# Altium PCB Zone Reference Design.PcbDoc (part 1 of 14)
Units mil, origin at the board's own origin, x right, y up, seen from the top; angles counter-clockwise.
Board outline 8858.11 x 7047.08 mil, 16 copper layers (Top Layer, GND_1, SIG_1, GND_2, PWR/SIG_1, GND_3, PWR_1, PWR_2, GND_4, PWR/SIG_2, GND_5, SIG_2, GND_6, SIG_3, GND_7, Bottom Layer), stack 80.368 mil thick; 1131 components, 808 nets, 3825 pads, 3523 vias.
Unrouted connection lines stored in the file: 563.

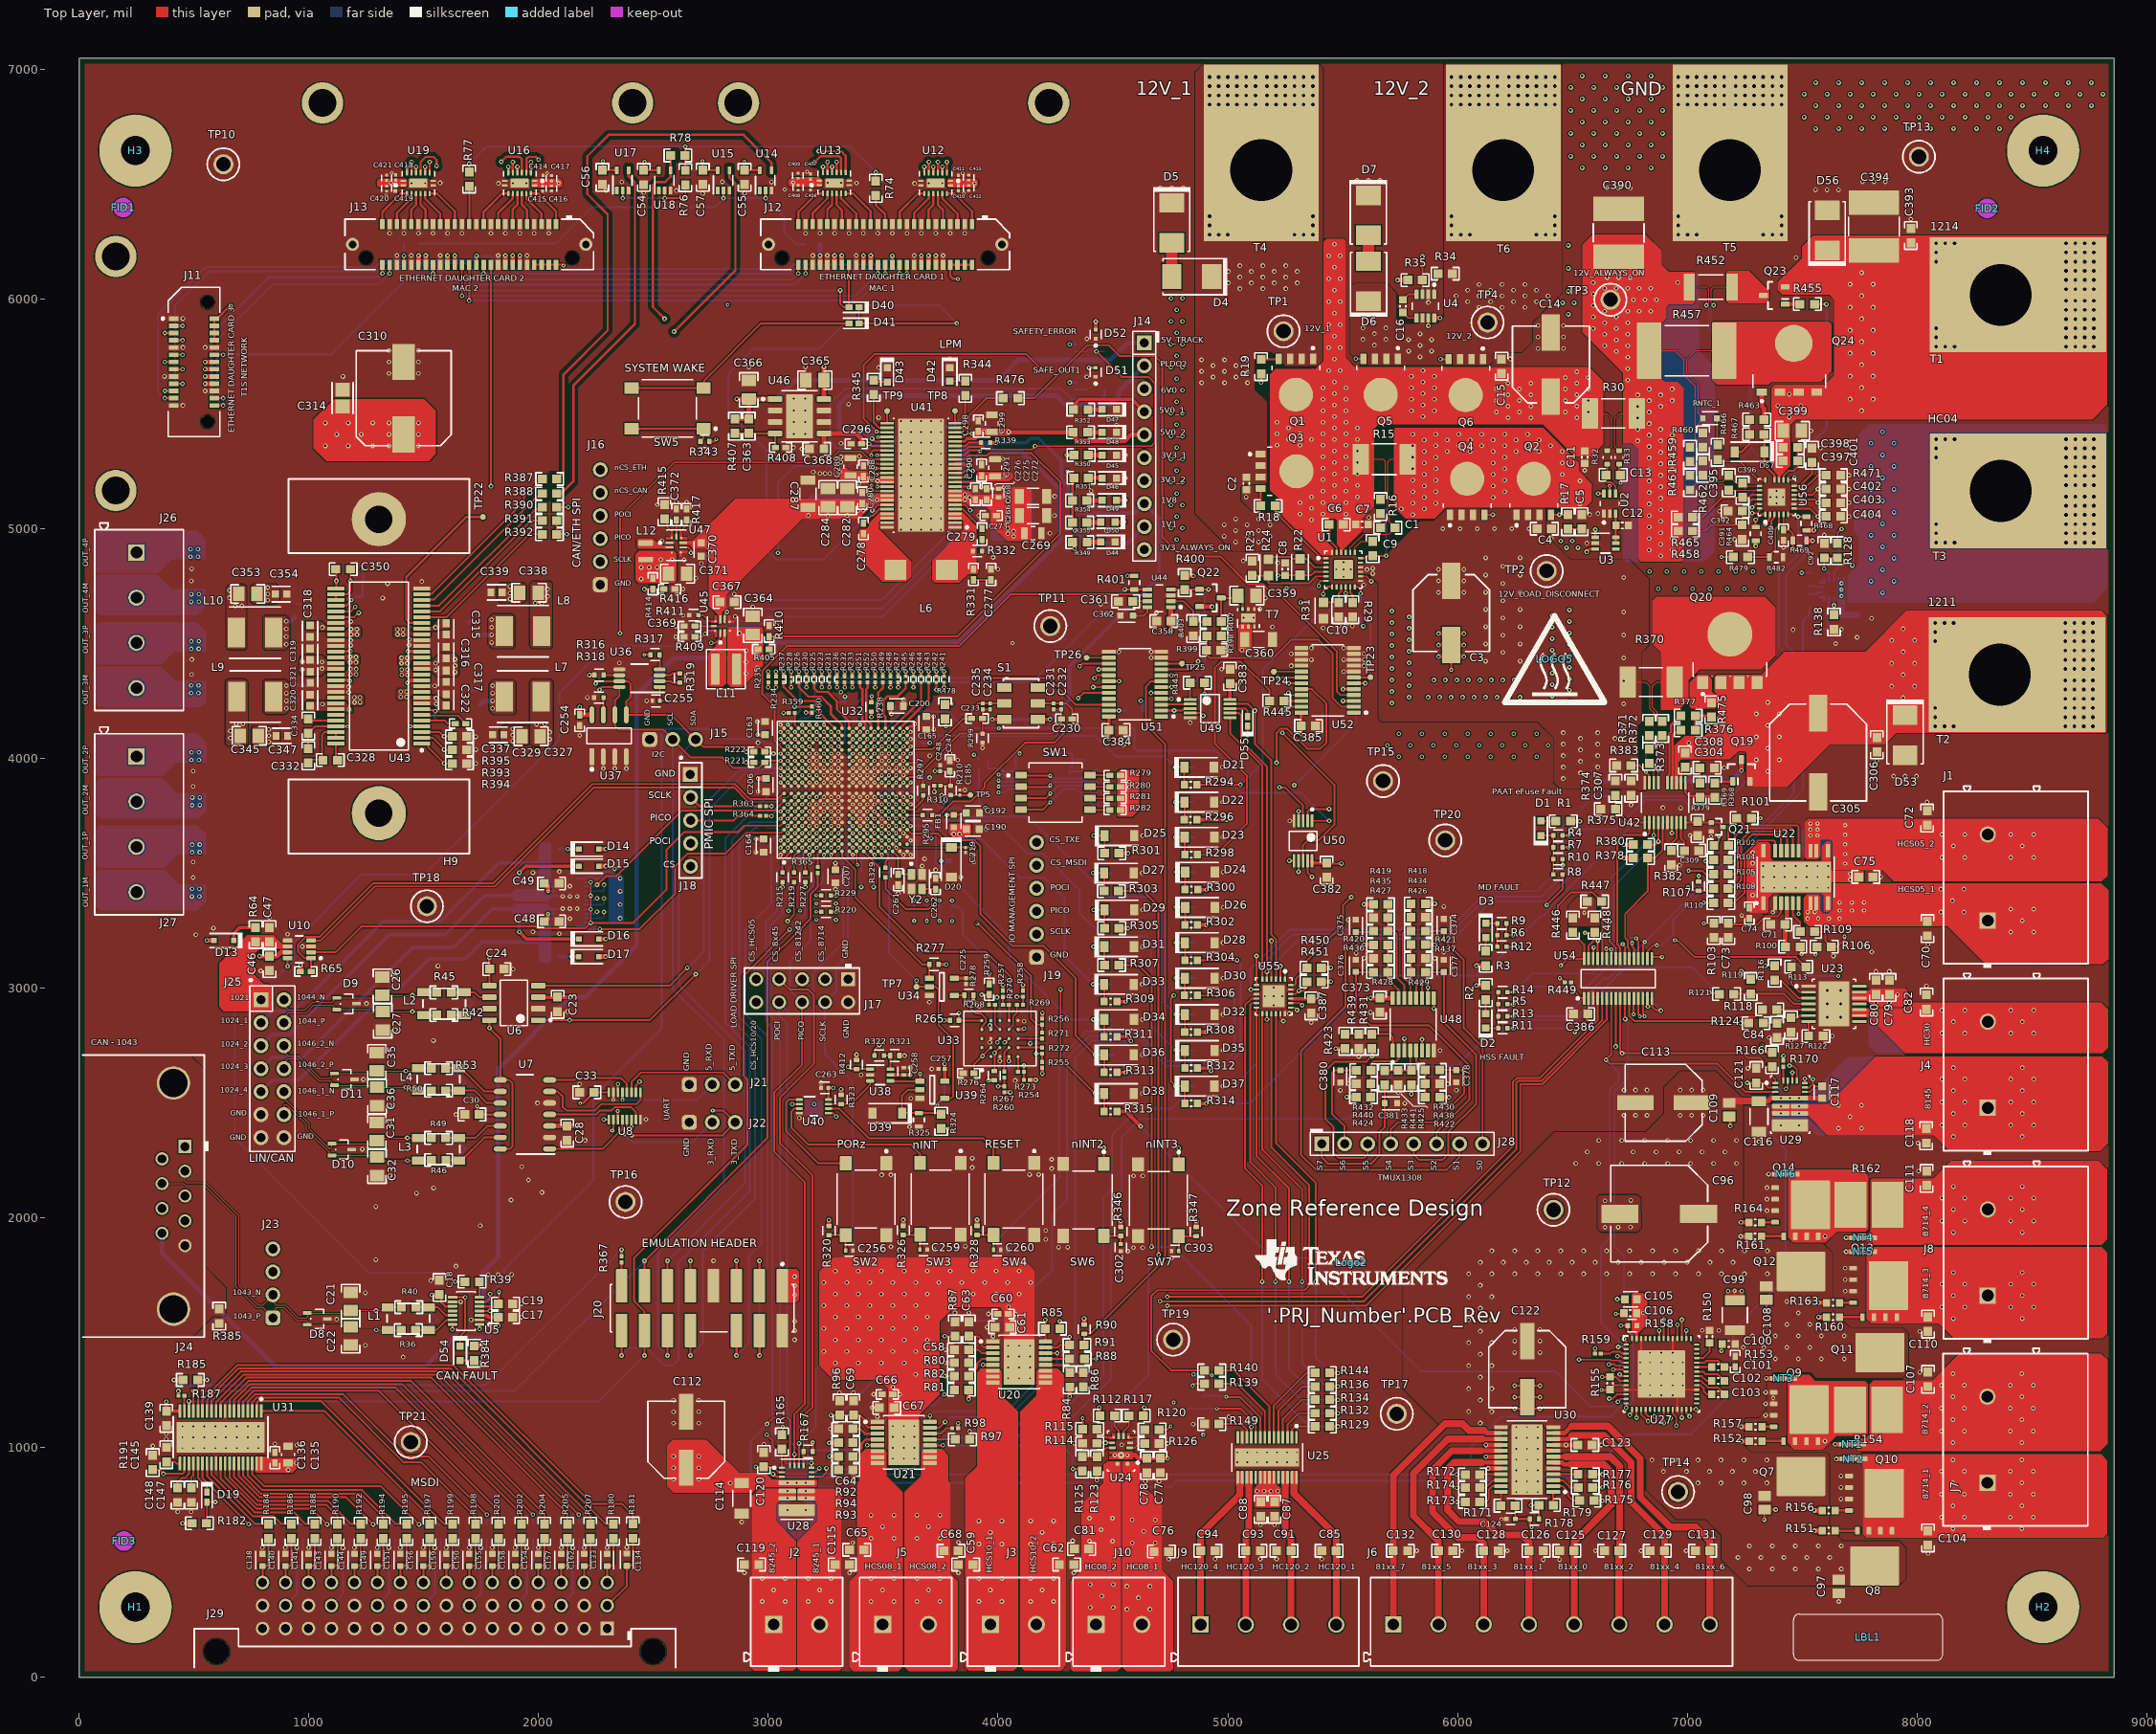
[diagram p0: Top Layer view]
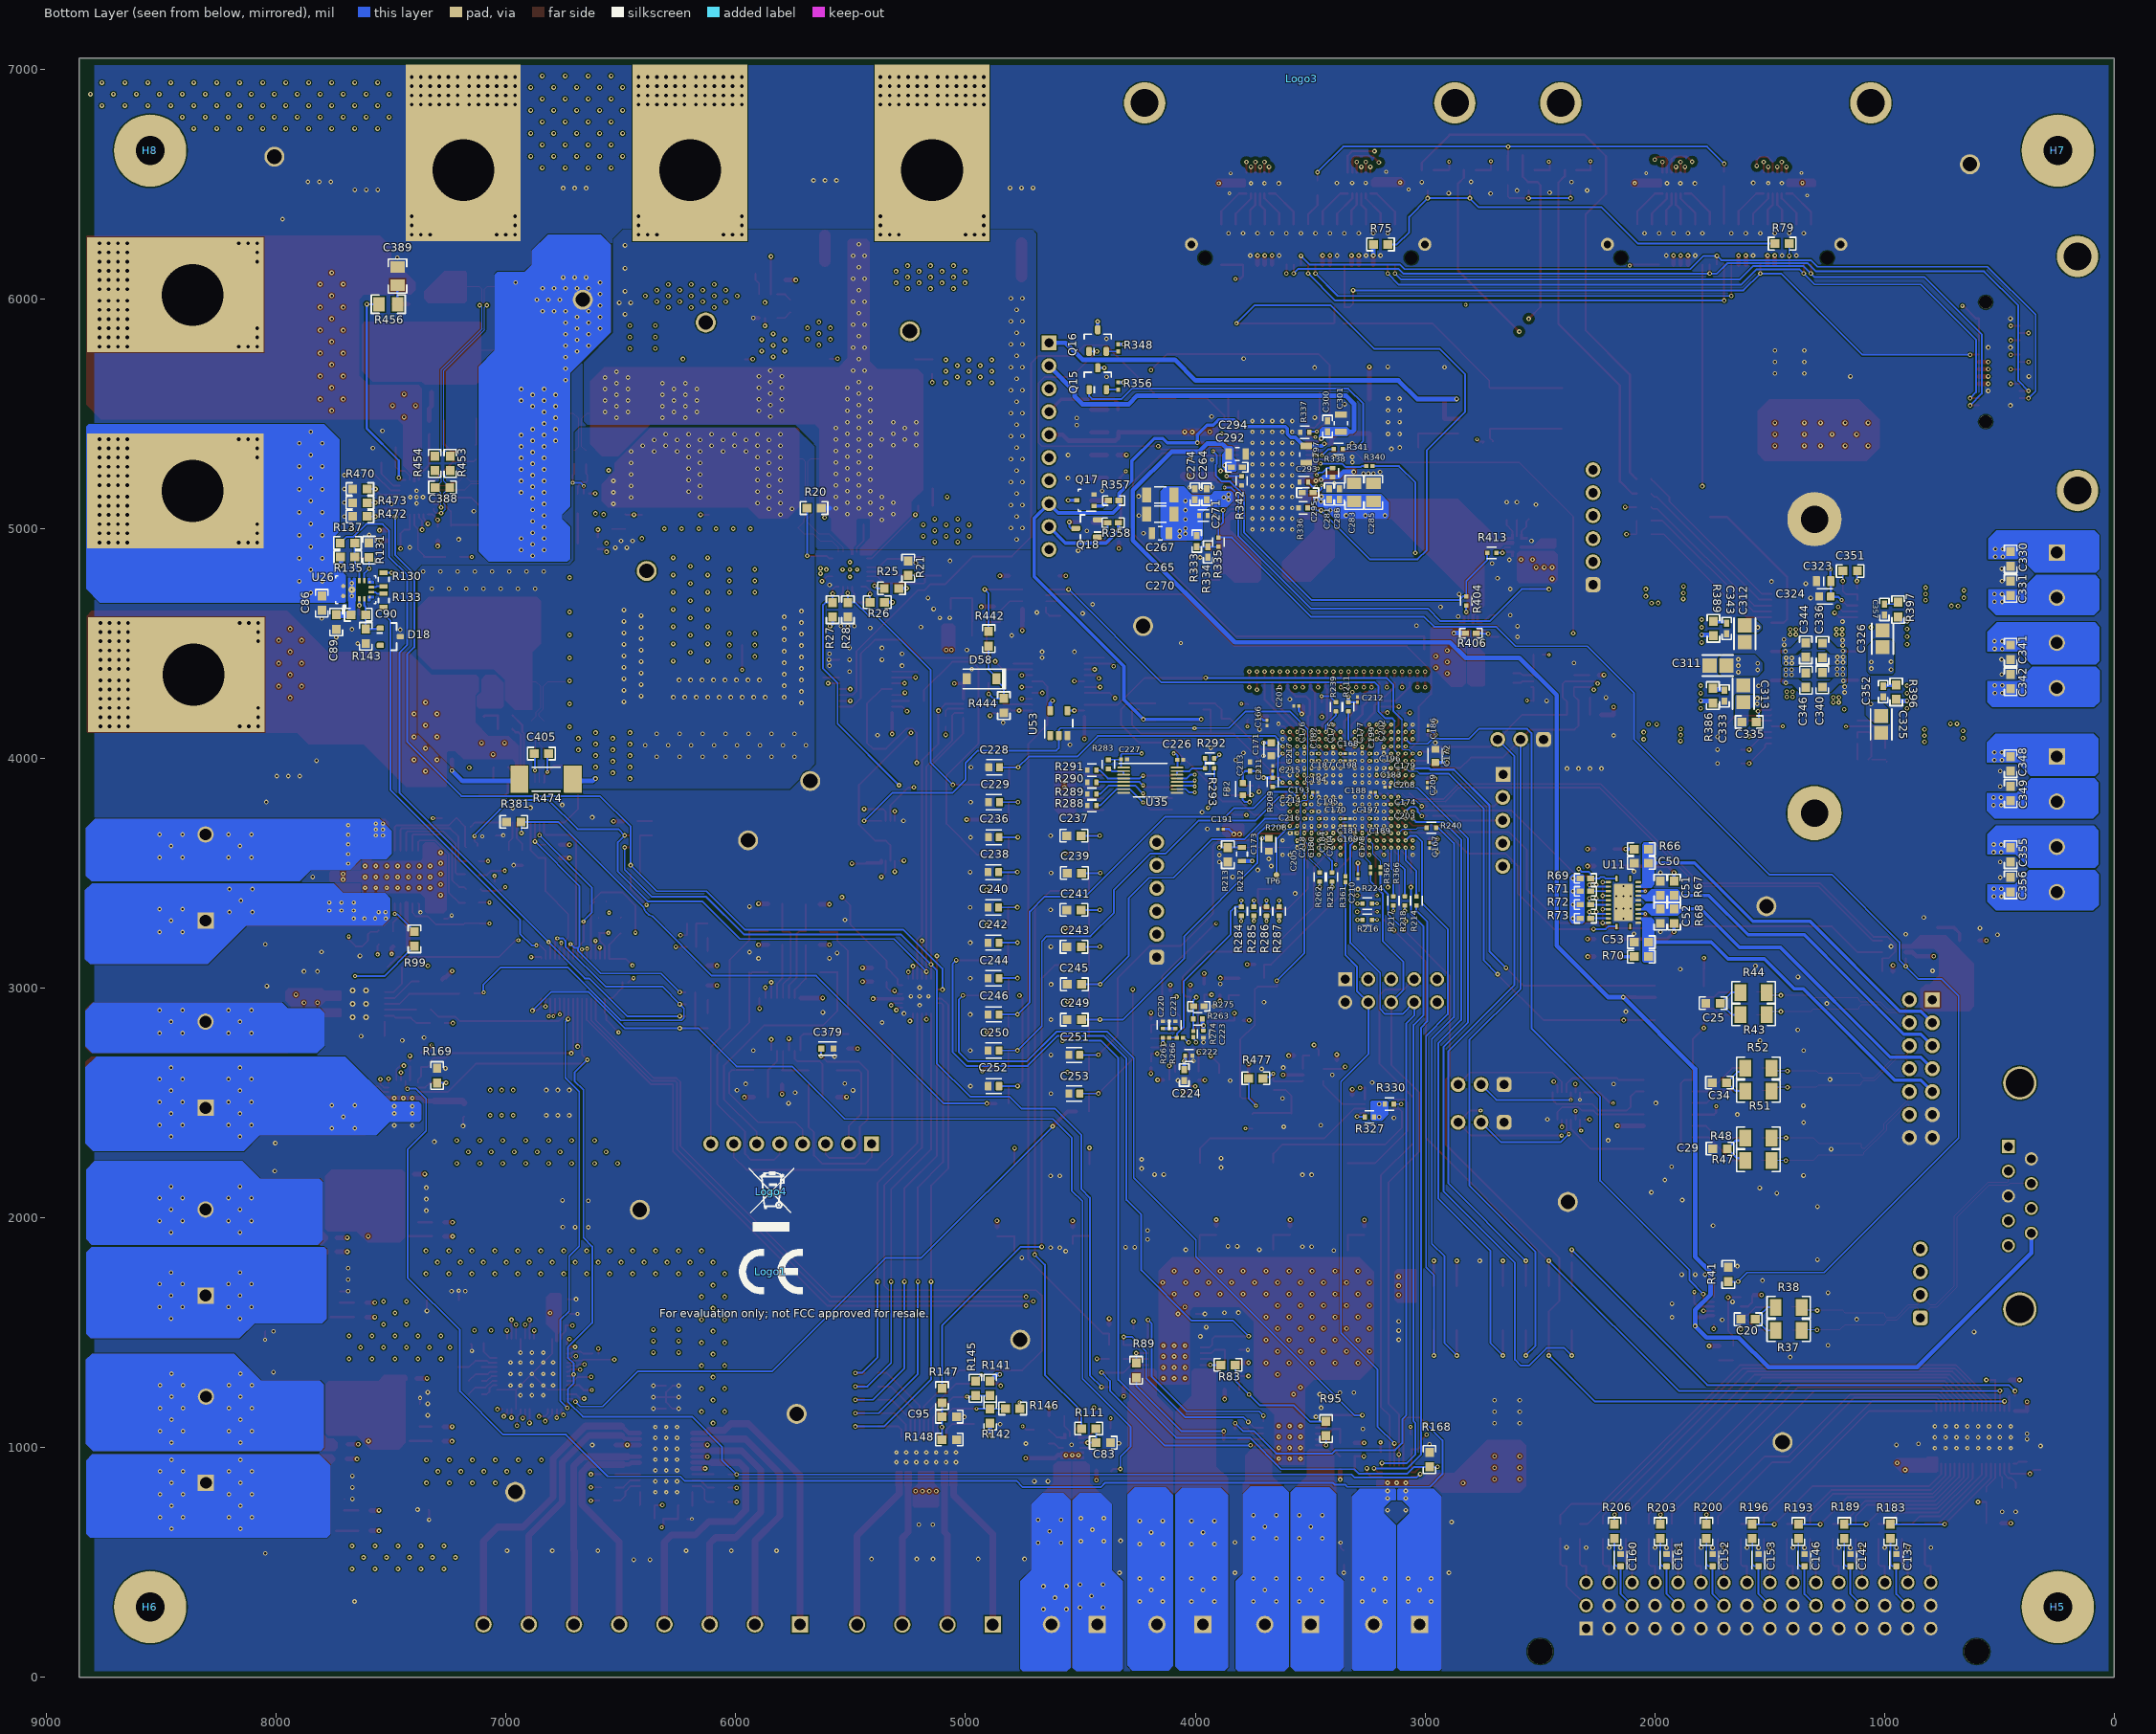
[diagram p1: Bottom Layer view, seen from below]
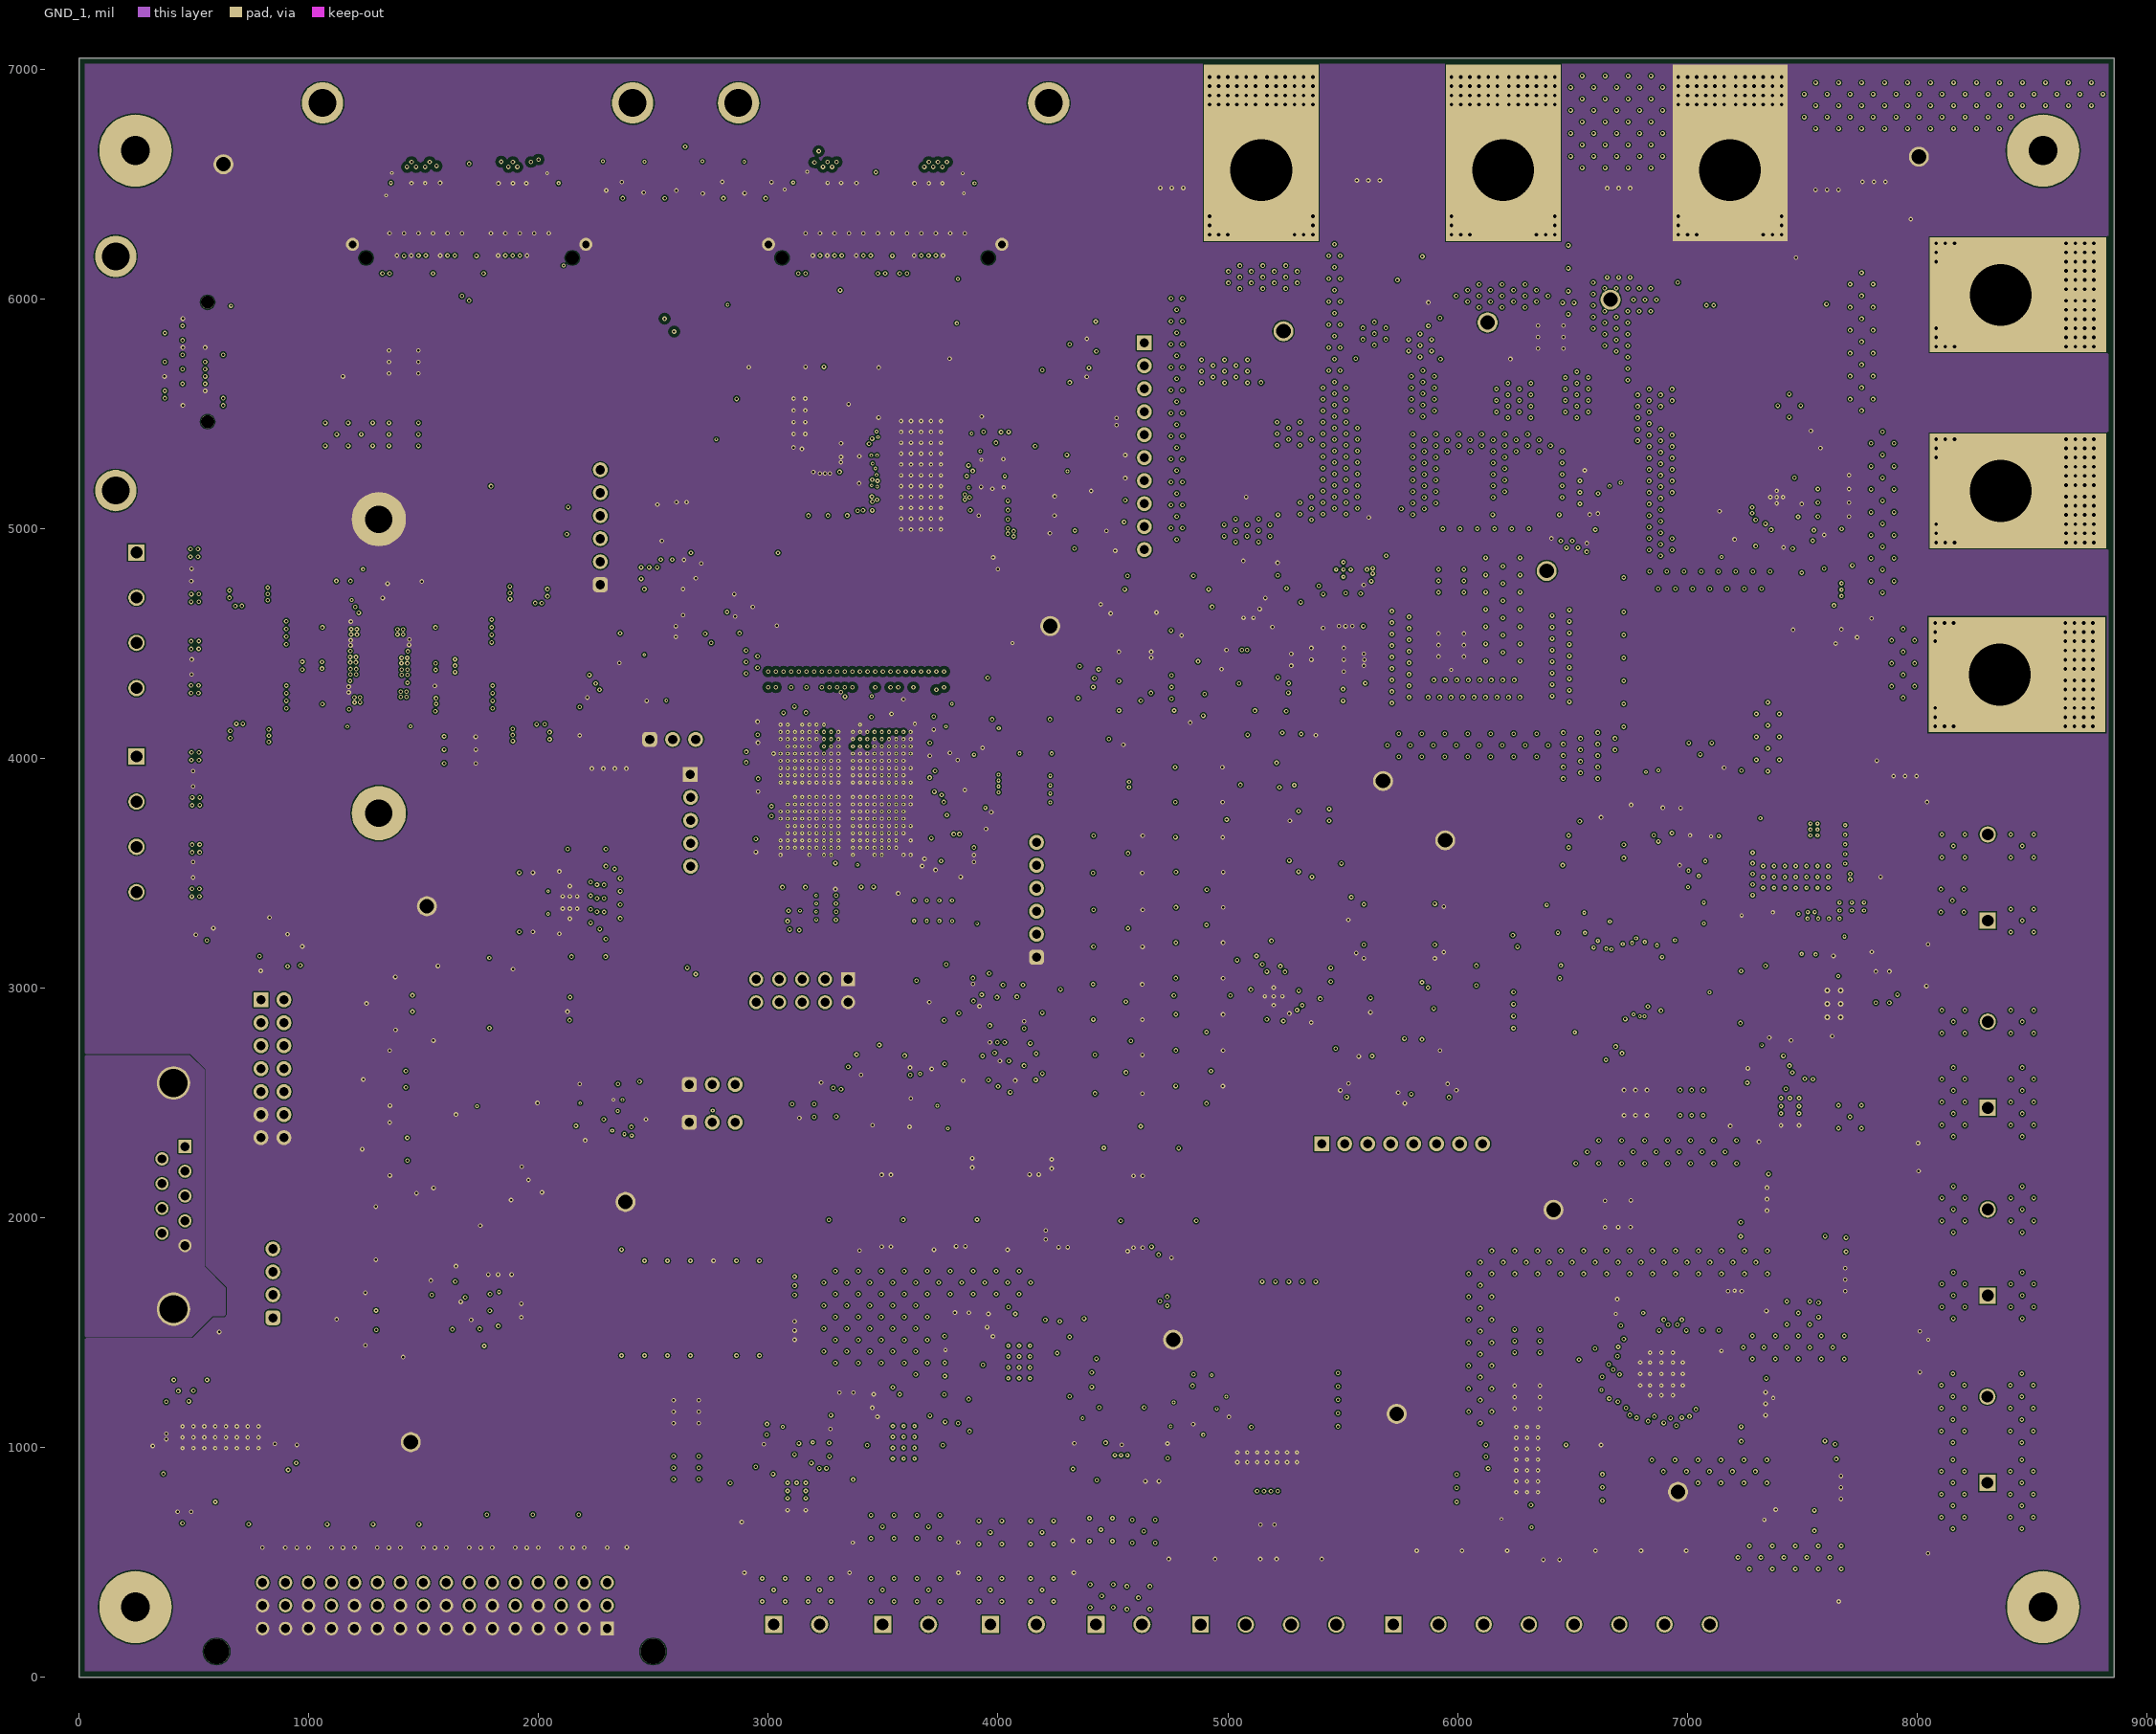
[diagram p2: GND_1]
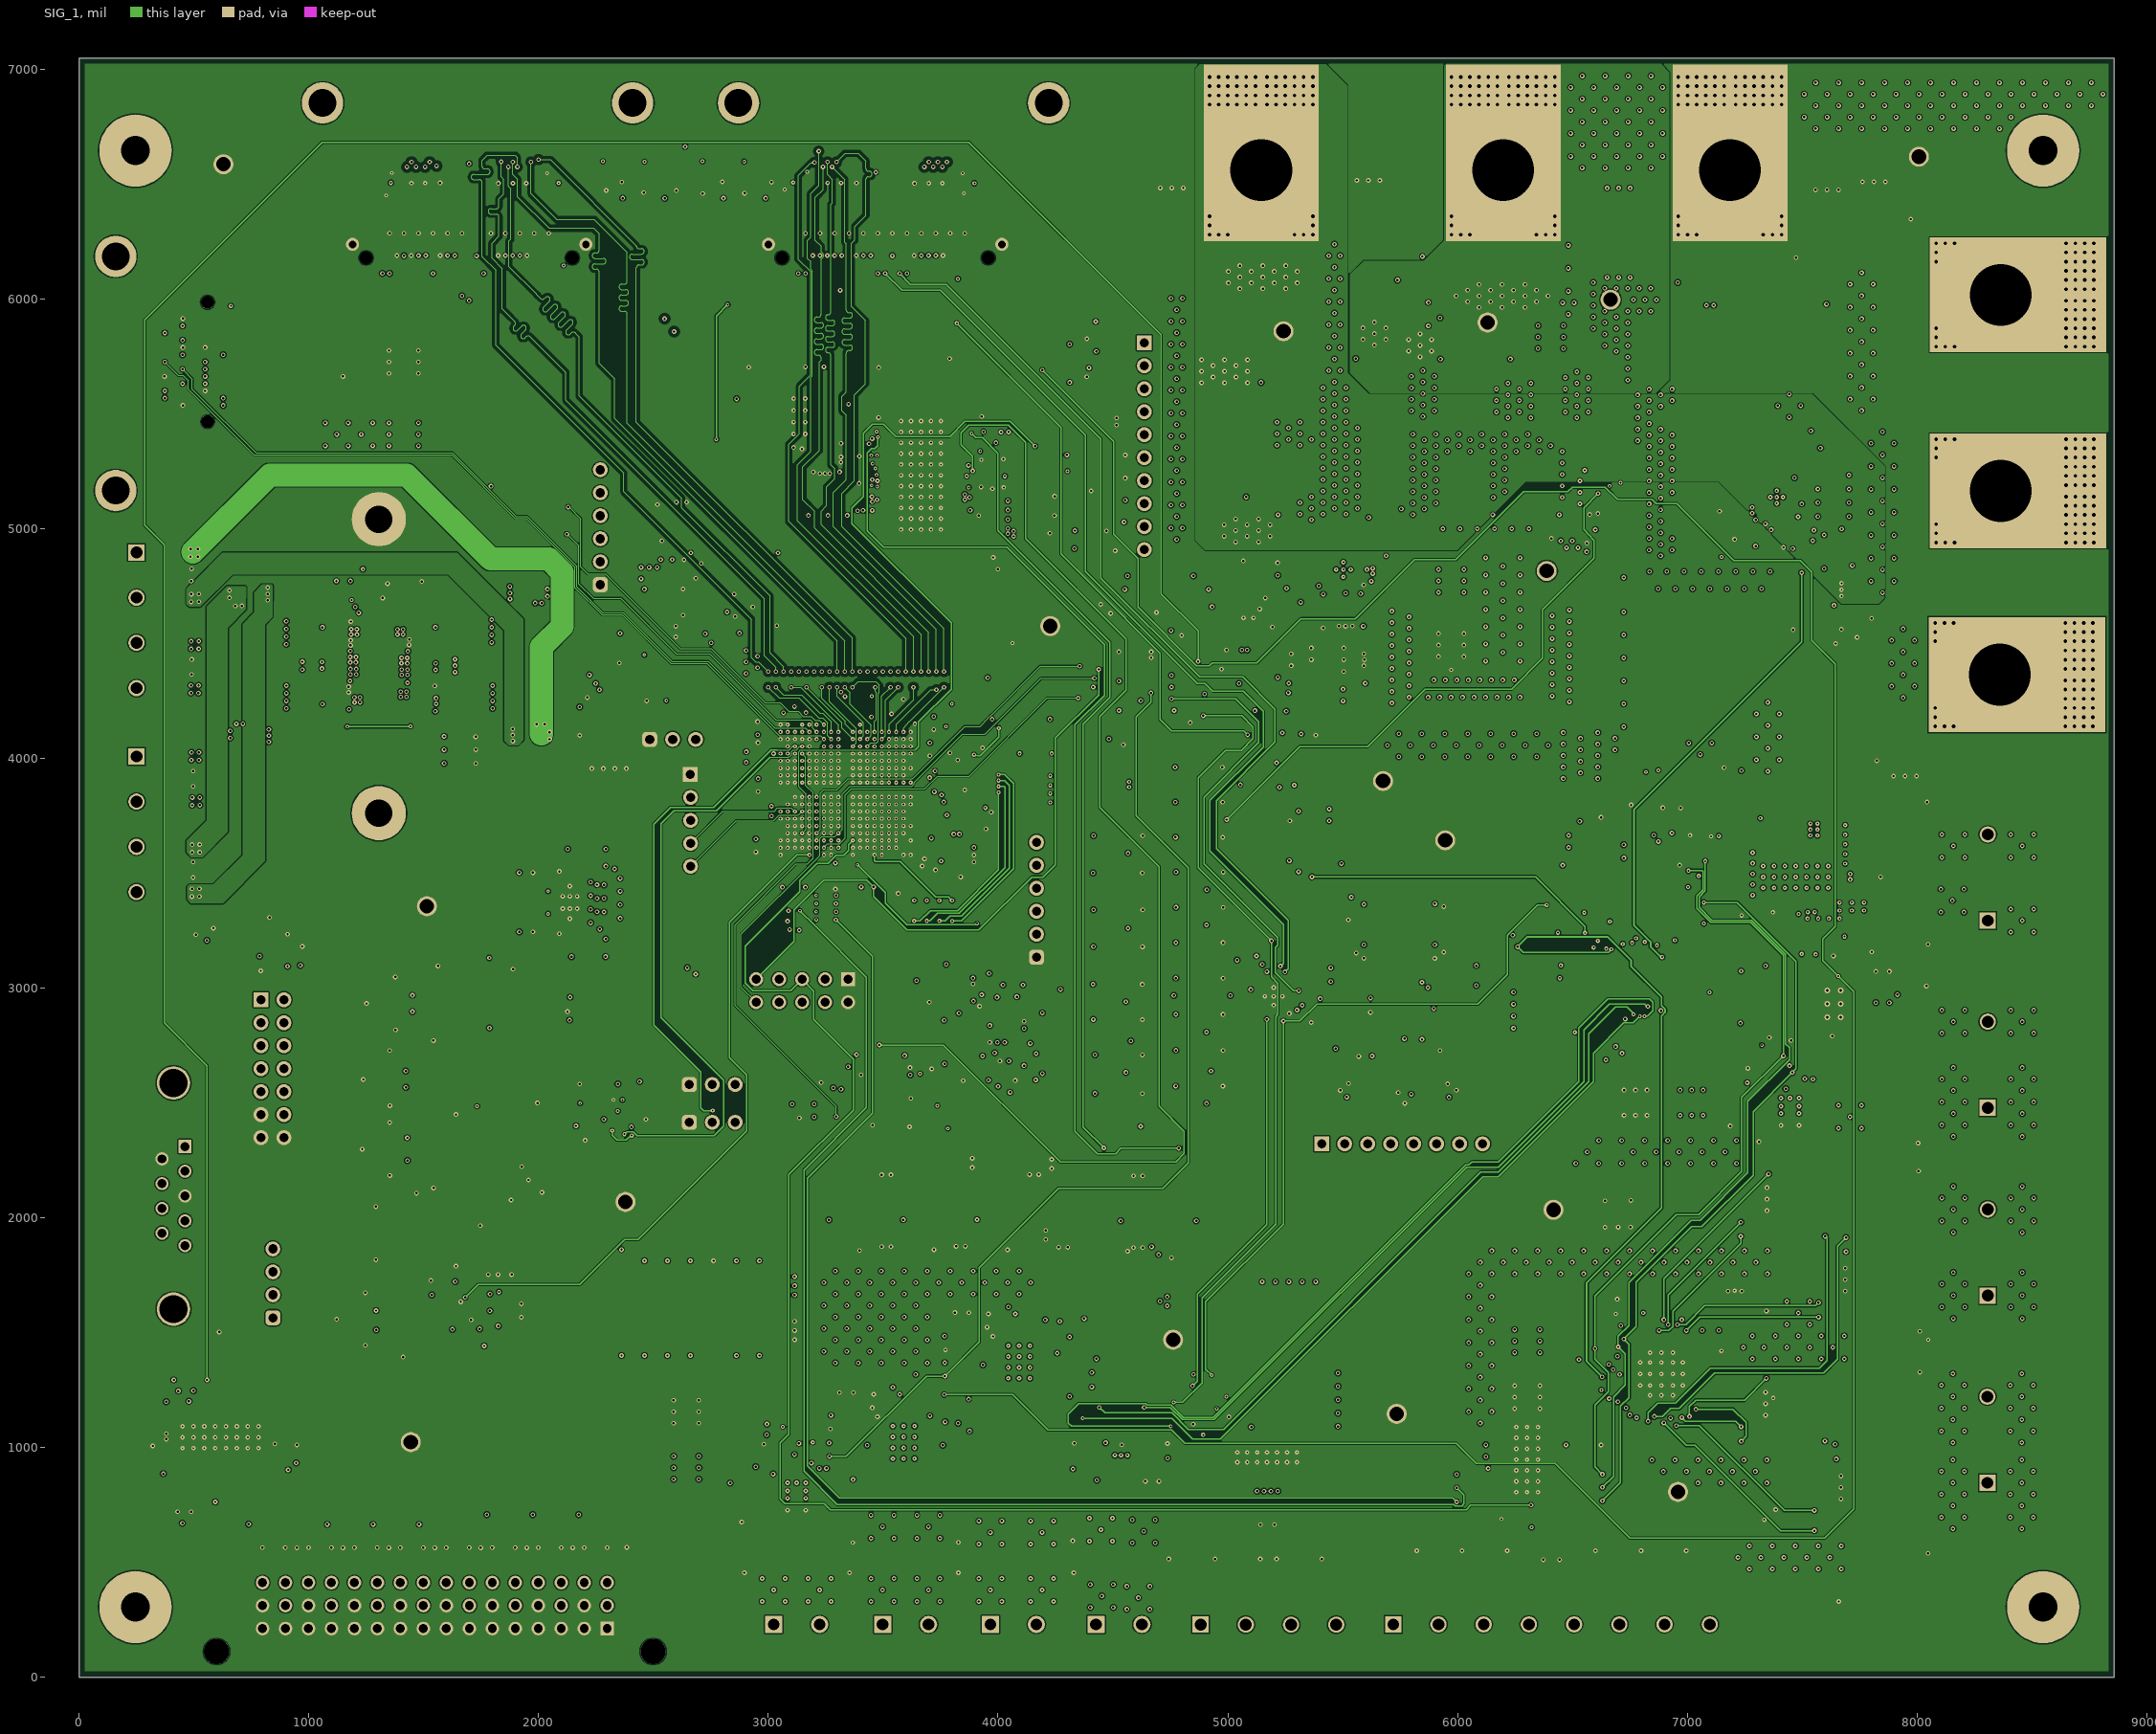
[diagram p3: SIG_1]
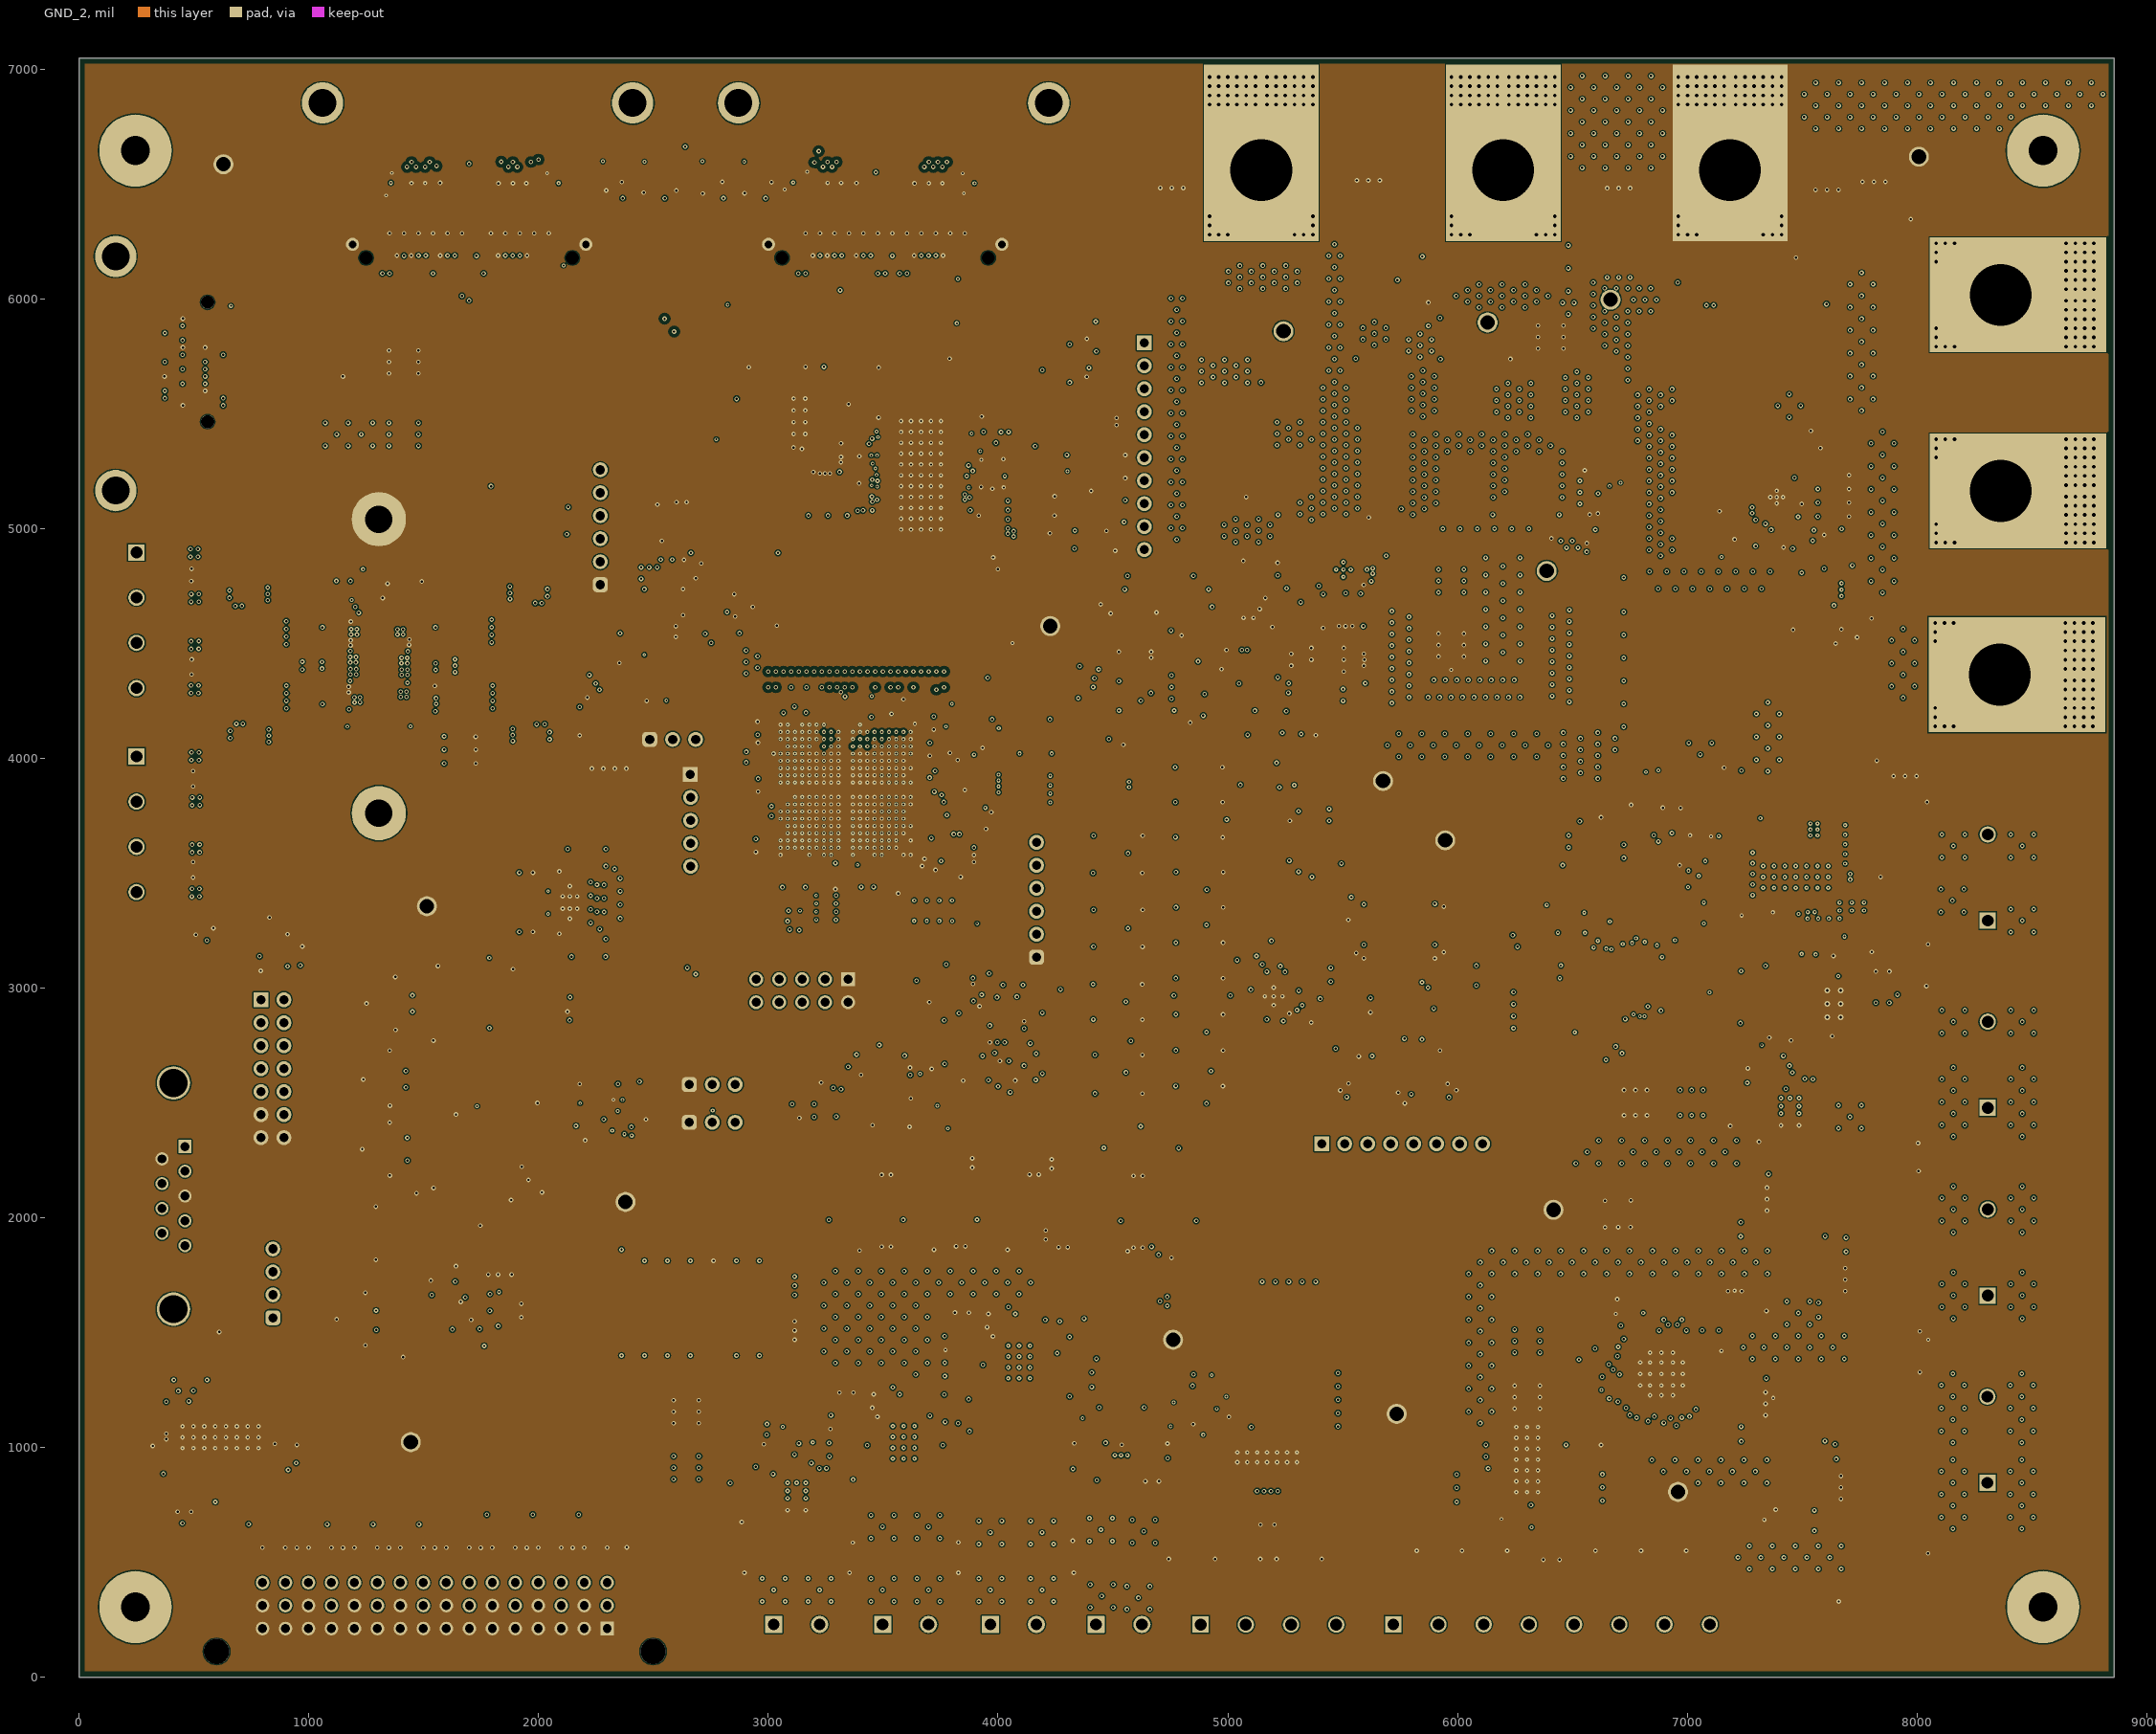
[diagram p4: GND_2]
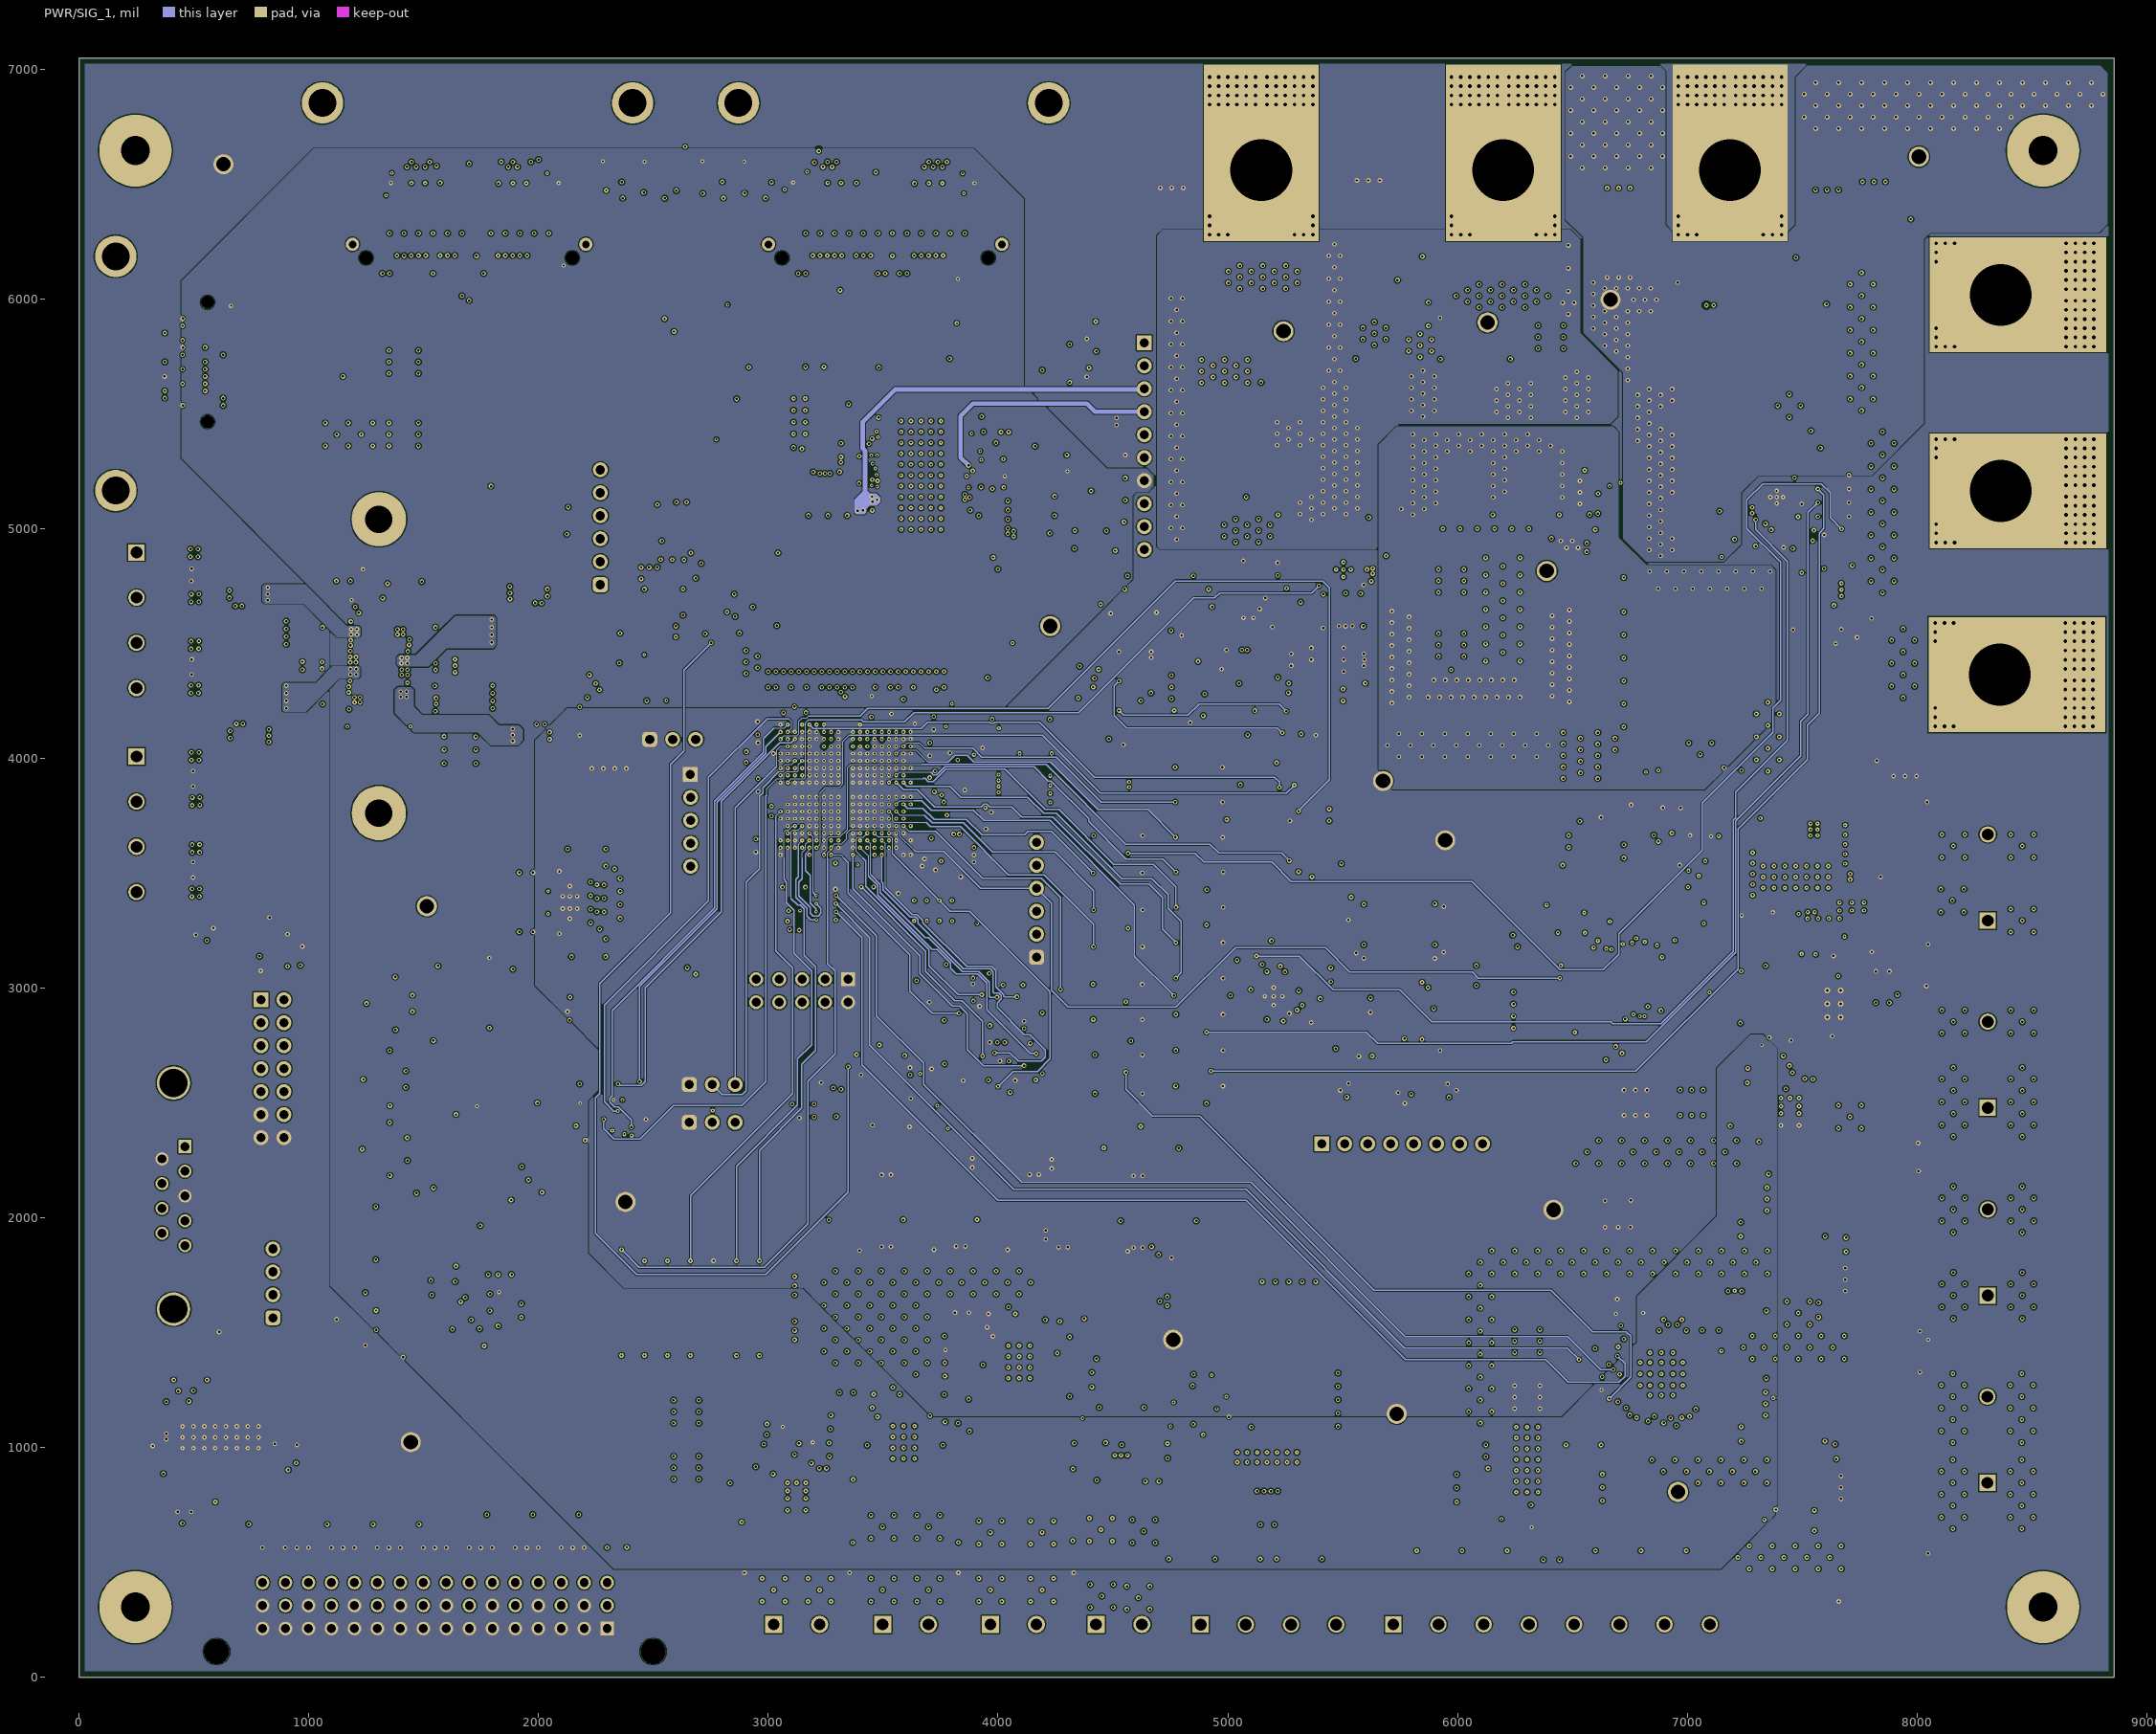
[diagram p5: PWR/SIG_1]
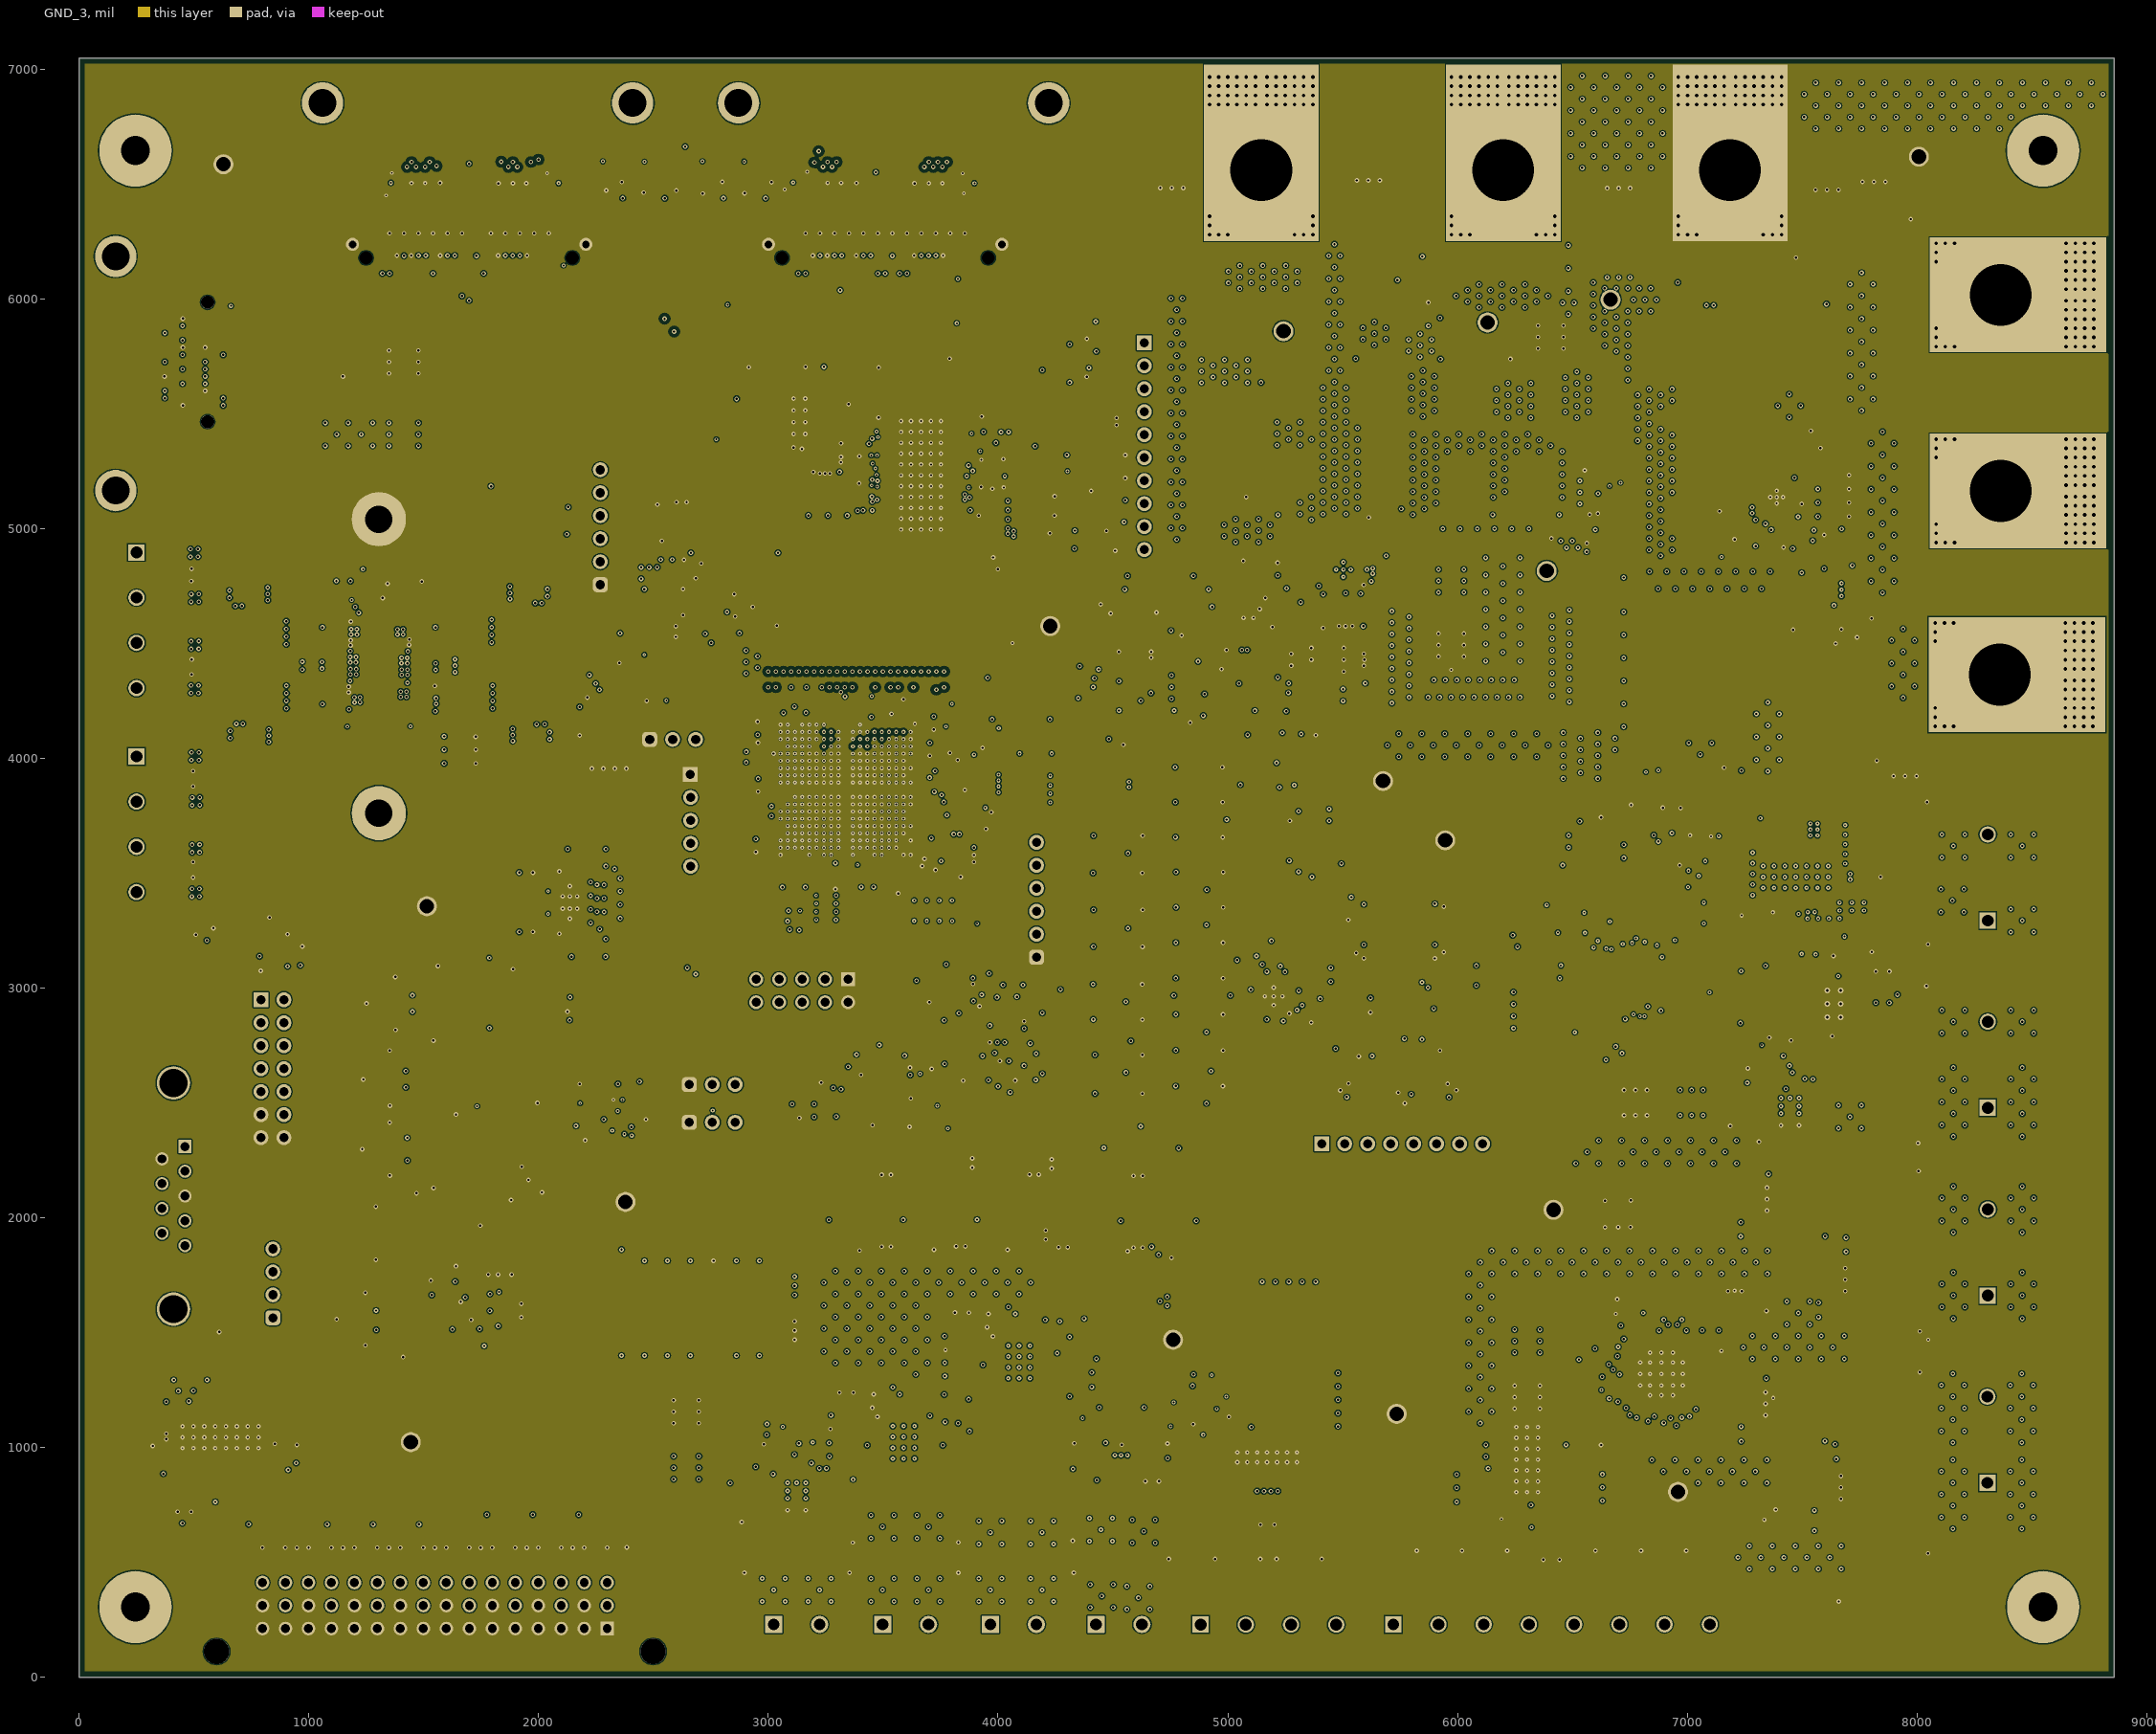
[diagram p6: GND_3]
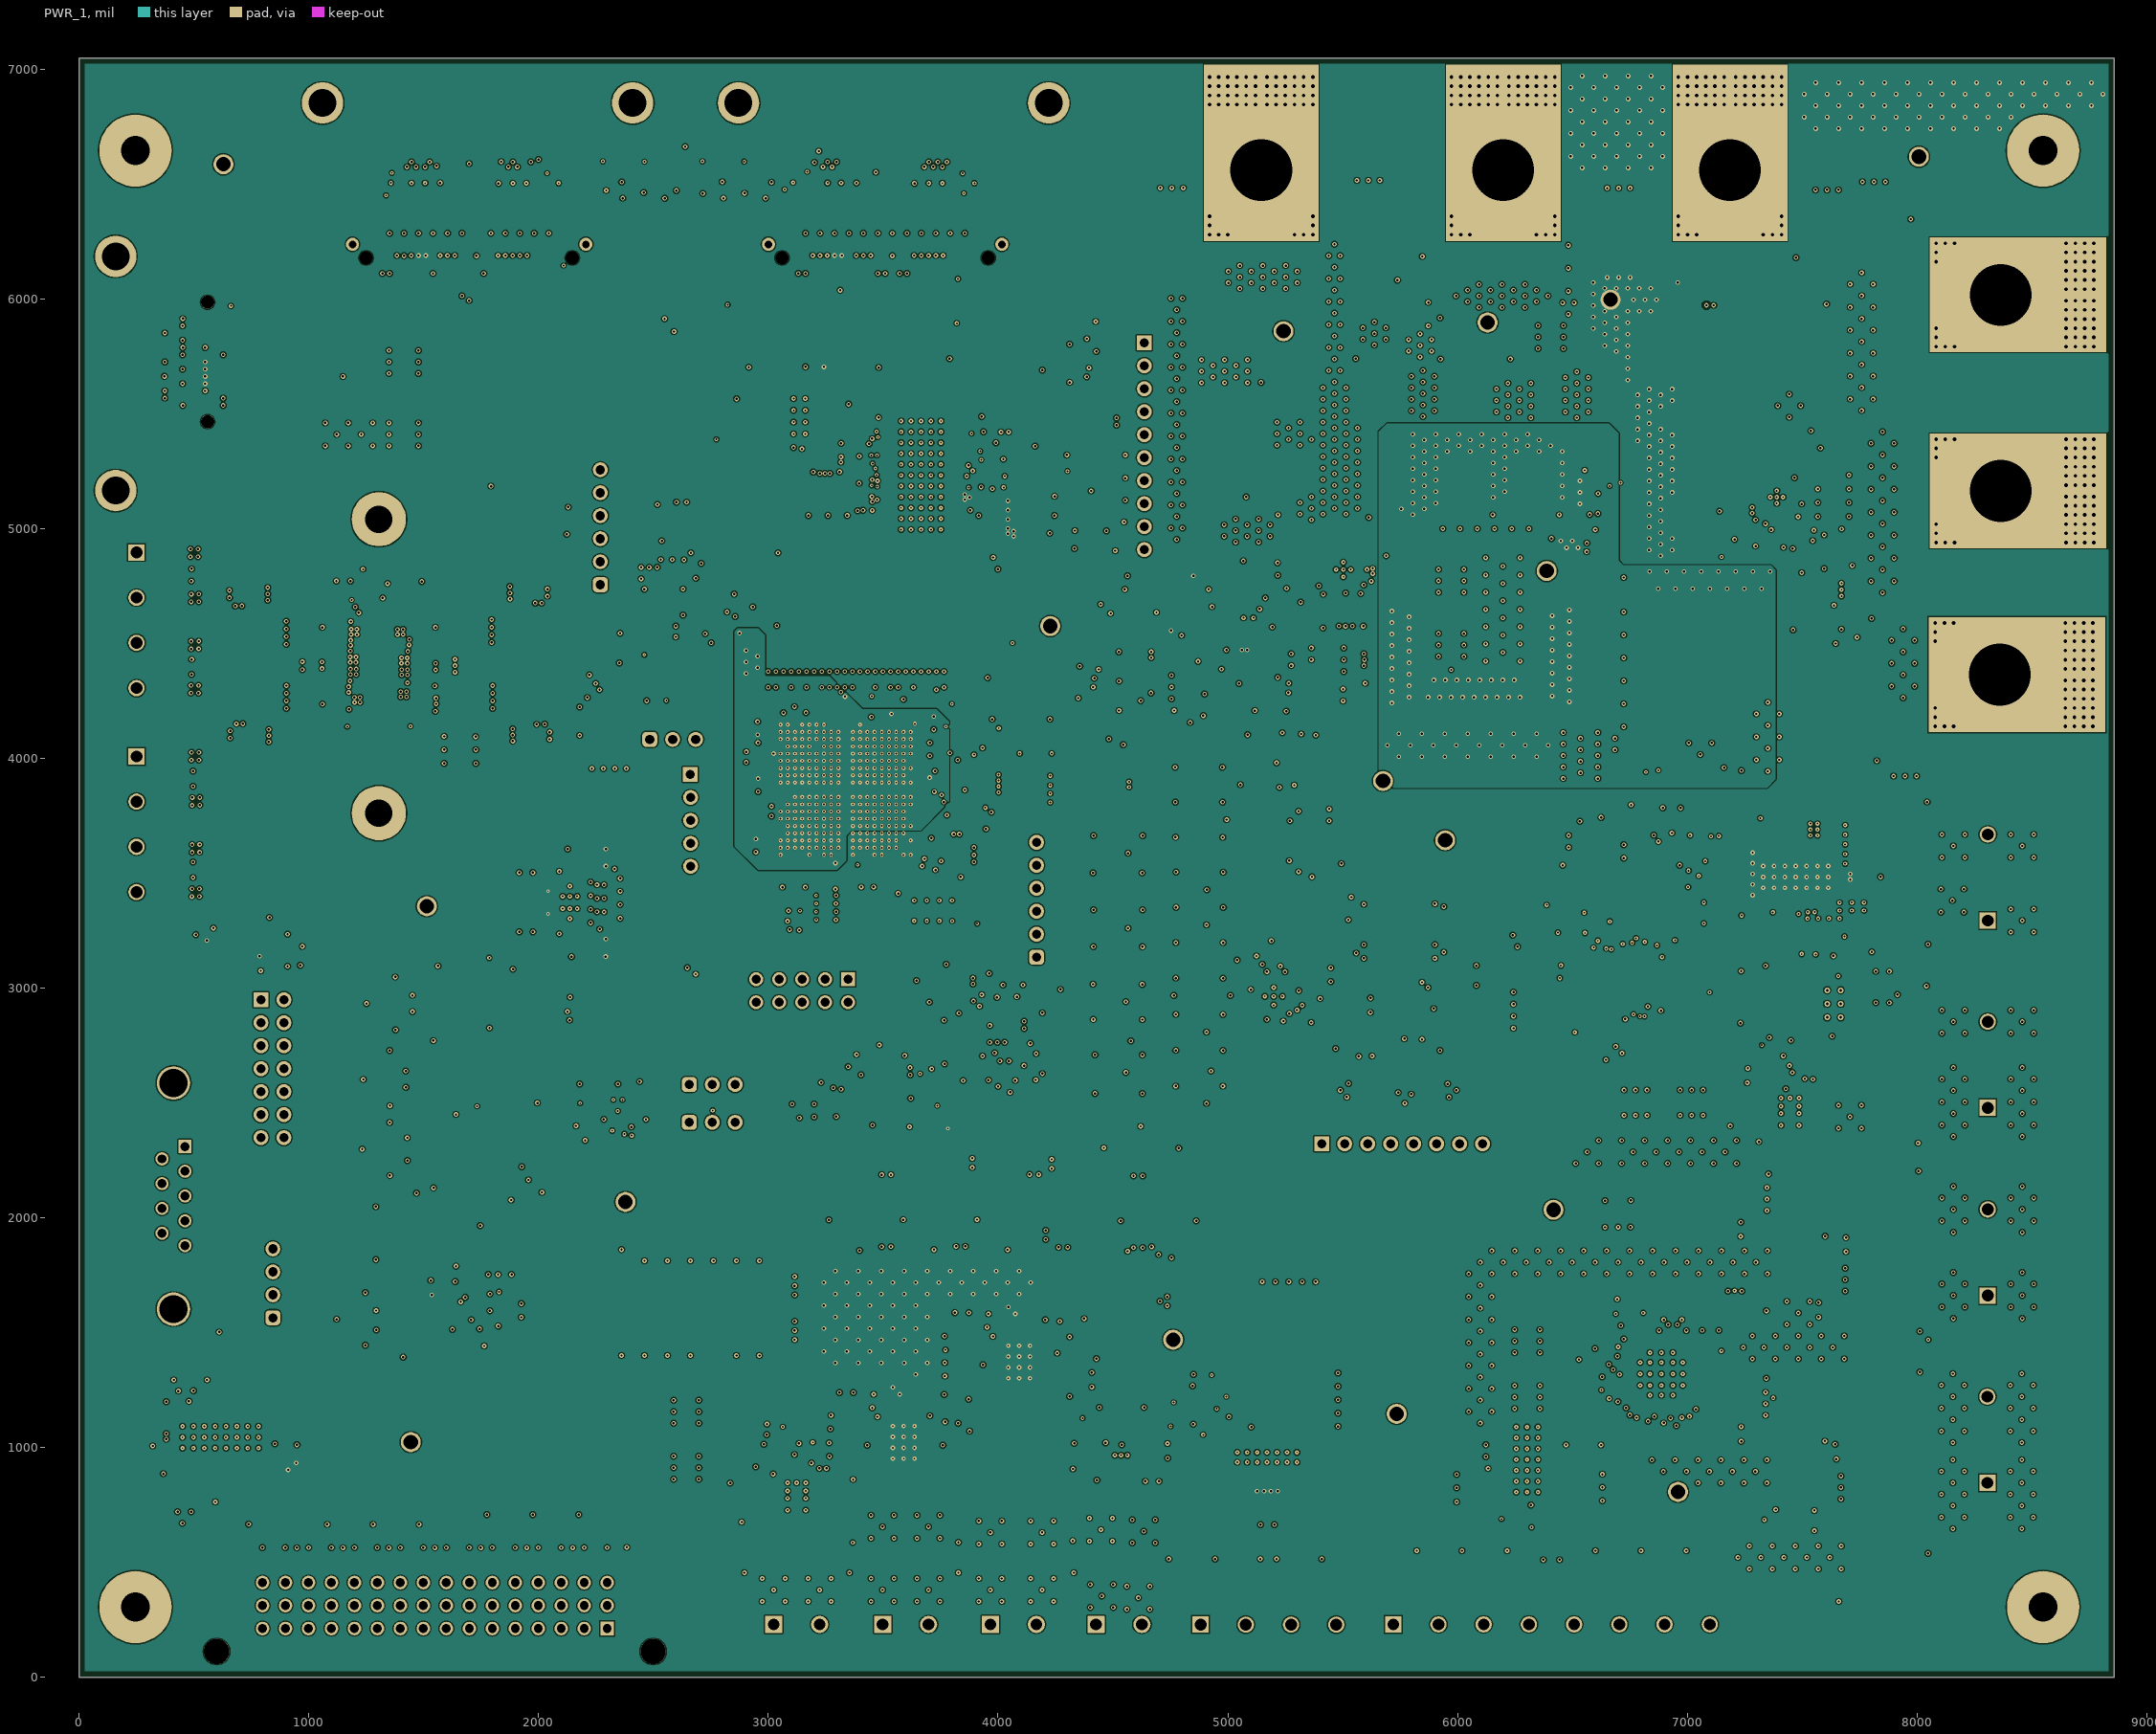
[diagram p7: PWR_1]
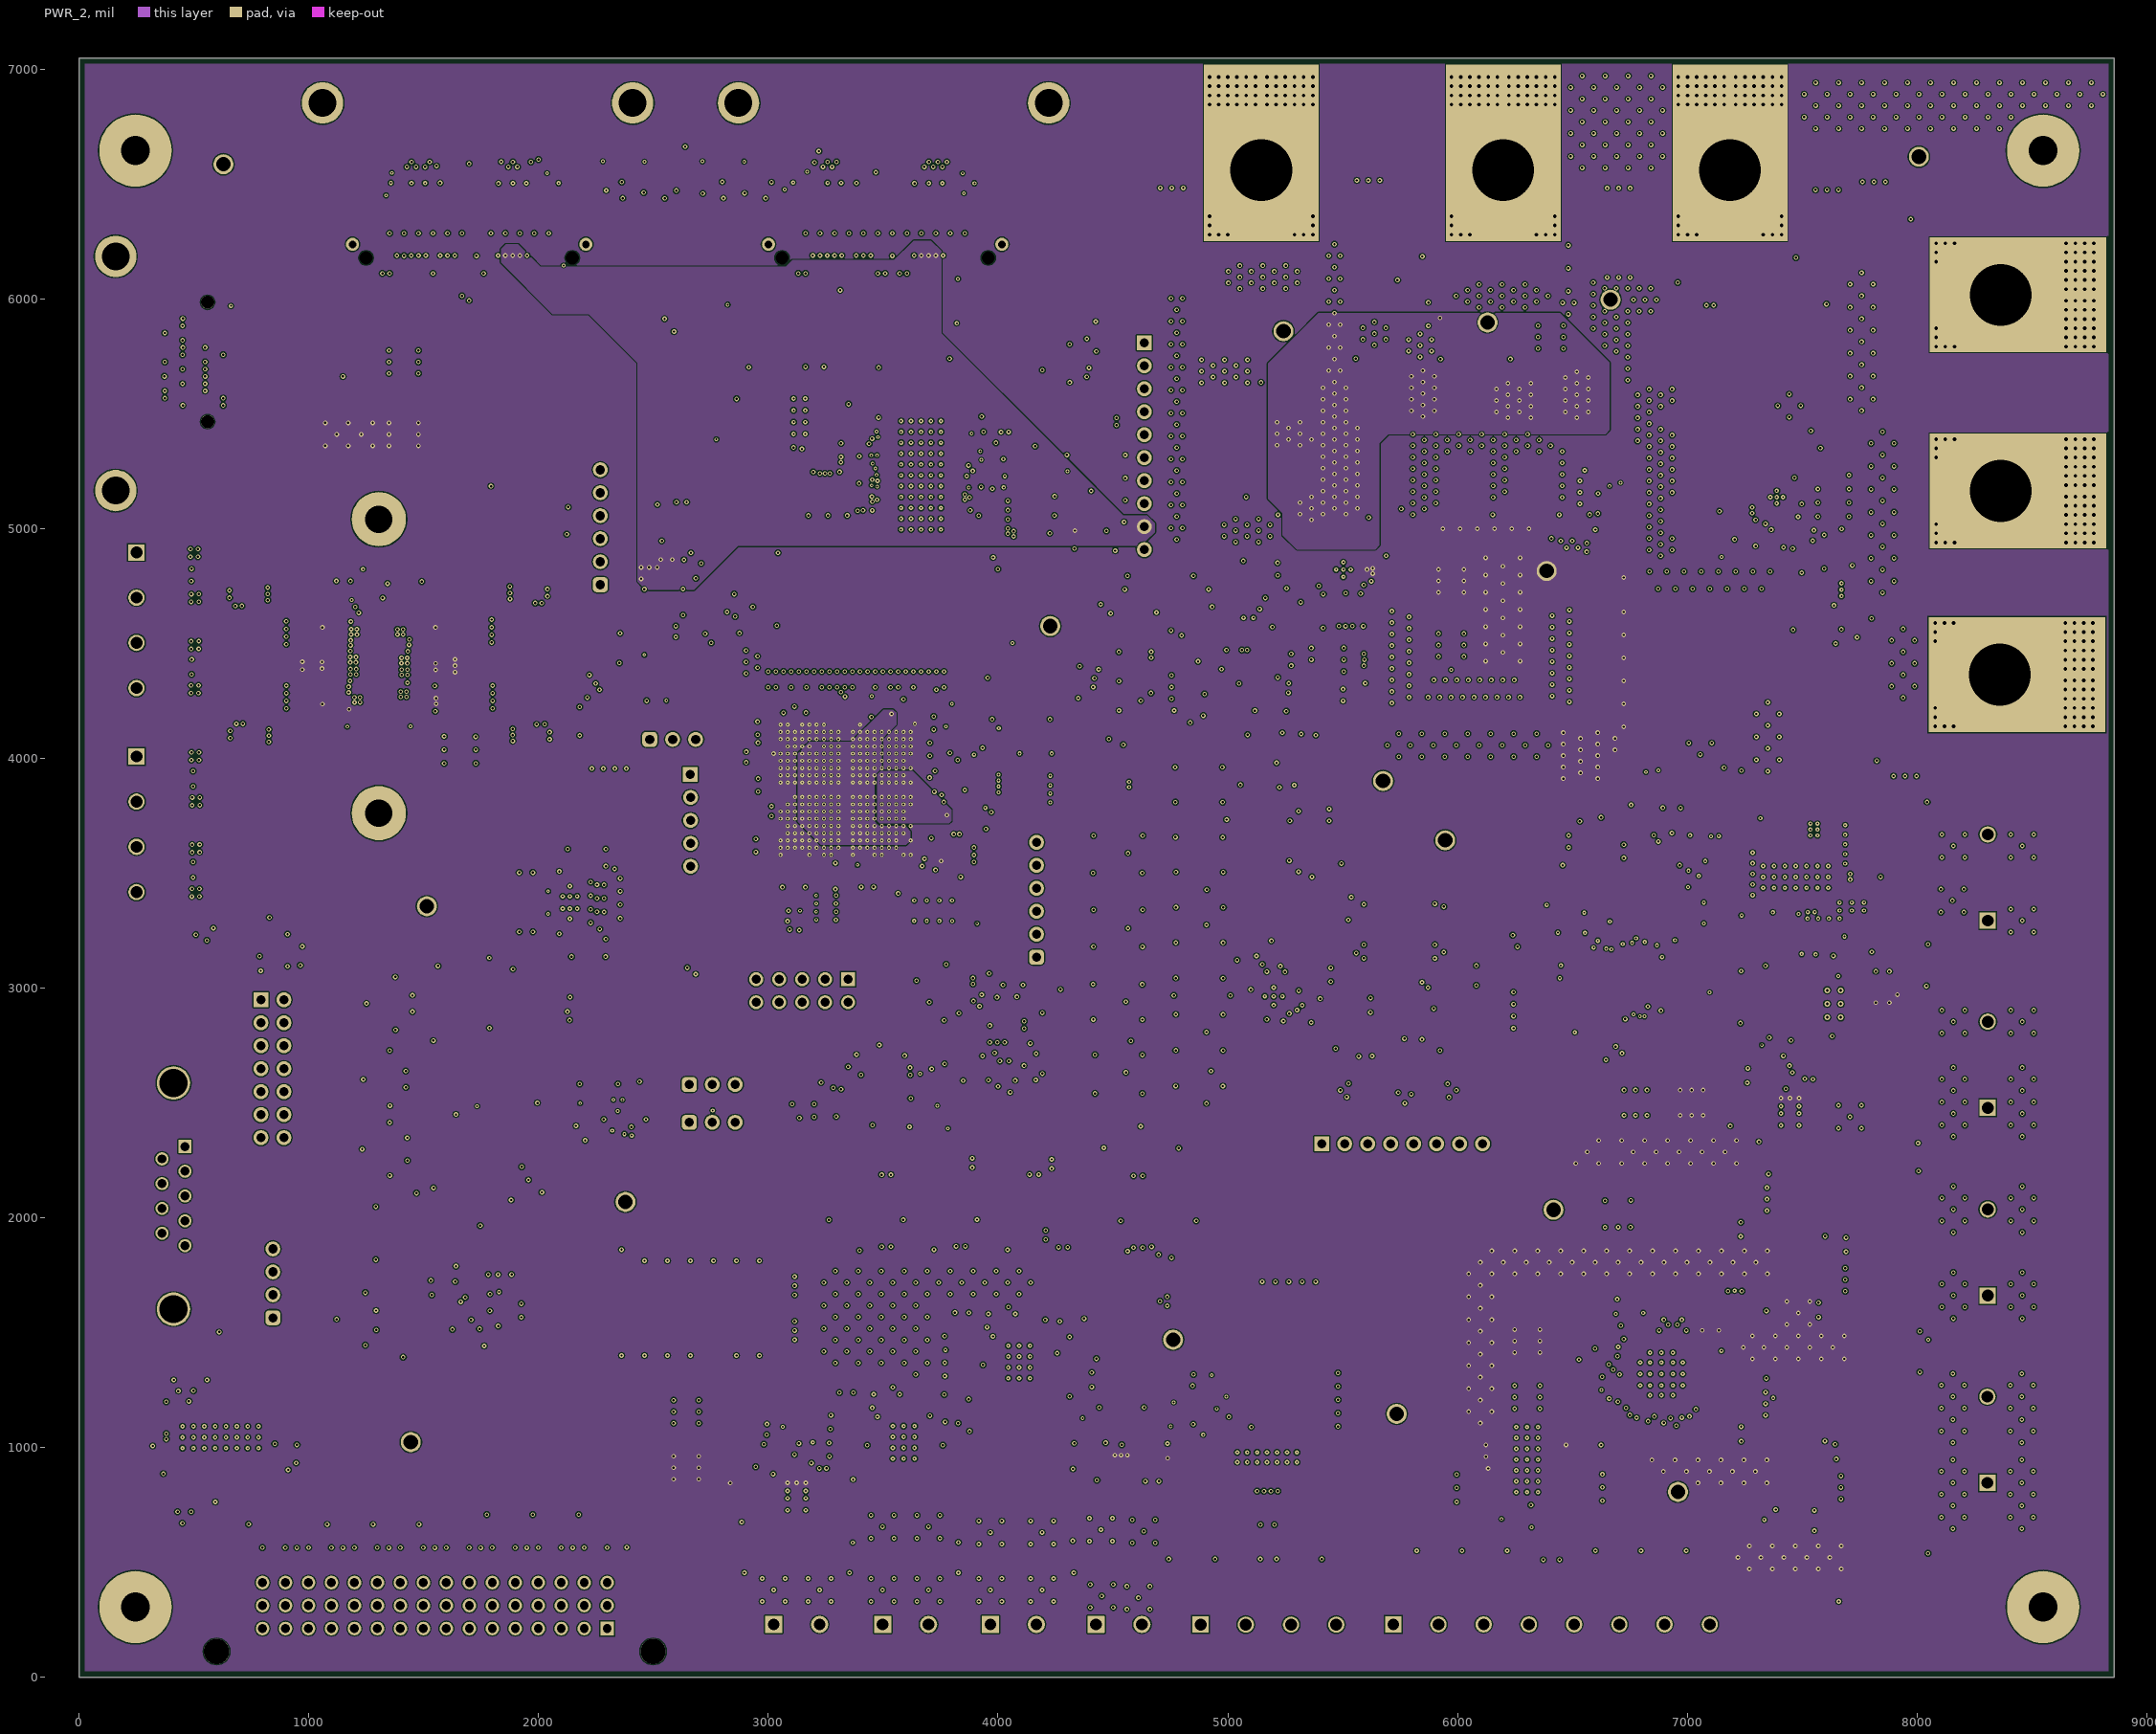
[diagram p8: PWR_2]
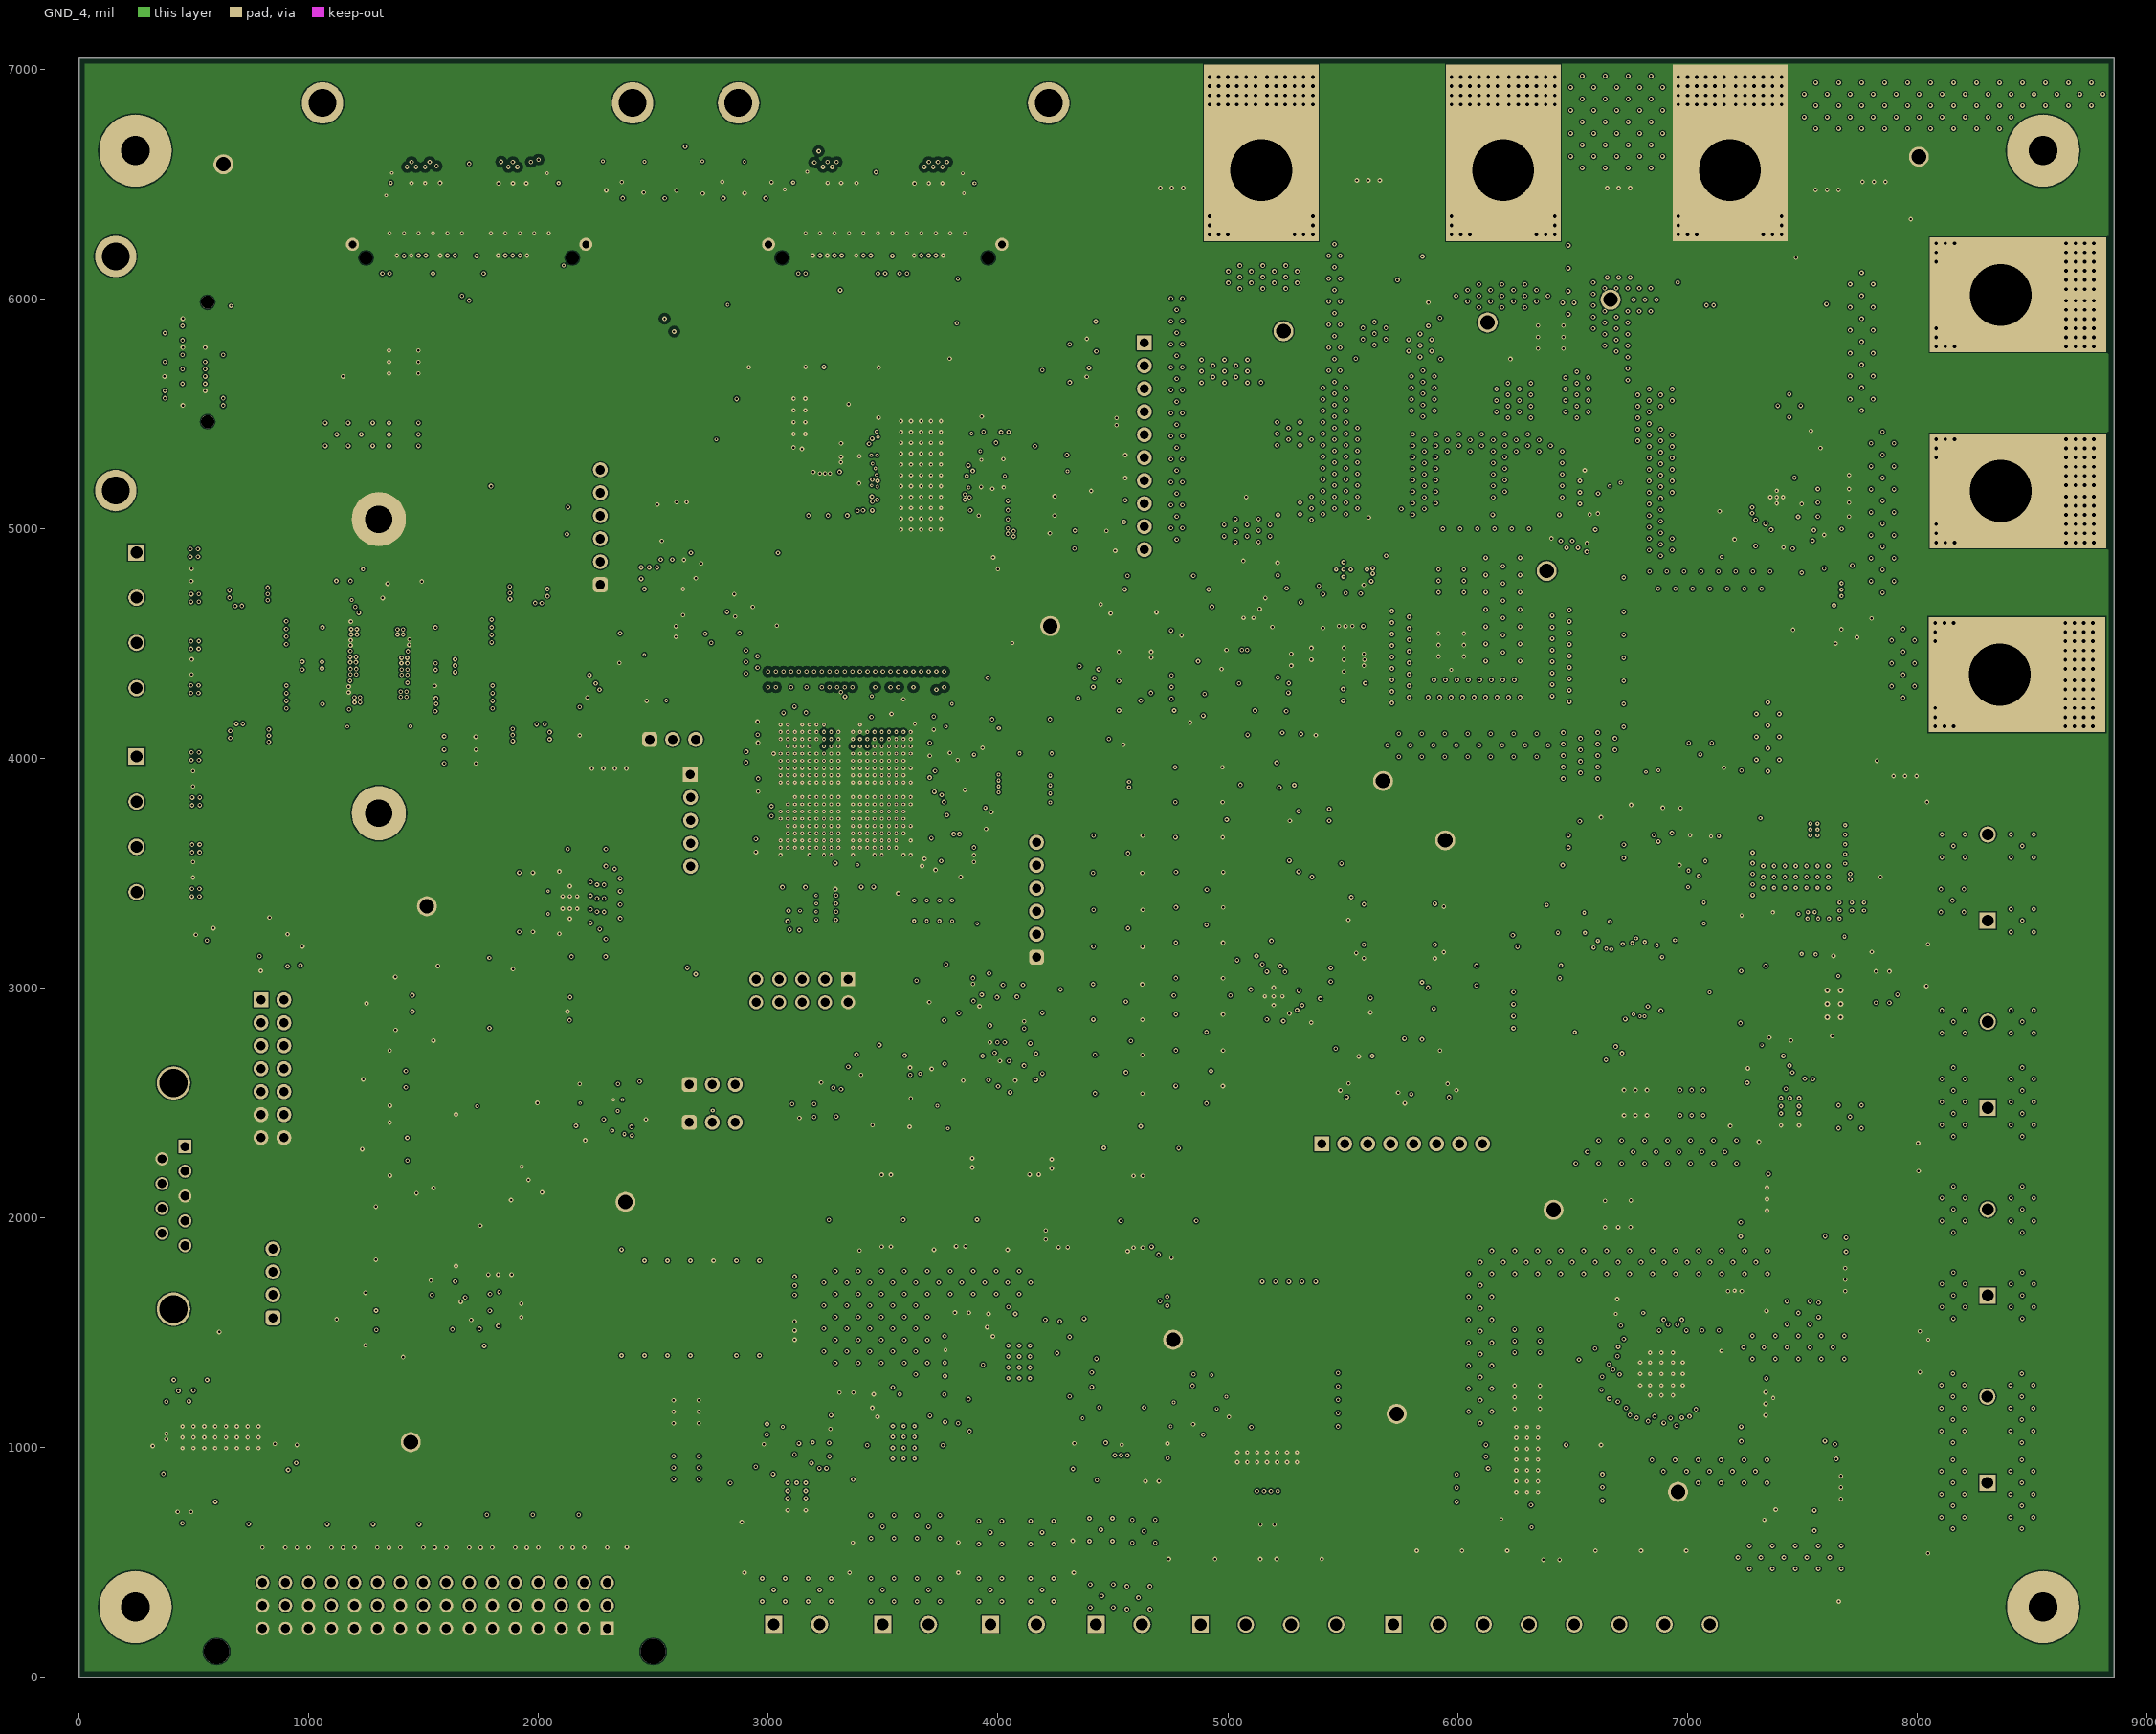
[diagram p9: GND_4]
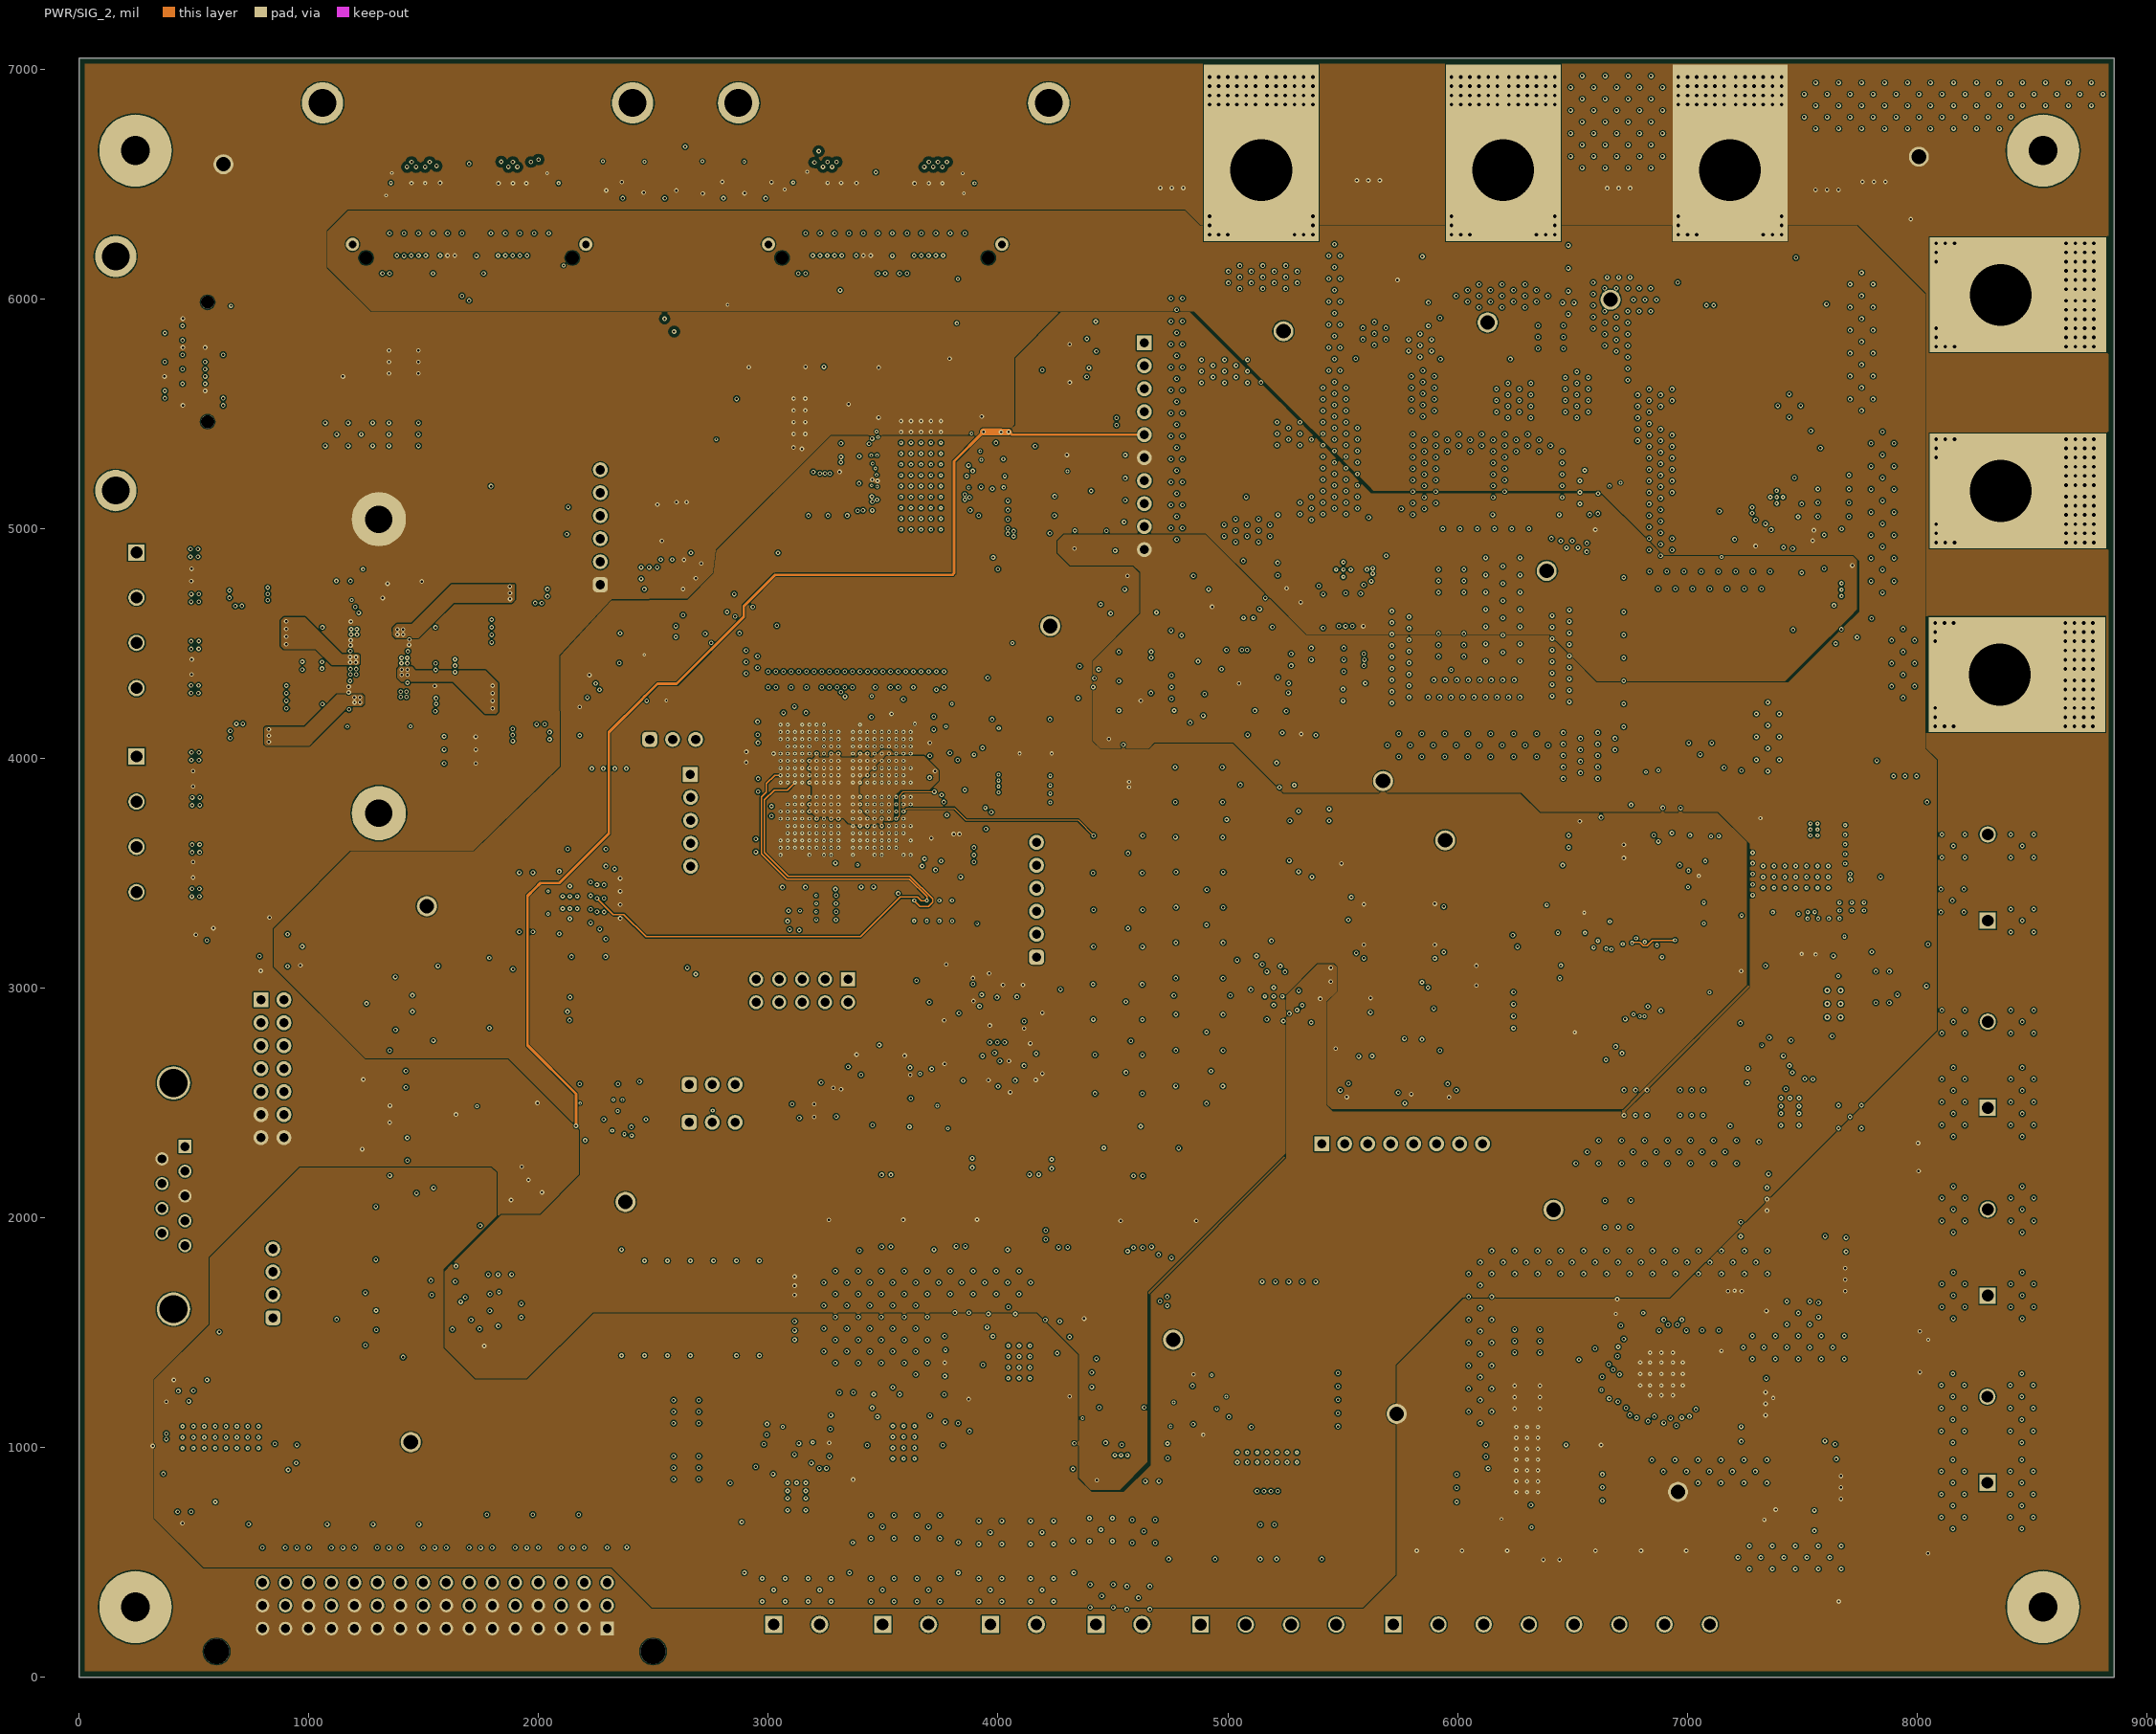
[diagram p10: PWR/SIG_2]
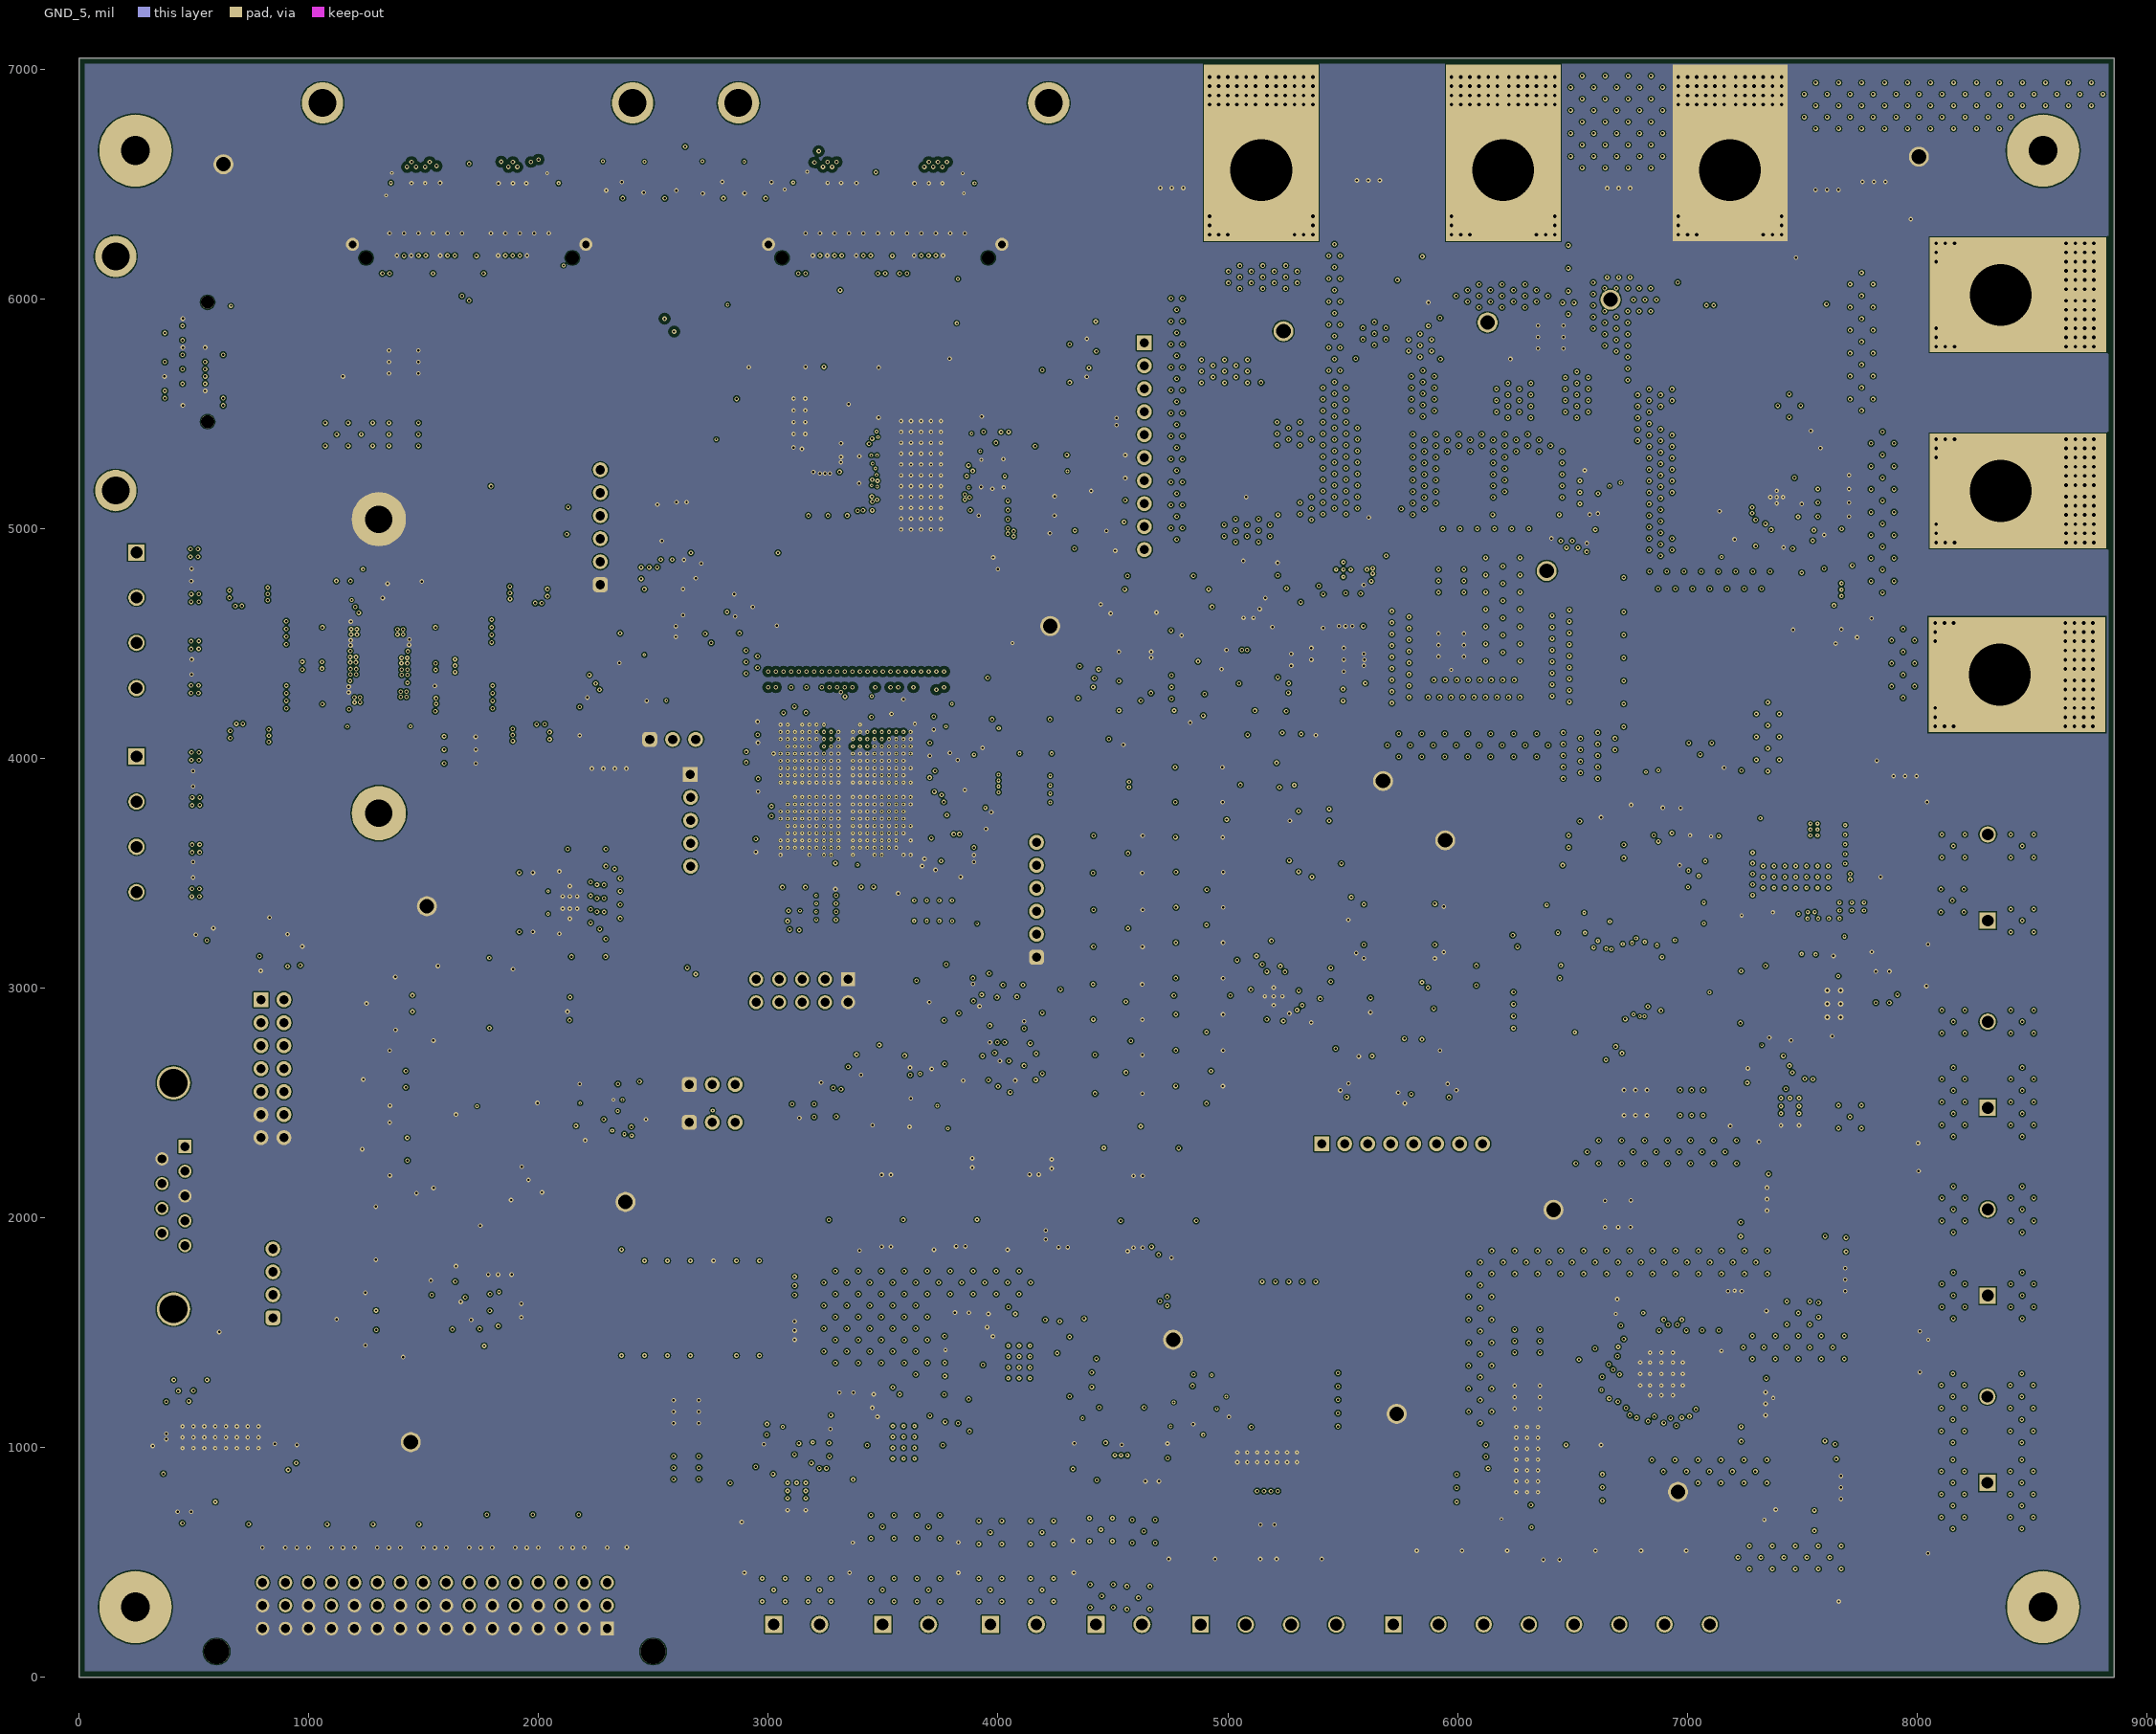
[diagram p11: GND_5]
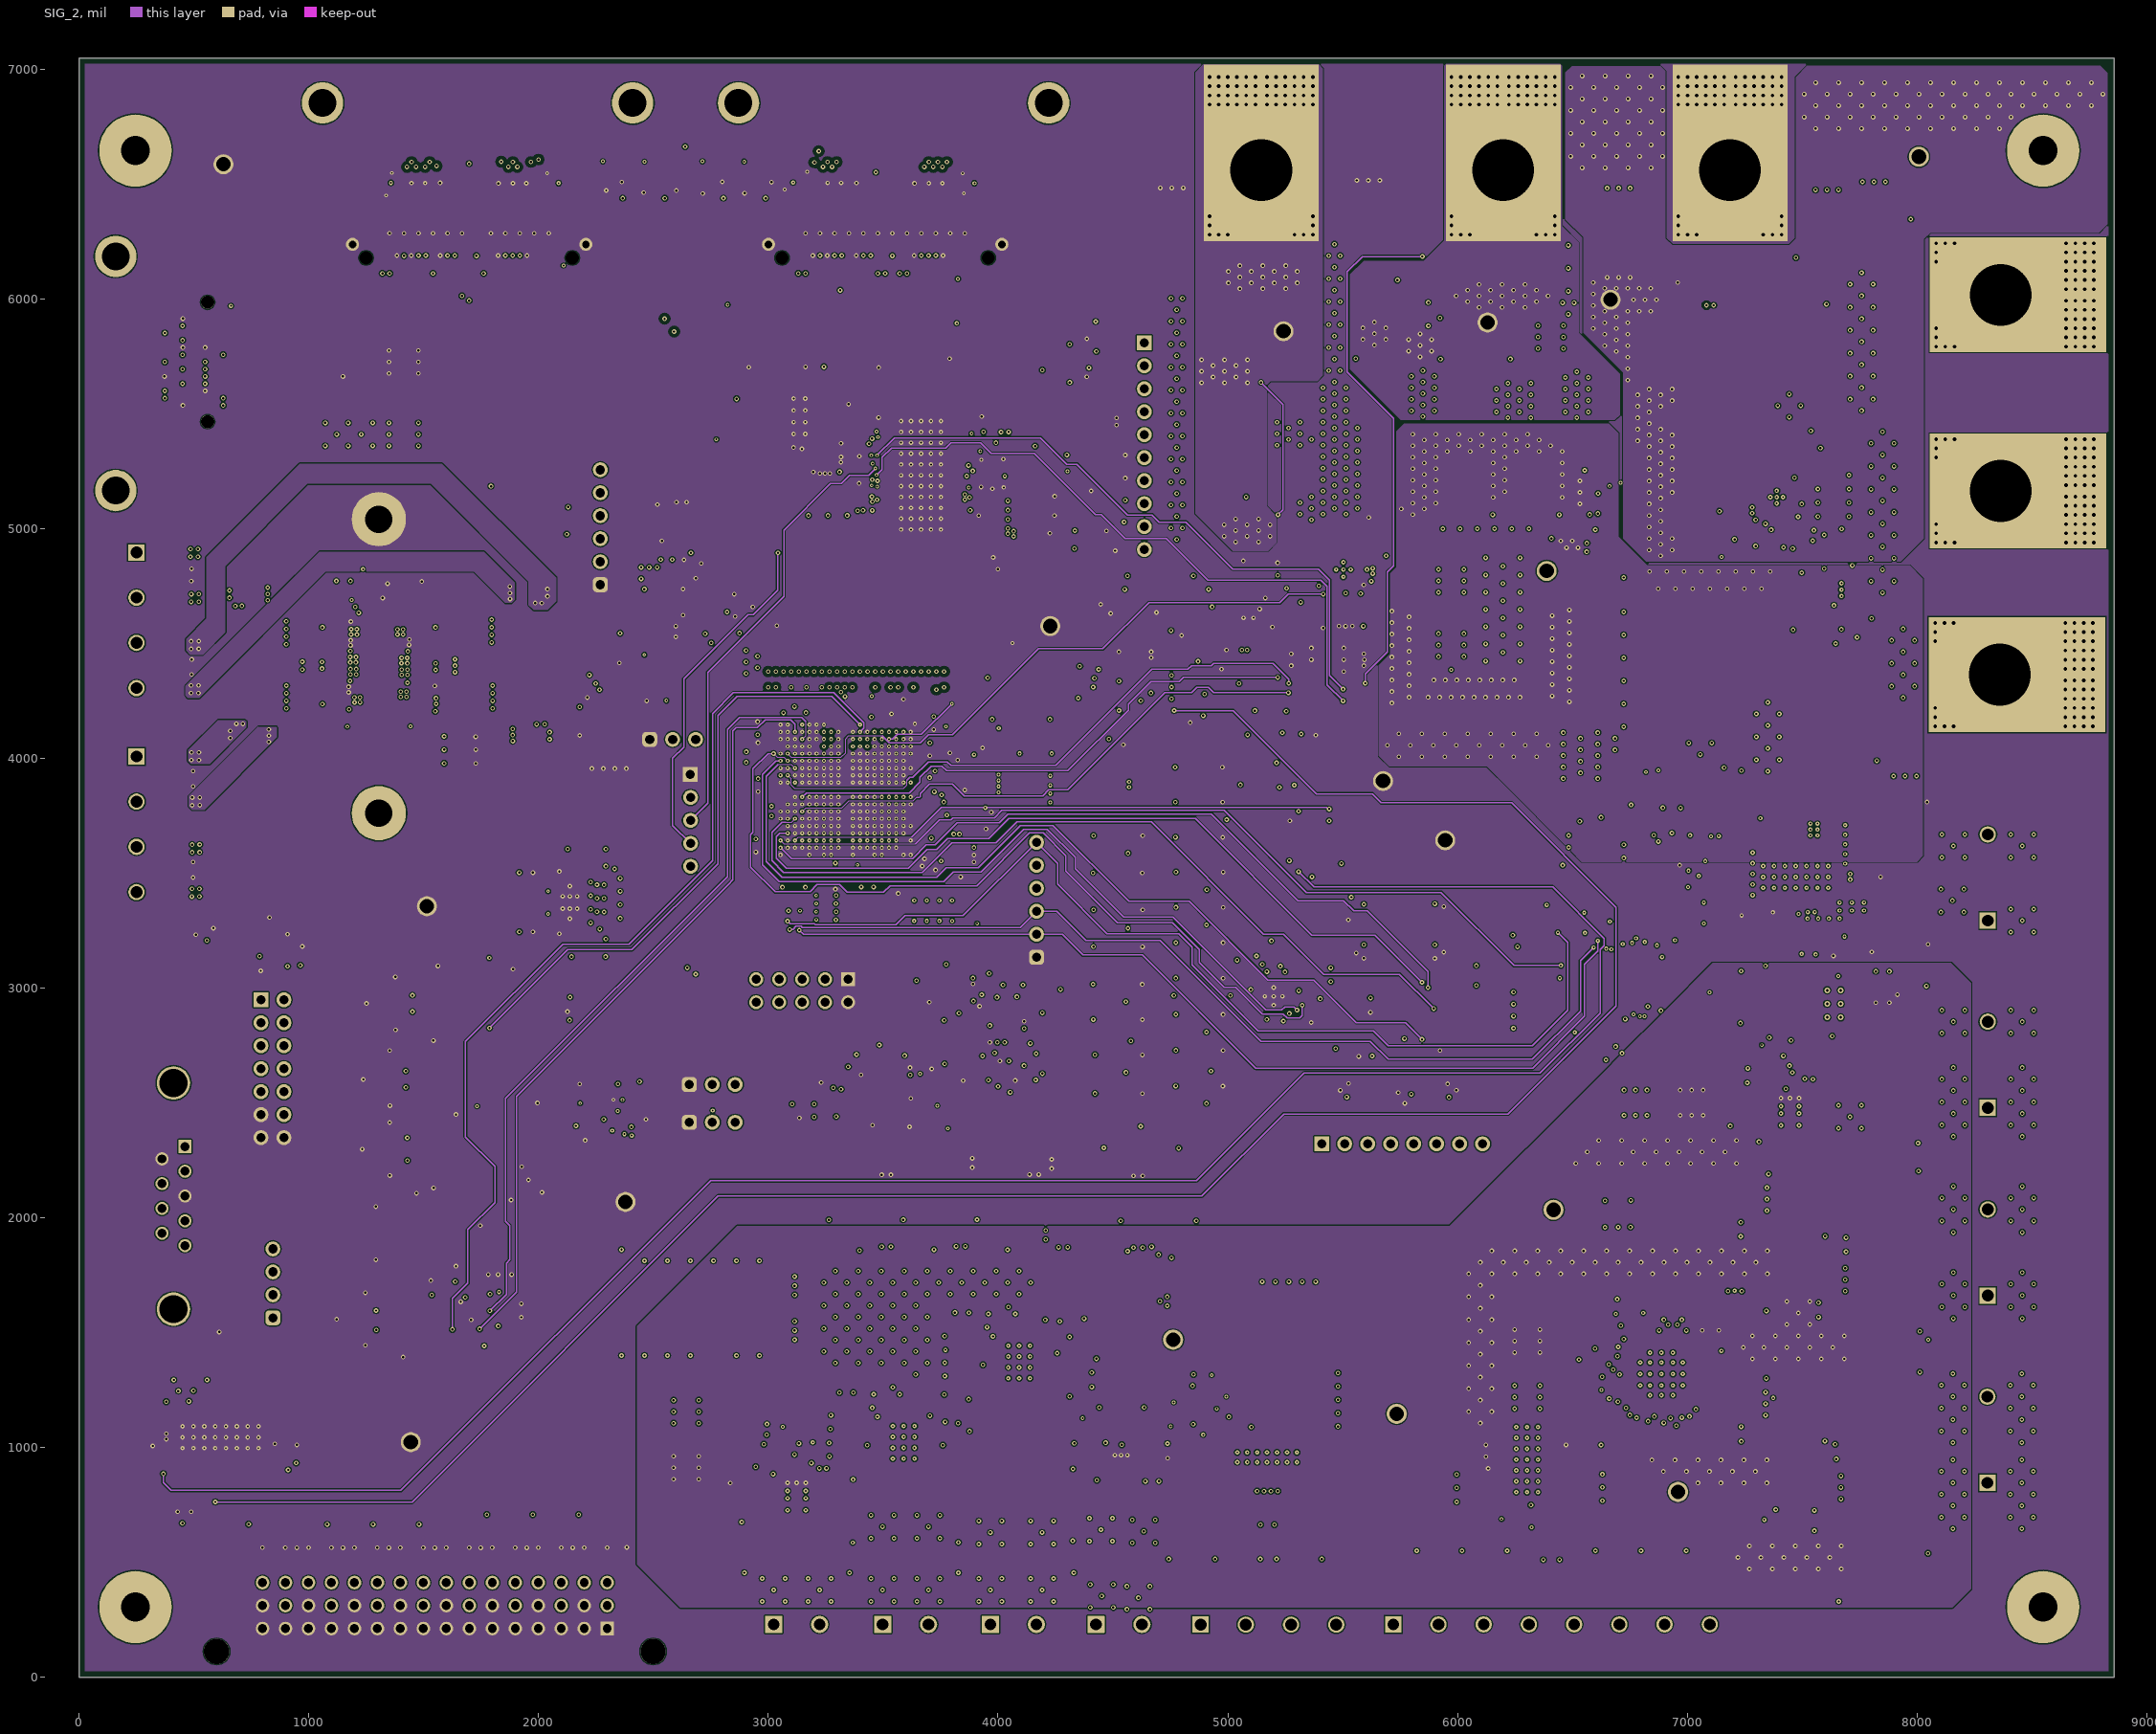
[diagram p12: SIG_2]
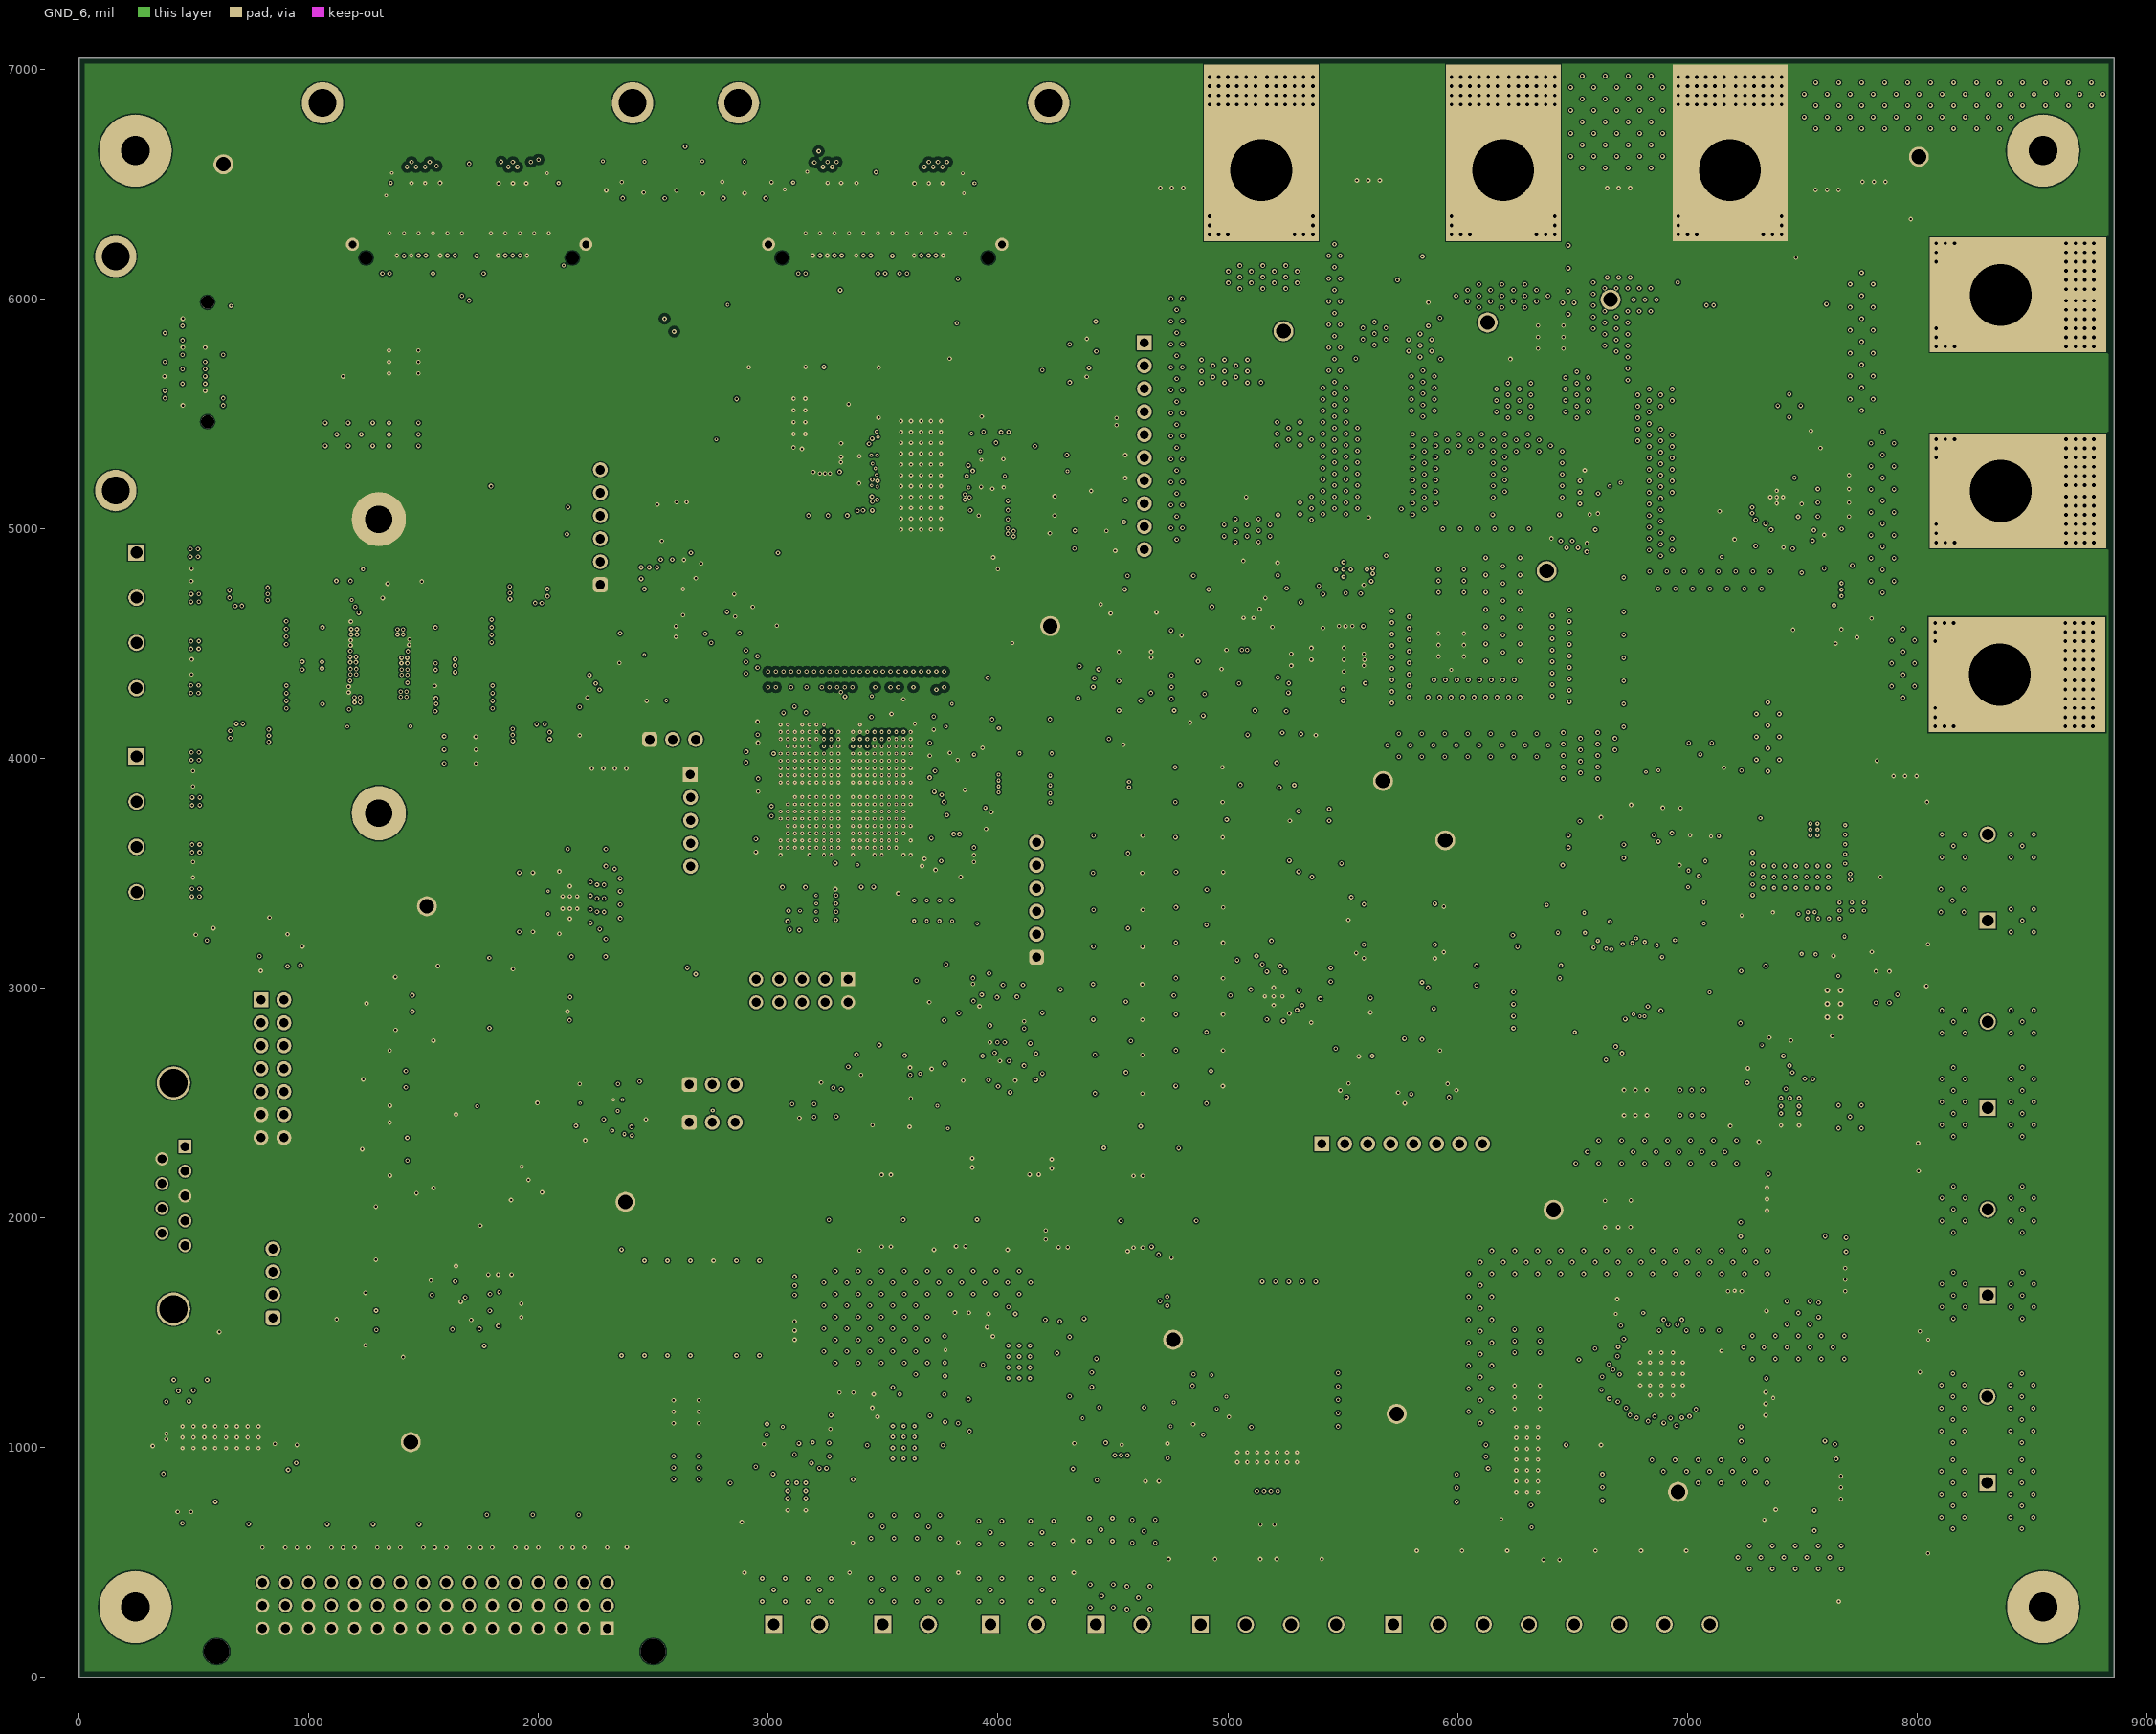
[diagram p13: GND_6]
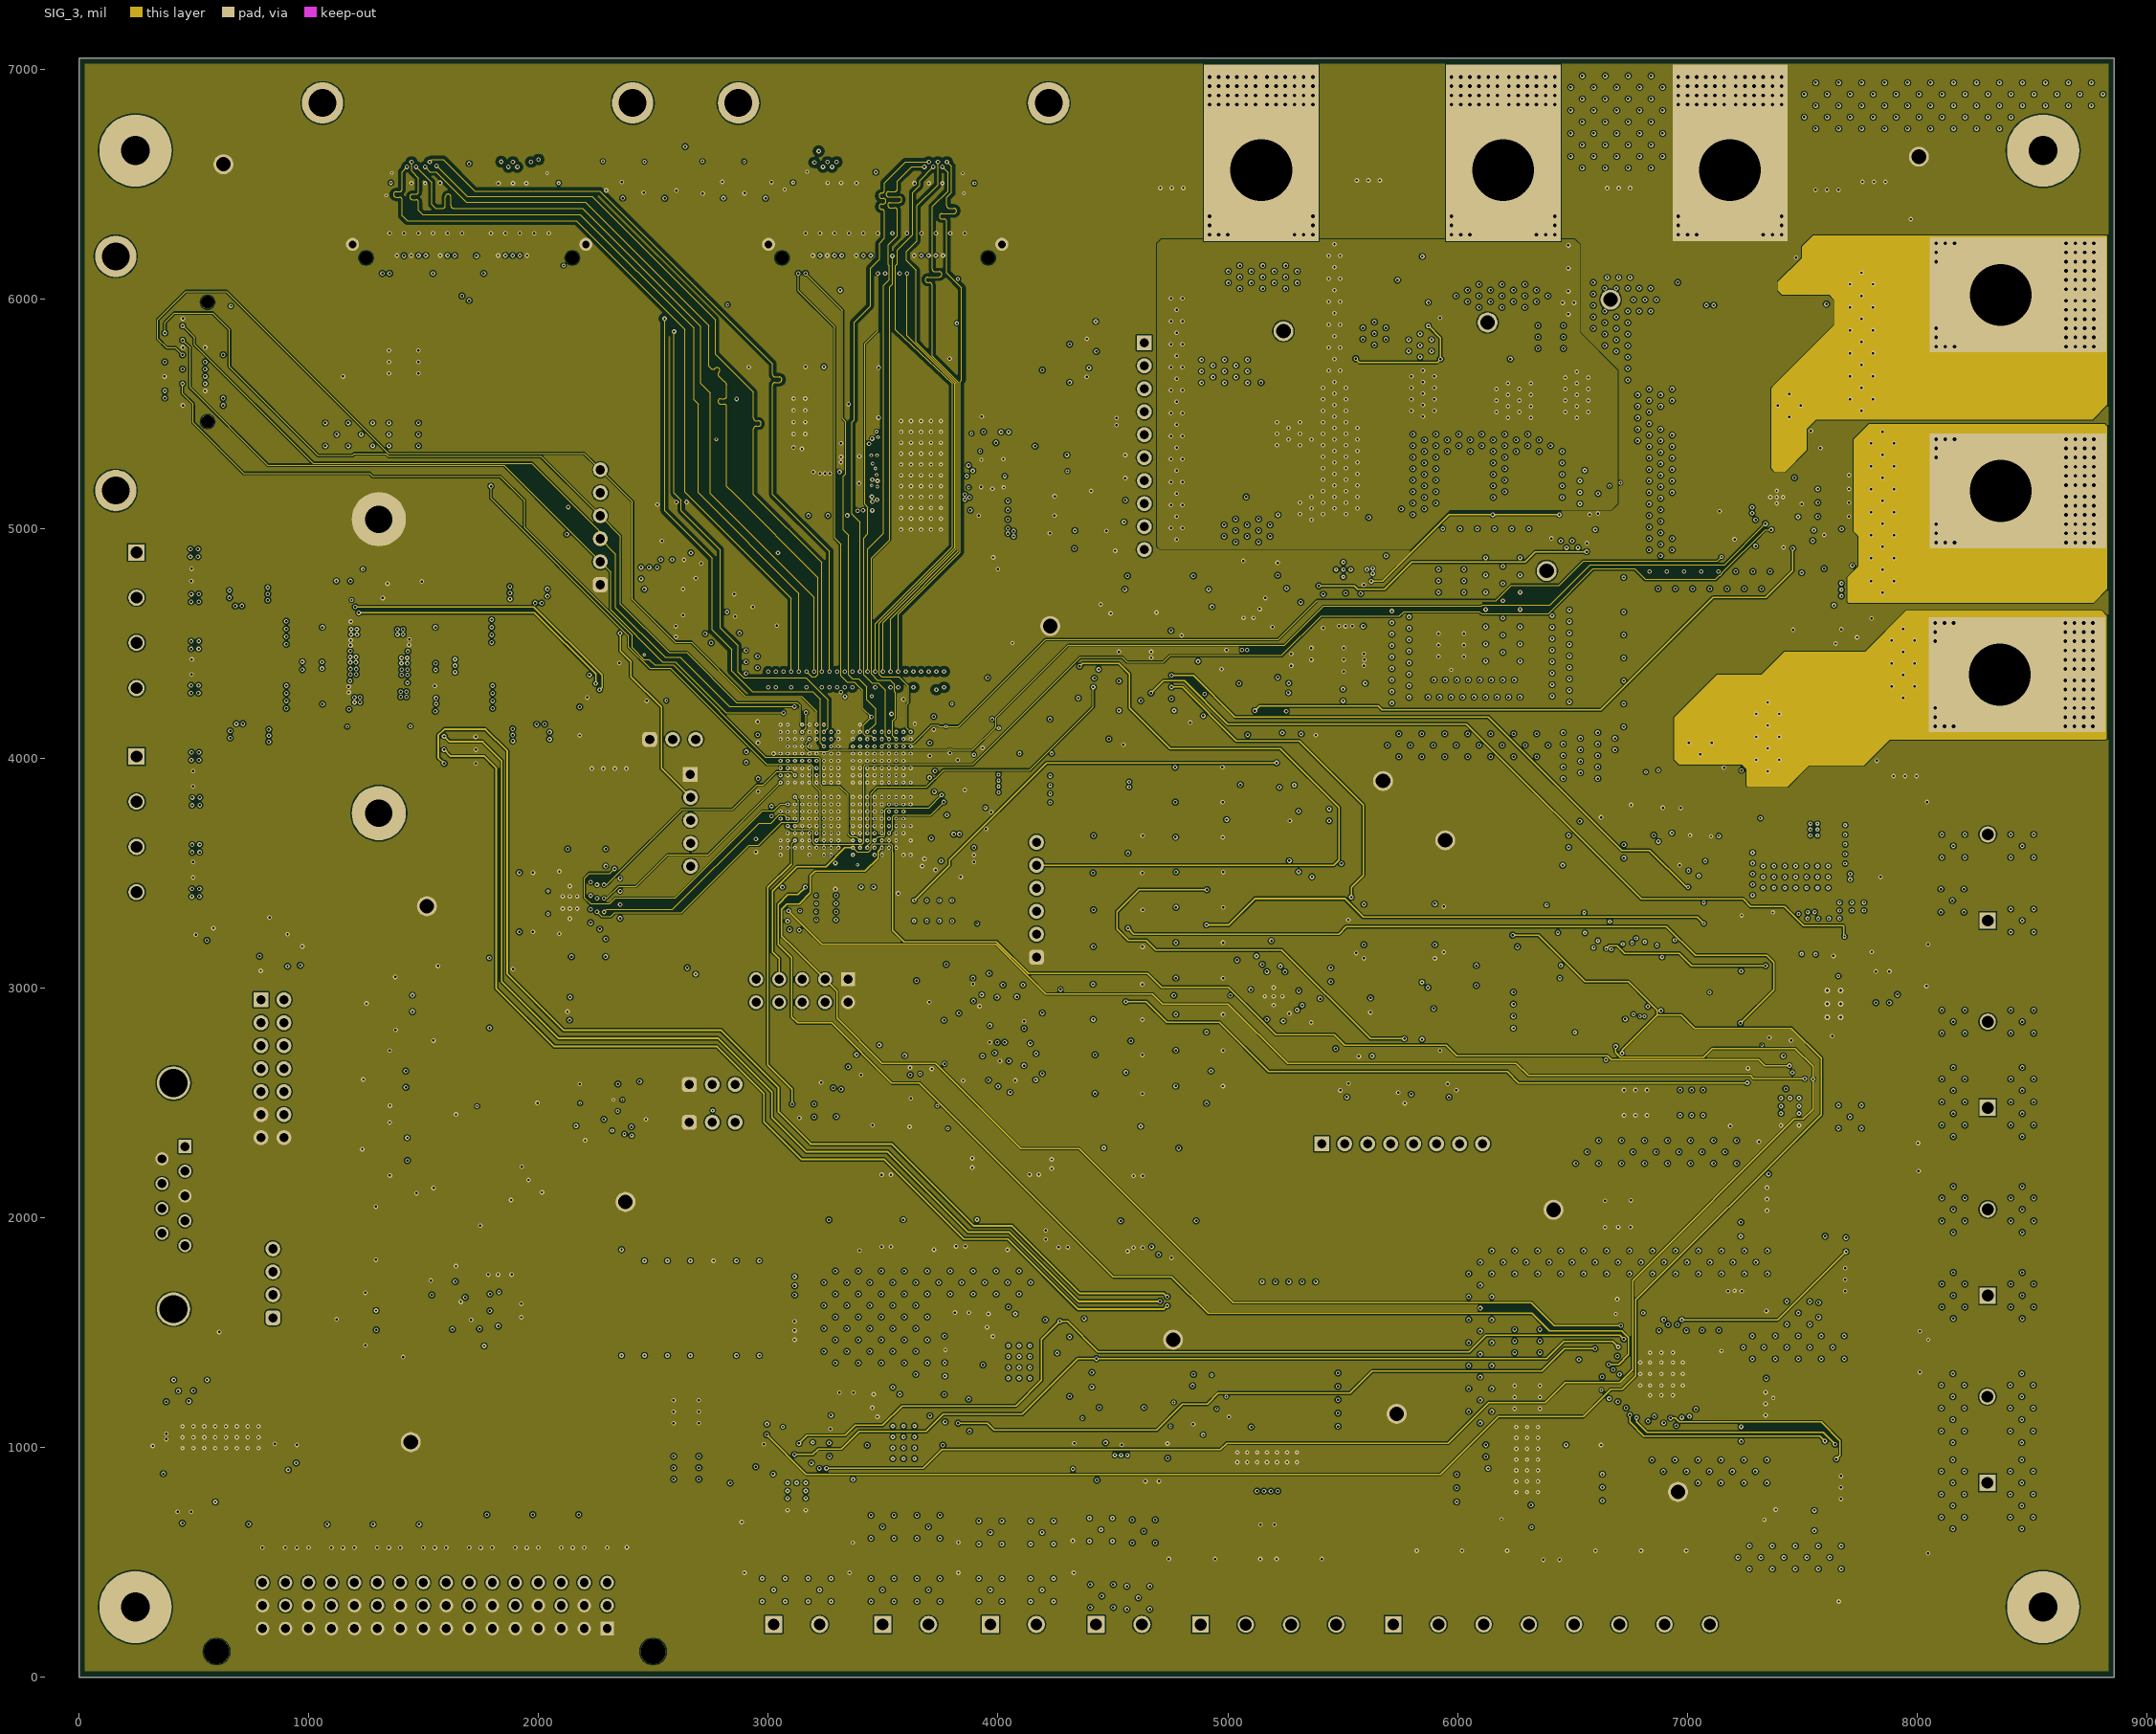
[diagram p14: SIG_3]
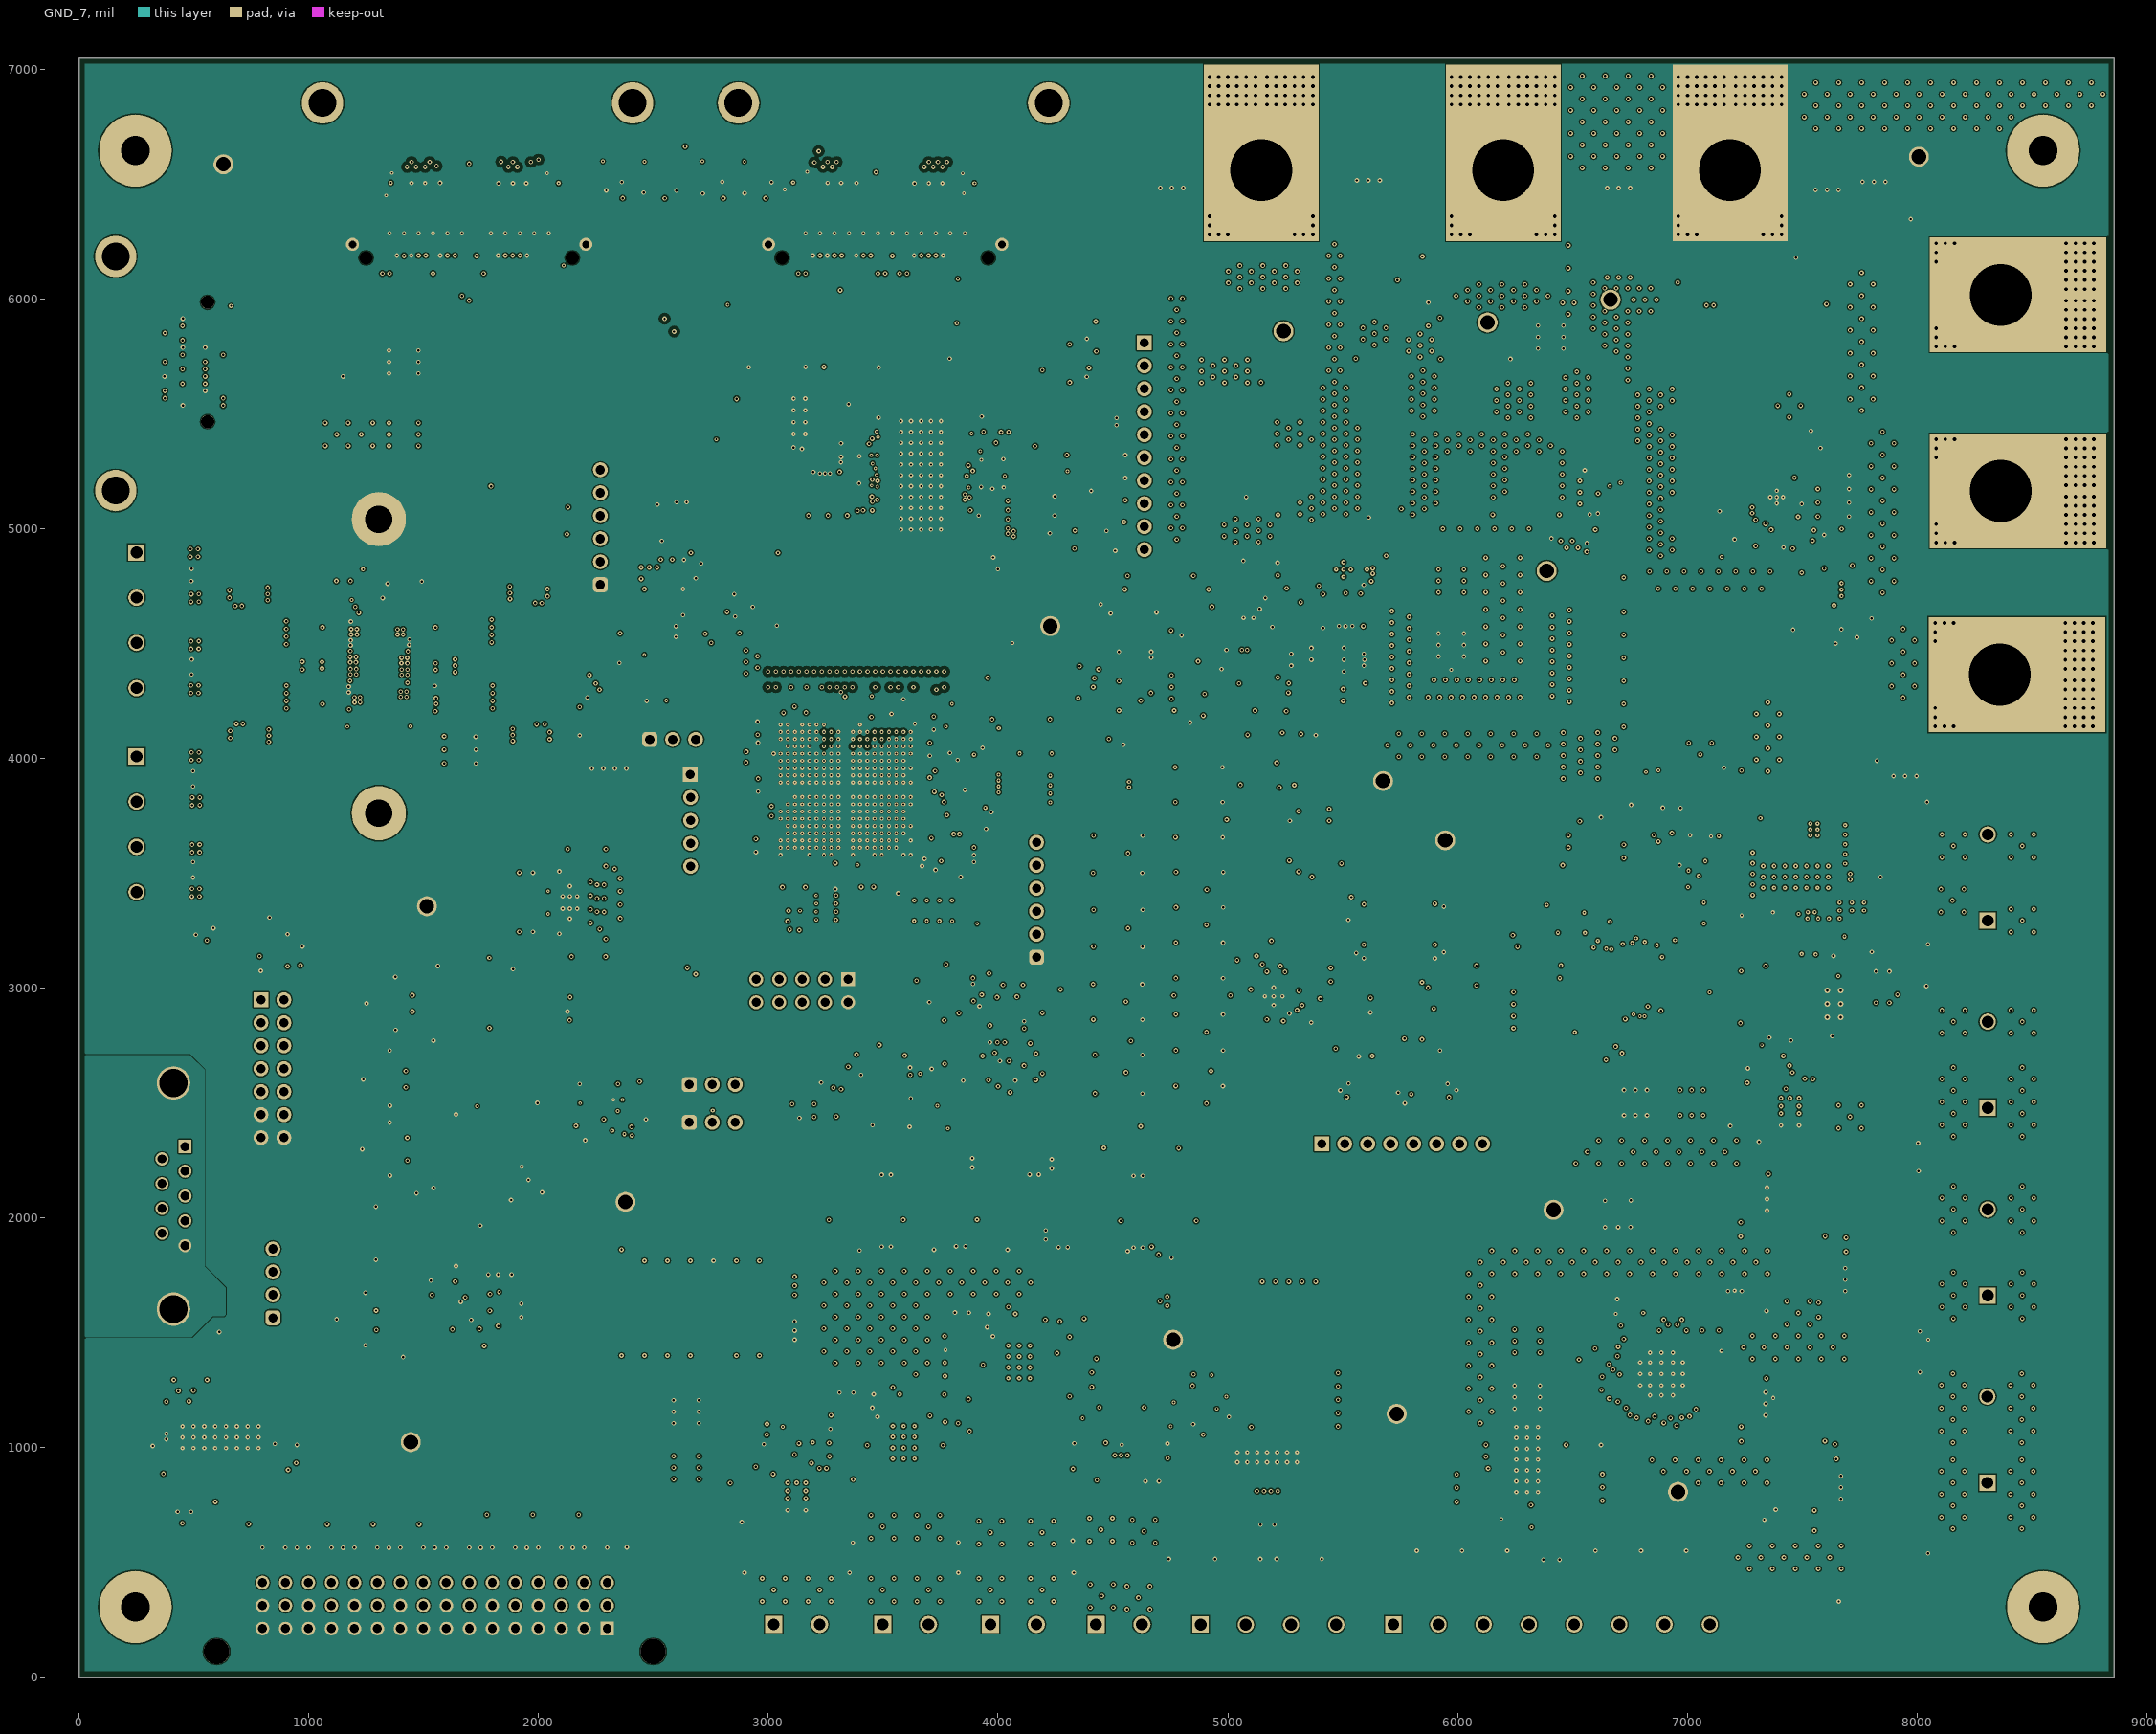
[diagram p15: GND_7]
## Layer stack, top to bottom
Top Solder: solder mask 0.4, Solder Resist, Dk 3.5
Top Layer: signal copper 0.7
Dielectric 11: prepreg 5.9, PP-006, Dk 4.1
GND_1: signal copper 0.7
Dielectric 9: core 3.9, Core-009, Dk 4.5
SIG_1: signal copper 0.7
Dielectric 7: prepreg 5, PP-006, Dk 4.1
GND_2: signal copper 0.7
Dielectric 5: core 3.9, Core-009, Dk 4.5
PWR/SIG_1: signal copper 1.378
Dielectric 3: prepreg 4, PP-006, Dk 4.1
GND_3: signal copper 0.7
Dielectric 1: core 3.9, Core-009, Dk 4.5
PWR_1: signal copper 1.378
Dielectric1: prepreg 4, PP-006, Dk 4.1
PWR_2: signal copper 1.378
Dielectric 2: core 3.9, Core-009, Dk 4.5
GND_4: signal copper 0.7
Dielectric 4: prepreg 4, PP-006, Dk 4.1
PWR/SIG_2: signal copper 1.378
Dielectric 6: core 3.9, Core-009, Dk 4.5
GND_5: signal copper 0.7
Dielectric 14: prepreg 4, PP-006, Dk 4.1
SIG_2: signal copper 1.378
Dielectric 13: core 3.9, Core-009, Dk 4.5
GND_6: signal copper 1.378
Dielectric 8: prepreg 5, PP-006, Dk 4.1
SIG_3: signal copper 0.7
Dielectric 10: core 3.9, Core-009, Dk 4.5
GND_7: signal copper 0.7
Dielectric 12: prepreg 5.9, PP-006, Dk 4.1
Bottom Layer: signal copper 0.7
Bottom Solder: solder mask 0.4, Solder Resist, Dk 3.5

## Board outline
0,0 0,7047.08 8858.11,7047.08 8858.11,0 5850,0

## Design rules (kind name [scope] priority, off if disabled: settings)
AcuteAngle [All] p1: minimum=4.50000000000000E+0001 checktracksonly=FALSE
AssemblyTestPointUsage [All] p1: valid=2
BoardOutlineClearance BoardOutlineClearance_MountingHoles [OnCopper and InComponentClass('Mounting Holes')] p1: gap=39.37 ignorepadtopadclearanceinfootprint=FALSE
BoardOutlineClearance BoardOutlineClearance_Poly [OnCopper and IsPoly] p2: gap=25 ignorepadtopadclearanceinfootprint=FALSE
BoardOutlineClearance [OnCopper and Not InComponentClass('Logo') and not InComponentClass('FiducialMark') and not InRegion(1000,500,4000,800) and not InPoly] p3: gap=25 ignorepadtopadclearanceinfootprint=FALSE
Clearance "RGMII Polygon Clearance" [InNetClass('50ohm') vs InNet('GND')] p1: gap=15 ignorepadtopadclearanceinfootprint=TRUE except(5: Arc-SMDPad Arc-Via Arc-Hole Track-SMDPad Track-Via Track-Hole SMDPad-SMDPad SMDPad-Via SMDPad-Hole THPad-Via THPad-Hole Via-Via Via-Hole Fill-Hole Poly-Hole Region-Hole Text-Hole)
Clearance Clearance_Keepouts [((IsTrack Or IsArc) And Not InPoly) And IsFree and IsKeepOut vs ((IsTrack Or IsArc) And Not InPoly) And IsFree and IsKeepOut] p2: gap=0 ignorepadtopadclearanceinfootprint=FALSE
Clearance Clearance_BGA_Inner [WithinRoom('BGA') vs OnMid] p3: gap=8 ignorepadtopadclearanceinfootprint=TRUE except(2: Text-Text; 4: Arc-Arc Arc-Track Arc-Via Track-Track Track-Via SMDPad-Via THPad-Via Via-Via Via-Fill Via-Poly Via-Region; 5: Arc-SMDPad Track-SMDPad; 10: Fill-Fill Fill-Poly Fill-Region Poly-Poly Poly-Region Region-Region)
Clearance Clearance_BGA_Outer [WithinRoom('BGA') vs OnOutside] p4: gap=8 ignorepadtopadclearanceinfootprint=TRUE except(2: Text-Text; 4: Arc-Via Track-Via Via-Fill Via-Poly Via-Region; 5: Arc-SMDPad Track-SMDPad SMDPad-Via; 6: Arc-Arc Arc-Track Track-Track Via-Via; 10: Fill-Fill Fill-Poly Fill-Region Poly-Poly Poly-Region Region-Region)
Clearance Clearance_Poly [InPolygon] p5: gap=5 ignorepadtopadclearanceinfootprint=TRUE
Clearance Clearance_FiducialMark [IsKeepOut and InComponentClass('FiducialMark') vs IsPad and InComponentClass('FiducialMark')] p6: gap=0 ignorepadtopadclearanceinfootprint=FALSE
Clearance [All] p7: gap=3.94 ignorepadtopadclearanceinfootprint=TRUE
ComponentClearance ComponentClearance_Heatsink [InComponent('U43') vs InComponent('H13')] p1: gap=0 collisioncheckmode=3 verticalgap=0 showdistances=FALSE
ComponentClearance ComponentClearance_MountingHoles_FiducialMarks [InComponentClass('Mounting Holes') vs InComponentClass('FiducialMark')] p2: gap=50 collisioncheckmode=3 verticalgap=10 showdistances=FALSE
ComponentClearance ComponentClearance_Shunt [InComponentClass('Header') vs InComponentClass('Shunt')] p3: gap=0 collisioncheckmode=3 verticalgap=0 showdistances=FALSE
ComponentClearance ComponentClearance_Logo [InComponentClass('Logo')] p4: gap=30 collisioncheckmode=3 verticalgap=10 showdistances=FALSE
ComponentClearance ComponentClearance_ScrewToNut [(HasFootprint('NY PMS 440 0025 PH')) vs (HasFootprint('Keystone_1902C'))] p5: gap=5 collisioncheckmode=3 verticalgap=10 showdistances=FALSE
ComponentClearance ComponentClearance_MountingHoles [InComponentClass('Mounting Holes')] p6: gap=100 collisioncheckmode=3 verticalgap=100000 showdistances=FALSE
ComponentClearance ComponentClearance_SmallPassives [HasFootprint('0201*') or HasFootprint('0402*') or HasFootprint('0508') or HasFootprint('0603*') or HasFootprint('0612') or HasFootprint('0805*') or HasFootprint('0815*') or HasFootprint('0830*') or HasFootprint('1206*') or HasFootprint('1210*') or HasFootprint('1808*') or HasFootprint('1812*') or HasFootprint('1825*') or HasFootprint('2010*') or HasFootprint('2220*') or HasFootprint('2225*') or HasFootprint('2512*') or HasFootprint('2728*') or HasFootprint('3518*') vs HasFootprint('0201*') or HasFootprint('0402*') or HasFootprint('0508') or HasFootprint('0603*') or HasFootprint('0612') or HasFootprint('0805*') or HasFootprint('0815*') or HasFootprint('0830*') or HasFootprint('1206*') or HasFootprint('1210*') or HasFootprint('1808*') or HasFootprint('1812*') or HasFootprint('1825*') or HasFootprint('2010*') or HasFootprint('2220*') or HasFootprint('2225*') or HasFootprint('2512*') or HasFootprint('2728*') or HasFootprint('3518*')] p7: gap=14.96 collisioncheckmode=3 verticalgap=10 showdistances=FALSE
ComponentClearance ComponentClearance_THtoSMT [IsThruComponent vs IsSMTComponent] p8: gap=30 collisioncheckmode=3 verticalgap=30 showdistances=FALSE
ComponentClearance ComponentClearance_THtoTH [IsThruComponent vs IsThruComponent] p9: gap=20 collisioncheckmode=3 verticalgap=30 showdistances=FALSE
ComponentClearance [All] p10: gap=20 collisioncheckmode=3 verticalgap=10 showdistances=FALSE
DiffPairsRouting [InDifferentialPairClass('All Differential Pairs')] p1: maxlimit=10 minlimit=7.8 mostfreqgap=10 toplayer_maxgap=7.8 toplayer_prefgap=7.8 toplayer_minwidth=4 toplayer_maxwidth=4 toplayer_prefwidth=4 bottomlayer_maxgap=7.8 bottomlayer_prefgap=7.8 bottomlayer_minwidth=4 bottomlayer_maxwidth=4 bottomlayer_prefwidth=4 impedanceprofiledriven=TRUE impedanceprofileid={B26EC2ED-3F71-405D-8DA8-618565256D38} impedanceprofilevalue=120.000000 maxuncoupledlength=1000
FabricationTestPointUsage TestPointUsage [All] p1: valid=2 allowmultiple=FALSE
FabricationTestpoint Testpoint [All] p1: side=3 testpointundercomponent=TRUE minsize=40 maxsize=100 preferedsize=60 minholesize=0 maxholesize=40 preferedholesize=32 testpointgrid=1 allowsidetop=TRUE allowsidebottom=TRUE usegrid=TRUE gridtolerance=0.01
FanoutControl Fanout_LCC [IsLCC] p1: bgadir=Out bgaviamode=Centered fanoutstyle=Auto fanoutdirection=Alternating viagrid=1 // Fanout_LCC (Default Rule)
FanoutControl Fanout_BGA [IsBGA] p2: bgadir=Out bgaviamode=Centered fanoutstyle=Auto fanoutdirection=Alternating viagrid=1 // Fanout_BGA (Default Rule)
FanoutControl Fanout_Default [All] p4: bgadir=Out bgaviamode=Centered fanoutstyle=Auto fanoutdirection=Alternating viagrid=1 // Fanout_Default (Default Rule)
FanoutControl Fanout_Small [(CompPinCount < 5)] p5: bgadir=Out bgaviamode=Centered fanoutstyle=Auto fanoutdirection=OutThenIn viagrid=1 // Fanout_Small (Default Rule)
Height Height_Heatsink [InComponent('H13')] p1: minheight=0 maxheight=2000 prefheight=500
Height [All] p2: minheight=0 maxheight=1000 prefheight=500
HoleSize [All] p1: absolutevalues=TRUE maxlimit=271 minlimit=7.87 maxpercent=80.000 minpercent=20.000
MinimumAnnularRing MinimumAnnularRing_ThermalPadVias [IsVia and InAnyComponent] p1: minimumring=5.91
MinimumAnnularRing [All] p2: minimumring=4
MinimumSolderMaskSliver MinimumSolderMaskSliver_Logo [InComponentClass('Logo') vs InComponentClass('Logo')] p1: minsoldermaskwidth=0.7
MinimumSolderMaskSliver [All] p2: minsoldermaskwidth=1.5
PlaneConnect [All] p1: planeconnectstyle=Relief reliefexpansion=10 reliefentries=4 reliefconductorwidth=10 reliefairgap=10
PolygonConnect [All] p1: connectstyle=Direct reliefconductorwidth=10 reliefentries=4 polygonreliefangle="90 Angle" airgapwidth=10
RoutingVias ThermalPadVias [IsVia and InAnyComponent] p1: holewidth=7.87 width=19.68 viastyle="Through Hole" minholewidth=7.87 minwidth=19.68 maxholewidth=16 maxwidth=32
RoutingVias [All] p2: holewidth=16 width=20 viastyle="Through Hole" minholewidth=7.87 minwidth=16 maxholewidth=40 maxwidth=65
SilkToBoardRegionClearance [Not ((IsComment or IsDesignator) And (Hide <> 'False')) and not InRegion(1000,500,4000,800)] p1:
SilkToSilkClearance SilkToSilkClearance_Pb-FreeLogo [(HasFootprint('Pb-Free_Overlay_Medium') OR HasFootprint('Pb-Free_Overlay_Small')) vs (HasFootprint('Pb-Free_Overlay_Medium') OR HasFootprint('Pb-Free_Overlay_Small'))] p1: silktosilkclearance=0
SilkToSilkClearance [All] p2: silktosilkclearance=3.94
SilkToSolderMaskClearance SilkToSolderMaskClearance_Footprints [HasFootprint('SOD-123') or HasFootprint('SMB') or HasFootprint('SOD-323') or HasFootprint('SOT-23')] p1: minsilkscreentomaskgap=3.5 clearancetoexposedcopper=TRUE
SilkToSolderMaskClearance SilkToComponentPadClearance [(IsPad or IsFill or IsRegion) and InAnycomponent] p2: minsilkscreentomaskgap=5 clearancetoexposedcopper=TRUE
SilkToSolderMaskClearance "Silk to Solder Mask Opening" [All] p3: minsilkscreentomaskgap=3.94 clearancetoexposedcopper=FALSE
SolderMaskExpansion [All] p1: expansion=1.97 istentingtop=FALSE
SupplyNets "Schematic Supply Nets_19" [InNet('TPS1HC04_IC_GND')] p1: voltage=0.000
SupplyNets "Schematic Supply Nets_18" [InNet('VS')] p2: voltage=0.000
SupplyNets "Schematic Supply Nets_17" [InNet('6V0_BB')] p3: voltage=0.000
SupplyNets "Schematic Supply Nets_16" [InNet('12V_VBATT_1')] p4: voltage=0.000
SupplyNets "Schematic Supply Nets_15" [InNet('12V_ALWAYS_ON')] p5: voltage=0.000
SupplyNets "Schematic Supply Nets_14" [InNet('1V2')] p6: voltage=0.000
SupplyNets "Schematic Supply Nets_13" [InNet('1V8')] p7: voltage=0.000
SupplyNets "Schematic Supply Nets_12" [InNet('5V0_1')] p8: voltage=0.000
SupplyNets "Schematic Supply Nets_11" [InNet('3V3_1')] p9: voltage=0.000
SupplyNets "Schematic Supply Nets_9" [InNet('SHIELD_GND')] p10: voltage=0.000
SupplyNets "Schematic Supply Nets_8" [InNet('VDDS18_LDO')] p11: voltage=0.000
SupplyNets "Schematic Supply Nets_7" [InNet('5V0_2')] p12: voltage=0.000
SupplyNets "Schematic Supply Nets_6" [InNet('5V_TRACK')] p13: voltage=0.000
SupplyNets "Schematic Supply Nets_5" [InNet('3V3_2')] p14: voltage=0.000
SupplyNets "Schematic Supply Nets_4" [InNet('1V1')] p15: voltage=0.000
SupplyNets "Schematic Supply Nets_3" [InNet('3V3_ALWAYS_ON')] p16: voltage=0.000
SupplyNets "Schematic Supply Nets_2" [InNet('GND')] p17: voltage=0.000
SupplyNets "Schematic Supply Nets_1" [InNet('12V_VBATT_2')] p18: voltage=0.000
SupplyNets "Schematic Supply Nets" [InNet('VDDA18_LDO')] p19: voltage=0.000
UnRoutedNet [All] p1: checkbadconnections=TRUE
Width Width_50Ohm [InNetClass('50ohm')] p1: maxlimit=10 minlimit=3.6 preferedwidth=10 toplayer_minwidth=9.9 toplayer_maxwidth=9.9 toplayer_prefwidth=9.9 midlayer2_maxwidth=3.6 midlayer2_prefwidth=3.6 midlayer11_maxwidth=3.6 midlayer11_prefwidth=3.6 bottomlayer_minwidth=9.9 bottomlayer_maxwidth=9.9 bottomlayer_prefwidth=9.9 impedanceprofiledriven=TRUE impedanceprofileid={22B06C10-33A0-4624-B183-3587ED3DEAF1} impedanceprofilevalue=50.000000 minimp=50.000000 maximp=50.000000 favimp=50.000000
Width [All] p2: maxlimit=100 minlimit=4 preferedwidth=6 toplayer_minwidth=5 toplayer_prefwidth=8 bottomlayer_minwidth=5 bottomlayer_prefwidth=8 minimp=50.000000 maximp=50.000000 favimp=50.000000 checkconnectedcopper=TRUE
13 further rules are at their usual default settings.

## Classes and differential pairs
net class 50ohm: ClassD_AMP_FSYNC ClassD_AMP_SCLk CRS_DV/RX_CTRL_ETH1 CRS_DV/RX_CTRL_ETH2 I2S_FSYNC_ETH_MCU I2S_SCLK_ETH_MCU NetR231_2 NetR232_2 NetR233_2 NetR234_2 NetR235_2 NetR236_2 NetR237_2 NetR241_1 NetR242_1 NetR243_1 NetR244_1 NetR245_1 NetR246_1 NetR247_1 NetR248_1 NetR249_1 NetR250_1 NetR251_1 NetR252_1 PR0_PRU0_GPIO0 PR0_PRU0_GPIO1 PR0_PRU0_GPIO2 PR0_PRU0_GPIO3 PR0_PRU0_GPIO6 PR0_PRU0_GPIO11 PR0_PRU0_GPIO12 PR0_PRU0_GPIO13 PR0_PRU0_GPIO14 PR0_PRU0_GPIO15 PR0_PRU0_GPIO16 RGMII1_RD0 RGMII1_RD1 RGMII1_RD2 RGMII1_RD3 RGMII1_RXC RGMII1_TD0 RGMII1_TD1 RGMII1_TD2 RGMII1_TD3 RGMII1_TX_CTL RGMII1_TXC
component class "Mounting Holes": H1 H2 H3 H4
component class Logo: Logo2
component class Label: LBL1
component class HeatSink: H9
component class Hardware: !PCB1 FID1 FID2 FID3 H1 H2 H3 H4 H5 H6 H7 H8 LBL1 Logo1 Logo2 Logo3 Logo4 LOGO5 ZZ1 ZZ2 ZZ3 ZZ4
component class FiducialMark: FID1 FID2 FID3
component class AssemblyNote: ZZ1 ZZ2 ZZ3 ZZ4
component class "Zone Reference Design Top Sheet": D40 R478
component class "TLIN1021A and TLIN1024A": C46 C47 C48 C49 C50 C51 C52 C53 D13 D14 D15 D16 D17 R64 R65 R66 R67 R68 R69 R70 R71 R72 R73 U10 U11
component class "Temp Sensor/EEPROM": C254 C255 R316 R317 R318 R319 U36 U37
component class TCAN1046AV: C28 C29 C30 C31 C32 C33 C34 C35 C36 D10 D11 L3 L4 R46 R47 R48 R49 R50 R51 R52 R53 U7 U8
component class "TCAN1043A and TCAN1044V": C17 C18 C19 C20 C21 C22 C23 C24 C25 C26 C27 D8 D9 L1 L2 R36 R37 R38 R39 R40 R41 R42 R43 R44 R45 U5 U6
component class "Standard HSS": C76 C77 C78 C79 C80 C81 C82 C83 C84 C85 C86 C87 C88 C89 C90 C91 C92 C93 C94 C95 D18 R111 R112 R113 R114 R115 R116 R117 R118 R119 R120 R121 R122 R123 R124 R125 R126 R127 R128 R129 R130 R131 R132 R133 R134 R135 R136 R137 R138 R139 R140 R141 R142 R143 R144 R145 R146 R147 R148 R149 U23 U24 U25 U26
component class "Standard HSSC": C304 C305 C306 C307 C308 C309 C405 D53 Q19 Q20 Q21 R368 R369 R370 R371 R372 R373 R374 R375 R376 R377 R378 R379 R380 R381 R382 R383 R474 R475 U42
component class "Smart Fuse HSS": C58 C59 C60 C61 C62 C63 C64 C65 C66 C67 C68 C69 C70 C71 C72 C73 C74 C75 R80 R81 R82 R83 R84 R85 R86 R87 R88 R89 R90 R91 R92 R93 R94 R95 R96 R97 R98 R99 R100 R101 R102 R103 R104 R105 R106 R107 R108 R109 R110 U20 U21 U22
component class "Smart Fuse HSSC": C388 C389 C390 C391 C392 C393 C394 C395 C396 C397 C398 C399 C400 C401 C402 C403 C404 D56 D57 Q23 Q24 R452 R453 R454 R455 R456 R457 R458 R459 R460 R461 R462 R463 R464 R465 R466 R467 R468 R469 R470 R471 R472 R473 R479 R482 RNTC_1 U56
component class POWER: C302 C303 D41 D42 D43 D44 D45 D46 D47 D48 D49 D50 D51 D52 Q15 Q16 Q17 Q18 R343 R344 R345 R346 R347 R348 R349 R350 R351 R352 R353 R354 R355 R356 R357 R358 SW5 SW6 SW7 TP10 TP11 TP12 TP13 TP14 TP15 TP16 TP17 TP18 TP19 TP20 TP21
component class "Power ORing": C1 C2 C3 C4 C5 C6 C7 C8 C9 C10 C11 C12 C13 C14 C15 C16 D4 D5 D6 D7 Q1 Q2 Q3 Q4 Q5 Q6 R15 R16 R17 R18 R19 R20 R21 R22 R23 R24 R25 R26 R27 R28 R29 R30 R31 R32 R33 R34 R35 T4 T5 T6 TP1 TP2 TP3 TP4 U1 U2 U3 U4
component class PMIC: C264 C265 C266 C267 C268 C269 C270 C271 C272 C273 C274 C275 C276 C277 C278 C279 C280 C281 C282 C283 C284 C285 C286 C287 C288 C289 C290 C291 C292 C293 C294 C295 C296 C297 C298 C299 C300 C301 J14 L6 R331 R332 R333 R334 R335 R336 R337 R338 R339 R340 R341 R342 R476 TP8 TP9 U41
component class "MUXes and TPLD": C373 C374 C375 C376 C377 C378 C379 C380 C381 C382 C383 C384 C385 D55 D58 R418 R419 R420 R421 R422 R423 R424 R425 R426 R427 R428 R429 R430 R431 R432 R433 R434 R435 R436 R437 R438 R439 R440 R441 R442 R443 R444 R445 TP23 TP24 TP25 TP26 U48 U49 U50 U51 U52 U53
component class MSDI: C133 C134 C135 C136 C137 C138 C139 C140 C141 C142 C143 C144 C145 C146 C147 C148 C149 C150 C151 C152 C153 C154 C155 C156 C157 C158 C159 C160 C161 C162 D19 R180 R181 R182 R183 R184 R185 R186 R187 R188 R189 R190 R191 R192 R193 R194 R195 R196 R197 R198 R199 R200 R201 R202 R203 R204 R205 R206 R207 U31
component class MCU: J15 J16 J17 J18 J19 J20 J21 J22 R359 R360 R361 R362 R363 R364 R365 R366 R367
component class "LOAD DRIVERS": D1 D2 D3 J1 J2 J3 J4 J5 J6 J7 J8 J9 J10 R1 R2 R3 R4 R5 R6 R7 R8 R9 R10 R11 R12 R13 R14 T1 T2 T3
component class "IO Mgmt": J28 J29
component class "IO Expanders": C386 C387 R446 R447 R448 R449 R450 R451 U54 U55
component class Header: J14 J15 J16 J17 J18 J19 J21 J22 J23 J25 J28 J29
component class "Half Bridge Gate Driver": C96 C97 C98 C99 C100 C101 C102 C103 C104 C105 C106 C107 C108 C109 C110 C111 NT1 NT2 NT3 NT4 NT5 NT6 Q7 Q8 Q9 Q10 Q11 Q12 Q13 Q14 R150 R151 R152 R153 R154 R155 R156 R157 R158 R159 R160 R161 R162 R163 R164 U27
component class "H-Bridge, Half Bridge, HS/LS": C112 C113 C114 C115 C116 C117 C118 C119 C120 C121 C122 C123 C124 C125 C126 C127 C128 C129 C130 C131 C132 R165 R166 R167 R168 R169 R170 R171 R172 R173 R174 R175 R176 R177 R178 R179 U28 U29 U30
component class "Extra Power": C358 C359 C360 C361 C362 C363 C364 C365 C366 C367 C368 C369 C370 C371 C372 L11 L12 Q22 R398 R399 R400 R401 R402 R403 R404 R405 R406 R407 R408 R409 R410 R411 R412 R413 R414 R415 R416 R417 T7 U44 U45 U46 U47
component class ETHERNET: C54 C55 C56 C57 C406 C407 C408 C409 C410 C411 C412 C413 C414 C415 C416 C417 C418 C419 C420 C421 J11 J12 J13 R74 R75 R76 R77 R78 R79 U12 U13 U14 U15 U16 U17 U18 U19
component class CAN/LIN: D54 J23 J24 J25 R384 R385
component class AUDIO: C310 C311 C312 C313 C314 C315 C316 C317 C318 C319 C320 C321 C322 C323 C324 C325 C326 C327 C328 C329 C330 C331 C332 C333 C334 C335 C336 C337 C338 C339 C340 C341 C342 C343 C344 C345 C346 C347 C348 C349 C350 C351 C352 C353 C354 C355 C356 C357 H9 J26 J27 L7 L8 L9 L10 R386 R387 R388 R389 R390 R391 R392 R393 R394 R395 R396 R397 TP22 U43
component class "RESET CIRCUIT": C256 C257 C258 C259 C260 C261 C262 C263 D39 R320 R321 R322 R323 R324 R325 R326 R327 R328 R329 R330 R477 SW2 SW3 SW4 TP7 U38 U39 U40 Y2
component class "AM263Px Power Caps": C163 C164 C165 C166 C167 C168 C169 C170 C171 C172 C173 C174 C175 C176 C177 C178 C179 C180 C181 C182 C183 C184 C185 C186 C187 C188 C189 C190 C191 C192 C193 C194 C195 C196 C197 C198 C199 C200 C201 C202 C203 C204 C205 C206 C207 C208 C209 C210 C211 C212 C213 C214 C215 C216 C217 C218 C219 D20 FB1 FB2 R208 R209 R210 R211 R212 R213 TP5
component class "OSPI Bootmode": C220 C221 C222 C223 C224 C225 C226 C227 R253 R254 R255 R256 R257 R258 R259 R260 R261 R262 R263 R264 R265 R266 R267 R268 R269 R270 R271 R272 R273 R274 R275 R276 R277 R278 R279 R280 R281 R282 R283 R284 R285 R286 R287 R288 R289 R290 R291 R292 R293 SW1 U33 U34 U35
component class "AM263Px IO": R214 R215 R216 R217 R218 R219 R220 R221 R222 R223 R224 R225 R226 R227 R228 R229 R230 R231 R232 R233 R234 R235 R236 R237 R238 R239 R240 R241 R242 R243 R244 R245 R246 R247 R248 R249 R250 R251 R252
component class ADC: C228 C229 C230 C231 C232 C233 C234 C235 C236 C237 C238 C239 C240 C241 C242 C243 C244 C245 C246 C247 C248 C249 C250 C251 C252 C253 D21 D22 D23 D24 D25 D26 D27 D28 D29 D30 D31 D32 D33 D34 D35 D36 D37 D38 R294 R295 R296 R297 R298 R299 R300 R301 R302 R303 R304 R305 R306 R307 R308 R309 R310 R311 R312 R313 R314 R315 S1 TP6 U32
differential pair CAN_1044: +CAN_1044_P -CAN_1044_N
differential pair CAN_1043: +CAN_1043_P -CAN_1043_N
differential pair CAN2_1046: +CAN2_1046_P -CAN2_1046_N
differential pair CAN1_1046: +CAN1_1046_P -CAN1_1046_N

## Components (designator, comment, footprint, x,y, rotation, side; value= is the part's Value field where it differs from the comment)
C1 "C0603C103J5RACTU" 0603 5696.37,5002.89 r180 top value=0.01uF
C2 "06035C104K4Z4A" 0603L 5079.98,5195.4 r270 top value=0.1uF
C3 "EEEFP1H101AP" Panasonic_SMT_800x1020 5972.29,4631.88 r270 top value=100uF
C4 "GRM188R61H225KE11D" 0603 6377.53,4998.39 r0 top value=2.2uF
C5 "C0603C103J5RACTU" 0603 6539.98,5029.02 r270 top value=0.01uF
C6 "GCM188R71H224KA64D" 0603 5472.13,5016.57 r0 top value=0.22uF
C7 "06035C104K4Z4A" 0603L 5584,5016.55 r0 top value=0.1uF
C8 "06035C104K4Z4A" 0603L 5249.21,4822.6 r270 top value=0.1uF
C9 "C0603C332K5RACTU" 0603 5630.4,4911.97 r90 top value=3300pF
C10 "06035C104KAZ2A" 0603 5483.73,4645.84 r270 top value=0.1uF
C11 "06035C104K4Z4A" 0603L 6553.43,5309.76 r270 top value=0.1uF
C12 "06035C104K4Z4A" 0603L 6716.6,5012.59 r0 top value=0.1uF
C13 "C0603C103J5RACTU" 0603 6677.52,5232.76 r180 top value=0.01uF
C14 "EEEFP1H101AP" Panasonic_SMT_800x1020 6406.23,5713.03 r90 top value=100uF
C15 "GRM188R61H225KE11D" 0603 6191.78,5705.87 r90 top value=2.2uF
C16 "06035C104K4Z4A" 0603L 5762.23,5967.51 r90 top value=0.1uF
C17 "06035C104KAZ2A" 0603 1855.72,1566.07 r0 top value=0.1uF
C18 "06035C104KAZ2A" 0603 1568.33,1695.79 r90 top value=0.1uF
C19 "06035C104KAZ2A" 0603 1855.72,1625.04 r0 top value=0.1uF
C20 "C0603C472K5RACTU" 0603 1593.31,1557.66 r180 bottom value=4700pF
C21 "08051A200JAT2A" 0805_HV 1181.71,1635.51 r90 top value=20pF
C22 "08051A200JAT2A" 0805_HV 1181.71,1484.62 r270 top value=20pF
C23 "06035C104KAZ2A" 0603 2082.53,2928.2 r270 top value=0.1uF
C24 "06035C104KAZ2A" 0603 1818.07,3081.46 r0 top value=0.1uF
C25 "C0603C472K5RACTU" 0603 1746.24,2933.33 r180 bottom value=4700pF
C26 "08051A200JAT2A" 0805_HV 1319.93,3007.47 r90 top value=20pF
C27 "08051A200JAT2A" 0805_HV 1321.11,2856.57 r270 top value=20pF
C28 "06035C104KAZ2A" 0603 2124.44,2367.69 r270 top value=0.1uF
C29 "C0603C472K5RACTU" 0603 1715.47,2300 r180 bottom value=4700pF
C30 "06035C104KAZ2A" 0603 1709.51,2448.99 r180 top value=0.1uF
C31 "08051A200JAT2A" 0805_HV 1295.8,2374.05 r90 top value=20pF
C32 "08051A200JAT2A" 0805_HV 1296.38,2223.16 r270 top value=20pF
C33 "06035C104KAZ2A" 0603 2210.12,2544.98 r180 top value=0.1uF
C34 "C0603C472K5RACTU" 0603 1718,2587.67 r180 bottom value=4700pF
C35 "08051A200JAT2A" 0805_HV 1295.51,2678.01 r90 top value=20pF
C36 "08051A200JAT2A" 0805_HV 1296.69,2527.11 r270 top value=20pF
C46 "06035C104KAZ2A" 0603 828.37,3105.75 r270 top value=0.1uF
C47 "CL10B221JB8NNNC" 0603 828.44,3231.77 r90 top value=220pF
C48 "06035C104KAZ2A" 0603 2056.74,3289.19 r0 top value=0.1uF
C49 "06035C104KAZ2A" 0603 2056.74,3454.42 r0 top value=0.1uF
C50 "CL10B221JB8NNNC" 0603 2058.52,3543.49 r0 bottom value=220pF
C51 "CL10B221JB8NNNC" 0603 1975.13,3433.63 r90 bottom value=220pF
C52 "CL10B221JB8NNNC" 0603 1975.19,3311.73 r270 bottom value=220pF
C53 "CL10B221JB8NNNC" 0603 2058.52,3198.99 r0 bottom value=220pF
C54 "HMK107B7104KAHT" 0603 2457.29,6527.57 r270 top value=0.1uF
C55 "HMK107B7104KAHT" 0603 2896.66,6527.78 r270 top value=0.1uF
C56 "HMK107B7104KAHT" 0603 2277.6,6527.77 r270 top value=0.1uF
C57 "HMK107B7104KAHT" 0603 2714.63,6527.92 r270 top value=0.1uF
C58 "C1608X7R1H474K080AC" 0603 3840.27,1425.27 r180 top value=0.47uF
C59 "CGA3E2X7R2A223K080AA" 0603 3858.48,489.93 r180 top value=0.022uF
C60 "GCM155R71H104KE02D" 0402 4021.5,1580.76 r180 top value=0.1uF
C61 "C0603X102K5RACTU" 0603 4018.8,1522.81 r180 top value=1000pF
C62 "CGA3E2X7R2A223K080AA" 0603 4298.1,490 r0 top value=0.022uF
C63 "GCM188R72A472KA37D" 0603 3873.05,1515.01 r90 top value=4700pF
C64 "C1608X7R1H474K080AC" 0603 3337.33,1080.12 r180 top value=0.47uF
C65 "CGA3E2X7R2A223K080AA" 0603 3384.48,554.25 r180 top value=0.022uF
C66 "GCM155R71H104KE02D" 0402 3518.27,1230.81 r180 top value=0.1uF
C67 "C0603X102K5RACTU" 0603 3514.81,1172.01 r180 top value=1000pF
C68 "CGA3E2X7R2A223K080AA" 0603 3795.49,550 r0 top value=0.022uF
C69 "GCM188R72A472KA37D" 0603 3370.11,1171.07 r90 top value=4700pF
C70 "CGA3E2X7R2A223K080AA" 0603 8045.45,3257.72 r270 top value=0.022uF
C71 "C1608X7R1H474K080AC" 0603 7393.86,3275.44 r180 top value=0.47uF
C72 "CGA3E2X7R2A223K080AA" 0603 8043.97,3739.22 r90 top value=0.022uF
C73 "C0603C102K5RACTU" 0603 7178.8,3249.94 r270 top value=1000pF
C74 "GCM155R71H104KE02D" 0402 7270.03,3325.44 r270 top value=0.1uF
C75 "C0603X102K5RACTU" 0603 7776.5,3482.81 r0 top value=1000pF
C76 "CGA3E2X7R2A223K080AA" 0603 4710.51,546.63 r0 top value=0.022uF
C77 "GCJ188R71H224KA01D" 0603 4707.04,920.8 r270 top value=0.22uF
C78 "06035C104KAZ2A" 0603 4647.54,920.74 r270 top value=0.1uF
C79 "GCJ188R71H224KA01D" 0603 7879.73,3001.94 r90 top value=0.22uF
C80 "06035C104KAZ2A" 0603 7820.98,3001.94 r90 top value=0.1uF
C81 "CGA3E2X7R2A223K080AA" 0603 4363.22,557.32 r180 top value=0.022uF
C82 "CGA3E2X7R2A223K080AA" 0603 8041.07,2938.41 r90 top value=0.022uF
C83 "06035C104KAZ2A" 0603 4400.19,1020.06 r180 bottom value=0.1uF
C84 "06035C104KAZ2A" 0603 7390.54,2815.03 r270 top value=0.1uF
C85 "CGA3E2X7R2A223K080AA" 0603 5440.53,550 r180 top value=0.022uF
C86 "CGA3E2X7R2A223K080AA" 0603 7801.71,4674.21 r270 bottom value=0.022uF
C87 "GCJ188R71H224KA01D" 0603 5202.92,731.04 r270 top value=0.22uF
C88 "06035C104KAZ2A" 0603 5142.64,731.04 r270 top value=0.1uF
C89 "GCJ188R71H224KA01D" 0603 7739,4592.38 r270 bottom value=0.22uF
C90 "06035C104KAZ2A" 0603 7642.73,4623.97 r180 bottom value=0.1uF
C91 "CGA3E2X7R2A223K080AA" 0603 5243.68,550 r180 top value=0.022uF
C92 "06035C104KAZ2A" 0603 7595.95,4902.94 r90 top value=0.1uF
C93 "CGA3E2X7R2A223K080AA" 0603 5109.82,550 r0 top value=0.022uF
C94 "CGA3E2X7R2A223K080AA" 0603 4912.97,550 r0 top value=0.022uF
C95 "06035C104KAZ2A" 0603 5070.51,1133.5 r180 bottom value=0.1uF
C96 "EEE-FT1H331AP" SM_RADIAL_G 6877.69,2016.79 r180 top value=330uF
C97 "885012207103" 0805L 7659.14,393.93 r270 top value=1uF
C98 "885012207103" 0805L 7337.05,758.54 r270 top value=1uF
C99 "CGA6P3X7S1H106K250AB" 1210_280 7207.07,1575.2 r90 top value=10uF
C100 "885012206095" 0603L 7180.19,1450.39 r180 top value=0.1uF
C101 "885012206052" 0603L 7134.06,1349.08 r180 top value=1uF
C102 "885012206095" 0603L 7134.06,1289.48 r180 top value=0.1uF
C103 "885012206095" 0603L 7134.06,1231.8 r180 top value=0.1uF
C104 "06035C104KAZ2A" 0603 8047.57,605.52 r270 top value=0.1uF
C105 "C0603X105J9RACAUTO" FP-C0603X105J9RACAUTO_0603-MFG 6754.01,1644.96 r0 top value=1µF
C106 "C0603C104K9RAC7867" 0603L 6751.79,1583.96 r0 top value=0.1uF
C107 "06035C104KAZ2A" 0603 8047.57,1295.78 r90 top value=0.1uF
C108 "885012207103" 0805L 7344.22,1671.87 r270 top value=1uF
C109 "885012207103" 0805L 7182.1,2469.72 r270 top value=1uF
C110 "06035C104KAZ2A" 0603 8047.57,1536.66 r270 top value=0.1uF
C111 "06035C104KAZ2A" 0603 8041.68,2170.75 r90 top value=0.1uF
C112 "EEE-2AA100UP" SM_RADIAL_E 2642.7,1033.22 r90 top value=10uF
C113 "EEE-2AA100UP" SM_RADIAL_E 6896.75,2500.29 r180 top value=10uF
C114 "C3216X7R2A104K160AA" 1206_180 2883.95,777.91 r270 top value=0.1uF
C115 "885012206095" 0603 3321.77,490 r180 top value=0.1uF
C116 "C3216X7R2A104K160AA" 1206_180 7311.72,2440.2 r270 top value=0.1uF
C117 "C0603X105J9RACAUTO" FP-C0603X105J9RACAUTO_0603-MFG 7586.55,2545.6 r270 top value=1µF
C118 "885012206095" 0603 8039.68,2355.93 r90 top value=0.1uF
C119 "885012206095" 0603 2927.26,490 r0 top value=0.1uF
C120 "885012206095" 0603 2980.43,946.7 r270 top value=0.1uF
C121 "885012206095" 0603 7300.01,2618.15 r270 top value=0.1uF
C122 "EEE-2AA100UP" SM_RADIAL_E 6303.27,1340.31 r270 top value=10uF
C123 "CGA3E3X7S2A683K080AB" 0603 6554.15,1010.02 r0 top value=0.068uF
C124 "885012205018" FP-885012205018_0402-MFG 6231.48,688.11 r180 top value=100nF
C125 "CGA3E2X7R2A103K080AA" 0603 6475.81,550 r180 top value=0.01uF
C126 "CGA3E2X7R2A103K080AA" 0603 6341.95,550 r0 top value=0.01uF
C127 "CGA3E2X7R2A103K080AA" 0603 6670.74,550 r180 top value=0.01uF
C128 "CGA3E2X7R2A103K080AA" 0603 6145.1,550 r0 top value=0.01uF
C129 "CGA3E2X7R2A103K080AA" 0603 6869.51,550 r180 top value=0.01uF
C130 "CGA3E2X7R2A103K080AA" 0603 5948.18,550 r0 top value=0.01uF
C131 "CGA3E2X7R2A103K080AA" 0603 7066.36,550 r180 top value=0.01uF
C132 "CGA3E2X7R2A103K080AA" 0603 5751.4,550 r0 top value=0.01uF
C133 "GCE188R71H103KA01D" FP-GCE188R71H103KA01D_0603-MFG 2298.37,510.03 r270 top value=10nF
C134 "GCE188R71H103KA01D" FP-GCE188R71H103KA01D_0603-MFG 2383.97,511.01 r270 top value=10nF
C135 "CGA4J1X7R1H475K125AC" FP-CGA4J1X7R1H475K125AC_0805-MFG 909.86,968.25 r270 top value=4.7µF
C136 "GCM155R71H104KE02D" 0402 851.82,955.15 r90 top value=0.1uF
C137 "GCE188R71H103KA01D" FP-GCE188R71H103KA01D_0603-MFG 948.11,509.04 r270 bottom value=10nF
C138 "GCE188R71H103KA01D" FP-GCE188R71H103KA01D_0603-MFG 797.93,510.03 r270 top value=10nF
C139 "GCM188R71E104KA57D" 0603 379.38,1126.41 r90 top value=0.1uF
C140 "GCE188R71H103KA01D" FP-GCE188R71H103KA01D_0603-MFG 897.43,510.03 r270 top value=10nF
C141 "GCE188R71H103KA01D" FP-GCE188R71H103KA01D_0603-MFG 998.8,510.03 r270 top value=10nF
C142 "GCE188R71H103KA01D" FP-GCE188R71H103KA01D_0603-MFG 1148.46,509.04 r270 bottom value=10nF
C143 "GCE188R71H103KA01D" FP-GCE188R71H103KA01D_0603-MFG 1098.36,510.03 r270 top value=10nF
C144 "GCE188R71H103KA01D" FP-GCE188R71H103KA01D_0603-MFG 1198.56,510.03 r270 top value=10nF
C145 "885012206020" 0603 379.37,968.26 r270 top value=0.1uF
C146 "GCE188R71H103KA01D" FP-GCE188R71H103KA01D_0603-MFG 1348.21,509.04 r270 bottom value=10nF
C147 "885012206020" 0603 487.64,791.76 r90 top value=0.1uF
C148 "LMK107B7105KA-T" 0603 428.59,791.76 r90 top value=1uF
C149 "GCE188R71H103KA01D" FP-GCE188R71H103KA01D_0603-MFG 1298,510.03 r270 top value=10nF
C150 "GCE188R71H103KA01D" FP-GCE188R71H103KA01D_0603-MFG 1698.37,510.03 r270 top value=10nF
C151 "GCE188R71H103KA01D" FP-GCE188R71H103KA01D_0603-MFG 1398.42,510.03 r270 top value=10nF
C152 "GCE188R71H103KA01D" FP-GCE188R71H103KA01D_0603-MFG 1748.37,509.04 r270 bottom value=10nF
C153 "GCE188R71H103KA01D" FP-GCE188R71H103KA01D_0603-MFG 1548.37,509.04 r270 bottom value=10nF
C154 "GCE188R71H103KA01D" FP-GCE188R71H103KA01D_0603-MFG 1998.37,510.03 r270 top value=10nF
C155 "GCE188R71H103KA01D" FP-GCE188R71H103KA01D_0603-MFG 1798.37,510.03 r270 top value=10nF
C156 "GCE188R71H103KA01D" FP-GCE188R71H103KA01D_0603-MFG 1498.37,510.03 r270 top value=10nF
C157 "GCE188R71H103KA01D" FP-GCE188R71H103KA01D_0603-MFG 2098.37,510.03 r270 top value=10nF
C158 "GCE188R71H103KA01D" FP-GCE188R71H103KA01D_0603-MFG 1898.37,510.03 r270 top value=10nF
C159 "GCE188R71H103KA01D" FP-GCE188R71H103KA01D_0603-MFG 1598.37,510.03 r270 top value=10nF
C160 "GCE188R71H103KA01D" FP-GCE188R71H103KA01D_0603-MFG 2148.37,509.04 r270 bottom value=10nF
C161 "GCE188R71H103KA01D" FP-GCE188R71H103KA01D_0603-MFG 1948.37,509.04 r270 bottom value=10nF
C162 "GCE188R71H103KA01D" FP-GCE188R71H103KA01D_0603-MFG 2198.37,510.03 r270 top value=10nF
C163 "CL10A335KP8NNNC" FP-CL10A335KP8NNNC_0603-MFG 2986.4,4130.47 r90 top value=3.3µF
C164 "CL10A335KP8NNNC" FP-CL10A335KP8NNNC_0603-MFG 2978.92,3619.51 r270 top value=3.3µF
C165 "CL10A335KP8NNNC" FP-CL10A335KP8NNNC_0603-MFG 3686.72,4152.68 r270 top value=3.3µF
C166 "GRM033Z71C104KE14D" 0201L 3686.72,4152.68 r270 bottom value=0.1uF
C167 "GRM033Z71C104KE14D" 0201L 2978.92,3619.51 r270 bottom value=0.1uF
C168 "GRM033Z71C104KE14D" 0201L 3336.25,4019.74 r180 bottom value=0.1uF
C169 "GRM033Z71C104KE14D" 0201L 3336.5,3704.81 r180 bottom value=0.1uF
C170 "GRM033Z71C104KE14D" 0201L 3446.25,3736.18 r180 bottom value=0.1uF
C171 "CL10A335KP8NNNC" FP-CL10A335KP8NNNC_0603-MFG 3669.37,4038.54 r270 bottom value=3.3µF
C172 "CL10A335KP8NNNC" FP-CL10A335KP8NNNC_0603-MFG 2955.01,4009.63 r90 bottom value=3.3µF
C173 "CL10A335KP8NNNC" FP-CL10A335KP8NNNC_0603-MFG 3679.66,3623.16 r270 bottom value=3.3µF
C174 "GRM033Z71C104KE14D" 0201L 3163.33,3799.17 r0 bottom value=0.1uF
C175 "GRM033Z71C104KE14D" 0201L 3399.28,4035.11 r270 bottom value=0.1uF
C176 "GRM033Z71C104KE14D" 0201L 3525.26,4035.11 r270 bottom value=0.1uF
C177 "GRM033Z71C104KE14D" 0201L 3273.29,4035.11 r270 bottom value=0.1uF
C178 "GRM033Z71C104KE14D" 0201L 3273.29,3689.21 r90 bottom value=0.1uF
C179 "GRM033Z71C104KE14D" 0201L 3163.33,3956.65 r0 bottom value=0.1uF
C180 "GRM033Z71C104KE14D" 0201L 3493.77,3689.21 r90 bottom value=0.1uF
C181 "GRM033Z71C104KE14D" 0201L 3336.5,3736.18 r180 bottom value=0.1uF
C182 "GRM033Z71C104KE14D" 0201L 3478.29,4019.64 r0 bottom value=0.1uF
C183 "GRM033Z71C104KE14D" 0201L 3210.3,3941.18 r90 bottom value=0.1uF
C184 "GRM033Z71C104KE14D" 0201L 3446.25,3704.68 r180 bottom value=0.1uF
C185 "GRM033Z71C104KE14D" 0201L 3833.38,3850.38 r90 top value=0.1uF
C186 "GRM033Z71C104KE14D" 0201L 2986.4,4130.47 r90 bottom value=0.1uF
C187 "GRM033Z71C104KE14D" 0201L 3478.29,3988.14 r0 bottom value=0.1uF
C188 "GRM033Z71C104KE14D" 0201L 3226.33,3850.66 r0 bottom value=0.1uF
C189 "GRM033Z71C104KE14D" 0201L 3225.77,3704.68 r180 bottom value=0.1uF
C190 "CL10A335KP8NNNC" FP-CL10A335KP8NNNC_0603-MFG 3889.77,3691.35 r0 top value=3.3µF
C191 "GRM033Z71C104KE14D" 0201L 3889.77,3691.35 r0 bottom value=0.1uF
C192 "CL10A335KP8NNNC" FP-CL10A335KP8NNNC_0603-MFG 3889.9,3760.48 r0 top value=3.3µF
C193 "GRM033Z71C104KE14D" 0201L 3477.74,3850.66 r180 bottom value=0.1uF
C194 "GRM033Z71C104KE14D" 0201L 3477.74,3925.15 r180 bottom value=0.1uF
C195 "GRM033Z71C104KE14D" 0201L 3477.74,3767.67 r180 bottom value=0.1uF
C196 "GRM033Z71C104KE14D" 0201L 3225.77,3988.14 r180 bottom value=0.1uF
C197 "GRM033Z71C104KE14D" 0201L 3225.77,3736.18 r180 bottom value=0.1uF
C198 "GRM033Z71C104KE14D" 0201L 3336.25,3988.24 r180 bottom value=0.1uF
C199 "GRM033Z71C104KE14D" 0201L 3225.77,4019.64 r180 bottom value=0.1uF
C200 "CL10A335KP8NNNC" FP-CL10A335KP8NNNC_0603-MFG 3559.76,4226.86 r0 top value=3.3µF
C201 "GRM033Z71C104KE14D" 0201L 3559.76,4226.86 r0 bottom value=0.1uF
C202 "GRM033Z71C104KE14D" 0201L 3178.81,4035.11 r270 bottom value=0.1uF
C203 "GRM033Z71C104KE14D" 0201L 3163.33,3736.18 r0 bottom value=0.1uF
C204 "GRM033Z71C104KE14D" 0201L 3399.28,3689.21 r90 bottom value=0.1uF
C205 "GRM033Z71C104KE14D" 0201L 3556.76,3625.66 r270 bottom value=0.1uF
C206 "CL10A335KP8NNNC" FP-CL10A335KP8NNNC_0603-MFG 2989.02,3882.49 r270 top value=3.3µF
C207 "CL10A335KP8NNNC" FP-CL10A335KP8NNNC_0603-MFG 3291.76,3485.31 r270 top value=3.3µF
C208 "GRM033Z71C104KE14D" 0201L 3163.33,3873.66 r0 bottom value=0.1uF
C209 "GRM033Z71C104KE14D" 0201L 2989.02,3882.49 r270 bottom value=0.1uF
C210 "GRM033Z71C104KE14D" 0201L 3291.76,3485.31 r270 bottom value=0.1uF
C211 "GRM033Z71C104KE14D" 0201L 3663.08,3954.99 r90 bottom value=0.1uF
C212 "GRM033Z71C104KE14D" 0201L 3293.76,4254.78 r90 bottom value=0.1uF
C213 "GRM155R61A475MEAAD" 0402L 3761.22,3963.66 r90 bottom value=4.7uF
C214 "GRM033Z71C104KE14D" 0201L 3509.24,3799.17 r180 bottom value=0.1uF
C215 "GRM033Z71C104KE14D" 0201L 3525.26,3941.18 r90 bottom value=0.1uF
C216 "GRM033Z71C104KE14D" 0201L 3509.24,3736.18 r180 bottom value=0.1uF
C217 "GRM033Z71C104KE14D" 0201L 3540.74,3988.14 r180 bottom value=0.1uF
C218 "GRM033Z71C104KE14D" 0201L 3525.26,3689.21 r90 bottom value=0.1uF
C219 "GRM033Z71C104KE14D" 0201L 3858.02,3600.03 r270 top value=0.1uF
C220 "GRM155R71H104KE14D" FP-GRM155R71H104KE14D_0402-MFG 4140.29,2838.62 r90 bottom value=100nF
C221 "GRM155R71H104KE14D" FP-GRM155R71H104KE14D_0402-MFG 4086.79,2838.62 r90 bottom value=100nF
C222 "GRM155R71H104KE14D" FP-GRM155R71H104KE14D_0402-MFG 4027.78,2704.96 r180 bottom value=100nF
C223 "GRM155R71H104KE14D" FP-GRM155R71H104KE14D_0402-MFG 3964.63,2798.52 r270 bottom value=100nF
C224 "GRM155R61A475MEAAD" 0402 4047.89,2620.42 r90 bottom value=4.7uF
C225 "GRM033Z71C104KE14D" 0201 3860.21,3029.54 r270 top value=0.1uF
C226 "GRM033Z71C104KE14D" 0201 4064.77,3992.04 r180 bottom value=0.1uF
C227 "GRM033Z71C104KE14D" 0201 4309.84,3994.61 r180 bottom value=0.1uF
C228 "C0603C104J5RAC7867" FP-C0603C104J5RAC7867_0603-MFG 4875.02,3960.06 r0 bottom value=100nF
C229 "C0603C104J5RAC7867" FP-C0603C104J5RAC7867_0603-MFG 4875.88,3808.23 r0 bottom value=100nF
C230 "GRM155R61A475MEAAD" 0402 4299.22,4170.98 r0 top value=4.7uF
C231 "GRM033Z71C104KE14D" 0201 4240.94,4225.41 r90 top value=0.1uF
C232 "GRM033Z71C104KE14D" 0201 4275.6,4225.41 r90 top value=0.1uF
C233 "GRM155R61A475MEAAD" 0402 3908.79,4172.12 r180 top value=4.7uF
C234 "GRM033Z71C104KE14D" 0201 3965.6,4225.09 r90 top value=0.1uF
C235 "GRM033Z71C104KE14D" 0201 3932.51,4225.09 r90 top value=0.1uF
C236 "C0603C104J5RAC7867" FP-C0603C104J5RAC7867_0603-MFG 4876.72,3655.28 r0 bottom value=100nF
C237 "GCM188R71E104KA57D" 0603 4528.09,3662.27 r0 bottom value=0.1uF
C238 "C0603C104J5RAC7867" FP-C0603C104J5RAC7867_0603-MFG 4878.93,3503.48 r0 bottom value=100nF
C239 "GCM188R71E104KA57D" 0603 4525.9,3499.75 r0 bottom value=0.1uF
C240 "C0603C104J5RAC7867" FP-C0603C104J5RAC7867_0603-MFG 4878.91,3350.13 r0 bottom value=100nF
C241 "GCM188R71E104KA57D" 0603 4527.91,3339.3 r0 bottom value=0.1uF
C242 "C0603C104J5RAC7867" FP-C0603C104J5RAC7867_0603-MFG 4878.08,3196.62 r0 bottom value=100nF
C243 "GCM188R71E104KA57D" 0603 4527.15,3178.83 r0 bottom value=0.1uF
C244 "C0603C104J5RAC7867" FP-C0603C104J5RAC7867_0603-MFG 4877.87,3042.02 r0 bottom value=100nF
C245 "C0603C103J5RACTU" 0603 4526.09,3015.3 r180 bottom value=0.01uF
C246 "C0603C104J5RAC7867" FP-C0603C104J5RAC7867_0603-MFG 4877.75,2884.01 r0 bottom value=100nF
C247 "GRM155R61A475MEAAD" 0402 3789.9,3966.9 r270 top value=4.7uF
C248 "GRM033Z71C104KE14D" 0201 3748.32,3956.38 r270 top value=0.1uF
C249 "C0603C103J5RACTU" 0603 4526.75,2861.77 r180 bottom value=0.01uF
C250 "C0603C104J5RAC7867" FP-C0603C104J5RAC7867_0603-MFG 4877.75,2727.51 r0 bottom value=100nF
C251 "C0603C104J5RAC7867" FP-C0603C104J5RAC7867_0603-MFG 4526.5,2708.04 r0 bottom value=100nF
C252 "C0603C104J5RAC7867" FP-C0603C104J5RAC7867_0603-MFG 4877.42,2572.2 r0 bottom value=100nF
C253 "C0603C104J5RAC7867" FP-C0603C104J5RAC7867_0603-MFG 4526.5,2539.91 r0 bottom value=100nF
C254 "GRM155R71E104KE14D" 0402 2179,4164.73 r270 top value=0.1uF
C255 "GRM155R71H104KE14D" FP-GRM155R71H104KE14D_0402-MFG 2511.39,4249.28 r180 top value=100nF
C256 "GRM155R71H104KE14D" FP-GRM155R71H104KE14D_0402-MFG 3352.03,1856.84 r0 top value=100nF
C257 "GRM033Z71C104KE14D" 0201 3754.17,2647.36 r180 top value=0.1uF
C258 "GRM155R71H104KE14D" FP-GRM155R71H104KE14D_0402-MFG 3589.76,2637.06 r90 top value=100nF
C259 "GRM155R71H104KE14D" FP-GRM155R71H104KE14D_0402-MFG 3675.63,1860.42 r0 top value=100nF
C260 "GRM155R71H104KE14D" FP-GRM155R71H104KE14D_0402-MFG 3996.01,1860.02 r0 top value=100nF
C261 "CGA2B2C0G1H120J050BA" 0402 3565.03,3470.55 r270 top value=12pF
C262 "CGA2B2C0G1H120J050BA" 0402 3727.56,3453.7 r270 top value=12pF
C263 "GRM155R71H104KE14D" FP-GRM155R71H104KE14D_0402-MFG 3245.48,2564.82 r180 top value=100nF
C264 "GRM155R71E104KE14D" 0402 3950.25,5148.57 r90 bottom value=0.1uF
C265 "GMC31X5R476M25NT" FP-GMC31X5R476M25NT_1206-MFG 4151.89,5062.02 r180 bottom value=47µF
C266 "GMC31X5R476M25NT" FP-GMC31X5R476M25NT_1206-MFG 4151.98,5055.89 r180 top value=47µF
C267 "GMC31X5R476M25NT" FP-GMC31X5R476M25NT_1206-MFG 4151.89,5145.98 r180 bottom value=47µF
C268 "GMC31X5R476M25NT" FP-GMC31X5R476M25NT_1206-MFG 4151.98,5139.75 r180 top value=47µF
C269 "GRM21BR61H106KE43L" FP-GRM21BR61H106KE43L_0805-MFG 4151.89,4979.14 r180 top value=10µF
C270 "GRM21BR61H106KE43L" FP-GRM21BR61H106KE43L_0805-MFG 4151.89,4979.14 r180 bottom value=10µF
C271 "GRM155R61E225KE11D" "FP-GRM155R61E225KE11D_0402 (1005 metric)-MFG" 3964.41,5055.75 r180 bottom value=2.2µF
C272 "GRM155R61E225KE11D" "FP-GRM155R61E225KE11D_0402 (1005 metric)-MFG" 4001.89,5153.89 r90 top value=2.2µF
C273 "GRM1555C1H102JA01D" 0402 3969.33,5055.75 r0 top value=1000pF
C274 "GRM1555C1H102JA01D" 0402 4001.89,5148.97 r270 bottom value=1000pF
C275 "GRM155R71E104KE14D" 0402 3950.25,5148.57 r90 top value=0.1uF
C276 "GRM155R71E104KE14D" 0402 3901.26,5148.8 r90 top value=0.1uF
C277 "GCM155R71E103KA37D" 0402 3969.04,4799.27 r90 top value=0.01uF
C278 "GRM155R71E104KE14D" 0402 3413.69,4999.62 r90 top value=0.1uF
C279 "GRM155R71E104KE14D" 0402 3930.44,4975.27 r90 top value=0.1uF
C280 "GRM1555C1H102JA01D" 0402 3408.75,5131.53 r90 top value=1000pF
C281 "GRM155R71E104KE14D" 0402 3417.15,5149.09 r90 bottom value=0.1uF
C282 "GRM21BR61E226ME44L" 0805_HV 3343.42,5134.26 r270 top value=22uF
C283 "GRM21BR61E226ME44L" 0805_HV 3308.31,5156.79 r270 bottom value=22uF
C284 "GRM21BR61E226ME44L" 0805_HV 3259.39,5134.26 r270 top value=22uF
C285 "GRM21BR61E226ME44L" 0805_HV 3224.28,5156.79 r270 bottom value=22uF
C286 "GRM155R71E104KE14D" 0402 3371.98,5149.09 r90 bottom value=0.1uF
C287 "GMC31X5R476M25NT" FP-GMC31X5R476M25NT_1206-MFG 3172.9,5150.51 r270 top value=47µF
C288 "GRM155R71E104KE14D" 0402 3414.38,5249.23 r90 top value=0.1uF
C289 "GRM21BR61H106KE43L" FP-GRM21BR61H106KE43L_0805-MFG 3357.12,5267.97 r90 top value=10µF
C290 "GRM155R71E104KE14D" 0402 3928.43,5252.98 r90 top value=0.1uF
C291 "GRM21BR61H106KE43L" FP-GRM21BR61H106KE43L_0805-MFG 3987.02,5263.89 r90 top value=10µF
C292 "GRM155R71E104KE14D" 0402 3819.01,5266.32 r180 bottom value=0.1uF
C293 "GRM155R61E225KE11D" "FP-GRM155R61E225KE11D_0402 (1005 metric)-MFG" 3526.91,5201.84 r0 bottom value=2.2µF
C294 "GRM21BR61H106KE43L" FP-GRM21BR61H106KE43L_0805-MFG 3817.06,5323.19 r180 bottom value=10µF
C295 "GRM155R61A475MEAAD" 0402 3510.42,5155.32 r180 bottom value=4.7uF
C296 "GRM155R71E104KE14D" 0402 3382.49,5368.3 r180 top value=0.1uF
C297 "GRM21BR61H106KE43L" FP-GRM21BR61H106KE43L_0805-MFG 3516.97,5321.63 r270 bottom value=10µF
C298 "GRM155R71E104KE14D" 0402 3913.99,5445.13 r90 top value=0.1uF
C299 "GRM21BR61H106KE43L" FP-GRM21BR61H106KE43L_0805-MFG 3973.12,5456.91 r90 top value=10µF
C300 "GRM155R71E104KE14D" 0402 3424.02,5444.37 r90 bottom value=0.1uF
C301 "GRM21BR61H106KE43L" FP-GRM21BR61H106KE43L_0805-MFG 3365.6,5458.1 r90 bottom value=10µF
C302 "GRM155R71H104KE14D" FP-GRM155R71H104KE14D_0402-MFG 4534.33,1869.55 r270 top value=100nF
C303 "GRM155R71H104KE14D" FP-GRM155R71H104KE14D_0402-MFG 4770.91,1854.75 r180 top value=100nF
C304 "GRM188R71E823KA01D" 0603 7086.31,3957.92 r180 top value=0.082uF
C305 "EEVFK1H221P" SM_RADIAL_G 7569.62,4024.24 r270 top value=220uF
C306 "CGA3E2X7R1H104K080AA" 0603 7825.29,4058.43 r270 top value=0.1uF
C307 "C0603C223K5RACTU" 0603 6755.38,3869.51 r90 top value=0.022uF
C308 "06035C104KAZ2A" 0603 6989.92,3991.61 r270 top value=0.1uF
C309 "06035C104KAZ2A" 0603 7019.14,3597.83 r0 top value=0.1uF
C310 "UCL1V391MNL1GS" SM_RADIAL_10BMM 1412.8,5566.72 r90 top value=390uF
C311 "GCJ21BR71H105MA01L" FP-GCJ21B-0_3-IPC_A 1725.01,4402.9 r0 bottom
C312 "GCJ21BR71H105MA01L" FP-GCJ21B-0_3-IPC_A 1607.72,4541.43 r270 bottom
C313 "GCJ21BR71H105MA01L" FP-GCJ21B-0_3-IPC_A 1614.27,4279.91 r90 bottom
C314 "GCJ21BR71H105MA01L" FP-GCJ21B-0_3-IPC_A 1146.64,5567.72 r90 top
C315 "GCJ188R71H104KA12D" FP-GCJ188-0_2-IPC_C 1597.68,4562.41 r90 top
C316 "GCJ188R71H104KA12D" FP-GCJ188-0_2-IPC_C 1597.68,4459.44 r270 top
C317 "GCJ188R71H104KA12D" FP-GCJ188-0_2-IPC_C 1597.68,4356.46 r90 top
C318 "GCJ188R71H104KA12D" FP-GCJ188-0_2-IPC_C 1004.9,4552.71 r90 top
C319 "GCJ188R71H104KA12D" FP-GCJ188-0_2-IPC_C 1005.16,4452.37 r270 top
C320 "GCJ188R71H104KA12D" FP-GCJ188-0_2-IPC_C 1005.46,4251.77 r270 top
C321 "GCJ188R71H104KA12D" FP-GCJ188-0_2-IPC_C 1005.72,4351.68 r90 top
C322 "GCJ188R71H104KA12D" FP-GCJ188-0_2-IPC_C 1597.68,4253.48 r270 top
C323 "CL10B105KB9VPJC" FP-CL10B105KB9VPJC_0603-MFG 1264.58,4769.71 r0 bottom value=1µF
C324 "C0603X104K5RACAUTO" FP-C0603X104K5RACAUTO_0603-MFG 1258.91,4703.31 r0 bottom value=100nF
C325 "GCJ21BR71H105MA01L" FP-GCJ21B-0_3-IPC_A 1014.03,4146.47 r270 bottom
C326 "GCJ21BR71H105MA01L" FP-GCJ21B-0_3-IPC_A 1008.52,4519.81 r90 bottom
C327 "GCM21BR71H105KA03K" 0805_HV 1967.39,4094.94 r180 top value=1uF
C328 "GCM188R71C105KA64J" 0603 1092.79,3991.34 r0 top value=1uF
C329 "GCM188R71H154KA64D" FP-GCM188-0_1-IPC_C 1824.57,4101.69 r180 top
C330 "GRM1885C1H103JA01D" 0603 450.68,4867.27 r270 bottom value=0.01uF
C331 "GRM1885C1H103JA01D" 0603 450.62,4738.77 r90 bottom value=0.01uF
C332 "GCM188R71C105KA64J" 0603 997.33,4010.19 r270 top value=1uF
C333 "GRM155R71H331KA01D" 0402 1696.53,4271.2 r90 bottom value=330pF
C334 "GRM188R71A225KE15J" 0603 997.39,4140.05 r90 top value=2.2uF
C335 "GRM188R71C334KA01D" 0603 1588.86,4157.07 r0 bottom value=0.33uF
C336 "GCM188R71C105KA64D" 0603 1269.44,4469.32 r90 bottom value=1uF
C337 "GCM155R71C104KA55D" 0402 1660.11,4150.37 r180 top value=0.1uF
C338 "GCM21BR71H105KA03K" 0805_HV 1958.32,4719.85 r180 top value=1uF
C339 "GCM188R71H154KA64D" FP-GCM188-0_1-IPC_C 1816.57,4721.45 r180 top
C340 "GCM188R71C105KA64D" 0603 1270.25,4340.58 r270 bottom value=1uF
C341 "GRM1885C1H103JA01D" 0603 450.68,4461.02 r270 bottom value=0.01uF
C342 "GRM1885C1H103JA01D" 0603 450.62,4332.85 r90 bottom value=0.01uF
C343 "GRM155R71H331KA01D" 0402 1686.53,4564.14 r90 bottom value=330pF
C344 "GCM188R71C105KA64D" 0603 1342.31,4470.94 r90 bottom value=1uF
C345 "GCM21BR71H105KA03K" 0805_HV 741.2,4096.87 r0 top value=1uF
C346 "GCM188R71C105KA64D" 0603 1341.71,4339.54 r270 bottom value=1uF
C347 "GCM188R71H154KA64D" FP-GCM188-0_1-IPC_C 882.37,4096.58 r0 top
C348 "GRM1885C1H103JA01D" 0603 450.68,3975.23 r270 bottom value=0.01uF
C349 "GRM1885C1H103JA01D" 0603 450.62,3845.76 r90 bottom value=0.01uF
C350 "GCM188R71C105KA64J" 0603 1148.87,4822.59 r0 top value=1uF
C351 "GCM188R71C105KA64J" 0603 1149.13,4814.51 r0 bottom value=1uF
C352 "GRM155R71H331KA01D" 0402 1005.35,4289.82 r90 bottom value=330pF
C353 "GCM21BR71H105KA03K" 0805_HV 734.27,4714.95 r0 top value=1uF
C354 "GCM188R71H154KA64D" FP-GCM188-0_1-IPC_C 879.13,4714.1 r0 top
C355 "GRM1885C1H103JA01D" 0603 450.68,3579.59 r270 bottom value=0.01uF
C356 "GRM1885C1H103JA01D" 0603 450.62,3448.93 r90 bottom value=0.01uF
C357 "GRM155R71H331KA01D" 0402 1000.51,4647.02 r90 bottom value=330pF
C358 "06035C104KAZ2A" 0603 4721.04,4596.41 r180 top value=0.1uF
C359 "CL21B106KOQNNNG" 0805_HV 5083.31,4707.02 r0 top value=10uF
C360 "GMC31X7R106K50NT" FP-GMC31X7R106K50NT_1206-MFG 5133.8,4516.25 r180 top value=10µF
C361 "06035C104KAZ2A" 0603 4555.24,4682.35 r180 top value=0.1uF
C362 "CGA3E2X7R1H333K080AA" FP-CGA3E2X7R1H333K080AA_0603-MFG 4559.63,4619.82 r0 top value=33nF
C363 "C0603C102J5RACAUTO" 0603 2914.81,5444.9 r270 top value=1000pF
C364 "GRM21BR61E226ME44L" 0805_HV 2932.07,4578.21 r90 top value=22uF
C365 "GCJ21BR71H105MA01L" 0805_HV 3201.95,5645.35 r180 top value=1uF
C366 "CGA4J3X7R1H225K125AE" 0805_HV 2914.81,5603.4 r90 top value=2.2uF
C367 "GRM188R61C106MAALD" 0603 2819.6,4679.27 r0 top value=10uF
C368 "06035C104KAZ2A" 0603 3210.33,5346.01 r180 top value=0.1uF
C369 "GRM155R71H682KA88D" 0402 2657.09,4574.25 r180 top value=6800pF
C370 "885012106031" FP-885012106031_0603-MFG 2707.57,4907.63 r270 top value=10µF
C371 "GRM21BR61E226ME44L" 0805_HV 2604.33,4802.79 r0 top value=22uF
C372 "GRM155R71H682KA88D" 0402 2599.87,5060.52 r90 top value=6800pF
C373 "C0603C475K8PACTU" 0603 5661.81,2924.65 r90 top value=4.7uF
C374 "GCE188R71H103KA01D" FP-GCE188R71H103KA01D_0603-MFG 5940.38,3273.68 r270 top value=10nF
C375 "GCE188R71H103KA01D" FP-GCE188R71H103KA01D_0603-MFG 5557.43,3270.1 r270 top value=10nF
C376 "GCE188R71H103KA01D" FP-GCE188R71H103KA01D_0603-MFG 5557.43,3095.94 r270 top value=10nF
C377 "GCE188R71H103KA01D" FP-GCE188R71H103KA01D_0603-MFG 5940.38,3095.28 r270 top value=10nF
C378 "GCE188R71H103KA01D" FP-GCE188R71H103KA01D_0603-MFG 5994.89,2615.27 r90 top value=10nF
C379 "GCE188R71H103KA01D" FP-GCE188R71H103KA01D_0603-MFG 5601.02,2735.89 r0 bottom value=10nF
C380 "GCE188R71H103KA01D" FP-GCE188R71H103KA01D_0603-MFG 5489.71,2614.68 r90 top value=10nF
C381 "GCE188R71H103KA01D" FP-GCE188R71H103KA01D_0603-MFG 5709.8,2497.76 r180 top value=10nF
C382 "GCM188R71C104KA37J" 0603 5430.09,3512.09 r270 top value=0.1uF
C383 "GCM188R71C104KA37J" 0603 5009.3,4356.08 r90 top value=0.1uF
C384 "GCM188R71C104KA37J" 0603 4513.42,4122.09 r0 top value=0.1uF
C385 "GCM188R71C104KA37J" 0603 5351.26,4140.61 r0 top value=0.1uF
C386 "GCM188R71C104KA37J" 0603 6535.54,2885.73 r180 top value=0.1uF
C387 "GCM188R71C104KA37J" 0603 5363.12,2921.54 r270 top value=0.1uF
C388 "C0603X102K5RACTU" 0603 7276.34,5178.61 r180 bottom value=1000pF
C389 "CGA4J2X7R2A104K125AA" 0805_HV 7472.6,6098.46 r90 bottom value=0.1uF
C390 "KCM55WR72A156MH01K" KCM55W 6701.35,6286.7 r90 top value=15uF
C391 "HMK107B7104KAHT" 0603 7239.26,4983.67 r270 top value=0.1uF
C392 "CGA3E2X7R2A103K080AA" 0603 7208.3,5074.75 r180 top value=0.01uF
C393 "HMK107B7104KAHT" 0603 7973.11,6274.52 r90 top value=0.1uF
C394 "KCM55WR72A156MH01K" KCM55W 7812.39,6314.29 r90 top value=15uF
C395 "C0603X102K5RACTU" 0603 7180.6,5198.55 r270 top value=1000pF
C396 "C0603X102K5RACTU" 0603 7240.43,5165.6 r270 top value=1000pF
C397 "CGA3E3X7R1E474K080AB" 0603 7448.92,5293.38 r0 top value=0.47uF
C398 "CGA3E3X7R1E474K080AB" 0603 7448.92,5352.17 r0 top value=0.47uF
C399 "CGA4J2X7R2A104K125AA" 0805_HV 7456.73,5424.87 r0 top value=0.1uF
C400 "GRM155R71H331KA01D" 0402 7418.7,4970.86 r270 top value=330pF
C401 "CGA3E3X7R1E474K080AB" 0603 7543.13,5318.16 r90 top value=0.47uF
C402 "C0603C331K5RACTU" 0603 7636.11,5171.25 r0 top value=330pF
C403 "C0603C331K5RACTU" 0603 7636.11,5111.95 r0 top value=330pF
C404 "CGA3E3X7R1E474K080AB" 0603 7636.11,5051.74 r0 top value=0.47uF
C405 "06035C104KAZ2A" 0603 6846.24,4019.76 r0 bottom value=0.1uF
C406 "0201BB104KW160" 0201_033L 3184.12,6483.94 r270 top value=0.1uF
C407 "0201BB104KW160" 0201_033L 3184.12,6531.55 r90 top value=0.1uF
C408 "GRM033R61C105ME15D" FP-GRM033R61C105ME15D_0201-MFG 3129.34,6483.22 r90 top value=1µF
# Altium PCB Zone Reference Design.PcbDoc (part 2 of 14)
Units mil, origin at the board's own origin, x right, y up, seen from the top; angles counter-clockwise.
Board outline 8858.11 x 7047.08 mil, 16 copper layers (Top Layer, GND_1, SIG_1, GND_2, PWR/SIG_1, GND_3, PWR_1, PWR_2, GND_4, PWR/SIG_2, GND_5, SIG_2, GND_6, SIG_3, GND_7, Bottom Layer), stack 80.368 mil thick; 1131 components, 808 nets, 3825 pads, 3523 vias.
Unrouted connection lines stored in the file: 563.

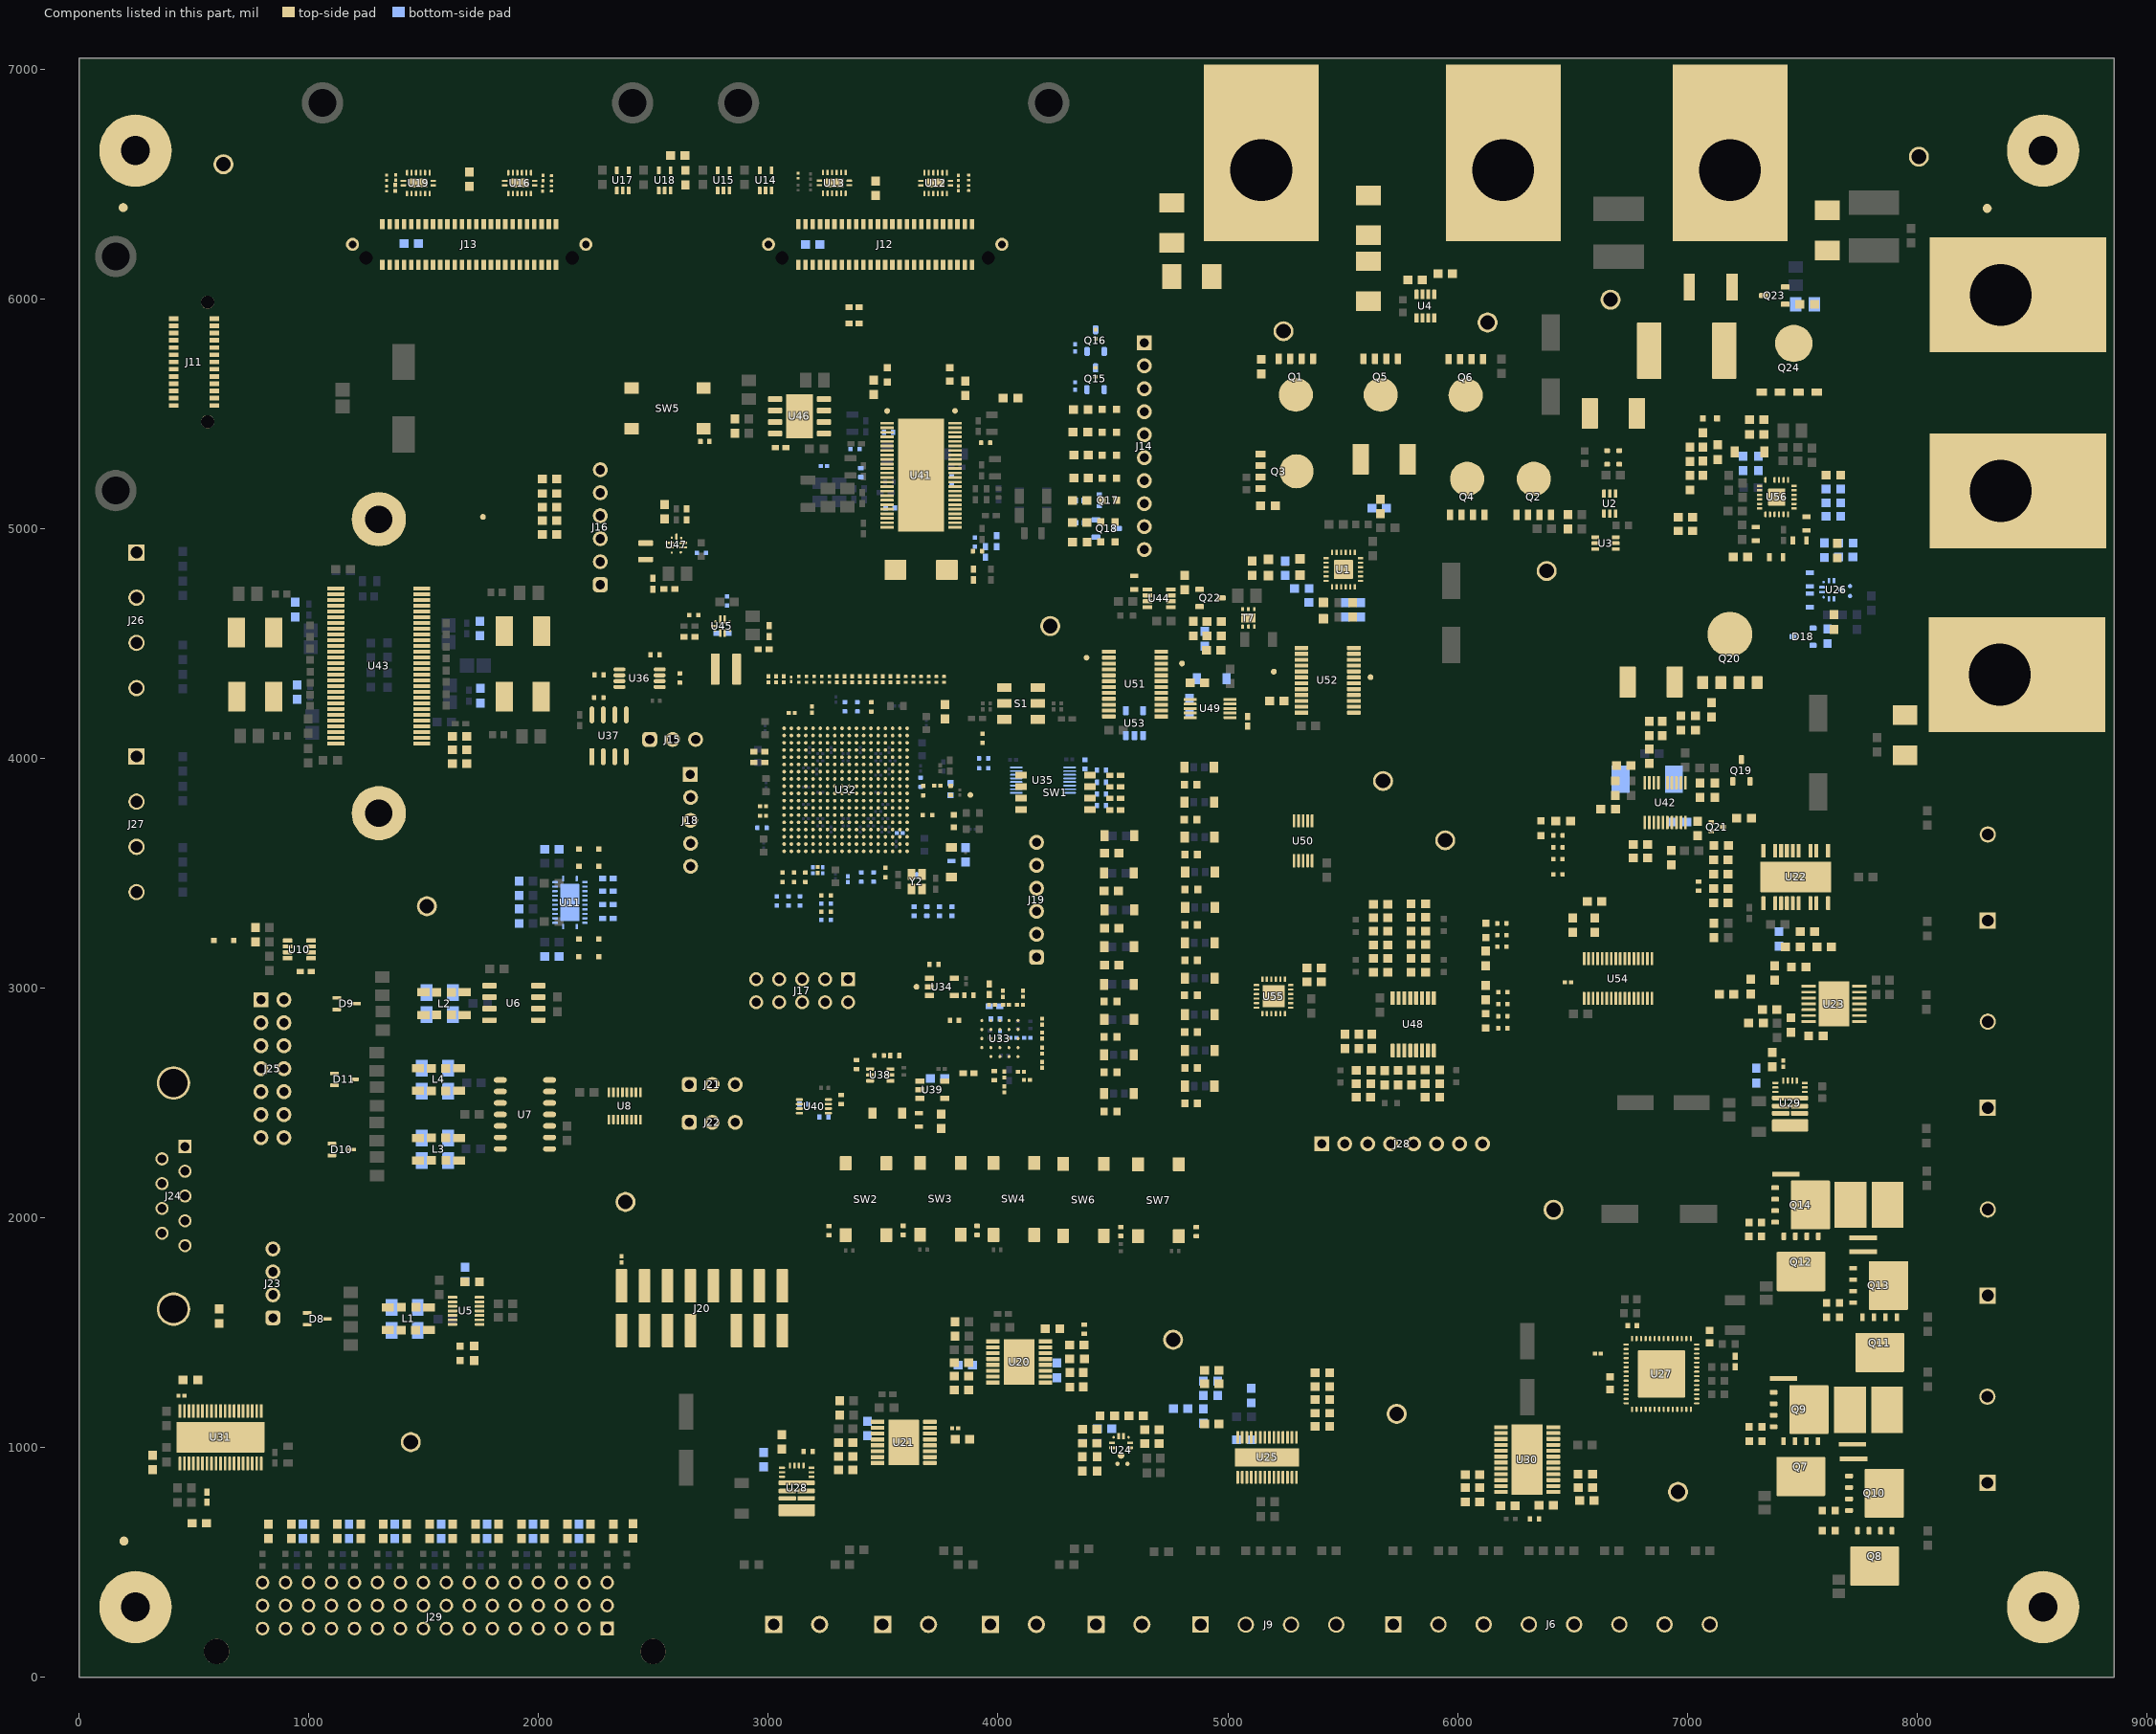
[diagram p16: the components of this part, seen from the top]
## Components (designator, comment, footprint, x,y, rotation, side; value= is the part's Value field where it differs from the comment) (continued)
C409 "GRM033R61C105ME15D" FP-GRM033R61C105ME15D_0201-MFG 3129.18,6535.52 r270 top value=1µF
C410 "0201BB104KW160" 0201_033L 3827.94,6480.54 r270 top value=0.1uF
C411 "0201BB104KW160" 0201_033L 3827.73,6525.83 r90 top value=0.1uF
C412 "GRM033R61C105ME15D" FP-GRM033R61C105ME15D_0201-MFG 3872.3,6481.49 r90 top value=1µF
C413 "GRM033R61C105ME15D" FP-GRM033R61C105ME15D_0201-MFG 3872.01,6526.78 r270 top value=1µF
C414 "0201BB104KW160" 0201_033L 2018.47,6524.91 r90 top value=0.1uF
C415 "0201BB104KW160" 0201_033L 2017.28,6478.63 r270 top value=0.1uF
C416 "GRM033R61C105ME15D" FP-GRM033R61C105ME15D_0201-MFG 2056.28,6479.58 r90 top value=1µF
C417 "GRM033R61C105ME15D" FP-GRM033R61C105ME15D_0201-MFG 2056.28,6523.95 r270 top value=1µF
C418 "0201BB104KW160" 0201_033L 1377.71,6527.09 r90 top value=0.1uF
C419 "0201BB104KW160" 0201_033 1376.53,6482 r270 top value=0.1uF
C420 "GRM033R61C105ME15D" FP-GRM033R61C105ME15D_0201-MFG 1338.1,6479.02 r90 top value=1µF
C421 "GRM033R61C105ME15D" FP-GRM033R61C105ME15D_0201-MFG 1338.1,6526.14 r270 top value=1µF
D1 "150060SS75000" WL-SMCW_RED 6363,3694.81 r90 top value="Super Red"
D2 "150060SS75000" WL-SMCW_RED 6122.29,2856.4 r90 top value="Super Red"
D3 "150060SS75000" WL-SMCW_RED 6122.86,3249.49 r270 top value="Super Red"
D4 "SMBJ33A-13-F" SMB 4843.13,6095.71 r180 top value=33V
D5 "SMBJ16A-13-F" SMB 4756.12,6329.84 r270 top value=16V
D6 "SMBJ33A-13-F" SMB 5612.33,6075.75 r90 top value=33V
D7 "SMBJ16A-13-F" SMB 5611.72,6362.8 r270 top value=16V
D8 "ESD2CAN24DCK" DCK0003A-MFG 1035.93,1559.24 r0 top
D9 "ESD2CAN24DCK" DCK0003A-MFG 1164.44,2931.09 r0 top
D10 "ESD2CAN24DCK" DCK0003A-MFG 1143.85,2296.23 r0 top
D11 "ESD2CAN24DCK" DCK0003A-MFG 1154.94,2601.68 r0 top
D13 "1N4148WS-7-F" SOD-323 629.83,3206.05 r180 top value=75V
D14 "1N4148WS-7-F" SOD-323 2219.13,3603.86 r0 top value=75V
D15 "1N4148WS-7-F" SOD-323 2219.13,3529.82 r0 top value=75V
D16 "1N4148WS-7-F" SOD-323 2219.17,3213.03 r0 top value=75V
D17 "1N4148WS-7-F" SOD-323 2218.39,3136.1 r0 top value=75V
D18 "BAS21-7-F" SOT-23L 7504.02,4528.47 r180 bottom value=200V
D19 "BAS 52-02V H6327" SOD-523 556.32,783.81 r270 top value=45V
D20 "MMSZ5226B-7-F" SOD-123 3796.11,3547.05 r270 top value=3.3V
D21 "MMSZ5226B-7-F" SOD-123 4875.02,3960.06 r0 top value=3.3V
D22 "MMSZ5226B-7-F" SOD-123 4875.88,3808.23 r0 top value=3.3V
D23 "MMSZ5226B-7-F" SOD-123 4876.72,3655.28 r0 top value=3.3V
D24 "MMSZ5226B-7-F" SOD-123 4878.93,3503.48 r0 top value=3.3V
D25 "MMSZ5226B-7-F" SOD-123 4528.09,3662.27 r0 top value=3.3V
D26 "MMSZ5226B-7-F" SOD-123 4878.91,3350.13 r0 top value=3.3V
D27 "MMSZ5226B-7-F" SOD-123 4525.9,3499.75 r0 top value=3.3V
D28 "MMSZ5226B-7-F" SOD-123 4878.08,3196.62 r0 top value=3.3V
D29 "MMSZ5226B-7-F" SOD-123 4527.91,3339.3 r0 top value=3.3V
D30 "MMSZ5226B-7-F" SOD-123 4877.87,3042.02 r0 top value=3.3V
D31 "MMSZ5226B-7-F" SOD-123 4527.15,3178.83 r0 top value=3.3V
D32 "MMSZ5226B-7-F" SOD-123 4877.75,2884.01 r0 top value=3.3V
D33 "MMSZ5226B-7-F" SOD-123 4526.09,3015.3 r0 top value=3.3V
D34 "MMSZ5226B-7-F" SOD-123 4526.75,2861.77 r0 top value=3.3V
D35 "MMSZ5226B-7-F" SOD-123 4877.75,2727.51 r0 top value=3.3V
D36 "MMSZ5226B-7-F" SOD-123 4526.5,2708.04 r0 top value=3.3V
D37 "MMSZ5226B-7-F" SOD-123 4877.21,2572.2 r0 top value=3.3V
D38 "MMSZ5226B-7-F" SOD-123 4526.5,2539.91 r0 top value=3.3V
D39 "MMSZ5226B-7-F" SOD-123 3517.56,2454.14 r180 top value=3.3V
D40 "NSR0520V2T1G" SOD-523 3373.69,5962.5 r180 top value=20V
D41 "NSR0520V2T1G" SOD-523 3373.69,5892.14 r180 top value=20V
D42 "LTST-C193TBKT-5A" LTST-C193_Blue 3789.6,5670.52 r90 top value=Blue
D43 "150060YS75000" WL-SMCW_YELLOW 3517.33,5668.55 r270 top value=Yellow
D44 "150060VS75000" WL-SMCW_GREEN 4478.5,4941.07 r180 top value=Green
D45 "150060VS75000" WL-SMCW_GREEN 4484.01,5319.09 r180 top value=Green
D46 "150060VS75000" WL-SMCW_GREEN 4484.01,5219.09 r180 top value=Green
D47 "150060VS75000" WL-SMCW_GREEN 4484.01,5517.31 r180 top value=Green
D48 "150060VS75000" WL-SMCW_GREEN 4484.01,5418.51 r180 top value=Green
D49 "150060VS75000" WL-SMCW_GREEN 4484.01,5122.39 r180 top value=Green
D50 "150060VS75000" WL-SMCW_GREEN 4478.5,5027.6 r180 top value=Green
D51 "150040RS73220" FP-150040RS73220_0402-MFG 4424.45,5679.24 r90 top
D52 "150040RS73220" FP-150040RS73220_0402-MFG 4424.71,5844.97 r90 top
D53 "SS2H10-E3/5BT" SMB 7947.76,4099.7 r270 top value=100V
D54 "150060SS75000" WL-SMCW_RED 1657.87,1409.57 r270 top value="Super Red"
D55 "NSR0520V2T1G" SOD-523 5085.98,4160.31 r90 top value=20V
D56 "SS2H10-E3/5BT" SMB 7608.54,6296.94 r90 top value=100V
D57 "1N4148W-TP" SOD-123 7270.48,5333 r180 top value=100V
D58 "MMSZ5226B-7-F" SOD-123 4930.14,4345.04 r0 bottom value=3.3V
FB1 "BLM18EG121SN1D" FP-BLM18EG121SN1D_0603-MFG 3806.77,3725.87 r90 top
FB2 "BLM18EG121SN1D" FP-BLM18EG121SN1D_0603-MFG 3793.06,3864.84 r270 bottom
FID1 "Fiducial" Fiducial10-20 191.69,6396.42 r0 top
FID2 "Fiducial" Fiducial10-20 8305.46,6392.92 r0 top
FID3 "Fiducial" Fiducial10-20 195.19,592.08 r0 top
H1 "NY PMS 440 0025 PH" "NY PMS 440 0025 PH" 245.19,304.99 r0 top
H2 "NY PMS 440 0025 PH" "NY PMS 440 0025 PH" 8549,304.99 r0 top
H3 "NY PMS 440 0025 PH" "NY PMS 440 0025 PH" 245.19,6644.75 r0 top
H4 "NY PMS 440 0025 PH" "NY PMS 440 0025 PH" 8549,6644.75 r0 top
H5 "1902C" Keystone_1902C 245.19,304.99 r180 bottom
H6 "1902C" Keystone_1902C 8549,304.99 r180 bottom
H7 "1902C" Keystone_1902C 245.19,6644.75 r180 bottom
H8 "1902C" Keystone_1902C 8549,6644.75 r180 bottom
H9 "HeatSink_2" HEATSINK-DKQ56_20MMX41_4X32_77MM 1304.45,4400.07 r180 top locked
J1 "1902547" Phoenix_1902547 8430.02,3480.32 r90 top
J2 "1715721" PhoenixContact_1715721 3123.25,229.26 r0 top
J3 "1715721" PhoenixContact_1715721 4066.47,229.26 r0 top
J4 "1902547" Phoenix_1902547 8430.02,2665.43 r90 top
J5 "1715721" PhoenixContact_1715721 3597.31,229.26 r0 top
J6 "1715080" Phoenix_1715080 6408.88,229.26 r0 top
J7 "1902547" Phoenix_1902547 8428.29,1033.15 r90 top
J8 "1902547" Phoenix_1902547 8430.02,1848.04 r90 top
J9 "1715048" Phoenix_1715048 5176.75,240.18 r0 top
J10 "1715721" PhoenixContact_1715721 4525.99,229.26 r0 top
J11 "ERF8-013-05.0-L-DV-TR" FP-ERF8-013-05.0-L-DV-TR_CONN_RCPT26-MFG 500,5724.28 r90 top
J12 "ERF8-025-05.0-L-DV-L-TR" Samtec_ERF8-025-05_0-x-DV-L 3508.44,6236.38 r270 top
J13 "ERF8-025-05.0-L-DV-L-TR" Samtec_ERF8-025-05_0-x-DV-L 1697.78,6236.38 r270 top
J14 "TSW-110-07-G-S" TSW-110-07-G-S 4636.77,5357.69 r270 top
J15 "TSW-103-07-G-S" TSW-103-07-G-S 2583.63,4081.72 r0 top
J16 "TSW-106-07-G-S" TSW-106-07-G-S 2268.87,5004.88 r90 top
J17 "TSW-105-07-F-D" Samtec_TSW-105-07-x-D 3146.96,2987.36 r270 top
J18 "TSW-105-07-G-S" TSW-105-07-X-S 2661.16,3728.88 r270 top
J19 "TSW-106-07-G-S" TSW-106-07-G-S 4167.42,3383.4 r90 top
J20 "TSM-108-01-L-DV-008-P-TR" FP-TSM-108-01-L-DV-008-P-TR_HDR15-MFG 2711.03,1605.81 r180 top
J21 "TSW-103-07-G-S" TSW-103-07-G-S 2755.83,2579.3 r0 top
J22 "TSW-103-07-G-S" TSW-103-07-G-S 2755.83,2414.69 r0 top
J23 "TSW-104-07-G-S" TSW-104-07-G-S 843.13,1713.96 r90 top
J24 "09 65 162 6810" "Harting_09 65 162 6810" 0.14,2093.89 r270 top
J25 "TSW-107-07-G-D" TSW-107-07-X-D 841.28,2648.11 r270 top
J26 "1715048" Phoenix_1715048 261.45,4600.04 r270 top
J27 "1715048" Phoenix_1715048 261.45,3712.24 r270 top
J28 "TSW-108-07-G-S" TSW-108-07-G-S 5758.74,2320.81 r0 top
J29 "5650478-5" TE_5650478-5 1548.37,2.26 r180 top
L1 "ACT45B-101-2P-TL003" ACT45B 1433.52,1560.29 r180 top value=100uH
L2 "ACT45B-101-2P-TL003" ACT45B 1588.69,2931.35 r180 top value=100uH
L3 "ACT45B-101-2P-TL003" ACT45B 1564.75,2297.94 r180 top value=100uH
L4 "ACT45B-101-2P-TL003" ACT45B 1564.27,2601.89 r180 top value=100uH
L6 "CLF7045NIT-2R2N-D" CLF7045NI-D 3664.85,4819.5 r180 top value=2.2uH
L7 "VCMT053T-3R3MN5" VCMT053T 1930.66,4267.41 r0 top value=3.3uH
L8 "VCMT053T-3R3MN5" VCMT053T 1931.47,4552.26 r0 top value=3.3uH
L9 "VCMT053T-3R3MN5" VCMT053T 766.51,4268.13 r180 top value=3.3uH
L10 "VCMT053T-3R3MN5" VCMT053T 765.59,4546.03 r180 top value=3.3uH
L11 "XGL4030-102MEC" FP-XGL4030-102MEC_SMD_IND_4MM0_4MM0-MFG 2815.34,4387.34 r0 top value=1uH
L12 "TFM201610ALMA1R0MTAA" TFM201610ALMA 2465.9,4900.31 r270 top value=1uH
LBL1 "THT-14-423-10" Label_650x200 7786.62,173.62 r0 top
Logo1 "CE Mark" CE_Mark_5mm 5847.55,1765.22 r180 bottom
Logo2 "Texas Instruments" TI_Stacked_Overlay_Small 5538,1805.76 r0 top
Logo3 "FCC disclaimer" FCC_disclaimer 3537.4,6956.99 r180 bottom
Logo4 "WEEE logo" WEEE_Minimum 5846.44,2112.64 r180 bottom
LOGO5 "CAUTION HOT SURFACE" IEC_HotSurface_Medium 6422.63,4430.68 r0 top
NT1 "Net-Tie" Net-Tie_20milWide_60milLong 7718.37,1013.61 r180 top net-tie
NT2 "Net-Tie" Net-Tie_20milWide_60milLong 7723.83,949.23 r0 top net-tie
NT3 "Net-Tie" Net-Tie_20milWide_60milLong 7418.94,1300.21 r0 top net-tie
NT4 "Net-Tie" Net-Tie_20milWide_60milLong 7765.93,1912.57 r180 top net-tie
NT5 "Net-Tie" Net-Tie_20milWide_60milLong 7765.93,1851.79 r0 top net-tie
NT6 "Net-Tie" Net-Tie_20milWide_60milLong 7428.79,2189.46 r0 top net-tie
Q1 "BUK7J1R4-40HX" FP-BUK7J1R4-40HX_LFPAK56E-MFG 5296.03,5615.06 r180 top
Q2 "BUK7J1R4-40HX" FP-BUK7J1R4-40HX_LFPAK56E-MFG 6331.79,5182.72 r0 top
Q3 "BUK7J1R4-40HX" FP-BUK7J1R4-40HX_LFPAK56E-MFG 5265.84,5248.42 r270 top
Q4 "BUK7J1R4-40HX" FP-BUK7J1R4-40HX_LFPAK56E-MFG 6041.58,5182.72 r0 top
Q5 "BUK7J1R4-40HX" FP-BUK7J1R4-40HX_LFPAK56E-MFG 5665.57,5615.06 r180 top
Q6 "BUK7J1R4-40HX" FP-BUK7J1R4-40HX_LFPAK56E-MFG 6035.1,5613.11 r180 top
Q7 "CSD18512Q5B" DNK0008A 7493.89,916.11 r270 top value=40V
Q8 "CSD18512Q5B" DNK0008A 7815.59,525.99 r270 top value=40V
Q9 "CSD18512Q5B" DNK0008A 7486.68,1164.68 r0 top value=40V
Q10 "CSD18512Q5B" DNK0008A 7815.11,800.11 r0 top value=40V
Q11 "CSD18512Q5B" DNK0008A 7837.5,1455.62 r270 top value=40V
Q12 "CSD18512Q5B" DNK0008A 7495.26,1807.7 r270 top value=40V
Q13 "CSD18512Q5B" DNK0008A 7833.35,1704.54 r0 top value=40V
Q14 "CSD18512Q5B" DNK0008A 7493.08,2055.12 r0 top value=40V
Q15 "IRLML6401TRPBF" SOT-23 4424.44,5651.29 r90 bottom value=-12V
Q16 "IRLML6401TRPBF" SOT-23 4424.71,5817.41 r90 bottom value=-12V
Q17 "BSS123W-7-F" SOT-323 4478.11,5122.39 r0 bottom value=100V
Q18 "FDV303N" SOT-23 4472.88,4999.91 r0 bottom value=25V
Q19 "DMN6075S-7" SOT-23 7235.56,3946.09 r90 top value=60V
Q20 "BUK7S0R5-40HJ" FP-BUK7S0R5-40HJ_SOT1235-MFG 7185.6,4479.19 r0 top
Q21 "MMBT3904TT1G" SOT-416 7129.46,3700.35 r0 top value="40 V"
Q22 "ZVN4106FTA" SOT-23 4924.09,4697.12 r0 top value=60V
Q23 "DMN6075S-7" SOT-23 7378.8,6013.4 r180 top value=60V
Q24 "SQJQ410EL-T1_GE3" "FP-SQJQ410EL-T1_GE3_PowerPAK 8x8L-MFG" 7443.67,5736.04 r0 top
R1 "RC0603FR-07205RL" 0603 6459.78,3725.38 r0 top value=205
R2 "RC0603FR-07205RL" 0603 6122.67,2979.14 r90 top value=205
R3 "RC0603FR-07205RL" 0603 6122.39,3128.26 r270 top value=205
R4 "ERJ-2GE0R00X" FP-ERJ-2GE0R00X_0402-MFG 6437.23,3663.38 r0 top value=0
R5 "ERJ-2GE0R00X" FP-ERJ-2GE0R00X_0402-MFG 6196.89,2928.84 r0 top value=0
R6 "ERJ-2GE0R00X" FP-ERJ-2GE0R00X_0402-MFG 6192.52,3229.39 r0 top value=0
R7 "ERJ-2GE0R00X" FP-ERJ-2GE0R00X_0402-MFG 6437.23,3611.35 r0 top value=0
R8 "ERJ-2GE0R00X" FP-ERJ-2GE0R00X_0402-MFG 6437.23,3494.26 r0 top value=0
R9 "ERJ-2GE0R00X" FP-ERJ-2GE0R00X_0402-MFG 6192.52,3280.74 r0 top value=0
R10 "ERJ-2GE0R00X" FP-ERJ-2GE0R00X_0402-MFG 6437.23,3560.18 r0 top value=0
R11 "ERJ-2GE0R00X" FP-ERJ-2GE0R00X_0402-MFG 6196.89,2824.41 r0 top value=0
R12 "ERJ-2GE0R00X" FP-ERJ-2GE0R00X_0402-MFG 6192.52,3178.83 r0 top value=0
R13 "ERJ-2GE0R00X" FP-ERJ-2GE0R00X_0402-MFG 6196.89,2876.62 r0 top value=0
R14 "ERJ-2GE0R00X" FP-ERJ-2GE0R00X_0402-MFG 6196.89,2981.05 r0 top value=0
R15 "PU2512FKGP60U3L" "FP-PU2512FKGP60U3L_2512 (6432 Metric)-MFG" 5680.07,5300.9 r0 top
R16 "CRCW060350R0FKEA" 0603 5665,5095.11 r90 top value=50
R17 "ERJ-3GEY0R00V" 0603 6480.43,5029.02 r270 top value=0
R18 "ERJ-3GEY0R00V" 0603 5174.75,5097.68 r180 top value=0
R19 "ERJ-3GEY0R00V" 0603 5144.87,5704.36 r90 top value=0
R20 "CRCW060350R0FKEA" 0603 5659.23,5088.43 r180 bottom value=50
R21 "RT0603BRD0720K8L" 0603 5249.21,4826.54 r270 bottom value=20.8k
R22 "ERJ-PB3B1003V" FP-ERJ-PB3B1003V_0603-IPC_A 5314.53,4831.49 r270 top value=100k
R23 "RT0603BRD071K62L" 0603 5106.46,4827.01 r270 top value=1.62k
R24 "ERJ-PB3B1003V" FP-ERJ-PB3B1003V_0603-IPC_A 5176.42,4829.56 r270 top value=100k
R25 "ERJ-3EKF1002V" 0603 5322.24,4738.84 r180 bottom value=10.0k
R26 "ERJ-3EKF1002V" 0603 5384.06,4678.34 r180 bottom value=10.0k
R27 "ERJ-3EKF1002V" 0603 5578.33,4645.84 r270 bottom value=10.0k
R28 "RC0603FR-0730KL" 0603 5512.3,4645.79 r270 bottom value=30.0k
R29 "RC0603FR-0736K5L" 0603 5542.62,4645.85 r90 top value=36.5k
R30 "CSS2H-2512R-L500F" FP-CSS2H-2512R-L500F_2512-MFG 6677.67,5500.4 r0 top value=500µ
R31 "ERJ-PB3B1003V" FP-ERJ-PB3B1003V_0603-IPC_A 5415.72,4641.81 r270 top value=100k
R32 "SG73S1JTTD101J" FP-SG73S1JTTD101J_0603-MFG 6651.01,5308.87 r90 top value=100
R33 "SG73S1JTTD101J" FP-SG73S1JTTD101J_0603-MFG 6703.51,5308.87 r90 top value=100
R34 "ERJ-3GEY0R00V" 0603 5946.25,6108.58 r0 top value=0
R35 "ERJ-3EKF1002V" 0603 5814.86,6080.93 r180 top value=10.0k
R36 "RC0603JR-070RL" 0603 1433.09,1510 r180 top value=0
R37 "CRCW120660R0KNEAIF" 1206 1416.87,1509.09 r180 bottom value=60
R38 "CRCW120660R0KNEAIF" 1206 1416.87,1609.88 r0 bottom value=60
R39 "CRCW060333R0JNEA" 0603 1710.89,1721.13 r0 top value=33
R40 "RC0603JR-070RL" 0603 1434.4,1610 r180 top value=0
R41 "RG1608P-104-B-T5" 0603 1679.4,1752.62 r270 bottom value=100k
R42 "RC0603JR-070RL" 0603 1588.2,2882 r180 top value=0
R43 "CRCW120660R0KNEAIF" 1206 1569.8,2882.81 r180 bottom value=60
R44 "CRCW120660R0KNEAIF" 1206 1569.8,2980.01 r0 bottom value=60
R45 "RC0603JR-070RL" 0603 1588.2,2980 r180 top value=0
R46 "RC0603JR-070RL" 0603 1565.18,2250 r180 top value=0
R47 "CRCW120660R0KNEAIF" 1206 1549.03,2247.97 r180 bottom value=60
R48 "CRCW120660R0KNEAIF" 1206 1549.03,2347.15 r0 bottom value=60
R49 "RC0603JR-070RL" 0603 1564.76,2347 r180 top value=0
R50 "RC0603JR-070RL" 0603 1564.76,2552 r180 top value=0
R51 "CRCW120660R0KNEAIF" 1206 1549.03,2550.73 r180 bottom value=60
R52 "CRCW120660R0KNEAIF" 1206 1549.03,2650.7 r0 bottom value=60
R53 "RC0603JR-070RL" 0603 1564.76,2650 r180 top value=0
R64 "RT0603BRD071KL" 0603 767.96,3231.77 r90 top value=1.00k
R65 "AC0402FR-0710KL" 0402 986.51,3071.43 r180 top value=10.0k
R66 "RT0603BRD071KL" 0603 2058.52,3603.86 r0 bottom value=1.00k
R67 "RT0603BRD071KL" 0603 1915.7,3433.63 r90 bottom value=1.00k
R68 "RT0603BRD071KL" 0603 1915.77,3311.73 r270 bottom value=1.00k
R69 "AC0402FR-0710KL" 0402 2301.46,3476.37 r0 bottom value=10.0k
R70 "RT0603BRD071KL" 0603 2058.52,3136.1 r0 bottom value=1.00k
R71 "AC0402FR-0710KL" 0402 2301.46,3420.28 r0 bottom value=10.0k
R72 "AC0402FR-0710KL" 0402 2301.46,3362.26 r0 bottom value=10.0k
R73 "AC0402FR-0710KL" 0402 2301.46,3302.64 r0 bottom value=10.0k
R74 "RC0603JR-070RL" 0603 3467.84,6480.46 r270 top value=0
R75 "RC0603JR-070RL" 0603 3193.57,6236.15 r180 bottom value=0
R76 "RC0603JR-070RL" 0603 2638.95,6526.98 r270 top value=0
R77 "RC0603JR-070RL" 0603 1697.78,6520.4 r270 top value=0
R78 "RC0603JR-070RL" 0603 2606.33,6623.43 r180 top value=0
R79 "RC0603JR-070RL" 0603 1445.3,6239.52 r0 bottom value=0
R80 "CRCW060310R0FKEAHP" 0603 3840.27,1368.24 r0 top value=10.0
R81 "RMCF0603FT10K0" 0603 3840.27,1250.54 r0 top value=10.0k
R82 "RMCF0603FT10K0" 0603 3840.27,1309.91 r180 top value=10.0k
R83 "RMCF0603FT10K0" 0603 3857.3,1358.76 r180 bottom value=10.0k
R84 "RMCF0603FT10K0" 0603 4311.77,1293.72 r270 top value=10.0k
R85 "CRCW0603100RJNEA" 0603 4237.16,1516.22 r180 top value=100
R86 "RMCF0603FT10K0" 0603 4370.02,1293.89 r90 top value=10.0k
R87 "CRCW0603698RFKEA" 0603 3812.12,1515.09 r270 top value=698
R88 "CRCW0603100RJNEA" 0603 4343.79,1385.6 r180 top value=100
R89 "RC0603FR-0722RL" 0603 4257.05,1335.15 r90 bottom value=22.0
R90 "RC0402JR-0710KL" FP-RC0402JR-0710KL_0402-MFG 4374.68,1514.4 r270 top value=10k
R91 "CRCW0603100RJNEA" 0603 4343.27,1445.53 r180 top value=100
R92 "CRCW060310R0FKEAHP" 0603 3337.33,1019.87 r0 top value=10.0
R93 "RMCF0603FT10K0" 0603 3337.33,900.91 r0 top value=10.0k
R94 "RMCF0603FT10K0" 0603 3337.33,960.82 r180 top value=10.0k
R95 "RMCF0603FT10K0" 0603 3430.5,1081.43 r90 bottom value=10.0k
R96 "CRCW0603698RFKEA" 0603 3309.7,1171.07 r270 top value=698
R97 "CRCW0603100RJNEA" 0603 3844.8,1034.34 r180 top value=100
R98 "RC0201FR-0722RL" 0201 3812.81,1082.54 r180 top value=22.0
R99 "RMCF0603FT10K0" 0603 7398.54,3213.39 r270 bottom value=10.0k
R100 "CRCW060310R0FKEAHP" 0603 7459.29,3179.16 r180 top value=10.0
R101 "RMCF0603FT10K0" 0603 7247.09,3738.94 r0 top value=10.0k
R102 "RMCF0603FT10K0" 0603 7147.27,3619.62 r180 top value=10.0k
R103 "CRCW0603698RFKEA" 0603 7115.24,3249.94 r90 top value=698
R104 "CRCW0603100RJNEA" 0603 7146.55,3557.01 r0 top value=100
R105 "RC0603FR-0722RL" 0603 7146.55,3494.47 r0 top value=22.0
R106 "RMCF0603FT10K0" 0603 7596.01,3179.16 r180 top value=10.0k
R107 "RC0402JR-0710KL" FP-RC0402JR-0710KL_0402-MFG 7049.09,3442.41 r270 top value=10k
R108 "CRCW0603100RJNEA" 0603 7146.55,3431.93 r0 top value=100
R109 "RMCF0603FT10K0" 0603 7523.31,3243.94 r0 top value=10.0k
R110 "CRCW0603100RJNEA" 0603 7146.55,3369.39 r0 top value=100
R111 "RMCF0603FT10K0" 0603 4463.6,1081.58 r180 bottom value=10.0k
R112 "CRCW06034K99FKEA" 0603 4475.06,1137.95 r0 top value=4.99k
R113 "CRCW06034K99FKEA" 0603 7484.6,3091.4 r180 top value=4.99k
R114 "ESR03EZPJ102" 0603 4398.98,1017.49 r0 top value=1.0k
R115 "CRCW06034K99FKEA" 0603 4398.98,1079.83 r0 top value=4.99k
R116 "CRCW06034K99FKEA" 0603 7380.12,3065 r270 top value=4.99k
R117 "CRCW06034K99FKEA" 0603 4601.01,1138.01 r180 top value=4.99k
R118 "CRCW06034K99FKEA" 0603 7359.02,2906.28 r0 top value=4.99k
R119 "RMCF0603FT10K0" 0603 7276.21,3005.5 r90 top value=10.0k
R120 "CRCW06034K99FKEA" 0603 4669.93,1077.64 r180 top value=4.99k
R121 "CRCW06034K99FKEA" 0603 7171.15,2972.72 r0 top value=4.99k
R122 "CRCW060320K5FKEA" 0603 7559.56,2789.99 r180 top value=20.5k
R123 "RMCF0603FT10K0" 0603 4430.5,927.39 r270 top value=10.0k
R124 "RMCF0603FT10K0" 0603 7299.04,2846.53 r180 top value=10.0k
R125 "CRCW06034K99FKEA" 0603 4366.13,927.39 r270 top value=4.99k
R126 "CRCW060366K5FKEA" 0603 4669.93,1016.44 r180 top value=66.5k
R127 "ESR03EZPJ102" 0603 7451.54,2838.46 r90 top value=1.0k
R128 "RMCF0603FT10K0" 0603 7653.99,4902.94 r270 top value=10.0k
R129 "CRCW06034K99FKEA" 0603 5411.88,1091.07 r180 top value=4.99k
R130 "TNPW060310K0BEEA" TNPW0603 7532.63,4777.56 r270 bottom value=10.0k
R131 "ESR03EZPJ102" 0603 7595.95,4905.04 r270 bottom value=1.0k
R132 "CRCW06034K99FKEA" 0603 5411.88,1148.67 r180 top value=4.99k
R133 "TNPW060310K0BEEA" TNPW0603 7532.3,4686.29 r90 bottom value=10.0k
R134 "CRCW06034K99FKEA" 0603 5411.88,1207.1 r180 top value=4.99k
R135 "RMCF0603FT10K0" 0603 7688.88,4874.74 r0 bottom value=10.0k
R136 "CRCW06034K99FKEA" 0603 5411.88,1265.01 r180 top value=4.99k
R137 "CRCW06034K99FKEA" 0603 7690.25,4936.52 r0 bottom value=4.99k
R138 "CRCW060316K9FKEA" 0603 7638.61,4592.38 r270 top value=16.9k
R139 "CRCW06034K99FKEA" 0603 4929.94,1277.18 r0 top value=4.99k
R140 "CRCW06034K99FKEA" 0603 4929.94,1335.18 r0 top value=4.99k
R141 "RMCF0603FT10K0" 0603 4892.67,1256.77 r90 bottom value=10.0k
R142 "RMCF0603FT10K0" 0603 4892.73,1136.05 r270 bottom value=10.0k
R143 "ESR03EZPJ102" 0603 7610.39,4530.09 r90 bottom value=1.0k
R144 "CRCW06034K99FKEA" 0603 5411.88,1323.89 r180 top value=4.99k
R145 "CRCW06034K99FKEA" 0603 4956.81,1256.77 r270 bottom value=4.99k
R146 "CRCW06034K99FKEA" 0603 4794.62,1168.84 r0 bottom value=4.99k
R147 "RMCF0603FT10K0" 0603 5102.01,1224.99 r90 bottom value=10.0k
R148 "ESR03EZPJ102" 0603 5070.51,1033.79 r0 bottom value=1.0k
R149 "CRCW060323K2FKEA" 0603 4929.94,1101.22 r0 top value=23.2k
R150 "Resistor" 0603L 7097.12,1481.67 r270 top value=0
R151 "Resistor" 0603L 7615.8,637.01 r180 top value=0
R152 "Resistor" 0603L 7297.48,1026.32 r0 top value=0
R153 "CRCW04020000Z0ED" 0402 7208.08,1373.81 r270 top value=0
R154 "WSHM28187L000FEA" WSHM2818 7789.01,1162.86 r0 top value=0.007
R155 "ERA-3ARW103V" 0603L 6663.53,1279.23 r90 top value=10.0k
R156 "Resistor" 0603L 7615.8,725.11 r180 top value=0
R157 "Resistor" 0603L 7297,1089.57 r0 top value=0
R158 "RC0402JR-0710KL" FP-RC0402JR-0710KL_0402-MFG 6760.51,1530.08 r180 top value=10k
R159 "RC0201FR-0722RL" 0201 6610.85,1408.08 r0 top value=22.0
R160 "Resistor" 0603L 7634.21,1566.64 r0 top value=0
R161 "Resistor" 0603L 7295.21,1918.09 r0 top value=0
R162 "WSHM28187L000FEA" WSHM2818 7791.21,2055.16 r0 top value=0.007
R163 "Resistor" 0603L 7634.21,1629.54 r0 top value=0
R164 "Resistor" 0603L 7295.7,1979.32 r0 top value=0
R165 "RC0603JR-0710KL" 0603 3059.14,1023.49 r90 top value=10k
R166 "RC0603JR-0710KL" 0603 7369.31,2687.15 r90 top value=10k
R167 "RC0402JR-0710KL" FP-RC0402JR-0710KL_0402-MFG 3173.14,982.48 r180 top value=10k
R168 "CRCW06031K00FKEA" 0603 2980.43,946.7 r270 bottom value=1.00k
R169 "CRCW06031K00FKEA" 0603 7300.01,2618.15 r270 bottom value=1.00k
R170 "RC0201FR-0722RL" 0201 7417.99,2669.94 r270 top value=22.0
R171 "CRCW0603110RJNEA" 0603 6219.61,746.22 r180 top value=110
R172 "CRCW06034K70JNEA" 0603 6064.46,881.97 r0 top value=4.7k
R173 "CRCW06034K70JNEA" 0603 6064.46,762.53 r0 top value=4.7k
R174 "CRCW06034K70JNEA" 0603 6064.46,824.01 r0 top value=4.7k
R175 "CRCW0603510RJNEA" 0603 6562.23,767.75 r180 top value=510
R176 "CRCW0603510RJNEA" 0603 6556.04,825.33 r180 top value=510
R177 "CRCW0603510RJNEA" 0603 6555.66,882.89 r180 top value=510
R178 "RC0402JR-0710KL" FP-RC0402JR-0710KL_0402-MFG 6334.49,688.28 r0 top value=10k
R179 "CRCW0603510RJNEA" 0603 6385.93,748.54 r0 top value=510
R180 "MCT06030C2200FP500" 0603 2324.79,634.64 r90 top value=220
R181 "MCT06030C2200FP500" 0603 2410.39,635.63 r90 top value=220
R182 "ERJ-3EKF1002V" 0603 523.37,669.68 r0 top value=10.0k
R183 "MCT06030C2200FP500" 0603 974.53,633.66 r90 bottom value=220
R184 "MCT06030C2200FP500" 0603 824.34,634.64 r90 top value=220
R185 "ERJ-3EKF1002V" 0603 484.3,1293.28 r0 top value=10.0k
R186 "MCT06030C2200FP500" 0603 923.84,634.64 r90 top value=220
R187 "RC0201FR-0722RL" 0201 445.12,1223.81 r180 top value=22.0
R188 "MCT06030C2200FP500" 0603 1025.21,634.64 r90 top value=220
R189 "MCT06030C2200FP500" 0603 1174.8,633.66 r90 bottom value=220
R190 "MCT06030C2200FP500" 0603 1124.77,634.64 r90 top value=220
R191 "RT0603BRD071KL" 0603 320.32,933.49 r90 top value=1.00k
R192 "MCT06030C2200FP500" 0603 1224.97,634.64 r90 top value=220
R193 "MCT06030C2200FP500" 0603 1374.62,633.66 r90 bottom value=220
R194 "MCT06030C2200FP500" 0603 1324.41,634.64 r90 top value=220
R195 "MCT06030C2200FP500" 0603 1424.83,634.64 r90 top value=220
R196 "MCT06030C2200FP500" 0603 1574.79,633.66 r90 bottom value=220
R197 "MCT06030C2200FP500" 0603 1524.79,634.64 r90 top value=220
R198 "MCT06030C2200FP500" 0603 1724.79,634.64 r90 top value=220
R199 "MCT06030C2200FP500" 0603 1624.79,634.64 r90 top value=220
R200 "MCT06030C2200FP500" 0603 1774.79,633.66 r90 bottom value=220
R201 "MCT06030C2200FP500" 0603 1824.79,634.64 r90 top value=220
R202 "MCT06030C2200FP500" 0603 1924.79,634.64 r90 top value=220
R203 "MCT06030C2200FP500" 0603 1974.72,633.66 r90 bottom value=220
R204 "MCT06030C2200FP500" 0603 2024.79,634.64 r90 top value=220
R205 "MCT06030C2200FP500" 0603 2124.79,634.64 r90 top value=220
R206 "MCT06030C2200FP500" 0603 2174.79,633.66 r90 bottom value=220
R207 "MCT06030C2200FP500" 0603 2224.79,634.64 r90 top value=220
R208 "ERJ-1GN0R00C" 0201 3572.25,3673.18 r0 bottom value=0
R209 "ERJ-2GE0R00X" FP-ERJ-2GE0R00X_0402-MFG 3662.86,3895.12 r270 bottom value=0
R210 "ERJ-2GE0R00X" FP-ERJ-2GE0R00X_0402-MFG 3793.53,3859.41 r90 top value=0
R211 "ERJ-2GE0R00X" FP-ERJ-2GE0R00X_0402-MFG 3333.41,4223.77 r270 bottom value=0
R212 "TNPW060310K0BEEA" TNPW0603 3796.11,3581.99 r270 bottom value=10.0k
R213 "ERJ-3GEYJ122V" 0603 3858.02,3579.55 r90 bottom value=1.2k
R214 "ERJ-2GE0R00X" FP-ERJ-2GE0R00X_0402-MFG 3037.27,3378.55 r90 bottom value=0
R215 "ERJ-2GE0R00X" FP-ERJ-2GE0R00X_0402-MFG 3061.31,3481.2 r90 top value=0
R216 "ERJ-2GE0R00X" FP-ERJ-2GE0R00X_0402-MFG 3251.24,3296.13 r180 bottom value=0
R217 "ERJ-2GE0R00X" FP-ERJ-2GE0R00X_0402-MFG 3137.71,3378.55 r90 bottom value=0
R218 "ERJ-2GE0R00X" FP-ERJ-2GE0R00X_0402-MFG 3087.67,3378.55 r90 bottom value=0
R219 "ERJ-2GE0R00X" FP-ERJ-2GE0R00X_0402-MFG 3111.6,3481.2 r90 top value=0
R220 "ERJ-2GE0R00X" FP-ERJ-2GE0R00X_0402-MFG 3251.25,3331.46 r180 top value=0
R221 "CRCW04024K70JNED" 0402 2961.31,3981.77 r180 top value=4.7k
R222 "CRCW04024K70JNED" 0402 2961.31,4027.75 r180 top value=4.7k
R223 "RMCF0201ZT0R00" FP-RMCF0201ZT0R00_0201-MFG 3232.43,4342.72 r270 top value=0
R224 "ERJ-2GE0R00X" FP-ERJ-2GE0R00X_0402-MFG 3251.24,3366.78 r180 bottom value=0
R225 "RMCF0201ZT0R00" FP-RMCF0201ZT0R00_0201-MFG 3199.18,4342.72 r270 top value=0
R226 "RMCF0201ZT0R00" FP-RMCF0201ZT0R00_0201-MFG 3132.67,4342.72 r270 top value=0
R227 "ERJ-2GE0R00X" FP-ERJ-2GE0R00X_0402-MFG 3161.13,3481.2 r90 top value=0
R228 "RMCF0201ZT0R00" FP-RMCF0201ZT0R00_0201-IPC_C 3099.42,4342.72 r270 top value=0
R229 "ERJ-2GE0R00X" FP-ERJ-2GE0R00X_0402-MFG 3251.25,3402.11 r180 top value=0
R230 "RMCF0201ZT0R00" FP-RMCF0201ZT0R00_0201-MFG 3165.93,4342.72 r270 top value=0
R231 "RMCF0201ZT0R00" FP-RMCF0201ZT0R00_0201-MFG 3265.69,4342.72 r270 top value=0
R232 "RC0201FR-0722RL" 0201 3332.19,4342.72 r270 top value=22.0
R233 "RC0201FR-0722RL" 0201 3365.45,4342.72 r270 top value=22.0
R234 "RC0201FR-0722RL" 0201 3032.91,4342.72 r270 top value=22.0
R235 "RC0201FR-0722RL" 0201 2999.66,4342.72 r270 top value=22.0
R236 "RC0201FR-0722RL" 0201 3298.94,4342.72 r270 top value=22.0
R237 "RC0201FR-0722RL" 0201 3066.17,4342.72 r270 top value=22.0
R238 "ERJ-2GEJ152X" FP-ERJ-2GEJ152X_0402-MFG 3448.47,4223.05 r90 top value=1.5k
R239 "ERJ-2GEJ152X" FP-ERJ-2GEJ152X_0402-MFG 3387.29,4223.19 r90 bottom value=1.5k
R240 "ERJ-2GE0R00X" FP-ERJ-2GE0R00X_0402-MFG 2972.51,3696.72 r0 bottom value=0
R241 "RMCF0201ZT0R00" FP-RMCF0201ZT0R00_0201-MFG 3764.48,4342.72 r90 top value=0
R242 "RMCF0201ZT0R00" FP-RMCF0201ZT0R00_0201-MFG 3731.23,4342.72 r90 top value=0
R243 "RMCF0201ZT0R00" FP-RMCF0201ZT0R00_0201-MFG 3697.98,4342.72 r90 top value=0
R244 "RMCF0201ZT0R00" FP-RMCF0201ZT0R00_0201-MFG 3664.72,4342.72 r90 top value=0
R245 "RMCF0201ZT0R00" FP-RMCF0201ZT0R00_0201-MFG 3598.22,4342.72 r90 top value=0
R246 "RMCF0201ZT0R00" FP-RMCF0201ZT0R00_0201-MFG 3631.47,4342.72 r90 top value=0
R247 "RC0201FR-0722RL" 0201 3564.96,4342.72 r90 top value=22.0
R248 "RC0201FR-0722RL" 0201 3531.71,4342.72 r90 top value=22.0
R249 "RC0201FR-0722RL" 0201 3498.46,4342.72 r90 top value=22.0
R250 "RC0201FR-0722RL" 0201 3465.2,4342.72 r90 top value=22.0
R251 "RC0201FR-0722RL" 0201 3398.7,4342.72 r90 top value=22.0
R252 "RC0201FR-0722RL" 0201 3431.95,4342.72 r90 top value=22.0
R253 "ERJ-2GE0R00X" FP-ERJ-2GE0R00X_0402-MFG 3404.51,3482.18 r90 bottom value=0
R254 "RC0201FR-0749K9L" 0201 4125.78,2599.2 r0 top value=49.9k
R255 "RC0201FR-0749K9L" 0201 4192.38,2664.97 r270 top value=49.9k
R256 "RC0201FR-0749K9L" 0201 4192.38,2852.9 r90 top value=49.9k
R257 "RC0201FR-0749K9L" 0201 4021.42,2974.33 r90 top value=49.9k
R258 "RC0201FR-0749K9L" 0201 4108.13,2974.37 r90 top value=49.9k
R259 "CRCW04024K70JNED" 0402 3960.94,2993.81 r90 top value=4.7k
R260 "RC0201FR-0749K9L" 0201 4027.24,2558.38 r270 top value=49.9k
R261 "RC0201FR-0749K9L" 0201 4127.11,2783.51 r0 bottom value=49.9k
R262 "ERJ-2GE0R00X" FP-ERJ-2GE0R00X_0402-MFG 3458.29,3482.18 r90 bottom value=0
R263 "RC0402JR-0710KL" FP-RC0402JR-0710KL_0402-MFG 3988.61,2864.49 r180 bottom value=10k
R264 "RC0402JR-0710KL" FP-RC0402JR-0710KL_0402-MFG 3983.21,2617.7 r90 top value=10k
R265 "RC0402JR-0710KL" FP-RC0402JR-0710KL_0402-MFG 3809.86,2858.54 r180 top value=10k
R266 "RC0201FR-0722RL" 0201 4066.75,2783.48 r0 bottom value=22.0
R267 "RC0201FR-0722RL" 0201 4027.58,2622.93 r270 top value=22.0
R268 "RC0201FR-0722RL" 0201 3973.51,2925.84 r180 top value=22.0
R269 "RC0201FR-0722RL" 0201 4095.41,2925.84 r0 top value=22.0
R270 "RC0201FR-0722RL" 0201 4034.23,2925.84 r180 top value=22.0
R271 "RC0201FR-0722RL" 0201 4192.38,2792.6 r90 top value=22.0
R272 "RC0201FR-0722RL" 0201 4192.38,2726.91 r270 top value=22.0
R273 "RC0201FR-0722RL" 0201 4099.78,2634.13 r0 top value=22.0
R274 "RC0201FR-0722RL" 0201 4007.81,2798.76 r90 bottom value=22.0
R275 "ERJ-2RKF1001X" 0402 3984.28,2919.82 r0 bottom value=1.00k
R276 "CRCW0402100KJNED" 0402 3871.73,2628.34 r0 top value=100k
R277 "RC0402JR-0710KL" FP-RC0402JR-0710KL_0402-MFG 3720.51,3101.86 r0 top value=10k
R278 "RC0402JR-0710KL" FP-RC0402JR-0710KL_0402-MFG 3873.21,2967.89 r0 top value=10k
R279 "ERJ-2RKF1001X" 0402 4509.51,3925.11 r0 top value=1.00k
R280 "ERJ-2RKF1001X" 0402 4509.51,3874.87 r0 top value=1.00k
R281 "ERJ-2RKF1001X" 0402 4509.51,3825.08 r0 top value=1.00k
R282 "ERJ-2RKF1001X" 0402 4509.51,3774.25 r0 top value=1.00k
R283 "RC0402JR-0710KL" FP-RC0402JR-0710KL_0402-MFG 4377.77,3972.87 r90 bottom value=10k
R284 "RC0402JR-0710KL" FP-RC0402JR-0710KL_0402-MFG 3799.6,3333.36 r270 bottom value=10k
R285 "RC0402JR-0710KL" FP-RC0402JR-0710KL_0402-MFG 3745.02,3333.36 r270 bottom value=10k
R286 "RC0402JR-0710KL" FP-RC0402JR-0710KL_0402-MFG 3689.55,3333.36 r270 bottom value=10k
R287 "RC0402JR-0710KL" FP-RC0402JR-0710KL_0402-MFG 3634.42,3333.36 r270 bottom value=10k
R288 "RC0402JR-0710KL" FP-RC0402JR-0710KL_0402-MFG 4450,3793.83 r180 bottom value=10k
R289 "RC0402JR-0710KL" FP-RC0402JR-0710KL_0402-MFG 4450,3844.14 r180 bottom value=10k
R290 "RC0402JR-0710KL" FP-RC0402JR-0710KL_0402-MFG 4450,3894.44 r180 bottom value=10k
R291 "RC0402JR-0710KL" FP-RC0402JR-0710KL_0402-MFG 4450,3947.38 r180 bottom value=10k
R292 "ERJ-2GE0R00X" FP-ERJ-2GE0R00X_0402-MFG 3936.95,3999.17 r0 bottom value=0
R293 "ERJ-2GE0R00X" FP-ERJ-2GE0R00X_0402-MFG 3936.95,3955.93 r0 bottom value=0
R294 "Resistor" 0603L 4838.38,3884.05 r180 top value=0
R295 "ERJ-2GE0R00X" FP-ERJ-2GE0R00X_0402-MFG 3692.77,3752.25 r0 top value=0
R296 "Resistor" 0603L 4837.81,3732.23 r180 top value=0
R297 "ERJ-2GE0R00X" FP-ERJ-2GE0R00X_0402-MFG 3673.58,3858.43 r90 top value=0
R298 "Resistor" 0603L 4840.39,3579.27 r180 top value=0
R299 "ERJ-2GE0R00X" FP-ERJ-2GE0R00X_0402-MFG 3932.41,4086.48 r90 top value=0
R300 "Resistor" 0603L 4841.76,3427.48 r180 top value=0
R301 "CRCW06034K99FKEA" 0603 4494.86,3586.21 r180 top value=4.99k
R302 "Resistor" 0603L 4840.54,3274.13 r180 top value=0
R303 "CRCW06034K99FKEA" 0603 4493.02,3421.36 r180 top value=4.99k
R304 "Resistor" 0603L 4840.15,3120.62 r180 top value=0
R305 "CRCW06034K99FKEA" 0603 4494.5,3259.76 r180 top value=4.99k
R306 "Resistor" 0603L 4839.21,2967.15 r180 top value=0
R307 "CRCW06034K99FKEA" 0603 4494.33,3098.97 r180 top value=4.99k
R308 "Resistor" 0603L 4839.86,2807.55 r180 top value=0
R309 "Resistor" 0603L 4489.11,2939.88 r180 top value=0
R310 "ERJ-1GN0R00C" 0201 3735.48,3879.71 r180 top value=0
R311 "Resistor" 0603L 4489.19,2787.35 r180 top value=0
R312 "Resistor" 0603L 4840.6,2650.95 r180 top value=0
R313 "Resistor" 0603L 4489.54,2632.12 r180 top value=0
R314 "Resistor" 0603L 4840.11,2496.98 r180 top value=0
R315 "Resistor" 0603L 4489.59,2461.83 r180 top value=0
R316 "RC0402JR-0710KL" FP-RC0402JR-0710KL_0402-MFG 2263.33,4361.72 r0 top value=10k
R317 "RC0402JR-0710KL" FP-RC0402JR-0710KL_0402-MFG 2507.05,4450.44 r0 top value=10k
R318 "ERJ-2GE0R00X" FP-ERJ-2GE0R00X_0402-MFG 2261.71,4263.73 r180 top value=0
R319 "ERJ-2GE0R00X" FP-ERJ-2GE0R00X_0402-MFG 2614.93,4348.72 r90 top value=0
R320 "RC0402JR-0710KL" FP-RC0402JR-0710KL_0402-MFG 3263.73,1943.51 r270 top value=10k
R321 "RC0402JR-0710KL" FP-RC0402JR-0710KL_0402-MFG 3550.58,2705.19 r180 top value=10k
R322 "ERJ-2GE0R00X" FP-ERJ-2GE0R00X_0402-MFG 3482.54,2705.37 r0 top value=0
R323 "RC0402JR-0710KL" FP-RC0402JR-0710KL_0402-MFG 3316.66,2513.85 r270 top value=10k
R324 "CRCW060326K7FKEA" 0603 3752.04,2419.06 r90 top value=26.7k
R325 "TNPW060310K0BEEA" TNPW0603 3655.25,2425.36 r90 top value=10.0k
R326 "RC0402JR-0710KL" FP-RC0402JR-0710KL_0402-MFG 3587.16,1944.55 r270 top value=10k
R327 "RC0402JR-0710KL" FP-RC0402JR-0710KL_0402-MFG 3241.63,2438.12 r0 bottom value=10k
R328 "RC0402JR-0710KL" FP-RC0402JR-0710KL_0402-MFG 3908.43,1944.14 r270 top value=10k
R329 "ERJ-2GE0R00X" FP-ERJ-2GE0R00X_0402-MFG 3509.74,3501.82 r90 top value=0
R330 "RC0402JR-0710KL" FP-RC0402JR-0710KL_0402-MFG 3155.02,2494.15 r180 bottom value=10k
R331 "ERJ-2GEJ102X" 0402 3893.1,4799.35 r270 top value=1.0k
R332 "ERJ-2GE0R00X" FP-ERJ-2GE0R00X_0402-MFG 3910.24,4901.1 r0 top value=0
R333 "AC0402FR-0710KL" 0402 3993.63,4944.64 r90 bottom value=10.0k
R334 "CRCW04023K90JNED" 0402 3944.45,4897.34 r90 bottom value=3.9k
R335 "ERJ-2GE0R00X" FP-ERJ-2GE0R00X_0402-MFG 3898.93,4940.12 r270 bottom value=0
R336 "RC0402JR-0710KL" FP-RC0402JR-0710KL_0402-MFG 3530.44,5088.86 r0 bottom value=10k
R337 "RC0402JR-0710KL" FP-RC0402JR-0710KL_0402-MFG 3522.75,5418.09 r0 bottom value=10k
R338 "RC0402JR-0710KL" FP-RC0402JR-0710KL_0402-MFG 3402.57,5242.81 r90 bottom value=10k
R339 "ERJ-2GE0R00X" FP-ERJ-2GE0R00X_0402-MFG 3945.79,5373.01 r180 top value=0
R340 "RC0201FR-0722RL" 0201 3241.75,5271.31 r0 bottom value=22.0
R341 "ERJ-2GE0R00X" FP-ERJ-2GE0R00X_0402-MFG 3377.03,5345.11 r180 bottom value=0
R342 "ERJ-2GE0R00X" FP-ERJ-2GE0R00X_0402-MFG 3798.28,5206.7 r270 bottom value=0
R343 "RC0402JR-0710KL" FP-RC0402JR-0710KL_0402-MFG 2723.91,5378.2 r180 top value=10k
R344 "RT0603BRD074K7L" 0603 3857.31,5609.5 r270 top value=4.70k
R345 "RT0603BRD074K7L" 0603 3458.36,5613.79 r270 top value=4.70k
R346 "RC0402JR-0710KL" FP-RC0402JR-0710KL_0402-MFG 4533.71,1939.57 r270 top value=10k
R347 "RC0402JR-0710KL" FP-RC0402JR-0710KL_0402-MFG 4862.6,1938.79 r270 top value=10k
R348 "ERJ-2GEJ221X" RESC1005X40X25LL05T05 4335.44,5785.84 r90 bottom
R349 "RT0603BRD07470RL" 0603 4355.81,4939.93 r0 top value=470
R350 "RT0603BRD07470RL" 0603 4361.32,5319.52 r180 top value=470
R351 "RT0603BRD07470RL" 0603 4361.32,5219.99 r0 top value=470
R352 "RT0603BRD07470RL" 0603 4360.13,5517.31 r180 top value=470
R353 "RT0603BRD07470RL" 0603 4358.3,5418.51 r180 top value=470
R354 "RT0603BRD07470RL" 0603 4354.98,5121.35 r0 top value=470
R355 "RT0603BRD07470RL" 0603 4355.32,5025.58 r0 top value=470
R356 "ERJ-2GEJ221X" RESC1005X40X25LL05T05 4335.81,5619.66 r90 bottom
R357 "ERJ-2RKF1001X" 0402 4354.98,5121.35 r0 bottom value=1.00k
R358 "ERJ-2RKF1001X" 0402 4357.6,5024.82 r0 bottom value=1.00k
R359 "RC0201FR-0722RL" 0201 3101.79,4197.27 r0 top value=22.0
R360 "RC0201FR-0722RL" 0201 3189.23,4211.16 r270 top value=22.0
R361 "RC0201FR-0722RL" 0201 3346.21,3472.92 r90 bottom value=22.0
R362 "RC0201FR-0722RL" 0201 3236.74,3511.77 r90 bottom value=22.0
R363 "RC0201FR-0722RL" 0201 2977.2,3790.57 r0 top value=22.0
R364 "RC0201FR-0722RL" 0201 2977.15,3748.25 r0 top value=22.0
R365 "RC0201FR-0722RL" 0201 3214.82,3513.32 r90 top value=22.0
R366 "RC0201FR-0722RL" 0201 3193.88,3511.77 r90 bottom value=22.0
R367 "RC0201FR-0722RL" 0201 2361.03,1818.33 r270 top value=22.0
R368 "RT0603DRE072R21L" 0603 7120.48,3860.58 r90 top value=2.21
R369 "RC0603FR-07300RL" 0603 7054.74,3859.98 r90 top value=300
R370 "WSLF25121L000FEB" FP-WSLF25121L000FEB_2512-MFG 6842.72,4331.17 r0 top
R371 "CRCW06030000Z0EA" 0603 6833.77,4129.13 r90 top value=0
R372 "CRCW06030000Z0EA" 0603 6890.9,4129.13 r90 top value=0
R373 "CRCW060350R0FKEA" 0603 6833.7,4007.83 r270 top value=50
R374 "ERJ-3EKF2002V" 0603 6686.95,3869.51 r90 top value=20.0k
R375 "ERJ-3EKF1002V" 0603 6655.46,3777.95 r180 top value=10.0k
R376 "TNPW060310R0BEEA" 0603 7003.45,4121.25 r180 top value=10.0
R377 "CRCW06030000Z0EA" 0603 7003.43,4185.12 r180 top value=0
R378 "ERJ-3EKF1002V" 0603 6796.11,3565.06 r0 top value=10.0k
R379 "CRCW06030000Z0EA" 0603 7044.24,3693.57 r90 top value=0
R380 "ERJ-3EKF1002V" 0603 6796.11,3623.08 r0 top value=10.0k
R381 "RC0603FR-076K65L" 0603 6966.09,3722.46 r180 bottom value=6.65k
R382 "RC0603FR-0723K7L" 0603 6929.38,3566.3 r90 top value=23.7k
R383 "RC0603FR-071K33L" 0603 6723.25,3967.93 r0 top value=1.33k
R384 "RC0603FR-07205RL" 0603 1719.89,1409.73 r90 top value=205
R385 "MCT06030C1004FP500" 0603 609.75,1570.78 r90 top value=1.00Meg
R386 "CRCW06033R30JNEA" 0603 1746.9,4271.82 r270 bottom value=3.3
R387 "RC0603JR-070RL" 0603 2047.75,5215.06 r180 top value=0
R388 "RC0603JR-070RL" 0603 2047.2,5151.61 r180 top value=0
R389 "CRCW06033R30JNEA" 0603 1744.48,4564.65 r270 bottom value=3.3
R390 "RC0603JR-070RL" 0603 2047.2,5092.57 r180 top value=0
R391 "RC0603JR-070RL" 0603 2047.2,5033.53 r180 top value=0
R392 "RC0603JR-070RL" 0603 2047.2,4974.49 r180 top value=0
R393 "CRCW0603100KJNEAC" 0603 1655.36,4036.69 r0 top value=100k
R394 "CRCW0603100KJNEAC" 0603 1655.36,3976.84 r0 top value=100k
R395 "CRCW0603100KJNEAC" 0603 1655.36,4094.51 r0 top value=100k
R396 "CRCW06033R30JNEA" 0603 948.98,4287.89 r270 bottom value=3.3
R397 "CRCW06033R30JNEA" 0603 940.47,4646.59 r270 bottom value=3.3
R398 "RT0603BRD07499KL" 0603 4940.04,4532.73 r0 top value=499k
R399 "RT0603BRD07200KL" 0603 4937.9,4470.18 r180 top value=200k
R400 "RT0603BRD07180KL" 0603 4812.51,4763.77 r90 top value=180k
R401 "TNPW060310K0BEEA" TNPW0603 4593.28,4764.03 r90 top value=10.0k
R402 "CRCW0603715KFKEA" 0603 4940.07,4594.06 r0 top value=715k
R403 "CRCW0603200KFKEA" 0603 4848.94,4563.55 r90 top value=200k
R404 "ERJ-2GE0R00X" FP-ERJ-2GE0R00X_0402-MFG 2820.21,4684.55 r270 bottom value=0
R405 "AC0402FR-0710KL" 0402 2979.89,4473.77 r180 top value=10.0k
R406 "CRCW0402100KJNED" 0402 2799.99,4543.74 r0 bottom value=100k
R407 "CRCW060317K8FKEA" 0603 2854.41,5444.9 r90 top value=17.8k
R408 "AC0402FR-0710KL" 0402 3053.29,5351.99 r180 top value=10.0k
R409 "CRCW0402100KJNED" 0402 2657.09,4527.97 r0 top value=100k
R410 "AC0402FR-0710KL" 0402 3003.51,4553.18 r270 top value=10.0k
R411 "ERJ-2GE0R00X" FP-ERJ-2GE0R00X_0402-MFG 2675.12,4622.54 r0 top value=0
R412 "RC0402JR-0710KL" FP-RC0402JR-0710KL_0402-MFG 3383.86,2666.19 r90 top value=10k
R413 "ERJ-2GE0R00X" FP-ERJ-2GE0R00X_0402-MFG 2708.99,4893.66 r180 bottom value=0
R414 "AC0402FR-0710KL" 0402 2496.77,4759.21 r90 top value=10.0k
R415 "RG1608P-113-B-T5" 0603 2547.72,5072.5 r90 top value=11.0k
R416 "AC0402FR-0710KL" 0402 2569.79,4736.05 r180 top value=10.0k
R417 "CRCW040226K1FKED" 0402 2644.08,5060.52 r90 top value=26.1k
R418 "CRCW06030000Z0EA" 0603 5828.89,3366.01 r0 top value=0
R419 "CRCW06030000Z0EA" 0603 5664.68,3363.61 r180 top value=0
R420 "CRCW06030000Z0EA" 0603 5664.68,3187.59 r180 top value=0
R421 "CRCW06030000Z0EA" 0603 5828.89,3187.99 r0 top value=0
R422 "CRCW06030000Z0EA" 0603 5890.8,2523.95 r0 top value=0
R423 "CRCW06030000Z0EA" 0603 5510.54,2767.39 r270 top value=0
R424 "CRCW06030000Z0EA" 0603 5590.48,2524.6 r180 top value=0
R425 "CRCW06030000Z0EA" 0603 5798.67,2609.66 r270 top value=0
R426 "CRCW06030000Z0EA" 0603 5828.89,3247.11 r180 top value=0
R427 "CRCW06030000Z0EA" 0603 5664.68,3246.2 r0 top value=0
R428 "CRCW06030000Z0EA" 0603 5664.68,3068.62 r0 top value=0
R429 "CRCW06030000Z0EA" 0603 5828.89,3068.7 r180 top value=0
R430 "CRCW06030000Z0EA" 0603 5890.89,2642.54 r180 top value=0
R431 "CRCW06030000Z0EA" 0603 5627.59,2767.39 r90 top value=0
R432 "CRCW06030000Z0EA" 0603 5591.2,2641.26 r0 top value=0
R433 "CRCW06030000Z0EA" 0603 5683.23,2609.25 r90 top value=0
R434 "CRCW06030000Z0EA" 0603 5828.89,3307.26 r180 top value=0
R435 "CRCW06030000Z0EA" 0603 5664.68,3304.92 r0 top value=0
R436 "CRCW06030000Z0EA" 0603 5664.68,3128.57 r0 top value=0
R437 "CRCW06030000Z0EA" 0603 5828.89,3128.13 r180 top value=0
R438 "CRCW06030000Z0EA" 0603 5890.76,2582.31 r180 top value=0
R439 "CRCW06030000Z0EA" 0603 5570.05,2767.39 r90 top value=0
R440 "CRCW06030000Z0EA" 0603 5591.04,2583.4 r0 top value=0
R441 "CRCW06030000Z0EA" 0603 5741.46,2609.52 r90 top value=0
R442 "CRCW0603270KJNEA" 0603 4898.9,4519.66 r90 bottom value=270k
R443 "CRCW06030000Z0EA" 0603 4867.4,4327.95 r180 top value=0
R444 "CRCW0603110KFKEA" 0603 4833.01,4228.27 r90 bottom value=110k
R445 "CRCW06030000Z0EA" 0603 5212.86,4249.48 r0 top value=0
R446 "ERJ-3EKF1002V" 0603 6501.84,3273.31 r270 top value=10.0k
R447 "ERJ-3EKF1002V" 0603 6596.42,3375.79 r0 top value=10.0k
R448 "ERJ-3EKF1002V" 0603 6596.23,3273.31 r270 top value=10.0k
R449 "RC0201FR-0722RL" 0201 6480.38,3024.76 r0 top value=22.0
R450 "ERJ-3EKF1002V" 0603 5375.58,3087.06 r180 top value=10.0k
R451 "ERJ-3EKF1002V" 0603 5375.58,3027.05 r180 top value=10.0k
R452 "VMP-1R00-1.0-U" FP-VMP-1R00-1.0-U_2010-MFG 7101.79,6050.45 r0 top value=3
R453 "CRCW06030000Z0EA" 0603 7242.96,5282.8 r90 bottom value=0
R454 "CRCW06030000Z0EA" 0603 7310.09,5282.8 r90 bottom value=0
R455 "CRCW06030000Z0EA" 0603 7521.94,5975.89 r180 top value=0
R456 "RC0805FR-0710RL" 0805_HV 7512.6,5975.41 r0 bottom value=10.0
R457 "WSL3921L5000FEA" FP-WSL3921L5000FEA_3921-MFG 6997.67,5773.48 r0 top value=500µ
R458 "ERJ-3EKF1000V" 0603 6991.52,4989.19 r180 top value=100
R459 "CRCW06030000Z0EA" 0603 7011.89,5322.35 r90 top value=0
R460 "CRCW06030000Z0EA" 0603 7068.34,5385.12 r90 top value=0
R461 "RC0603FR-07124RL" 0603 7011.89,5198.65 r90 top value=124
R462 "CRCW06030000Z0EA" 0603 7068.34,5261.45 r90 top value=0
R463 "RC0603FR-072R21L" 0603 7302.34,5473.73 r0 top value=2.21
R464 "TNPW060310K0BEEA" TNPW0603 7297.3,4976.37 r270 top value=10.0k
R465 "RC0603FR-07820RL" 0603 6991.52,5047.62 r180 top value=820
R466 "RC0603FR-071KL" 0603 7131.83,5331.65 r90 top value=1.00k
R467 "CRCW06030000Z0EA" 0603 7301.85,5409.57 r0 top value=0
R468 "TNPW060310K0BEEA" TNPW0603 7518.16,5021.25 r270 top value=10.0k
R469 "TNPW060310K0BEEA" TNPW0603 7488.66,4946.6 r0 top value=10.0k
R470 "ERJ-3EKF1002V" 0603 7636.11,5171.25 r0 bottom value=10.0k
R471 "RC0603FR-074K7L" 0603 7636.11,5231.66 r180 top value=4.70k
R472 "CRCW0603100KFKEA" 0603 7636.11,5051.74 r180 bottom value=100k
R473 "RT0603BRD0724K6L" 0603 7636.11,5111.95 r180 bottom value=24.6k
R474 "3502220RFT" FP-3502220RFT_2010-MFG 6825.62,3908.49 r0 bottom
R475 "RT0603DRE072R21L" 0603 7104.65,4210.04 r90 top value=2.21
R476 "CRCW06030000Z0EA" 0603 4054.03,5566.72 r0 top value=0
R477 "CRCW06030000Z0EA" 0603 3736.13,2606.32 r180 bottom value=0
R478 "RC0603JR-070RL" 0603 3768.76,4201.68 r90 top value=0
R479 "RC0603JR-070RL" 0603 7231.32,4875.04 r0 top value=0
R482 "TNPW060310K0BEEA" TNPW0603 7387.18,4875.04 r180 top value=10.0k
RNTC_1 "NCU18WB473J6SRB" FP-NCU18WB473J6SRB_0603-MFG 7098.85,5479.19 r180 top value=47kΩ
S1 "CAS-D20TA" SW_CAS-D20TA 4100.27,4238.28 r0 top
SW1 "416131160804" FP-416131160804_SMT_SW-MFG 4249.35,3850.48 r270 top
SW2 "430182050816" FP-430182050816_SMT_SW_6MM2_6MM2-MFG 3424.75,2080.15 r270 top
SW3 "430182050816" FP-430182050816_SMT_SW_6MM2_6MM2-MFG 3748.77,2081.43 r270 top
SW4 "430182050816" FP-430182050816_SMT_SW_6MM2_6MM2-MFG 4068.61,2080.99 r270 top
SW5 "430182050816" FP-430182050816_SMT_SW_6MM2_6MM2-MFG 2561.2,5522.33 r180 top
SW6 "430182050816" FP-430182050816_SMT_SW_6MM2_6MM2-MFG 4371.74,2077.06 r270 top
SW7 "430182050816" FP-430182050816_SMT_SW_6MM2_6MM2-MFG 4698.05,2075.47 r270 top
T1 "CXS70-14-C" Panduit_CXS70-14-C 8364.25,6016.12 r180 top
T2 "CXS70-14-C" Panduit_CXS70-14-C 8360.21,4363.44 r180 top
T3 "CXS70-14-C" Panduit_CXS70-14-C 8364.25,5163.52 r180 top
T4 "CXS70-14-C" Panduit_CXS70-14-C 5144.95,6559.7 r270 top
T5 "CXS70-14-C" Panduit_CXS70-14-C 7185.58,6559.7 r270 top
T6 "CXS70-14-C" Panduit_CXS70-14-C 6198.51,6559.7 r270 top
T7 "TPS7B8133QDRVRQ1" DRV0006A 5089.81,4610.64 r90 top
TP1 "5010" Keystone5010 5242.27,5858.2 r0 top
TP2 "5010" Keystone5010 6388,4814.57 r0 top
TP3 "5010" Keystone5010 6665.66,5995.4 r0 top
TP4 "5010" Keystone5010 6130.36,5896.25 r0 top
TP5 "TESTPOINT" TP_25MIL-SMT 3879.32,3839.72 r90 top
TP6 "TESTPOINT" TP_25MIL-SMT 3646.41,3491.81 r90 bottom
TP7 "TESTPOINT" TP_25MIL-SMT 3644.68,3004.52 r90 top
TP8 "TESTPOINT" TP_25MIL-SMT 3812.36,5511.67 r270 top
TP9 "TESTPOINT" TP_25MIL-SMT 3517.1,5511.17 r270 top
TP10 "5011" Keystone5011 627.86,6584.9 r0 top
TP11 "5011" Keystone5011 4227.19,4574.96 r0 top
TP12 "5011" Keystone5011 6417.54,2034.06 r0 top
TP13 "5011" Keystone5011 8007.95,6617.81 r0 top
TP14 "5011" Keystone5011 6959.68,805.77 r0 top
TP15 "5011" Keystone5011 5675.8,3900.34 r0 top
TP16 "5011" Keystone5011 2378.28,2068.18 r0 top
TP17 "5011" Keystone5011 5735.25,1145.92 r0 top
TP18 "5011" Keystone5011 1513.81,3355.18 r90 top
TP19 "5011" Keystone5011 4761.84,1468.73 r90 top
TP20 "5011" Keystone5011 5946.15,3642.14 r90 top
TP21 "5011" Keystone5011 1443.74,1022.8 r90 top
TP22 "TESTPOINT" TP_25MIL-SMT 1757.78,5050.06 r180 top
TP23 "TESTPOINT" TP_25MIL-SMT 5621.07,4352.15 r0 top
TP24 "TESTPOINT" TP_25MIL-SMT 5200.23,4376.44 r0 top
TP25 "TESTPOINT" TP_25MIL-SMT 4800.56,4411.86 r180 top
TP26 "TESTPOINT" TP_25MIL-SMT 4384.94,4437.25 r0 top
U1 "LM74900QRGERQ1" RGE0024T-MFG 5503.11,4820.88 r0 top
U2 "INA186A3QDCKRQ1" DCK0006A-MFG 6662.54,5108.04 r90 top
U3 "TPS22919DCKT" DCK0006A_N 6644.04,4935.73 r0 top
U4 "LM74703QDDFRQ1" DDF0008A-MFG 5859.86,5967.23 r270 top
U5 "TCAN1043ADYYRQ1" DYY0014A-MFG 1683.99,1593.99 r180 top
U6 "TCAN1044VDRQ1" D0008A-MFG 1892.31,2934.25 r180 top
U7 "TCAN1046VDRQ1" D0014A_N 1940.53,2448.99 r180 top
U8 "SN3257QDYYRQ1" DYY0016A 2374.51,2486.2 r90 top
U10 "TLIN1021ADDF" DDF0008A-MFG 958.56,3167.55 r180 top
U11 "TLIN1024RGYRQ1" RGY0024C 2136.34,3371.56 r180 bottom
U12 "TXV0106BQBR" BQB0016A-MFG 3728.04,6502.68 r270 top
U13 "TXV0106BQBR" BQB0016A-MFG 3287.31,6503.64 r90 top
U14 "SN74LVC1G17QDCKRQ1" DCK0005A_N 2988.06,6514.96 r90 top
U15 "SN74LVC1G17QDCKRQ1" DCK0005A_N 2804.76,6515.01 r90 top
U16 "TXV0106BQBR" BQB0016A-MFG 1917.38,6502.68 r270 top
U17 "SN74LVC1G17QDCKRQ1" DCK0005A_N 2366.11,6515.01 r90 top
U18 "SN74LVC1G17QDCKRQ1" DCK0005A_N 2548.86,6514.76 r90 top
U19 "TXV0106BQBR" BQB0016A-MFG 1476.33,6502.84 r90 top
U20 "TPS2HCS10-Q1" PWP0016P-MFG 4091.67,1371.55 r0 top
U21 "TPS2HCS10-Q1" PWP0016P-MFG 3589.02,1021.54 r0 top
U22 "TPS2HCS05A" PWC0018A-MFG 7472.01,3482.69 r90 top
U23 "TPS1HC30BQPWPRQ1" PWP0014C-MFG 7638.36,2930.38 r0 top
U24 "TPS2HC08-Q1" VAH0011C-MFG 4535.32,983.41 r180 top
U25 "TPS4HC120-Q1" DGQ0028A-MFG 5170.91,956.42 r270 top
U26 "TPS1HC04PQVAHRQ1" VAH0011B-MFG 7653.42,4733.2 r90 bottom
U27 "DRV8714SQRVJRQ1" RVJ0056A 6887.44,1319.5 r0 top
U28 "DRV8245SQRXZRQ1" RXZ0016A-MFG 3123.43,817.89 r0 top
U29 "DRV8145SQRXZRQ1" RXZ0016A-MFG 7447.29,2492.92 r0 top
U30 "DRV81602QPWPRQ1" PWP0024T-MFG 6302.57,946.72 r180 top
U31 "TIC12400QDCPRQ1" DCP0038A-MFG 615.6,1043.93 r270 top
U32 "AM263PxC" ZCZ0324A-MFG 3336.29,3862.16 r90 top
U33 "IS25LX256-LHLE" FP-IS25LX256-LHLE_TFBGA24-IPC_C 4008,2779.44 r90 top
U34 "SN74LVC1G08DBVR" DBV0005A_N 3754.74,3004.66 r0 top
U35 "SN74AVC4T245DGVR" DGV0016A_N 4195.41,3904.08 r180 bottom
U36 "TMP411AQDGKRQ1" DGK0008A_N 2439.28,4347.81 r180 top
U37 "CAT24M01WI-GT3" FP-CAT24M01WI-GT3_SOIC8-IPC_C 2306.64,4097.23 r90 top
U38 "SN74LVC1G11DCKR" DCK0006A_N 3487.24,2621 r0 top
U39 "SN74LVC1G08DBVR" DBV0005A_N 3713.07,2556.37 r0 top
U40 "SN74LVC3G17DCUR" DCU0008A_N 3198.32,2484.31 r0 top
U41 "TPS6538600QDCARQ1" DCA0048J-MFG 3664.61,5231.08 r180 top
U42 "PTPS48111-Q1" 0-MFG 6903.5,3806.34 r90 top
U43 "TAS6754QDKQRQ1" DKQ0056D-MFG 1304.45,4401.1 r180 top
U44 "TPS3762-Q1" DDF0008A-MFG 4701.3,4695.67 r180 top
U45 "TPS62903QRYTQ1" RYT0009A-MFG 2800.49,4574.25 r90 top
U46 "TPS7B4256QDDARQ1" DDA0008A-MFG 3135.51,5488.01 r0 top
U47 "TPS62902QRYTRQ1" RYT0009A-MFG 2599.81,4927 r0 top
U48 "TMUX1308AQPWRQ1" PW0016A-MFG 5806.94,2841.47 r90 top
U49 "PTPLD1201DGSRQ1" DGS0010A-MFG 4922.82,4215.9 r0 top
U50 "PTPLD1201DGSRQ1" DGS0010A-MFG 5327.55,3640.12 r270 top
U51 "CCBTLV3861IPWRQ1" PW0024A-MFG 4596.32,4322.09 r180 top
U52 "CCBTLV3861IPWRQ1" PW0024A-MFG 5434.21,4338.62 r180 top
U53 "SN74AHCT1G14DBVT" DBV0005A_N 4593.79,4152.68 r90 bottom
U54 "TXE8124DGSR" DGS0032A-MFG 6698.38,3040.44 r90 top
U55 "TCAL9539RTW" RTW0024B-MFG 5199.43,2963.12 r270 top
U56 "TPS12140-Q1" RGE0023A-MFG 7389.35,5136.07 r90 top
Y2 "ABM10W-25.0000MHZ-8-K1Z-T3" FP-ABM10W-25.0000MHZ-8-K1Z-T3_SMT4_2MM5_2MM0-MFG 3645.74,3462.41 r270 top
ZZ1 "This Assembly Note is for PCB labels only" AssemblyNoteLabel -2.45,7848.43 r0 top
ZZ2 "These assemblies are ESD sensitive, ESD precautions shall be observed." AssemblyNote -0.79,7743.55 r0 top
ZZ3 "These assemblies must be clean and free from flux and all contaminants. Use of no clean flux is not acceptable." AssemblyNote -0.79,7645.8 r0 top
ZZ4 "These assemblies must comply with workmanship standards IPC-A-610 Class 2, unless otherwise specified." AssemblyNote -0.79,7548.06 r0 top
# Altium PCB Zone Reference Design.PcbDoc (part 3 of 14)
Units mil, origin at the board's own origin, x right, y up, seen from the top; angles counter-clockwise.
Board outline 8858.11 x 7047.08 mil, 16 copper layers (Top Layer, GND_1, SIG_1, GND_2, PWR/SIG_1, GND_3, PWR_1, PWR_2, GND_4, PWR/SIG_2, GND_5, SIG_2, GND_6, SIG_3, GND_7, Bottom Layer), stack 80.368 mil thick; 1131 components, 808 nets, 3825 pads, 3523 vias.
Unrouted connection lines stored in the file: 563.

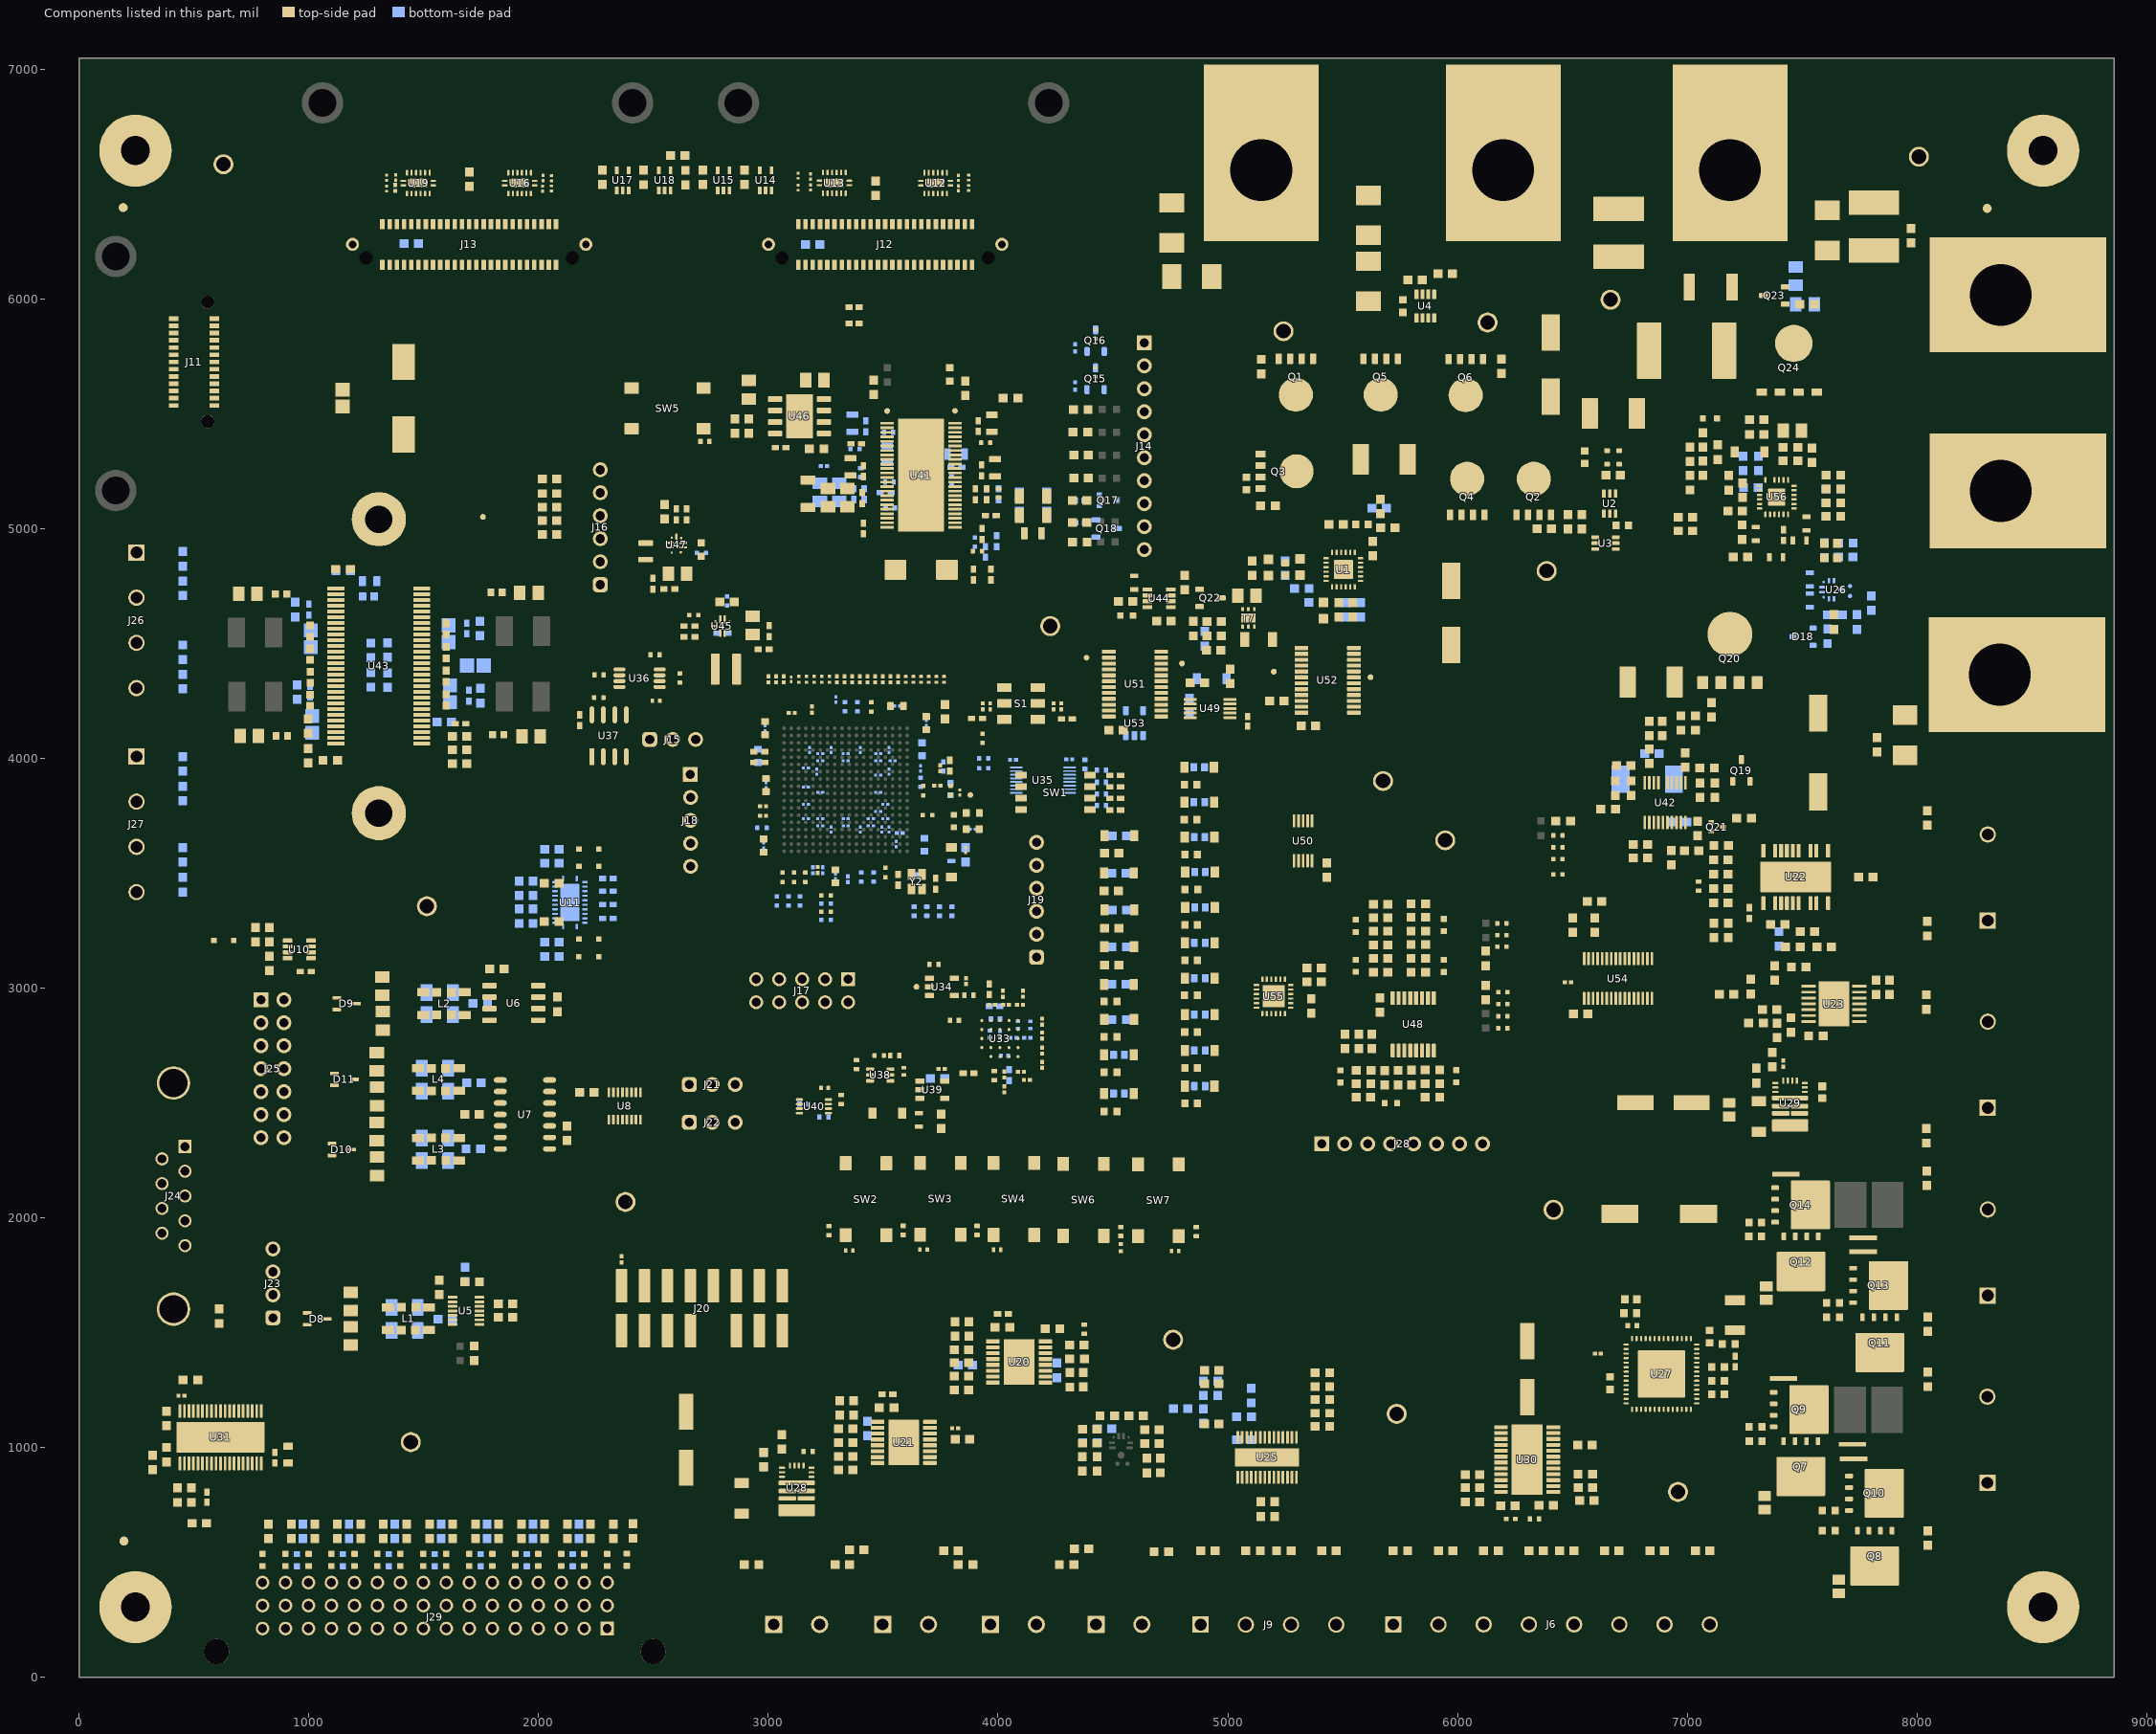
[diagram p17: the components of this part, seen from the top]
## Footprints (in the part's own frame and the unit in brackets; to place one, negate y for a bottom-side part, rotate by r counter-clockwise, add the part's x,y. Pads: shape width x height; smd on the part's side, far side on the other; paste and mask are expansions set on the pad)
0-MFG [mm]
  rrect33% 1.45x0.3 smd paste+0 mask+0: 1(-2.2,2.25) 2(-2.2,1.75) 3(-2.2,1.25) 4(-2.2,0.75) 5(-2.2,0.25) 6(-2.2,-0.25) 7(-2.2,-0.75) 8(-2.2,-1.25) 9(-2.2,-1.75) 10(-2.2,-2.25) 11(2.2,-2.25) 12(2.2,-1.75) 13(2.2,-1.25) 14(2.2,-0.75) 15(2.2,-0.25) 17(2.2,0.75) 18(2.2,1.25) 19(2.2,1.75) 20(2.2,2.25)
  silkscreen extent -3.6,-2.6 1.1,2.6, body extent -3.03,-2.85 3.03,2.85, height 0.25
0201 [mm] "Data from Kemet datasheet CC101_COM dated 7/28/11"
  rect 0.46x0.42 smd mask+0.048: 1(-0.33,0) 2(0.33,0)
  body extent -0.31,-0.16 0.31,0.16, height 0.26
0201_033 [mm] "SMD, 2-Leads, Height 0.33mm"
  rect 0.46x0.42 smd mask+0.048: 1(-0.33,0) 2(0.33,0)
  body extent -0.31,-0.16 0.31,0.16, height 0.33
0201_033L [mm] "0201"
  rect 0.36x0.32 smd mask+0.048: 1(-0.28,0) 2(0.28,0)
  body extent -0.31,-0.16 0.31,0.16, height 0.33
0201L [mm] "Data from Kemet datasheet CC101_COM dated 7/28/11"
  rect 0.36x0.32 smd mask+0.048: 1(-0.28,0) 2(0.28,0)
  body extent -0.31,-0.16 0.31,0.16, height 0.26
0402 [mm] "0402 from SM-752 data"
  rect 0.8x0.6 smd: 1(-0.6,0) 2(0.6,0)
  silkscreen extent -1.22,-0.52 1.22,0.52, body extent -0.55,-0.3 0.55,0.3, height 0.6
0402L [mm] "0402 from SM-752 data"
  rect 0.6x0.5 smd: 1(-0.5,0) 2(0.5,0)
  body extent -0.55,-0.3 0.55,0.3, height 0.6
0603 [mm] "0603 from SM-752 data"
  rect 1x0.95 smd: 1(-0.8,0) 2(0.8,0)
  silkscreen extent -1.52,-0.69 1.52,0.69, body extent -0.87,-0.47 0.87,0.47, height 1
0603L [mm] "0603 from SM-752 data"
  rect 0.8x0.85 smd: 1(-0.7,0) 2(0.7,0)
  silkscreen extent -0.07,-0.33 0.07,0.33, body extent -0.87,-0.47 0.87,0.47, height 1
0805_HV [mil] "0805 with 30mil clearance between pads"
  rect 50x63 smd: 1(-40,0) 2(40,0)
  silkscreen extent -74,-40 74,40, body extent -43,-29 43,29, height 57
0805L [mm] "0805 from SM-752 data"
  rect 1.1x1.4 smd: 1(-0.75,0) 2(0.75,0)
  body extent -1.1,-0.72 1.1,0.72, height 1.45
1206 [mm] "1206 from SM-752 data"
  rect 1.3x1.85 smd: 1(-1.45,0) 2(1.45,0)
  silkscreen extent -2.4,-1.21 2.4,1.21, body extent -1.7,-0.9 1.7,0.9, height 1.35
1206_180 [mm] "1206_180"
  rect 1.1x1.6 smd: 1(-1.7,0) 2(1.7,0)
  silkscreen extent -0.9,-1 0.9,1, body extent -1.75,-0.95 1.75,0.95, height 1.8
1210_280 [mm] "SMD, 2-Leads, Body 3.6x2.8mm, Height 2.8mm"
  rect 1.1x2.2 smd: 1(-1.65,0) 2(1.65,0)
  silkscreen extent -0.84,-1.4 0.84,1.4, body extent -1.8,-1.4 1.8,1.4, height 2.8
ACT45B [mm] "SMD, 4-Leads, Body 4.7 x 3.7 mm"
  rect 1.35x0.9 smd: 1(-2.275,1.25) 2(-2.275,-1.25) 3(2.275,-1.25) 4(2.275,1.25)
  silkscreen extent -2.35,-1.7 2.35,2, body extent -2.35,-1.7 2.35,1.7, height 3
AssemblyNote [mil] "Assembly Note"
AssemblyNoteLabel [mil] "Assembly Note for PCB Labels"
BQB0016A-MFG [mm]
  rrect42% 0.24x0.6 smd paste+0 mask+0: 1(-0.25,1.65) 8(-0.25,-1.65) 9(0.25,-1.65) 16(0.25,1.65)
  rrect42% 0.6x0.24 smd paste+0 mask+0: 2(-1.15,1.25) 3(-1.15,0.75) 4(-1.15,0.25) 5(-1.15,-0.25) 6(-1.15,-0.75) 7(-1.15,-1.25) 10(1.15,-1.25) 11(1.15,-0.75) 12(1.15,-0.25) 13(1.15,0.25) 14(1.15,0.75) 15(1.15,1.25)
  rrect10% 1x2 smd paste-1000 mask+0: 17(0,0)
  silkscreen extent -1.3,-1.8 1.3,2.63, body extent -1.55,-2.05 1.55,2.05, height 0.25
CE_Mark_5mm [mil] "Minimum text height for CE Mark"
  silkscreen extent -138,-98 138,98
CLF7045NI-D [mm] "Inductor"
  rrect5% 2.4x2.2 smd: 1(-2.85,0) 2(2.85,0)
  body extent -3.8,-3.6 3.8,3.6, height 4.81
D0008A-MFG [mm]
  rrect17% 1.55x0.6 smd paste+0 mask+0: 1(-2.7,1.905) 2(-2.7,0.635) 3(-2.7,-0.635) 4(-2.7,-1.905) 5(2.7,-1.905) 6(2.7,-0.635) 7(2.7,0.635) 8(2.7,1.905)
  silkscreen extent -4.18,-2.5 1.5,2.5, body extent -3.57,-2.75 3.57,2.75, height 0.25
D0014A_N [mm] "SOIC, 14-Leads, Body 8.7x3.9mm, Pitch 1.27mm, IPC Medium Density"
  oval 1.45x0.6 smd: 1(-2.725,3.81) 2(-2.725,2.54) 3(-2.725,1.27) 4(-2.725,0) 5(-2.725,-1.27) 6(-2.725,-2.54) 7(-2.725,-3.81) 8(2.725,-3.81) 9(2.725,-2.54) 10(2.725,-1.27) 11(2.725,0) 12(2.725,1.27) 13(2.725,2.54) 14(2.725,3.81)
  silkscreen extent -3.3,-4.4 0.9,4.4, body extent -3.02,-4.32 3.02,4.32, height 1.6
DBV0005A_N [mm] "SOT23, 5-Leads, Body 2.9x1.6mm, Pitch 0.95mm, Lead Span 2.8mm, IPC Medium Density"
  rrect17% 1x0.6 smd: 1(-1.375,0.95) 2(-1.375,0) 3(-1.375,-0.95) 4(1.375,-0.95) 5(1.375,0.95)
  silkscreen extent -0.25,-1.55 0.25,1.55, body extent -1.42,-1.46 1.42,1.46, height 1.09
DCA0048J-MFG [mm]
  rrect33% 1.5x0.3 smd paste+0 mask+0: 1(-3.75,5.75) 2(-3.75,5.25) 3(-3.75,4.75) 4(-3.75,4.25) 5(-3.75,3.75) 6(-3.75,3.25) 7(-3.75,2.75) 8(-3.75,2.25) 9(-3.75,1.75) 10(-3.75,1.25) 11(-3.75,0.75) 12(-3.75,0.25) 13(-3.75,-0.25) 14(-3.75,-0.75) 15(-3.75,-1.25) 16(-3.75,-1.75) 17(-3.75,-2.25) 18(-3.75,-2.75) 19(-3.75,-3.25) 20(-3.75,-3.75) 21(-3.75,-4.25) 22(-3.75,-4.75) 23(-3.75,-5.25) 24(-3.75,-5.75) 25(3.75,-5.75) 26(3.75,-5.25) 27(3.75,-4.75) 28(3.75,-4.25) 29(3.75,-3.75) 30(3.75,-3.25) 31(3.75,-2.75) 32(3.75,-2.25) 33(3.75,-1.75) 34(3.75,-1.25) 35(3.75,-0.75) 36(3.75,-0.25) 37(3.75,0.25) 38(3.75,0.75) 39(3.75,1.25) 40(3.75,1.75) 41(3.75,2.25) 42(3.75,2.75) 43(3.75,3.25) 44(3.75,3.75) 45(3.75,4.25) 46(3.75,4.75) 47(3.75,5.25) 48(3.75,5.75)
  rrect2% 5.1x12.5 smd paste-1000 mask-1000: 49(0,0)
  silkscreen extent -5.2,-6.3 3.1,6.3, body extent -4.6,-6.55 4.6,6.55, height 0.25
DCK0003A-MFG [mm]
  rrect25% 0.95x0.4 smd paste+0 mask+0: 1(-1.1,0.65) 2(-1.1,-0.65) 3(1.1,0)
  silkscreen extent -0.7,-1.07 0.7,1.07, body extent -1.67,-1.17 1.68,1.17, height 0.25
DCK0005A_N [mm] "SOT353, 5-Leads, Body 2x1.3mm, Pitch 0.65mm, Lead Span 2.1mm, IPC Medium Density"
  rrect25% 0.85x0.4 smd: 1(-1.125,0.65) 2(-1.125,0) 3(-1.125,-0.65) 4(1.125,-0.65) 5(1.125,0.65)
  silkscreen extent -1.48,-1.02 0.55,1.1, body extent -1.14,-1 1.14,1, height 0.95
DCK0006A-MFG [mm]
  rrect25% 0.9x0.4 smd paste-1000 mask+0: 1(-1.1,0.65) 2(-1.1,0) 3(-1.1,-0.65) 4(1.1,-0.65) 5(1.1,0) 6(1.1,0.65)
  silkscreen extent -2.22,-1.07 0.27,1.07, body extent -1.65,-1.33 1.65,1.33, height 0.25
DCK0006A_N [mm] "SOT23, 6-Leads, Body 2x1.3mm, Pitch 0.65mm, Lead Span 2.1mm, IPC Medium Density"
  rrect25% 0.85x0.4 smd: 1(-1.125,0.65) 2(-1.125,0) 3(-1.125,-0.65) 4(1.125,-0.65) 5(1.125,0) 6(1.125,0.65)
  silkscreen extent -1.5,-1.09 0.51,1.09, body extent -1.14,-1 1.14,1, height 0.95
DCP0038A-MFG [mm]
  rrect33% 1.5x0.3 smd paste+0 mask+0: 1(-2.9,4.5) 2(-2.9,4) 3(-2.9,3.5) 4(-2.9,3) 5(-2.9,2.5) 6(-2.9,2) 7(-2.9,1.5) 8(-2.9,1) 9(-2.9,0.5) 10(-2.9,0) 11(-2.9,-0.5) 12(-2.9,-1) 13(-2.9,-1.5) 14(-2.9,-2) 15(-2.9,-2.5) 16(-2.9,-3) 17(-2.9,-3.5) 18(-2.9,-4) 19(-2.9,-4.5) 20(2.9,-4.5) 21(2.9,-4) 22(2.9,-3.5) 23(2.9,-3) 24(2.9,-2.5) 25(2.9,-2) 26(2.9,-1.5) 27(2.9,-1) 28(2.9,-0.5) 29(2.9,0) 30(2.9,0.5) 31(2.9,1) 32(2.9,1.5) 33(2.9,2) 34(2.9,2.5) 35(2.9,3) 36(2.9,3.5) 37(2.9,4) 38(2.9,4.5)
  rrect3% 3.4x9.7 smd paste-1000 mask-1000: 39(0,0)
  silkscreen extent -4.35,-5.23 2.25,5.22, body extent -3.75,-5.15 3.75,5.15, height 0.25
DCU0008A_N [mm] "TSSOP, 8-Leads, Body 2x2.3mm, Pitch 0.5mm, IPC Medium Density"
  oval 0.8x0.3 smd: 1(-1.6,0.75) 2(-1.6,0.25) 3(-1.6,-0.25) 4(-1.6,-0.75) 5(1.6,-0.75) 6(1.6,-0.25) 7(1.6,0.25) 8(1.6,0.75)
  silkscreen extent -1.05,-1.05 0.38,1.05, body extent -1.56,-1 1.56,1, height 0.9
DDA0008A-MFG [mm]
  rrect17% 1.55x0.6 smd paste+0 mask+0: 1(-2.7,1.905) 2(-2.7,0.635) 3(-2.7,-0.635) 4(-2.7,-1.905) 5(2.7,-1.905) 6(2.7,-0.635) 7(2.7,0.635) 8(2.7,1.905)
  rrect3% 2.95x4.9 smd paste-1000 mask-1000: 9(0,0)
  silkscreen extent -4.15,-2.83 2,2.83, body extent -3.57,-2.75 3.57,2.75, height 0.25
DDF0008A-MFG [mm]
  rrect22% 1.05x0.45 smd paste+0 mask+0: 1(-1.3,0.975) 2(-1.3,0.325) 3(-1.3,-0.325) 4(-1.3,-0.975) 5(1.3,-0.975) 6(1.3,-0.325) 7(1.3,0.325) 8(1.3,0.975)
  silkscreen extent -2.5,-1.47 0.4,1.48, body extent -1.92,-1.72 1.93,1.73, height 0.25
DGK0008A_N [mm] "TSOP, 8-Leads, Body 3x3mm, Pitch 0.65mm, IPC Medium Density"
  oval 1.35x0.45 smd: 1(-2.225,0.975) 2(-2.225,0.325) 3(-2.225,-0.325) 4(-2.225,-0.975) 5(2.225,-0.975) 6(2.225,-0.325) 7(2.225,0.325) 8(2.225,0.975)
  silkscreen extent -2.75,-1.55 0.95,1.55, body extent -2.45,-1.5 2.45,1.5, height 0.96
DGQ0028A-MFG [mm]
  rrect33% 1.4x0.3 smd paste+0 mask+0: 1(-2.2,3.25) 2(-2.2,2.75) 3(-2.2,2.25) 4(-2.2,1.75) 5(-2.2,1.25) 6(-2.2,0.75) 7(-2.2,0.25) 8(-2.2,-0.25) 9(-2.2,-0.75) 10(-2.2,-1.25) 11(-2.2,-1.75) 12(-2.2,-2.25) 13(-2.2,-2.75) 14(-2.2,-3.25) 15(2.2,-3.25) 16(2.2,-2.75) 17(2.2,-2.25) 18(2.2,-1.75) 19(2.2,-1.25) 20(2.2,-0.75) 21(2.2,-0.25) 22(2.2,0.25) 23(2.2,0.75) 24(2.2,1.25) 25(2.2,1.75) 26(2.2,2.25) 27(2.2,2.75) 28(2.2,3.25)
  rrect5% 2x7.1 smd paste-1000 mask-1000: 29(0,0)
  silkscreen extent -3.57,-3.92 1.55,3.92, body extent -3,-3.85 3,3.85, height 0.25
DGS0010A-MFG [mm] "Recommended Land Pattern"
  rrect33% 1.45x0.3 smd paste+0 mask+0: 1(-2.2,1) 2(-2.2,0.5) 3(-2.2,0) 4(-2.2,-0.5) 5(-2.2,-1) 6(2.2,-1) 7(2.2,-0.5) 8(2.2,0) 9(2.2,0.5) 10(2.2,1)
  silkscreen extent -3.6,-1.55 1.05,1.55, body extent -3.03,-1.8 3.03,1.8, height 0.25
DGS0032A-MFG [mm]
  rrect33% 1.45x0.3 smd paste+0 mask+0: 1(-2.2,3.75) 2(-2.2,3.25) 3(-2.2,2.75) 4(-2.2,2.25) 5(-2.2,1.75) 6(-2.2,1.25) 7(-2.2,0.75) 8(-2.2,0.25) 9(-2.2,-0.25) 10(-2.2,-0.75) 11(-2.2,-1.25) 12(-2.2,-1.75) 13(-2.2,-2.25) 14(-2.2,-2.75) 15(-2.2,-3.25) 16(-2.2,-3.75) 17(2.2,-3.75) 18(2.2,-3.25) 19(2.2,-2.75) 20(2.2,-2.25) 21(2.2,-1.75) 22(2.2,-1.25) 23(2.2,-0.75) 24(2.2,-0.25) 25(2.2,0.25) 26(2.2,0.75) 27(2.2,1.25) 28(2.2,1.75) 29(2.2,2.25) 30(2.2,2.75) 31(2.2,3.25) 32(2.2,3.75)
  silkscreen extent -2.32,-4.1 1,4.57, body extent -3.03,-4.35 3.03,4.35, height 0.25
DGV0016A_N [mm] "TSSOP, 16-Leads, Body 3.6x4.4mm, Pitch 0.4mm, IPC Medium Density"
  oval 1.4x0.2 smd: 1(-2.95,1.4) 2(-2.95,1) 3(-2.95,0.6) 4(-2.95,0.2) 5(-2.95,-0.2) 6(-2.95,-0.6) 7(-2.95,-1) 8(-2.95,-1.4) 9(2.95,-1.4) 10(2.95,-1) 11(2.95,-0.6) 12(2.95,-0.2) 13(2.95,0.2) 14(2.95,0.6) 15(2.95,1) 16(2.95,1.4)
  silkscreen extent -3.45,-1.85 1.85,1.85, body extent -3.21,-1.8 3.21,1.8, height 1.2
DKQ0056D-MFG [mm]
  rrect25% 1.9x0.4 smd paste+0 mask+0: 1(-4.75,8.572) 2(-4.75,7.937) 3(-4.75,7.303) 4(-4.75,6.667) 5(-4.75,6.032) 6(-4.75,5.397) 7(-4.75,4.762) 8(-4.75,4.127) 9(-4.75,3.492) 10(-4.75,2.857) 11(-4.75,2.222) 12(-4.75,1.587) 13(-4.75,0.952) 14(-4.75,0.317) 15(-4.75,-0.318) 16(-4.75,-0.953) 17(-4.75,-1.588) 18(-4.75,-2.223) 19(-4.75,-2.858) 20(-4.75,-3.493) 21(-4.75,-4.128) 22(-4.75,-4.763) 23(-4.75,-5.398) 24(-4.75,-6.033) 25(-4.75,-6.668) 26(-4.75,-7.302) 27(-4.75,-7.938) 28(-4.75,-8.572) 29(4.75,-8.572) 30(4.75,-7.938) 31(4.75,-7.303) 32(4.75,-6.668) 33(4.75,-6.033) 34(4.75,-5.398) 35(4.75,-4.762) 36(4.75,-4.127) 37(4.75,-3.493) 38(4.75,-2.858) 39(4.75,-2.222) 40(4.75,-1.588) 41(4.75,-0.953) 42(4.75,-0.318) 43(4.75,0.317) 44(4.75,0.952) 45(4.75,1.587) 46(4.75,2.222) 47(4.75,2.857) 48(4.75,3.493) 49(4.75,4.128) 50(4.75,4.762) 51(4.75,5.397) 52(4.75,6.033) 53(4.75,6.667) 54(4.75,7.302) 55(4.75,7.937) 56(4.75,8.572)
  silkscreen extent -4.87,-9.27 3.25,9.45, body extent -5.8,-9.52 5.8,9.52, height 0.25
DNK0008A [mm] "SON, 8-Leads, Body 5x6mm"
  rrect39% 0.86x0.51 smd paste-0.05 mask-0.05: 1(-2.82,1.905) 2(-2.82,0.635) 3(-2.82,-0.635) 4(-2.82,-1.905) 5(2.82,-1.905) 6(2.82,-0.635) 7(2.82,0.635) 8(2.82,1.905)
  rrect40% 0.25x0.555 on Top Paste: 9(-0.83,2.372) 9(-0.83,-2.373)
  rrect40% 0.25x0.555 on Top Solder: 9(-0.83,2.372) 9(-0.83,-2.373)
  rrect11% 0.95x1.13 on Top Paste: 9(-0.535,0) 9(-0.535,-1.33) 9(-0.535,1.33) 9(0.615,1.33) 9(0.615,0) 9(0.615,-1.33) 9(1.765,1.33) 9(1.765,-1.33) 9(1.765,0)
  rrect3% 3.58x4 on Top Solder: 9(0.75,0)
  rrect5% 4.34x5.4 smd paste-3 mask-3: 9(1.08,0)
  body extent -3.05,-2.55 3.05,2.55, height 1.06
DRV0006A [mm] "SON, 6-Leads, Body 2x2mm, Pitch 0.65mm, Thermal Pad 1.6x1mm, TI Recommended"
  rrect33% 0.45x0.3 smd: 1(-0.975,0.65) 2(-0.975,0) 3(-0.975,-0.65) 4(0.975,-0.65) 5(0.975,0) 6(0.975,0.65)
  rrect14% 1x0.7 on Top Paste: 7(0,0.45) 7(0,-0.45)
  rrect10% 1x1.6 smd paste-0.5: 7(0,0)
  silkscreen extent -1.05,-1.2 1.05,1.2, body extent -1.05,-1.05 1.05,1.05, height 0.81
DYY0014A-MFG [mm]
  rrect33% 1.05x0.3 smd paste+0 mask+0: 1(-1.5,1.5) 2(-1.5,1) 3(-1.5,0.5) 4(-1.5,0) 5(-1.5,-0.5) 6(-1.5,-1) 7(-1.5,-1.5) 8(1.5,-1.5) 9(1.5,-1) 10(1.5,-0.5) 11(1.5,0) 12(1.5,0.5) 13(1.5,1) 14(1.5,1.5)
  silkscreen extent -2.73,-2.15 1.05,2.15, body extent -2.13,-2.4 2.12,2.4, height 0.25
DYY0016A [mm] "SOP, 16-Leads, Body 2x4.2mm, Pitch 0.5mm"
  rrect33% 1.05x0.3 smd: 1(-1.5,1.75) 2(-1.5,1.25) 3(-1.5,0.75) 4(-1.5,0.25) 5(-1.5,-0.25) 6(-1.5,-0.75) 7(-1.5,-1.25) 8(-1.5,-1.75) 9(1.5,-1.75) 10(1.5,-1.25) 11(1.5,-0.75) 12(1.5,-0.25) 13(1.5,0.25) 14(1.5,0.75) 15(1.5,1.25) 16(1.5,1.75)
  body extent -1.63,-2.1 1.63,2.1, height 1.02
FCC_disclaimer [mil]
Fiducial10-20 [mm]
  round 1 smd mask+0.5: 1(0,0)
  Top Layer keep-out circle w1.178: c0,0 r0.5
FP-150040RS73220_0402-MFG [mm]
  rrect25% 0.4x0.46 smd paste+0 mask+0: 1(-0.5,0) 2(0.5,0)
  silkscreen extent -1.37,-0.6 0.5,0.61, body extent -0.8,-0.4 0.8,0.4, height 0.25
FP-3502220RFT_2010-MFG [mm]
  rrect5% 2x3 smd paste+0 mask+0: 1(-2.95,0) 2(2.95,0)
  silkscreen extent -1.58,-1.33 1.58,1.33, body extent -2.5,-1.25 2.5,1.25, height 1.2
FP-416131160804_SMT_SW-MFG [mm]
  rrect13% 0.76x1.27 smd paste+0 mask+0: 1(-1.905,-3.81) 2(-0.635,-3.81) 3(0.635,-3.81) 4(1.905,-3.81) 5(1.905,3.81) 6(0.635,3.81) 7(-0.635,3.81) 8(-1.905,3.81)
  silkscreen extent -3.27,-5.33 3.27,2.93, body extent -3.37,-4.54 3.37,4.54, height 0.25
FP-430182050816_SMT_SW_6MM2_6MM2-MFG [mm]
  rrect8% 1.55x1.3 smd paste+0 mask+0: 1(-3.975,2.25) 2(-3.975,-2.25) 3(3.975,2.25) 4(3.975,-2.25)
  silkscreen extent -5.42,-3.2 3.2,3.2, body extent -4.85,-3.3 4.85,3.3, height 0.25
FP-885012106031_0603-MFG [mm]
  rrect13% 0.8x0.8 smd paste+0 mask+0: 1(-0.75,0) 2(0.75,0)
  silkscreen extent -0.9,-0.77 0.9,0.78, body extent -1.25,-0.6 1.25,0.6, height 0.25
FP-885012205018_0402-MFG [mm]
  rrect20% 0.5x0.5 smd paste+0 mask+0: 1(-0.5,0) 2(0.5,0)
  silkscreen extent -0.5,-0.63 0.5,0.63, body extent -0.85,-0.38 0.85,0.38, height 0.25
FP-ABM10W-25.0000MHZ-8-K1Z-T3_SMT4_2MM5_2MM0-MFG [mm]
  rrect12% 1.2x0.85 smd paste+0 mask+0: 1(-0.813,-0.6) 2(0.812,-0.6) 3(0.812,0.6) 4(-0.813,0.6)
  silkscreen extent -2.1,-1.42 1.3,1.43, body extent -1.51,-1.15 1.51,1.15, height 0.25
FP-BLM18EG121SN1D_0603-MFG [mm]
  rrect15% 0.65x0.7 smd paste+0 mask+0: 1(-0.675,0) 2(0.675,0)
  silkscreen extent -0.87,-0.8 0.88,0.8, body extent -1.1,-0.58 1.1,0.58, height 0.25
FP-BUK7J1R4-40HX_LFPAK56E-MFG [mm]
  rrect14% 0.7x1.15 smd paste-1000 mask+0: 1(-1.905,-3.137) 2(-0.635,-3.137) 3(0.635,-3.137) 4(1.905,-3.137)
  round 3.78 smd paste-1000 mask+0: 5(0,0.845)
  Top Layer region: -2.35,3.087 2.35,3.087 2.35,1.588 2.1,1.588 2.1,-1.512 -2.1,-1.512 -2.1,1.587 -2.35,1.587
  silkscreen extent -2.65,-4.42 2.65,-1.89, body extent -2.9,-3.81 2.9,3.19, height 0.25
FP-BUK7S0R5-40HJ_SOT1235-MFG [mm]
  rrect8% 1.2x1.4 smd paste-1000 mask-1000: 1(-3,-3.825) 2(-1,-3.825) 3(1,-3.825) 4(3,-3.825)
  round 4.95 smd paste-1000 mask-1000: 5(0,1.525)
  Top Layer region: -3.4,-1.225 3.4,-1.225 3.4,2.515 4.3,2.515 4.3,4.275 -4.3,4.275 -4.3,2.515 -3.4,2.515 -3.4,-1.225
  silkscreen extent -4.05,-5.2 4.05,-1.6, body extent -4.6,-4.83 4.6,4.57, height 0.25
FP-C0603C104J5RAC7867_0603-MFG [mm]
  rrect13% 0.75x0.9 smd paste+0 mask+0: 1(-0.6,0) 2(0.6,0)
  silkscreen extent -0.87,-0.83 0.88,0.82, body extent -0.8,-0.4 0.8,0.4, height 0.95
FP-C0603X104K5RACAUTO_0603-MFG [mm]
  rrect12% 0.85x0.9 smd paste+0 mask+0: 1(-0.65,0) 2(0.65,0)
  silkscreen extent -0.88,-0.83 0.88,0.83, body extent -0.8,-0.4 0.8,0.4, height 0.95
FP-C0603X105J9RACAUTO_0603-MFG [mm]
  rrect12% 0.85x0.9 smd paste+0 mask+0: 1(-0.65,0) 2(0.65,0)
  silkscreen extent -0.81,-0.85 0.81,0.85, body extent -1.2,-0.6 1.2,0.6, height 0.25
FP-CAT24M01WI-GT3_SOIC8-IPC_C [mil]
  rrect18% 73.78x21.39 smd paste+0 mask+0: 1(-91.18,75)
  rrect100% 73.78x21.39 smd paste+0 mask+0: 2(-91.18,25) 3(-91.18,-25) 4(-91.18,-75) 5(91.18,-75) 6(91.18,-25) 7(91.18,25) 8(91.18,75)
  silkscreen extent -153,-96 35,96, body extent -132,-100 132,100, height 10
FP-CGA3E2X7R1H333K080AA_0603-MFG [mm]
  rrect14% 0.7x0.7 smd paste+0 mask+0: 1(-0.7,0) 2(0.7,0)
  silkscreen extent -0.95,-0.73 0.95,0.73, body extent -1.15,-0.65 1.15,0.65, height 0.25
FP-CGA4J1X7R1H475K125AC_0805-MFG [mm]
  rrect13% 0.8x1.05 smd paste+0 mask+0: 1(-0.925,0) 2(0.925,0)
  silkscreen extent -0.15,-0.73 0.15,0.73, body extent -1.43,-0.82 1.42,0.82, height 0.25
FP-CL10A335KP8NNNC_0603-MFG [mm]
  rrect13% 0.76x0.85 smd paste+0 mask+0: 1(-0.72,0) 2(0.72,0)
  silkscreen extent -0.85,-0.8 0.85,0.8, body extent -1.2,-0.55 1.2,0.55, height 0.25
FP-CL10B105KB9VPJC_0603-MFG [mm]
  rrect12% 0.82x1.1 smd paste+0 mask+0: 1(-0.79,0) 2(0.79,0)
  silkscreen extent 0,-0.5 0,0.5, body extent -0.8,-0.4 0.8,0.4, height 1
FP-CSS2H-2512R-L500F_2512-MFG [mm]
  rrect6% 1.8x3.4 smd paste+0 mask+0: 1(-2.6,0) 2(2.6,0)
  silkscreen extent -1.33,-1.63 1.33,1.63, body extent -3.6,-1.8 3.6,1.8, height 0.25
FP-ERF8-013-05.0-L-DV-TR_CONN_RCPT26-MFG [mm]
  rrect20% 0.5x1.1 smd paste+0 mask+0: 1(4.8,2.25) 2(4.8,-2.25) 3(4,2.25) 4(4,-2.25) 5(3.2,2.25) 6(3.2,-2.25) 7(2.4,2.25) 8(2.4,-2.25) 9(1.6,2.25) 10(1.6,-2.25) 11(0.8,2.25) 12(0.8,-2.25) 13(0,2.25) 14(0,-2.25) 15(-0.8,2.25) 16(-0.8,-2.25) 17(-1.6,2.25) 18(-1.6,-2.25) 19(-2.4,2.25) 20(-2.4,-2.25) 21(-3.2,2.25) 22(-3.2,-2.25) 23(-4,2.25) 24(-4,-2.25) 25(-4.8,2.25) 26(-4.8,-2.25)
  round 1.45 hole 1.45 unplated paste-2539.97 mask+0: ""(-6.6,-1.5) ""(6.6,-1.5)
  silkscreen extent -8.26,-2.87 8.26,3.57, body extent -8.36,-2.97 8.36,2.97, height 0.25
FP-ERJ-2GE0R00X_0402-MFG [mm]
  rrect21% 0.475x0.5 smd paste+0 mask+0: 1(-0.512,0) 2(0.513,0)
  silkscreen extent -0.52,-0.63 0.53,0.63, body extent -0.85,-0.38 0.85,0.38, height 0.25
FP-ERJ-2GEJ152X_0402-MFG [mm]
  rrect21% 0.475x0.5 smd paste+0 mask+0: 1(-0.513,0) 2(0.512,0)
  silkscreen extent -0.53,-0.63 0.52,0.63, body extent -0.85,-0.38 0.85,0.38, height 0.25
FP-ERJ-PB3B1003V_0603-IPC_A [mil]
  rrect9% 41.62x41.82 smd paste+0 mask+0: 1(-35.45,0) 2(35.45,0)
  silkscreen extent -56,-37 56,37, body extent -76,-41 76,41, height 10
FP-GCE188R71H103KA01D_0603-MFG [mm] "0603 from SM-752 data"
  rrect15% 0.65x0.7 smd paste+0 mask+0: 1(-0.675,0) 2(0.675,0)
  silkscreen extent -1,-0.72 1,0.72, body extent -1.1,-0.55 1.1,0.55, height 0.25
FP-GCJ21B-0_3-IPC_A [mil]
  rect 61.16x61.27 smd paste+0 mask+0: 1(-36.43,0) 2(36.43,0)
  silkscreen extent -67,-46 67,46, body extent -39,-25 39,25, height 57
FP-GCJ188-0_2-IPC_C [mil]
  rect 33.67x31.97 smd paste+0 mask+0: 1(-24.63,0) 2(24.63,0)
  silkscreen extent -41,-33 41,33, body extent -45,-22 45,22, height 10
FP-GCM188-0_1-IPC_C [mil]
  rect 29.87x31.97 smd paste+0 mask+0: 1(-24.67,0) 2(24.67,0)
  silkscreen extent -40,-33 40,33, body extent -31,-16 31,16, height 35
FP-GMC31X5R476M25NT_1206-MFG [mil] "Recommended Land Pattern"
  rrect10% 40x65 smd paste+0 mask+0: 1(-60,0) 2(60,0)
  silkscreen extent -25,-35 25,35, body extent -63,-31 63,31, height 71
FP-GMC31X7R106K50NT_1206-MFG [mil]
  rrect10% 40x65 smd paste+0 mask+0: 1(-60,0) 2(60,0)
  silkscreen extent -25,-35 25,35, body extent -84,-39 84,39, height 10
FP-GRM21BR61H106KE43L_0805-MFG [mm]
  rrect14% 0.7x1.3 smd paste+0 mask+0: 1(-0.95,0) 2(0.95,0)
  silkscreen extent -0.23,-0.72 0.23,0.73, body extent -1.4,-0.82 1.4,0.82, height 0.25
FP-GRM033R61C105ME15D_0201-MFG [mm]
  rrect33% 0.3x0.35 smd paste+0 mask+0: 1(-0.282,0) 2(0.282,0)
  silkscreen extent -0.35,-0.58 0.35,0.58, body extent -0.53,-0.3 0.53,0.3, height 0.25
"FP-GRM155R61E225KE11D_0402 (1005 metric)-MFG" [mm]
  rrect22% 0.45x0.6 smd paste+0 mask+0: 1(-0.475,0) 2(0.475,0)
  silkscreen extent -0.6,-0.64 0.6,0.65, body extent -0.5,-0.25 0.5,0.25, height 0.7
FP-GRM155R71H104KE14D_0402-MFG [mm]
  rrect25% 0.4x0.5 smd paste+0 mask+0: 1(-0.4,0) 2(0.4,0)
  silkscreen extent -0.5,-0.65 0.5,0.65, body extent -0.5,-0.25 0.5,0.25, height 0.55
FP-IS25LX256-LHLE_TFBGA24-IPC_C [mm]
  round 0.34 smd paste+0 mask+0: A2(-1,2) A3(0,2) A4(1,2) A5(2,2) B1(-2,1) B2(-1,1) B3(0,1) B4(1,1) B5(2,1) C1(-2,0) C2(-1,0) C3(0,0) C4(1,0) C5(2,0) D1(-2,-1) D2(-1,-1) D3(0,-1) D4(1,-1) D5(2,-1) E1(-2,-2) E2(-1,-2) E3(0,-2) E4(1,-2) E5(2,-2)
  silkscreen extent -3.62,-4 3,4, body extent -3.1,-4.1 3.1,4.1, height 0.25
FP-NCU18WB473J6SRB_0603-MFG [mm]
  rrect15% 0.65x0.7 smd paste+0 mask+0: 1(-0.775,0) 2(0.775,0)
  silkscreen extent -0.87,-0.72 0.87,0.72, body extent -1.2,-0.58 1.2,0.58, height 0.25
"FP-PU2512FKGP60U3L_2512 (6432 Metric)-MFG" [mm]
  rrect6% 1.8x3.4 smd paste+0 mask+0: 1(-2.6,0) 2(2.6,0)
  silkscreen extent -1.33,-1.72 1.33,1.72, body extent -3.6,-1.82 3.6,1.82, height 0.25
FP-RC0402JR-0710KL_0402-MFG [mm]
  rrect20% 0.5x0.6 smd paste+0 mask+0: 1(-0.5,0) 2(0.5,0)
  silkscreen extent -0.5,-0.67 0.5,0.67, body extent -0.85,-0.4 0.85,0.4, height 0.25
FP-RMCF0201ZT0R00_0201-IPC_C [mil]
  rrect38% 13.94x10.34 smd paste+0 mask+0: 1(-10.01,0) 2(10.01,0)
  silkscreen extent -17,-22 17,22, body extent -21,-10 21,10, height 10
FP-RMCF0201ZT0R00_0201-MFG [mm]
  rrect29% 0.35x0.4 smd paste+0 mask+0: 1(-0.325,0) 2(0.325,0)
  silkscreen extent -0.32,-0.58 0.32,0.58, body extent -0.6,-0.3 0.6,0.3, height 0.25
FP-SG73S1JTTD101J_0603-MFG [mm]
  rrect20% 0.5x0.6 smd paste+0 mask+0: 1(-0.75,0) 2(0.75,0)
  silkscreen extent -0.13,-0.45 0.13,0.45, body extent -1.1,-0.55 1.1,0.55, height 0.25
"FP-SQJQ410EL-T1_GE3_PowerPAK 8x8L-MFG" [mm]
  rrect12% 1.15x0.82 smd paste+0 mask+0: 1(-3.045,-3.64) 2(-1.015,-3.64) 3(1.015,-3.64) 4(3.045,-3.64)
  round 4.13 smd paste+0 mask+0: 5(0.506,1.755)
  Top Layer region: -4,4.05 4,4.05 4,3.55 3.45,3.55 3.45,-0.44 4.125,-0.44 4.125,-1.29 3.055,-1.29 3.055,-0.54 -3.055,-0.54 -3.055,-1.29 -4.125,-1.29 -4.125,-0.44 -3.45,-0.44 -3.45,3.55 -4,3.55 -4,4.05
  silkscreen extent -4,-4.75 4,-1.67, body extent -4.23,-4.15 4.23,4.15, height 0.25
FP-TSM-108-01-L-DV-008-P-TR_HDR15-MFG [mm]
  rrect8% 1.27x3.68 smd paste+0 mask+0: 1(-8.89,-2.475) 2(-8.89,2.475) 3(-6.35,-2.475) 4(-6.35,2.475) 5(-3.81,-2.475) 6(-3.81,2.475) 7(-1.27,-2.475) 9(1.27,-2.475) 10(1.27,2.475) 11(3.81,-2.475) 12(3.81,2.475) 13(6.35,-2.475) 14(6.35,2.475) 15(8.89,-2.475) 16(8.89,2.475)
  silkscreen extent -10.16,-5 10.16,2.61, body extent -10.26,-4.42 10.26,4.42, height 0.25
FP-VMP-1R00-1.0-U_2010-MFG [mm]
  rrect8% 1.25x3 smd paste+0 mask+0: 1(-2.375,0) 2(2.375,0)
  silkscreen extent -1.38,-1.37 1.37,1.37, body extent -3.1,-1.6 3.1,1.6, height 0.25
FP-WSL3921L5000FEA_3921-MFG [mm]
  rrect4% 2.7x6.2 smd paste+0 mask+0: 1(-4.15,0) 2(4.15,0)
  silkscreen extent -2.42,-2.79 2.42,2.79, body extent -5.6,-3.2 5.6,3.2, height 0.25
FP-WSLF25121L000FEB_2512-MFG [mm]
  rrect6% 1.8x3.4 smd paste+0 mask+0: 1(-2.6,0) 2(2.6,0)
  silkscreen extent -1.33,-1.61 1.33,1.61, body extent -3.6,-1.8 3.6,1.8, height 0.25
FP-XGL4030-102MEC_SMD_IND_4MM0_4MM0-MFG [mm]
  rrect10% 0.98x3.4 smd paste+0 mask+0: 1(-1.185,0) 2(1.185,0)
  silkscreen extent -2.15,-2.15 2.15,2.15, body extent -2.25,-2.25 2.25,2.25, height 0.25
"Harting_09 65 162 6810" [mm] "Harting"
  rrect7% 1.45x1.45 hole 1 paste-2539.97: 1(-5.48,11.7)
  round 1.45 hole 1 paste-2539.97: 2(-2.74,11.7) 3(0,11.7) 4(2.74,11.7) 5(5.48,11.7) 6(-4.11,9.16) 7(-1.37,9.16) 8(1.37,9.16) 9(4.11,9.16)
  round 3.7 hole 3.1 paste-2539.97: 10(-12.5,10.43) 11(12.5,10.43)
  silkscreen extent -15.6,0.38 15.6,14.3, body extent -15.6,-7.27 15.6,13.73, height 13.61
HEATSINK-DKQ56_20MMX41_4X32_77MM [mm] "Heat Sink for DKQ Packages, 41.4x20 mm"
  round 6 hole 3: 2(0,-16.25) C(0,16.25)
  silkscreen extent -10,-20.7 10,20.7, body extent -10,-20.7 10,20.7, height 32.77
IEC_HotSurface_Medium [mil]
  silkscreen extent -217,-188 217,188
KCM55W [mm] "MuRata"
  rect 2.7x5.6 smd: 1(-2.65,0) 2(2.65,0)
  silkscreen extent -1.05,-2.8 1,2.8, body extent -3.25,-2.75 3.25,2.75, height 6.7
Keystone5010 [mil] "Keystone Multipurpose loops"
  round 87 hole 63: 1(0,0)
  silkscreen extent -70,-70 70,70, body extent -63,-63 63,62, height 319
Keystone5011 [mil] "Keystone Multipurpose loops"
  round 87 hole 63: 1(0,0)
  silkscreen extent -70,-70 70,70, body extent -63,-63 63,62, height 319
Keystone_1902C [mil] "Hex Standoff, 4-40 threaded, nylon"
  round 1 on Mech4: 0(0,0)
  body extent -145,-126 146,126, height 501
Label_650x200 [mil] "Thermal Transfer Label"
  round 1 on Mech13: 0(0,0)
  silkscreen extent -325,-100 325,100, body extent -325,-100 325,100, height 1
LTST-C193_Blue [mm] "SMD, 2-Leads, Body1.6x0.8mm"
  rect 0.8x0.8 smd: 1(-0.75,0) 2(0.75,0)
  silkscreen extent -1.2,-0.9 1.85,0.9, body extent -0.85,-0.45 0.85,0.45, height 0.45
Net-Tie_20milWide_60milLong [mil] "20mil net tie, no solder mask opening, no solder paste"
  rect 60x20 smd paste-10 mask-10: 1(-30,0) 2(30,0)
"NY PMS 440 0025 PH" [mm] "4-40 nylon screw and mounting hole"
  round 8 hole 3.2: 1(0,0)
  body extent -3.3,-3.3 3.3,3.3, height 2.69
Panasonic_SMT_800x1020 [mm] "SMD, 2-Leads, Dia 8mm"
  rect 4x2 smd: 1(-3.55,0) 2(3.55,0)
  silkscreen extent -4.25,-4.25 4.25,4.25, body extent -4.25,-4.25 4.25,4.25, height 10.51
Panduit_CXS70-14-C [mil] "Panduit"
  rect 770x500 hole 270 copper offset -74.8,0 paste-99999: 1(0,0)
  body extent -960,-250 310,250, height 684
Phoenix_1715048 [mm] "Terminal Block, 5mm, 4x1, TH"
  rect 1.8x1.8 hole 1.3: 1(-7.5,-0.3)
  round 1.8 hole 1.3: 2(-2.5,-0.3) 3(2.5,-0.3) 4(7.5,-0.3)
  silkscreen extent -10.74,-4.9 10,4.9, body extent -10.74,-4.9 10,4.9, height 14.3
Phoenix_1715080 [mm] "Terminal Block, 5mm, 8 Pos, TH"
  rect 1.8x1.8 hole 1.3: 1(-17.5,0)
  round 1.8 hole 1.3: 2(-12.5,0) 3(-7.5,0) 4(-2.5,0) 5(2.5,0) 6(7.5,0) 7(12.5,0) 8(17.5,0)
  silkscreen extent -20.74,-4.6 20,5.2, body extent -20.74,-4.6 20,5.2, height 13.8
Phoenix_1902547 [mm] "TH, 2-Leads, Body 19.04x16mm, Pitch 9.52mm"
  rect 1.8x1.8 hole 1.3: 1(-4.76,3.1)
  round 1.8 hole 1.3: 2(4.76,3.1)
  silkscreen extent -10,-8 10.09,8, body extent -9.52,-8 10.09,8, height 22
PhoenixContact_1715721 [mm] "Phoenix Contact 1715721 used on LM3445 design from Longmont"
  rrect5% 1.905x1.905 hole 1.3: 1(-2.54,0)
  round 1.9 hole 1.3: 2(2.54,0)
  silkscreen extent -5.82,-5.25 5.08,5.2, body extent -5.82,-4.6 5.08,5.2, height 14.2
PW0016A-MFG [mm]
  rrect22% 1.5x0.45 smd paste+0 mask+0: 1(-2.9,2.275) 2(-2.9,1.625) 3(-2.9,0.975) 4(-2.9,0.325) 5(-2.9,-0.325) 6(-2.9,-0.975) 7(-2.9,-1.625) 8(-2.9,-2.275) 9(2.9,-2.275) 10(2.9,-1.625) 11(2.9,-0.975) 12(2.9,-0.325) 13(2.9,0.325) 14(2.9,0.975) 15(2.9,1.625) 16(2.9,2.275)
  silkscreen extent -4.32,-2.55 1.78,2.55, body extent -3.75,-2.8 3.75,2.8, height 0.25
PW0024A-MFG [mm]
  rrect22% 1.5x0.45 smd paste+0 mask+0: 1(-2.9,3.575) 2(-2.9,2.925) 3(-2.9,2.275) 4(-2.9,1.625) 5(-2.9,0.975) 6(-2.9,0.325) 7(-2.9,-0.325) 8(-2.9,-0.975) 9(-2.9,-1.625) 10(-2.9,-2.275) 11(-2.9,-2.925) 12(-2.9,-3.575) 13(2.9,-3.575) 14(2.9,-2.925) 15(2.9,-2.275) 16(2.9,-1.625) 17(2.9,-0.975) 18(2.9,-0.325) 19(2.9,0.325) 20(2.9,0.975) 21(2.9,1.625) 22(2.9,2.275) 23(2.9,2.925) 24(2.9,3.575)
  silkscreen extent -4.38,-3.95 1.78,3.95, body extent -3.75,-4.2 3.75,4.2, height 0.25
PWC0018A-MFG [mm] "Recommended Land Pattern"
  rrect22% 1.5x0.45 smd paste+0 mask+0: 1(-2.9,3.575) 2(-2.9,2.275) 3(-2.9,1.625) 4(-2.9,0.975) 5(-2.9,0.325) 6(-2.9,-0.325) 7(-2.9,-1.625) 8(-2.9,-2.275) 9(-2.9,-3.575) 10(2.9,-3.575) 11(2.9,-2.275) 12(2.9,-1.625) 13(2.9,-0.325) 14(2.9,0.325) 15(2.9,0.975) 16(2.9,1.625) 17(2.9,2.275) 18(2.9,3.575)
  rrect3% 3.4x7.8 smd paste-1000 mask-1000: 19(0,0)
  silkscreen extent -3.02,-4.28 2.25,4.47, body extent -3.75,-4.2 3.75,4.2, height 0.25
PWP0014C-MFG [mm]
  rrect33% 1.6x0.3 smd paste-1000 mask+0: 1(-2.8,1.95) 2(-2.8,1.3) 3(-2.8,0.65) 4(-2.8,0) 5(-2.8,-0.65) 6(-2.8,-1.3) 7(-2.8,-1.95) 8(2.8,-1.95) 9(2.8,-1.3) 10(2.8,-0.65) 11(2.8,0) 12(2.8,0.65) 13(2.8,1.3) 14(2.8,1.95)
  rrect3% 3.4x5 smd paste-1000 mask-1000: 15(0,0)
  silkscreen extent -4.27,-2.7 2.4,2.7, body extent -3.7,-2.8 3.7,2.8, height 0.25
PWP0016P-MFG [mm]
  rrect22% 1.5x0.45 smd paste+0 mask+0: 1(-2.9,2.275) 2(-2.9,1.625) 3(-2.9,0.975) 4(-2.9,0.325) 5(-2.9,-0.325) 6(-2.9,-0.975) 7(-2.9,-1.625) 8(-2.9,-2.275) 9(2.9,-2.275) 10(2.9,-1.625) 11(2.9,-0.975) 12(2.9,-0.325) 13(2.9,0.325) 14(2.9,0.975) 15(2.9,1.625) 16(2.9,2.275)
  rrect3% 3.4x5 smd paste-1000 mask-1000: 17(0,0)
  silkscreen extent -4.35,-2.95 2.25,2.95, body extent -3.75,-2.8 3.75,2.8, height 0.25
PWP0024T-MFG [mm]
  rrect22% 1.5x0.45 smd paste+0 mask+0: 1(-2.9,3.575) 2(-2.9,2.925) 3(-2.9,2.275) 4(-2.9,1.625) 5(-2.9,0.975) 6(-2.9,0.325) 7(-2.9,-0.325) 8(-2.9,-0.975) 9(-2.9,-1.625) 10(-2.9,-2.275) 11(-2.9,-2.925) 12(-2.9,-3.575) 13(2.9,-3.575) 14(2.9,-2.925) 15(2.9,-2.275) 16(2.9,-1.625) 17(2.9,-0.975) 18(2.9,-0.325) 19(2.9,0.325) 20(2.9,0.975) 21(2.9,1.625) 22(2.9,2.275) 23(2.9,2.925) 24(2.9,3.575)
  rrect3% 3.4x7.8 smd paste-1000 mask-1000: 25(0,0)
  silkscreen extent -4.33,-4.28 2.22,4.28, body extent -3.75,-4.2 3.75,4.2, height 0.25
RESC1005X40X25LL05T05 [mm] "Chip Resistor, 2-Leads, Body 1.05x0.55mm, IPC High Density"
  rect 0.45x0.45 smd: 1(-0.4,0) 2(0.4,0)
  body extent -0.53,-0.28 0.53,0.28, height 0.4
RGE0023A-MFG [mm]
  rrect40% 0.6x0.25 smd paste+0 mask+0: 1(-1.9,1.25) 2(-1.9,0.75) 3(-1.9,0.25) 4(-1.9,-0.25) 5(-1.9,-0.75) 6(-1.9,-1.25) 13(1.9,-1.25) 14(1.9,-0.75) 15(1.9,-0.25) 16(1.9,0.25) 18(1.9,1.25)
  rrect40% 0.25x0.6 smd paste+0 mask+0: 7(-1.25,-1.9) 8(-0.75,-1.9) 9(-0.25,-1.9) 10(0.25,-1.9) 11(0.75,-1.9) 12(1.25,-1.9) 19(1.25,1.9) 20(0.75,1.9) 21(0.25,1.9) 22(-0.25,1.9) 23(-0.75,1.9) 24(-1.25,1.9)
  rrect5% 1.9x1.9 smd paste-1000 mask+0: 25(0,0)
  silkscreen extent -2.87,-2.05 2.05,2.05, body extent -2.3,-2.3 2.3,2.3, height 0.25
RGE0024T-MFG [mm]
  rrect40% 0.6x0.25 smd paste+0 mask+0: 1(-1.9,1.25) 2(-1.9,0.75) 3(-1.9,0.25) 4(-1.9,-0.25) 5(-1.9,-0.75) 6(-1.9,-1.25) 13(1.9,-1.25) 14(1.9,-0.75) 15(1.9,-0.25) 16(1.9,0.25) 17(1.9,0.75) 18(1.9,1.25)
  rrect40% 0.25x0.6 smd paste+0 mask+0: 7(-1.25,-1.9) 8(-0.75,-1.9) 9(-0.25,-1.9) 10(0.25,-1.9) 11(0.75,-1.9) 12(1.25,-1.9) 19(1.25,1.9) 20(0.75,1.9) 21(0.25,1.9) 22(-0.25,1.9) 23(-0.75,1.9) 24(-1.25,1.9)
  rrect5% 2.1x2.1 smd paste-1000 mask+0: 25(0,0)
  silkscreen extent -2.9,-2.05 2.05,2.05, body extent -2.3,-2.3 2.3,2.3, height 0.25
RGY0024C [mm] "VQFN-24"
  rrect42% 0.24x0.6 smd: 1(-0.75,2.65) 12(-0.75,-2.65) 13(0.75,-2.65) 24(0.75,2.65)
  rrect42% 0.6x0.24 smd: 2(-1.65,2.25) 3(-1.65,1.75) 4(-1.65,1.25) 5(-1.65,0.75) 6(-1.65,0.25) 7(-1.65,-0.25) 8(-1.65,-0.75) 9(-1.65,-1.25) 10(-1.65,-1.75) 11(-1.65,-2.25) 14(1.65,-2.25) 15(1.65,-1.75) 16(1.65,-1.25) 17(1.65,-0.75) 18(1.65,-0.25) 19(1.65,0.25) 20(1.65,0.75) 21(1.65,1.25) 22(1.65,1.75) 23(1.65,2.25)
  rrect5% 2.1x4.1 smd paste-1.2: 25(0,0)
  body extent -1.75,-2.75 1.75,2.75, height 1
RTW0024B-MFG [mm]
  rrect42% 0.6x0.24 smd paste+0 mask+0: 1(-1.9,1.25) 2(-1.9,0.75) 3(-1.9,0.25) 4(-1.9,-0.25) 5(-1.9,-0.75) 6(-1.9,-1.25) 13(1.9,-1.25) 14(1.9,-0.75) 15(1.9,-0.25) 16(1.9,0.25) 17(1.9,0.75) 18(1.9,1.25)
  rrect42% 0.24x0.6 smd paste+0 mask+0: 7(-1.25,-1.9) 8(-0.75,-1.9) 9(-0.25,-1.9) 10(0.25,-1.9) 11(0.75,-1.9) 12(1.25,-1.9) 19(1.25,1.9) 20(0.75,1.9) 21(0.25,1.9) 22(-0.25,1.9) 23(-0.75,1.9) 24(-1.25,1.9)
  rrect4% 2.45x2.45 smd paste-1000 mask+0: 25(0,0)
  silkscreen extent -2.9,-2.05 2.05,2.05, body extent -2,-2 2,2, height 0.8
RVJ0056A [mm] "QFN, 56-Leads, Body 8.00x8.00mm, Pitch 0.50mm, Thermal Pad 5.20x5.20mm"
  rrect100% 0.6x0.24 smd: 1(-3.9,3.25) 2(-3.9,2.75) 3(-3.9,2.25) 4(-3.9,1.75) 5(-3.9,1.25) 6(-3.9,0.75) 7(-3.9,0.25) 8(-3.9,-0.25) 9(-3.9,-0.75) 10(-3.9,-1.25) 11(-3.9,-1.75) 12(-3.9,-2.25) 13(-3.9,-2.75) 14(-3.9,-3.25) 29(3.9,-3.25) 30(3.9,-2.75) 31(3.9,-2.25) 32(3.9,-1.75) 33(3.9,-1.25) 34(3.9,-0.75) 35(3.9,-0.25) 36(3.9,0.25) 37(3.9,0.75) 38(3.9,1.25) 39(3.9,1.75) 40(3.9,2.25) 41(3.9,2.75) 42(3.9,3.25)
  rrect100% 0.24x0.6 smd: 15(-3.25,-3.9) 16(-2.75,-3.9) 17(-2.25,-3.9) 18(-1.75,-3.9) 19(-1.25,-3.9) 20(-0.75,-3.9) 21(-0.25,-3.9) 22(0.25,-3.9) 23(0.75,-3.9) 24(1.25,-3.9) 25(1.75,-3.9) 26(2.25,-3.9) 27(2.75,-3.9) 28(3.25,-3.9) 43(3.25,3.9) 44(2.75,3.9) 45(2.25,3.9) 46(1.75,3.9) 47(1.25,3.9) 48(0.75,3.9) 49(0.25,3.9) 50(-0.25,3.9) 51(-0.75,3.9) 52(-1.25,3.9) 53(-1.75,3.9) 54(-2.25,3.9) 55(-2.75,3.9) 56(-3.25,3.9)
  rrect2% 5.2x5.2 smd paste-5: 57(0,0)
  silkscreen extent -4.23,-4.23 4.22,4.23, body extent -4.08,-4.07 4.07,4.08, height 1.02
RXZ0016A-MFG [mm]
  rrect40% 0.65x0.25 smd paste+0 mask+0: 1(-1.625,2.375) 2(-1.625,1.875) 3(-1.625,1.375) 10(1.625,1.375) 11(1.625,1.875) 12(1.625,2.375)
  rrect40% 4x0.5 smd paste-1000 mask-1000: 4(0,0.7)
  rrect40% 1.925x0.5 smd paste-1000 mask-1000: 5(-1.038,-0.2) 6(-1.038,-1) 8(1.038,-1) 9(1.038,-0.2)
  rrect15% 4x1.35 smd paste-1000 mask-1000: 7(0,-2.325)
  rrect40% 0.25x0.65 smd paste+0 mask+0: 13(0.75,2.625) 14(0.25,2.625) 15(-0.25,2.625) 16(-0.75,2.625)
  silkscreen extent -2.62,-3.32 1.8,3.33, body extent -2.1,-3.1 2.1,3.05, height 0.25
RYT0009A-MFG [mm]
  rrect40% 0.875x0.25 smd paste+0 mask+0: 1(-0.763,0.25) 2(-0.763,-0.25) 5(0.763,-0.25) 6(0.763,0.25)
  round 0.255 smd paste+0 mask+0: 3(-0.509,-0.828)
  round 0.278 smd paste+0 mask+0: 4(0.488,-0.787)
  round 0.26 smd paste+0 mask+0: 7(0.537,0.787)
  rrect40% 0.25x0.65 smd paste+0 mask+0: 8(0,0.95)
  round 0.242 smd paste+0 mask+0: 9(-0.509,0.828)
  Top Layer region: -1.2,0.825 -1.193,0.85 -1.175,0.868 -1.15,0.875 -1.15,0.875 -0.675,0.875 -0.656,0.879 -0.64,0.89 -0.629,0.906 -0.625,0.925 -0.625,0.925 -0.625,1.225 -0.618,1.25 -0.6,1.268 -0.575,1.275 -0.575,1.275 -0.425,1.275 -0.406,1.271 -0.39,1.26 -0.379,1.244 -0.375,1.225 -0.375,1.225 -0.375,0.675 -0.379,0.656 -0.39,0.64 -0.406,0.629 -0.425,0.625 -0.425,0.625 -1.15,0.625 -1.169,0.629 -1.185,0.64 -1.196,0.656 -1.2,0.675 -1.2,0.675
  Top Layer region: 1.2,0.825 1.193,0.85 1.175,0.868 1.15,0.875 1.15,0.875 0.675,0.875 0.656,0.879 0.64,0.89 0.629,0.906 0.625,0.925 0.625,0.925 0.625,1.225 0.618,1.25 0.6,1.268 0.575,1.275 0.575,1.275 0.425,1.275 0.406,1.271 0.39,1.26 0.379,1.244 0.375,1.225 0.375,1.225 0.375,0.675 0.379,0.656 0.39,0.64 0.406,0.629 0.425,0.625 0.425,0.625 1.15,0.625 1.169,0.629 1.185,0.64 1.196,0.656 1.2,0.675 1.2,0.675
  Top Layer region: -1.2,-0.825 -1.193,-0.85 -1.175,-0.868 -1.15,-0.875 -1.15,-0.875 -0.675,-0.875 -0.656,-0.879 -0.64,-0.89 -0.629,-0.906 -0.625,-0.925 -0.625,-0.925 -0.625,-1.225 -0.618,-1.25 -0.6,-1.268 -0.575,-1.275 -0.575,-1.275 -0.425,-1.275 -0.406,-1.271 -0.39,-1.26 -0.379,-1.244 -0.375,-1.225 -0.375,-1.225 -0.375,-0.912 -0.368,-0.887 -0.35,-0.868 -0.35,-0.868 -0.337,-0.857 -0.328,-0.842 -0.325,-0.825 -0.325,-0.825 -0.325,-0.675 -0.329,-0.656 -0.34,-0.64 -0.356,-0.629 -0.375,-0.625 -0.375,-0.625 -1.15,-0.625 -1.169,-0.629 -1.185,-0.64 -1.196,-0.656 -1.2,-0.675 -1.2,-0.675
  Top Layer region: 1.2,-0.825 1.193,-0.85 1.175,-0.868 1.15,-0.875 1.15,-0.875 0.675,-0.875 0.656,-0.879 0.64,-0.89 0.629,-0.906 0.625,-0.925 0.625,-0.925 0.625,-1.225 0.618,-1.25 0.6,-1.268 0.575,-1.275 0.575,-1.275 0.425,-1.275 0.406,-1.271 0.39,-1.26 0.379,-1.244 0.375,-1.225 0.375,-1.225 0.375,-0.912 0.372,-0.894 0.363,-0.879 0.35,-0.868 0.35,-0.868 0.337,-0.857 0.328,-0.842 0.325,-0.825 0.325,-0.825 0.325,-0.675 0.329,-0.656 0.34,-0.64 0.356,-0.629 0.375,-0.625 0.375,-0.625 1.15,-0.625 1.169,-0.629 1.185,-0.64 1.196,-0.656 1.2,-0.675 1.2,-0.675
  silkscreen extent -1.92,-1.68 1.05,1.68, body extent -1.3,-1.38 1.3,1.38, height 0.25
Samtec_ERF8-025-05_0-x-DV-L [mm] "Receptacle, 0.8mm, 25x2, SMT"
  rect 1.1x0.5 smd: 1(-2.25,9.6) 2(2.25,9.6) 3(-2.25,8.8) 4(2.25,8.8) 5(-2.25,8) 6(2.25,8) 7(-2.25,7.2) 8(2.25,7.2) 9(-2.25,6.4) 10(2.25,6.4) 11(-2.25,5.6) 12(2.25,5.6) 13(-2.25,4.8) 14(2.25,4.8) 15(-2.25,4) 16(2.25,4) 17(-2.25,3.2) 18(2.25,3.2) 19(-2.25,2.4) 20(2.25,2.4) 21(-2.25,1.6) 22(2.25,1.6) 23(-2.25,0.8) 24(2.25,0.8) 25(-2.25,0) 26(2.25,0) 27(-2.25,-0.8) 28(2.25,-0.8) 29(-2.25,-1.6) 30(2.25,-1.6) 31(-2.25,-2.4) 32(2.25,-2.4) 33(-2.25,-3.2) 34(2.25,-3.2) 35(-2.25,-4) 36(2.25,-4) 37(-2.25,-4.8) 38(2.25,-4.8) 39(-2.25,-5.6) 40(2.25,-5.6) 41(-2.25,-6.4) 42(2.25,-6.4) 43(-2.25,-7.2) 44(2.25,-7.2) 45(-2.25,-8) 46(2.25,-8) 47(-2.25,-8.8) 48(2.25,-8.8) 49(-2.25,-9.6) 50(2.25,-9.6)
  round 1.45 hole 0.83: MH1(0,12.9) MH2(0,-12.9)
  round 1 hole 1.45 unplated: MH3(1.5,11.4) MH4(1.5,-11.4)
  silkscreen extent -3.2,-13.75 2.8,13.75, body extent -2.8,-13.75 2.8,13.75, height 5.34
Samtec_TSW-105-07-x-D [mm] "Header, 2.54mm, 5x2, TH"
  rect 1.55x1.55 hole 1.02: 1(-1.27,5.08)
  round 1.55 hole 1.02: 2(1.27,5.08) 3(-1.27,2.54) 4(1.27,2.54) 5(-1.27,0) 6(1.27,0) 7(-1.27,-2.54) 8(1.27,-2.54) 9(-1.27,-5.08) 10(1.27,-5.08)
  silkscreen extent -3,-6.35 2.54,6.35, body extent -2.54,-6.35 2.54,6.35, height 8.39
SM_RADIAL_10BMM [mm] "Nichicon 10x10"
  rect 4x2.5 smd: 1(-4,0) 2(4,0)
  silkscreen extent -5.25,-5.25 5.25,5.25, body extent -5.25,-5.25 5.25,5.25, height 10.5
SM_RADIAL_E [mm] "8 x 6.2mm:  Panasonic E"
  rect 4x1.6 smd: 1(-3.1,0) 2(3.1,0)
  silkscreen extent -4.25,-4.25 4.25,4.25, body extent -4.25,-4.25 4.25,4.25, height 6.5
SM_RADIAL_G [mm] "10 x 10.2mm:  Panasonic G"
  rect 4.1x2 smd: 1(-4.35,0) 2(4.35,0)
  silkscreen extent -5.35,-5.35 5.35,5.35, body extent -5.25,-5.25 5.25,5.25, height 10.5
SMB [mil] "Molded Diode, 2-Leads, Body 5.4x3.6mm, IPC Medium Density, based on OnSemi component dimensions"
  rect 85x107.99 smd: 1(-87.01,0) 2(87.01,0)
  silkscreen extent -155,-82 125,82, body extent -106,-71 106,71, height 91
SOD-123 [mm] "On Semi recommended land pattern"
  rect 0.915x1.22 smd: 1(-1.637,0) 2(1.637,0)
  silkscreen extent -2.74,-1.17 2.03,1.17, body extent -1.93,-0.9 1.93,0.9, height 1.35
SOD-323 [mm] "NXP recommended land pattern"
  rect 0.6x0.6 smd paste-0.05: 1(-1.1,0) 2(1.1,0)
  silkscreen extent -2.06,-0.86 1.53,0.86, body extent -1.3,-0.67 1.3,0.68, height 1.1
SOD-523 [mm] "NXP Semiconductor recommended land pattern, nominal STEP model"
  rect 0.8x0.6 smd paste-0.05: 1(-0.55,0) 2(0.55,0)
  silkscreen extent -1.65,-0.66 1.2,0.66, body extent -0.8,-0.4 0.8,0.4, height 0.72
SOT-23 [mm] "SOT23, 3-Leads, Body 2.9x1.3mm, Pitch 0.95mm, Lead Span 2.5mm, IPC Medium Density"
  rrect50% 1x0.6 smd: 1(-1.2,0.95) 2(-1.2,-0.95) 3(1.2,0)
  silkscreen extent -1.62,-1.5 0.7,1.5, body extent -1.16,-1.45 1.21,1.45, height 1
SOT-23L [mm] "SOT23, 3-Leads, Body 2.9x1.3mm, Pitch 0.95mm, Lead Span 2.5mm, IPC High Density"
  rrect50% 0.8x0.6 smd: 1(-1.1,0.95) 2(-1.1,-0.95) 3(1.1,0)
  silkscreen extent -1.5,-1.5 0.7,1.5, body extent -1.16,-1.45 1.21,1.45, height 1
SOT-323 [mm] "Diodes Inc recommended land pattern.  2016-02-24"
  rrect21% 0.6x0.47 smd: 1(-0.95,0.65) 2(-0.95,-0.65) 3(0.95,0)
  silkscreen extent -1.14,-1.22 0.78,1.22, body extent -1.13,-1.13 1.12,1.12, height 1.13
SOT-416 [mm] "NXP recommended footprint."
  rect 0.6x0.5 smd: 1(-0.65,0.5) 2(-0.65,-0.5) 3(0.65,0)
  silkscreen extent -0.13,-0.9 0.5,0.9, body extent -0.8,-0.9 0.8,0.9, height 0.82
SW_CAS-D20TA [mm] "SMD, 6-Leads, Body 5.4x3.9mm, Pitch 1.75mm"
  rect 1.6x1 smd: 1(-1.85,1.75) 2(-1.85,0) 3(-1.85,-1.75) 4(1.85,1.75) 5(1.85,0) 6(1.85,-1.75)
  silkscreen extent -1.95,-2.7 1.95,2.9, body extent -2.1,-2.7 2.1,2.7, height 2.5
TE_5650478-5 [mm] "Header, 2.54mml, 16x3, TH"
  rect 1.5x1.5 hole 0.99: A1(-19.05,-5.31)
  round 1.5 hole 0.99: A2(-16.51,-5.31) A3(-13.97,-5.31) A4(-11.43,-5.31) A5(-8.89,-5.31) A6(-6.35,-5.31) A7(-3.81,-5.31) A8(-1.27,-5.31) A9(1.27,-5.31) A10(3.81,-5.31) A11(6.35,-5.31) A12(8.89,-5.31) A13(11.43,-5.31) A14(13.97,-5.31) A15(16.51,-5.31) A16(19.05,-5.31) B1(-19.05,-7.85) B2(-16.51,-7.85) B3(-13.97,-7.85) B4(-11.43,-7.85) B5(-8.89,-7.85) B6(-6.35,-7.85) B7(-3.81,-7.85) B8(-1.27,-7.85) B9(1.27,-7.85) B10(3.81,-7.85) B11(6.35,-7.85) B12(8.89,-7.85) B13(11.43,-7.85) B14(13.97,-7.85) B15(16.51,-7.85) B16(19.05,-7.85) C1(-19.05,-10.39) C2(-16.51,-10.39) C3(-13.97,-10.39) C4(-11.43,-10.39) C5(-8.89,-10.39) C6(-6.35,-10.39) C7(-3.81,-10.39) C8(-1.27,-10.39) C9(1.27,-10.39) C10(3.81,-10.39) C11(6.35,-10.39) C12(8.89,-10.39) C13(11.43,-10.39) C14(13.97,-10.39) C15(16.51,-10.39) C16(19.05,-10.39)
  round 2.79 hole 2.79 unplated mask+0: MH1(-24.13,-2.77) MH2(24.13,-2.77)
  silkscreen extent -26.61,-5.31 26.61,-1, body extent -26.61,-10.68 26.6,7.34, height 9.46
TFM201610ALMA [mm] "TDK"
  rrect17% 0.6x1.6 smd: 1(-0.9,0) 2(0.9,0)
  body extent -1.1,-0.9 1.1,0.9, height 1
TI_Stacked_Overlay_Small [mil]
  silkscreen extent -418,-98 418,98
TNPW0603 [mm] "Vishay"
  rect 0.5x0.9 smd: 1(-0.75,0) 2(0.75,0)
  silkscreen extent -0.2,-0.6 0.2,0.6, body extent -0.85,-0.47 0.85,0.47, height 0.55
TP_25MIL-SMT [mil]
  round 25 smd mask-2.5: 1(0,0)
TSW-103-07-G-S [mm] "Samtec 100mil, 1x3, 230 mil above insulator"
  rrect50% 1.65x1.65 hole 1.016: 1(-2.54,0)
  round 1.65 hole 1.016: 2(0,0) 3(2.54,0)
  body extent -3.81,-1.27 3.81,1.27, height 8.38
TSW-104-07-G-S [mm] "Samtec 100mil, 1x4, 230 mil above insulator"
  rrect50% 1.65x1.65 hole 1.016: 1(-3.81,0)
  round 1.65 hole 1.016: 2(-1.27,0) 3(1.27,0) 4(3.81,0)
  body extent -5.08,-1.27 5.08,1.27, height 8.38
TSW-105-07-X-S [mm] "Samtec 100mil, 1x5, 230 mil above insulator"
  rrect6% 1.65x1.65 hole 1.016: 1(-5.08,-0.025)
  round 1.65 hole 1.016: 2(-2.54,0) 3(0,0) 4(2.54,0) 5(5.08,0)
  silkscreen extent -7.05,-1.25 6.37,1.25, body extent -6.35,-1.27 6.35,1.27, height 8.38
TSW-106-07-G-S [mm] "Samtec 100mil, 1x6, 230 mil above insulator"
  rrect50% 1.65x1.65 hole 1.016: 1(-6.35,0)
  round 1.65 hole 1.016: 2(-3.81,0) 3(-1.27,0) 4(1.27,0) 5(3.81,0) 6(6.35,0)
  body extent -7.62,-1.27 7.62,1.27, height 8.38
TSW-107-07-X-D [mm] "Samtec 100mil, 2x7, 230 mil above insulator"
  rrect6% 1.65x1.65 hole 1.016: 1(-7.62,-1.27)
  round 1.65 hole 1.016: 2(-7.62,1.27) 3(-5.08,-1.27) 4(-5.08,1.27) 5(-2.54,-1.27) 6(-2.54,1.27) 7(0,-1.27) 8(0,1.27) 9(2.54,-1.27) 10(2.54,1.27) 11(5.08,-1.27) 12(5.08,1.27) 13(7.62,-1.27) 14(7.62,1.27)
  silkscreen extent -9.91,-2.52 9.14,2.5, body extent -8.89,-2.54 8.89,2.54, height 8.38
TSW-108-07-G-S [mm] "Samtec 100mil, 1x8, 230 mil above insulator"
  rrect6% 1.65x1.65 hole 1.016: 1(-8.89,0)
  round 1.65 hole 1.016: 2(-6.35,0) 3(-3.81,0) 4(-1.27,0) 5(1.27,0) 6(3.81,0) 7(6.35,0) 8(8.89,0)
  silkscreen extent -10.16,-1.27 10.16,1.65, body extent -10.16,-1.27 10.16,1.27, height 8.38
TSW-110-07-G-S [mm] "Samtec 100mil, 1x10, 230 mil above insulator"
  rrect6% 1.65x1.65 hole 1.016: 1(-11.43,0)
  round 1.65 hole 1.016: 2(-8.89,0) 3(-6.35,0) 4(-3.81,0) 5(-1.27,0) 6(1.27,0) 7(3.81,0) 8(6.35,0) 9(8.89,0) 10(11.43,0)
  silkscreen extent -12.7,-1.27 12.7,1.65, body extent -12.7,-1.27 12.7,1.27, height 8.38
VAH0011B-MFG [mm] "Recommended Land Pattern"
  round 0.469 smd paste+0 mask+0: 1(-0.698,1.397)
  round 0.765 smd paste-1000 mask+0: 2(0,0.449)
  rrect33% 0.6x0.3 smd paste+0 mask+0: 3(-1,-0.376) 4(-1,-0.926) 9(1,-0.926) 10(1,-0.376)
  round 0.281 smd paste+0 mask+0: 5(-0.831,-1.532) 8(0.831,-1.532)
  rrect33% 0.3x0.6 smd paste+0 mask+0: 6(-0.275,-1.701) 7(0.275,-1.701)
  round 0.47 smd paste+0 mask+0: 11(0.398,1.397)
  Top Layer region: -1.25,1.124 -1.269,1.128 -1.285,1.139 -1.296,1.155 -1.3,1.174 -1.3,1.174 -1.3,1.374 -1.293,1.399 -1.275,1.417 -1.25,1.424 -1.25,1.424 -1.025,1.424 -1.006,1.428 -0.99,1.439 -0.979,1.455 -0.975,1.474 -0.975,1.474 -0.975,1.949 -0.968,1.974 -0.95,1.992 -0.925,1.999 -0.925,1.999 -0.725,1.999 -0.706,1.995 -0.69,1.984 -0.679,1.968 -0.675,1.949 -0.675,1.949 -0.675,1.699 -0.671,1.68 -0.66,1.664 -0.644,1.653 -0.625,1.649 -0.625,1.649 -0.475,1.649 -0.456,1.653 -0.44,1.664 -0.429,1.68 -0.425,1.699 -0.425,1.699 -0.425,1.949 -0.418,1.974 -0.4,1.992 -0.375,1.999 -0.375,1.999 -0.175,1.999 -0.156,1.995 -0.14,1.984 -0.129,1.968 -0.125,1.949 -0.125,1.949 -0.125,1.174 -0.129,1.155 -0.14,1.139 -0.156,1.128 -0.175,1.124 -0.175,1.124
  Top Layer region: 1.25,1.124 1.269,1.128 1.285,1.139 1.296,1.155 1.3,1.174 1.3,1.174 1.3,1.374 1.296,1.393 1.285,1.409 1.269,1.42 1.25,1.424 1.25,1.424 1.025,1.424 1.006,1.428 0.99,1.439 0.979,1.455 0.975,1.474 0.975,1.474 0.975,1.949 0.971,1.968 0.96,1.984 0.944,1.995 0.925,1.999 0.925,1.999 0.725,1.999 0.706,1.995 0.69,1.984 0.679,1.968 0.675,1.949 0.675,1.949 0.675,1.699 0.671,1.68 0.66,1.664 0.644,1.653 0.625,1.649 0.625,1.649 0.475,1.649 0.456,1.653 0.44,1.664 0.429,1.68 0.425,1.699 0.425,1.699 0.425,1.949 0.421,1.968 0.41,1.984 0.394,1.995 0.375,1.999 0.375,1.999 0.175,1.999 0.156,1.995 0.14,1.984 0.129,1.968 0.125,1.949 0.125,1.949 0.125,1.174 0.129,1.155 0.14,1.139 0.156,1.128 0.175,1.124 0.175,1.124
  Top Layer region: -1.3,0.824 -1.293,0.849 -1.275,0.867 -1.25,0.874 -1.25,0.874 1.25,0.874 1.275,0.867 1.293,0.849 1.3,0.824 1.3,0.824 1.3,0.624 1.296,0.605 1.285,0.589 1.269,0.578 1.25,0.574 1.25,0.574 1,0.574 0.975,0.567 0.957,0.549 0.95,0.524 0.95,0.524 0.95,0.374 0.954,0.355 0.965,0.339 0.981,0.328 1,0.324 1,0.324 1.25,0.324 1.275,0.317 1.293,0.299 1.3,0.274 1.3,0.274 1.3,0.074 1.296,0.055 1.285,0.039 1.269,0.028 1.25,0.024 1.25,0.024 -1.25,0.024 -1.269,0.028 -1.285,0.039 -1.296,0.055 -1.3,0.074 -1.3,0.074 -1.3,0.274 -1.293,0.299 -1.275,0.317 -1.25,0.324 -1.25,0.324 -1,0.324 -0.981,0.328 -0.965,0.339 -0.954,0.355 -0.95,0.374 -0.95,0.374 -0.95,0.524 -0.957,0.549 -0.975,0.567 -1,0.574 -1,0.574 -1.25,0.574 -1.269,0.578 -1.285,0.589 -1.296,0.605 -1.3,0.624 -1.3,0.624
  Top Layer region: -0.675,-1.951 -0.682,-1.976 -0.7,-1.994 -0.725,-2.001 -0.725,-2.001 -0.925,-2.001 -0.95,-1.994 -0.968,-1.976 -0.975,-1.951 -0.975,-1.951 -0.975,-1.676 -0.979,-1.657 -0.99,-1.641 -1.006,-1.63 -1.025,-1.626 -1.025,-1.626 -1.25,-1.626 -1.275,-1.619 -1.293,-1.601 -1.3,-1.576 -1.3,-1.576 -1.3,-1.376 -1.296,-1.357 -1.285,-1.341 -1.269,-1.33 -1.25,-1.326 -1.25,-1.326 -0.725,-1.326 -0.706,-1.33 -0.69,-1.341 -0.679,-1.357 -0.675,-1.376 -0.675,-1.376
  Top Layer region: 0.675,-1.951 0.679,-1.97 0.69,-1.986 0.706,-1.997 0.725,-2.001 0.725,-2.001 0.925,-2.001 0.944,-1.997 0.96,-1.986 0.971,-1.97 0.975,-1.951 0.975,-1.951 0.975,-1.676 0.982,-1.651 1,-1.633 1.025,-1.626 1.025,-1.626 1.25,-1.626 1.275,-1.619 1.293,-1.601 1.3,-1.576 1.3,-1.576 1.3,-1.376 1.293,-1.351 1.275,-1.333 1.25,-1.326 1.25,-1.326 0.725,-1.326 0.706,-1.33 0.69,-1.341 0.679,-1.357 0.675,-1.376 0.675,-1.376
  silkscreen extent -1.97,-2.22 1.53,2.22, body extent -1.1,-1.8 1.1,1.8, height 1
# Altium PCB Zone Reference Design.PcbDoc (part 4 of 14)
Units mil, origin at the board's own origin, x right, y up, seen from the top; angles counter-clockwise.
Board outline 8858.11 x 7047.08 mil, 16 copper layers (Top Layer, GND_1, SIG_1, GND_2, PWR/SIG_1, GND_3, PWR_1, PWR_2, GND_4, PWR/SIG_2, GND_5, SIG_2, GND_6, SIG_3, GND_7, Bottom Layer), stack 80.368 mil thick; 1131 components, 808 nets, 3825 pads, 3523 vias.
Unrouted connection lines stored in the file: 563.

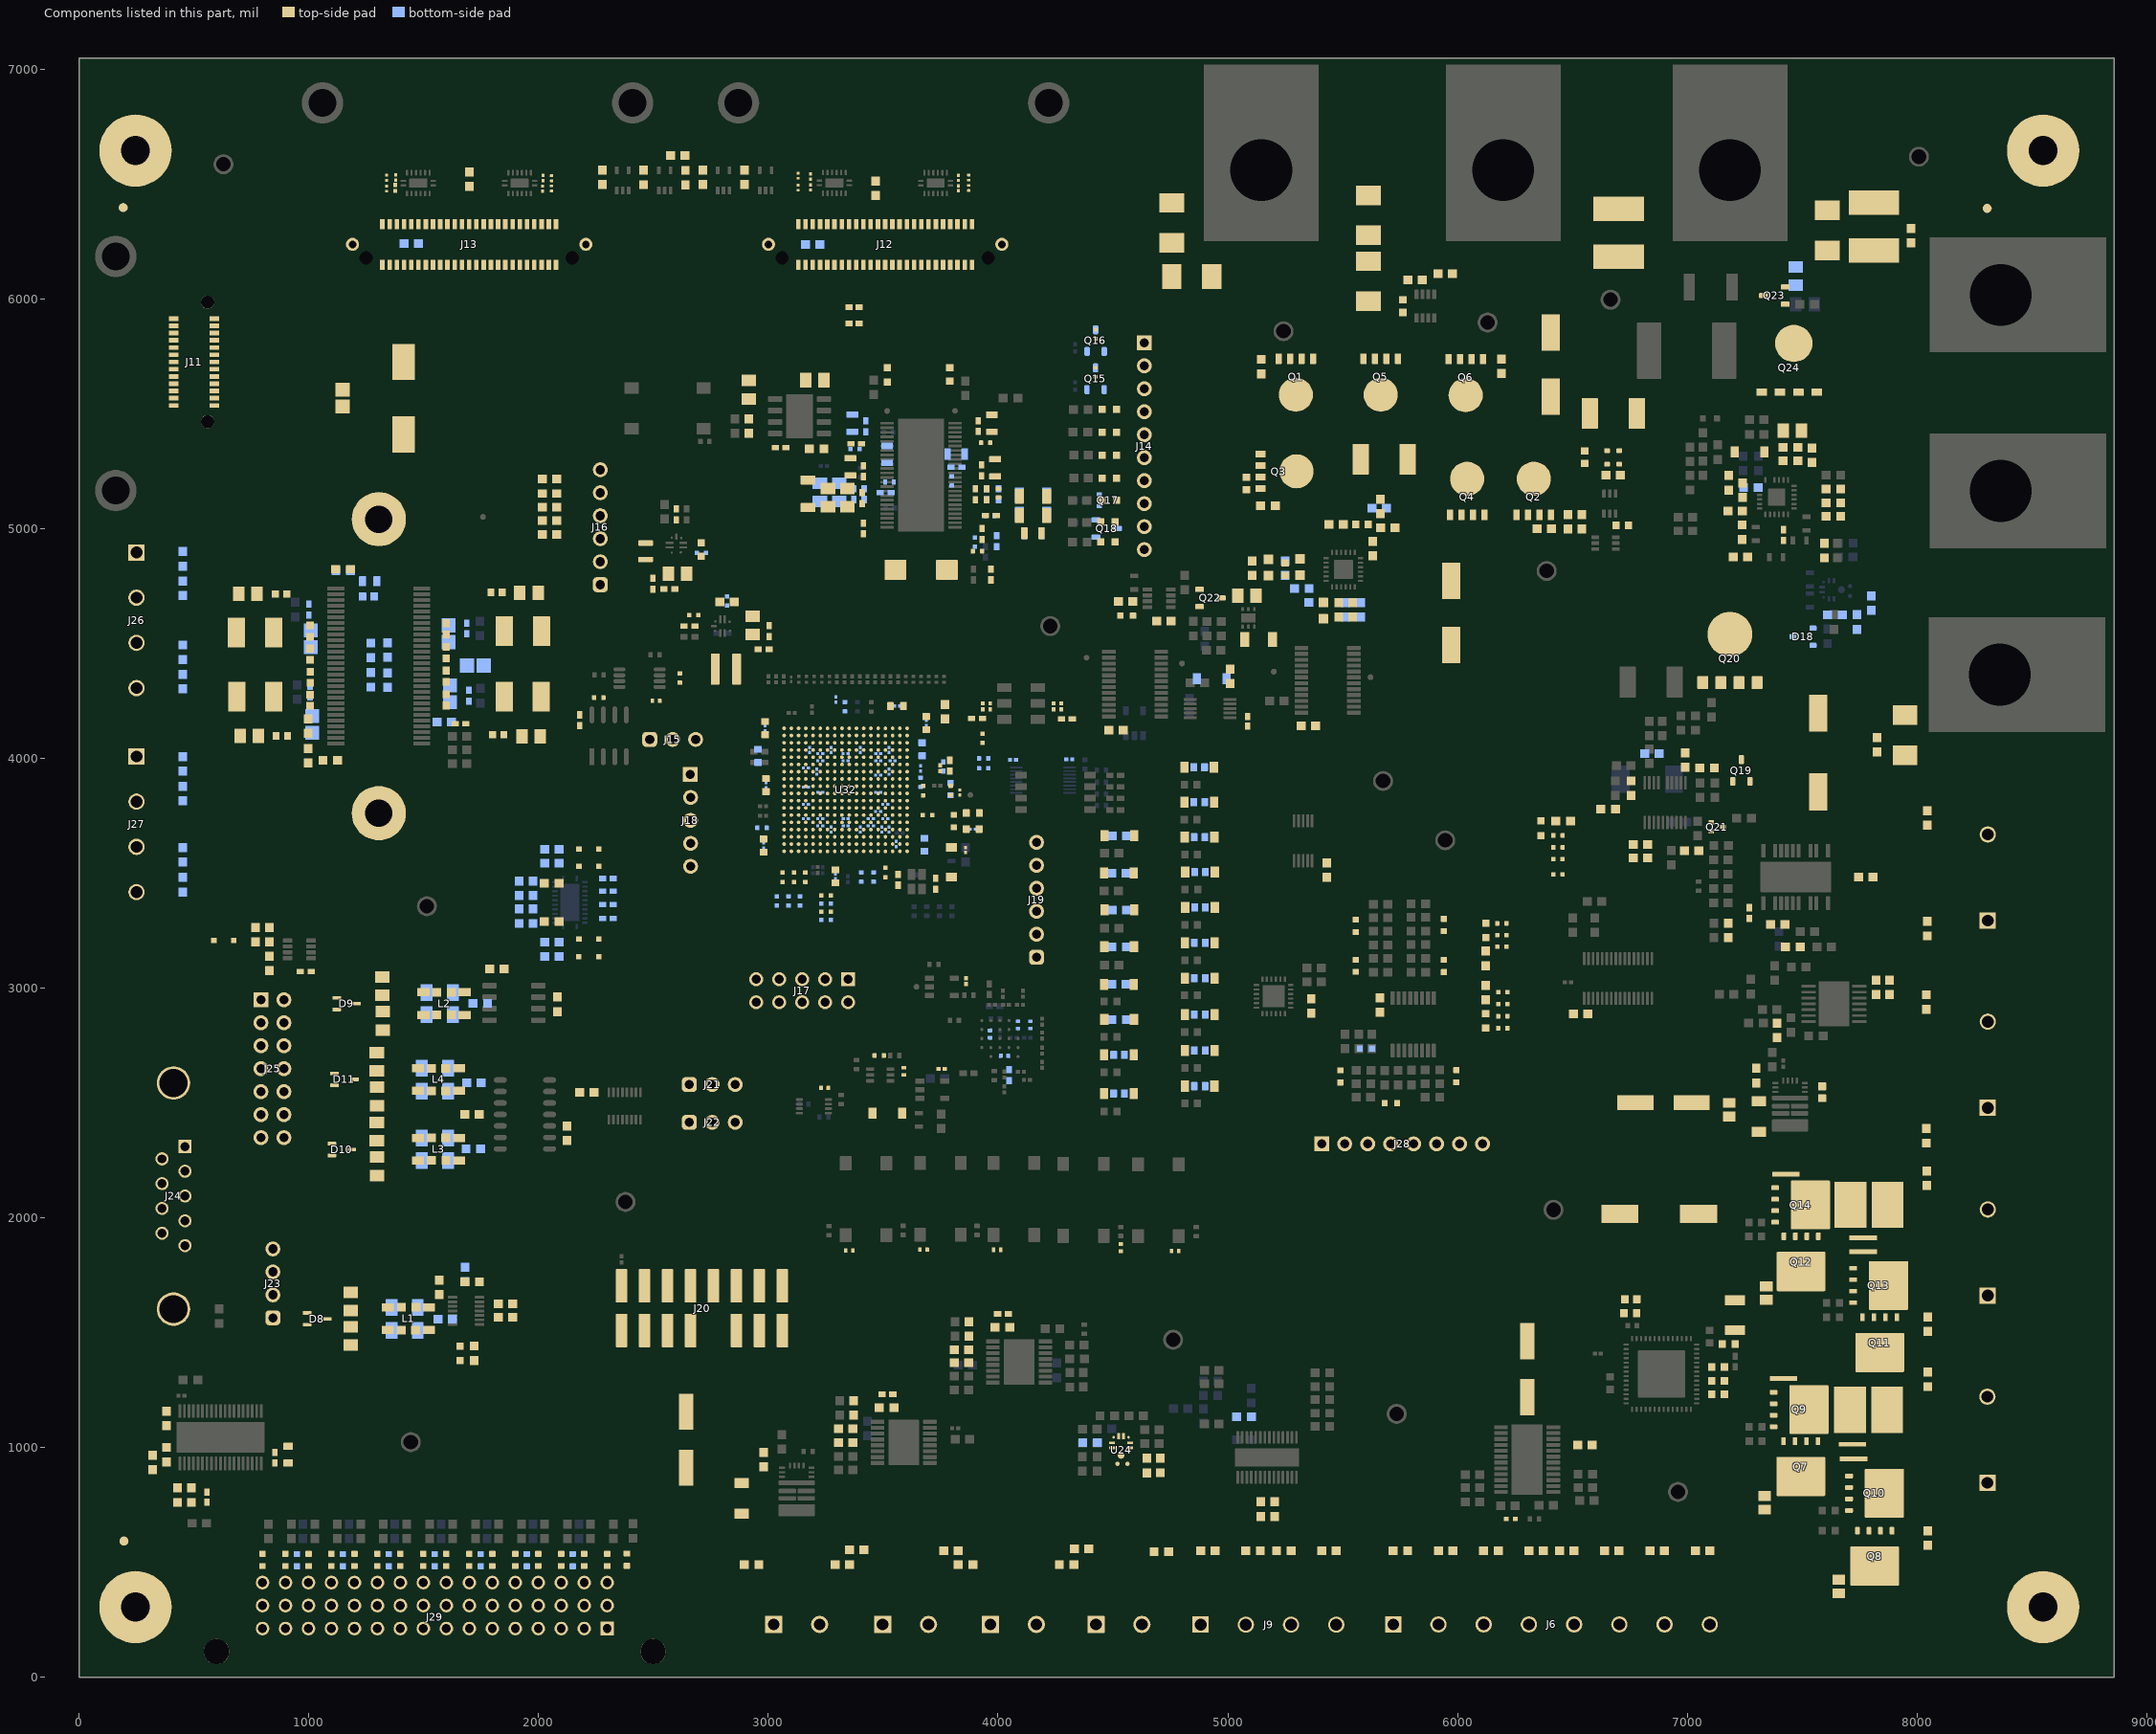
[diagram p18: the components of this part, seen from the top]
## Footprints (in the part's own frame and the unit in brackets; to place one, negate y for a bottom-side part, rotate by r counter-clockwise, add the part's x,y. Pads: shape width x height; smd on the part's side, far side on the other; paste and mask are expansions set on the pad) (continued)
VAH0011C-MFG [mm]
  round 0.469 smd paste+0 mask+0: 1(-0.698,1.397)
  round 0.765 smd paste-1000 mask+0: 2(0,0.449)
  rrect33% 0.7x0.3 smd paste+0 mask+0: 3(-0.95,-0.376) 10(0.95,-0.376)
  rrect33% 0.6x0.3 smd paste+0 mask+0: 4(-1,-0.926) 9(1,-0.926)
  round 0.281 smd paste+0 mask+0: 5(-0.831,-1.532) 8(0.831,-1.532)
  rrect33% 0.3x0.7 smd paste+0 mask+0: 6(-0.275,-1.651) 7(0.275,-1.651)
  round 0.47 smd paste+0 mask+0: 11(0.398,1.397)
  Top Layer region: 0.675,-1.951 0.679,-1.97 0.69,-1.986 0.706,-1.997 0.725,-2.001 0.725,-2.001 0.925,-2.001 0.944,-1.997 0.96,-1.986 0.971,-1.97 0.975,-1.951 0.975,-1.951 0.975,-1.676 0.982,-1.651 1,-1.633 1.025,-1.626 1.025,-1.626 1.25,-1.626 1.275,-1.619 1.293,-1.601 1.3,-1.576 1.3,-1.576 1.3,-1.376 1.293,-1.351 1.275,-1.333 1.25,-1.326 1.25,-1.326 0.725,-1.326 0.706,-1.33 0.69,-1.341 0.679,-1.357 0.675,-1.376 0.675,-1.376
  Top Layer region: -0.675,-1.951 -0.682,-1.976 -0.7,-1.994 -0.725,-2.001 -0.725,-2.001 -0.925,-2.001 -0.95,-1.994 -0.968,-1.976 -0.975,-1.951 -0.975,-1.951 -0.975,-1.676 -0.979,-1.657 -0.99,-1.641 -1.006,-1.63 -1.025,-1.626 -1.025,-1.626 -1.25,-1.626 -1.275,-1.619 -1.293,-1.601 -1.3,-1.576 -1.3,-1.576 -1.3,-1.376 -1.296,-1.357 -1.285,-1.341 -1.269,-1.33 -1.25,-1.326 -1.25,-1.326 -0.725,-1.326 -0.706,-1.33 -0.69,-1.341 -0.679,-1.357 -0.675,-1.376 -0.675,-1.376
  Top Layer region: -1.3,0.824 -1.293,0.849 -1.275,0.867 -1.25,0.874 -1.25,0.874 1.25,0.874 1.275,0.867 1.293,0.849 1.3,0.824 1.3,0.824 1.3,0.624 1.296,0.605 1.285,0.589 1.269,0.578 1.25,0.574 1.25,0.574 1,0.574 0.975,0.567 0.957,0.549 0.95,0.524 0.95,0.524 0.95,0.374 0.954,0.355 0.965,0.339 0.981,0.328 1,0.324 1,0.324 1.25,0.324 1.275,0.317 1.293,0.299 1.3,0.274 1.3,0.274 1.3,0.074 1.296,0.055 1.285,0.039 1.269,0.028 1.25,0.024 1.25,0.024 -1.25,0.024 -1.269,0.028 -1.285,0.039 -1.296,0.055 -1.3,0.074 -1.3,0.074 -1.3,0.274 -1.293,0.299 -1.275,0.317 -1.25,0.324 -1.25,0.324 -1,0.324 -0.981,0.328 -0.965,0.339 -0.954,0.355 -0.95,0.374 -0.95,0.374 -0.95,0.524 -0.957,0.549 -0.975,0.567 -1,0.574 -1,0.574 -1.25,0.574 -1.269,0.578 -1.285,0.589 -1.296,0.605 -1.3,0.624 -1.3,0.624
  Top Layer region: 1.25,1.124 1.269,1.128 1.285,1.139 1.296,1.155 1.3,1.174 1.3,1.174 1.3,1.374 1.296,1.393 1.285,1.409 1.269,1.42 1.25,1.424 1.25,1.424 1.025,1.424 1.006,1.428 0.99,1.439 0.979,1.455 0.975,1.474 0.975,1.474 0.975,1.949 0.971,1.968 0.96,1.984 0.944,1.995 0.925,1.999 0.925,1.999 0.725,1.999 0.706,1.995 0.69,1.984 0.679,1.968 0.675,1.949 0.675,1.949 0.675,1.699 0.671,1.68 0.66,1.664 0.644,1.653 0.625,1.649 0.625,1.649 0.475,1.649 0.456,1.653 0.44,1.664 0.429,1.68 0.425,1.699 0.425,1.699 0.425,1.949 0.421,1.968 0.41,1.984 0.394,1.995 0.375,1.999 0.375,1.999 0.175,1.999 0.156,1.995 0.14,1.984 0.129,1.968 0.125,1.949 0.125,1.949 0.125,1.174 0.129,1.155 0.14,1.139 0.156,1.128 0.175,1.124 0.175,1.124
  Top Layer region: -1.25,1.124 -1.269,1.128 -1.285,1.139 -1.296,1.155 -1.3,1.174 -1.3,1.174 -1.3,1.374 -1.293,1.399 -1.275,1.417 -1.25,1.424 -1.25,1.424 -1.025,1.424 -1.006,1.428 -0.99,1.439 -0.979,1.455 -0.975,1.474 -0.975,1.474 -0.975,1.949 -0.968,1.974 -0.95,1.992 -0.925,1.999 -0.925,1.999 -0.725,1.999 -0.706,1.995 -0.69,1.984 -0.679,1.968 -0.675,1.949 -0.675,1.949 -0.675,1.699 -0.671,1.68 -0.66,1.664 -0.644,1.653 -0.625,1.649 -0.625,1.649 -0.475,1.649 -0.456,1.653 -0.44,1.664 -0.429,1.68 -0.425,1.699 -0.425,1.699 -0.425,1.949 -0.418,1.974 -0.4,1.992 -0.375,1.999 -0.375,1.999 -0.175,1.999 -0.156,1.995 -0.14,1.984 -0.129,1.968 -0.125,1.949 -0.125,1.949 -0.125,1.174 -0.129,1.155 -0.14,1.139 -0.156,1.128 -0.175,1.124 -0.175,1.124
  silkscreen extent -1.97,-2.22 1.53,2.22, body extent -1.4,-2.1 1.4,2.1, height 0.25
VCMT053T [mm] "CYNTEC"
  rrect5% 1.9x3.3 smd: 1(-2.05,0) 2(2.05,0)
  silkscreen extent -2.8,-2.85 2.8,2.85, body extent -2.9,-2.72 2.9,2.72, height 3.02
WEEE_Minimum [mil] "WEEElie bin"
  silkscreen extent -95,-172 99,104
WL-SMCW_GREEN [mm] "WURTH"
  rect 0.8x0.8 smd: 1(-0.8,0) 2(0.8,0)
  silkscreen extent -1.9,-0.8 1.2,0.8, body extent -0.85,-0.45 0.85,0.45, height 0.8
WL-SMCW_RED [mm] "WURTH"
  rect 0.8x0.8 smd: 1(-0.8,0) 2(0.8,0)
  silkscreen extent -1.9,-0.8 1.2,0.8, body extent -0.85,-0.45 0.85,0.45, height 0.8
WL-SMCW_YELLOW [mm] "WURTH"
  rect 0.8x0.8 smd: 1(-0.8,0) 2(0.8,0)
  silkscreen extent -1.9,-0.8 1.2,0.8, body extent -0.85,-0.45 0.85,0.45, height 0.8
WSHM2818 [mm] "SMD, 2-Leads, Body 7.1x4.6mm"
  rect 3.5x5.1 smd: 1(-2.055,0) 2(2.055,0)
  body extent -3.55,-2.3 3.55,2.3, height 1.5
ZCZ0324A-MFG [mm]
  round 0.4 smd paste+0 mask+0.05: A1(-6.8,6.8) A2(-6,6.8) A3(-5.2,6.8) A4(-4.4,6.8) A5(-3.6,6.8) A6(-2.8,6.8) A7(-2,6.8) A8(-1.2,6.8) A9(-0.4,6.8) A10(0.4,6.8) A11(1.2,6.8) A12(2,6.8) A13(2.8,6.8) A14(3.6,6.8) A15(4.4,6.8) A16(5.2,6.8) A17(6,6.8) A18(6.8,6.8) B1(-6.8,6) B2(-6,6) B3(-5.2,6) B4(-4.4,6) B5(-3.6,6) B6(-2.8,6) B7(-2,6) B8(-1.2,6) B9(-0.4,6) B10(0.4,6) B11(1.2,6) B12(2,6) B13(2.8,6) B14(3.6,6) B15(4.4,6) B16(5.2,6) B17(6,6) B18(6.8,6) C1(-6.8,5.2) C2(-6,5.2) C3(-5.2,5.2) C4(-4.4,5.2) C5(-3.6,5.2) C6(-2.8,5.2) C7(-2,5.2) C8(-1.2,5.2) C9(-0.4,5.2) C10(0.4,5.2) C11(1.2,5.2) C12(2,5.2) C13(2.8,5.2) C14(3.6,5.2) C15(4.4,5.2) C16(5.2,5.2) C17(6,5.2) C18(6.8,5.2) D1(-6.8,4.4) D2(-6,4.4) D3(-5.2,4.4) D4(-4.4,4.4) D5(-3.6,4.4) D6(-2.8,4.4) D7(-2,4.4) D8(-1.2,4.4) D9(-0.4,4.4) D10(0.4,4.4) D11(1.2,4.4) D12(2,4.4) D13(2.8,4.4) D14(3.6,4.4) D15(4.4,4.4) D16(5.2,4.4) D17(6,4.4) D18(6.8,4.4) E1(-6.8,3.6) E2(-6,3.6) E3(-5.2,3.6) E4(-4.4,3.6) E5(-3.6,3.6) E6(-2.8,3.6) E7(-2,3.6) E8(-1.2,3.6) E9(-0.4,3.6) E10(0.4,3.6) E11(1.2,3.6) E12(2,3.6) E13(2.8,3.6) E14(3.6,3.6) E15(4.4,3.6) E16(5.2,3.6) E17(6,3.6) E18(6.8,3.6) F1(-6.8,2.8) F2(-6,2.8) F3(-5.2,2.8) F4(-4.4,2.8) F5(-3.6,2.8) F6(-2.8,2.8) F7(-2,2.8) F8(-1.2,2.8) F9(-0.4,2.8) F10(0.4,2.8) F11(1.2,2.8) F12(2,2.8) F13(2.8,2.8) F14(3.6,2.8) F15(4.4,2.8) F16(5.2,2.8) F17(6,2.8) F18(6.8,2.8) G1(-6.8,2) G2(-6,2) G3(-5.2,2) G4(-4.4,2) G5(-3.6,2) G6(-2.8,2) G7(-2,2) G8(-1.2,2) G9(-0.4,2) G10(0.4,2) G11(1.2,2) G12(2,2) G13(2.8,2) G14(3.6,2) G15(4.4,2) G16(5.2,2) G17(6,2) G18(6.8,2) H1(-6.8,1.2) H2(-6,1.2) H3(-5.2,1.2) H4(-4.4,1.2) H5(-3.6,1.2) H6(-2.8,1.2) H7(-2,1.2) H8(-1.2,1.2) H9(-0.4,1.2) H10(0.4,1.2) H11(1.2,1.2) H12(2,1.2) H13(2.8,1.2) H14(3.6,1.2) H15(4.4,1.2) H16(5.2,1.2) H17(6,1.2) H18(6.8,1.2) J1(-6.8,0.4) J2(-6,0.4) J3(-5.2,0.4) J4(-4.4,0.4) J5(-3.6,0.4) J6(-2.8,0.4) J7(-2,0.4) J8(-1.2,0.4) J9(-0.4,0.4) J10(0.4,0.4) J11(1.2,0.4) J12(2,0.4) J13(2.8,0.4) J14(3.6,0.4) J15(4.4,0.4) J16(5.2,0.4) J17(6,0.4) J18(6.8,0.4) K1(-6.8,-0.4) K2(-6,-0.4) K3(-5.2,-0.4) K4(-4.4,-0.4) K5(-3.6,-0.4) K6(-2.8,-0.4) K7(-2,-0.4) K8(-1.2,-0.4) K9(-0.4,-0.4) K10(0.4,-0.4) K11(1.2,-0.4) K12(2,-0.4) K13(2.8,-0.4) K14(3.6,-0.4) K15(4.4,-0.4) K16(5.2,-0.4) K17(6,-0.4) K18(6.8,-0.4) L1(-6.8,-1.2) L2(-6,-1.2) L3(-5.2,-1.2) L4(-4.4,-1.2) L5(-3.6,-1.2) L6(-2.8,-1.2) L7(-2,-1.2) L8(-1.2,-1.2) L9(-0.4,-1.2) L10(0.4,-1.2) L11(1.2,-1.2) L12(2,-1.2) L13(2.8,-1.2) L14(3.6,-1.2) L15(4.4,-1.2) L16(5.2,-1.2) L17(6,-1.2) L18(6.8,-1.2) M1(-6.8,-2) M2(-6,-2) M3(-5.2,-2) M4(-4.4,-2) M5(-3.6,-2) M6(-2.8,-2) M7(-2,-2) M8(-1.2,-2) M9(-0.4,-2) M10(0.4,-2) M11(1.2,-2) M12(2,-2) M13(2.8,-2) M14(3.6,-2) M15(4.4,-2) M16(5.2,-2) M17(6,-2) M18(6.8,-2) N1(-6.8,-2.8) N2(-6,-2.8) N3(-5.2,-2.8) N4(-4.4,-2.8) N5(-3.6,-2.8) N6(-2.8,-2.8) N7(-2,-2.8) N8(-1.2,-2.8) N9(-0.4,-2.8) N10(0.4,-2.8) N11(1.2,-2.8) N12(2,-2.8) N13(2.8,-2.8) N14(3.6,-2.8) N15(4.4,-2.8) N16(5.2,-2.8) N17(6,-2.8) N18(6.8,-2.8) P1(-6.8,-3.6) P2(-6,-3.6) P3(-5.2,-3.6) P4(-4.4,-3.6) P5(-3.6,-3.6) P6(-2.8,-3.6) P7(-2,-3.6) P8(-1.2,-3.6) P9(-0.4,-3.6) P10(0.4,-3.6) P11(1.2,-3.6) P12(2,-3.6) P13(2.8,-3.6) P14(3.6,-3.6) P15(4.4,-3.6) P16(5.2,-3.6) P17(6,-3.6) P18(6.8,-3.6) R1(-6.8,-4.4) R2(-6,-4.4) R3(-5.2,-4.4) R4(-4.4,-4.4) R5(-3.6,-4.4) R6(-2.8,-4.4) R7(-2,-4.4) R8(-1.2,-4.4) R9(-0.4,-4.4) R10(0.4,-4.4) R11(1.2,-4.4) R12(2,-4.4) R13(2.8,-4.4) R14(3.6,-4.4) R15(4.4,-4.4) R16(5.2,-4.4) R17(6,-4.4) R18(6.8,-4.4) T1(-6.8,-5.2) T2(-6,-5.2) T3(-5.2,-5.2) T4(-4.4,-5.2) T5(-3.6,-5.2) T6(-2.8,-5.2) T7(-2,-5.2) T8(-1.2,-5.2) T9(-0.4,-5.2) T10(0.4,-5.2) T11(1.2,-5.2) T12(2,-5.2) T13(2.8,-5.2) T14(3.6,-5.2) T15(4.4,-5.2) T16(5.2,-5.2) T17(6,-5.2) T18(6.8,-5.2) U1(-6.8,-6) U2(-6,-6) U3(-5.2,-6) U4(-4.4,-6) U5(-3.6,-6) U6(-2.8,-6) U7(-2,-6) U8(-1.2,-6) U9(-0.4,-6) U10(0.4,-6) U11(1.2,-6) U12(2,-6) U13(2.8,-6) U14(3.6,-6) U15(4.4,-6) U16(5.2,-6) U17(6,-6) U18(6.8,-6) V1(-6.8,-6.8) V2(-6,-6.8) V3(-5.2,-6.8) V4(-4.4,-6.8) V5(-3.6,-6.8) V6(-2.8,-6.8) V7(-2,-6.8) V8(-1.2,-6.8) V9(-0.4,-6.8) V10(0.4,-6.8) V11(1.2,-6.8) V12(2,-6.8) V13(2.8,-6.8) V14(3.6,-6.8) V15(4.4,-6.8) V16(5.2,-6.8) V17(6,-6.8) V18(6.8,-6.8)
  silkscreen extent -8.15,-7.55 7.55,7.55, body extent -8.05,-8.05 8.05,8.05, height 0.25

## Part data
C1 C5 C13: library part CMP-0006850-4, "CAP, CERM, 0.01 uF, 50 V, +/- 5%, X7R, 0603", Cap_Case=0603, Manufacturer=Kemet, Supplier Part Number 1=399-1092-1-ND, TempCo=X7R, Tolerance_%=5%, Value1=Unknown, Value2=50V, ValueDisplayed=0.01uF
C2 C7 C8 C11 C12 C16: library part CMP-0084736-1, "CAP, CERM, 0.1 µF, 50 V,+/- 10%, X7R, AEC-Q200 Grade 0, 0603", Cap_Case=0603, Manufacturer=AVX, TempCo=X7R, Tolerance_%=10%, Value2=50V, ValueDisplayed=0.1µF
C3 C14: library part CMP-0077295-1, "CAP, AL, 100 µF, 50 V, +/- 20%, 0.18 ohm, AEC-Q200 Grade 2, SMD", Cap_Case=8x10.2mm, Manufacturer=Panasonic, Supplier Part Number 1=P19726CT-ND, Tolerance_%=20%, Value1="0.18 ohm", Value2=50V, ValueDisplayed=100µF
C4 C15: library part CMP-0007353-5, "CAP, CERM, 2.2 uF, 50 V, +/- 10%, X5R, 0603", Cap_Case=0603, Manufacturer=MuRata, Supplier Part Number 1=490-10733-1-ND, TempCo=X5R, Tolerance_%=10%, Value1=Unknown, Value2=50V, ValueDisplayed=2.2uF
C6: library part CMP-0007145-4, "CAP, CERM, 0.22 uF, 50 V, +/- 10%, X7R, AEC-Q200 Grade 1, 0603", Cap_Case=0603, Manufacturer=MuRata, Supplier Part Number 1=490-5402-1-ND, TempCo=X7R, Tolerance_%=10%, Value1=Unknown, Value2=50V, ValueDisplayed=0.22uF
C9: library part CMP-0006922-4, "CAP, CERM, 3300 pF, 50 V, +/- 10%, X7R, 0603", Cap_Case=0603, Manufacturer=Kemet, Supplier Part Number 1=399-1086-1-ND, TempCo=X7R, Tolerance_%=10%, Value1=Unknown, Value2=50V, ValueDisplayed=3300pF
C10 C17 C18 C19 C23 C24 C28 C30 C33 C46 C48 C49 C78 C80 C83 C84 C88 C90 C92 C95 C104 C107 C110 C111 C308 C309 C358 C361 C368 C405: library part CMP-0079095-1, "CAP, CERM, 0.1 µF, 50 V,+/- 10%, X7R, AEC-Q200 Grade 1, 0603", Cap_Case=0603, Manufacturer=AVX, Supplier Part Number 1=478-3540-1-ND, TempCo=X7R, Tolerance_%=10%, Value2=50V, ValueDisplayed=0.1µF
C20 C25 C29 C34: library part CMP-0006943-2, "CAP, CERM, 4700 pF, 50 V, +/- 10%, X7R, 0603", Cap_Case=0603, Manufacturer=Kemet, Supplier Part Number 1=399-1087-1-ND, TempCo=X7R, Tolerance_%=10%, Value1=Unknown, Value2=50V, ValueDisplayed=4700pF
C21 C22 C26 C27 C31 C32 C35 C36: library part CMP-0007523-1, "CAP, CERM, 20 pF, 100 V, +/- 5%, C0G/NP0, 0805", Cap_Case=0805, Manufacturer=AVX, Supplier Part Number 1=478-3735-1-ND, TempCo=C0G/NP0, Tolerance_%=5%, Value1="0.92 ohm", Value2=100V, ValueDisplayed=20pF
C47 C50 C51 C52 C53: library part CMP-0860329-1, "CAP, CERM, 220 pF, 50 V,+/- 5%, X7R, 0603", Cap_Case=0603, Manufacturer="Samsung Electro-Mechanics", TempCo=X7R, Tolerance_%=5%, Value2=50V, ValueDisplayed=220pF
C54 C55 C56 C57 C391 C393: library part CMP-0081011-1, "CAP, CERM, 0.1 µF, 100 V,+/- 10%, X7R, AEC-Q200 Grade 1, 0603", Cap_Case=0603, Manufacturer="Taiyo Yuden", Supplier Part Number 1=587-6009-1-ND, TempCo=X7R, Tolerance_%=10%, Value2=100V, ValueDisplayed=0.1µF
C58 C64 C71: library part CMP-0007050-1, "CAP, CERM, 0.47 uF, 50 V, +/- 10%, X7R, 0603", Cap_Case=0603, Manufacturer=TDK, Supplier Part Number 1=445-5952-1-ND, TempCo=X7R, Tolerance_%=10%, Value1="0.010974 ohm", Value2=50V, ValueDisplayed=0.47uF
C59 C62 C65 C68 C70 C72 C76 C81 C82 C85 C86 C91 C93 C94: library part CMP-0007086-4, "CAP, CERM, 0.022 uF, 100 V, +/- 10%, X7R, AEC-Q200 Grade 1, 0603", Cap_Case=0603, Manufacturer=TDK, Supplier Part Number 1=445-5814-1-ND, TempCo=X7R, Tolerance_%=10%, Value1="0.083542 ohm", Value2=100V, ValueDisplayed=0.022uF
C60 C66 C74 C136: library part CMP-0006356-2, "CAP, CERM, 0.1 uF, 50 V, +/- 10%, X7R, AEC-Q200 Grade 1, 0402", Cap_Case=0402, Manufacturer=MuRata, Supplier Part Number 1=490-10672-1-ND, TempCo=X7R, Tolerance_%=10%, Value1=Unknown, Value2=50V, ValueDisplayed=0.1uF
C61 C67 C75 C388 C395 C396: library part CMP-0006976-5, "CAP, CERM, 1000 pF, 50 V, +/- 10%, X7R, 0603", Cap_Case=0603, Manufacturer=Kemet, Supplier Part Number 1=399-5348-1-ND, TempCo=X7R, Tolerance_%=10%, Value1=Unknown, Value2=50V, ValueDisplayed=1000pF
C63 C69: library part CMP-0079247-1, "CAP, CERM, 4700 pF, 100 V,+/- 10%, X7R, AEC-Q200 Grade 1, 0603", Cap_Case=0603, Manufacturer=MuRata, Supplier Part Number 1=490-4930-1-ND, TempCo=X7R, Tolerance_%=10%, Value2=100V, ValueDisplayed=4700pF
C73: library part CMP-0006847-3, "CAP, CERM, 1000 pF, 50 V, +/- 10%, X7R, 0603", Cap_Case=0603, Manufacturer=Kemet, Supplier Part Number 1=399-1082-1-ND, TempCo=X7R, Tolerance_%=10%, Value1=Unknown, Value2=50V, ValueDisplayed=1000pF
C77 C79 C87 C89: library part CMP-0079579-1, "CAP, CERM, 0.22 µF, 50 V,+/- 10%, X7R, AEC-Q200 Grade 1, 0603", Cap_Case=0603, Manufacturer=MuRata, Supplier Part Number 1=490-14410-1-ND, TempCo=X7R, Tolerance_%=10%, Value2=50V, ValueDisplayed=0.22µF
C96: library part CMP-0860442-1, "CAP, AL, 330 µF, 50 V, +/- 20%, 0.12 ohm, AEC-Q200 Grade 2, SMD", Cap_Case=10x10.2mm, Manufacturer=Panasonic, Tolerance_%=20%, Value1="0.12 ohm", Value2=50V, ValueDisplayed=330µF
C97 C98 C108 C109: library part CMP-0007696-2, "CAP, CERM, 1 uF, 50 V, +/- 10%, X7R, 0805", Cap_Case=0805, Manufacturer="Wurth Elektronik", Supplier Part Number 1=710-885012207103, TempCo=X7R, Tolerance_%=10%, Value1=Unknown, Value2=50V, ValueDisplayed=1uF
C99: library part CMP-0009164-2, "CAP, CERM, 10 uF, 50 V, +/- 10%, X7S, AEC-Q200 Grade 1, 1210", Cap_Case=1210_280, Manufacturer=TDK, Supplier Part Number 1=445-7004-1-ND, TempCo=X7S, Tolerance_%=10%, Value1="0.002827 ohm", Value2=50V, ValueDisplayed=10uF
C100 C102 C103: library part CMP-0006837-4, "CAP, CERM, 0.1 uF, 50 V, +/- 10%, X7R, 0603", Cap_Case=0603, Manufacturer="Wurth Elektronik", TempCo=X7R, Tolerance_%=10%, Value1=Unknown, Value2=50V, ValueDisplayed=0.1uF
C101: library part CMP-0006831-4, "CAP, CERM, 1 uF, 16 V, +/- 10%, X7R, 0603", Cap_Case=0603, Manufacturer="Wurth Elektronik", Supplier Part Number 1=710-885012206052, TempCo=X7R, Tolerance_%=10%, Value1=Unknown, Value2=16V, ValueDisplayed=1uF
C105 C117: library part CMP-0095056-1, "Cap Ceramic 1uF 6.3V X7R 5% Pad SMD 0603 Flexible Termination 125°C Automotive T/R", Digikey Part Number=399-17703-1-ND, Manufacturer=KEMET, Mouser Part Number=80-C0603X105J9RAUTO, Operating Temperature Range="-55°C to +125°C", TempCo=15%, Temperature Characteristic=X7R, Tolerance_%=5%, ValueDisplayed=1uF
C106: library part CMP-0086271-1, "CAP, CERM, 0.1 µF, 6.3 V,+/- 10%, X7R, 0603", Cap_Case=0603, Manufacturer=Kemet, TempCo=X7R, Tolerance_%=10%, Value2=6.3V, ValueDisplayed=0.1µF
C112 C113 C122: library part CMP-0011164-2, "CAP, AL, 10 uF, 100 V, +/- 20%, AEC-Q200 Grade 3, SMD", Cap_Case=8.0x6.0mm, Manufacturer=Panasonic, Supplier Part Number 1=PCE3966CT-ND, Tolerance_%=20%, Value1=Unknown, Value2=100V, ValueDisplayed=10uF
C114 C116: library part CMP-0008709-1, "CAP, CERM, 0.1 uF, 100 V, +/- 10%, X7R, 1206", Cap_Case=1206_180, Manufacturer=TDK, Supplier Part Number 1=445-1377-1-ND, TempCo=X7R, Tolerance_%=10%, Value1="0.030343 ohm", Value2=100V, ValueDisplayed=0.1uF
C115 C118 C119 C120 C121: library part CMP-0006837-2, "CAP, CERM, 0.1 uF, 50 V, +/- 10%, X7R, 0603", Cap_Case=0603, Manufacturer="Wurth Elektronik", TempCo=X7R, Tolerance_%=10%, Value1=Unknown, Value2=50V, ValueDisplayed=0.1uF
C123: library part CMP-0007102-3, "CAP, CERM, 0.068 uF, 100 V, +/- 10%, X7S, AEC-Q200 Grade 1, 0603", Cap_Case=0603, Manufacturer=TDK, Supplier Part Number 1=445-6937-1-ND, TempCo=X7S, Tolerance_%=10%, Value1="0.074084 ohm", Value2=100V, ValueDisplayed=0.068uF
C124: library part CMP-0090362-1, "0.1µF ±10% 10V Ceramic Capacitor X7R 0402 (1005 Metric)", Digikey Part Number=732-7513-1-ND, Manufacturer="Wurth Electronics", Mouser Part Number=710-885012205018, Operating Temperature Range="-55°C to +125°C", TempCo=15%, Temperature Characteristic=X7R, Tolerance_%=10%, ValueDisplayed=100000pF
C125 C126 C127 C128 C129 C130 C131 C132: library part CMP-0007082-1, "CAP, CERM, 0.01 uF, 100 V, +/- 10%, X7R, AEC-Q200 Grade 1, 0603", Cap_Case=0603, Manufacturer=TDK, Supplier Part Number 1=445-5812-1-ND, TempCo=X7R, Tolerance_%=10%, Value1="0.235428 ohm", Value2=100V, ValueDisplayed=0.01uF
C133 C134 C137 C138 C140 C141 C142 C143 C144 C146 C149 C150 C151 C152 C153 C154 C155 C156 C157 C158 C159 C160 C161 C162 C374 C375 C376 C377 C378 C379 C380 C381: library part CMP-0095668-2, "Ceramic Capacitor 10nF ±10% 50V X7R 0603", Manufacturer=Murata, Operating Temperature Range="-55°C to +125°C", TempCo=15%, Temperature Characteristic=X7R, Tolerance_%=10%, ValueDisplayed=10nF
C135: library part CMP-0090082-1, "Cap Ceramic 4.7uF 50V X7R 10% Pad SMD 0805 +125°C Automotive T/R", Manufacturer="TDK Corporation", Operating Temperature Range="-55°C to +125°C", TempCo=15%, Temperature Characteristic=X7R, Tolerance_%=0.1%, ValueDisplayed=4.7uF
C139 C237 C239 C241 C243: library part CMP-0084679-1, "CAP, CERM, 0.1 µF, 25 V,+/- 10%, X7R, AEC-Q200 Grade 1, 0603", Cap_Case=0603, Manufacturer=MuRata, TempCo=X7R, Tolerance_%=10%, Value2=25V, ValueDisplayed=0.1µF
C145 C147: library part CMP-0064931-4, "CAP, CERM, 0.1 uF, 10 V,+/- 10%, X7R, 0603", Cap_Case=0603, Manufacturer="Wurth Elektronik", Supplier Part Number 1=732-7939-1-ND, TempCo=X7R, Tolerance_%=10%, Value1=Unknown, Value2=10V, ValueDisplayed=0.1uF
C148: library part CMP-0080632-1, "CAP, CERM, 1 µF, 10 V,+/- 10%, X7R, 0603", Cap_Case=0603, Manufacturer="Taiyo Yuden", Supplier Part Number 1=587-1242-1-ND, TempCo=X7R, Tolerance_%=10%, Value2=10V, ValueDisplayed=1µF
C163 C164 C165 C171 C172 C173 C190 C192 C200 C206 C207: library part CMP-0042976-1, "Cap Ceramic 3.3uF 10V X5R ±10% Pad SMD 0603 +85°C T/R", Digikey Part Number=1276-1892-1-ND, Manufacturer=Samsung, Mouser Part Number=187-CL10A335KP8NNNC, Operating Temperature Range="-55°C to +85°C", TempCo=15%, Temperature Characteristic=X5R, Tolerance_%=10%, ValueDisplayed=3.3uF
C166 C167 C168 C169 C170 C174 C175 C176 C177 C178 C179 C180 C181 C182 C183 C184 C185 C186 C187 C188 C189 C191 C193 C194 C195 C196 C197 C198 C199 C201 C202 C203 C204 C205 C208 C209 C210 C211 C212 C214 C215 C216 C217 C218 C219 C225 C226 C227 C231 C232 C234 C235 C248 C257: library part CMP-0064970-1, "CAP, CERM, 0.1 uF, 16 V,+/- 10%, X7R, 0201", Cap_Case=0201, Manufacturer=MuRata, Supplier Part Number 1=81-GRM033Z71C104KE4D, TempCo=X7R, Tolerance_%=10%, Value1=Unknown, Value2=16V, ValueDisplayed=0.1uF
C213 C224 C230 C233 C247 C295: library part CMP-0006582-2, "CAP, CERM, 4.7 uF, 10 V, +/- 20%, X5R, 0402", Cap_Case=0402, Manufacturer=MuRata, TempCo=X5R, Tolerance_%=20%, Value1=Unknown, Value2=10V, ValueDisplayed=4.7uF
C220 C221 C222 C223 C255 C256 C258 C259 C260 C263 C302 C303: library part CMP-0096855-1, "Chip Multilayer Ceramic Capacitors for General Purpose, 0402, 0.10uF, X7R, 15%, 10%, 50V", Manufacturer=Murata, Operating Temperature Range="-55°C to +125°C", TempCo=15%, Temperature Characteristic=X7R, Tolerance_%=10%, ValueDisplayed=0.10uF
C228 C229 C236 C238 C240 C242 C244 C246 C250 C251 C252 C253: library part CMP-0122528-1, "Cap Ceramic 0.1uF 50V X7R 5% SMD 1.6 x 0.8 mm 125 C Paper T/R", Digikey Part Number=399-C0603C104J5RAC7867CT-ND, Manufacturer=KEMET, Mouser Part Number=80-C0603C104J5R, Operating Temperature Range="-55°C to +125°C", TempCo=15%, Temperature Characteristic=X7R, Tolerance_%=5%, ValueDisplayed=0.1uF
C245 C249: library part CMP-0006850-2, "CAP, CERM, 0.01 uF, 50 V, +/- 5%, X7R, 0603", Cap_Case=0603, Manufacturer=Kemet, Supplier Part Number 1=399-1092-1-ND, TempCo=X7R, Tolerance_%=5%, Value1=Unknown, Value2=50V, ValueDisplayed=0.01uF
C254 C264 C275 C276 C278 C279 C281 C286 C288 C290 C292 C296 C298 C300: library part CMP-0006659-2, "CAP, CERM, 0.1 uF, 25 V, +/- 10%, X7R, 0402", Cap_Case=0402, Manufacturer=MuRata, Supplier Part Number 1=490-10698-1-ND, TempCo=X7R, Tolerance_%=10%, Value1=Unknown, Value2=25V, ValueDisplayed=0.1uF
C261 C262: library part CMP-0860828-1, "CAP, CERM, 12 pF, 50 V,+/- 5%, C0G/NP0, AEC-Q200 Grade 1, 0402", Cap_Case=0402, Manufacturer=TDK, TempCo=C0G/NP0, Tolerance_%=5%, Value2=50V, ValueDisplayed=12pF
C265 C266 C267 C268 C287: library part CMP-0124829-1, "47 µF ±20% 25V Ceramic Capacitor X5R 1206 (3216 Metric)", Digikey Part Number=4713-GMC31X5R476M25NTCT-ND, Manufacturer="Cal-Chip Electronics", Operating Temperature Range="-55°C to +85°C", TempCo=15%, Temperature Characteristic=X5R, Tolerance_%=20%, ValueDisplayed=47uF
C269 C270 C289 C291 C294 C297 C299 C301: library part CMP-0122097-1, "Chip Multilayer Ceramic Capacitors for General Purpose, 0805, 10uF, X5R, 15%, 10%, 50V", Manufacturer=Murata, Operating Temperature Range="-55°C to +85°C", TempCo=15%, Temperature Characteristic=X5R, Tolerance_%=10%, ValueDisplayed=10uF
C271 C272 C293: library part CMP-0089929-1, "2.2µF ±10% 25V Ceramic Capacitor X5R 0402 (1005 Metric)", Digikey Part Number=490-12703-1-ND, Manufacturer=Murata, Mouser Part Number=81-GRM155R61E225KE1D, Operating Temperature Range="-55°C to +85°C", TempCo=15%, Temperature Characteristic=X5R, Tolerance_%=10%, ValueDisplayed=2.2uF, Voltage=25V
C273 C274 C280: library part CMP-0006412-2, "CAP, CERM, 1000 pF, 50 V, +/- 5%, C0G/NP0, 0402", Cap_Case=0402, Manufacturer=MuRata, Supplier Part Number 1=490-3244-1-ND, TempCo=C0G/NP0, Tolerance_%=5%, Value1=Unknown, Value2=50V, ValueDisplayed=1000pF
C277: library part CMP-0006352-2, "CAP, CERM, 0.01 uF, 25 V, +/- 10%, X7R, 0402", Cap_Case=0402, Manufacturer=MuRata, Supplier Part Number 1=490-6043-2-ND, TempCo=X7R, Tolerance_%=10%, Value1=Unknown, Value2=25V, ValueDisplayed=0.01uF
C282 C283 C284 C285 C364 C371: library part CMP-0008305-2, "CAP, CERM, 22 uF, 25 V, +/- 20%, X5R, 0805", Cap_Case=0805, Manufacturer=MuRata, Supplier Part Number 1=490-10749-1-ND, TempCo=X5R, Tolerance_%=20%, Value1=Unknown, Value2=25V, ValueDisplayed=22uF
C304: library part CMP-0007430-2, "CAP, CERM, 0.082 uF, 25 V, +/- 10%, X7R, 0603", Cap_Case=0603, Manufacturer=MuRata, Supplier Part Number 1=GRM188R71E823KA01D-ND, TempCo=X7R, Tolerance_%=10%, Value1=Unknown, Value2=25V, ValueDisplayed=0.082uF
C305: library part CMP-0011210-2, "CAP, AL, 220 uF, 50 V, +/- 20%, 0.1 ohm, AEC-Q200 Grade 2, SMD", Cap_Case=G, Manufacturer=Panasonic, Supplier Part Number 1=PCE3474CT-ND, Tolerance_%=20%, Value1="0.1 ohm", Value2=50V, ValueDisplayed=220uF
C306: library part CMP-0007078-1, "CAP, CERM, 0.1 uF, 50 V, +/- 10%, X7R, AEC-Q200 Grade 1, 0603", Cap_Case=0603, Manufacturer=TDK, Supplier Part Number 1=445-5666-1-ND, TempCo=X7R, Tolerance_%=10%, Value1="0.0296 ohm", Value2=50V, ValueDisplayed=0.1uF
C307: library part CMP-0006901-3, "CAP, CERM, 0.022 uF, 50 V, +/- 10%, X7R, 0603", Cap_Case=0603, Manufacturer=Kemet, Supplier Part Number 1=399-1280-1-ND, TempCo=X7R, Tolerance_%=10%, Value1=Unknown, Value2=50V, ValueDisplayed=0.022uF
C310: library part CMP-0011092-1, "CAP, AL, 390 uF, 35 V, +/- 20%, 0.08 ohm, SMD", Cap_Case=10x10, Manufacturer=Nichicon, Supplier Part Number 1=493-3960-1-ND, Tolerance_%=20%, Value1="0.08 ohm", Value2=35V, ValueDisplayed=390uF
C311 C312 C313 C314 C325 C326: library part CMP-06035-059042-1, "Multilayer Ceramic Capacitors MLCC - SMD/SMT 0805 1uF 20%, 50VDC,  X7R 15%", Capacitance=1uF, Case Code (Imperial)=0805, Case Code (Metric)=2012, Max Operating Temperature=125°C, Min Operating Temperature=-55°C, Ratings=AEC-Q200, Tolerance=20%, Voltage Rating=50V
C315 C316 C317 C318 C319 C320 C321 C322: library part CMP-2006-02223-2, "Cap Ceramic 0.1uF 50V X7R 10% Pad SMD 0603 Soft Termination +125°C Automotive T/R", Capacitance=100nF, Case Code (Imperial)=0603, Case Code (Metric)=1608, Dielectric=X7R, Max Operating Temperature=125°C, Min Operating Temperature=-55°C, Package Quantity=1, Ratings=AEC-Q200, Tolerance=10%, Voltage Rating=50V
C323: library part CMP-0122257-1, "1 µF ±10% 50V Ceramic Capacitor X7R 0603 (1608 Metric)", Digikey Part Number=1276-CL10B105KB9VPJCCT-ND, Manufacturer=Samsung, Mouser Part Number=187-CL10B105KB9VPJC, Operating Temperature Range="-55°C to +125°C", TempCo=15%, Temperature Characteristic=X7R, Tolerance_%=10%, ValueDisplayed=1uF
C324: library part CMP-0122397-1, "Cap Ceramic 0.1uF 50V X7R 10% Pad SMD 0603 Flexible Termination 125C Automotive T/R", Digikey Part Number=399-6912-1-ND, Manufacturer=Kemet, Mouser Part Number=80-C0603X104K5RAUTO, Operating Temperature Range="-55°C to +125°C", TempCo=15%, Temperature Characteristic=X7R, Tolerance_%=10%, ValueDisplayed=0.1uF
C327 C338 C345 C353: library part CMP-0086249-1, "CAP, CERM, 1 µF, 50 V,+/- 10%, X7R, AEC-Q200 Grade 1, 0805", Cap_Case=0805, Manufacturer=MuRata, TempCo=X7R, Tolerance_%=10%, Value2=50V, ValueDisplayed=1µF
C328 C332 C350 C351: library part CMP-0079154-1, "CAP, CERM, 1 µF, 16 V,+/- 10%, X7R, AEC-Q200 Grade 1, 0603", Cap_Case=0603, Manufacturer=MuRata, Supplier Part Number 1=490-12657-1-ND, TempCo=X7R, Tolerance_%=10%, Value2=16V, ValueDisplayed=1µF
C329 C339 C347 C354: library part CMP-2006-02379-2, "Ceramic Capacitor for Automotive 150nF  ±10% 50VDC X7R 0603 Paper T/R", Capacitance=150nF, Case Code (Imperial)=0603, Case Code (Metric)=1608, Dielectric=X7R, Max Operating Temperature=125°C, Min Operating Temperature=-55°C, Package Quantity=4000, Ratings=AEC-Q200, Tolerance=10%, Voltage Rating=50V
C330 C331 C341 C342 C348 C349 C355 C356: library part CMP-0007174-3, "CAP, CERM, 0.01 uF, 50 V, +/- 5%, C0G/NP0, 0603", Cap_Case=0603, Manufacturer=MuRata, Supplier Part Number 1=490-9666-1-ND, TempCo=C0G/NP0, Tolerance_%=5%, Value1=Unknown, Value2=50V, ValueDisplayed=0.01uF
C333 C343 C352 C357: library part CMP-0006687-1, "CAP, CERM, 330 pF, 50 V, +/- 10%, X7R, 0402", Cap_Case=0402, Manufacturer=MuRata, Supplier Part Number 1=490-3247-1-ND, TempCo=X7R, Tolerance_%=10%, Value1=Unknown, Value2=50V, ValueDisplayed=330pF
C334: library part CMP-0084284-1, "CAP, CERM, 2.2 µF, 10 V,+/- 10%, X7R, AEC-Q200 Grade 1, 0603", Cap_Case=0603, Manufacturer=MuRata, TempCo=X7R, Tolerance_%=10%, Value2=10V, ValueDisplayed=2.2µF
C335: library part CMP-0007393-2, "CAP, CERM, 0.33 uF, 16 V, +/- 10%, X7R, 0603", Cap_Case=0603, Manufacturer=MuRata, Supplier Part Number 1=490-3294-1-ND, TempCo=X7R, Tolerance_%=10%, Value1=Unknown, Value2=16V, ValueDisplayed=0.33uF
C336 C340 C344 C346: library part CMP-0007136-1, "CAP, CERM, 1 uF, 16 V, +/- 10%, X7R, AEC-Q200 Grade 1, 0603", Cap_Case=0603, Manufacturer=MuRata, Supplier Part Number 1=490-5241-6-ND, TempCo=X7R, Tolerance_%=10%, Value1=Unknown, Value2=16V, ValueDisplayed=1uF
C337: library part CMP-0006351-1, "CAP, CERM, 0.1 uF, 16 V, +/- 10%, X7R, 0402", Cap_Case=0402, Manufacturer=MuRata, Supplier Part Number 1=490-4759-2-ND, TempCo=X7R, Tolerance_%=10%, Value1=Unknown, Value2=16V, ValueDisplayed=0.1uF
C359: library part CMP-0860967-1, "CAP, CERM, 10 µF, 16 V,+/- 10%, X7R, 0805", Cap_Case=0805, Manufacturer=Samsung, TempCo=X7R, Tolerance_%=10%, Value2=16V, ValueDisplayed=10µF
C360: library part CMP-0093201-1, "10 µF ±10% 50V Ceramic Capacitor X7R 1206 (3216 Metric)", Manufacturer="Cal-Chip Electronics", Operating Temperature Range="-55°C to +125°C", TempCo=15%, Temperature Characteristic=X7R, Tolerance_%=10%, ValueDisplayed=10uF
C362: library part CMP-0090210-1, "Cap Ceramic 33nF 50V X7R 10% Pad SMD 0603 +125°C Automotive T/R", Manufacturer=TDK, Operating Temperature Range="-55°C to +125°C", TempCo=0.15, Temperature Characteristic=X7R, Tolerance_%=0.1%, ValueDisplayed=33nF
C363: library part CMP-0006844-3, "CAP, CERM, 1000 pF, 50 V, +/- 5%, X7R, AEC-Q200 Grade 1, 0603", Cap_Case=0603, Manufacturer=Kemet, Supplier Part Number 1=399-12989-1-ND, TempCo=X7R, Tolerance_%=5%, Value1=Unknown, Value2=50V, ValueDisplayed=1000pF
C365: library part CMP-0080480-1, "CAP, CERM, 1 µF, 50 V,+/- 20%, X7R, AEC-Q200 Grade 1, 0805", Cap_Case=0805, Manufacturer=MuRata, Supplier Part Number 1=490-16470-1-ND, TempCo=X7R, Tolerance_%=20%, Value2=50V, ValueDisplayed=1µF
C366: library part CMP-0860897-1, "CAP, CERM, 2.2 µF, 50 V,+/- 10%, X7R, AEC-Q200 Grade 1, 0805", Cap_Case=0805, Manufacturer=TDK, TempCo=X7R, Tolerance_%=10%, Value2=50V, ValueDisplayed=2.2µF
C367: library part CMP-0007336-5, "CAP, CERM, 10 uF, 16 V, +/- 20%, X5R, 0603", Cap_Case=0603, Manufacturer=MuRata, Supplier Part Number 1=GRM188R61C106MAALD-ND, TempCo=X5R, Tolerance_%=20%, Value1=Unknown, Value2=16V, ValueDisplayed=10uF
C369 C372: library part CMP-0006696-2, "CAP, CERM, 6800 pF, 50 V, +/- 10%, X7R, 0402", Cap_Case=0402, Manufacturer=MuRata, Supplier Part Number 1=490-4515-1-ND, TempCo=X7R, Tolerance_%=10%, Value1=Unknown, Value2=50V, ValueDisplayed=6800pF
C370: library part CMP-0096736-1, "10 µF ±20% 25V Ceramic Capacitor X5R 0603 (1608 Metric)", Manufacturer=Wurth, Operating Temperature Range="-55°C to +85°C", TempCo=15%, Temperature Characteristic=X5R, Tolerance_%=20%, ValueDisplayed=10uF
C373: library part CMP-0006949-5, "CAP, CERM, 4.7 uF, 10 V, +/- 10%, X5R, 0603", Cap_Case=0603, Manufacturer=Kemet, Supplier Part Number 1=399-5503-1-ND, TempCo=X5R, Tolerance_%=10%, Value1="0.006 ohm", Value2=10V, ValueDisplayed=4.7uF
C382 C383 C384 C385 C386 C387: library part CMP-0007135-2, "CAP, CERM, 0.1 uF, 16 V, +/- 10%, X7R, AEC-Q200 Grade 1, 0603", Cap_Case=0603, Manufacturer=MuRata, Supplier Part Number 1=490-8015-1-ND, TempCo=X7R, Tolerance_%=10%, Value1=Unknown, Value2=16V, ValueDisplayed=0.1uF
C389 C399: library part CMP-0007969-2, "CAP, CERM, 0.1 uF, 100 V, +/- 10%, X7R, AEC-Q200 Grade 1, 0805", Cap_Case=0805, Manufacturer=TDK, Supplier Part Number 1=445-5827-1-ND, TempCo=X7R, Tolerance_%=10%, Value1="0.020726 ohm", Value2=100V, ValueDisplayed=0.1uF
C390 C394: library part CMP-0009477-2, "CAP, CERM, 15 uF, 100 V, +/- 20%, X7R, Stacked 2220", Cap_Case=2220, Manufacturer=MuRata, Supplier Part Number 1=490-5838-1-ND, TempCo=X7R, Tolerance_%=20%, Value1=Unknown, Value2=100V, ValueDisplayed=15uF
C392: library part CMP-0007082-4, "CAP, CERM, 0.01 uF, 100 V, +/- 10%, X7R, AEC-Q200 Grade 1, 0603", Cap_Case=0603, Manufacturer=TDK, Supplier Part Number 1=445-5812-1-ND, TempCo=X7R, Tolerance_%=10%, Value1="0.235428 ohm", Value2=100V, ValueDisplayed=0.01uF
C397 C398 C401 C404: library part CMP-0007092-5, "CAP, CERM, 0.47 uF, 25 V, +/- 10%, X7R, AEC-Q200 Grade 1, 0603", Cap_Case=0603, Manufacturer=TDK, Supplier Part Number 1=445-6929-1-ND, TempCo=X7R, Tolerance_%=10%, Value1=Unknown, Value2=25V, ValueDisplayed=0.47uF
C400: library part CMP-0006687-2, "CAP, CERM, 330 pF, 50 V, +/- 10%, X7R, 0402", Cap_Case=0402, Manufacturer=MuRata, Supplier Part Number 1=490-3247-1-ND, TempCo=X7R, Tolerance_%=10%, Value1=Unknown, Value2=50V, ValueDisplayed=330pF
C402 C403: library part CMP-0006921-4, "CAP, CERM, 330 pF, 50 V, +/- 10%, X7R, 0603", Cap_Case=0603, Manufacturer=Kemet, Supplier Part Number 1=399-1073-1-ND, TempCo=X7R, Tolerance_%=10%, Value1=Unknown, Value2=50V, ValueDisplayed=330pF
C406 C407 C410 C411 C414 C415 C418 C419: library part CMP-0860981-1, "CAP, CERM, 0.1 µF, 16 V,+/- 10%, X7R, 0201", Cap_Case=0201, Manufacturer="Passive Plus", TempCo=X7R, Tolerance_%=10%, Value2=16V, ValueDisplayed=0.1µF
C408 C409 C412 C413 C416 C417 C420 C421: library part CMP-0097126-1, "Chip Multilayer Ceramic Capacitors for General Purpose, 0201, 1.0uF, X5R, 15%, 20%, 16V", Manufacturer=Murata, Operating Temperature Range="-55°C to +85°C", TempCo=15%, Temperature Characteristic=X5R, Tolerance_%=20%, ValueDisplayed=1.0uF
D1 D2 D3 D54: library part CMP-0002893-1, "LED, Super Red, SMD", Color="super red", Manufacturer="Wurth Elektronik", Supplier Part Number 1=732-4979-1-ND, Value1=W, Value2=1.9V
D4 D6: library part CMP-0005563-4, "Diode, TVS, Uni, 33 V, 53.3 Vc, SMB", Manufacturer="Diodes Inc.", Value1=600W
D5 D7: library part CMP-0005547-4, "Diode, TVS, Uni, 16 V, 26 Vc, SMB", Manufacturer="Diodes Inc.", Value1=600W
D8 D9 D10 D11: library part CMP-0093308-1, "24-V, 2-Channel ESD Protection Diode for In-Vehicle Networks, SC70-3", Breakdown Voltage=25.5V, Clamping Voltage=32V, Manufacturer="Texas Instruments", Operating Temperature Range="-55°C to +150°C", ValueDisplayed=3pF
D13 D14 D15 D16 D17: library part CMP-0079597-2, "Diode, Switching, 75 V, 0.15 A, AEC-Q101, SOD-323", Manufacturer="Diodes Inc.", Value1=0.15A, Value2=1.25V
D18: library part CMP-0076901-2, "Diode, Switching, 200 V, 0.2 A, SOT-23", Manufacturer="Diodes Inc.", Value1=0.2A, Value2=1.25V
D19: library part CMP-0028606-3, "Diode, Schottky, 45 V, 0.75 A, SOD-523", Manufacturer="Infineon Technologies", Value1=0.75A, Value2=0.6V
D20 D21 D22 D23 D24 D25 D26 D27 D28 D29 D30 D31 D32 D33 D34 D35 D36 D37 D38 D39 D58: library part CMP-0005797-3, "Diode, Zener, 3.3 V, 500 mW, SOD-123", Manufacturer="Diodes Inc.", Power_W=500mW, Value1=0.5W
D40 D41 D55: library part CMP-0028880-3, "Diode, Schottky, 20 V, 0.5 A, AEC-Q101, SOD-523", Manufacturer="ON Semiconductor", Value1=0.5A, Value2=0.48V
D42: library part CMP-0002938-2, "LED, Blue, SMD", Color=Blue, Manufacturer=Lite-On, Power_TotalModule=76mW, Supplier Part Number 1=160-1827-1-ND, Value1=0.076W, Value2=2.8V
D43: library part CMP-0002892-2, "LED, Yellow, SMD", Color=yellow, Manufacturer="Wurth Elektronik", Supplier Part Number 1=732-4981-1-ND, Value1=W, Value2=2V
D44 D45 D46 D47 D48 D49 D50: library part CMP-0002894-2, "LED, Green, SMD", Color=green, Manufacturer="Wurth Elektronik", Value1=W, Value2=2V
D51 D52: library part CMP-0122246-1, "Red 624nm LED Indication - Discrete 2V 0402 (1005 Metric)", Color=Red, Digikey Part Number=732-13422-1-ND, Forward Current=20mA, Manufacturer=Wurth, Mouser Part Number=710-150040RS73220, Operating Temperature Range="-40°C to +85°C", Power_TotalModule=48mW
D53 D56: library part CMP-0028987-2, "Diode, Schottky, 100 V, 2 A, SMB", Manufacturer=Vishay-Semiconductor, Value1=2A, Value2=0.79V
D57: library part CMP-0076974-1, "Diode, Switching, 100 V, 0.15 A, SOD-123", Manufacturer="Micro Commercial Components", Supplier Part Number 1=1N4148WTPMSCT-ND, Value1=0.15A, Value2=1.25V
FB1 FB2: library part CMP-0089199-1, "120 Ohms @ 100MHz 1  Ferrite Bead 0603 (1608 Metric) 2A 40mOhm", Digikey Part Number=490-3991-1-ND, Impedance At Frequency="120Ω @ 100MHz", Manufacturer=Murata, Mouser Part Number=81-BLM18EG121SN1D, Operating Temperature Range="-55°C to +125°C", Tolerance_%=25%
FID1 FID2 FID3: library part CMP-0077181-1, "Fiducial mark.  There is nothing to buy or mount.", Manufacturer=N/A
H1 H2 H3 H4: library part CMP-0003617-1, "Machine Screw, Round, #4-40 x 1/4, Nylon, Philips panhead", Manufacturer="B&F Fastener Supply", Supplier Part Number 1=H542-ND
H5 H6 H7 H8: library part CMP-0003610-1, "Standoff, Hex, 0.5\"L #4-40 Nylon", Manufacturer=Keystone, Supplier Part Number 1=36-1902C-ND
H9: library part CMP-0004050-1, "Heat Sink for DKQ Packages, 41.4x20 mm", Manufacturer="Advanced Thermal Solutions", PartNumber=ATS-TI1OP-1099-C1-R1
J1 J4 J7 J8: library part CMP-0055527-1, "Terminal Block, 9.52mm, 2x1, R/A, TH", Color=Green, Current_A=32A, Manufacturer="Phoenix Contact", Supplier Part Number 1=277-5951-ND, Voltage_V=1kV
J2 J3 J5 J10: library part CMP-0055471-1, "Terminal Block, 5.08 mm, 2x1, TH", Color=Green, Current_A=17.5A, Manufacturer="Phoenix Contact", Supplier Part Number 1=277-1263-ND, Voltage_V=400V
J6: library part CMP-0055522-1, "Terminal Block, 5mm, 8 Pos, TH", Color=Green, Current_A=17.5A, Manufacturer="Phoenix Contact", Supplier Part Number 1=277-1261-ND
J9 J26 J27: library part CMP-0055526-1, "Terminal Block, 5mm, 4x1, R/A,TH", Color=Green, Current_A=17.5A, Manufacturer="Phoenix Contact", Supplier Part Number 1=277-1260-ND, Voltage_V=400V
J11: library part CMP-0096961-1, "26 Position Connector Socket, Outer Shroud Contacts Surface Mount Gold", Current_A=1.4A, Digikey Part Number=SAM13540CT-ND, Manufacturer=Samtec, Mouser Part Number=200-ERF801305.0LDVTR, Operating Temperature Range="-55°C to +125°C", Voltage_V=225V
J12 J13: library part CMP-0055635-1, "Receptacle, 0.8mm, 25x2, Gold, SMT", Color=Black, Current_A=2.2A, Manufacturer=Samtec, Voltage_V=200V
J14: library part CMP-0075422-1, "Header, 100mil, 10x1, Gold, TH", Color=Black, Current_A=6.3A, Manufacturer=Samtec, Supplier Part Number 1=SAM1029-10-ND, Voltage_V=550V
J15 J21 J22: library part CMP-0075407-2, "Header, 100mil, 3x1, Gold, TH", Color=Black, Current_A=6.3A, Manufacturer=Samtec, Supplier Part Number 1=SAM1029-03-ND, Voltage_V=550V
J16 J19: library part CMP-0075413-2, "Header, 100mil, 6x1, Gold, TH", Color=Black, Current_A=6.3A, Manufacturer=Samtec, Supplier Part Number 1=SAM1029-06-ND, Voltage_V=550V
J17: library part CMP-0075665-2, "Header, 2.54mm, 5x2, Gold, Black, TH", Color=Black, Manufacturer=Samtec, Supplier Part Number 1=SAM8999-ND
J18: library part CMP-0075411-1, "Header, 100mil, 5x1, Gold, TH", Color=Black, Current_A=6.3A, Manufacturer=Samtec, Supplier Part Number 1=SAM1029-05-ND, Voltage_V=550V
J20: library part CMP-0121706-1, "Conn Unshrouded HDR 16 POS 2.54mm Solder ST SMT", Manufacturer=Samtec, Operating Temperature Range="-55°C to +125°C"
J23: library part CMP-0075409-2, "Header, 100mil, 4x1, Gold, TH", Color=Black, Current_A=6.3A, Manufacturer=Samtec, Supplier Part Number 1=SAM1029-04-ND, Voltage_V=550V
J24: library part CMP-0055372-1, "D-Sub-9, 11Pos, Male, TH", Manufacturer=Harting, Supplier Part Number 1=09651626810-ND
J25: library part CMP-0075415-1, "Header, 100mil, 7x2, Gold, TH", Color=Black, Current_A=6.3A, Manufacturer=Samtec, Supplier Part Number 1=SAM1028-07-ND, Voltage_V=550V
J28: library part CMP-0075419-1, "Header, 100mil, 8x1, Gold, TH", Color=Black, Current_A=6.3A, Manufacturer=Samtec, Supplier Part Number 1=SAM1029-08-ND, Voltage_V=550V
J29: library part CMP-0054957-1, "Header, 2.54mml, 16x3, Gold, TH", Manufacturer="TE Connectivity", Supplier Part Number 1=A32298-ND
L1 L2 L3 L4: library part CMP-0062430-2, "Inductor, Ferrite, 100 uH, 0.15 A, 2 ohm, SMD", Manufacturer=TDK, Supplier Part Number 1=445-3959-1-ND, Value1="2 ohm", Value2=0.15A, ValueDisplayed=100uH
L6: library part CMP-0080400-2, "Inductor, Shielded, Ferrite, 2.2 µH, 5.1 A, 0.017 ohm, AEC-Q200 Grade 0, SMD", Manufacturer=TDK, Supplier Part Number 1=445-174169-1-ND, Value1="0.017 ohm", Value2=5.1A, ValueDisplayed=2.2µH
L7 L8 L9 L10: library part CMP-0059924-1, "Inductor, 3.3 uH, 4.5 A, 0.038 ohm, AEC-Q200 Grade 0, SMD", Manufacturer=Cyntec, Value1="0.038 ohm", Value2=4.5A, ValueDisplayed=3.3uH
L11: library part CMP-0090842-1, "Power Inductor, shielded, composite, 1uH 20% tol, DCR 7.2mOhms, SRF 65MHz, Isat 4.8A, Irms 13A, AEC-Q200", Manufacturer=Coilcraft, Operating Temperature Range="to +165°C", Self Resonant Frequency=65MHz, Test Frequency=1MHz, Tolerance_%=20%
L12: library part CMP-0081092-1, "Inductor, Shielded, Metal Composite, 1 µH, 3.1 A, 0.06 ohm, AEC-Q200 Grade 0, SMD", Manufacturer=TDK, Supplier Part Number 1=445-174574-1-ND, Value1="0.06 ohm", Value2=3.1A, ValueDisplayed=1µH
LBL1: library part CMP-0003625-1, "Thermal Transfer Printable Labels, 0.650\" W x 0.200\" H - 10,000 per roll", Manufacturer=Brady, Supplier Part Number 1=97C5133
Logo1: library part CMP-0074844-1
Logo2: library part CMP-0074838-1, "Texas Instrument Corporate Signature"
Logo3: library part CMP-0074847-1, "FCC_disclaimer"
Logo4: library part CMP-0074769-1
LOGO5: library part CMP-0074837-1, "IEC 61010-1 Hot Surface Warning"
NT1 NT2 NT3 NT4 NT5 NT6: library part CMP-0078142-3, "Single point connection between nets.", Manufacturer=N/A
Q1 Q2 Q3 Q4 Q5 Q6: library part CMP-0098150-1, "Trans MOSFET N-CH 40V 190A Automotive 5-Pin(4+Tab) LFPAK T/R", Digikey Part Number=1727-7419-1-ND, Drain To Source Breakdown Voltage=42V, Input Capacitace At Vds="5436pF @ 25V", Manufacturer=Nexperia, Mouser Part Number=771-BUK7J1R4-40HX, Operating Temperature Range="-55°C to +175°C", Power_W=395W, Pulse Drain Current=600A, Typ Forward Diode Voltage=0.8V
Q7 Q8 Q9 Q10 Q11 Q12 Q13 Q14: library part CMP-0000713-2, "MOSFET, N-CH, 40 V, 100 A, DNK0008A (VSON-CLIP-8)", Alternate Manufacturer=None, Manufacturer="Texas Instruments", Supplier Part Number 1=CSD18512Q5B-ND, Value1=0.002, Value2="37 nC"
Q15 Q16: library part CMP-0078819-2, "MOSFET, P-CH, -12 V, -4.3 A, SOT-23", Alternate Manufacturer=None, Manufacturer="Infineon Technologies", Value1="0.05 ohm", Value2="10 nC"
Q17: library part CMP-0000948-2, "MOSFET, N-CH, 100 V, 0.17 A, SOT-323", Alternate Manufacturer=None, Manufacturer="Diodes Inc.", Supplier Part Number 1=BSS123W-FDICT-ND, Value1=1
Q18: library part CMP-0000282-1, "MOSFET, N-CH, 25 V, 0.68 A, SOT-23", Alternate Manufacturer=None, Manufacturer="Fairchild Semiconductor", Supplier Part Number 1=FDV303NCT-ND, Value1=0.4, Value2="1.64 nC"
Q19 Q23: library part CMP-0078323-1, "MOSFET, N-CH, 60 V, 2 A, AEC-Q101, SOT-23", Alternate Manufacturer=None, Manufacturer="Diodes Inc.", Supplier Part Number 1=DMN6075S-7DICT-ND, Value1="0.12 ohm", Value2="5.6 nC"
Q20: library part CMP-0095948-1, "N-Channel 40 V 500A (Ta) 375W (Ta) Surface Mount LFPAK88 (SOT1235)", Digikey Part Number=1727-BUK7S0R5-40HJCT-ND, Drain To Source Breakdown Voltage=43V, Input Capacitace At Vds="15116pF @ 25V", Manufacturer=Nexperia, Mouser Part Number=771-BUK7S0R5-40HJ, Operating Temperature Range="-55°C to +175°C", Power_W=375W, Pulse Drain Current=2237A, Typ Forward Diode Voltage=0.79V
Q21: library part CMP-0000428-2, "Transistor, NPN, 40 V, 0.2 A, SOT-416", Manufacturer="ON Semiconductor", Supplier Part Number 1=MMBT3904TT1GOSCT-ND, Value1="0.2 A", Value2=300
Q22: library part CMP-0000887-1, "MOSFET, N-CH, 60 V, 0.2 A, AEC-Q101, SOT-23", Alternate Manufacturer=None, Manufacturer="Diodes Inc.", Supplier Part Number 1=ZVN4106FCT-ND
Q24: library part CMP-0091832-1, "N-Channel 100V 135A (Tc) 136W (Tc) Surface Mount PowerPAK® 8 x 8", Digikey Part Number=SQJQ410EL-T1_GE3CT-ND, Drain To Source Breakdown Voltage=100V, Input Capacitace At Vds="5620pF @ 25V", Manufacturer=Vishay, Mouser Part Number=78-SQJQ410EL-T1_GE3, Operating Temperature Range="-55°C to +175°C", Power_W=136W, Pulse Drain Current=210A, Typ Forward Diode Voltage=0.83V
R1 R2 R3 R384: library part CMP-0022904-5, "RES, 205, 1%, 0.1 W, 0603", Manufacturer=Yageo, Power_W=100mW, Supplier Part Number 1=311-205HRCT-ND, TempCo="100 ppm/C", Tolerance_%=1%, Value2=0.1W, Value_Code=205R, ValueDisplayed=205
R4 R5 R6 R7 R8 R9 R10 R11 R12 R13 R14 R209 R210 R211 R214 R215 R216 R217 R218 R219 R220 R224 R227 R229 R240 R253 R262 R292 R293 R295 R297 R299 R318 R319 R322 R329 R332 R335 R339 R341 R342 R404 R411 R413: library part CMP-0002710-1, "0 Ohms Jumper Chip Resistor 0402 (1005 Metric) Automotive AEC-Q200 Thick Film", Digikey Part Number=P0.0JCT-ND, Manufacturer=Panasonic, Mouser Part Number=667-ERJ-2GE0R00X, Operating Temperature Range="-55°C to +155°C", Power=100mW
R15: library part CMP-0086899-1, "300 µOhms ±1% 6W Chip Resistor 2512 (6432 Metric) Automotive AEC-Q200, Current Sense, Moisture Resistant Metal Element", Manufacturer=Yageo, Power_W=6W, TempCo=200ppm/°C, Tolerance_%=1%
R16: library part CMP-0022479-4, "RES, 50, 1%, 0.1 W, AEC-Q200 Grade 0, 0603", Manufacturer=Vishay-Dale, Power_W=100mW, Supplier Part Number 1=89M6778, TempCo="100 ppm/C", Tolerance_%=1%, Value2=0.1W, Value_Code=50R0, ValueDisplayed=50
R17: library part CMP-0025874-4, "RES, 0, 5%, 0.1 W, AEC-Q200 Grade 0, 0603", Manufacturer=Panasonic, Power_W=100mW, Supplier Part Number 1=P0.0GCT-ND, TempCo="600 ppm/C", Tolerance_%=5%, Value2=0.1W, Value_Code=0000, ValueDisplayed=100
R18 R19 R34: library part CMP-0025874-4, "RES, 0, 5%, 0.1 W, AEC-Q200 Grade 0, 0603", Manufacturer=Panasonic, Power_W=100mW, Supplier Part Number 1=P0.0GCT-ND, TempCo="600 ppm/C", Tolerance_%=5%, Value2=0.1W, Value_Code=0000, ValueDisplayed=0
R20: library part CMP-0022479-4, "RES, 50, 1%, 0.1 W, AEC-Q200 Grade 0, 0603", Manufacturer=Vishay-Dale, Power_W=100mW, Supplier Part Number 1=89M6778, TempCo="100 ppm/C", Tolerance_%=1%, Value2=0.1W, Value_Code=50R0, ValueDisplayed=0
R21: library part CMP-0023930-3, "RES, 20.8 k, 0.1%, 0.1 W, 0603", Manufacturer="Yageo America", Power_W=100mW, TempCo="25 ppm/C", Tolerance_%=0.1%, Value2=0.1W, Value_Code=20k8, ValueDisplayed=10k
R22 R24 R31: library part CMP-0092407-1, "Res Thick Film 0603 100K Ohm 0.1% 0.2W(1/5W) ±50ppm/°C Pad SMD Automotive T/R", Digikey Part Number=P20200CT-ND, Manufacturer=Panasonic, Mouser Part Number=667-ERJ-PB3B1003V, Operating Temperature Range="-55°C to +155°C", Power_W=200mW, TempCo=50ppm/°C, Tolerance_%=0.1%
R23: library part CMP-0023900-3, "RES, 1.62 k, 0.1%, 0.1 W, 0603", Manufacturer="Yageo America", Power_W=100mW, TempCo="25 ppm/C", Tolerance_%=0.1%, Value2=0.1W, Value_Code=1k62, ValueDisplayed=1.65k
R25 R26 R27 R35 R375 R378 R380: library part CMP-0022684-3, "RES, 10.0 k, 1%, 0.1 W, 0603", Manufacturer=Panasonic, Power_W=100mW, Supplier Part Number 1=P10.0KHCT-ND, TempCo="100 ppm/C", Tolerance_%=1%, Value2=0.1W, Value_Code=10k0, ValueDisplayed=10.0k
R28: library part CMP-0023020-5, "RES, 30.0 k, 1%, 0.1 W, 0603", Manufacturer=Yageo, Power_W=100mW, Supplier Part Number 1=311-30.0KHRCT-ND, TempCo="100 ppm/C", Tolerance_%=1%, Value2=0.1W, Value_Code=30k0, ValueDisplayed=5k
R29: library part CMP-0023056-5, "RES, 36.5 k, 1%, 0.1 W, 0603", Manufacturer=Yageo, Power_W=100mW, Supplier Part Number 1=311-36.5KHRCT-ND, TempCo="100 ppm/C", Tolerance_%=1%, Value2=0.1W, Value_Code=36k5, ValueDisplayed=36.5k
R30: library part CMP-0095938-1, "500 µOhms ±1% 6W Chip Resistor 2512 (6432 Metric) Automotive AEC-Q200, Current Sense Metal Element", Digikey Part Number=CSS2H-2512R-L500FCT-ND, Manufacturer=Bourns, Mouser Part Number=652-CSS2H2512RL500F, Operating Temperature Range="-55°C to +170°C", Power_W=6W, TempCo=100ppm/°C, Tolerance_%=1%
R32 R33: library part CMP-0095262-1, "100 Ohms ±5% 0.2W, 1/5W Chip Resistor 0603 (1608 Metric) Automotive AEC-Q200, Moisture Resistant, Pulse Withstanding Thick Film", Digikey Part Number=2019-SG73S1JTTD101JCT-ND, Manufacturer="KOA Speer", Mouser Part Number=660-SG73S1JTTD101J, Operating Temperature Range="-55°C to +155°C", Power_W=200mW, TempCo=100ppm/°C, Tolerance_%=5%
R36 R40 R42 R45 R46 R49 R50 R53 R74 R75 R76 R77 R78 R79 R387 R388 R390 R391 R392 R478 R479: library part CMP-0025885-5, "RES, 0, 5%, 0.1 W, 0603", Manufacturer=Yageo, Power_W=100mW, Supplier Part Number 1=311-0.0GRCT-ND, TempCo="200 ppm/C", Tolerance_%=5%, Value2=0.1W, Value_Code=0000, ValueDisplayed=0
R37 R38 R43 R44 R47 R48 R51 R52: library part CMP-0018709-3, "RES, 60, 10%, 0.25 W, AEC-Q200 Grade 0, 1206", Manufacturer=Vishay-Dale, Power_W=250mW, Supplier Part Number 1=CRCW120660R0KNEAIF-ND, TempCo="200 ppm/C", Tolerance_%=10%, Value2=0.25W, Value_Code=60R0, ValueDisplayed=60
R39: library part CMP-0025787-4, "RES, 33, 5%, 0.1 W, AEC-Q200 Grade 0, 0603", Manufacturer=Vishay-Dale, Power_W=100mW, Supplier Part Number 1=541-33GCT-ND, TempCo="200 ppm/C", Tolerance_%=5%, Value2=0.1W, Value_Code=33R0, ValueDisplayed=33
R41: library part CMP-0023405-3, "RES, 100 k, 0.1%, 0.1 W, 0603", Manufacturer="Susumu Co Ltd", Power_W=100mW, Supplier Part Number 1=RG16P100KBCT-ND, TempCo="25 ppm/C", Tolerance_%=0.1%, Value2=0.1W, Value_Code=100k
R64 R66 R67 R68 R70 R191: library part CMP-0023919-1, "RES, 1.00 k, 0.1%, 0.1 W, 0603", Manufacturer="Yageo America", Power_W=100mW, Supplier Part Number 1=603-RT0603BRD071KL, TempCo="25 ppm/C", Tolerance_%=0.1%, Value2=0.1W, Value_Code=1k00, ValueDisplayed=1.00k
R65 R69 R71 R72 R73 R333 R405 R408 R410 R414 R416: library part CMP-0077731-1, "RES, 10.0 k, 1%, 0.063 W, AEC-Q200 Grade 0, 0402", Manufacturer="Yageo America", Power_W=63mW, Supplier Part Number 1=YAG3436CT-ND, TempCo="100 ppm/C", Tolerance_%=1%, Value2=0.063W, Value_Code=10k0, ValueDisplayed=10.0k
R80 R92 R100: library part CMP-0022004-4, "RES, 10.0, 1%, 0.25 W, AEC-Q200 Grade 0, 0603", Manufacturer=Vishay-Dale, Power_W=250mW, Supplier Part Number 1=541-10.0SCT-ND, TempCo="100 ppm/C", Tolerance_%=1%, Value2=0.25W, Value_Code=10R0, ValueDisplayed=10.0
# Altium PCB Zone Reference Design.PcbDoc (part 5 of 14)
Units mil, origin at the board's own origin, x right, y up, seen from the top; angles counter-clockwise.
Board outline 8858.11 x 7047.08 mil, 16 copper layers (Top Layer, GND_1, SIG_1, GND_2, PWR/SIG_1, GND_3, PWR_1, PWR_2, GND_4, PWR/SIG_2, GND_5, SIG_2, GND_6, SIG_3, GND_7, Bottom Layer), stack 80.368 mil thick; 1131 components, 808 nets, 3825 pads, 3523 vias.
Unrouted connection lines stored in the file: 563.

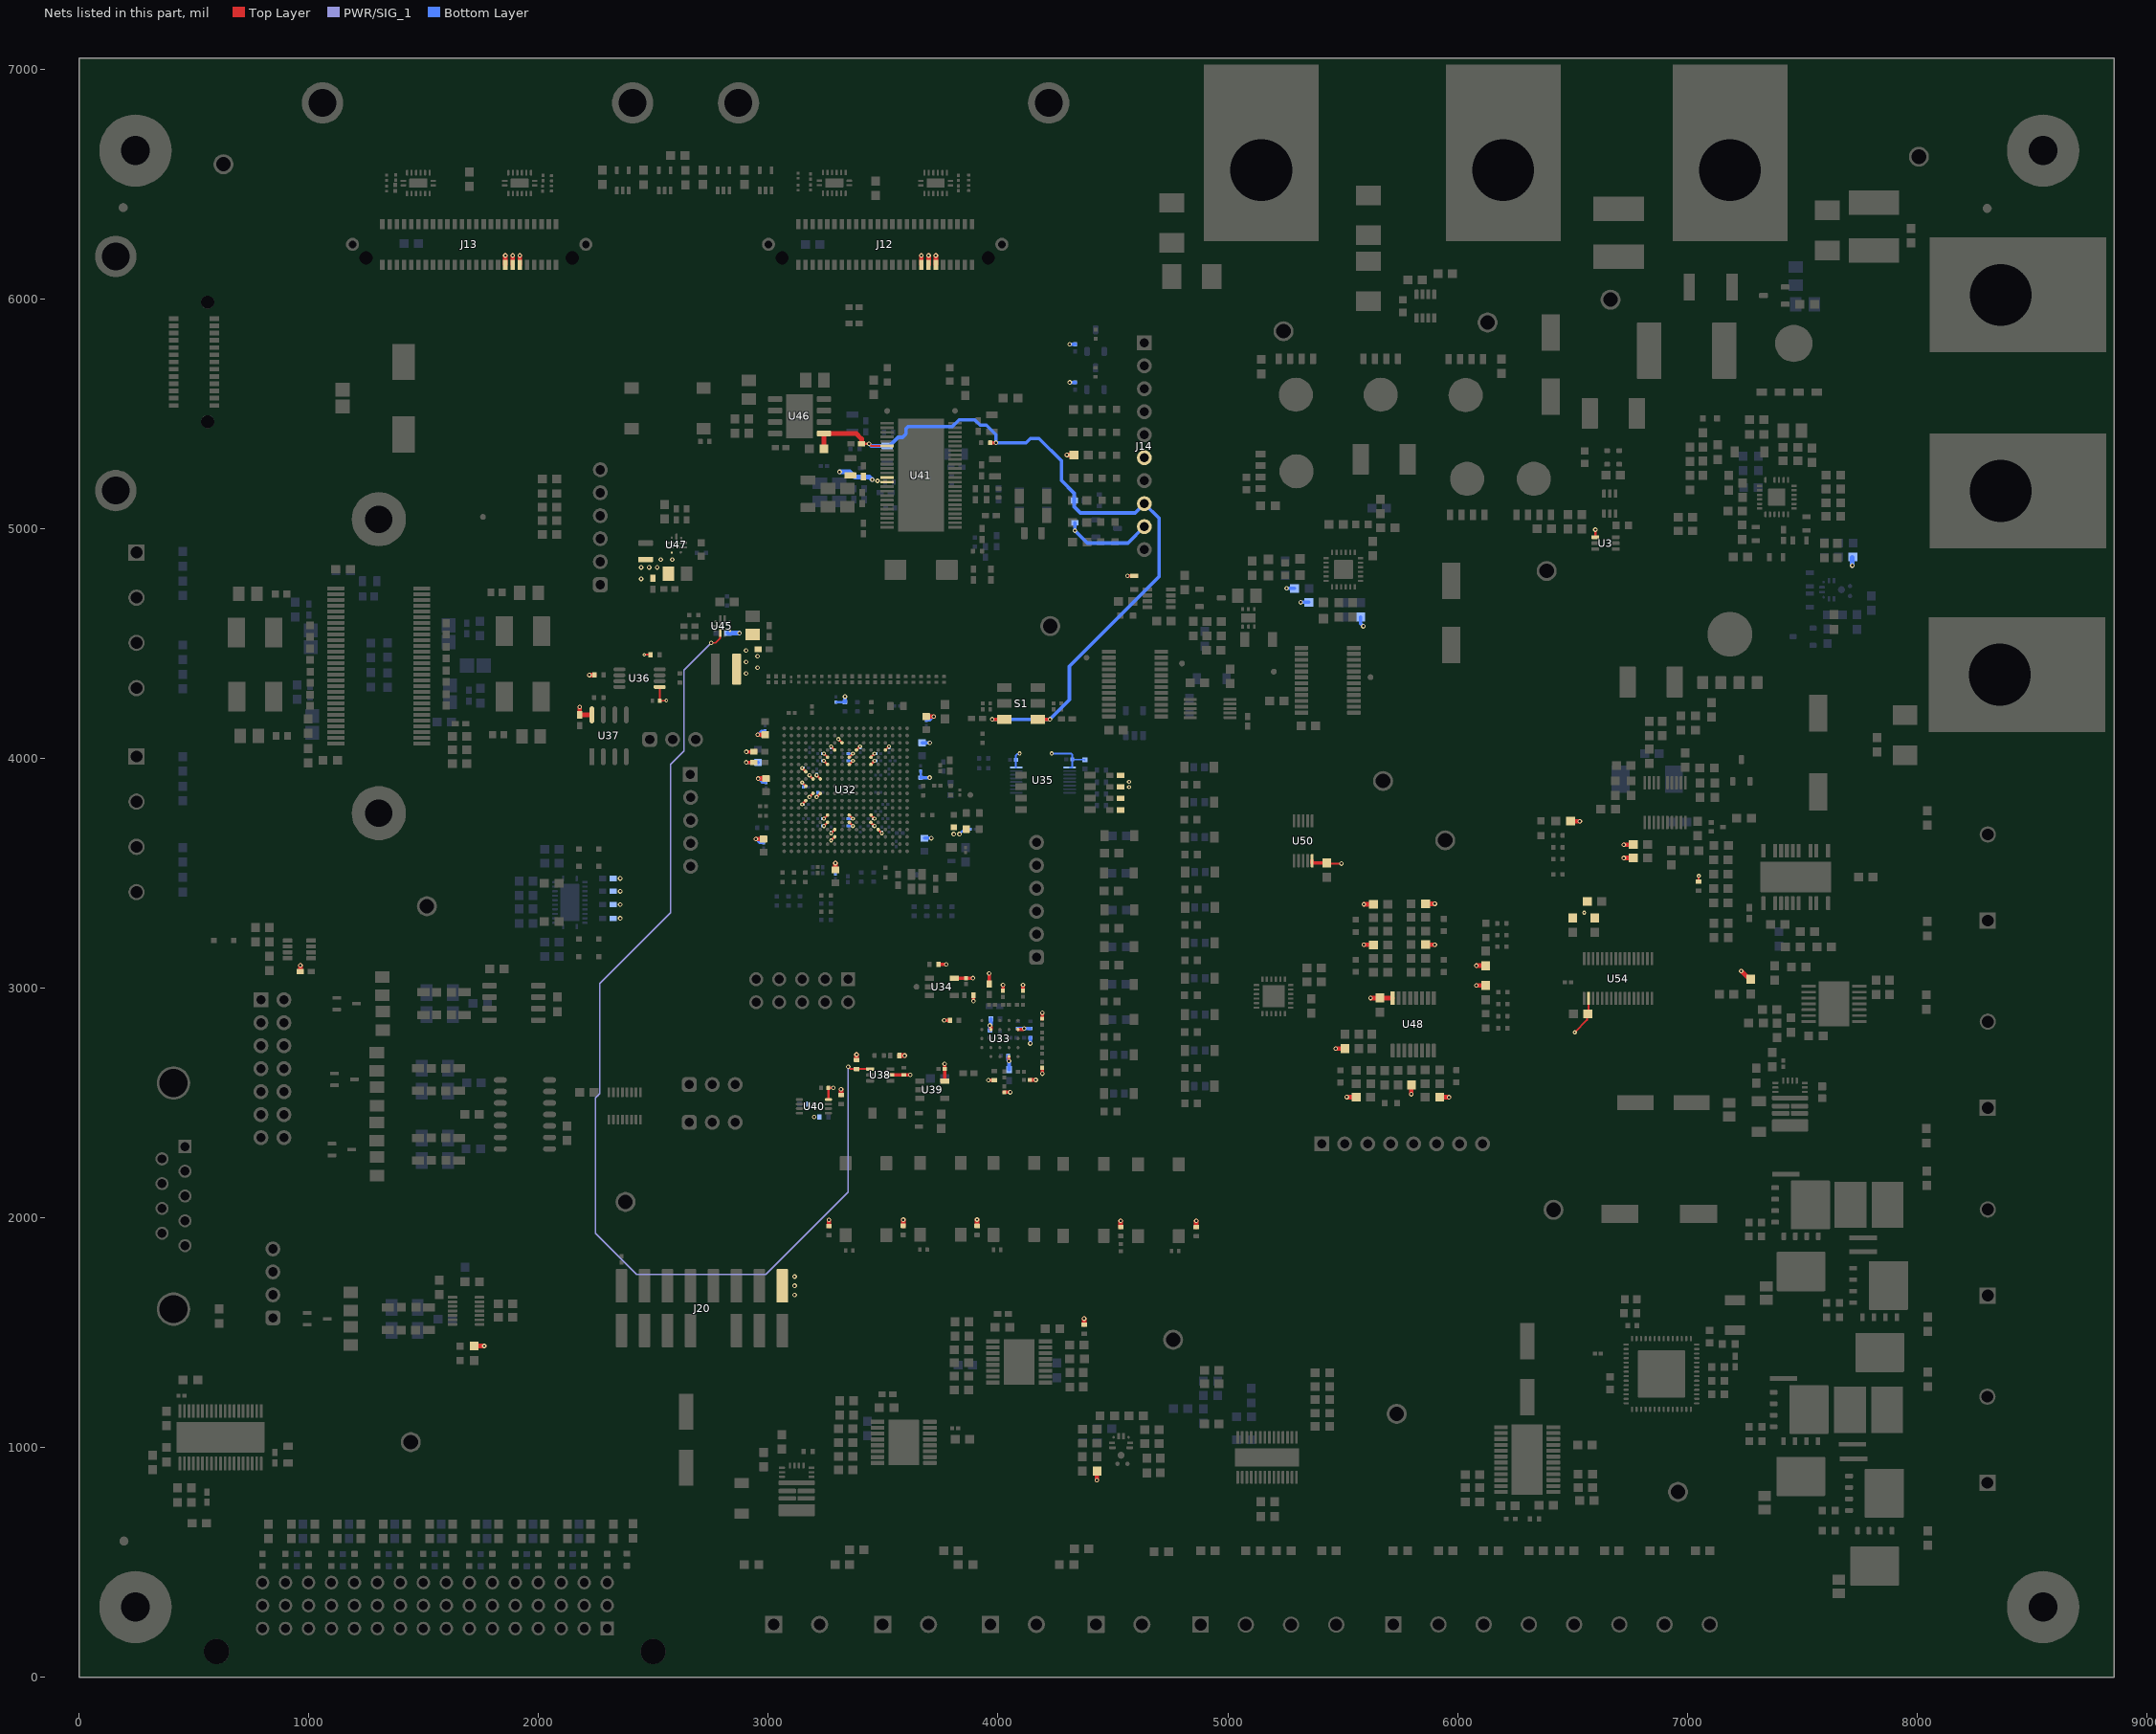
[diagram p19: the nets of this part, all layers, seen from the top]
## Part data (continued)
R81 R82 R83 R84 R86 R93 R94 R95 R99 R101 R102 R106 R109 R111 R119 R123 R124 R128 R135 R141 R142 R147: library part CMP-0023341-2, "RES, 10.0 k, 1%, 0.1 W, AEC-Q200 Grade 0, 0603", Manufacturer="Stackpole Electronics Inc", Power_W=100mW, Supplier Part Number 1=RMCF0603FT10K0CT-ND, TempCo="100 ppm/C", Tolerance_%=1%, Value2=0.1W, Value_Code=10k0, ValueDisplayed=10.0k
R85 R88 R91 R97 R104 R108 R110: library part CMP-0025700-3, "RES, 100, 5%, 0.1 W, 0603", Manufacturer=Vishay-Dale, Power_W=100mW, Supplier Part Number 1=541-100GCT-ND, TempCo="200 ppm/C", Tolerance_%=5%, Value2=0.1W, Value_Code=100R, ValueDisplayed=100
R87 R96 R103: library part CMP-0022555-5, "RES, 698, 1%, 0.1 W, AEC-Q200 Grade 0, 0603", Manufacturer=Vishay-Dale, Power_W=100mW, Supplier Part Number 1=541-698HCT-ND, TempCo="100 ppm/C", Tolerance_%=1%, Value2=0.1W, Value_Code=698R, ValueDisplayed=698
R89 R105: library part CMP-0022928-4, "RES, 22.0, 1%, 0.1 W, 0603", Manufacturer=Yageo, Power_W=100mW, Supplier Part Number 1=311-22.0HRCT-ND, TempCo="100 ppm/C", Tolerance_%=1%, Value2=0.1W, Value_Code=22R0, ValueDisplayed=22.0
R90 R107 R158 R167 R178 R263 R264 R265 R277 R278 R283 R284 R285 R286 R287 R288 R289 R290 R291 R316 R317 R320 R321 R323 R326 R327 R328 R330 R336 R337 R338 R343 R346 R347 R412: library part CMP-0094798-1, "Res Thick Film 0402 10K Ohm 5% 0.063W(1/16W) ±100ppm/C Pad SMD T/R", Digikey Part Number=311-10KJRCT-ND, Manufacturer=YAGEO, Mouser Part Number=603-RC0402JR-0710KL, Operating Temperature Range="-55°C to +155°C", Power_W=63mW, TempCo=100ppm/°C, Tolerance_%=5%
R98 R159 R170 R187 R232 R233 R234 R235 R236 R237 R247 R248 R249 R250 R251 R252 R266 R267 R268 R269 R270 R271 R272 R273 R274 R340 R359 R360 R361 R362 R363 R364 R365 R366 R367 R449: library part CMP-0027500-1, "RES, 22.0, 1%, 0.05 W, 0201", Manufacturer="Yageo America", Power_W=50mW, Supplier Part Number 1=YAG2518CT-ND, TempCo="200 ppm/C", Tolerance_%=1%, Value2=0.05W, Value_Code=22R0, ValueDisplayed=22.0
R112 R113 R115 R116 R117 R118 R120 R121 R125 R129 R132 R134 R136 R137 R139 R140 R144 R145 R146 R301 R303 R305 R307: library part CMP-0022458-4, "RES, 4.99 k, 1%, 0.1 W, AEC-Q200 Grade 0, 0603", Manufacturer=Vishay-Dale, Power_W=100mW, Supplier Part Number 1=541-4.99KHCT-ND, TempCo="100 ppm/C", Tolerance_%=1%, Value2=0.1W, Value_Code=4k99, ValueDisplayed=4.99k
R114 R127 R131 R143 R148: library part CMP-0084244-1, "RES, 1.0 k, 5%, 0.25 W, AEC-Q200 Grade 0, 0603", Manufacturer=Rohm, Power_W=250mW, TempCo="200 ppm/C", Tolerance_%=5%, Value2=0.25W, Value_Code=1k00, ValueDisplayed=1.0k
R122: library part CMP-0022205-4, "RES, 20.5 k, 1%, 0.1 W, AEC-Q200 Grade 0, 0603", Manufacturer=Vishay-Dale, Power_W=100mW, Supplier Part Number 1=541-20.5KHCT-ND, TempCo="100 ppm/C", Tolerance_%=1%, Value2=0.1W, Value_Code=20k5, ValueDisplayed=20.5k
R126: library part CMP-0022548-4, "RES, 66.5 k, 1%, 0.1 W, AEC-Q200 Grade 0, 0603", Manufacturer=Vishay-Dale, Power_W=100mW, Supplier Part Number 1=541-66.5KHCT-ND, TempCo="100 ppm/C", Tolerance_%=1%, Value2=0.1W, Value_Code=66k5, ValueDisplayed=66.5k
R130 R133 R212 R325 R401 R464 R468 R469 R482: library part CMP-0025686-1, "RES, 10.0 k, 0.1%, 0.1 W, AEC-Q200 Grade 1, 0603", Manufacturer=Vishay-Dale, Power_W=100mW, Supplier Part Number 1=TNP10.0KAACT-ND, TempCo="25 ppm/C", Tolerance_%=0.1%, Value2=0.1W, Value_Code=10k0, ValueDisplayed=10.0k
R138: library part CMP-0022081-1, "RES, 16.9 k, 1%, 0.1 W, 0603", Manufacturer=Vishay-Dale, Power_W=100mW, Supplier Part Number 1=541-16.9KHCT-ND, TempCo="100 ppm/C", Tolerance_%=1%, Value2=0.1W, Value_Code=16k9, ValueDisplayed=16.9k
R149: library part CMP-0022228-4, "RES, 23.2 k, 1%, 0.1 W, AEC-Q200 Grade 0, 0603", Manufacturer=Vishay-Dale, Power_W=100mW, Supplier Part Number 1=541-23.2KHCT-ND, TempCo="100 ppm/C", Tolerance_%=1%, Value2=0.1W, Value_Code=23k2, ValueDisplayed=23.2k
R150 R151 R152 R156 R157 R160 R161 R163 R164 R294 R296 R298 R300 R302 R304 R306 R308 R309 R311 R312 R313 R314 R315: library part CMP-0025697-4, "RES, 0, 5%, 0.1 W, AEC-Q200 Grade 0, 0603", Manufacturer=Vishay-Dale, PartNumber=CRCW06030000Z0EA, Power_W=100mW, Supplier Part Number 1=541-0.0GCT-ND, TempCo="200 ppm/C", Tolerance_%=5%, Value2=0.1W, Value_Code=0000, ValueDisplayed=0
R153: library part CMP-0026822-1, "RES, 0, 5%, 0.063 W, 0402", Manufacturer=Vishay-Dale, Power_W=63mW, Supplier Part Number 1=541-0.0JCT-ND, TempCo="200 ppm/C", Tolerance_%=5%, Value2=0.063W, Value_Code=0000, ValueDisplayed=0
R154 R162: library part CMP-0086254-1, "RES, 0.007, 1%, 7 W, AEC-Q200 Grade 0, 7.1x4.6mm", Manufacturer=Vishay-Dale, Power_W=7W, TempCo="75 ppm/C", Tolerance_%=1%, Value_Code=7L000, ValueDisplayed=0.007
R155: library part CMP-0086251-1, "RES, 10.0 k, 0.05%, 0.1 W, AEC-Q200 Grade 0, 0603", Manufacturer=Panasonic, Power_W=100mW, TempCo="10 ppm/C", Tolerance_%=0.05%, Value2=0.1W, Value_Code=10k0, ValueDisplayed=10.0k
R165 R166: library part CMP-0025886-3, "RES, 10 k, 5%, 0.1 W, 0603", Manufacturer="Yageo America", Power_W=100mW, Supplier Part Number 1=311-10KGRCT-ND, TempCo="100 ppm/C", Tolerance_%=5%, Value2=0.1W, Value_Code=10k0, ValueDisplayed=10k
R168 R169: library part CMP-0022109-5, "RES, 1.00 k, 1%, 0.1 W, AEC-Q200 Grade 0, 0603", Manufacturer=Vishay-Dale, Power_W=100mW, Supplier Part Number 1=541-1.00KHCT-ND, TempCo="100 ppm/C", Tolerance_%=1%, Value2=0.1W, Value_Code=1k00, ValueDisplayed=1.00k
R171: library part CMP-0025706-4, "RES, 110, 5%, 0.1 W, AEC-Q200 Grade 0, 0603", Manufacturer=Vishay-Dale, Power_W=100mW, Supplier Part Number 1=541-110GCT-ND, TempCo="200 ppm/C", Tolerance_%=5%, Value2=0.1W, Value_Code=110R, ValueDisplayed=110
R172 R173 R174: library part CMP-0025817-4, "RES, 4.7 k, 5%, 0.1 W, AEC-Q200 Grade 0, 0603", Manufacturer=Vishay-Dale, Power_W=100mW, Supplier Part Number 1=541-4.7KGCT-ND, TempCo="200 ppm/C", Tolerance_%=5%, Value2=0.1W, Value_Code=4k70, ValueDisplayed=4.7k
R175 R176 R177 R179: library part CMP-0025823-4, "RES, 510, 5%, 0.1 W, AEC-Q200 Grade 0, 0603", Manufacturer=Vishay-Dale, Power_W=100mW, Supplier Part Number 1=541-510GCT-ND, TempCo="200 ppm/C", Tolerance_%=5%, Value2=0.1W, Value_Code=510R, ValueDisplayed=510
R180 R181 R183 R184 R186 R188 R189 R190 R192 R193 R194 R195 R196 R197 R198 R199 R200 R201 R202 R203 R204 R205 R206 R207: library part CMP-0022733-1, "RES, 220, 1%, 0.125 W, 0603", Manufacturer=Vishay/Beyschlag, Power_W=125mW, Supplier Part Number 1=MCT0603-220-CFCT-ND, TempCo="50 ppm/C", Tolerance_%=1%, Value2=0.125W, Value_Code=220R, ValueDisplayed=220
R182 R185 R446 R447 R448 R450 R451 R470: library part CMP-0022684-2, "RES, 10.0 k, 1%, 0.1 W, 0603", Manufacturer=Panasonic, Power_W=100mW, Supplier Part Number 1=P10.0KHCT-ND, TempCo="100 ppm/C", Tolerance_%=1%, Value2=0.1W, Value_Code=10k0, ValueDisplayed=10.0k
R208 R310: library part CMP-0065361-1, "RES, 0, 5%, .05 W, AEC-Q200 Grade 0, 0201", Manufacturer=Panasonic, Power_W=50mW, Supplier Part Number 1=P15979CT-ND, TempCo=ppm/C, Tolerance_%=5%, Value2=.05W, Value_Code=0000, ValueDisplayed=0
R213: library part CMP-0025876-1, "RES, 1.2 k, 5%, 0.1 W, AEC-Q200 Grade 0, 0603", Manufacturer=Panasonic, Power_W=100mW, Supplier Part Number 1=P1.2KGCT-ND, TempCo="200 ppm/C", Tolerance_%=5%, Value2=0.1W, Value_Code=1k20, ValueDisplayed=1.2k
R221 R222 R259: library part CMP-0026938-5, "RES, 4.7 k, 5%, 0.063 W, AEC-Q200 Grade 0, 0402", Manufacturer=Vishay-Dale, Power_W=63mW, Supplier Part Number 1=541-4.7KJCT-ND, TempCo="200 ppm/C", Tolerance_%=5%, Value2=0.063W, Value_Code=4k70, ValueDisplayed=4.7k
R223 R225 R226 R228 R230 R231 R241 R242 R243 R244 R245 R246: library part CMP-0033520-1, "0Ω ±0 0.05W 0201 Thick Film Chip Resistor AEC-Q200 compliant", Manufacturer="Stackpole Electronics", Operating Temperature Range="-55°C to +155°C", Power_W=50mW
R238 R239: library part CMP-0042990-1, "Res Thick Film 0402 1.5K Ohm 5% 1/10W ±200ppm/°C Molded SMD Punched Carrier T/R", Digikey Part Number=P1.5KJCT-ND, Manufacturer=Panasonic, Mouser Part Number=667-ERJ-2GEJ152X, Octopart Part Number=cecc048b4d5c110b, Operating Temperature Range="-55°C to +155°C", Power_W=100mW, TempCo=200ppm/°C, Tolerance_%=5%, Voltage=50V
R254 R255 R256 R257 R258 R260 R261: library part CMP-0027732-1, "RES, 49.9 k, 1%, 0.05 W, 0201", Manufacturer="Yageo America", Power_W=50mW, Supplier Part Number 1=YAG2701CT-ND, TempCo="200 ppm/C", Tolerance_%=1%, Value2=0.05W, Value_Code=49k9, ValueDisplayed=49.9k
R275 R279 R280 R281 R282 R357 R358: library part CMP-0026657-1, "RES, 1.00 k, 1%, 0.1 W, 0402", Manufacturer=Panasonic, Power_W=100mW, Supplier Part Number 1=P1.00KLCT-ND, TempCo="100 ppm/C", Tolerance_%=1%, Value2=0.1W, Value_Code=1k00, ValueDisplayed=1.00k
R276 R406 R409: library part CMP-0026823-3, "RES, 100 k, 5%, 0.063 W, AEC-Q200 Grade 0, 0402", Manufacturer=Vishay-Dale, Power_W=63mW, Supplier Part Number 1=541-100KJCT-ND, TempCo="200 ppm/C", Tolerance_%=5%, Value2=0.063W, Value_Code=100k
R324: library part CMP-0022249-4, "RES, 26.7 k, 1%, 0.1 W, AEC-Q200 Grade 0, 0603", Manufacturer=Vishay-Dale, Power_W=100mW, Supplier Part Number 1=541-26.7KHCT-ND, TempCo="100 ppm/C", Tolerance_%=1%, Value2=0.1W, Value_Code=26k7, ValueDisplayed=26.7k
R331: library part CMP-0078193-1, "RES, 1.0 k, 5%, 0.1 W, AEC-Q200 Grade 0, 0402", Manufacturer=Panasonic, Power_W=100mW, Supplier Part Number 1=P1.0KJCT-ND, TempCo="200 ppm/C", Tolerance_%=5%, Value2=0.1W, Value_Code=1k00, ValueDisplayed=1.0k
R334: library part CMP-0026920-5, "RES, 3.9 k, 5%, 0.063 W, AEC-Q200 Grade 0, 0402", Manufacturer=Vishay-Dale, Power_W=63mW, Supplier Part Number 1=541-3.9KJCT-ND, TempCo="200 ppm/C", Tolerance_%=5%, Value2=0.063W, Value_Code=3k90, ValueDisplayed=3.9k
R344 R345: library part CMP-0024300-2, "RES, 4.70 k, 0.1%, 0.1 W, 0603", Manufacturer="Yageo America", Power_W=100mW, TempCo="25 ppm/C", Tolerance_%=0.1%, Value2=0.1W, Value_Code=4k70, ValueDisplayed=4.70k
R348 R356: library part CMP-2002-00487-3, "Chip Resistor, 220 Ohm, +/- 5%, 100 mW, -55 to 155 degC, 0402 (1005 Metric), RoHS, Tape and Reel", Case Code (Imperial)=0402, Case Code (Metric)=1005, Manufacturer="Basic Passives", Max Operating Temperature="155 degC", Min Operating Temperature="-55 degC", Package Quantity=10000, Power Rating="100 mW", Resistance="220 Ohm", Tolerance=5%, Voltage Rating="50 V"
R349 R350 R351 R352 R353 R354 R355: library part CMP-0024263-2, "RES, 470, 0.1%, 0.1 W, 0603", Manufacturer="Yageo America", Power_W=100mW, TempCo="25 ppm/C", Tolerance_%=0.1%, Value2=0.1W, Value_Code=470R, ValueDisplayed=470
R368 R475: library part CMP-0025088-1, "RES, 2.21, 0.5%, 0.1 W, 0603", Manufacturer="Yageo America", Power_W=100mW, TempCo="50 ppm/C", Tolerance_%=0.5%, Value2=0.1W, Value_Code=2R21, ValueDisplayed=2.21
R369: library part CMP-0023013-5, "RES, 300, 1%, 0.1 W, 0603", Manufacturer=Yageo, Power_W=100mW, Supplier Part Number 1=311-300HRCT-ND, TempCo="100 ppm/C", Tolerance_%=1%, Value2=0.1W, Value_Code=300R, ValueDisplayed=300
R370: library part CMP-0089827-1, "1 mOhms ±1% 5W Chip Resistor 2512 (6432 Metric) Automotive AEC-Q200, Current Sense, Moisture Resistant, Pulse Withstanding Metal Element", Digikey Part Number=541-3130-1-ND, Manufacturer=Vishay, Mouser Part Number=71-WSLF25121L000FEB, Operating Temperature Range="-65°C to +170°C", Power_W=5W, TempCo=170ppm/°C, Tolerance_%=1%
R371 R372 R377 R379 R418 R419 R420 R421 R422 R423 R424 R425 R426 R427 R428 R429 R430 R431 R432 R433 R434 R435 R436 R437 R438 R439 R440 R441 R443 R445 R453 R454 R455 R459 R460 R462 R467 R476 R477: library part CMP-0025697-4, "RES, 0, 5%, 0.1 W, AEC-Q200 Grade 0, 0603", Manufacturer=Vishay-Dale, Power_W=100mW, Supplier Part Number 1=541-0.0GCT-ND, TempCo="200 ppm/C", Tolerance_%=5%, Value2=0.1W, Value_Code=0000, ValueDisplayed=0
R373: library part CMP-0022479-2, "RES, 50, 1%, 0.1 W, 0603", Manufacturer=Vishay-Dale, Power_W=100mW, Supplier Part Number 1=89M6778, TempCo="100 ppm/C", Tolerance_%=1%, Value2=0.1W, Value_Code=50R0, ValueDisplayed=50
R374: library part CMP-0022691-1, "RES, 20.0 k, 1%, 0.1 W, AEC-Q200 Grade 0, 0603", Manufacturer=Panasonic, Power_W=100mW, Supplier Part Number 1=P20.0KHCT-ND, TempCo="100 ppm/C", Tolerance_%=1%, Value2=0.1W, Value_Code=20k0, ValueDisplayed=20.0k
R376: library part CMP-0025687-2, "RES, 10.0, 0.1%, 0.1 W, 0603", Manufacturer=Vishay-Dale, Power_W=100mW, Supplier Part Number 1=TNP10.0AACT-ND, TempCo="25 ppm/C", Tolerance_%=0.1%, Value2=0.1W, Value_Code=10R0, ValueDisplayed=10.0
R381: library part CMP-0023251-5, "RES, 6.65 k, 1%, 0.1 W, 0603", Manufacturer=Yageo, Power_W=100mW, Supplier Part Number 1=311-6.65KHRCT-ND, TempCo="100 ppm/C", Tolerance_%=1%, Value2=0.1W, Value_Code=6k65, ValueDisplayed=6.65k
R382: library part CMP-0022934-5, "RES, 23.7 k, 1%, 0.1 W, 0603", Manufacturer=Yageo, Power_W=100mW, Supplier Part Number 1=311-23.7KHRCT-ND, TempCo="100 ppm/C", Tolerance_%=1%, Value2=0.1W, Value_Code=23k7, ValueDisplayed=23.7k
R383: library part CMP-0022875-5, "RES, 1.33 k, 1%, 0.1 W, 0603", Manufacturer=Yageo, Power_W=100mW, Supplier Part Number 1=311-1.33KHRCT-ND, TempCo="100 ppm/C", Tolerance_%=1%, Value2=0.1W, Value_Code=1k33, ValueDisplayed=1.33k
R385: library part CMP-0022731-2, "RES, 1.00 M, 1%, 0.125 W, 0603", Manufacturer=Vishay/Beyschlag, Power_W=125mW, Supplier Part Number 1=MCT0603-1.00M-CFCT-ND, TempCo="50 ppm/C", Tolerance_%=1%, Value2=0.125W, Value_Code=1M00, ValueDisplayed=1.00M
R386 R389 R396 R397: library part CMP-0025805-4, "RES, 3.3, 5%, 0.1 W, AEC-Q200 Grade 0, 0603", Manufacturer=Vishay-Dale, Power_W=100mW, Supplier Part Number 1=541-3.3GCT-ND, TempCo="200 ppm/C", Tolerance_%=5%, Value2=0.1W, Value_Code=3R30, ValueDisplayed=3.3
R393 R394 R395: library part CMP-0082530-1, "RES, 100 k, 5%, 0.1 W, 0603", Manufacturer=Vishay-Dale, Power_W=100mW, Supplier Part Number 1=541-3992-1-ND, TempCo="200 ppm/C", Tolerance_%=5%, Value2=0.1W, Value_Code=100k
R398: library part CMP-0024280-3, "RES, 499 k, 0.1%, 0.1 W, 0603", Manufacturer="Yageo America", Power_W=100mW, TempCo="25 ppm/C", Tolerance_%=0.1%, Value2=0.1W, Value_Code=499k
R399: library part CMP-0023920-1, "RES, 200 k, 0.1%, 0.1 W, 0603", Manufacturer="Yageo America", Power_W=100mW, TempCo="25 ppm/C", Tolerance_%=0.1%, Value2=0.1W, Value_Code=200k
R400: library part CMP-0023826-3, "RES, 180 k, 0.1%, 0.1 W, 0603", Manufacturer="Yageo America", Power_W=100mW, TempCo="25 ppm/C", Tolerance_%=0.1%, Value2=0.1W, Value_Code=180k
R402: library part CMP-0022579-4, "RES, 715 k, 1%, 0.1 W, AEC-Q200 Grade 0, 0603", Manufacturer=Vishay-Dale, Power_W=100mW, Supplier Part Number 1=541-715KHCT-ND, TempCo="100 ppm/C", Tolerance_%=1%, Value2=0.1W, Value_Code=715k
R403: library part CMP-0022200-4, "RES, 200 k, 1%, 0.1 W, AEC-Q200 Grade 0, 0603", Manufacturer=Vishay-Dale, Power_W=100mW, Supplier Part Number 1=541-200KHCT-ND, TempCo="100 ppm/C", Tolerance_%=1%, Value2=0.1W, Value_Code=200k
R407: library part CMP-0022090-4, "RES, 17.8 k, 1%, 0.1 W, AEC-Q200 Grade 0, 0603", Manufacturer=Vishay-Dale, Power_W=100mW, Supplier Part Number 1=541-17.8KHCT-ND, TempCo="100 ppm/C", Tolerance_%=1%, Value2=0.1W, Value_Code=17k8, ValueDisplayed=17.8k
R415: library part CMP-0023415-3, "RES, 11.0 k, 0.1%, 0.1 W, 0603", Manufacturer="Susumu Co Ltd", Power_W=100mW, Supplier Part Number 1=RG16P11.0KBCT-ND, TempCo="25 ppm/C", Tolerance_%=0.1%, Value2=0.1W, Value_Code=11k0, ValueDisplayed=11.0k
R417: library part CMP-0026207-1, "RES, 26.1 k, 1%, 0.063 W, 0402", Manufacturer=Vishay-Dale, Power_W=63mW, Supplier Part Number 1=541-26.1KLCT-ND, TempCo="100 ppm/C", Tolerance_%=1%, Value2=0.063W, Value_Code=26k1, ValueDisplayed=26.1k
R442: library part CMP-0025764-4, "RES, 270 k, 5%, 0.1 W, AEC-Q200 Grade 0, 0603", Manufacturer=Vishay-Dale, Power_W=100mW, Supplier Part Number 1=541-270KGCT-ND, TempCo="200 ppm/C", Tolerance_%=5%, Value2=0.1W, Value_Code=270k
R444: library part CMP-0022008-4, "RES, 110 k, 1%, 0.1 W, AEC-Q200 Grade 0, 0603", Manufacturer=Vishay-Dale, Power_W=100mW, Supplier Part Number 1=541-110KHCT-ND, TempCo="100 ppm/C", Tolerance_%=1%, Value2=0.1W, Value_Code=110k
R452: library part CMP-0098465-1, "1 Ohms ±1% 3W Chip Resistor 2010 (5025 Metric) Automotive AEC-Q200, Current Sense, Moisture Resistant, Pulse Withstanding", Digikey Part Number=4423-VMP-1R00-1.0-UCT-ND, Manufacturer=Isabellenhuette, Operating Temperature Range="-65°C to +170°C", Power_W=3W, TempCo=20ppm/°C, Tolerance_%=1%
R456: library part CMP-0021863-2, "RES, 10.0, 1%, 0.125 W, 0805", Manufacturer="Yageo America", Power_W=125mW, Supplier Part Number 1=311-10.0CRCT-ND, TempCo="200 ppm/C", Tolerance_%=1%, Value2=0.125W, Value_Code=10R0, ValueDisplayed=10.0
R457: library part CMP-0092921-1, "Res Metal Strip 3921 0.0005 Ohm 1% 3W ±175ppm/°C Molded SMD SMD Embossed Plastic T/R", Digikey Part Number=WSLM-.0005CT-ND, Manufacturer="Vishay Dale", Mouser Part Number=71-WSL3921L5000FEA, Operating Temperature Range="-65°C to +170°C", Power_W=3W, TempCo=150ppm/°C, Tolerance_%=1%
R458: library part CMP-0022679-3, "RES, 100, 1%, 0.1 W, AEC-Q200 Grade 0, 0603", Manufacturer=Panasonic, Power_W=100mW, Supplier Part Number 1=P100HCT-ND, TempCo="100 ppm/C", Tolerance_%=1%, Value2=0.1W, Value_Code=100R, ValueDisplayed=100
R461: library part CMP-0022773-5, "RES, 124, 1%, 0.1 W, 0603", Manufacturer=Yageo, Power_W=100mW, Supplier Part Number 1=311-124HRCT-ND, TempCo="100 ppm/C", Tolerance_%=1%, Value2=0.1W, Value_Code=124R, ValueDisplayed=124
R463: library part CMP-0023007-4, "RES, 2.21, 1%, 0.1 W, 0603", Manufacturer=Yageo, Power_W=100mW, Supplier Part Number 1=311-2.21HRCT-ND, TempCo="200 ppm/C", Tolerance_%=1%, Value2=0.1W, Value_Code=2R21, ValueDisplayed=2.21
R465: library part CMP-0023288-5, "RES, 820, 1%, 0.1 W, 0603", Manufacturer=Yageo, Power_W=100mW, Supplier Part Number 1=311-820HRCT-ND, TempCo="100 ppm/C", Tolerance_%=1%, Value2=0.1W, Value_Code=820R, ValueDisplayed=820
R466: library part CMP-0022895-5, "RES, 1.00 k, 1%, 0.1 W, 0603", Manufacturer=Yageo, Power_W=100mW, Supplier Part Number 1=311-1.00KHRCT-ND, TempCo="100 ppm/C", Tolerance_%=1%, Value2=0.1W, Value_Code=1k00, ValueDisplayed=1.00k
R471: library part CMP-0023153-5, "RES, 4.70 k, 1%, 0.1 W, 0603", Manufacturer=Yageo, Power_W=100mW, Supplier Part Number 1=311-4.70KHRCT-ND, TempCo="100 ppm/C", Tolerance_%=1%, Value2=0.1W, Value_Code=4k70, ValueDisplayed=4.70k
R472: library part CMP-0021990-4, "RES, 100 k, 1%, 0.1 W, AEC-Q200 Grade 0, 0603", Manufacturer=Vishay-Dale, Power_W=100mW, Supplier Part Number 1=541-100KHCT-ND, TempCo="100 ppm/C", Tolerance_%=1%, Value2=0.1W, Value_Code=100k
R473: library part CMP-0023989-3, "RES, 24.6 k, 0.1%, 0.1 W, 0603", Manufacturer="Yageo America", Power_W=100mW, TempCo="25 ppm/C", Tolerance_%=0.1%, Value2=0.1W, Value_Code=24k6, ValueDisplayed=24.6k
R474: library part CMP-0088875-1, "220 Ohms ±1% 2W Chip Resistor 2010 (5025 Metric)  Thick Film", Digikey Part Number=A143179CT-ND, Manufacturer=TE, Mouser Part Number=279-3502220RFT, Operating Temperature Range="-55°C to +155°C", Power_W=2W, TempCo=100ppm/°C, Tolerance_%=1%
RNTC_1: library part CMP-0095715-1, "NTC Thermistor for Temperature Sensor, Automotive, 0603, 47kΩ, 5%, 0.046mA, 5V", B Tolerance=1%, Digikey Part Number=490-NCU18WB473D60RBTR-ND, Manufacturer=Murata, Max Current=0.046mA, Mouser Part Number=81-NCU18WB473D60RB, Operating Temperature Range="-40°C to +150℃", Tolerance_%=5%
S1: library part CMP-0002233-1, "Switch, Dual SPDT,  2 Pos, 0.1A, 6VDC, SMD", CurrentRating_mA=100A, Manufacturer="Copal Electronics", Supplier Part Number 1=CASD20JCT-ND
SW1: library part CMP-0093176-1, "Dip Switch SPST 4 Position Surface Mount Slide (Standard) Actuator 25mA 24VDC", Coil Resistance_ohm=100mΩ, Contact Current Rating=25mA, Digikey Part Number=732-3854-1-ND, Manufacturer=Wurth, Mouser Part Number=710-416131160804, Operating Temperature Range="-40°C to +85°C"
SW2 SW3 SW4 SW5 SW6 SW7: library part CMP-0097324-1, "Switch Tactile N.O. SPST Round Button Gull Wing 0.05A 12VDC 1000000Cycles 1.57N SMD Reel", Coil Resistance_ohm=100mΩ, Contact Current Rating=50mA, Digikey Part Number=732-7005-1-ND, Manufacturer="Wurth Electronics", Mouser Part Number=710-430182050816, Operating Force=160gf, Operating Temperature Range="-40°C to +85°C"
T1 T2 T3 T4 T5 T6: library part CMP-0075010-2, "Terminal 70A Lug", Manufacturer=Panduit, Supplier Part Number 1=CXS70-14-C-ND
T7: library part CMP-0860463-2, "Automotive 150-mA high-voltage ultra-low-IQ low-dropout (LDO) linear regulator, DRV0006A (WSON-6)", Alternate Manufacturer="Texas Instruments", Operating Temperature Range="-40 to 150 C", Rating=Automotive
TP1 TP2 TP3 TP4: library part CMP-0055147-2, "Test Point, Multipurpose, Red, TH", Color=Red, Manufacturer="Keystone Electronics", Supplier Part Number 1=36-5010-ND
TP5 TP6 TP7 TP8 TP9 TP22 TP23 TP24 TP25 TP26: library part CMP-0078143-3, "TEST POINT.  No entry in BOM.", Manufacturer=N/A
TP10 TP11 TP12 TP13 TP14 TP15 TP16 TP17 TP18 TP19 TP20 TP21: library part CMP-0055148-2, "Test Point, Multipurpose, Black, TH", Color=Black, Manufacturer="Keystone Electronics", Supplier Part Number 1=36-5011-ND
U1: library part CMP-0122616-1, "Automotive ideal diode with circuit breaker, under- and overvoltage protection with fault output 24-VQFN -40 to 125", Digikey Part Number=296-LM74900QRGERQ1CT-ND, Manufacturer="Texas Instruments", Max Supply Voltage=65V, Min Supply Voltage=3V, Mouser Part Number=595-LM74900QRGERQ1, Nominal Supply Current=630-635uA, Operating Temperature Range="-40°C to +125°C"
U2: library part CMP-0121214-1, "SP Amp Current Sense Amp Single R-R O/P 5.5V Automotive AEC-Q100 6-Pin SC-70 T/R", Digikey Part Number=296-INA186A3QDCKRQ1CT-ND, Input Bias Current=0.0005uA, Input Offset Voltage=-0.003mV, Manufacturer="Texas Instruments", Max Supply Voltage=5.5V, Min Supply Voltage=1.7V, Mouser Part Number=595-INA186A3QDCKRQ1, Nominal Supply Current=48uA, Operating Temperature Range="-40°C to +125°C", Voltage Gain=0.1V/mV
U3: library part CMP-0081107-1, "5.5-V, 1.5-A, 100-mohm Load Switch with Output Discharge, DCK0006A (SOT-SC70-6)", Alternate Manufacturer="Texas Instruments", Alternate PartNumber=TPS22919DCKR
U4: library part CMP-0122213-1, "Automotive Ideal Diode Controller With External FET Health Indication", Digikey Part Number=296-LM74703QDDFRQ1CT-ND, Manufacturer="Texas Instruments", Max Supply Voltage=65V, Min Supply Voltage=3.2V, Mouser Part Number=595-LM74703QDDFRQ1, Nominal Supply Current=80uA, Operating Temperature Range="-40°C to +125°C"
U5: library part CMP-0089855-1, "Low-Power Fault Protected CAN FD Transceiver with INH and WAKE", Manufacturer="Texas Instruments", Max Supply Voltage=28V, Min Supply Voltage=1.7V, Operating Temperature Range="-40°C to +125°C"
U6: library part CMP-0032674-1, "CAN Interface IC Automotive high speed CAN transceiver 8-SOIC -40 to 125", Digikey Part Number=296-TCAN1044VDRQ1CT-ND, Manufacturer="Texas Instruments", Max Supply Voltage=5.5V, Min Supply Voltage=4.5V, Mouser Part Number=595-TCAN1044VDRQ1, Nominal Supply Current=4.5-49mA, Operating Temperature Range="-40°C to +125°C"
U7: library part CMP-0013023-1, "Automotive High Speed Dual CAN Transceiver, D0014A (SOIC-14)", Alternate Manufacturer="Texas Instruments"
U8: library part CMP-0860151-2, "SN3257QDYYRQ1, DYY0016A (SOT-23-THIN-16)", Alternate Manufacturer="Texas Instruments"
U10: library part CMP-0088554-1, "Local Interconnect Network (LIN) Transceiver with Local Wake and Inhibit", Manufacturer="Texas Instruments", Max Supply Voltage=36V, Min Supply Voltage=5.5V, Nominal Supply Current=300-1200uA, Operating Temperature Range="-40°C to +125°C"
U11: library part CMP-0081959-1, "Quad Local Interconnect Network (LIN) Transceiver with Dominant State Timeout, RGY0024C (VQFN-24)", Alternate Manufacturer="Texas Instruments", Alternate PartNumber=TLIN1024RGYTQ1, Operating Temperature Range="-40 to 125 C", Rating=Automotive
U12 U13 U16 U19: library part CMP-0050159-1, "Dual-Supply Hex-Buffer with Configurable Voltage Translation and Tri-State Outputs", Manufacturer="Texas Instruments", Operating Temperature Range=to, Quiescent Current=40uA
U14 U15 U17 U18: library part CMP-0051710-3, "Automotive Catalog Single Schmitt-Trigger Buffer, DCK0005A, LARGE T&R", F @ Nom Voltage(Max)(Mhz)=150, Generic Part Number=SN74LVC1G17-Q1, ICC @ Nom Voltage(Max)(mA)=0.02, Manufacturer="Texas Instruments", Operating Temperature Range(C)="-40 to 125", Rating=Automotive, tpd @ Nom Voltage(Max)(ns)=14,9,8,7, Voltage(Nom)(V)=1.8,2.5,3.3,5
U20 U21: library part CMP-0098417-1, Manufacturer="Texas Instruments", Operating Temperature Range=to
U22: library part CMP-0124507-1, "5mΩ, Automotive Dual-Channel, SPI Controlled High-Side Switch with Integrated I2 t Wire Protection and low power mode", Manufacturer="Texas Instruments", Max Supply Voltage=18V, Min Supply Voltage=6V, Nominal Supply Current=2-4.9mA, Operating Temperature Range="-40°C to +125°C"
U23: library part CMP-0094747-1, "30-mΩ, 5-A Single-Channel Smart High-Side Switch, HTSSOP14", Manufacturer="Texas Instruments", Max Supply Voltage=28V, Min Supply Voltage=2.6V, Nominal Supply Current=1.6mA, Operating Temperature Range="-40°C to +150°C"
U24: library part CMP-0123761-1, Manufacturer="Texas Instruments", Operating Temperature Range=to
U25: library part CMP-0038451-2, "1A, 120-mΩ Quad-Channel Smart High-Side Switch", Manufacturer="Texas Instruments", Max Supply Voltage=18V, Min Supply Voltage=6V, Nominal Supply Current=1.3-4.9mA, Operating Temperature Range="-40°C to +125°C"
U26: library part CMP-0127210-1, Manufacturer="Texas Instruments", Operating Temperature Range=to
U27: library part CMP-0860746-6, "Automotive Multi-Channel Smart Half-Bridge Gate Drivers With Wide Common Mode Current Sense Amplifiers, RVJ0056A (VQFN-56)", Alternate Manufacturer="Texas Instruments"
U28: library part CMP-0095863-1, "Automotive H-Bridge Driver with Integrated Current Sense and Diagnostics", Manufacturer="Texas Instruments", Max Supply Voltage=35V, Min Supply Voltage=4.5V, Nominal Supply Current=10mA, Operating Temperature Range="-40°C to +150°C", Switching Frequency=25kHz
U29: library part CMP-0096004-1, "Automotive Half Bridge Driver with Integrated Current Sense and Diagnostics", Manufacturer="Texas Instruments", Max Supply Voltage=35V, Min Supply Voltage=4.5V, Nominal Supply Current=10mA, Operating Temperature Range="-40°C to +150°C"
U30: library part CMP-0122276-1, "8-channel Configurable Low-side and High-side Driver for Automotive Relay, Lighting and Motor Control", Manufacturer="Texas Instruments", Max Supply Voltage=40V, Min Supply Voltage=3V, Nominal Supply Current=2.6-4.5mA, Operating Temperature Range="-40°C to +150°C"
U31: library part CMP-0088400-1, "Automotive, Switch Monitoring Interface 38-HTSSOP", Digikey Part Number=296-47394-1-ND, Manufacturer="Texas Instruments", Max Supply Voltage=35V, Min Supply Voltage=4.5V, Mouser Part Number=595-TIC12400QDCPRQ1, Operating Temperature Range="-40°C to +150°C"
U32: library part CMP-0001698-2, "Sitara™ Microcontroller", Frequency_Fixed=200MHz, Manufacturer="Texas Instruments", Max Supply Voltage=3.465V, Min Supply Voltage=1.14V, Operating Temperature Range=to
U33: library part CMP-0120691-1, "FLASH Memory IC 256Mbit SPI - Octal I/O 133 MHz 6 ns 24-TFBGA (6x8)", Digikey Part Number=706-IS25LX256-LHLE-ND, Frequency_Fixed=133MHz, Manufacturer=ISSI, Max Supply Voltage=3.6V, Min Supply Voltage=2.7V, Mouser Part Number=870-IS25LX256-LHLE, Nominal Supply Current=0.13-48mA, Operating Temperature Range="-40°C to +105°C"
U34 U39: library part CMP-0051588-2, "Single 2-Input Positive-AND Gate, DBV0005A, LARGE T&R", Alternate Manufacturer="Texas Instruments", F @ Nom Voltage(Max)(Mhz)=150, Generic Part Number=SN74LVC1G08, ICC @ Nom Voltage(Max)(mA)=0.01, Operating Temperature Range(C)="-40 to 125,-40 to 85", Rating=Catalog, tpd @ Nom Voltage(Max)(ns)=4.5,6,4,5, Voltage(Nom)(V)=1.8,2.5,3.3,5
U35: library part CMP-0066446-2, "4-Bit Dual-Supply Bus Transceiver with Configurable Voltage-Level Shifting and 3-State Outputs, DGV0016A (TVSOP-16)", Alternate Manufacturer="Texas Instruments"
U36: library part CMP-0860146-1, "Automotive Grade, Remote and Local Temperature Sensor with N-Factor and Series-R Correction, DGK0008A (VSSOP-8)", Alternate Manufacturer="Texas Instruments", Operating Temperature Range="-40 to 125 C", Rating=Automotive
U37: library part CMP-0122130-1, "EEPROM Serial-I2C 1M-bit 128K x 8 2.5V/3.3V/5V 8-Pin SOIC N T/R", Digikey Part Number=CAT24M01WI-GT3OSCT-ND, Frequency_Fixed=1MHz, Manufacturer="ON Semi", Max Supply Voltage=5.5V, Min Supply Voltage=1.8V, Mouser Part Number=863-CAT24M01WI-GT3, Nominal Supply Current=1-5mA, Operating Temperature Range="-40°C to +85°C"
U38: library part CMP-0051216-3, "Single 3-Input Positive-AND Gate, DCK0006A (SOT-SC70-6)", F @ Nom Voltage(Max)(Mhz)=150, Generic Part Number=SN74LVC1G11, ICC @ Nom Voltage(Max)(mA)=0.01, Manufacturer="Texas Instruments", Operating Temperature Range="-40 to 125,-40 to 85 C", Rating=Catalog, tpd @ Nom Voltage(Max)(ns)=20,7.8,6.2,4.6, Voltage(Nom)(V)=1.8,2.5,3.3,5
U40: library part CMP-0051981-2, "TRIPLE SCHMITT-TRIGGER BUFFER, DCU0008A (VSSOP-8)", F @ Nom Voltage(Max)(Mhz)=150, Generic Part Number=SN74LVC3G17, ICC @ Nom Voltage(Max)(mA)=0.01, Manufacturer="Texas Instruments", Operating Temperature Range="-40 to 125 C", Rating=Catalog, tpd @ Nom Voltage(Max)(ns)=9.2,6.2,5.4,4.1, Voltage(Nom)(V)=1.8,2.5,3.3,5
U41: library part CMP-0095884-1, "Power Management IC For Safety-Relevant Applications HTSSOP48 5 Outputs 4 LDO and 1 Synchronous Buck-Boost Regulator", Manufacturer="Texas Instruments", Max Supply Voltage=28V, Min Supply Voltage=2.3V, Operating Temperature Range="-40°C to +150°C"
U42: library part CMP-0092088-1, "100V Smart High Side controller with Protection and Diagnostics", Manufacturer="Texas Instruments", Max Supply Voltage=80V, Min Supply Voltage=3.5V, Nominal Supply Current=1uA, Operating Temperature Range=to
U43: library part CMP-0123170-1, "1L Modulation, 2-MHz Digital Input 4-Channel Automotive Class-D Audio Amplifier with Current Sense and Real-time Load Diagnostics", Manufacturer="Texas Instruments", Max Supply Voltage=26.4V, Min Supply Voltage=4.5V, Nominal Supply Current=40-81mA, Operating Temperature Range="-40°C to +125°C", Part Number=TAS6764QDKQRQ1, Power At Speaker R="75W @ 4Ω"
U44: library part CMP-0098319-1, "Wide VIN 65 V Dual Channel Overvoltage & Undervoltage (OV & UV) Detector with Built-in Self-test for Automotive", Manufacturer="Texas Instruments", Max Supply Voltage=65V, Min Supply Voltage=2.7V, Nominal Supply Current=8.1-31.1uA, Operating Temperature Range="-40°C to +125°C"
U45: library part CMP-0093448-1, "3-V to 18-V, High Efficiency and Low IQ Buck Converter in QFN HR  Package with 165C Junction temperature", Manufacturer="Texas Instruments", Max Supply Voltage=18V, Min Supply Voltage=3V, Nominal Supply Current=8mA, Operating Temperature Range="-55°C to +165°C", Output Voltage=0.4-5.5V, Switching Frequency=1/2.5MHz
U46: library part CMP-0037155-1, "70-mA, 40-V, Voltage-Tracking LDO With 3-mV Tracking Tolerance", Dropout Voltage=300mV, Manufacturer="Texas Instruments", Max Supply Voltage=40V, Min Supply Voltage=3V, Nominal Supply Current=34-45uA, Operating Temperature Range="-40°C to +150°C", Output Voltage=2-40V
U47: library part CMP-0121948-1, "3-V to 18-V, 2-A, Automotive Low IQ Buck Converter with +165°C TJ", Digikey Part Number=296-TPS62902QRYTRQ1CT-ND, Manufacturer="Texas Instruments", Max Supply Voltage=18V, Min Supply Voltage=3V, Mouser Part Number=595-TPS62902QRYTRQ1, Nominal Supply Current=8mA, Operating Temperature Range="-40°C to +165°C", Output Voltage=0.4-5.5V, Switching Frequency=1/2.5MHz
U48: library part CMP-0123545-1, "Automotive 5V, bidirectional 8: 1, 1-channel multiplexer with injection current control & 1.8V logic 16-TSSOP -40 to...", Digikey Part Number=296-TMUX1308AQPWRQ1CT-ND, Manufacturer="Texas Instruments", Max Supply Voltage=5.5V, Min Supply Voltage=1.62V, Mouser Part Number=595-TMUX1308AQPWRQ1, Nominal Supply Current=1uA, On State Resistance=75Ω, Operating Temperature Range="-40°C to +125°C"
U49 U50: library part CMP-0123925-1, "Automotive Programmable logic device with eight general purpose inputs or outputs 10-VSSOP -40 to 125", Manufacturer="Texas Instruments", Operating Temperature Range=to
U51 U52: library part CMP-0123129-1, "Automotive 3.3-V, 1:1 (SPST), 10-channel general-purpose FET bus switch", Digikey Part Number=296-28890-1-ND, Manufacturer="Texas Instruments", Max Supply Voltage=3.6V, Min Supply Voltage=2.3V, Mouser Part Number=595-CCBTLV3861IPWRQ1, Nominal Supply Current=10uA, On State Resistance=5Ω, Operating Temperature Range="-40°C to +85°C"
U53: library part CMP-0051630-2, "Single Schmitt-Trigger Inverter Gate, DBV0005A (SOT-23-5)", F @ Nom Voltage(Max)(Mhz)=75, Generic Part Number=SN74AHCT1G14, ICC @ Nom Voltage(Max)(mA)=0.01, Manufacturer="Texas Instruments", Operating Temperature Range="-40 to 125 C", Rating=Catalog, tpd @ Nom Voltage(Max)(ns)=8, Voltage(Nom)(V)=5
U54: library part CMP-0122824-1, Manufacturer="Texas Instruments", Operating Temperature Range=to
U55: library part CMP-0094311-1, "Low-Voltage Translating, 16-Bit I2C-Bus, SMBus I/O Expander with Interrupt Output, Reset, and Agile I/O Configuration Registers", Frequency_Fixed=1MHz, Manufacturer="Texas Instruments", Max Supply Voltage=3.6V, Min Supply Voltage=1.08V, Nominal Supply Current=2-11uA, Operating Temperature Range="to +125°C"
U56: library part CMP-0121394-1, "Low IQ Smart High Side gate driver with I2t, Low Power Mode and Diagnostics", Manufacturer="Texas Instruments", Operating Temperature Range=to
Y2: library part CMP-0120101-2, "Crystal 25MHz ±10ppm 8pF SMD-4 2.5mm x 2mm", Frequency Stability=50ppm, Frequency Tolerance=10ppm, Frequency_Fixed=25MHz, Load Capacitance=8pF, Manufacturer=Abracon, Operating Temperature Range="-40°C to +125°C"
ZZ1: library part CMP-0003616-3
ZZ2: library part CMP-0077236-1
ZZ3: library part CMP-0077237-1
ZZ4: library part CMP-0077238-1

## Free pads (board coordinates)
  round 180 hole 121: 2(159.05,5164.44) 2(159.05,6184.13) 2(1059.36,6851.73) 2(2409.41,6851.73) 2(2870.02,6851.73) 2(4220.07,6851.73)

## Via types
v1: diameter 20, hole 10, Top Layer to Bottom Layer, tented both sides, 2450 vias
v2: diameter 18, hole 8, Top Layer to Bottom Layer, tented both sides, 400 vias
v3: diameter 32, hole 16, Top Layer to Bottom Layer, tented both sides, 348 vias
v4: diameter 19.68, hole 7.87, Top Layer to Bottom Layer, tented both sides, 245 vias
v5: diameter 16, hole 8, Top Layer to Bottom Layer, tented both sides, 60 vias
v6: diameter 16, hole 8, Top Layer to Bottom Layer, 14 vias
v7: diameter 24.8, hole 12.99, Top Layer to Bottom Layer, tented both sides, 6 vias

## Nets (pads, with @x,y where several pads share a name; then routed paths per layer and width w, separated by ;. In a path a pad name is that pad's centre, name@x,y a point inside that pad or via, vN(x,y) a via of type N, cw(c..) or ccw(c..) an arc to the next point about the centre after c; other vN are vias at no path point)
1V1: C371.1 J12.12 J12.14 J12.16 J13.12 J13.14 J13.16 J14.9 L12.2 R358.1 R414.2 U47.3 | length 629.5
  Top Layer w20: J13.16@1855.26,6147.8 v1(1855.26,6187.8) ; J13.14@1886.76,6147.8 v1(1886.76,6187.8) ; J13.12@1918.25,6147.8 v1(1918.25,6187.8) ; J12.16@3665.92,6147.8 v1(3665.92,6187.8) ; J12.14@3697.41,6147.8 v1(3697.41,6187.8) ; J12.12@3728.91,6147.8 v1(3728.91,6187.8)
  Bottom Layer w15: R358.1@4333.98,5024.82 v1(4333.98,4990.23) 4388.21,4936 4565.08,4936 J14.9@4636.77,5007.69
  other v1: 2446.36,4780.44 2446.36,4830.44 2481.36,4830.44 2516.36,4830.44 2531.72,4863.79 2581.72,4863.79
1V2: C163.1 C164.1 C165.1 C166.1 C167.1 C168.1 C169.1 C170.1 C181.1 C182.1 C183.1 C184.1 C186.1 C187.1 C188.1 C189.1 C196.1 C197.1 C198.1 C199.1 C206.1 C207.1 C208.1 C209.1 C210.1 C211.1 C212.1 C364.1 L11.2 R209.1 R211.1 R405.2 R406.2 U32.D10 U32.E9 U32.E11 U32.F9 U32.F11 U32.G5 U32.G6 U32.G13 U32.G14 U32.H3 U32.J16 U32.K5 U32.K6 U32.K13 U32.K14 U32.N5 U32.N6 U32.N13 U32.N14 U45.3 | length 1099.5
  Top Layer w9.9: v2(3147.31,3893.66) U32.D10@3163.06,3877.91 ; v2(3178.81,3830.66) U32.E9@3194.55,3846.41 ; v2(3178.81,3925.15) U32.E11@3194.55,3909.4 ; v2(3210.3,3830.66) U32.F9@3226.05,3846.41 ; v2(3210.3,3925.15) U32.F11@3226.05,3909.4 ; v2(3241.8,3704.68) U32.G5@3257.55,3720.43 ; v2(3241.8,3736.18) U32.G6@3257.55,3751.92 ; v2(3241.8,3988.14) U32.G13@3257.55,3972.4 ; v2(3241.8,4019.64) U32.G14@3257.55,4003.89 ; v2(3273.29,3641.69) U32.H3@3289.04,3657.44 ; v2(3304.79,4082.63) U32.J16@3320.54,4066.88 ; U32.K5@3352.03,3720.43 v2(3367.78,3704.68) ; U32.K6@3352.03,3751.92 v2(3367.78,3736.18) ; U32.K13@3352.03,3972.4 v2(3367.78,3988.14) ; U32.K14@3352.03,4003.89 v2(3367.78,4019.64) ; U32.N5@3446.52,3720.43 v2(3462.27,3704.68) ; U32.N6@3446.52,3751.92 v2(3462.27,3736.18) ; U32.N13@3446.52,3972.4 v2(3462.27,3988.14) ; U32.N14@3446.52,4003.89 v2(3462.27,4019.64)
  Top Layer w20: v1(2945.57,3647.85) C164.1@2978.92,3647.85 ; v1(2953.16,4102.12) C163.1@2986.4,4102.12 ; v1(2955.67,3910.84) C206.1@2989.02,3910.84 ; C207.1@3291.76,3513.66 v1(3291.76,3543.01) ; C165.1@3686.72,4181.02 v1(3719.96,4181.02)
  Bottom Layer w10: v1(2945.57,3647.85) 2962.89,3630.53 C167.1@2978.92,3630.53 ; v1(2953.16,4102.12) 2970.48,4119.44 C186.1@2986.4,4119.44 ; v1(2955.67,3910.84) 2972.99,3893.51 C209.1@2989.02,3893.51 ; v2(3147.31,3893.66) 3152.31,3888.66 C208.1@3152.31,3873.66 ; v2(3210.3,3830.66) 3215.3,3835.66 C188.1@3215.3,3850.66 ; C210.1@3291.76,3496.34 v1(3291.76,3543.01) ; C212.1@3295.95,4243.94 R211.1@3333.41,4243.94 ; C198.1@3347.27,3988.24 3367.68,3988.24 v2(3367.78,3988.14) ; C168.1@3347.27,4019.74 3367.68,4019.74 v2(3367.78,4019.64) ; C169.1@3347.52,3704.81 3367.66,3704.81 v2(3367.78,3704.68) ; C181.1@3347.52,3736.18 v2(3367.78,3736.18) ; R209.1@3662.86,3915.3 3663.08,3915.51 C211.1@3663.08,3943.97 ; C166.1@3686.72,4163.7 3702.63,4163.7 v1(3719.96,4181.02)
  Bottom Layer w15: R211.1@3333.41,4243.94 v1(3333.41,4268.11) ; R209.1@3662.86,3915.3 v1(3702.14,3915.3)
  Bottom Layer w20: R406.2@2824.1,4544.22 v1(2873.92,4544.22)
  other v1: 2902.66,4368.68 2952.66,4393.68 2902.66,4418.68 2952.66,4443.68 2902.66,4468.68
1V2_PG: R412.1 U38.1 U45.1 | length 4815.5
  Top Layer w8: v1(2751.48,4501.8) 2769.98,4501.8 2790.65,4522.46 U45.1@2790.65,4544.23 ; v1(3347.59,2656.94) 3358.02,2646.51 R412.1@3383.86,2646.51 3383.94,2646.59 U38.1@3442.95,2646.59
  PWR/SIG_1 w6: v1(2751.48,4501.8) 2632.69,4383.01 2632.69,4030.71 2574.37,3972.39 2574.37,3326.35 2266.7,3018.68 2266.7,2540.81 2247.97,2522.08 2247.97,1931.5 2426.54,1752.92 2988.73,1752.92 3347.59,2111.78 v1(3347.59,2656.94)
1V8: C296.1 C297.1 C368.1 J14.8 R339.1 R357.1 S1.3 S1.6 U41.30 U46.5 | length 3489.4
  Top Layer w10: C296.1@3406.11,5368.3 v1(3438.26,5368.3) 3447.53,5359.03 U41.30@3516.97,5359.03
  Top Layer w15: R339.1@3965.97,5373.01 3966.06,5372.91 3990.14,5372.91 v1(3990.24,5372.82) ; v1(3974.33,4169.38) S1.3@4027.44,4169.38 ; S1.6@4173.11,4169.38 v1(4226.22,4169.38)
  Top Layer w20: C368.1@3241.83,5346.01 U46.5@3241.81,5413.01 3383.05,5413.01 3406.11,5389.95 C296.1@3406.11,5368.3
  Bottom Layer w15: v1(3438.26,5368.3) 3447.53,5359.03 C297.1@3516.97,5359.03 3527.17,5359.03 3564.42,5396.28 3583.36,5396.28 3585.86,5398.78 3586.81,5398.78 3599.27,5411.24 3599.27,5412.19 3599.39,5412.31 3599.39,5433.73 3608.41,5442.75 3800.35,5442.75 3829.95,5472.34 3898.22,5472.34 3921.28,5449.28 3948.96,5449.28 3990.24,5408 v1(3990.24,5372.82) 4121.45,5372.82 4140.33,5391.7 4178.1,5391.7 4276.65,5293.15 4276.65,5207.23 4331.35,5152.53 R357.1@4331.35,5121.35 4331.35,5094.27 4358.37,5067.25 4596.33,5067.25 J14.8@4636.77,5107.69 4701.66,5042.8 4701.66,4791.66 4310.2,4400.2 4310.2,4253.36 v1(4226.22,4169.38) v1(3974.33,4169.38)
3V3_1: C171.1 C172.1 C173.1 C174.1 C175.1 C176.1 C177.1 C178.1 C179.1 C180.1 C190.1 C191.1 C220.1 C221.1 C222.1 C223.1 C224.2 C225.1 C226.1 C227.1 C254.1 C255.1 C257.1 C258.1 C263.1 C288.1 C289.1 C373.2 C382.1 C386.1 FB1.1 J14.6 J20.1 R1.2 R2.2 R3.2 R25.2 R26.2 R27.2 R65.2 R69.2 R71.2 R72.2 R73.2 R90.1 R107.1 R119.2 R123.2 R135.2 R221.2 R222.2 R254.2 R255.2 R256.2 R257.2 R258.2 R259.2 R260.2 R261.2 R263.2 R264.1 R265.2 R277.2 R278.2 R279.2 R280.2 R281.2 R282.2 R283.2 R316.1 R317.1 R320.1 R321.1 R323.1 R326.1 R327.1 R328.1 R330.1 R338.1 R346.1 R347.1 R348.2 R350.2 R356.2 R378.1 R380.1 R384.2 R401.2 R412.2 R418.2 R419.2 R420.2 R421.2 R422.2 R423.2 R424.2 R425.2 R446.1 R447.1 R448.1 U3.1 U32.D8 U32.D12 U32.H4 U32.H15 U32.L15 U32.P4 U32.R15 U33.B4 U33.D1 U33.E4 U34.5 U35.1 U35.16 U36.1 U37.8 U38.5 U39.5 U40.8 U41.37 U41.38 U48.16 U50.10 U54.2 | length 3621.5
  Top Layer w8: v6(2460,4449.64) 2460.4,4450.04 2486.96,4450.04 R317.1@2487.36,4450.44 ; U36.1@2526.88,4309.43 U36.1@2527.14,4309.18 ; U36.1@2538.16,4308.72 2527.6,4308.72 U36.1@2527.14,4309.18 ; v6(2555.89,4250.55) 2555.25,4249.92 2527.77,4249.92 C255.1@2527.14,4249.28 U36.1@2527.14,4309.18 ; R280.2@4533.13,3874.88 R280.2@4533.62,3874.39 ; v2@4569.77,3874.39 v2(4570.26,3873.9) ; C382.1@5430.09,3543.59 5432.73,3540.95 v1(5494.01,3540.95) ; R446.1@6499.76,3306.89 R446.1@6501.84,3304.81 ; v2(6510.38,2806.4) 6563.69,2859.72 6563.69,2882.38 C386.1@6567.04,2885.73 ; R447.1@6563.7,3377.01 R447.1@6564.92,3375.79 ; C386.1@6570.43,2891.55 U54.2@6570.43,2953.82 ; R107.1@7049.09,3462.09 7049.61,3462.61 7049.61,3486.85 v2(7050.12,3487.36)
  Top Layer w9.9: v2(3147.31,3799.17) U32.D8@3163.06,3814.92 ; v2(3147.31,3956.65) U32.D12@3163.06,3940.9 ; v2(3273.29,3673.18) U32.H4@3289.04,3688.93 ; v2(3273.29,4051.14) U32.H15@3289.04,4035.39 ; U32.L15@3383.53,4035.39 v2(3399.28,4051.14) ; U32.P4@3478.02,3688.93 v2(3493.77,3673.18) ; U32.R15@3509.51,4035.39 v2(3525.26,4051.14)
  Top Layer w10: U40.8@3261.32,2513.84 3261.32,2564.74 C263.1@3261.23,2564.82 v1(3282.5,2564.82) ; U3.1@6599.75,4961.32 v1(6599.75,4994.48)
  Top Layer w15: v1(2903.52,3981.77) R221.2@2937.69,3981.77 ; v1(2904.02,4027.75) R222.2@2937.69,4027.75 ; U38.5@3531.53,2621 3589.45,2621 C258.1@3589.76,2621.31 v1(3618.09,2621.31) ; R277.2@3740.2,3101.86 v1(3773.83,3101.86) ; v1(3764.98,2858.54) R265.2@3790.17,2858.54 ; v1(3767.16,2669.15) C257.1@3767.16,2647.36 U39.5@3767.21,2593.77 U39.5@3767.21,2593.77 ; U34.5@3808.87,3042.06 3859.73,3042.06 C225.1@3860.21,3042.54 v1(3890.73,3042.54) ; v1(3892.89,2942.7) R278.2@3892.89,2967.89 ; v1@3960.02,2598.02 R264.1@3983.21,2598.02 R264.1@3985.21,2598.02 ; R259.2@3960.94,3017.43 v1(3960.94,3062.47) ; v1(3964.25,2836.08) 3968.63,2831.69 U33.B4@3968.63,2818.81 ; R257.2@4021.42,2987.32 v1(4021.42,3012.51) ; R260.2@4027.24,2545.39 v1(4052.43,2545.39) ; v1@4047.37,2683.14 U33.D1@4047.37,2700.69 ; U33.E4@4086.74,2818.81 4109.74,2818.81 v1(4113.77,2822.83) ; R258.2@4108.13,2987.37 v1(4108.13,3012.55) ; R254.2@4138.77,2599.2 v1(4163.96,2599.2) ; v1(4192.38,2626.79) R255.2@4192.38,2651.98 ; R256.2@4192.38,2865.89 v1(4192.38,2891.08) ; v1(4563.55,4793.56) R401.2@4593.28,4793.56
  Top Layer w16: U50.10@5366.92,3553.51 5366.92,3545.49 5368.83,3543.59 C382.1@5430.09,3543.59
  Top Layer w20: R65.2@962.88,3071.43 v1(962.88,3098.16) ; R384.2@1719.89,1441.23 v1(1763.37,1441.23) ; v1(2179,4222.77) C254.1@2179,4188.36 2179.05,4188.41 U37.8@2231.64,4188.41 ; v1(2221.17,4361.72) R316.1@2243.65,4361.72 ; R320.1@3263.73,1963.19 v1(3263.73,1989.68) ; R323.1@3316.66,2533.53 v1(3316.66,2558.45) ; R412.2@3383.86,2685.88 v1(3383.86,2709.84) ; R321.1@3570.26,2705.19 v1(3593.49,2705.19) ; R326.1@3587.16,1964.24 v1(3587.16,1990.73) ; R328.1@3908.43,1964.81 v1(3908.43,1991.3) ; v1(4299.37,5319.52) R350.2@4337.7,5319.52 ; R90.1@4374.68,1534.09 v1(4374.68,1560.25) ; v1(4430.48,857.12) R123.2@4430.48,898.04 ; R346.1@4533.71,1959.25 v1(4533.71,1985.74) ; R347.1@4862.6,1959.46 v1(4862.6,1985.95) ; v1(5469.62,2735.89) R423.2@5510.54,2735.89 ; v1(5518.06,2524.6) R424.2@5558.99,2524.6 ; v1(5592.26,3187.59) R420.2@5633.19,3187.59 ; v1(5592.26,3363.61) R419.2@5633.19,3363.61 ; v1(5621.01,2956.02) C373.2@5661.94,2956.02 ; C373.2@5662.06,2955.9 C373.2@5661.94,2956.02 ; U48.16@5717.37,2955.64 5662.32,2955.64 C373.2@5661.94,2956.02 ; v1(5798.67,2537.24) R425.2@5798.67,2578.17 ; R421.2@5860.38,3187.99 v1(5901.31,3187.99) ; R418.2@5860.38,3366.01 v1(5901.31,3366.01) ; R422.2@5922.3,2523.95 v1(5963.22,2523.95) ; v1(6081.46,3096.77) R3.2@6122.39,3096.77 ; v1(6081.74,3010.64) R2.2@6122.67,3010.64 ; R1.2@6491.28,3725.38 v1(6532.2,3725.38) ; v1(6723.69,3565.06) R378.1@6764.61,3565.06 ; v1(6723.69,3623.08) R380.1@6764.61,3623.08 ; v1(7234.64,3073.37) 7262.07,3045.93 7268.78,3045.93 7277.48,3037.23 R119.2@7277.48,3036.25 ; C373.2@5661.94,2956.02 C373.2@5661.81,2956.15 C373.2@5661.94,2956.02
  Bottom Layer w8: U35.16@4079.27,3959.2 4077.82,3959.2 4077.76,3959.26 C226.1@4077.76,3992.04 4077.76,4012.31 4083.89,4018.44 4092.15,4018.44 v2(4094.07,4020.36) ; v2(4233.15,4020.36) 4318.14,4020.36 4322.82,4015.67 4322.82,3959.26 4322.76,3959.2 U35.1@4311.55,3959.2 ; C227.1@4322.83,3994.61 4323.86,3993.58 4376.75,3993.58 R283.2@4377.77,3992.56
  Bottom Layer w10: v1(3831.77,3669.29) 3853.82,3691.35 C191.1@3878.74,3691.35
  Bottom Layer w15: v1(2903.52,3981.77) 2904.01,3981.29 C172.1@2955.01,3981.29 ; C171.1@3669.37,4066.88 v1(3702.78,4066.88) ; C173.1@3679.66,3651.51 v1(3709.16,3651.51) ; C223.1@3964.63,2814.27 3964.63,2835.69 3968.93,2839.99 R263.2@3968.93,2864.49 ; C222.1@4043.53,2704.96 4043.53,2684.98 v1(4047.37,2681.14) 4047.89,2680.62 C224.2@4047.89,2644.04 ; C221.1@4086.79,2822.87 C220.1@4140.29,2822.87 ; v1(4140.1,2758.01) R261.2@4140.1,2783.51 ; v1(4311.5,5801.58) R348.2@4335.44,5801.58 ; v1(4311.87,5635.41) R356.2@4335.81,5635.41 ; v1(5255.75,4738.84) R25.2@5290.75,4738.84 ; v1(5317.57,4678.34) R26.2@5352.57,4678.34 ; R27.2@5578.33,4614.35 5578.33,4585.46 v1(5589.62,4574.17)
  Bottom Layer w20: v1(3310.16,5245.89) 3354.57,5245.89 3377.33,5223.12 R338.1@3402.57,5223.12 3440.88,5223.12 v1(3452.35,5211.65) ; v1(7718.06,4838.39) R135.2@7718.06,4873.39
  other v1: 3114.58,1663.25 3114.58,1703.25 3114.58,1743.25 3198.95,2438.12 3198.95,2494.15 3958.02,2598.02 2355.08,3302.64 2355.08,3362.26 2355.08,3420.28 2355.08,3476.37 3806.77,3669.29 3475.13,5206.75
  other v2: 6551.09,3327.32 4570.26,3897.04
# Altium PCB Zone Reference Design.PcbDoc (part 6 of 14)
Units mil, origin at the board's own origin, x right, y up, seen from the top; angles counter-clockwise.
Board outline 8858.11 x 7047.08 mil, 16 copper layers (Top Layer, GND_1, SIG_1, GND_2, PWR/SIG_1, GND_3, PWR_1, PWR_2, GND_4, PWR/SIG_2, GND_5, SIG_2, GND_6, SIG_3, GND_7, Bottom Layer), stack 80.368 mil thick; 1131 components, 808 nets, 3825 pads, 3523 vias.
Unrouted connection lines stored in the file: 563.

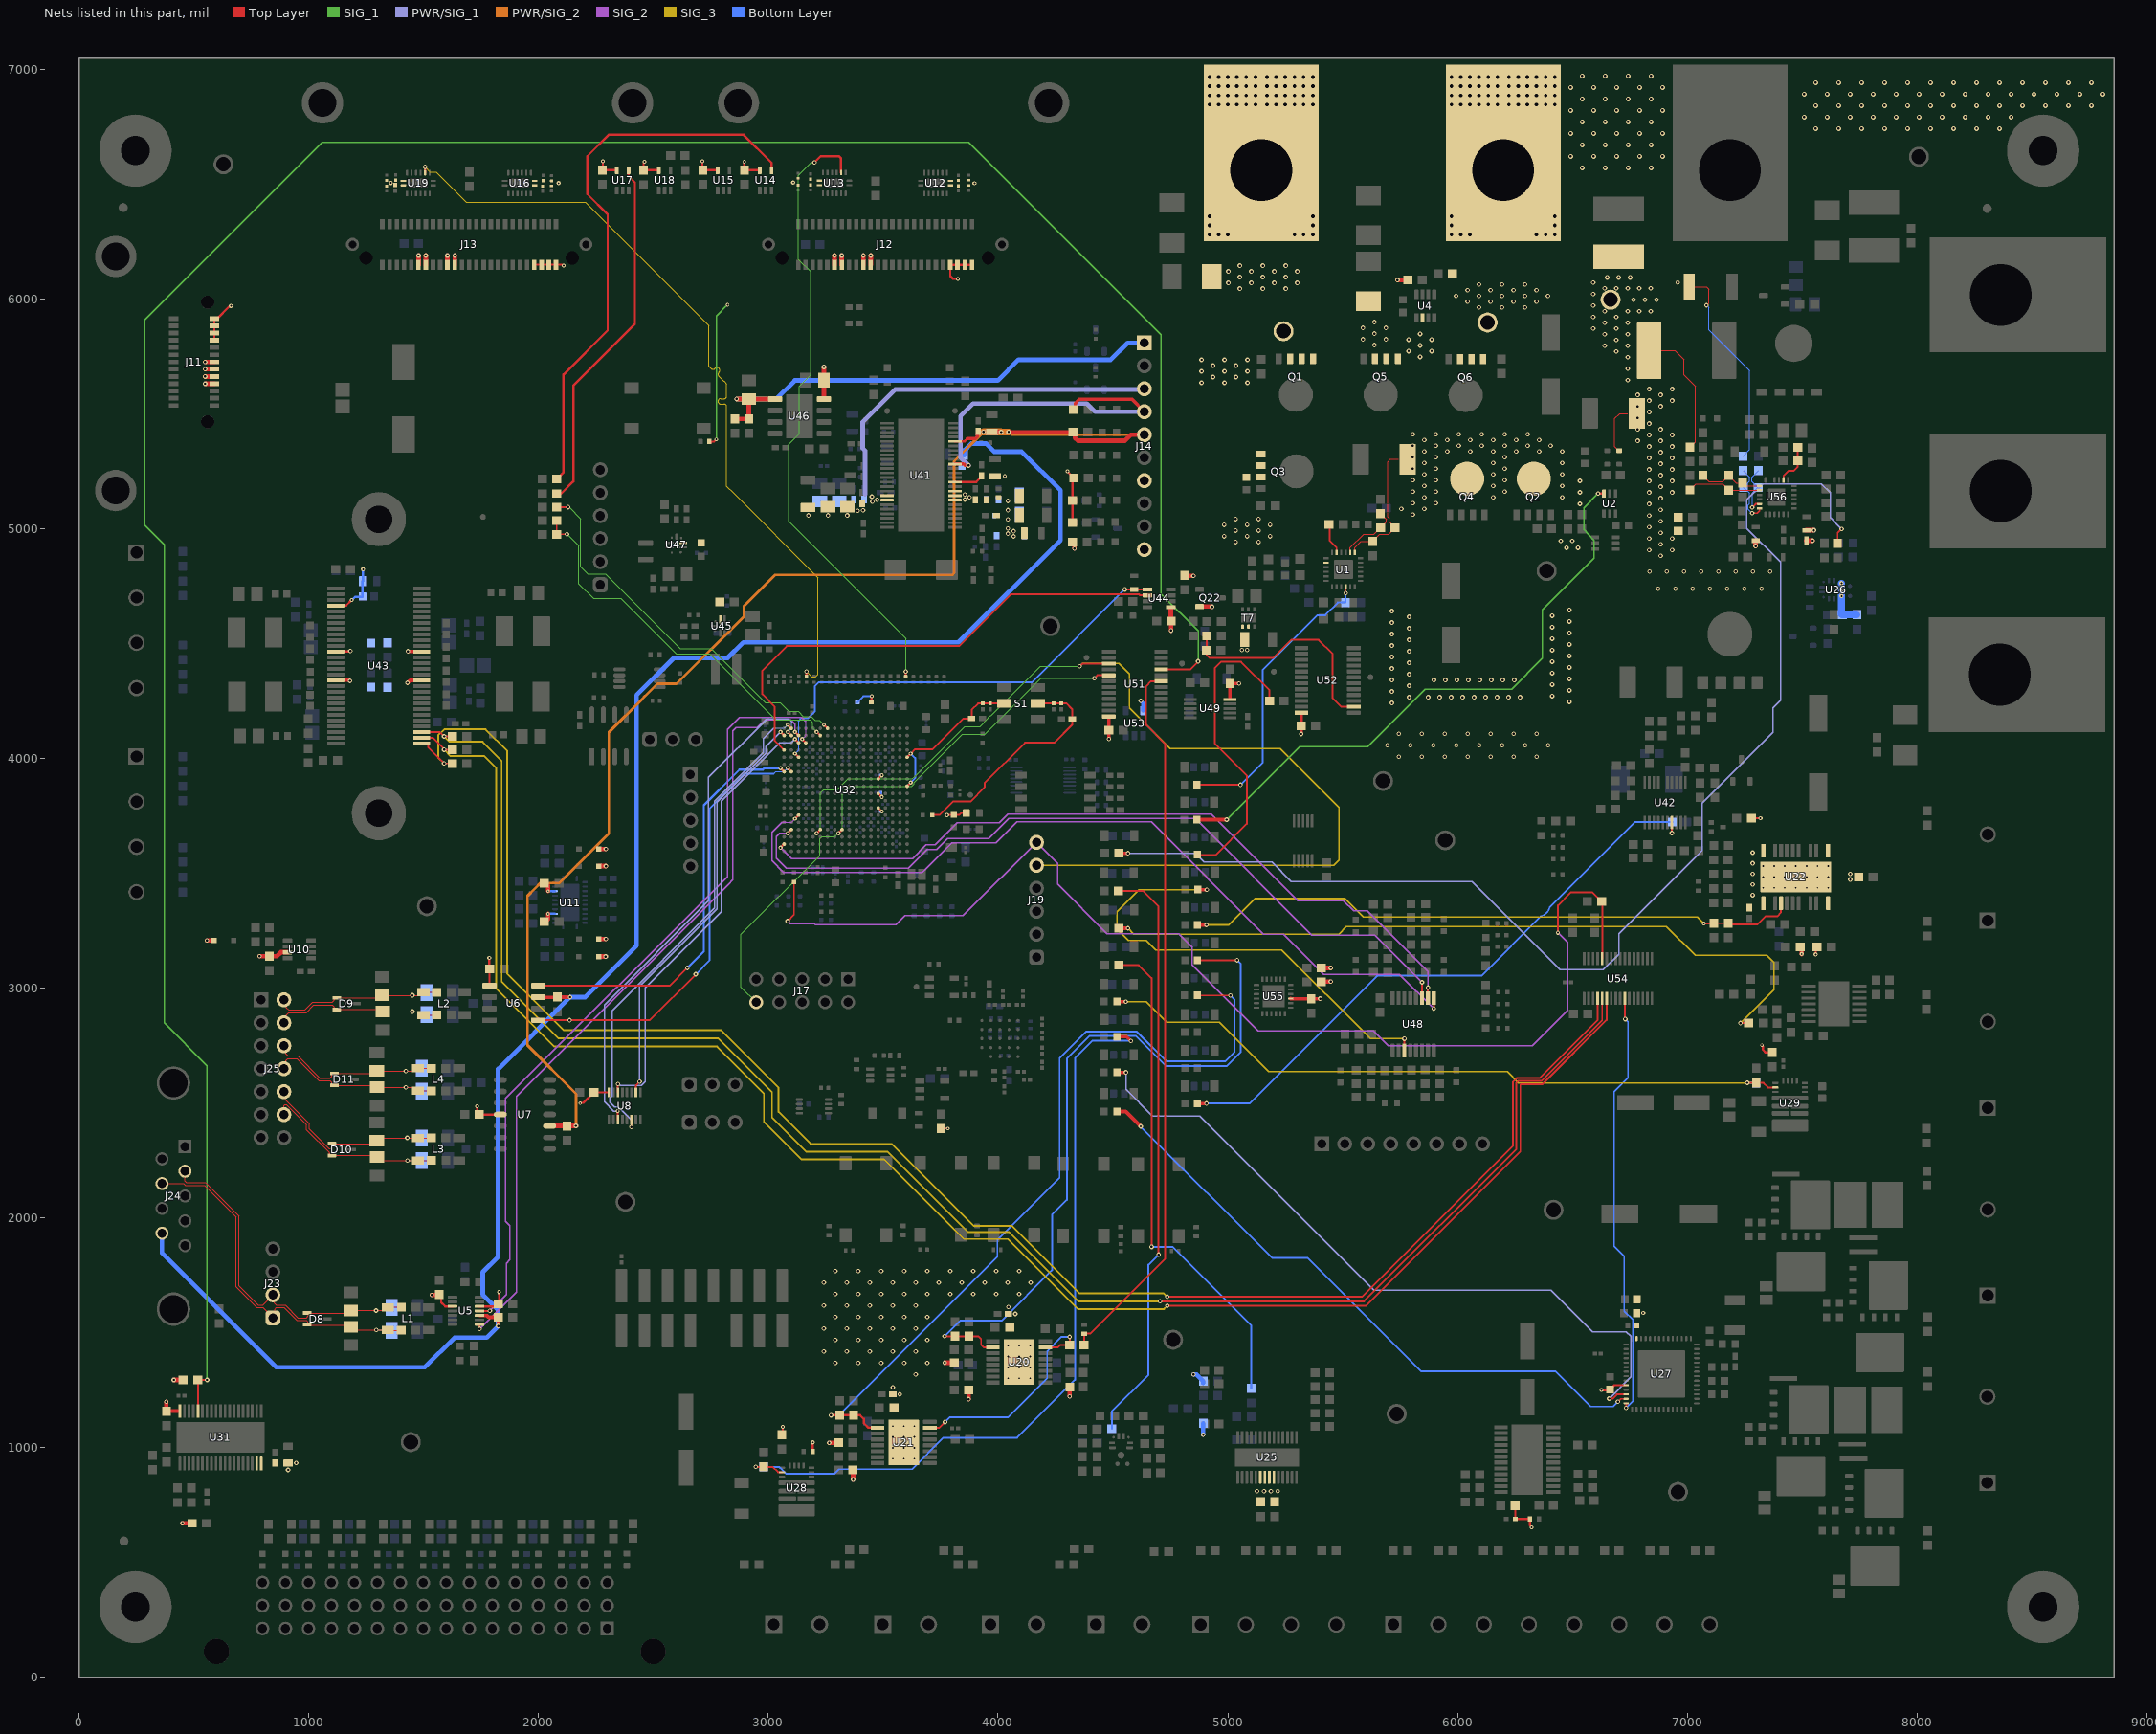
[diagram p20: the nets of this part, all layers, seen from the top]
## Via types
v1: diameter 20, hole 10, Top Layer to Bottom Layer, tented both sides, 2450 vias
v2: diameter 18, hole 8, Top Layer to Bottom Layer, tented both sides, 400 vias
v3: diameter 32, hole 16, Top Layer to Bottom Layer, tented both sides, 348 vias
v4: diameter 19.68, hole 7.87, Top Layer to Bottom Layer, tented both sides, 245 vias
v5: diameter 16, hole 8, Top Layer to Bottom Layer, tented both sides, 60 vias
v6: diameter 16, hole 8, Top Layer to Bottom Layer, 14 vias
v7: diameter 24.8, hole 12.99, Top Layer to Bottom Layer, tented both sides, 6 vias

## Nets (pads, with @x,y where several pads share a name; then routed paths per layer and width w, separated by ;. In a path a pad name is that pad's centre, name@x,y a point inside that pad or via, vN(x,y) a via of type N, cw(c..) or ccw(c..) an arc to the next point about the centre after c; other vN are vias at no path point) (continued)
3V3_2: C19.1 C24.1 C30.1 C33.1 C54.1 C55.1 C56.1 C57.1 C105.2 C106.2 C124.1 C290.1 C291.1 C323.1 C324.1 C406.1 C407.1 C408.2 C409.2 C410.1 C411.1 C412.2 C413.2 C414.1 C415.1 C416.2 C417.2 C418.1 C419.1 C420.2 C421.2 J11.2 J11.4 J11.6 J11.8 J12.2 J12.4 J12.6 J12.8 J13.2 J13.4 J13.6 J13.8 J14.7 R155.1 R158.1 R165.2 R166.2 R167.1 R171.1 R178.1 R238.2 R239.2 R351.1 R354.1 R355.1 U5.5 U6.5 U7.11 U8.16 U12.1 U12.16 U13.1 U13.16 U14.5 U15.5 U16.1 U16.16 U17.5 U18.5 U19.1 U19.16 U27.10 U27.55 U41.11 U43.32 | length 2589.2
  Top Layer w8: J13.8@1981.24,6147.8 J13.6@2012.74,6147.8 J13.4@2044.24,6147.8 J13.2@2075.73,6147.8 2102.6,6147.8 2106.12,6144.27 v6(2108.29,6144.27) ; C56.1@2277.6,6559.27 C56.1@2277.6,6559.27 2279.63,6561.3 v6(2279.63,6597.47) ; C54.1@2457.29,6559.06 2457.29,6589.85 2461.01,6593.56 v6(2461.01,6595.73) ; v6(2713.44,6597.38) 2713.44,6560.61 C57.1@2714.63,6559.41 ; v6(2894.89,6596.38) 2894.89,6561.05 C55.1@2896.66,6559.28 ; R165.2@3059.14,1054.99 3063.22,1059.06 v6(3063.22,1089.44)
  Top Layer w9.9: J11.8@588.58,5818.77 J11.6@588.58,5850.27 J11.4@588.58,5881.77 J11.2@588.58,5913.26 600.39,5913.26 653.84,5966.71 659.14,5966.71 v2(660.69,5968.26) ; U43.32@1117.44,4663.6 1117.98,4664.13 1162.23,4664.13 v6(1186.32,4688.22) ; v6(1732.48,2484.91) 1732.48,2457.51 C30.1@1741.01,2448.99 U7.11@1833.25,2448.99 ; U5.5@1743.05,1613.68 1812.85,1613.68 1827.85,1628.67 v2(1827.85,1676.2) ; v2(1785.27,3130.16) 1785.27,3082.77 C24.1@1786.58,3081.46 1786.01,3080.89 U6.5@1786.01,3009.25 ; v6(2180.68,2498.08) 2181.85,2499.24 2194.89,2499.24 2240.9,2545.25 U8.16@2305.62,2545.25 ; C56.1@2277.6,6559.27 U17.5@2340.52,6559.3 ; C54.1@2457.29,6559.06 U18.5@2523.27,6559.06 ; C57.1@2714.63,6559.41 2714.75,6559.3 U15.5@2779.16,6559.3 ; C55.1@2896.69,6559.25 U14.5@2962.47,6559.25 ; R167.1@3192.82,982.48 3193.2,982.86 3193.2,1021.26 v2(3193.58,1021.64) ; R238.2@3448.47,4243.23 3449.24,4244 3449.24,4268.26 v6(3450.01,4269.03) ; U41.11@3812.24,5201.55 3904.57,5201.55 3928.43,5225.42 C290.1@3928.43,5229.36 ; v2(3824.88,6086.05) 3804.29,6086.05 3791.9,6098.44 J12.8@3791.9,6147.8 J12.6@3823.4,6147.8 J12.4@3854.89,6147.8 J12.2@3886.39,6147.8 ; v6(4301.89,5248.98) 4303.05,5247.81 4303.05,5245.77 4328.84,5219.99 R351.1@4329.83,5219.99 4323.48,5213.64 R354.1@4323.48,5121.35 4323.82,5121 R355.1@4323.82,5025.58 ; R171.1@6251.11,746.22 6251.16,746.16 C124.1@6251.16,688.11 6251.25,688.2 6314.72,688.2 R178.1@6314.8,688.28 6315.1,687.99 6315.1,661.62 6322.51,654.21 v2(6322.51,652.02) ; v2(6626.55,1249.34) 6662.19,1249.34 6683.13,1270.28 U27.10@6733.89,1270.28 ; v6(7324.84,2750.52) 7324.84,2748.87 7329.5,2744.2 7329.5,2730.32 7341.18,2718.65 R166.2@7369.31,2718.65
  Bottom Layer w8: R239.2@3387.29,4243.36 3387.78,4243.36 3413.45,4269.03 v6(3450.01,4269.03)
  Bottom Layer w9.9: v6(1186.32,4688.22) 1187.53,4688.22 1201.74,4702.43 1232.44,4702.43 1233.4,4703.39 1233.4,4769.63 C323.1@1233.48,4769.71 1234.54,4770.77 1234.54,4821.32 v2(1235.6,4822.38)
  other v2: 6808.21,1584.7 4029.27,5227.1 3897.11,6502.3 2087.19,6502.77 1357.14,6503.73 3107.88,6505.39
3V3_ADC_1: R398.1 R399.2 U52.2 | length 995.1
  Top Layer w8: R398.1@4908.54,4532.73 4908.54,4470.34 4908.38,4470.18 4908.38,4447.93 4919.51,4436.8 5198.75,4436.8 5276.53,4514.58 5395.39,4514.58 5456.3,4453.67 5456.3,4261.08 5493.92,4223.46 U52.2@5548.39,4223.46
3V3_ALWAYS_ON: C139.2 C383.1 C384.1 C385.1 C387.1 J12.30 J12.32 J13.30 J13.32 J14.10 Q22.2 R35.2 R80.1 R81.2 R84.2 R92.1 R93.2 R100.1 R101.2 R106.2 R141.2 R142.2 R182.1 R185.1 R343.1 R349.1 R450.1 R451.1 R464.2 R468.2 R469.2 U31.19 U49.10 U51.24 U52.24 U53.5 U55.21 | length 2190.5
  Top Layer w8: R343.1@2749.43,5370.38 2743.59,5376.23 R343.1@2743.59,5378.2 2764.95,5378.2 v5(2773.94,5387.18) ; R101.2@7278.59,3738.94 7279.1,3738.42 v2(7318.38,3738.42) ; R106.2@7553.21,3188.91 7558.67,3183.45 v2(7558.67,3145.51)
  Top Layer w15: C139.2@379.37,1157.9 379.57,1158.1 U31.19@432.52,1158.1 ; v1(4481.92,4082.95) C384.1@4481.92,4122.09 4482.15,4122.32 U51.24@4482.15,4181.34 ; U49.10@5009.43,4257.51 5009.43,4324.45 C383.1@5009.3,4324.58 v1(5048.86,4324.58) ; U55.21@5274.23,2953.27 5274.47,2953.03 C387.1@5363.12,2953.03 v1(5401.9,2953.03) ; v1(5319.77,4105.07) C385.1@5319.77,4140.61 5320.04,4140.89 U52.24@5320.04,4197.87
  Top Layer w20: C139.2@379.37,1157.9 v1(379.37,1198.83) ; v1(411.88,1293.28) R185.1@452.8,1293.28 ; v1(449.28,669.68) R182.1@490.2,669.68 ; J13.32@1603.29,6147.8 v1(1603.29,6187.8) ; J13.30@1634.79,6147.8 v1(1634.79,6187.8) ; v1(3264.91,1019.87) R92.1@3305.83,1019.87 ; v1(3368.82,859.99) R93.2@3368.82,900.91 ; J12.32@3413.95,6147.8 v1(3413.95,6187.8) ; J12.30@3445.44,6147.8 v1(3445.44,6187.8) ; v1(3767.85,1368.24) R80.1@3808.78,1368.24 ; v1(3871.77,1209.62) R81.2@3871.77,1250.54 ; v1(4311.77,1221.3) R84.2@4311.77,1262.23 ; v1(4332.19,4912.52) R349.1@4332.19,4939.93 ; Q22.2@4876.85,4659.72 4930.34,4659.72 v1(4931.27,4658.79) ; R451.1@5407.08,3027.05 v1(5448,3027.05) ; R450.1@5407.08,3087.07 v1(5448,3087.07) ; v1(5738.57,6080.93) R35.2@5783.36,6080.93 ; v1(7297.3,4923.15) R464.2@7297.3,4946.84 ; R100.1@7490.73,3179.22 7497.98,3171.97 v2(7497.98,3147.62) ; R468.2@7518.16,4991.72 v1(7551.16,4991.72) ; R469.2@7518.19,4946.6 v1(7546.19,4946.6)
  SIG_1 w6: v5(2773.94,5387.18) 2773.94,5925.23 v5(2822.55,5973.84)
  Bottom Layer w15: v1(4621.05,4249.43) 4631.19,4239.28 U53.5@4631.19,4206.81
  Bottom Layer w20: v1(4850.51,1317.24) 4863.83,1317.24 4892.67,1288.41 R141.2@4892.67,1280.02 ; v2(4892.73,1054.73) R142.2@4892.73,1104.56
3V3_AlwaysOn_Monitor_MCU: R298.1 R445.1 | length 1353.1
  Top Layer w8: R298.1@4868.07,3579.27 4947.99,3579.27 5082.26,3713.54 5082.26,3924.47 4943.85,4062.88 4943.85,4393.4 4969.98,4419.52 5057.7,4419.52 5181.36,4295.86 R445.1@5181.36,4249.48
  Top Layer w15: R298.1@4867.95,3579.27 R298.1@4868.07,3579.27
3V3_VDDA_7: C192.1 C193.1 C194.1 C195.1 FB1.2 U32.P7 U32.P9 U32.P11 | length 176
  Top Layer w8: v1(3777.25,3752.44) FB1.2@3806.77,3752.44 3831,3752.44 3839.03,3760.48 C192.1@3861.05,3760.48
  Top Layer w9.9: U32.P7@3478.02,3783.42 v2(3493.77,3767.67) ; U32.P9@3478.02,3846.41 v2(3493.77,3830.66) ; U32.P11@3478.02,3909.4 v2(3493.77,3925.15)
  Bottom Layer w10: C193.1@3488.77,3850.66 3488.77,3835.66 v2(3493.77,3830.66)
5V0_1: C17.1 C23.1 C292.1 C294.1 J14.4 J24.9 R352.2 U5.3 U6.3 U41.15 | length 9543
  Top Layer w15: U5.3@1743.05,1574.31 1773.94,1574.31 1782.18,1566.07 C17.1@1824.22,1566.07 v1(1824.22,1528.31) ; U6.3@1998.6,2959.25 2082.08,2959.25 C23.1@2082.53,2959.69 v1(2137.15,2959.69) ; U41.15@3812.24,5280.29 3849.83,5280.29 3856.14,5273.98 v1(3871.14,5273.98) ; R352.2@4336.51,5517.31 4336.51,5544.49 4353.41,5561.38 4583.09,5561.38 J14.4@4636.77,5507.69
  PWR/SIG_1 w20: v1(3871.14,5273.98) 3836.46,5308.67 3836.46,5489.19 3890.67,5543.41 4386.35,5543.41 4422.06,5507.69 J14.4@4636.77,5507.69
  Bottom Layer w20: J24.9@360.77,1932.08 360.77,1845.52 857.75,1348.54 1504.85,1348.54 1634.45,1478.14 1774.05,1478.14 v1(1824.22,1528.31) 1824.22,1597.53 1756.82,1664.93 1756.82,1762.07 1824.22,1829.48 1824.22,2646.77 v1(2137.15,2959.69) 2203.01,2959.69 2426.49,3183.18 2426.49,4273.92 2588.75,4436.18 2822.74,4436.18 2890.67,4504.11 3827.22,4504.11 4271.41,4948.31 4271.41,5165.58 4103.5,5333.49 3983.47,5333.49 3947.49,5369.47 3883.92,5369.47 3852.46,5338.01 C294.1@3852.46,5319.19
5V0_2: C28.1 C298.1 C299.1 J14.5 R353.2 U7.3 U41.20 | length 6103.2
  Top Layer w11: U41.20@3812.24,5378.72 3854.2,5378.72 3866.09,5390.6
  Top Layer w15: 3866.09,5390.6 3900.9,5390.6 3909.68,5399.39 3909.68,5414.14 C298.1@3914.52,5418.98 ; v1@3936.51,5420.91 v1(3936.79,5420.62) v1@3937.08,5420.34
  Top Layer w20: U7.3@2047.82,2398.99 2124.24,2398.99 C28.1@2124.44,2399.18 v1(2162.74,2399.18) ; C299.1@3973.12,5419.5 v1@4012.81,5419.5 ; v1(4045.66,5419.5) 4046.66,5418.51 R353.2@4334.67,5418.51 ; R353.2@4333.77,5419.5 4334.68,5420.41 4334.68,5418.51 4334.68,5394.33 4346.81,5382.2 4553.35,5382.2 4578.85,5407.69 J14.5@4636.77,5407.69
  PWR/SIG_2 w12: v1(2162.74,2399.18) 2162.74,2538.64 1951.46,2749.92 1951.46,3399.92 1983.72,3432.18 2007.62,3456.08 2090.06,3456.08 2305.98,3672 2305.98,4112.06 2450.32,4256.4 2450.32,4257.54 2462,4269.22 2463.13,4269.22 2517.1,4323.19 2601.06,4323.19 2893,4615.12 2893,4661.78 3028.94,4797.72 3801.59,4797.72 3808.62,4804.75 3808.62,5292.45 v1(3936.79,5420.62) ; v1(4045.66,5419.5) 4048.91,5419.5 4060.72,5407.69 J14.5@4636.77,5407.69
  PWR/SIG_2 w30: v1(3936.79,5420.62) v1@4011.5,5420.62 ; v1@4012.81,5419.5 v1(4045.66,5419.5)
  other v1: 4012.81,5419.31
5V_TRACK: C363.1 C366.1 J14.1 R407.2 U46.1 | length 2191.3
  Top Layer w20: R407.2@2854.41,5476.4 C363.1@2914.81,5476.4 C366.1@2914.81,5563.4 ; v1(2861.74,5563.4) C366.1@2914.81,5563.4 ; U46.1@3029.21,5563.01 3028.81,5563.4 C366.1@2914.81,5563.4
  Bottom Layer w20: v1(2861.74,5563.4) 3035.1,5563.4 3115.32,5643.63 3999.27,5643.63 4089.49,5733.85 4490.67,5733.85 4564.51,5807.69 J14.1@4636.77,5807.69
6V0_BB: C280.1 C281.1 C282.2 C283.2 C284.2 C285.2 C286.1 C287.2 C367.1 C370.1 J14.3 U41.41 U41.42 U45.6 U47.6 | length 1604.5
  PWR/SIG_1 w20: 3421.25,5148.47 3421.25,5337.67 3411.05,5347.87 3411.05,5463.2 3551.96,5604.11 4633.19,5604.11 J14.3@4636.77,5607.69
  other v1: 3174.07,5056.37 3259.39,5056.37 3343.42,5056.37 3388.8,5076.35 3412.15,5078.36 3452.63,5116.33 3473.05,5124.53 3450.48,5138.23
12V_ALWAYS_ON: C18.1 C46.1 C48.1 C49.1 C60.1 C61.1 C66.1 C67.1 C74.1 C75.1 C87.1 C88.1 C135.2 C136.1 C264.1 C265.2 C266.2 C267.2 C268.2 C269.2 C270.2 C271.1 C272.1 C273.2 C274.2 C275.1 C276.1 C358.1 C360.2 C365.1 C390.1 D13.2 D14.2 D15.2 D16.2 D17.2 J11.14 J11.16 J11.18 J11.20 J12.38 J12.40 J13.38 J13.40 R30.2 R33.2 R324.1 R333.2 R400.2 R452.1 R453.2 R457.1 R458.2 R459.2 R465.2 T7.1 T7.2 TP3.1 U5.10 U10.7 U11.16 U11.21 U20.17 U21.17 U22.1 U22.9 U22.10 U22.18 U22.19 U25.20 U25.21 U25.22 U25.23 U31.37 U31.38 U41.7 U41.8 U41.9 U44.1 U46.8 | length 2861.9
  Top Layer w5: R33.2@6703.51,5338.4 6701.16,5338.4 6684.46,5355.1 6684.46,5478.85 6706,5500.4 6739.84,5500.4 ; R457.1@6834.28,5773.48 6946.6,5773.48 6985.33,5734.74 6985.33,5667.98 7034.76,5618.54 7034.76,5376.72 R459.2@7011.89,5353.85 ; R452.1@7008.28,6050.45 7083.22,6050.45 7093.75,6039.92 7093.75,5981.36 v1(7083.75,5971.36)
  Top Layer w8: R324.1@3752.04,2387.56 3752.43,2387.95 v5(3781.94,2387.95)
  Top Layer w10: C18.1@1568.33,1663.3 1575.91,1655.72 1575.91,1631.05 1593.28,1613.68 U5.10@1624.94,1613.68
  Top Layer w20: v1(548.58,5629.8) J11.20@588.58,5629.8 ; v1(548.58,5661.29) J11.18@588.58,5661.29 ; v1(548.58,5692.79) J11.16@588.58,5692.79 ; v1(548.58,5724.28) J11.14@588.58,5724.28 ; v1(556.4,3206.05) D13.2@586.53,3206.05 ; v1(785.11,3137.25) C46.1@828.37,3137.25 860.49,3137.25 878,3154.75 U10.7@907.38,3154.75 ; J13.40@1477.31,6147.8 v1(1477.31,6187.8) ; J13.38@1508.8,6147.8 v1(1508.8,6187.8) ; v1(1534.83,1663.3) C18.1@1568.33,1663.3 ; C48.1@2031.24,3289.19 2041.38,3299.33 v5(2041.38,3322.34) ; C49.1@2031.24,3454.42 2041.38,3444.29 v5(2041.38,3420.77) ; D17.2@2261.69,3136.1 v1(2291.69,3136.1) ; D15.2@2262.44,3529.82 v1(2292.44,3529.82) ; D14.2@2262.44,3603.86 v1(2292.44,3603.86) ; D16.2@2262.48,3213.03 v1(2292.48,3213.03) ; U46.8@3241.81,5563.01 3241.81,5645.21 C365.1@3241.95,5645.35 v1(3241.95,5703.03) ; J12.40@3287.96,6147.8 v1(3287.96,6187.8) ; J12.38@3319.46,6147.8 v1(3319.46,6187.8) ; 4752.48,4648.42 4752.48,4596.46 C358.1@4752.53,4596.41 v1(4752.53,4555.25) ; R400.2@4812.51,4793.3 v1(4850.28,4793.3)
  Bottom Layer w5: v1(7083.75,5971.36) 7094.02,5961.1 7094.02,5863.11 7271.08,5686.05 7271.08,5342.41 R453.2@7242.96,5314.29
  Bottom Layer w10: v5(2041.38,3322.34) U11.16@2071.38,3322.34 ; v5(2041.38,3420.77) U11.21@2071.38,3420.77
  other v1: 5127.37,809.13 5157.37,809.13 5187.37,809.13 5217.37,809.13 909.86,901.84 944.86,931.84 3571.9,1230.81 3541.9,1260.81 3641.58,1317.08 3291.58,1367.08 3391.58,1367.08 3491.58,1367.08 3591.58,1367.08 3691.58,1367.08 3241.58,1417.08 3341.58,1417.08 3441.58,1417.08 3541.58,1417.08 3641.58,1417.08 3291.58,1467.08 3391.58,1467.08 3491.58,1467.08 3591.58,1467.08 3691.58,1467.08 3241.58,1517.08 3341.58,1517.08 3441.58,1517.08 3541.58,1517.08 3641.58,1517.08 3291.58,1567.08 3391.58,1567.08 3491.58,1567.08 3591.58,1567.08 3691.58,1567.08 4075.12,1580.76 4045.12,1610.76 3241.58,1617.08 3341.58,1617.08 3441.58,1617.08 3541.58,1617.08 3641.58,1617.08 3291.58,1667.08 3391.58,1667.08 3491.58,1667.08 3591.58,1667.08 3691.58,1667.08 3791.58,1667.08 3891.58,1667.08 3991.58,1667.08 4091.58,1667.08 3241.58,1717.08 3341.58,1717.08 3441.58,1717.08 3541.58,1717.08 3641.58,1717.08 3741.58,1717.08 3841.58,1717.08 3941.58,1717.08 4041.58,1717.08 4141.58,1717.08 3291.58,1767.08 3391.58,1767.08 3491.58,1767.08 3591.58,1767.08 3691.58,1767.08 3791.58,1767.08 3891.58,1767.08 3991.58,1767.08 4091.58,1767.08 7284.5,3403.54 7284.5,3449.82 7709.24,3471.6 7284.5,3496.11 7709.24,3495.6 7284.5,3542.4 7284.5,3588.69 5061.11,4470.23 5084.46,4470.23 6884.12,4881.22 6834.12,4906.22 6934.12,4906.22 6884.12,4931.22 6834.12,4956.22 6934.12,4956.22 4067.98,4965.38 4042.98,4977.38 6884.12,4981.22 4067.98,4987.56 4042.98,4999.56 6834.12,5006.22 6884.12,5031.22 4042.98,5039.56 6834.12,5056.22 4042.98,5079.56 6884.12,5081.22 6834.12,5106.22 4042.98,5119.56 3855.45,5125.6 6884.12,5131.22 3875.42,5134.84 3855.25,5147.78 6834.12,5156.22 6934.12,5156.22 6884.12,5181.22 6834.12,5206.22 6934.12,5206.22 6884.12,5231.22 6834.12,5256.22 6934.12,5256.22 6884.12,5281.22 6834.12,5306.22 6934.12,5306.22 6884.12,5331.22 6834.12,5356.22 6934.12,5356.22 6784.12,5381.22 6884.12,5381.22 6834.12,5406.22 6934.12,5406.22 6784.12,5431.22 6884.12,5431.22 6834.12,5456.22 6784.12,5481.22 6834.12,5506.22 6784.12,5531.22 6884.12,5531.22 6834.12,5556.22 6934.12,5556.22 6784.12,5581.22 6884.12,5581.22 6834.12,5606.22 6934.12,5606.22 6740.66,5645.4 6740.66,5695.4 6740.66,5745.4 6690.66,5770.4 6640.66,5795.4 6740.66,5795.4 6690.66,5820.4 6640.66,5845.4 6740.66,5845.4 6590.66,5870.4 6690.66,5870.4 6640.66,5895.4 6740.66,5895.4 6590.66,5920.4 6690.66,5920.4 6640.66,5945.4 6740.66,5945.4 6790.66,5945.4 6840.66,5945.4 6590.66,5970.4 6765.66,5995.4 6815.66,5995.4 6865.66,5995.4 6590.66,6020.4 6640.66,6045.4 6690.66,6045.4 6740.66,6045.4 6790.66,6045.4 6840.66,6045.4 6590.66,6070.4 6958.28,6070.45 6651.35,6092.37 6701.35,6092.37 6751.35,6092.37 6542.62,6569.24 6642.62,6569.24 6742.62,6569.24 6842.62,6569.24 6492.62,6619.24 6592.62,6619.24 6692.62,6619.24 6792.62,6619.24 6892.62,6619.24 6542.62,6669.24 6642.62,6669.24 6742.62,6669.24 6842.62,6669.24 6492.62,6719.24 6592.62,6719.24 6692.62,6719.24 6792.62,6719.24 6892.62,6719.24 7558.96,6739.9 7658.96,6739.9 7758.96,6739.9 7858.96,6739.9 7958.96,6739.9 8058.96,6739.9 8158.96,6739.9 8258.96,6739.9 8358.96,6739.9 6542.62,6769.24 6642.62,6769.24 6742.62,6769.24 6842.62,6769.24 7508.96,6789.9 7608.96,6789.9 7708.96,6789.9 7808.96,6789.9 7908.96,6789.9 8008.96,6789.9 8108.96,6789.9 8208.96,6789.9 8308.96,6789.9 8408.96,6789.9 6492.62,6819.24 6592.62,6819.24 6692.62,6819.24 6792.62,6819.24 6892.62,6819.24 7558.96,6839.9 7658.96,6839.9 7758.96,6839.9 7858.96,6839.9 7958.96,6839.9 8058.96,6839.9 8158.96,6839.9 8258.96,6839.9 8358.96,6839.9 8458.96,6839.9 8558.96,6839.9 8658.96,6839.9 8758.96,6839.9 6542.62,6869.24 6642.62,6869.24 6742.62,6869.24 6842.62,6869.24 7508.96,6889.9 7608.96,6889.9 7708.96,6889.9 7808.96,6889.9 7908.96,6889.9 8008.96,6889.9 8108.96,6889.9 8208.96,6889.9 8308.96,6889.9 8408.96,6889.9 8508.96,6889.9 8608.96,6889.9 8708.96,6889.9 8808.96,6889.9 6492.62,6919.24 6592.62,6919.24 6692.62,6919.24 6792.62,6919.24 6892.62,6919.24 7558.96,6939.9 7658.96,6939.9 7758.96,6939.9 7858.96,6939.9 7958.96,6939.9 8058.96,6939.9 8158.96,6939.9 8258.96,6939.9 8358.96,6939.9 8458.96,6939.9 8558.96,6939.9 8658.96,6939.9 8758.96,6939.9 6542.62,6969.24 6642.62,6969.24 6742.62,6969.24 6842.62,6969.24
  other v4: 3541.77,950.68 3589.02,950.68 3636.26,950.68 3541.77,997.92 3589.02,997.92 3636.26,997.92 3541.77,1045.16 3589.02,1045.16 3636.26,1045.16 3541.77,1092.41 3589.02,1092.41 3636.26,1092.41 4044.42,1300.69 4091.67,1300.69 4138.91,1300.69 4044.42,1347.93 4091.67,1347.93 4138.91,1347.93 4044.42,1395.18 4091.67,1395.18 4138.91,1395.18 4044.42,1442.42 4091.67,1442.42 4138.91,1442.42 7330.28,3435.45 7377.53,3435.45 7424.77,3435.45 7472.01,3435.45 7519.26,3435.45 7566.5,3435.45 7613.75,3435.45 7330.28,3482.69 7377.53,3482.69 7424.77,3482.69 7472.01,3482.69 7519.26,3482.69 7566.5,3482.69 7613.75,3482.69 7330.28,3529.93 7377.53,3529.93 7424.77,3529.93 7472.01,3529.93 7519.26,3529.93 7566.5,3529.93 7613.75,3529.93
12V_VBATT_1: C2.1 C89.1 C90.1 D4.1 Q1.1 Q1.2 Q1.3 Q3.1 Q3.2 Q3.3 T4.1 TP1.1 U1.2 U26.2 | length 202.9
  Bottom Layer w30: v4(7671.09,4760.76) v4(7671.09,4705.64) 7671.09,4627.11 C90.1@7674.23,4623.97 7738.9,4623.97 C89.1@7739,4623.88
  other v1: 5033.95,4940.51 5133.95,4940.51 4983.95,4965.51 5083.95,4965.51 5183.95,4965.51 5033.95,4990.51 5133.95,4990.51 4983.95,5015.51 5083.95,5015.51 5183.95,5015.51 5033.95,5040.51 5133.95,5040.51 4885.61,5633.68 4985.61,5633.68 5085.61,5633.68 4935.61,5658.68 5035.61,5658.68 4885.61,5683.68 4985.61,5683.68 5085.61,5683.68 4935.61,5708.68 5035.61,5708.68 4885.61,5733.68 4985.61,5733.68 5085.61,5733.68 5052.02,6043.79 5152.02,6043.79 5252.02,6043.79 5002.02,6068.79 5102.02,6068.79 5202.02,6068.79 5302.02,6068.79 5052.02,6093.79 5152.02,6093.79 5252.02,6093.79 5002.02,6118.79 5102.02,6118.79 5202.02,6118.79 5302.02,6118.79 5052.02,6143.79 5152.02,6143.79 5252.02,6143.79
  other v3: 4919.95,6278.44 4959.95,6278.44 4999.95,6278.44 5289.95,6278.44 5329.95,6278.44 5369.95,6278.44 4919.95,6318.44 5369.95,6318.44 4919.95,6358.44 5369.95,6358.44 4919.95,6844.7 4959.95,6844.7 4999.95,6844.7 5039.95,6844.7 5079.95,6844.7 5119.95,6844.7 5169.95,6844.7 5209.95,6844.7 5249.95,6844.7 5289.95,6844.7 5329.95,6844.7 5369.95,6844.7 4919.95,6884.7 4959.95,6884.7 4999.95,6884.7 5039.95,6884.7 5079.95,6884.7 5119.95,6884.7 5169.95,6884.7 5209.95,6884.7 5249.95,6884.7 5289.95,6884.7 5329.95,6884.7 5369.95,6884.7 4919.95,6924.7 4959.95,6924.7 4999.95,6924.7 5039.95,6924.7 5079.95,6924.7 5119.95,6924.7 5169.95,6924.7 5209.95,6924.7 5249.95,6924.7 5289.95,6924.7 5329.95,6924.7 5369.95,6924.7 4919.95,6964.7 4959.95,6964.7 4999.95,6964.7 5039.95,6964.7 5079.95,6964.7 5119.95,6964.7 5169.95,6964.7 5209.95,6964.7 5249.95,6964.7 5289.95,6964.7 5329.95,6964.7 5369.95,6964.7
  other v4: 7671.09,4733.2
12V_VBATT_2: D6.1 Q5.1 Q5.2 Q5.3 Q6.1 Q6.2 Q6.3 R34.2 T6.1 TP4.1 U4.6
  other v1: 5837.13,5746.6 5787.13,5771.6 5887.13,5771.6 5837.13,5796.6 5637.84,5797.99 5787.13,5821.6 5887.13,5821.6 5587.84,5822.99 5687.84,5822.99 5837.13,5846.6 5637.84,5847.99 5587.84,5872.99 5687.84,5872.99 5637.84,5897.99 6093.41,5961.88 6193.41,5961.88 6293.41,5961.88 6043.41,5986.88 6143.41,5986.88 6243.41,5986.88 6343.41,5986.88 5993.41,6011.88 6093.41,6011.88 6193.41,6011.88 6293.41,6011.88 6393.41,6011.88 6043.41,6036.88 6143.41,6036.88 6243.41,6036.88 6343.41,6036.88 6093.41,6061.88 6193.41,6061.88 6293.41,6061.88
  other v3: 5973.51,6278.44 6013.51,6278.44 6053.51,6278.44 6343.51,6278.44 6383.51,6278.44 6423.51,6278.44 5973.51,6318.44 6423.51,6318.44 5973.51,6358.44 6423.51,6358.44 5973.51,6844.7 6013.51,6844.7 6053.51,6844.7 6093.51,6844.7 6133.51,6844.7 6173.51,6844.7 6223.51,6844.7 6263.51,6844.7 6303.51,6844.7 6343.51,6844.7 6383.51,6844.7 6423.51,6844.7 5973.51,6884.7 6013.51,6884.7 6053.51,6884.7 6093.51,6884.7 6133.51,6884.7 6173.51,6884.7 6223.51,6884.7 6263.51,6884.7 6303.51,6884.7 6343.51,6884.7 6383.51,6884.7 6423.51,6884.7 5973.51,6924.7 6013.51,6924.7 6053.51,6924.7 6093.51,6924.7 6133.51,6924.7 6173.51,6924.7 6223.51,6924.7 6263.51,6924.7 6303.51,6924.7 6343.51,6924.7 6383.51,6924.7 6423.51,6924.7 5973.51,6964.7 6013.51,6964.7 6053.51,6964.7 6093.51,6964.7 6133.51,6964.7 6173.51,6964.7 6223.51,6964.7 6263.51,6964.7 6303.51,6964.7 6343.51,6964.7 6383.51,6964.7 6423.51,6964.7
A0_TMUX1308: U32.B4 U48.11 | length 3454.8
  Top Layer w8: U48.11@5845.32,2955.64 v1(5845.32,3023.97)
  Top Layer w9.9: v2(3084.32,3673.18) U32.B4@3100.07,3688.93
  SIG_2 w6: v2(3084.32,3673.18) 3049.23,3673.18 3034.19,3658.14 3034.19,3565.08 3078.79,3520.48 3610.32,3520.48 3691.74,3601.9 3732.52,3601.9 3780.65,3650.03 3959.74,3650.03 4046.94,3737.23 4858.49,3737.23 5366.13,3229.58 5639.71,3229.58 v1(5845.32,3023.97)
A1_TMUX1308: U32.A2 U48.10 | length 3339.2
  Top Layer w8: U48.10@5870.92,2955.64 v1(5870.92,3001.4)
  Top Layer w9.9: v2(3052.82,3610.19) U32.A2@3068.57,3625.94
  SIG_2 w6: v2(3052.82,3610.19) 3100.44,3562.57 3627.39,3562.57 3687.36,3622.54 3726.34,3622.54 3822.36,3718.56 4005.97,3718.56 4043.68,3756.27 4928.45,3756.27 5304.51,3380.22 5503.52,3380.22 5548.82,3334.91 5606.43,3334.91 5870.92,3070.42 v1(5870.92,3001.4)
A2_TMUX1308: U32.C6 U48.9 | length 3645.5
  Top Layer w8: v1(5896.51,2909.88) U48.9@5896.51,2955.64
  Top Layer w9.9: v2(3115.81,3736.18) U32.C6@3131.56,3751.92
  SIG_2 w4.5: 3076.53,3720.66 3100.3,3720.66 v2(3115.81,3736.18)
  SIG_2 w6: 3076.53,3720.66 3059.37,3720.66 3015.64,3676.92 3015.64,3553.33 3065.86,3503.1 3670.94,3503.1 3799.17,3631.33 3990.39,3631.33 4081.58,3722.52 4666.84,3722.52 5155.12,3234.24 5241.43,3234.24 5416.47,3059.2 5747.19,3059.2 v1(5896.51,2909.88)
ADC0_AIN0: R28.1 R294.1 U1.10 | length 1280.4
  Top Layer w8: R294.1@4866.06,3883.94 v1(5055.2,3883.94) ; v1(5512.96,4718.42) U1.10@5512.96,4746.07
  Bottom Layer w8: v1(5055.2,3883.94) 5151.08,3979.82 5151.08,4383.57 5389.54,4622.03 5424.17,4622.03 5479.43,4677.28 R28.1@5512.3,4677.28 5512.3,4717.77 v1(5512.96,4718.42)
ADC0_AIN1: R296.1 U2.6 | length 2674.5
  Top Layer w10: v1(6611.63,5151.34) U2.6@6636.95,5151.34
  Top Layer w15: R296.1@4865.48,3732.12 v1(4995.01,3732.12)
  SIG_1 w6: v1(4995.01,3732.12) 5312.58,4049.69 5607.89,4049.69 5858.55,4300.35 6234.78,4300.35 6368.83,4434.41 6368.83,4644.66 6594.6,4870.43 6594.6,4948.04 6570.61,4972.02 6570.61,4973.44 6549.44,4994.61 6549.44,5089.15 v1(6611.63,5151.34)
ADC1_AIN0: R300.1 U48.3 | length 2046.5
  Top Layer w8: U48.3@5768.55,2727.3 v1(5768.55,2778.64)
  Top Layer w15: R300.1@4869.43,3427.37 v1(4908.58,3427.37)
  SIG_3 w6: v1(4908.58,3427.37) 4612.55,3427.37 4516.77,3331.59 4516.77,3256.97 4566.81,3206.93 4645.06,3206.93 4686.92,3165.07 5234.69,3165.07 5621.12,2778.64 v1(5768.55,2778.64)
ADC2_AIN0: C73.1 R103.2 R302.1 U22.3 | length 2698.2
  Top Layer w8: v2(7072.18,3280.05) 7113.85,3280.05 R103.2@7115.24,3281.44 C73.1@7178.8,3281.44 7184.84,3275.39 7304.87,3275.39 7340.63,3311.16 7364.63,3311.16 7364.91,3310.88 7379.83,3310.88 7380.11,3311.16 7390.8,3311.16 7408.04,3328.4 U22.3@7408.04,3368.52
  Top Layer w15: R302.1@4868.21,3274.02 v1(4907.35,3274.02)
  SIG_3 w8: v1(4907.35,3274.02) 5003.57,3274.02 5118.88,3389.33 5508.25,3389.33 5589.21,3308.36 6954.86,3308.36 7043.87,3308.36 v2(7072.18,3280.05)
ADC2_AIN1: C63.1 R87.2 R304.1 U20.2 | length 3236
  Top Layer w8: v1(3767.05,1483.59) R87.2@3812.12,1483.59 3812.19,1483.52 C63.1@3873.05,1483.52 3913.63,1483.52 3926.19,1470.95 3926.19,1446.5 3937.16,1435.53 U20.2@3977.5,1435.53 ; R304.1@4867.82,3120.5 v1(5040.63,3120.5)
  Bottom Layer w8: v1(3767.05,1483.59) 3835.1,1551.65 4015.66,1551.65 4235.13,1771.13 4235.13,2012.55 4299.77,2077.18 4299.77,2691.38 4399.89,2791.5 4598.17,2791.5 4729.56,2660.11 4996.2,2660.11 5056.52,2720.43 5056.52,3104.62 v1(5040.63,3120.5)
ADC2_AIN2: C69.1 R96.2 R306.1 U21.2 | length 3500.1
  Top Layer w8: R306.1@4866.88,2967.03 v1(5011.26,2967.03)
  Top Layer w10: v1(3272.9,1139.57) R96.2@3309.7,1139.57 ; R96.2@3309.7,1141.09 3311.21,1139.57 C69.1@3370.11,1139.57 3399.32,1139.57 3415.96,1122.93 3415.96,1105.24 3435.69,1085.52 U21.2@3474.84,1085.52
  Bottom Layer w8: v1(3272.9,1139.57) 3307.35,1139.57 3996.77,1828.99 3996.77,1902.74 4267.53,2173.5 4267.53,2694.76 4382.35,2809.58 4604.01,2809.58 4733.37,2680.22 4988.2,2680.22 5029.24,2721.26 5029.24,2949.05 v1(5011.26,2967.03)
ADC2_AIN5: R314.1 R381.2 U42.7 | length 2671.6
  Top Layer w8: v1(6933.03,3674.11) U42.7@6933.03,3719.72
  Top Layer w15: R314.1@4867.79,2496.87 v1(4906.93,2496.87)
  Bottom Layer w8: v1(4906.93,2496.87) 5093.8,2496.87 5650.19,3053.25 6104.46,3053.25 6363.36,3312.15 ccw(c6350.49,3361.95) 6400.3,3349.08 6773.67,3722.46 R381.2@6934.6,3722.46 6933.03,3720.89 v1(6933.03,3674.11)
ADC3_AIN0: R128.1 R301.1 | length 5399.8
  Top Layer w8: R128.1@7653.99,4934.44 7653.99,4980.2 v1(7671.61,4997.81)
  Top Layer w15: R301.1@4526.47,3586.09 v1(4565.62,3586.09)
  PWR/SIG_1 w6: v1(4565.62,3586.09) 4857.66,3586.09 4896.72,3547.03 5192.22,3547.03 5276.62,3462.64 6061.98,3462.64 6445.98,3078.63 6633.99,3078.63 6702.13,3146.77 6702.13,3235.66 7063.69,3597.22 7063.69,3803.13 7373.6,4113.04 7373.6,4219.32 7406.25,4251.98 7406.25,4853.45 7259.37,5000.33 7259.37,5124.33 7328.64,5193.6 7583.29,5193.6 7621.85,5155.03 7621.85,5047.57 v1(7671.61,4997.81)
ADC3_AIN1: R111.1 R303.1 | length 2558.4
  Top Layer w8: R303.1@4524.51,3421.36 4631.13,3421.36 4698.37,3354.11 v1(4698.37,1838.76)
  Bottom Layer w8: R111.1@4495.1,1081.58 4495.1,1156.25 4654.17,1315.32 4654.17,1794.55 v1(4698.37,1838.76)
ADC3_AIN2: R124.2 R305.1 | length 3298.7
  Top Layer w8: v1(7231.24,2846.53) R124.2@7267.54,2846.53
  Top Layer w15: R305.1@4526.11,3259.65 v1(4565.26,3259.65)
  SIG_3 w6: v1(4565.26,3259.65) 4590.53,3234.37 5483.42,3234.37 5515.65,3266.6 6909.42,3266.6 7035.07,3140.96 7345.51,3140.96 7376.08,3110.39 7376.08,2991.37 v1(7231.24,2846.53)
ADC3_AIN3: R147.2 R307.1 | length 2184.7
  Top Layer w8: R307.1@4525.83,3098.97 4611.59,3098.97 4668.33,3042.23 v1(4668.33,1872.91)
  Bottom Layer w8: v1(4668.33,1872.91) 4759.35,1872.91 5102.01,1530.25 R147.2@5102.01,1256.49
ADC4_AIN0: C121.2 R169.2 R309.1 U29.2 | length 3060
  Top Layer w8: v1(7261.03,2586.65) C121.2@7300.01,2586.65 7331.72,2586.65 7351.63,2566.74 U29.2@7383.31,2566.74
  Top Layer w15: R309.1@4516.78,2939.77 v1(4555.93,2939.77)
  SIG_3 w6: v1(4555.93,2939.77) 4644.73,2939.77 4734.88,2849.62 4964.05,2849.62 5178.04,2635.64 6216.21,2635.64 6265.19,2586.65 v1(7261.03,2586.65)
  Bottom Layer w8: v1(7261.03,2586.65) R169.2@7300.01,2586.65
ADC4_AIN1: C120.2 R168.2 R311.1 U28.2 | length 3437.3
  Top Layer w8: v1(2945.25,915.2) C120.2@2980.43,915.2 3018.91,915.2 3042.4,891.71 U28.2@3059.45,891.71
  Top Layer w15: R311.1@4516.75,2787.35 4559.5,2787.35 v1(4577.59,2769.26)
  Bottom Layer w8: v1(2945.25,915.2) R168.2@2980.43,915.2 3047.01,915.2 3076.29,885.92 3288.16,885.92 3307.37,905.13 3625.28,905.13 3761.71,1041.56 4083.06,1041.56 4335.07,1293.57 4335.07,2694.13 4410.2,2769.26 v1(4577.59,2769.26)
ADC4_AIN2: R313.1 U27.12 | length 3147.6
  Top Layer w8: v1(6659.97,1212.12) 6674.69,1212.12 6693.49,1230.91 U27.12@6733.89,1230.91
  Top Layer w15: R313.1@4517.21,2632.01 v1(4556.36,2632.01)
  PWR/SIG_1 w6: v1(4556.36,2632.01) 4556.36,2558.75 4672.47,2442.63 4878.01,2442.63 5636.01,1684.64 6406.77,1684.64 6587.88,1503.52 6733.86,1503.52 6754.18,1483.2 6754.18,1306.33 v1(6659.97,1212.12)
ADC4_AIN3: R315.1 U27.13 | length 2762.4
  Top Layer w8: v1(6697.64,1198.64) 6710.23,1211.23 U27.13@6733.89,1211.23
  Top Layer w15: R315.1@4517.15,2461.83 4555.78,2461.83 v1(4620.47,2397.14)
  Bottom Layer w8: v1(4620.47,2397.14) 5193.71,1823.9 5348.51,1823.9 5840.81,1331.61 6425.95,1331.61 6579.67,1177.9 6676.89,1177.9 v1(6697.64,1198.64)
ADC_VREFHI_G0_G1_10: C233.2 C234.2 C235.2 S1.2 U32.V10 U32.V14 | length 707.3
  Top Layer w8: v2(3619.75,4019.64) 3638.86,4038.75 3715.57,4038.75 3848.94,4172.12 C233.2@3885.16,4172.12 3885.16,4210.6 3912.84,4238.28 S1.2@4027.44,4238.28
  Top Layer w9.9: U32.V10@3604,3877.91 v2(3619.75,3893.66) ; U32.V14@3604,4003.89 v2(3619.75,4019.64)
  Bottom Layer w8: v2(3619.75,3893.66) 3639.07,3912.98 3639.07,4000.32 v2(3619.75,4019.64)
ADC_VREFHI_G2_10: C230.2 C231.2 C232.2 R295.2 S1.5 | length 1010.7
  Top Layer w8: R295.2@3712.95,3752.25 3744.59,3752.25 3803.43,3811.09 3879.59,3811.09 3941.38,3872.88 3941.38,3891.62 4117.25,4067.49 4243.87,4067.49 4322.84,4146.47 C230.2@4322.84,4170.98 4322.84,4212.49 4296.93,4238.4 C232.2@4275.6,4238.4 4275.48,4238.28 4240.94,4238.28 S1.5@4173.11,4238.28
BIST_EN_TPS3762: U32.A15 U44.6 | length 2200.4
  Top Layer w8: U32.A15@3068.57,4035.39 3027.32,4076.64 3027.32,4224.39 2973.72,4277.98 2973.72,4381.02 3080.12,4487.42 3829.81,4487.42 4054.98,4712.58 4614.33,4712.58 4618.45,4708.46 U44.6@4650.12,4708.46
BIST_TPS3762: R401.1 U32.C14 U44.5 | length 1991.5
  Top Layer w8: v1(4551.69,4734.5) R401.1@4593.28,4734.5 4593.51,4734.28 4649.9,4734.28 U44.5@4650.12,4734.05
  Top Layer w9.9: v2(3115.81,4019.64) U32.C14@3131.56,4003.89
  Bottom Layer w5: v2(3115.81,4019.64) 3131.61,4035.43 3131.61,4162.11
  Bottom Layer w8: 3131.61,4162.11 3144.02,4174.53 3173.54,4174.53 3201.58,4202.57 3201.58,4312.57 3218.24,4329.23 4146.42,4329.23 v1(4551.69,4734.5)
BRAKE_DRV8714: U27.14 U54.10 | length 1879.9
  Top Layer w8: U54.10@6727.91,2953.82 6728.92,2952.81 6728.92,2865.19 v1(6729.93,2864.17) ; v1(6733.89,1171.68) U27.14@6733.89,1191.54
  Bottom Layer w8: v1(6729.93,2864.17) 6741.9,2852.21 6741.9,2607.93 6681.45,2547.48 6681.45,1874.77 6725.34,1830.88 6725.34,1593.15 6764.53,1553.97 6764.53,1202.32 v1(6733.89,1171.68)
BST_1P1_25: C336.2 U43.40 | length 64.2
  Top Layer w10: U43.40@1117.44,4463.6 1118.93,4465.08 1178.92,4465.08 v1(1180.41,4466.56)
BST_2P1_25: C340.2 U43.45 | length 62.5
  Top Layer w15: U43.45@1117.5,4338.62 1175.03,4338.62 1177.56,4336.09 v1(1178.91,4336.09)
BST_3P1_25: C344.2 U43.17 | length 60.9
  Top Layer w15: v1(1431.23,4465.14) 1432.59,4465.14 1433.76,4463.97 1491.16,4463.97 U43.17@1491.46,4463.6
BST_4P1_25: C346.2 U43.12 | length 66.6
  Top Layer w15: v1(1429.25,4328.07) 1430.6,4328.07 1440.76,4338.22 1491.12,4338.22 U43.12@1491.46,4338.6
BST_19: C397.2 C398.2 U56.14 | length 179.9
  Top Layer w8: U56.14@7418.88,5210.88 7418.88,5228.45 7441.32,5250.89 7463.66,5250.89 7480.41,5267.65 C397.2@7480.41,5293.38 C398.2@7480.41,5352.17
CAN1_1046_N: C31.1 D10.1 J25.10 L3.3 R48.1 R49.2 | length 867.2
  Top Layer w4: J25.10@891.28,2548.11 898.52,2540.87 898.52,2511.98 1001.97,2408.53 1001.97,2386.5 1088.16,2300.31 1095.2,2300.31 1100.54,2305.65 D10.1@1100.54,2321.82 1283.56,2321.82 C31.1@1295.8,2334.05 1308.89,2347.15 v1(1428.14,2347.15) L3.3@1475.18,2347.15 1533.11,2347.15 R49.2@1533.27,2347
  Bottom Layer w4: v1(1428.14,2347.15) R48.1@1491.94,2347.15
CAN1_1046_P: C32.1 D10.2 J25.12 L3.4 R46.2 R47.2 | length 865
  Top Layer w4: J25.12@891.28,2448.11 891.28,2487.98 895.52,2492.21 901.6,2492.21 990.17,2403.65 990.17,2381.62 1089.01,2282.77 1089.01,2276.51 1094.89,2270.63 1288.91,2270.63 C32.1@1296.38,2263.16 1310.81,2248.73 v1(1429.2,2248.73) L3.4@1475.18,2248.73 1532.42,2248.73 R46.2@1533.69,2250
  Bottom Layer w4: v1(1429.2,2248.73) 1491.18,2248.73 R47.2@1491.94,2247.97
CAN2_1046_N: C35.1 D11.1 J25.6 L4.3 R52.1 R53.2 | length 812.9
  Top Layer w4: J25.6@891.28,2748.11 900.7,2738.7 900.7,2711.98 908.66,2704.01 952.23,2704.01 1048.66,2607.58 1091.94,2607.58 1100.1,2615.74 1100.1,2621.4 1105.98,2627.27 D11.1@1111.63,2627.27 1284.78,2627.27 C35.1@1295.51,2638.01 v1(1421.97,2638.01) 1461.61,2638.01 L4.3@1474.71,2651.1 1532.16,2651.1 R53.2@1533.27,2650
  Bottom Layer w4: v1(1421.97,2638.01) 1479.24,2638.01 R52.1@1491.94,2650.7
CAN2_1046_P: C36.1 D11.2 J25.8 L4.4 R50.2 R51.2 | length 813.9
  Top Layer w4: J25.8@891.28,2648.11 900.62,2657.45 900.62,2684.25 908.58,2692.21 947.34,2692.21 1043.77,2595.78 1091.94,2595.78 1100.1,2587.62 1100.1,2581.96 1105.98,2576.09 D11.2@1111.63,2576.09 1287.71,2576.09 C36.1@1296.69,2567.11 v1(1422.18,2567.11) 1460.28,2567.11 L4.4@1474.71,2552.68 1532.59,2552.68 R50.2@1533.27,2552
  Bottom Layer w4: v1(1422.18,2567.11) 1475.57,2567.11 R51.2@1491.94,2550.73
CAN2_RXD: U6.4 U32.A12 | length 1841.4
  Top Layer w8: U6.4@1998.6,3009.25 2569.32,3009.25 v1(2647.22,3087.14)
  Top Layer w9.9: v2(3052.82,3956.65) U32.A12@3068.57,3940.9
  Bottom Layer w9.9: v1(2647.22,3087.14) 2718.91,3158.83 2718.91,3794.65 2874.18,3949.92 2975.63,3949.92 2982.35,3956.65 v2(3052.82,3956.65)
CAN2_TXD: U6.1 U32.B12 | length 1949.5
  Top Layer w8: U6.1@1998.6,2859.25 v1(2134.68,2859.25) 2483.72,2859.25 v1(2683.91,3059.45)
  Top Layer w9.9: v2(3084.32,3956.65) U32.B12@3100.07,3940.9
  Bottom Layer w5: 3023.81,3932.42 3032.51,3941.12 3068.79,3941.12 v2(3084.32,3956.65)
  Bottom Layer w8: v1(2683.91,3059.45) 2744.98,3120.52 2744.98,3781.13 2896.28,3932.42 2959.09,3932.42 3023.81,3932.42
CAN5_RXD: U8.14 U32.C16 | length 1977.3
  Top Layer w8: U8.14@2344.99,2545.25 v1(2344.99,2581.72)
  Top Layer w9.9: v2(3115.81,4082.63) U32.C16@3131.56,4066.88
  PWR/SIG_1 w6: v1(2344.99,2581.72) 2348.77,2581.72 2355.13,2575.37 2446.89,2575.37 2464.17,2592.65 2464.17,2999.46 2795.02,3330.31 2795.02,3812.48 3049.23,4066.69 3059.42,4066.69 3059.8,4067.07 3100.25,4067.07 v2(3115.81,4082.63)
CAN5_TXD: U8.10 U32.A17 | length 1851.7
  Top Layer w8: U8.10@2423.73,2545.25 2423.73,2576.16 v1(2439.87,2592.31)
  Top Layer w9.9: v2(3052.82,4114.13) U32.A17@3068.57,4098.38
  PWR/SIG_1 w6: v1(2439.87,2592.31) 2439.87,3006.47 2776.43,3343.02 2776.43,3809.25 2988.41,4021.24 2988.41,4049.72 v2(3052.82,4114.13)
CAN6_RXD: U8.6 U32.B18 | length 2204.8
  Top Layer w8: v1(2404.04,2394.92) U8.6@2404.04,2427.14
  Top Layer w9.9: v2(3084.32,4145.62) U32.B18@3100.07,4129.88
  PWR/SIG_1 w5: 3025.15,4130.98 3069.68,4130.98 v2(3084.32,4145.62)
  PWR/SIG_1 w6: v1@2401.36,2392.24 v1(2404.04,2394.92) 2404.04,2425.36 2347.7,2481.7 2330.1,2481.7 2310.36,2501.44 2310.36,2518.9 2320.05,2528.58 2320.05,2900.69 2766.37,3347.01 2766.37,3813.25 2978.48,4025.36 2978.48,4084.31 3025.15,4130.98
CAN6_TXD: U8.3 U32.B17 | length 2258
  Top Layer w8: U8.3@2344.99,2427.14 v5(2344.99,2463.29)
  Top Layer w9.9: v2(3084.32,4114.13) U32.B17@3100.07,4098.38
  PWR/SIG_1 w4.5: v2(3084.32,4114.13) 3101.22,4131.03 3101.22,4158.37 3088.12,4171.47
  PWR/SIG_1 w6: v5(2344.99,2463.29) 2327.37,2463.29 2286.4,2504.27 2286.4,2926.19 2738.62,3378.41 2738.62,3915.73 2994.35,4171.47 3088.12,4171.47
CAN7_RXD: U5.4 U32.D16 | length 3494.3
  Top Layer w8: U5.4@1743.05,1593.99 v1(1787.93,1593.99)
  Top Layer w9.9: v2(3147.31,4082.63) U32.D16@3163.06,4066.88
  SIG_2 w4.5: v2(3147.31,4082.63) 3163.28,4098.61 3163.28,4158.14 3163.02,4158.4
  SIG_2 w6: v1(1787.93,1593.99) 1859.16,1665.22 1859.16,1800.47 1874.97,1816.29 1874.97,1965.39 1856.9,1983.47 1856.9,2518.9 2822.12,3484.12 2822.12,4125.1 2874.08,4177.06 3117.46,4177.06 3144.36,4177.06 3163.02,4158.4
CAN7_TXD: U5.1 U32.C17 | length 3433
  Top Layer w8: v1(1743.05,1515.73) U5.1@1743.05,1534.94
  Top Layer w9.9: v2(3115.81,4114.13) U32.C17@3131.56,4098.38
  SIG_2 w6: v1(1743.05,1515.73) 1902.82,1675.5 1902.82,2527.48 2825.53,3450.19 2825.53,3450.4 2845.13,3470 2845.13,4117.71 2859.79,4132.37 2952.05,4132.37 2986.66,4166.98 3097.13,4166.98 3105.71,4158.4 3115.81,4148.3 v2(3115.81,4114.13)
CAN_1043_N: C21.1 D8.1 J23.2 J24.2 L1.3 R38.1 R40.2 | length 1568.2
  Top Layer w4: J24.2@460.77,2201.77 460.77,2158.98 467.66,2152.1 550.57,2152.1 695.31,2007.36 695.31,1702.8 778.25,1619.86 799.03,1619.86 J23.2@843.13,1663.96 850.9,1656.19 850.9,1627.82 858.86,1619.86 897.05,1619.86 953.01,1563.89 989.26,1563.89 998.67,1573.3 998.67,1578.95 1003.29,1583.58 1169.78,1583.58 C21.1@1181.71,1595.51 v1(1292.67,1595.51) 1329.96,1595.51 L1.3@1343.95,1609.5 1344.45,1610 R40.2@1402.91,1610
  Bottom Layer w4: v1(1292.67,1595.51) 1345.42,1595.51 R38.1@1359.79,1609.88 R38.1@1359.79,1600.19
CAN_1043_P: C22.1 D8.2 J23.1 J24.7 L1.4 R36.2 R37.2 | length 1618.1
  Top Layer w4: J24.7@360.77,2147.83 454.69,2147.83 462.22,2140.3 545.69,2140.3 683.51,2002.47 683.51,1697.91 773.37,1608.06 799.03,1608.06 J23.1@843.13,1563.96 851.23,1572.05 851.23,1600.09 859.19,1608.06 892.16,1608.06 948.13,1552.09 989.26,1552.09 996.17,1545.18 996.17,1539.52 1003.29,1532.4 1008.95,1532.4 1172.89,1532.4 1181.56,1523.74 1182.6,1523.74 1195.25,1511.08 v1(1293.39,1511.08) L1.4@1343.95,1511.08 1345.03,1510 R36.2@1401.59,1510
  Bottom Layer w4: v1(1293.39,1511.08) 1357.8,1511.08 R37.2@1359.79,1509.09 R37.2@1359.79,1520.24
CAN_1044_N: C26.1 D9.1 J25.2 L2.3 R44.1 R45.2 | length 799.9
  Top Layer w4: J25.2@891.28,2948.11 902.78,2936.62 902.78,2913.19 911.96,2904.01 983.82,2904.01 1016.79,2936.99 1101.45,2936.99 1109.61,2945.15 1109.61,2950.8 1115.48,2956.68 D9.1@1121.14,2956.68 1309.14,2956.68 C26.1@1319.93,2967.47 v1(1450.64,2967.47) 1486.03,2967.47 L2.3@1499.13,2980.57 1556.14,2980.57 R45.2@1556.71,2980
  Bottom Layer w4: v1(1450.64,2967.47) 1500.17,2967.47 R44.1@1512.71,2980.01
CAN_1044_P: C27.1 D9.2 J25.4 L2.4 R42.2 R43.2 | length 799.4
  Top Layer w4: J25.4@891.28,2848.11 902.94,2859.78 902.94,2882.41 912.75,2892.21 988.71,2892.21 1021.68,2925.19 1101.45,2925.19 1109.61,2917.03 1109.61,2911.37 1115.48,2905.5 D9.2@1121.14,2905.5 1312.18,2905.5 C27.1@1321.11,2896.57 v1(1450.82,2896.57) 1484.7,2896.57 L2.4@1499.13,2882.14 1556.57,2882.14 R42.2@1556.71,2882
  Bottom Layer w4: v1(1450.82,2896.57) 1498.96,2896.57 R43.2@1512.71,2882.81
CAP_4: C6.1 U1.23 | length 133.7
  Top Layer w8: C6.1@5442.63,5016.57 5442.63,4947.12 5473.59,4916.16 U1.23@5473.59,4895.68
ClassD_AMP_FAULT: R395.1 U43.3 U54.5 | length 7593.8
  Top Layer w8: U43.3@1491.46,4113.6 1567.99,4113.62 v1@1586.58,4095.02 ; v1(1588.87,4094.51) R395.1@1623.87,4094.51 ; v1(4704.79,1635.78) 5592.84,1635.78 6255.97,2298.91 6255.97,2587.07 6263.21,2594.32 6364.75,2594.32 6629.48,2859.06 U54.5@6629.48,2953.82
  SIG_3 w8: v1(1588.87,4094.51) 1612.42,4070.96 1756.16,4070.96 1839.26,3987.86 1839.26,3028.2 2087.81,2779.64 2781.92,2779.64 3015.94,2545.62 3015.94,2435.34 3163.82,2287.46 3517.99,2287.46 3869.3,1936.15 4048.61,1936.15 4348.98,1635.78 v1(4704.79,1635.78)
ClassD_AMP_FSYNC: R388.1 U17.4 | length 1571.8
  Top Layer w9.9: R388.1@2078.69,5151.61 2098.38,5151.61 2150.93,5204.16 2150.93,5621.08 2419.36,5889.51 2419.36,6505.45 2391.7,6533.12 U17.4@2391.7,6559.3
ClassD_AMP_SCLk: R387.1 U14.4 | length 2456.6
  Top Layer w9.9: R387.1@2079.24,5215.06 2080.23,5215.06 2093.98,5228.81 2093.98,5229.8 2108.64,5244.45 2108.64,5669.71 2300.6,5861.67 2300.6,6366.65 2212.01,6455.24 2212.01,6619.79 2305.2,6712.98 2892.34,6712.98 3013.65,6591.67 U14.4@3013.65,6559.25
ClassD_AMP_SDIN_1: R390.1 U32.G18 | length 1700
  Top Layer w8: R390.1@2078.69,5092.57 v1(2128.48,5092.57)
  Top Layer w9.9: v2(3241.8,4145.62) U32.G18@3257.55,4129.88
  SIG_1 w4.5: v1(2128.48,5092.57) 2132.21,5092.57 2183.4,5041.38 2183.4,4832.47 2213.44,4802.43 2290.83,4802.43 2616.85,4476.41 2752.42,4476.41 2987.72,4241.11 3052.09,4241.11 3089.03,4204.17 3129.61,4204.17 3151.91,4181.86 3186.12,4181.86 3203.22,4164.76 3222.66,4164.76 v2(3241.8,4145.62)
ClassD_AMP_SDOUT_1: R391.1 R392.1 U32.F17 | length 1680.4
  Top Layer w8: R391.1@2078.69,5033.53 R392.1@2078.69,4974.49 v1(2123.05,4974.49)
  Top Layer w9.9: v2(3210.3,4114.13) U32.F17@3226.05,4098.38
  SIG_1 w4.5: v1(2123.05,4974.49) 2125.21,4974.49 2174.97,4924.73 2174.97,4758.71 2238.09,4695.59 2358.36,4695.59 2600.23,4453.73 2745.22,4453.73 3033.31,4165.64 3182.41,4165.64 3193.63,4154.41 3193.63,4130.8 v2(3210.3,4114.13)
ClassD_AMP_SHTDN: R393.1 U43.2 U54.6 | length 7645.3
  Top Layer w8: U43.2@1491.46,4088.6 1538.62,4088.62 v1@1590.54,4036.69 ; v1(1588.87,4036.69) v1@1590.54,4036.69 ; R393.1@1623.87,4036.69 v1@1590.54,4036.69 ; v1(4736.28,1616.1) 5601,1616.1 6273.37,2288.47 6273.37,2581.32 6370.13,2581.32 6649.17,2860.36 U54.6@6649.17,2953.82
  SIG_3 w8: v1(1588.87,4036.69) 1616.82,4008.74 1763.88,4008.74 1816.09,3956.52 1816.09,2995.92 2067.78,2744.24 2777.04,2744.24 2980.65,2540.62 2980.65,2417.81 3145.61,2252.85 3505.05,2252.85 3851.2,1906.7 4042.83,1906.7 4347.66,1601.88 4722.05,1601.88 v1(4736.28,1616.1)
ClassD_AMP_STBY: R394.1 U43.1 U54.4 | length 7774.2
  Top Layer w8: U43.1@1491.46,4063.6 1514.89,4063.6 1518.76,4059.72 1518.76,4046.95 v1(1588.87,3976.84) R394.1@1623.87,3976.84 ; v1(4736.28,1655.47) 5584.69,1655.47 6240.68,2311.46 6240.68,2590.17 6257.83,2607.32 6356.63,2607.32 6609.8,2860.48 U54.4@6609.8,2953.82
  SIG_3 w8: v1(1588.87,3976.84) 1563.24,4002.47 1563.24,4099.32 1589.38,4125.46 1768.7,4125.46 1864.02,4030.14 1864.02,3060.65 2108.72,2815.95 2793.14,2815.95 3044.7,2564.39 3044.7,2460.07 3183.96,2320.81 3536.52,2320.81 3893.26,1964.07 4059.97,1964.07 4352.89,1671.15 4720.59,1671.15 v1(4736.28,1655.47)
CRS_DV/RX_CTRL_ETH1: R245.2 U13.11 | length 2741
  Top Layer w9.9: v1(3200.74,6592.64) 3228.5,6620.4 3306.85,6620.4 3316.62,6610.63 U13.11@3316.62,6547.96 ; R245.2@3598.22,4355.71 v1(3598.22,4377.1)
  SIG_1 w3.6: v1(3200.74,6592.64) 3199.28,6591.18 3185.34,6591.18 3129.92,6535.76 3129.92,6488.48 3129.92,6407.48 3129.92,6171.05 3183.72,6117.25 3183.72,5667.38 3135,5618.66 3135,5411.32 3088.98,5365.3 3088.98,5030.13 3598.22,4520.89 v1(3598.22,4377.1)
CRS_DV/RX_CTRL_ETH2: R230.1 U19.11 | length 3434
  Top Layer w9.9: U19.11@1505.97,6547.96 v1(1505.97,6573.35) ; R230.1@3165.93,4355.71 v1(3165.93,4377.1)
  SIG_3 w3.6: v1(1505.97,6573.35) 1527.45,6551.87 1553.67,6551.87 1685.14,6420.4 2204.41,6420.4 2741.82,5882.99 2741.82,5705.21 2750.04,5696.99 2751.31,5695.72 ccw(c2759.65,5704.06) 2768,5695.72 2769.03,5696.75 cw(c2777.38,5688.41) 2785.72,5696.75 cw(c2777.38,5688.41) 2785.72,5680.07 2784.69,5679.03 ccw(c2793.03,5670.69) 2784.69,5662.34 2805.45,5641.58 2806.72,5640.31 2818.88,5628.15 2818.88,5601.94 2818.88,5576.54 cw(c2807.08,5576.54) 2807.08,5564.74 2792.59,5564.74 ccw(c2792.59,5552.94) 2792.59,5541.14 2807.08,5541.14 cw(c2807.08,5529.34) 2818.88,5529.34 2818.88,5509.33 2818.88,5183.07 2846.69,5155.27 3215.94,4786.01 3215.94,4363.42 3206.33,4353.81 3189.22,4353.81 v1(3165.93,4377.1)
CS1+_19: C395.2 R461.1 U56.20 | length 324.6
  Top Layer w5: R461.1@7011.89,5167.15 7037.59,5192.85 7154.81,5192.85 C395.2@7180.6,5167.06 7182.06,5165.6 U56.20@7314.55,5165.6
CS1-_19: C395.1 C396.1 R462.1 U56.19 | length 286
  Top Layer w5: R462.1@7068.34,5229.95 7093.98,5204.31 7154.86,5204.31 C395.1@7180.6,5230.05 7213.55,5197.1 C396.1@7240.43,5197.1 7252.24,5185.29 U56.19@7314.55,5185.29
CS2+_19: C388.2 R453.1 U56.24 | length 275.7
  Top Layer w8: v1(7282.45,5066.24) 7304.92,5066.24 7314.55,5075.87 U56.24@7314.55,5086.86
  Bottom Layer w5: R453.1@7242.96,5251.3 7271.08,5223.19 7271.08,5204.85 C388.2@7244.84,5178.61 7270.51,5152.94 7270.51,5107.42 7264.82,5101.73 7264.82,5082.58 7281.16,5066.24 v1(7282.45,5066.24)
CS2-_19: C388.1 R454.1 U56.23 | length 231.4
  Top Layer w8: v1(7282.45,5091.24) 7297.76,5106.55 U56.23@7314.55,5106.55
  Bottom Layer w5: v1(7282.45,5091.24) 7282.45,5153.23 C388.1@7307.83,5178.61 7281.89,5204.56 7281.89,5223.11 R454.1@7310.09,5251.3
CS+_4: C1.2 R16.1 U1.20 | length 269.7
  Top Layer w5: U1.20@5532.64,4895.68 5532.64,4915.47 5591.26,4974.1 5636.08,4974.1 C1.2@5664.87,5002.89 5690.03,5028.05 5690.03,5038.59 R16.1@5665,5063.61
CS-_4: C1.1 C9.2 Q2.5 Q4.5 R15.2 U1.19 | length 583.2
  Top Layer w5: U1.19@5552.33,4895.68 5552.33,4915.73 5580.07,4943.47 C9.2@5630.4,4943.47 5661.75,4974.82 5700.13,4974.82 5727.87,5002.56 C1.1@5727.87,5002.89 5702.44,5028.32 5702.44,5042.86 5696.33,5048.96 5696.33,5289.83 5707.4,5300.9 5743.07,5300.9
  other v1: 5744.35,4006.36 5844.35,4006.36 5944.35,4006.36 6044.35,4006.36 6144.35,4006.36 6244.35,4006.36 6344.35,4006.36 5694.35,4056.36 5794.35,4056.36 5894.35,4056.36 5994.35,4056.36 6094.35,4056.36 6194.35,4056.36 6294.35,4056.36 6394.35,4056.36 5744.35,4106.36 5844.35,4106.36 5944.35,4106.36 6044.35,4106.36 6144.35,4106.36 6244.35,4106.36 6344.35,4106.36 5714.19,4239.86 6486.82,4244.87 5789.19,4264.86 5871.89,4265.14 5921.89,4265.14 5971.89,4265.14 6021.89,4265.14 6071.89,4265.14 6121.89,4265.14 6171.89,4265.14 6221.89,4265.14 6271.89,4265.14 6411.82,4269.87 5714.19,4289.86 6486.82,4294.87 5789.19,4314.86 6411.82,4319.87 5714.19,4339.86 5896.89,4340.14 5946.89,4340.14 5996.89,4340.14 6046.89,4340.14 6096.89,4340.14 6146.89,4340.14 6196.89,4340.14 6246.89,4340.14 6486.82,4344.87 5789.19,4364.86 6411.82,4369.87 5714.19,4389.86 6486.82,4394.87 5789.19,4414.86 6411.82,4419.87 5714.19,4439.86 6486.82,4444.87 5789.19,4464.86 6411.82,4469.87 5714.19,4489.86 6486.82,4494.87 5789.19,4514.86 6411.82,4519.87 5714.19,4539.86 6486.82,4544.87 5789.19,4564.86 6411.82,4569.87 5714.19,4589.86 6486.82,4594.87 5789.19,4614.86 6411.82,4619.87 5714.19,4639.86 6486.82,4644.87 6872.79,4737.25 6947.79,4737.25 7022.79,4737.25 7097.79,4737.25 7172.79,4737.25 7247.79,4737.25 7322.79,4737.25 6835.79,4812.25 6910.79,4812.25 6985.79,4812.25 7060.79,4812.25 7135.79,4812.25 7210.79,4812.25 7285.79,4812.25 7360.79,4812.25 6474.13,4915.82 6524.13,4915.82 6449.13,4945.82 6499.13,4945.82 5805.33,5059.92 5755.33,5084.92 5855.33,5084.92 6532.56,5106.99 5805.33,5109.92 5905.33,5109.92 5855.33,5134.92 6155.33,5134.92 6455.33,5134.92 6532.56,5156.99 5805.33,5159.92 5905.33,5159.92 6205.33,5159.92 5855.33,5184.92 6155.33,5184.92 6455.33,5184.92 6532.56,5206.99 5805.33,5209.92 5905.33,5209.92 6205.33,5209.92 5855.33,5234.92 6155.33,5234.92 6455.33,5234.92 5805.33,5259.92 5905.33,5259.92 6205.33,5259.92 5855.33,5284.92 6155.33,5284.92 6455.33,5284.92 5805.33,5309.92 5905.33,5309.92 6205.33,5309.92 5855.33,5334.92 5955.33,5334.92 6055.33,5334.92 6155.33,5334.92 6255.33,5334.92 6355.33,5334.92 6455.33,5334.92 5805.33,5359.92 5905.33,5359.92 6005.33,5359.92 6105.33,5359.92 6205.33,5359.92 6305.33,5359.92 6405.33,5359.92 5855.33,5384.92 5955.33,5384.92 6055.33,5384.92 6155.33,5384.92 6255.33,5384.92 6355.33,5384.92 5805.33,5409.92 5905.33,5409.92 6005.33,5409.92 6105.33,5409.92 6205.33,5409.92 6305.33,5409.92
CS_15: R91.2 U20.15 U21.15 | length 986.3
  Top Layer w8: U21.15@3703.19,1085.52 3744.18,1085.52 v1(3769.37,1110.71) ; U20.15@4205.84,1435.53 4261.55,1435.53 4271.55,1445.53 R91.2@4311.77,1445.53 v1(4311.77,1481.06)
  Bottom Layer w8: v1(3769.37,1110.71) 3789.01,1130.35 4042.44,1130.35 4213.61,1301.52 4213.61,1418 4276.66,1481.06 v1(4311.77,1481.06)
CS_IO: J19.6 R219.1 R447.2 U54.28 | length 5220.3
  Top Layer w8: v1(3083.7,3290.35) 3111.6,3318.25 R219.1@3111.6,3461.02 ; v2(6437.02,3240.34) 6437.02,3359.32 6492.91,3415.21 6587.51,3415.21 6626.93,3375.79 R447.2@6627.91,3375.79 ; R447.2@6615.72,3374.27 6629.63,3360.36 6629.63,3127.2 U54.28@6629.48,3127.05
  SIG_2 w6: v1(3083.7,3290.35) 3083.97,3290.35 3094.22,3280.11 3198.96,3280.11 3204.65,3274.41 3555.15,3274.41 3594.69,3313.95 3847.97,3313.95 J19.6@4167.42,3633.4 4259.35,3541.48 4259.35,3451.11 4473.9,3236.55 4785.45,3236.55 4844.23,3177.78 4844.23,3100.04 5131.6,2812.67 5633.21,2812.67 5697.64,2748.24 6324.99,2748.24 6479.85,2903.1 6479.85,3197.51 v2(6437.02,3240.34)
CS_IO_1_MCU: J19.5 U32.F4 U51.15 | length 4727.9
  Top Layer w8: v1(4355.48,4400.07) 4367.07,4411.66 U51.15@4482.15,4411.66
  Top Layer w9.9: v2(3210.3,3673.18) U32.F4@3226.05,3688.93
  SIG_1 w4.5: v2(3210.3,3673.18) 3226.09,3688.97 3226.09,3847.19 3240.98,3862.09 3299.62,3862.09 3347,3909.47 3626.92,3909.47 3633.48,3916.02 3855.27,4137.82 3921.13,4137.82 3958.14,4174.82 3958.14,4176.09 3967.62,4185.57 3968.89,4185.57 4183.38,4400.07 v1(4355.48,4400.07)
  SIG_3 w6: J19.5@4167.42,3533.4 5461.01,3533.4 5483.92,3556.31 5483.92,3785.83 5227.95,4041.8 4748.8,4041.8 4572.13,4218.48 4572.13,4366.12 4526.59,4411.66 4367.07,4411.66 v1(4355.48,4400.07)
CS_IO_1_MUX_26: R185.2 U31.15 U51.9 | length 11658.1
  Top Layer w8: U31.15@517.17,1158.1 517.17,1291.9 R185.2@515.79,1293.28 v1(557,1293.28) ; U51.9@4710.5,4386.07 4835.57,4386.07 v1(4870.63,4421.13)
  SIG_1 w6: v1(557,1293.28) 557,2661.4 370.01,2848.39 370.01,4928.86 284.89,5013.98 284.89,5906.66 1058.48,6680.26 3872.05,6680.26 4710.18,5842.13 4710.18,4714.84 4870.63,4554.39 v1(4870.63,4421.13)
CS_LD_1: R90.2 R91.1 U51.7 | length 3138.9
  Top Layer w8: R91.1@4374.76,1445.53 4374.76,1494.64 R90.2@4374.68,1494.72 4401.83,1494.72 4726.32,1819.21 4726.32,4062.28 4643.62,4144.99 4643.62,4312.45 4666.05,4334.89 U51.7@4710.5,4334.89
CS_LD_1_MCU: J17.10 U32.J4 U51.17 | length 2548.9
  Top Layer w8: v1(4419,4347.7) 4431.78,4360.48 U51.17@4482.15,4360.48
  Top Layer w9.9: v2(3304.79,3673.18) U32.J4@3320.54,3688.93
  SIG_1 w4.5: J17.10@2946.96,2937.36 2881.06,3003.26 2881.06,3232.56 3213.64,3565.14 3225.08,3576.58 3225.08,3649.38 3233.49,3657.79 3289.4,3657.79 v2(3304.79,3673.18) 3321.19,3689.58 3321.19,3843.42 3355.32,3877.55 3624.03,3877.55 3633.48,3887 3634,3887.53 3634,3892.76 3844.66,4103.41 3942.23,4103.41 4186.54,4347.73 v1(4419,4347.7)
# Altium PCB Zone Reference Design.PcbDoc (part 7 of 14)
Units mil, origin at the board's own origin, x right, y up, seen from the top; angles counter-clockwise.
Board outline 8858.11 x 7047.08 mil, 16 copper layers (Top Layer, GND_1, SIG_1, GND_2, PWR/SIG_1, GND_3, PWR_1, PWR_2, GND_4, PWR/SIG_2, GND_5, SIG_2, GND_6, SIG_3, GND_7, Bottom Layer), stack 80.368 mil thick; 1131 components, 808 nets, 3825 pads, 3523 vias.
Unrouted connection lines stored in the file: 563.

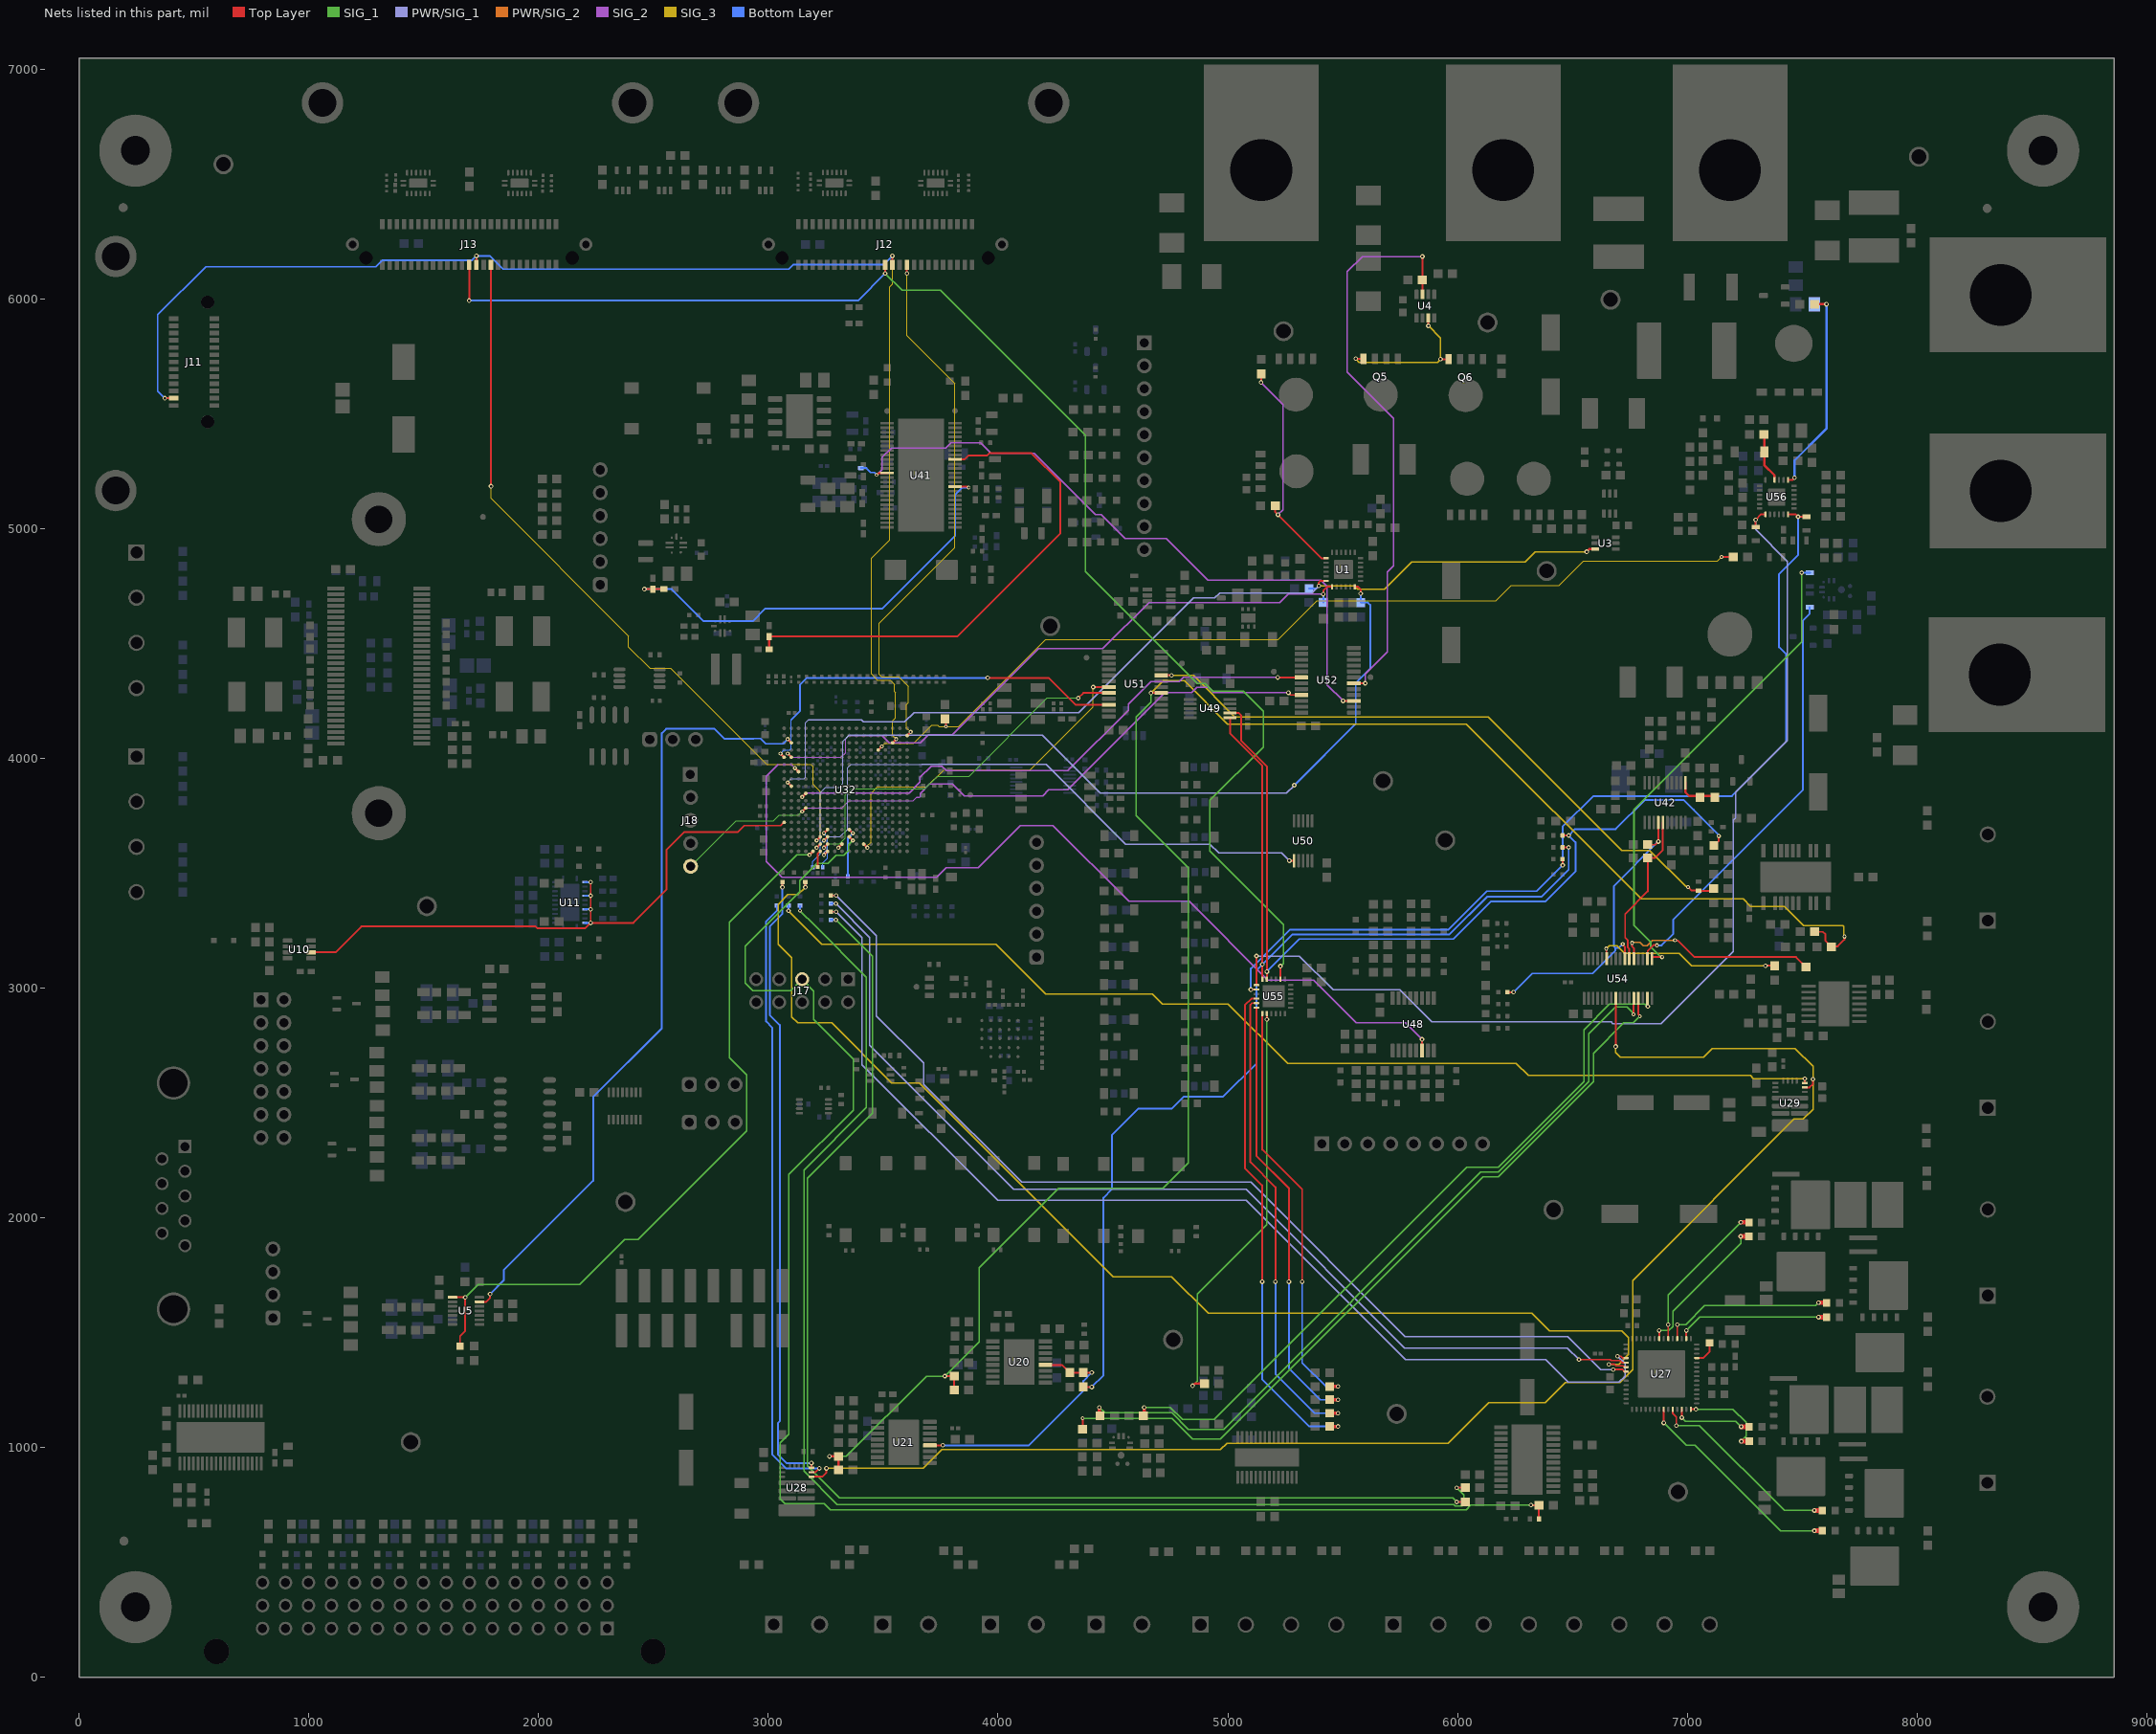
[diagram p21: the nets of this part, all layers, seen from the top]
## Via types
v1: diameter 20, hole 10, Top Layer to Bottom Layer, tented both sides, 2450 vias
v2: diameter 18, hole 8, Top Layer to Bottom Layer, tented both sides, 400 vias
v3: diameter 32, hole 16, Top Layer to Bottom Layer, tented both sides, 348 vias
v4: diameter 19.68, hole 7.87, Top Layer to Bottom Layer, tented both sides, 245 vias
v5: diameter 16, hole 8, Top Layer to Bottom Layer, tented both sides, 60 vias
v6: diameter 16, hole 8, Top Layer to Bottom Layer, 14 vias
v7: diameter 24.8, hole 12.99, Top Layer to Bottom Layer, tented both sides, 6 vias

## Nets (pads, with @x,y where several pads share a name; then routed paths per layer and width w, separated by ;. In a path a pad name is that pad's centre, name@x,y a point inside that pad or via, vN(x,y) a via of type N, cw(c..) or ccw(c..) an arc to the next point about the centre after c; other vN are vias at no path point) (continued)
CS_LD_2: R107.2 R108.1 U51.8 | length 2790.7
  Top Layer w8: U51.8@4710.5,4360.48 v1(4754.94,4360.48) ; v2(7003.62,3438.73) 7018.65,3423.69 7048.13,3423.69 R107.2@7049.09,3422.72 7102.94,3422.72 R108.1@7109.87,3429.66
  SIG_3 w6: v1(4754.94,4360.48) 4850,4360.48 5030.87,4179.61 6133.87,4179.61 6714.96,3598.52 6835.54,3598.52 6993.03,3441.02 7001.32,3441.02 v2(7003.62,3438.73)
CS_LD_4: J17.5 R178.2 R179.1 U32.K3 | length 7045.5
  Top Layer w8: v1(6319.69,748.54) R179.1@6354.44,748.54 6354.17,748.28 R178.2@6354.17,688.28
  Top Layer w9.9: U32.K3@3352.03,3657.44 v2(3367.78,3641.69)
  SIG_1 w6: v2(3367.78,3641.69) 3349.16,3623.06 3349.16,3597.79 3327.66,3576.29 3294.61,3576.29 3259.92,3541.61 3211.68,3541.61 3136.21,3466.14 3136.21,3418.54 2898.33,3180.65 2898.33,3021.57 2932.59,2987.3 3096.9,2987.3 J17.5@3146.96,3037.36 3197.99,2986.33 3197.99,2861.95 3369.59,2690.35 3369.59,2467.84 3089.15,2187.4 3089.15,1057.55 3051.14,1019.54 3051.14,776.1 3072.98,754.26 3243.63,754.26 3269.87,728.02 6036.91,728.02 6057.43,748.54 v1(6319.69,748.54)
CS_PMIC_1: R338.2 U41.36 U52.3 | length 3013
  Top Layer w8: v5(3471.55,5232.56) 3472.8,5232.56 3481.16,5240.92 U41.36@3516.97,5240.92 ; v1(5501.71,4249.05) U52.3@5548.39,4249.05
  SIG_2 w6: v5(3471.55,5232.56) 3495.67,5256.68 3495.67,5309.09 3535.78,5349.21 3771.85,5349.21 3794.21,5371.56 3924.36,5371.56 3969.4,5326.52 4156.58,5326.52 4423.46,5059.64 4449.21,5059.64 4553.97,4954.88 4733.01,4954.88 4912.84,4775.05 5405.7,4775.05 5432.5,4748.25 5432.5,4652.11 5431.54,4651.15 5431.54,4319.22 v1(5501.71,4249.05)
  Bottom Layer w8: R338.2@3402.57,5262.49 3426.56,5262.49 3445.92,5243.13 3460.97,5243.13 v5(3471.55,5232.56)
CS_PMIC_MCU: J18.5 U32.D7 U52.21 | length 3070
  Top Layer w8: v1(5263.95,4284.52) 5273.83,4274.64 U52.21@5320.04,4274.64
  Top Layer w9.9: v2(3147.31,3767.67) U32.D7@3163.06,3783.42
  SIG_1 w4.5: J18.5@2661.16,3528.88 2859.82,3727.54 3022.33,3727.54 3046.38,3751.59 3131.23,3751.59 v2(3147.31,3767.67)
  SIG_2 w4.5: v2(3147.31,3767.67) 3163.04,3783.4 3319.5,3783.4 3351.09,3814.98 3631.23,3814.98 3644.51,3828.27
  SIG_2 w6: 3644.51,3828.27 3658.07,3828.27 3661.59,3831.78 3661.59,3846.58 3702.02,3887.01 3800.84,3887.01 3852.51,3835.34 4013.74,3835.34 4013.96,3835.56 4194.11,3835.56 4220.48,3861.93 4303.07,3861.93 4725.66,4284.52 4841.47,4284.52 4865.94,4309 4914.82,4309 4939.3,4284.52 v1(5263.95,4284.52)
DGATE_4: R18.1 R19.1 U1.1 | length 994.3
  Top Layer w8: v1(5144.87,5635.35) R19.1@5144.87,5672.86 ; R18.1@5206.25,5097.68 5206.25,5071.18 v1(5218.23,5059.2) 5407.33,4870.09 U1.1@5428.31,4870.09
  SIG_2 w6: v1(5144.87,5635.35) 5240.44,5539.78 5240.44,5081.41 v1(5218.23,5059.2)
DI_HCS: R81.1 R82.2 R93.1 R94.2 R106.1 R109.2 U51.5 | length 8414.5
  Top Layer w8: v1(3768.5,1309.91) R82.2@3808.78,1309.91 R81.1@3808.78,1250.54 ; v1(4665.78,4283.7) U51.5@4710.5,4283.7 ; R109.2@7554.8,3249.83 7560.69,3243.94 7590.37,3243.94 7601.61,3232.7 7601.61,3205.06 7611.82,3194.84 7611.82,3193.86 7626.53,3179.16 R106.1@7627.51,3179.16 7629.46,3181.11 7654.51,3181.11 7683.71,3210.31 7683.71,3223.29 v2(7684.07,3223.65)
  Top Layer w10: v1(3266.04,960.82) R94.2@3305.83,960.82 R93.1@3305.83,900.91
  SIG_1 w6: v1(3266.04,960.82) 3338.8,960.82 3687.88,1309.91 v1(3768.5,1309.91) 3917.79,1459.21 3917.79,1782.3 4263.55,2128.05 4717.3,2128.05 4827.81,2238.56 4827.81,3522.83 4601.36,3749.28 4601.36,4179.35 4665.78,4243.77 v1(4665.78,4283.7)
  SIG_3 w6: v1(4665.78,4283.7) 4718.73,4336.66 4810.8,4336.66 4998.84,4148.62 6038.49,4148.62 6799.86,3387.24 7242.86,3387.24 7275.82,3354.29 7422.67,3354.29 7505.97,3271 7676.84,3271 7680.36,3267.48 v2@7680.36,3223.65
DI_HCS_MCU: U32.M2 U51.19 | length 1542.5
  Top Layer w8: v1(4414.18,4309.29) U51.19@4482.15,4309.29
  Top Layer w9.9: U32.M2@3415.03,3625.94 v2(3430.77,3610.19)
  SIG_3 w4.5: v2(3430.77,3610.19) 3430.77,3618.87 3446.2,3634.3 3446.2,3845.94 3474.57,3874.31 3633.48,3874.31 3689.45,3874.31 3763.38,3948.24 4138.88,3948.24 4414.18,4223.54 v1(4414.18,4309.29)
DIAGEN_TPS1HC04: R133.1 U54.18 | length 1844.5
  Top Layer w8: U54.18@6826.33,3127.05 6827.29,3128.01 6827.29,3160.37 6852.89,3185.97 6866.59,3185.97 v2(6867.59,3184.96)
  Bottom Layer w8: v2(6867.59,3184.96) 6888.59,3184.98 6937.96,3234.34 6937.96,3296.06 7503.56,3861.66 7503.56,4599.76 7532.3,4628.5
  Bottom Layer w10: 7532.3,4628.5 R133.1@7532.3,4656.76
DIAGEN_TPS1HC30: R116.1 U54.27 | length 818.4
  Top Layer w8: v2(6647.46,3170.79) 6648.31,3169.94 6648.31,3127.9 U54.27@6649.17,3127.05 ; v1(7340.3,3096.36) R116.1@7379.99,3096.36
  SIG_3 w6: v2(6647.46,3170.79) 6660.3,3183.63 6694.17,3183.63 6727.75,3150.05 6965.01,3150.05 7018.7,3096.36 v1(7340.3,3096.36)
DIAGEN_TPS2HC08: R117.1 U54.15 | length 3171.8
  Top Layer w8: U54.15@6826.33,2953.82 6827.35,2952.81 6827.35,2919.82 v1(6828.36,2918.8)
  Top Layer w15: R117.1@4635.46,1138.01 v1(4635.46,1174.02)
  SIG_1 w6: v1(4635.46,1174.02) 4749.59,1174.02 4802.63,1120.98 4940.19,1120.98 6039.26,2220.05 6178.15,2220.05 6549.52,2591.41 6549.52,2816.77 6661.6,2928.85 6814.53,2928.85 6824.58,2918.8 v1(6828.36,2918.8)
DIAGEN_TPS4HC120: R139.1 U55.14 | length 1809.6
  Top Layer w8: v1(5169.9,2863.13) U55.14@5169.9,2888.31
  Top Layer w10: v1(4846.95,1267.82) 4856.31,1277.18 R139.1@4898.44,1277.18
  SIG_1 w6: v1(4846.95,1267.82) 4867.45,1288.32 4867.45,1667.07 5169.9,1969.52 v1(5169.9,2863.13)
DRAIN_17: R150.2 U27.39 | length 105.2
  Top Layer w8: U27.39@7040.98,1388.39 7068.64,1388.39 7097.12,1416.87 R150.2@7097.12,1454.11
DRVOFF_DRV8145: U28.10 U29.11 U54.8 | length 6658
  Top Layer w8: U28.10@3187.41,872.03 3234.98,872.03 3252.96,890.01 v1(3252.96,908.51) ; v1(6688.49,2744.73) 6688.54,2744.77 U54.8@6688.54,2953.82 ; U29.11@7511.26,2566.74 7531.62,2566.74 7546.94,2582.06 v1(7546.94,2602.12)
  SIG_3 w6: v1(3252.96,908.51) 3675.05,908.51 3756.26,989.72 4968.18,989.72 4995.91,1017.45 5958.27,1017.45 6136.06,1195.24 6382.36,1195.24 6469.65,1282.53 6705.65,1282.53 6762.05,1338.93 6762.05,1726.26 7464.54,2428.75 7504.79,2428.75 7546.94,2470.9 v1(7546.94,2602.12) 7546.94,2658.27 7469.63,2735.58 7107.67,2735.58 7070.79,2698.7 6708.84,2698.7 6688.49,2719.05 v1(6688.49,2744.73)
EN1_TLIN1024A: U10.2 U11.2 U11.5 U11.8 U11.11 U32.A5 | length 2679.5
  Top Layer w8: U10.2@1009.74,3154.75 1115.76,3154.75 1228.18,3267.17 1987.05,3267.17 1995.29,3258.93 2202.58,3258.93 v1(2226.62,3282.97) ; v1(2226.62,3460.14) v1(2226.62,3401.08) v1(2226.62,3342.03) v1(2226.62,3282.97) ; U32.A5@3068.57,3720.43 3054.24,3706.1 3039.05,3706.1 2895.19,3706.1 2867.41,3678.32 2634.94,3678.32 2556.55,3599.93 2556.55,3427.3 2412.22,3282.97 v1(2226.62,3282.97)
  Bottom Layer w8: U11.11@2201.3,3282.97 v1(2226.62,3282.97) ; U11.8@2201.3,3342.03 v1(2226.62,3342.03) ; U11.5@2201.3,3401.08 v1(2226.62,3401.08) ; U11.2@2201.3,3460.14 v1(2226.62,3460.14)
EN1_TPS2HC08: R112.1 U54.12 | length 3371.2
  Top Layer w8: v5(6765.25,2884.95) 6766.41,2886.11 6766.41,2952.95 U54.12@6767.28,2953.82
  Top Layer w15: R112.1@4440.61,1137.95 v1(4440.61,1173.95)
  SIG_1 w6: v1(4440.61,1173.95) 4464.76,1149.8 4756.28,1149.8 4827.23,1078.85 4980.97,1078.85 6100.29,2198.17 6178.15,2198.17 6571.4,2591.41 6571.4,2801.01 6688.19,2917.8 6738.1,2917.8 6763.34,2892.56 6763.34,2886.86 v5(6765.25,2884.95)
EN1_TPS4HC120: R129.1 U55.10 | length 2172.4
  Top Layer w8: U55.10@5124.62,2953.27 5102.84,2953.27 5074.58,2925.02 5074.58,2215.38 5149.65,2140.3 v1(5149.65,1720.67)
  Top Layer w15: R129.1@5443.38,1091.07 v1(5479.38,1091.07)
  Bottom Layer w8: v1(5149.65,1720.67) 5149.65,1296.18 5354.76,1091.07 v1(5479.38,1091.07)
EN2_TPS2HC08: R115.1 U54.13 | length 3426.2
  Top Layer w8: R115.1@4367.49,1079.83 4367.82,1080.16 v5(4367.82,1127.11) ; U54.13@6786.96,2953.82 6786.96,2885.39 6793.67,2878.68 v5(6793.67,2876.51)
  SIG_1 w6: v5(4367.82,1127.11) 4369.6,1125.33 4758.02,1125.33 4847.36,1035.98 4967.39,1035.98 6109.81,2178.4 6178.15,2178.4 6591.17,2591.41 6591.17,2715.48 6722.92,2847.24 6764.4,2847.24 v5(6793.67,2876.51)
EN2_TPS4HC120: R132.1 U55.11 | length 2060
  Top Layer w8: U55.11@5124.62,2933.59 5105.86,2933.59 5097.87,2925.6 5097.87,2241.43 5207.26,2132.05 v1(5207.26,1720.67)
  Top Layer w15: R132.1@5443.38,1148.67 v1(5479.38,1148.67)
  Bottom Layer w8: v1(5207.26,1720.67) 5207.26,1320.04 5378.63,1148.67 v1(5479.38,1148.67)
EN3_TPS4HC120: R134.1 U55.12 | length 1934.6
  Top Layer w8: U55.12@5124.62,2913.9 5124.62,2269.64 5265.68,2128.58 v1(5265.68,1720.67)
  Top Layer w15: R134.1@5443.38,1207.1 v1(5479.38,1207.1)
  Bottom Layer w8: v1(5265.68,1720.67) 5265.68,1344.24 5402.83,1207.1 v1(5479.38,1207.1)
EN4_TPS4HC120: R136.1 U55.13 | length 1826.4
  Top Layer w8: U55.13@5150.21,2888.31 5150.21,2296.01 5323.6,2122.63 v1(5323.6,1720.67)
  Top Layer w15: R136.1@5443.38,1265.01 v1(5479.38,1265.01)
  Bottom Layer w8: v1(5323.6,1720.67) 5323.6,1368.23 5426.82,1265.01 v1(5479.38,1265.01)
EN/IN1_DRV8245: R214.1 U28.11 | length 2692
  Top Layer w8: U28.11@3187.41,891.71 3205.39,891.71 v1(3222.19,908.51)
  Bottom Layer w8: R214.1@3037.27,3358.38 3037.27,3335.7 2990.39,3288.82 2990.39,2853.8 3016.92,2827.27 3016.92,1021.31 3016.92,968.8 3077.22,908.51 v1(3222.19,908.51)
EN_ETH_1: J12.26 J13.26 U55.2 | length 6236.5
  Top Layer w8: v1(1697.78,5991.54) J13.26@1697.78,6147.8 ; v1(3508.44,6109.41) J12.26@3508.44,6147.8 ; U55.2@5228.95,3037.92 v1(5228.95,3094.52)
  SIG_1 w6: v1(3508.44,6109.41) 3581.85,6035.99 3748.98,6035.99 4380.16,5404.81 4380.16,4812.63 4867.39,4325.4 4901.71,4325.4 4934.9,4292.2 5067.04,4292.2 5154.24,4205 5154.24,4048.1 4921.94,3815.79 4921.94,3595.09 5241.45,3275.58 5241.45,3107.01 v1(5228.95,3094.52)
  Bottom Layer w8: v1(1697.78,5991.54) 3390.57,5991.54 v1(3508.44,6109.41)
EN_INA186: R25.1 U1.6 U3.3 U32.B10 | length 4213.6
  Top Layer w8: v1(5396.13,4749.31) 5396.13,4764.27 5403.53,4771.66 U1.6@5428.31,4771.66
  Top Layer w9.9: v2(3084.32,3893.66) U32.B10@3100.07,3877.91
  Top Layer w10: v1(6562.04,4898.2) 6573.98,4910.14 U3.3@6599.75,4910.14
  PWR/SIG_1 w4.5: v2(3084.32,3893.66) 3100.23,3909.56 3154.75,3909.56 3162.76,3917.58 3162.76,4154.63 3174.03,4165.9
  PWR/SIG_1 w6: 3174.03,4165.9 3406.31,4165.9 3414.71,4157.5 3592.69,4157.5 3633.74,4198.54 4351.87,4198.54 4849.88,4696.56 4943.27,4696.56 4965.37,4718.66 5365.48,4718.66 v1(5396.13,4749.31)
  SIG_3 w6: v1(5396.13,4749.31) 5550.73,4749.31 5565.35,4734.68 5681.32,4734.68 5800.12,4853.48 6293.92,4853.48 6338.65,4898.2 v1(6562.04,4898.2)
  Bottom Layer w8: R25.1@5353.74,4738.84 5385.67,4738.84 v1(5396.13,4749.31)
EN_TCAN1043A: U5.6 U32.B16 | length 3434.6
  Top Layer w8: U5.6@1743.05,1633.36 1772.19,1633.36 1788.56,1649.73 v1(1788.56,1667.04)
  Top Layer w9.9: v2(3084.32,4082.63) U32.B16@3100.07,4066.88
  Bottom Layer w6: 2935.42,4084.43 2966.35,4084.43 2987.94,4062.83 3039.05,4062.83 3041.51,4062.83 3064.52,4062.83 v2(3084.32,4082.63)
  Bottom Layer w8: v1@1788.56,1667.05 1848.13,1726.62 1848.13,1771.09 2237.43,2160.39 2237.43,2525.68 2535.96,2824.2 2535.96,4109 2554.68,4127.72 2765.32,4127.72 2808.61,4084.43 2935.42,4084.43
EN_TPS1HC04: R130.1 U54.17 | length 2114.4
  Top Layer w8: U54.17@6846.02,3127.05 6846.02,3132.21 6847.92,3134.11 v2(6890.38,3134.11)
  SIG_1 w8: v2(6890.38,3134.11) 6887.68,3134.11 6883.32,3138.47 6881.04,3138.47 6867.22,3152.29 6862.54,3156.98 6862.54,3157.19 6840.21,3179.52 6840.21,3200.92 6767.41,3273.72 6767.41,3775.75 7497.92,4506.25 v1(7497.92,4807.09)
  Bottom Layer w10: v1(7497.92,4807.09) R130.1@7532.63,4807.09
EN_TPS1HC30: R113.1 U54.21 | length 892.7
  Top Layer w8: v2(6759.72,3195.63) 6759.72,3180.1 6767.28,3172.54 U54.21@6767.28,3127.05 ; v2(6946.4,3207.08) 6946.95,3206.53 6959.03,3206.53 7031.55,3134.02 7473.48,3134.02 7500.41,3107.09 7500.41,3106.1 7514.97,3091.54 R113.1@7515.96,3091.54
  PWR/SIG_2 w6: v2(6759.72,3195.63) 6761.64,3197.54 6794.25,3197.54 6808.26,3183.54 6824.36,3183.54 6847.91,3207.08 v2(6946.4,3207.08)
EN_TPS1214: R464.1 U55.7 U56.1 | length 4571.8
  Top Layer w8: U55.7@5124.62,3012.33 v1(5124.62,3138.69) ; R464.1@7297.3,5005.9 v1(7297.3,5037.35) 7321.23,5061.27 U56.1@7340.14,5061.27
  PWR/SIG_1 w6: v1(5124.62,3138.69) 5311.4,3138.69 5458.03,2992.06 5747.55,2992.06 5888.27,2851.35 6668.24,2851.35 6675.59,2843.99 6885.42,2843.99 7199.96,3158.53 7199.96,3730.39 7209.89,3740.33 7209.89,3852.19 7435.41,4077.71 7435.41,4856.54 7297.3,4994.65 v1(7297.3,5037.35)
EPWM0_B: R215.1 U28.12 | length 2718
  Top Layer w8: v1(3061.31,3438.34) R215.1@3061.31,3461.02 ; U28.12@3187.41,911.4 v1(3187.41,931.49)
  Bottom Layer w8: v1(3061.31,3438.34) 3061.31,3322.66 3006.41,3267.77 3006.41,2881.5 3049.5,2838.41 3049.5,1113.55 3041.2,1105.26 3041.2,968.8 3078.52,931.49 v1(3187.41,931.49)
EPWM1_A: R173.1 R216.1 | length 5510
  Top Layer w8: v1(5996.28,762.53) R173.1@6032.96,762.53
  SIG_1 w6: v1(3294.1,3296.13) 3452.63,3137.59 3452.63,2453.98 3169.89,2171.23 3169.89,919.79 3310.64,779.04 5979.77,779.04 v1(5996.28,762.53)
  Bottom Layer w8: R216.1@3271.42,3296.13 v1(3294.1,3296.13)
EPWM1_B: R174.1 R217.1 | length 5752.3
  Top Layer w8: v1(5996.28,824.01) R174.1@6032.96,824.01
  SIG_1 w6: v5(3137.71,3335.7) 3202.48,3270.93 3426.92,3046.49 3426.92,2478.93 3155.16,2207.17 3155.16,895.82 3300.2,750.78 5984.08,750.78 5989.27,745.59 6018.71,745.59 6027.41,754.3 6027.41,792.88 v1(5996.28,824.01)
  Bottom Layer w8: v5(3137.71,3335.7) R217.1@3137.71,3358.38
EPWM2_A: R218.1 U29.12 | length 4767.8
  Top Layer w8: U29.12@7511.26,2586.43 v1(7511.26,2604.53)
  SIG_3 w6: v1(3087.67,3335.7) 3087.67,3334.71 3231.74,3190.64 3989.64,3190.64 4206.57,2973.71 4672.51,2973.71 4715.89,2930.32 5001.61,2930.32 5260.48,2671.46 6254.92,2671.46 6307.8,2618.57 7274.45,2618.57 7288.49,2604.53 v1(7511.26,2604.53)
  Bottom Layer w8: v1(3087.67,3335.7) R218.1@3087.67,3358.38
EPWM3_A: R220.1 U27.4 | length 4782.7
  Top Layer w8: R220.1@3271.42,3331.46 v1(3294.75,3331.46) ; v1(6696.1,1396.91) 6696.64,1396.37 6710.68,1396.37 6718.38,1388.67 6733.62,1388.67 U27.4@6733.89,1388.39
  PWR/SIG_1 w6: v1(3294.75,3331.46) 3408.17,3218.04 3408.17,2665.14 3998.29,2075.02 5080.24,2075.02 5773.97,1381.29 6383.2,1381.29 6481.35,1283.14 6702.65,1283.14 6728.41,1308.9 6728.41,1364.6 v1(6696.1,1396.91)
EPWM3_B: R224.1 U27.5 | length 4565.3
  Top Layer w8: v1(6528.51,1381.95) 6663.69,1381.95 6665.15,1380.49 6666.65,1380.49 6669.23,1377.91 6705.63,1377.91 6714.83,1368.71 U27.5@6733.89,1368.71
  PWR/SIG_1 w6: v1(3294.1,3366.78) 3441.73,3219.15 3441.73,2749.28 3759.4,2431.61 4067.89,2123.12 5079.64,2123.12 5769.87,1432.89 6477.56,1432.89 v1(6528.51,1381.95)
  Bottom Layer w8: R224.1@3271.42,3366.78 v1(3294.1,3366.78)
EPWM4_A: R227.1 U27.6 | length 5165.2
  Top Layer w8: v1(3161.13,3438.34) R227.1@3161.13,3461.02 ; v1(6658.78,1361.49) 6683.23,1361.49 6689.74,1354.99 6721.4,1354.99 6726.08,1350.3 6726.08,1350.14 6727.2,1349.02 U27.6@6733.89,1349.02
  SIG_3 w6: v1(3161.13,3438.34) 3128.87,3406.09 3085.55,3406.09 3042.66,3363.19 3042.66,3189.74 3101.32,3131.08 3101.32,2873.79 3127.97,2847.14 3276.93,2847.14 3537.64,2586.44 3657.75,2586.44 4501.36,1742.83 4754.88,1742.83 4914.75,1582.97 6323.78,1582.97 6399.77,1506.98 6714.91,1506.98 6744.97,1476.92 6744.97,1404.22 6702.24,1361.49 v1(6658.78,1361.49)
EPWM4_B: R229.1 U27.7 | length 4579.5
  Top Layer w8: R229.1@3271.42,3402.11 v1(3294.75,3402.11) ; v1(6677.17,1338.58) 6717.84,1338.58 6721.12,1335.3 6721.4,1335.3 6726.08,1330.61 6726.08,1330.46 6727.2,1329.34 U27.7@6733.89,1329.34
  PWR/SIG_1 w6: v1(3294.75,3402.11) 3469.95,3226.91 3469.95,2878.26 3675.96,2672.24 3675.96,2579.8 4102.14,2153.61 5100.17,2153.61 5770.86,1482.92 6478.55,1482.92 6622.88,1338.58 v1(6677.17,1338.58)
EPWM5_A: R27.1 U1.12 U32.F2 | length 3718
  Top Layer w8: U1.12@5552.33,4746.07 5566.36,4746.07 5578.33,4734.11 v1(5578.33,4715.94)
  Top Layer w9.9: v2(3210.3,3610.19) U32.F2@3226.05,3625.94
  PWR/SIG_1 w4.5: v2(3210.3,3610.19) 3225.94,3625.83 3225.94,3850.76 3248.67,3873.5 3309.62,3873.5 3325.09,3888.97 3325.09,4073.35 3350.76,4099.02
  PWR/SIG_1 w6: 3350.76,4099.02 4193.32,4099.02 4445.03,3847.31 5254.42,3847.31 v1(5289.22,3882.11)
  Bottom Layer w8: v1(5289.22,3882.11) 5557,4149.89 5557,4326.63 5620.16,4389.8 5620.16,4667.07 5609.89,4677.34 R27.1@5578.33,4677.34 v1(5578.33,4715.94)
EPWM5_B: U32.G2 U51.20 | length 1651.9
  Top Layer w8: v1(4349.15,4261.43) 4371.42,4283.7 U51.20@4482.15,4283.7
  Top Layer w9.9: v2(3241.8,3610.19) U32.G2@3257.55,3625.94
  SIG_1 w4.5: v2(3241.8,3610.19) 3257.66,3626.05 3309.85,3626.05 3334.91,3651.11 3334.91,3839.34 3361.19,3865.63 3679.79,3865.63 3735.55,3921.39 3873.69,3921.39 4213.73,4261.43 v1(4349.15,4261.43)
EPWM6_A: D54.1 U5.8 U32.E1 | length 3233.1
  Top Layer w8: U5.8@1624.94,1653.05 v1(1680.48,1653.05) 1680.48,1507.27 1657.87,1484.67 D54.1@1657.87,1441.07
  Top Layer w9.9: v2(3178.81,3578.69) U32.E1@3194.55,3594.44
  SIG_1 w6: v1(1680.48,1653.05) 1736.83,1709.4 2178.58,1709.4 2373.45,1904.27 2433.45,1904.27 2906.11,2376.93 2906.11,2620.15 2830.98,2695.27 2830.98,3284.58 3125.1,3578.69 v2(3178.81,3578.69)
EPWM6_B: J13.20 U32.F3 | length 3294.1
  Top Layer w8: J13.20@1792.27,6147.8 1792.47,6147.6 1792.47,5183.86 v1(1792.66,5183.66)
  Top Layer w9.9: v2(3210.3,3641.69) U32.F3@3226.05,3657.44
  SIG_3 w4.5: v1(1792.66,5183.66) 1792.66,5130.91 2391.77,4531.8 2391.77,4483.58 2484.4,4390.95 2574.45,4390.95 2992.4,3973 3184.8,3973 3194.85,3962.94 3194.85,3885.52 3225.82,3854.56 3225.82,3657.2 v2(3210.3,3641.69)
EPWM7_B: R365.2 U32.F1 | length 72.8
  Top Layer w8: R365.2@3214.82,3526.31 3214.82,3583.21 U32.F1@3226.05,3594.44
EPWM8_A: R366.2 U32.G3 | length 159
  Top Layer w9.9: v2(3241.8,3641.69) U32.G3@3257.55,3657.44
  Bottom Layer w5: R366.2@3193.88,3524.76 3193.88,3550.53 3225.97,3582.62 3225.97,3625.85 v2(3241.8,3641.69)
EPWM9_A: U32.G1 U50.6 | length 2596.2
  Top Layer w8: v1(5267.76,3553.51) U50.6@5288.18,3553.51
  Top Layer w9.9: v2(3241.8,3578.69) U32.G1@3257.55,3594.44
  PWR/SIG_1 w4.5: v2(3241.8,3578.69) 3241.8,3587.63 3256.48,3602.31 3256.48,3650.16 3263.64,3657.32 3312.38,3657.32 3345.05,3689.99 3345.05,3958.98 3358.66,3972.58 3668.46,3972.58
  PWR/SIG_1 w6: 3668.46,3972.58 3691.3,3972.58 3691.54,3972.34 4209.04,3972.34 4555.61,3625.77 4922.63,3625.77 4960.27,3588.13 5233.13,3588.13 v1(5267.76,3553.51)
EPWM9_B: U32.J2 | length 22.3
  Top Layer w9.9: v2(3304.79,3610.19) U32.J2@3320.54,3625.94
EPWM10_A: R362.2 U32.G4 | length 186
  Top Layer w9.9: v2(3241.8,3673.18) U32.G4@3257.55,3688.93
  Bottom Layer w5: R362.2@3236.74,3524.76 3236.74,3542.9 3257.79,3563.95 3257.79,3648.11 3257.8,3657.18 v2(3241.8,3673.18)
EPWM_13A: R361.2 U32.K4 | length 218.5
  Top Layer w9.9: U32.K4@3352.03,3688.93 v2(3367.78,3673.18)
  Bottom Layer w9.9: R361.2@3346.21,3485.92 3346.21,3651.61 v2(3367.78,3673.18)
EPWM_14A: J12.20 U32.V17 | length 2385.9
  Top Layer w8: v1(3602.92,6109.41) J12.20@3602.92,6147.8
  Top Layer w9.9: U32.V17@3604,4098.38 v2(3619.75,4114.13)
  SIG_3 w4.5: v1(3602.92,6109.41) 3602.92,5838.61 3810.69,5630.83 3810.69,4916.7 3481.78,4587.79 3481.78,4365.25 3493.38,4353.65 3568.65,4353.65 3609.85,4312.45 3609.85,4241.75 3602.09,4233.99 3602.09,4131.79 v2(3619.75,4114.13)
EPWM_14B: J11.23 J12.24 J13.24 U32.T16 | length 6094
  Top Layer w8: v1(373.03,5566.8) J11.23@411.42,5566.8 ; J13.24@1729.28,6147.8 v1(1729.28,6186.18) ; J12.24@3539.93,6147.8 v1(3539.93,6186.18)
  Top Layer w9.9: U32.T16@3541.01,4066.88 v2(3556.76,4082.63)
  SIG_3 w4.5: v1(3539.93,6186.18) 3539.93,6062.96 3528.51,6051.54 3528.51,4950.09 3448.41,4869.99 3448.41,4365.78 3474.03,4340.16 3529.43,4340.16 3548.51,4321.07 3548.51,4289.01 3552.79,4284.74 3552.79,4174.31 3540.86,4162.39 3540.86,4158.4 3540.86,4098.53 v2(3556.76,4082.63)
  Bottom Layer w8: v1(373.03,5566.8) 341.89,5597.95 341.89,5929.56 551.29,6138.96 1291.75,6138.96 1319.99,6167.19 1710.29,6167.19 v1(1729.28,6186.18) 1787.32,6186.18 1845.17,6128.34 3088.81,6128.34 3108.31,6147.83 3501.58,6147.83 v1(3539.93,6186.18)
EPWM_15A: R478.1 R479.1 U32.P15 | length 4108.7
  Top Layer w8: R478.1@3768.76,4170.18 3772.45,4166.49 v5(3772.45,4137.48) ; v5(7148.52,4875.69) 7199.17,4875.69 R479.1@7199.82,4875.04
  Top Layer w9.9: U32.P15@3478.02,4035.39 v2(3493.77,4051.14)
  SIG_3 w4.5: v2(3493.77,4051.14) 3507,4064.37 3632.43,4064.37 3710.73,4142.67 3737.44,4142.67 3742.62,4137.48 v5(3772.45,4137.48) 3828.99,4137.48 4207.02,4515.52 5218.64,4515.52 5388.62,4685.49 6167.92,4685.49 6234.09,4751.66 6442.19,4751.66 6548.05,4857.51 7130.45,4857.51 v5@7148.58,4875.64
EQEP0_A: R26.1 U1.7 U32.B14 | length 2811.6
  Top Layer w8: v1(5415.56,4713.65) 5415.56,4729.7 5431.94,4746.07 U1.7@5453.9,4746.07
  Top Layer w9.9: v2(3084.32,4019.64) U32.B14@3100.07,4003.89
  SIG_2 w4.5: v2(3084.32,4019.64) 3099.92,4004.04 3315.97,4004.04 3335.67,4023.74 3335.67,4083.81 3349.9,4098.05 3494.38,4098.05
  SIG_2 w6: 3494.38,4098.05 3525.73,4066.69 3662.61,4066.69 3697.55,4101.63 3801.7,4101.63 4176.24,4476.18 4455.91,4476.18 4656.52,4676.79 5226.37,4676.79 5263.23,4713.65 v1(5415.56,4713.65)
  Bottom Layer w8: R26.1@5415.56,4678.34 v1(5415.56,4713.65)
EQEP0_B: U32.A14 U51.22 | length 1777.2
  Top Layer w8: v1(3954.61,4349.39) 4219.76,4349.39 4336.63,4232.52 U51.22@4482.15,4232.52
  Top Layer w9.9: v2(3052.82,4019.64) U32.A14@3068.57,4003.89
  Bottom Layer w5: v2(3052.82,4019.64) 3068.51,4035.32 3093.03,4035.32 3100.08,4042.37 3100.08,4167.45
  Bottom Layer w8: 3100.08,4167.45 3138.12,4205.48 3138.12,4320.4 3167.12,4349.39 v1(3954.61,4349.39)
EQEP0_STROBE: U32.C12 U48.6 | length 3955
  Top Layer w8: U48.6@5845.32,2727.3 v1(5845.32,2775.9)
  Top Layer w9.9: v2(3115.81,3956.65) U32.C12@3131.56,3940.9
  SIG_2 w4.5: 3042.85,3972.31 3100.15,3972.31 v2(3115.81,3956.65)
  SIG_2 w6: 3042.85,3972.31 2990.36,3919.81 2990.36,3551.05 3059.47,3481.94 3733.29,3481.94 3774.49,3523.14 3913.38,3523.14 4096.26,3706.02 4239.12,3706.02 4568.82,3376.32 4832.62,3376.32 5174.39,3034.55 5372.71,3034.55 5559.53,2847.73 5773.46,2847.73 v1(5845.32,2775.9)
EXT_VMON1: R405.1 R410.2 U41.16 | length 2254.6
  Top Layer w8: R410.2@3003.51,4529.56 3822.33,4529.56 4270.85,4978.08 4270.85,5201.84 4145.34,5327.35 3961.91,5327.35 3951.34,5316.79 3869.76,5316.79 3852.95,5299.98 U41.16@3812.24,5299.98
  Top Layer w10: R405.1@3003.51,4473.77 R410.2@3003.51,4529.56
EXT_VMON2: R414.1 R416.2 U41.10 | length 1962.8
  Top Layer w8: v1(2460.45,4735.59) R414.1@2496.77,4735.59 2497.23,4736.05 R416.2@2546.16,4736.05 ; U41.10@3812.24,5181.87 3865.18,5181.87 3868.97,5178.07 v5(3872.22,5178.07)
  Bottom Layer w8: v1(2460.45,4735.59) 2579.57,4735.59 2718.64,4596.52 2932.21,4596.52 2987.18,4651.5 3496.94,4651.5 3812.27,4966.83 3812.27,5146.18 3844.16,5178.07 v5(3872.22,5178.07)
FETGOOD: R35.1 U4.3 U52.6 | length 2495
  Top Layer w8: U52.6@5548.39,4325.82 v1(5598.04,4325.82) ; v1(5846.81,6183.57) 5846.81,6081.38 R35.1@5846.35,6080.93 5847.06,6080.22 U4.3@5847.06,6018.41
  SIG_2 w6: v1(5598.04,4325.82) 5598.04,4365.84 5693.67,4461.47 5693.67,4809.51 5720.73,4836.57 5720.73,5479.29 5520.31,5679.71 5520.31,6117.97 5585.91,6183.57 5780.25,6183.57 v1(5846.81,6183.57)
FG_LM74704_MCU: U32.D9 U52.18 | length 2454.4
  Top Layer w8: v1(5217.44,4351.41) U52.18@5320.04,4351.41
  Top Layer w9.9: v2(3147.31,3830.66) U32.D9@3163.06,3846.41
  SIG_2 w6: v2(3147.31,3830.66) 3165.1,3848.45 3613.24,3848.45 3660.4,3895.61 3660.4,3915.7 3709.31,3964.6 3755.74,3964.6 3775.16,3945.19 4302.95,3945.19 4566.9,4209.13 4566.9,4236.2 4664.71,4334.01 4788.72,4334.01 4806.12,4351.41 v1(5217.44,4351.41)
FLT/: R10.2 R468.1 U55.8 U56.6 | length 4089.8
  Top Layer w8: v1(5100.1,2992.64) U55.8@5124.62,2992.64 ; v1(6457.41,3533.95) R10.2@6457.41,3560.18 ; U56.6@7438.56,5061.27 7471.67,5061.27 v1(7482.17,5050.77) R468.1@7518.16,5050.77
  Bottom Layer w8: v1(5100.1,2992.64) 5100.1,3083.77 5269.28,3252.94 5959.64,3252.94 6127.56,3420.86 6344.32,3420.86 v1(6457.41,3533.95) 6457.41,3701.24 6591.18,3835.01 7194.06,3835.01 7430.83,4071.79 7430.83,4451.37 7399.78,4482.42 7399.78,4801.3 7482.17,4883.69 v1(7482.17,5050.77)
FLT_I_TPS1211: R378.2 U42.5 U54.22 | length 686.6
  Top Layer w8: U54.22@6747.59,3127.05 6747.73,3127.19 6747.73,3168.66 6740.91,3175.49 6740.91,3207.25 6729.26,3218.9 6729.26,3321.72 6827.6,3420.06 R378.2@6827.6,3565.06 6858.48,3565.06 6893.66,3600.25 U42.5@6893.66,3719.72
FLT_T_TPS1211: R14.2 R380.2 U42.4 U54.23 | length 1344.5
  Top Layer w8: R14.2@6217.07,2981.05 v1(6243.32,2981.05) ; v2(6719.13,3190.6) 6719.13,3187.89 6727.91,3179.12 U54.23@6727.91,3127.05 ; R380.2@6827.6,3623.08 6860.17,3623.08 v1(6873.97,3636.88) U42.4@6873.97,3719.72
  Bottom Layer w8: v1(6243.32,2981.05) 6324.96,3062.69 6588.13,3062.69 6686.12,3160.68 6686.12,3174.71 ; v2(6719.13,3190.6) 6703.24,3174.71 6686.12,3174.71 ; v1(6873.97,3636.88) 6679.64,3442.54 6679.64,3181.19 6686.12,3174.71
FLT_TPS2HCS05: R4.2 R102.2 U49.7 U55.5 | length 3801.8
  Top Layer w8: U49.7@5009.43,4196.21 5048.2,4196.21 5057.62,4186.8 5057.62,4076.83 5169.9,3964.55 v1(5169.9,3070.56) U55.5@5169.9,3037.92 ; R4.2@6457.41,3663.38 v1(6483.64,3663.38) ; R102.2@7123.94,3617.85 7123.94,3626.81 7137.28,3640.15 v2(7137.28,3660.79)
  Bottom Layer w8: v1(5169.9,3070.56) 5312.06,3212.72 5982.25,3212.72 6146.48,3376.96 6383.09,3376.96 6513.22,3507.09 6513.22,3633.8 v1(6483.64,3663.38) 6511.08,3690.82 6688.05,3690.82 6814.76,3817.53 6985.25,3817.53 7027.6,3775.19 7139.69,3663.1 v2@7139.69,3660
FLT_TPS2HCS10/08: R7.2 R86.1 U49.6 U55.6 | length 5194.1
  Top Layer w8: R86.1@4370.02,1262.4 v1(4407.94,1262.4) ; U49.6@5009.43,4176.53 5009.43,4108.14 5150.21,3967.35 v1(5150.21,3101.84) U55.6@5150.21,3037.92 ; R7.2@6457.41,3611.35 v1(6483.64,3611.35)
  Bottom Layer w8: v1(4407.94,1262.4) 4458.37,1312.83 4458.37,2086.81 4495.41,2123.85 4495.41,2358.4 4611.82,2474.81 4756.72,2474.81 4808.4,2526.5 4979.37,2526.5 5124.78,2671.91 5124.78,3076.41 v1(5150.21,3101.84) 5281.42,3233.05 5964.72,3233.05 6128.54,3396.87 6365.73,3396.87 6483.64,3514.78 v1(6483.64,3611.35)
FLT_TPS2HCS10/08_15: R84.1 R86.2 U20.12 U21.12 | length 1076.9
  Top Layer w8: U21.12@3703.19,1008.75 v1(3759.84,1008.75) ; U20.12@4205.84,1358.76 4278.23,1358.76 R84.1@4311.77,1325.22 4369.85,1325.22 R86.2@4369.93,1325.3 ; R86.2@4370.02,1325.39 R86.2@4369.93,1325.3 ; v1(4407.85,1325.3) R86.2@4369.93,1325.3
  Bottom Layer w8: v1(3759.84,1008.75) 4134.1,1008.75 4371.57,1246.21 4371.57,1289.02 v1(4407.85,1325.3)
G_14: R368.1 R369.1 U42.11 | length 172.7
  Top Layer w10: U42.11@6992.09,3892.95 6992.09,3850.94 7007.96,3835.07 7055.19,3835.07 R368.1@7116.24,3835.07
G_19: R455.1 R456.2 U56.13 | length 950.8
  Top Layer w8: U56.13@7438.56,5210.88 7457.34,5210.88 v1(7466.55,5220.09)
  Top Layer w10: R455.1@7553.44,5975.89 v1(7605.72,5975.89)
  Bottom Layer w10: v1(7466.55,5220.09) 7466.55,5295.35 7605.72,5434.51 v1(7605.72,5975.89) 7605.23,5975.41 R456.2@7552.6,5975.41
GATE_4: Q5.4 Q6.4 U4.7 | length 651.4
  Top Layer w8: v1(5556.52,5738.58) Q5.4@5590.56,5738.58 ; v1(5872.65,5881.62) U4.7@5872.65,5916.05 ; v1(5926.05,5736.64) Q6.4@5960.1,5736.64
  SIG_3 w6: v1(5556.52,5738.58) 5572.26,5722.84 5912.26,5722.84 v1(5926.05,5736.64) 5926.05,5828.22 v1(5872.65,5881.62)
GATE_19: D57.1 R467.2 U56.16 | length 217.8
  Top Layer w10: R467.2@7333.35,5409.57 7334.95,5407.96 D57.1@7334.95,5333 7334.95,5276.06 7379.51,5231.51 U56.16@7379.51,5210.88
GH1_17: R151.2 U27.22 | length 945
  Top Layer w8: v1(6897.28,1106.34) U27.22@6897.28,1165.95
  Top Layer w20: v1(7553.08,637.01) R151.2@7588.24,637.01
  SIG_1 w6: v1(6897.28,1106.34) 6995.08,1008.54 7033.96,1008.54 7405.49,637.01 v1(7553.08,637.01)
GH2_17: R152.1 U27.28 | length 390.8
  Top Layer w8: U27.28@7015.39,1165.95 v1(7037.29,1165.95)
  Top Layer w20: v1(7234.76,1026.32) R152.1@7269.92,1026.32
  SIG_1 w6: v1(7037.29,1165.95) 7198.62,1165.95 7256.25,1108.33 7256.25,1047.81 v1(7234.76,1026.32)
GH3_17: R160.1 U27.44 | length 670.3
  Top Layer w8: U27.44@6995.7,1473.04 v1(6995.7,1508.17)
  Top Layer w20: v1(7571.5,1566.64) R160.1@7606.65,1566.64
  SIG_1 w6: v1(6995.7,1508.17) 7054.17,1566.64 v1(7571.5,1566.64)
GH4_17: R161.1 U27.50 | length 651.3
  Top Layer w8: U27.50@6877.59,1473.04 v1(6877.59,1508.17)
  Top Layer w20: v1(7232.5,1918.09) R161.1@7267.65,1918.09
  SIG_1 w6: v1(6877.59,1508.17) 6918.69,1508.17 6937.13,1526.62 6937.13,1591.98 7232.5,1887.34 v1(7232.5,1918.09)
GL1_17: R156.2 U27.24 | length 866.9
  Top Layer w8: U27.24@6936.65,1165.95 6936.65,1147.56 6952.1,1132.11 v1(6952.1,1094.75)
  Top Layer w20: v1(7553.08,725.11) R156.2@7588.24,725.11
  SIG_1 w6: v1(6952.1,1094.75) 7052.85,1094.75 7422.5,725.11 v1(7553.08,725.11)
GL2_17: R157.1 U27.26 | length 346.4
  Top Layer w8: v1(6976.02,1129.48) U27.26@6976.02,1165.95
  Top Layer w20: v1(7234.29,1089.57) R157.1@7269.45,1089.57
  SIG_1 w6: v1(6976.02,1129.48) 6991.56,1113.94 7209.9,1113.94 v1(7234.29,1089.57)
GL3_17: R163.1 U27.46 | length 750.8
  Top Layer w8: U27.46@6956.33,1473.04 v1(6956.33,1533.97)
  Top Layer w20: v1(7571.5,1629.54) R163.1@7606.65,1629.54
  SIG_1 w6: v1(6956.33,1533.97) 6993.73,1533.97 7076.05,1616.29 7558.25,1616.29 v1(7571.5,1629.54)
GL4_17: R164.1 U27.48 | length 672.3
  Top Layer w8: U27.48@6916.96,1473.04 v1(6916.96,1533.97)
  Top Layer w20: v1(7232.98,1979.32) R164.1@7268.14,1979.32
  SIG_1 w6: v1(6916.96,1533.97) 6916.96,1663.3 v1(7232.98,1979.32)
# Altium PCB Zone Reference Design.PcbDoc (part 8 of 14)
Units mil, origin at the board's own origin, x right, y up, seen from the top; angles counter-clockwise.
Board outline 8858.11 x 7047.08 mil, 16 copper layers (Top Layer, GND_1, SIG_1, GND_2, PWR/SIG_1, GND_3, PWR_1, PWR_2, GND_4, PWR/SIG_2, GND_5, SIG_2, GND_6, SIG_3, GND_7, Bottom Layer), stack 80.368 mil thick; 1131 components, 808 nets, 3825 pads, 3523 vias.
Unrouted connection lines stored in the file: 563.

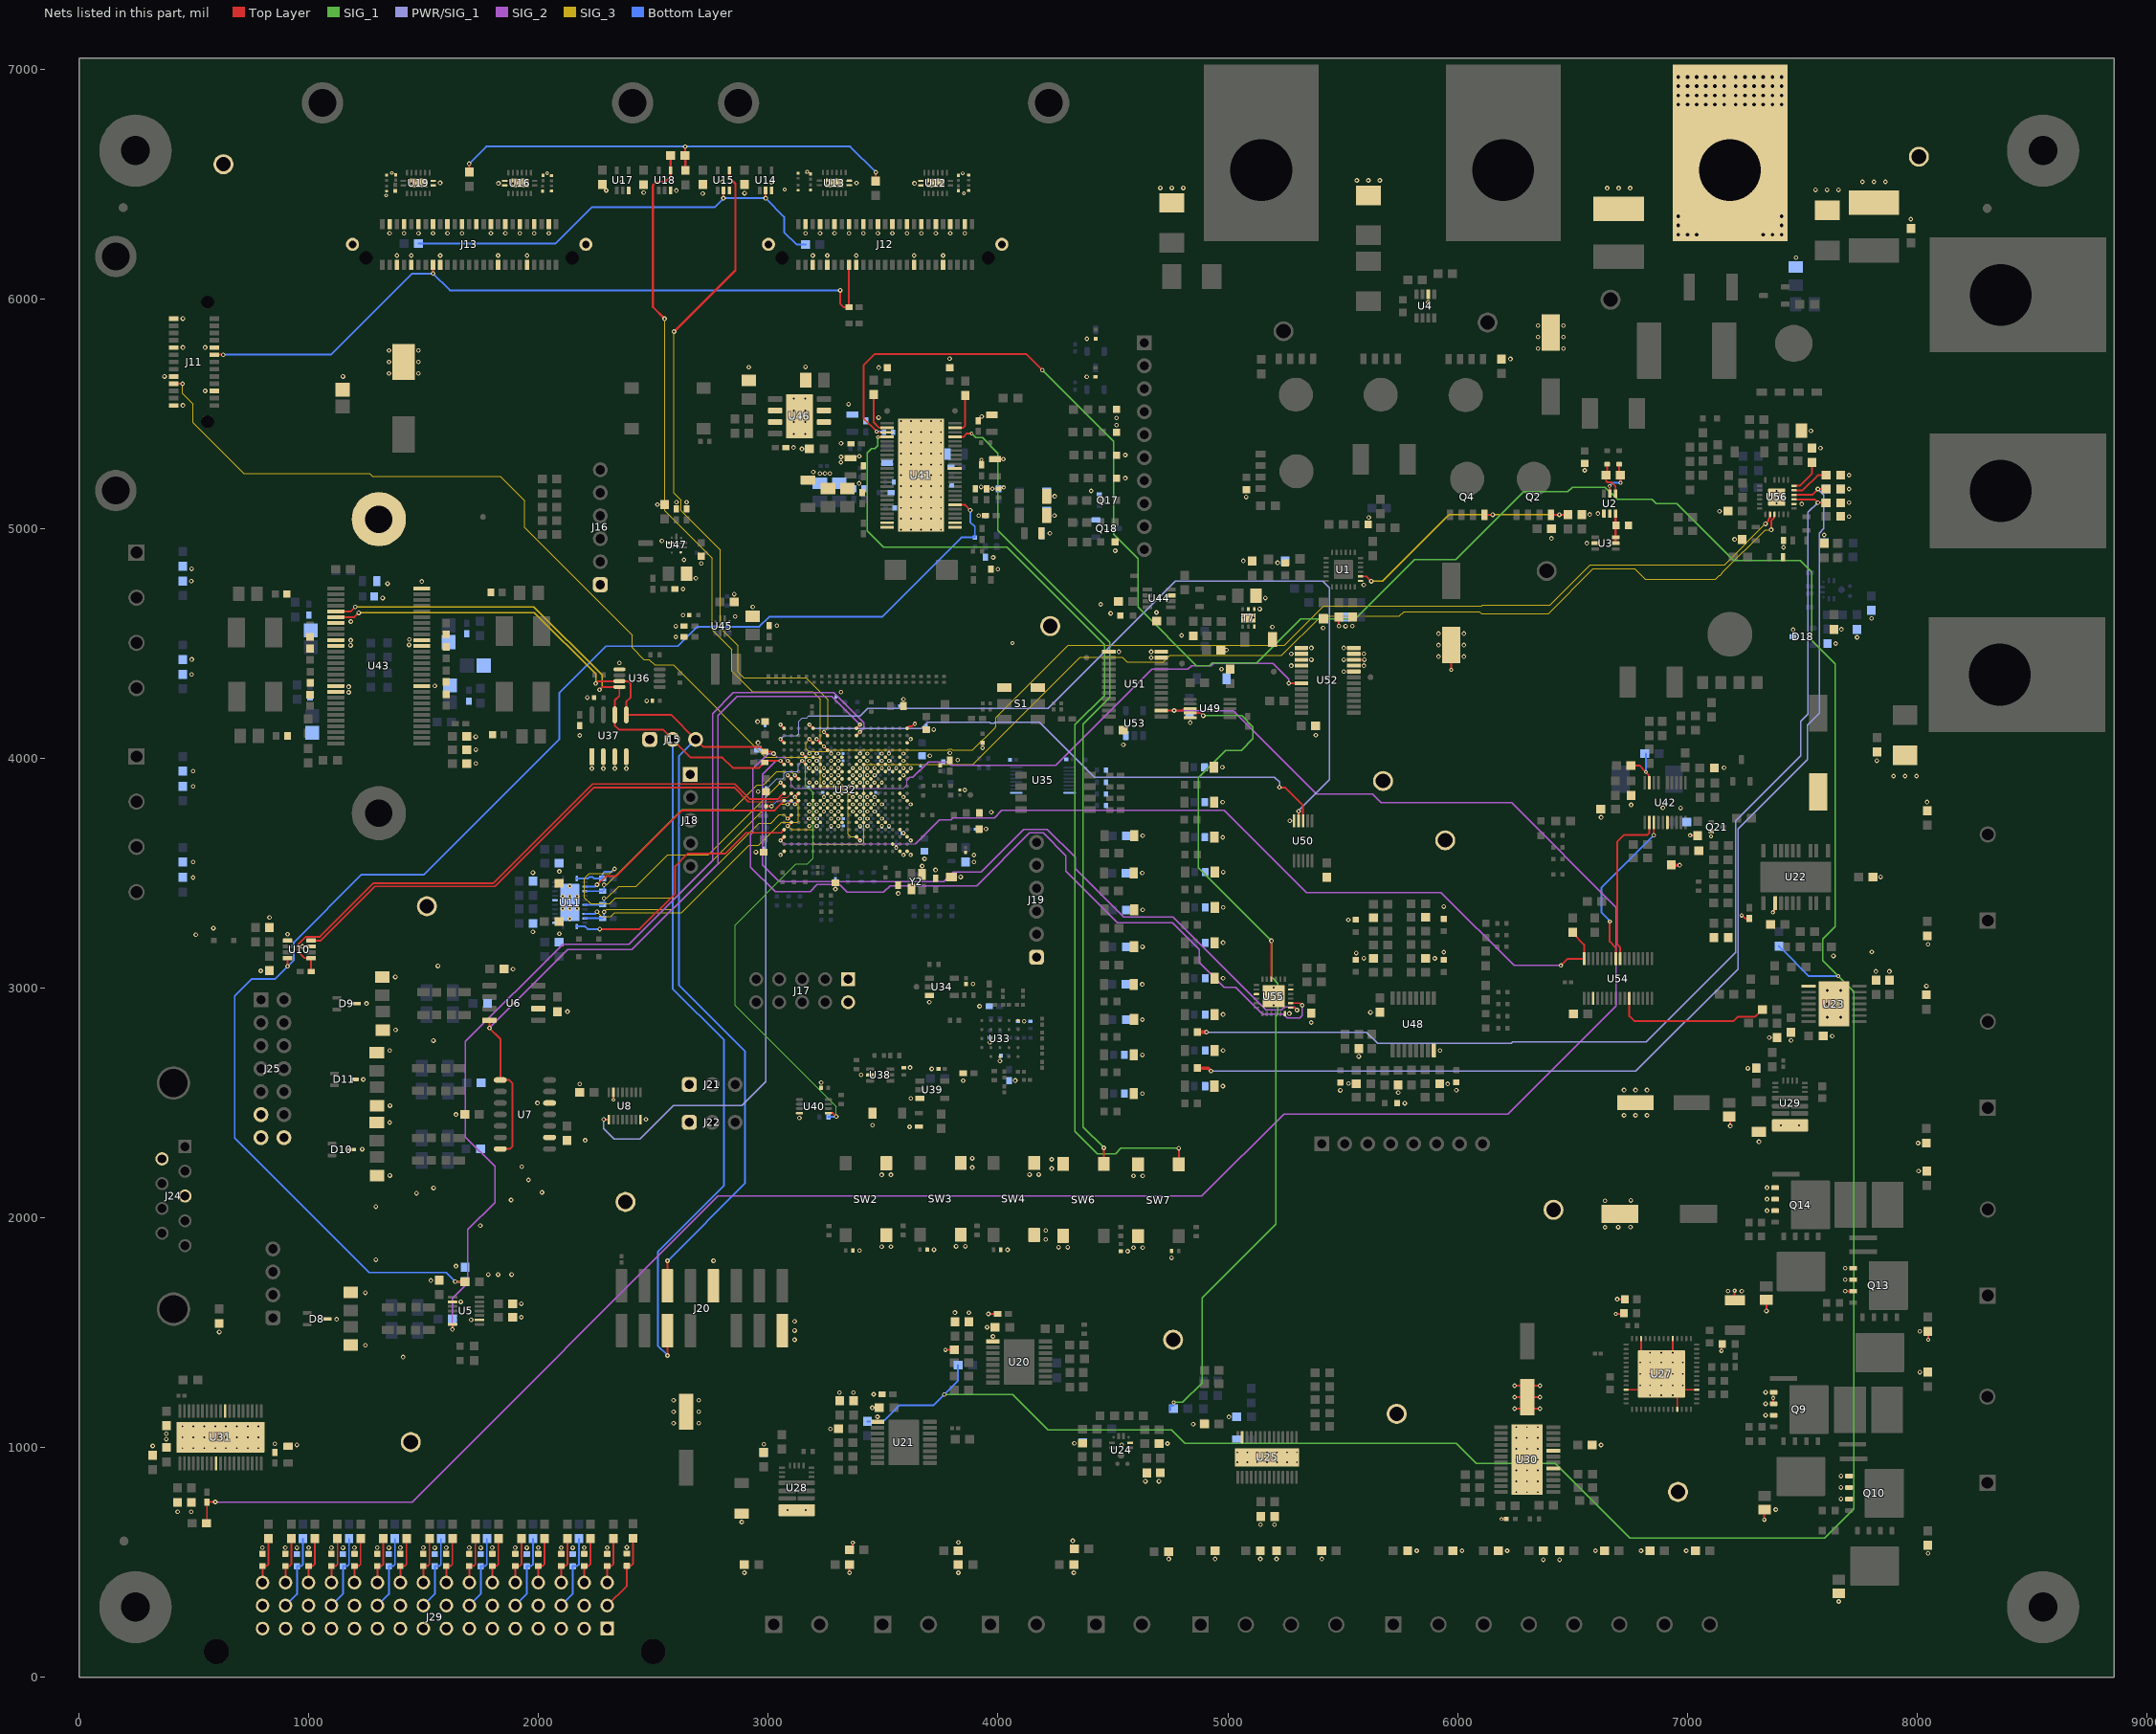
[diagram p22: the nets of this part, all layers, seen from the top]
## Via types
v1: diameter 20, hole 10, Top Layer to Bottom Layer, tented both sides, 2450 vias
v2: diameter 18, hole 8, Top Layer to Bottom Layer, tented both sides, 400 vias
v3: diameter 32, hole 16, Top Layer to Bottom Layer, tented both sides, 348 vias
v4: diameter 19.68, hole 7.87, Top Layer to Bottom Layer, tented both sides, 245 vias
v5: diameter 16, hole 8, Top Layer to Bottom Layer, tented both sides, 60 vias
v6: diameter 16, hole 8, Top Layer to Bottom Layer, 14 vias
v7: diameter 24.8, hole 12.99, Top Layer to Bottom Layer, tented both sides, 6 vias

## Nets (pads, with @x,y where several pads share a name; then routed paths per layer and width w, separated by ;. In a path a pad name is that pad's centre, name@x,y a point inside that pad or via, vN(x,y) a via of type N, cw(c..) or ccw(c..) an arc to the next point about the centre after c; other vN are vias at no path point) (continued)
GND: C2.2 C3.2 C4.2 C5.1 C7.2 C8.1 C10.2 C11.2 C12.2 C14.2 C15.2 C17.2 C18.2 C19.2 C20.1 C21.2 C22.2 C23.2 C24.2 C25.1 C26.2 C27.2 C28.2 C29.1 C30.2 C31.2 C32.2 C33.2 C34.1 C35.2 C36.2 C46.2 C47.2 C48.2 C49.2 C50.2 C51.2 C52.2 C53.2 C54.2 C55.2 C56.2 C57.2 C58.2 C59.2 C60.2 C61.2 C62.2 C63.2 C64.2 C65.2 C66.2 C67.2 C68.2 C69.2 C70.2 C71.2 C72.2 C73.2 C74.2 C75.2 C76.2 C77.2 C78.2 C79.2 C80.2 C81.2 C82.2 C83.2 C84.2 C85.2 C86.2 C87.2 C88.2 C89.2 C91.2 C92.2 C93.2 C94.2 C95.2 C96.2 C97.2 C98.2 C99.2 C100.2 C104.2 C105.1 C106.1 C107.2 C108.2 C109.2 C110.2 C111.2 C112.2 C113.2 C114.2 C115.1 C116.2 C118.1 C119.1 C120.1 C121.1 C122.2 C123.2 C124.2 C125.2 C126.2 C127.2 C128.2 C129.2 C130.2 C131.2 C132.2 C133.1 C134.1 C135.1 C136.2 C137.1 C138.1 C139.1 C140.1 C141.1 C142.1 C143.1 C144.1 C145.1 C146.1 C147.1 C148.1 C149.1 C150.1 C151.1 C152.1 C153.1 C154.1 C155.1 C156.1 C157.1 C158.1 C159.1 C160.1 C161.1 C162.1 C163.2 C164.2 C165.2 C166.2 C167.2 C168.2 C169.2 C170.2 C171.2 C172.2 C173.2 C174.2 C175.2 C176.2 C177.2 C178.2 C179.2 C180.2 C181.2 C182.2 C183.2 C184.2 C185.2 C186.2 C187.2 C188.2 C189.2 C190.2 C191.2 C192.2 C193.2 C194.2 C195.2 C196.2 C197.2 C198.2 C199.2 C200.2 C201.2 C202.2 C203.2 C204.2 C205.2 C206.2 C207.2 C208.2 C209.2 C210.2 C211.2 C212.2 C213.2 C214.2 C215.2 C216.2 C217.2 C218.2 C219.2 C220.2 C221.2 C222.2 C223.2 C224.1 C225.2 C226.2 C227.2 C228.2 C229.2 C236.2 C237.2 C238.2 C239.2 C240.2 C241.2 C242.2 C243.2 C244.2 C245.1 C246.2 C247.1 C248.1 C249.1 C250.2 C251.2 C252.2 C253.2 C254.2 C255.2 C256.2 C257.2 C258.2 C259.2 C260.2 C261.2 C262.1 C263.2 C264.2 C265.1 C266.1 C267.1 C268.1 C269.1 C270.1 C271.2 C272.2 C273.1 C274.1 C275.2 C276.2 C277.2 C280.2 C281.2 C282.1 C283.1 C284.1 C285.1 C286.2 C287.1 C288.2 C289.2 C290.2 C291.2 C292.2 C293.2 C294.2 C295.1 C296.2 C297.2 C298.2 C299.2 C300.2 C301.2 C302.2 C303.2 C304.1 C305.2 C306.2 C307.1 C309.2 C310.2 C311.2 C312.2 C313.2 C314.2 C315.1 C316.1 C317.1 C318.1 C319.1 C320.1 C321.1 C322.1 C323.2 C324.2 C325.2 C326.2 C329.2 C330.2 C331.2 C333.1 C339.2 C341.2 C342.2 C343.1 C347.2 C348.2 C349.2 C352.1 C354.2 C355.2 C356.2 C357.1 C358.2 C359.2 C360.1 C361.2 C362.1 C364.2 C365.2 C366.2 C367.2 C368.2 C369.2 C370.2 C371.2 C372.2 C373.1 C374.1 C375.1 C376.1 C377.1 C378.1 C379.1 C380.1 C381.1 C382.2 C383.2 C384.2 C385.2 C386.2 C387.2 C389.2 C390.2 C391.2 C392.2 C393.2 C394.2 C399.2 C400.2 C401.2 C402.2 C403.2 C404.2 C406.2 C407.2 C408.1 C409.1 C410.2 C411.2 C412.1 C413.1 C414.2 C415.2 C416.1 C417.1 C418.2 C419.2 C420.1 C421.1 D5.1 D7.1 D8.3 D9.3 D10.3 D11.3 D18.3 D20.2 D21.2 D22.2 D23.2 D24.2 D25.2 D26.2 D27.2 D28.2 D29.2 D30.2 D31.2 D32.2 D33.2 D34.2 D35.2 D36.2 D37.2 D38.2 D39.2 D42.2 D43.1 D44.1 D45.1 D46.1 D47.1 D48.1 D51.1 D52.1 D53.2 D56.2 D58.2 H9.2 J11.1 J11.9 J11.10 J11.17 J11.22 J11.25 J12.3 J12.7 J12.10 J12.11 J12.15 J12.18 J12.19 J12.23 J12.27 J12.31 J12.34 J12.35 J12.39 J12.42 J12.43 J12.46 J12.47 J12.MH1 J12.MH2 J13.3 J13.7 J13.10 J13.11 J13.15 J13.18 J13.19 J13.23 J13.27 J13.31 J13.34 J13.35 J13.39 J13.42 J13.43 J13.46 J13.47 J13.MH1 J13.MH2 J15.1 J16.1 J17.1 J17.2 J18.1 J19.1 J20.2 J20.7 J21.1 J22.1 J24.3 J24.6 J25.11 J25.13 J25.14 J29.A1 J29.A2 J29.A3 J29.A4 J29.A5 J29.A6 J29.A7 J29.A8 J29.A9 J29.A10 J29.A11 J29.A12 J29.A13 J29.A14 J29.A15 J29.A16 J29.B2 J29.B4 J29.B6 J29.B8 J29.B10 J29.B12 J29.B14 J29.B16 Q9.1 Q9.2 Q9.3 Q10.1 Q10.2 Q10.3 Q13.1 Q13.2 Q13.3 Q14.1 Q14.2 Q14.3 Q17.2 Q18.2 Q21.2 R21.1 R23.1 R28.2 R29.1 R31.2 R41.1 R87.1 R96.1 R103.1 R114.1 R122.1 R126.1 R127.1 R131.1 R138.2 R143.1 R148.1 R149.1 R168.1 R169.1 R191.2 R208.2 R213.1 R275.1 R276.1 R288.1 R289.1 R290.1 R291.1 R299.1 R318.2 R325.1 R334.1 R336.2 R337.2 R342.2 R375.2 R379.1 R381.1 R382.1 R385.1 R393.2 R394.2 R395.2 R399.1 R403.1 R408.1 R409.1 R410.1 R411.1 R415.2 R416.1 R417.2 R434.1 R435.1 R436.1 R437.1 R438.1 R439.1 R440.1 R441.1 R444.1 R470.2 R471.1 R472.1 R473.1 R482.1 SW2.1 SW2.3 SW3.1 SW3.3 SW4.1 SW4.3 SW6.2 SW6.4 SW7.2 SW7.4 T5.1 T7.3 T7.4 T7.5 T7.7@5089.81,4610.64 TP10.1 TP11.1 TP12.1 TP13.1 TP14.1 TP15.1 TP16.1 TP17.1 TP18.1 TP19.1 TP20.1 TP21.1 U1.13 U2.1 U2.2 U3.2 U4.2 U5.2 U5.9 U6.2 U7.2 U7.5 U8.8 U8.15 U10.3 U10.5 U11.14 U11.19 U11.25 U12.8 U12.9 U12.17 U13.8 U13.9 U13.17 U14.3 U15.3 U16.8 U16.9 U16.17 U17.3 U18.3 U19.8 U19.9 U19.17 U20.1 U21.1 U22.2 U23.1 U23.15 U24.4 U25.13 U25.29 U27.11 U27.25 U27.32 U27.47 U27.54 U27.57 U28.7 U29.7 U30.5 U30.8 U30.25 U31.9 U31.28 U31.39 U32.A1 U32.A18 U32.E5 U32.E6 U32.E7 U32.E8 U32.E10 U32.E12 U32.E13 U32.E14 U32.F5 U32.F6 U32.F7 U32.F8 U32.F10 U32.F12 U32.F13 U32.F14 U32.G7 U32.G8 U32.G9 U32.G10 U32.G11 U32.G12 U32.H5 U32.H6 U32.H7 U32.H8 U32.H9 U32.H10 U32.H11 U32.H12 U32.H13 U32.H14 U32.J5 U32.J6 U32.J7 U32.J8 U32.J9 U32.J10 U32.J11 U32.J12 U32.J13 U32.J14 U32.K7 U32.K8 U32.K9 U32.K10 U32.K11 U32.K12 U32.L5 U32.L6 U32.L7 U32.L8 U32.L9 U32.L10 U32.L11 U32.L12 U32.L13 U32.L14 U32.M5 U32.M6 U32.M7 U32.M8 U32.M9 U32.M10 U32.M11 U32.M12 U32.M13 U32.M14 U32.N7 U32.N8 U32.N9 U32.N10 U32.N11 U32.N12 U32.P5 U32.P6 U32.P8 U32.P10 U32.P12 U32.P13 U32.P14 U32.R5 U32.R12 U32.R13 U32.R14 U32.T2 U32.T12 U32.U1 U32.U4 U32.U9 U32.U11 U32.U12 U32.U13 U32.U14 U32.V1 U32.V3 U32.V8 U32.V12 U32.V16 U32.V18 U33.B3 U33.C1 U33.E5 U34.3 U35.8 U35.9 U36.5 U37.1 U37.2 U37.3 U37.4 U38.2 U39.3 U40.4 U41.1 U41.2 U41.14 U41.47 U41.48 U41.49 U42.6 U43.11 U43.18 U43.19 U43.28 U43.35 U43.38 U43.39 U43.46 U43.47 U44.3 U45.4 U46.2 U46.3 U46.6 U46.7 U46.9 U47.1 U47.4 U48.8 U49.5 U50.5 U51.11 U51.12 U51.13 U52.8 U52.9 U52.10 U52.11 U52.12 U52.13 U52.14 U52.15 U52.16 U53.3 U54.3 U55.9 U55.18 U55.23 U55.25 U56.8 U56.25 Y2.2 Y2.4 | length 2135.8
  Top Layer w8: v5(2325.3,2512.71) U8.15@2325.3,2545.25 ; v2(3052.82,4145.62) U32.A18@3068.57,4129.88 ; 3161.73,6546.64 3167.43,6552.34 v5(3169.59,6552.34) ; v1@3352.02,461.11 3352.02,488.75 C115.1@3353.26,490 ; C65.2@3354.4,551.13 3367.48,564.22 v2(3367.48,585.38) ; U32.V18@3604,4129.88 3612.34,4138.21 3623.41,4138.21 3634.65,4149.45 v2(3637.36,4149.45) ; v2(3771.25,1424.19) 3807.7,1424.19 C58.2@3808.78,1425.27 ; v1@3952.66,1580.5 3952.78,1580.63 3997.75,1580.63 C60.2@3997.88,1580.76 ; C272.2@4001.89,5172.59 4005.74,5176.44 4022.33,5176.44 v2(4024.24,5178.35) ; v1@5478.08,4575.29 5483.73,4580.95 C10.2@5483.73,4614.35 ; U52.10@5548.39,4428.18 5548.47,4428.26 5594.62,4428.26 v1(5594.7,4428.34) ; C3.2@5972.29,4492.11 5972.41,4491.99 v2(5972.41,4384.3) ; v5(6191.29,688.11) C124.2@6211.79,688.11 ; v1(6248.27,1168.26) 6275.77,1168.26 6303.27,1195.76 C122.2@6303.27,1218.26 ; v1(6248.27,1218.26) C122.2@6303.27,1218.26 ; v1(6248.27,1268.26) 6249.42,1267.11 6250.57,1268.26 6275.77,1268.26 6303.27,1240.76 C122.2@6303.27,1218.26 ; C122.2@6303.27,1168.26 v1(6358.27,1168.26) ; C122.2@6303.27,1268.26 v1(6358.27,1268.26) ; v1(6358.27,1218.26) C122.2@6303.27,1218.26 ; v2(6688.64,1580.88) 6721.15,1580.88 C106.1@6724.23,1583.96 ; v1@6690.49,1644.34 6727.8,1644.34 C105.1@6728.42,1644.96 ; U27.11@6733.89,1250.6 6818.54,1250.6 v4(6837.59,1269.65) v4(6887.44,1319.5) ; U27.54@6798.85,1473.04 6798.85,1408.08 v4(6837.59,1369.34) v4(6887.44,1319.5) ; U27.47@6936.65,1473.04 6936.65,1412.65 v4(6937.28,1412.02) ; U27.25@6956.33,1165.95 U27.57@6956.33,1250.6 ; v2(7012.13,3663.93) 7042.39,3663.93 R379.1@7044.24,3662.08 ; U27.32@7040.98,1250.6 U27.57@6956.33,1250.6 ; v2(7148.49,1419.8) 7148.49,1446.25 C100.2@7152.63,1450.39 ; C109.2@7182.1,2440.19 7187.09,2435.2 v1(7187.09,2398.98) ; v2(7205.67,1681.93) 7205.67,1641.56 C99.2@7207.07,1640.16 ; v2(7236.16,3315.04) 7238.87,3315.04 7252.1,3301.82 C74.2@7270.03,3301.82 ; v2(7335.16,684.8) 7335.16,727.13 C98.2@7337.05,729.02 ; C108.2@7344.22,1642.34 7344.44,1642.11 v1@7344.44,1597.81 ; v2(7372.37,3328.88) v2@7372.37,3331.58 ; v2(7374.13,1215.02) 7374.13,1191.21 Q9.2@7375.66,1189.68 ; 7377.59,3336.8 7377.59,3363.66 U22.2@7382.45,3368.52 ; v1@7680.64,1677.57 7681.62,1678.55 7721.34,1678.55 Q13.3@7722.33,1679.54 ; Q10.3@7702.65,773.67 Q10.3@7704.09,775.11 ; C110.2@8047.57,1505.17 8049.11,1503.63 v2(8049.11,1468.38) ; v4(6887.44,1319.5) v4(6937.28,1269.65) U27.57@6956.33,1250.6
  Top Layer w15: R382.1@6929.39,3533.93 v1(6967.14,3533.93)
  other v1: 7659.14,329.25 2895.76,454 3353.26,454 3826.99,453.93 4329.59,454 6373.44,510.65 6444.31,510.65 4742.99,514 4944.47,514 5141.32,514 5212.19,514 5409.04,514 8047.57,538.86 5822.24,550 6019.03,550 6215.94,550 6599.9,550 6798.66,550 6995.51,550 948.11,562.81 1148.46,562.81 1348.21,562.81 1548.37,562.81 1748.37,562.81 1948.37,562.81 2148.37,562.81 797.93,563.79 897.43,563.79 998.8,563.79 1098.36,563.79 1198.56,563.79 1298,563.79 1398.42,563.79 1498.37,563.79 1598.37,563.79 1698.37,563.79 1798.37,563.79 1898.37,563.79 1998.37,563.79 2098.37,563.79 2198.37,563.79 2298.37,563.79 2383.97,564.78 3826.99,586 4324.76,593.17 5142.64,663.54 5202.92,663.54 2883.95,674.98 428.59,719.34 487.64,719.34 7384.92,729.02 7668.93,775.11 7668.93,825.11 4640.88,852.25 4700.39,852.31 7668.93,875.11 320.32,1005.91 6624.65,1010.02 948.16,1010.79 4538.32,1011.1 2980.43,1013.55 851.68,1015.61 4737.43,1016.44 4331.48,1017.49 379.37,1035.67 379.38,1058.99 3269.83,1080.12 4849.48,1100.88 2587.7,1105.27 2697.7,1105.27 3474.84,1133.11 5005.15,1132.68 7340.5,1139.68 2587.7,1155.27 2697.7,1155.27 3452.23,1172.01 7340.5,1189.68 2587.7,1205.27 2697.7,1205.27 3458.65,1230.81 3309.7,1238.57 3370.11,1238.57 7340.5,1239.68 8012.41,1327.28 1410.57,1392.78 1245.58,1444.8 3114.58,1468.37 3977.5,1483.12 609.75,1502.1 8012.41,1505.17 3114.58,1508.37 3952.32,1522.81 3114.58,1548.37 1706.68,1554.62 1120.66,1557.49 1924.97,1566.07 3957.97,1580.76 3812.12,1586.49 3873.05,1586.41 7344.22,1593.9 1924.97,1625.04 1661.3,1633.36 6694.82,1644.96 1245.58,1673.09 7177.07,1680.16 7237.07,1680.16 7687.17,1679.54 1530.58,1726.29 7687.17,1729.54 1780.75,1752.16 1823.76,1752.16 1882.28,1752.16 7687.17,1779.54 1640.37,1788.54 2761.03,1811.89 1291.33,1816.79 4755.16,1825.11 4563.98,1853.8 3397.43,1856.84 3721.03,1860.42 4041.4,1860.02 4589.47,1868.97 4629.47,1868.97 4263.16,1870.57 4303.16,1870.57 3493.33,1873.65 3533.33,1873.65 3817.35,1874.93 3857.35,1874.93 4207.19,1904.49 4207.19,1944.49 6641.67,1957.79 6699.39,1958.26 6752.78,1958.53 1745.93,1965.17 7346.9,2030.12 1291.33,2047.69 6641.67,2073.66 6754.26,2074.88 1880.44,2076.32 7346.9,2080.12 1468.81,2106.29 2014.72,2109.86 1542.65,2129.06 7346.9,2130.12 1956.16,2163.86 4589.47,2181.96 4629.47,2181.96 1352.57,2183.16 3493.33,2186.64 3533.33,2186.64 4137.19,2187.49 4177.19,2187.49 8006.52,2202.25 4233.16,2213.56 3887.35,2217.92 1926.6,2221.17 4233.16,2253.56 3887.35,2257.92 1232.27,2297.75 8004.52,2324.44 7311.72,2330.35 2202.84,2336.29 3614.53,2395.27 3453.09,2402.85 1351.99,2414.05 2467.34,2427.14 3135.33,2433.9 6724.7,2445.29 6774.7,2445.29 6824.7,2445.29 1640.48,2448.99 1352.88,2487.11 5770.43,2497.76 1994.77,2498.99 3619.53,2518.97 4627.87,2539.91 5741.46,2543.97 5489.71,2554.05 5994.89,2554.64 6724.7,2555.29 6774.7,2555.29 6824.7,2555.29 4978.57,2572.2 2178.62,2581.88 5956.31,2582.31 5525.48,2583.4 3229.69,2588.05 3848.1,2596.17 4074.71,2596.8 1236.9,2601.32 3403.54,2621 3710.75,2647.36 7263.52,2649.64 3616.93,2652.81 4008,2681.14 5570.05,2701.84 4627.87,2708.04 1351.7,2727.23 5923.52,2727.3 4979.11,2727.51 3964.25,2762.85 1541.91,2770.44 7451.33,2770.72 7357.02,2783.32 7630.59,2789.99 1377.3,2816.57 5363.12,2849.12 4113.77,2854.15 4628.11,2861.77 4979.11,2884.01 5267.83,2888.31 5620.88,2893.16 2125.63,2896.7 3919.28,2919.82 1250.71,2932.01 3700.6,2937.82 8041.07,3008.11 4627.45,3015.3 3890.73,3016.55 4979.23,3042.02 1376.12,3047.47 7820.98,3071.64 7879.73,3071.64 790.66,3074.26 1888.38,3081.46 1561.68,3095.26 5901.31,3128.13 5592.26,3128.57 7635.83,3139.25 5558.6,3151.63 5939.86,3155.42 7803.08,3156.78 4628.51,3178.83 971.35,3180.34 8047.67,3189.41 4979.45,3196.62 507.75,3231.75 907.38,3233.5 2090.01,3235.42 1975.19,3243.81 584.32,3260.02 5524.47,3296.04 828.44,3306.14 4629.27,3339.3 4980.27,3350.13 5940.11,3353.57 3565.03,3410.92 3291.76,3429.85 495.81,3480.42 3837.3,3482.58 7841.32,3482.81 4627.26,3499.75 1975.13,3501.54 4980.29,3503.48 2090.01,3507.07 3727.56,3513.32 3669.37,3530.4 495.81,3548.1 3894.74,3548.06 3679.66,3561.4 3894.74,3578.06 2945.68,3591.16 4978.08,3655.28 4629.46,3662.27 3947.43,3691.35 5270.21,3726.74 6624.8,3742.05 3970.65,3764.75 6970.79,3782.72 6893.45,3783.87 6755.38,3796.31 4977.24,3808.23 8043.97,3808.92 2955.78,3854.14 3855.3,3861.4 495.81,3877.26 7897.51,3921.76 7947.51,3921.76 7997.51,3921.76 495.81,3943.74 2231.64,3954.52 2281.64,3954.52 2331.64,3954.52 2381.64,3954.52 7159.73,3957.92 4976.38,3960.06 1727.17,3976.84 7825.29,3988.73 3824.22,3991.93 3702.78,4010.19 3790.21,4022.77 1727.17,4036.69 3932.41,4044.61 4545.19,4058.06 2955.01,4067 1726.02,4093.11 2179,4098.76 5382.76,4099.92 3720.07,4124.33 4836.2,4154.63 2953.04,4158.81 2470.25,4249.28 3588.11,4256.21 2212.27,4263.73 1173.28,4286.43 3315.78,4287.63 1173.28,4310.83 1548.39,4314.15 489.42,4364.34 5504.5,4377 4972.67,4387.58 5276.15,4402.59 5592.28,4402.59 2351.69,4413.99 5363.93,4428.18 5504.5,4428.18 490.2,4429.53 4666.6,4437.25 5917.29,4442.11 6027.29,4442.11 5276.15,4453.77 5592.28,4453.77 4526.04,4462.84 4666.6,4462.84 4993.89,4470.18 5363.93,4479.36 5504.5,4479.36 1181.62,4490.89 5917.29,4492.11 6027.29,4492.11 1436.33,4492.93 7645.39,4498.59 1182.26,4512.99 1436.99,4516.28 7739,4525.89 2597.46,4527.97 4798.92,4534.02 5917.29,4542.11 6027.29,4542.11 7460.71,4558.47 7670.74,4560.89 5414.6,4566.36 5193.8,4570.47 2597.46,4574.25 5483.73,4574.35 5512.3,4574.29 5542.62,4574.35 3036.47,4576.8 1182.39,4594.32 7801.71,4607.72 2855.47,4616.52 2628.94,4622.54 4489.79,4629.83 4689.54,4633.92 5138.66,4649.02 2932.07,4658.21 4446.45,4669.47 1321.33,4697.12 5162.94,4697.12 2851.36,4713.79 2628.41,4736.05 5591.68,4753.42 1342.69,4759.64 1491.52,4768.88 488.28,4770.27 2684.33,4782.79 3998.85,4822.89 489.34,4823.84 2707.57,4847.56 5216.71,4850.16 5067.18,4858.5 2632.42,4863.13 3978.68,4873.71 4510,4902.8 7418.7,4917.45 6563.15,4935.73 2536.28,4945.19 7205.73,4952.18 6409.03,4956.34 7595.95,4971.54 4225.3,4979.14 4471.55,4989.51 5613.56,5047.44 7704.12,5051.74 3915.71,5055.75 4245.38,5055.51 6575.62,5060.51 6610.57,5064.73 7140.29,5074.75 2517.3,5103.99 7498.02,5106.55 7704.12,5111.95 2599.87,5114.02 2644.08,5114.02 5079.98,5136.54 4246.06,5139.75 4405.46,5163.22 7704.12,5171.25 3974.95,5172.69 3926.12,5180.27 3395.36,5196.12 4553.77,5219.09 7704.12,5231.66 3224.32,5238.89 3246.32,5238.89 3268.32,5238.89 3195.63,5245.66 6553.43,5252.69 3316.15,5287.84 4023.02,5301.3 3316.62,5310.91 3396.16,5313.79 4553.77,5319.09 3145.99,5346.01 7579.64,5349.65 3109.81,5351.99 3316.62,5370.72 7538.25,5424.87 4515.51,5449.44 4515.51,5481.05 3479.68,5482.33 3928.67,5486.53 451.42,5535.31 3349.24,5540.56 548.58,5598.3 4385.72,5659.56 371.42,5661.29 1148.37,5661.09 1348.8,5674.2 1476.8,5674.2 3480.27,5700.05 2914.88,5701.16 3162.03,5703.11 1348.8,5724.2 1476.8,5724.2 6229.98,5737.37 3789.17,5738.9 1348.8,5774.2 1476.8,5774.2 6350.62,5783.02 6460.62,5783.02 451.42,5787.28 548.58,5787.28 4385.98,5825.28 6350.62,5833.02 6460.62,5833.02 6350.62,5883.02 6460.62,5883.02 451.42,5913.26 5872.65,5983.26 7472.6,6178.46 1382.82,6187.8 1445.81,6187.8 1571.8,6187.8 1823.76,6187.8 1949.75,6187.8 3193.47,6187.8 3256.47,6187.8 3382.45,6187.8 3634.42,6187.8 3760.4,6187.8 1351.32,6284.96 1414.32,6284.96 1477.31,6284.96 1540.3,6284.96 1603.29,6284.96 1666.28,6284.96 1792.27,6284.96 1855.26,6284.96 1918.25,6284.96 1981.24,6284.96 2044.24,6284.96 3161.98,6284.96 3224.97,6284.96 3287.96,6284.96 3350.96,6284.96 3413.95,6284.96 3476.94,6284.96 3539.93,6284.96 3602.92,6284.96 3665.92,6284.96 3728.91,6284.96 3791.9,6284.96 3854.89,6284.96 7973.11,6346.01 2714.63,6457.21 2896.66,6458.93 2457.29,6461.95 2599.56,6470.47 2294.19,6471.06 7558.17,6473.3 7608.17,6473.3 7658.17,6473.3 6651.35,6481.03 6701.35,6481.03 6751.35,6481.03 4706.12,6481.85 4756.12,6481.85 4806.12,6481.85 1825.31,6501.79 3635.97,6501.79 3383.46,6502.93 1571.28,6503.83 3013.65,6506.73 2361.66,6507.53 2799.7,6508.43 7762.39,6508.62 7812.39,6508.62 7862.39,6508.62 5561.72,6514.81 5611.72,6514.81 5661.72,6514.81
  other v2: 3052.82,3578.69 3588.25,3578.69 3619.75,3578.69 3556.76,3610.19 3619.75,3641.69 3588.25,3673.18 3178.81,3704.68 3210.3,3704.68 3273.29,3704.68 3304.79,3704.68 3399.28,3704.68 3430.77,3704.68 3493.77,3704.68 3525.26,3704.68 3178.81,3736.18 3210.3,3736.18 3273.29,3736.18 3304.79,3736.18 3399.28,3736.18 3430.77,3736.18 3493.77,3736.18 3178.81,3767.67 3210.3,3767.67 3241.8,3767.67 3273.29,3767.67 3304.79,3767.67 3367.78,3767.67 3399.28,3767.67 3430.77,3767.67 3462.27,3767.67 3178.81,3799.17 3210.3,3799.17 3241.8,3799.17 3273.29,3799.17 3304.79,3799.17 3367.78,3799.17 3399.28,3799.17 3430.77,3799.17 3462.27,3799.17 3493.77,3799.17 3619.75,3799.17 3241.8,3830.66 3273.29,3830.66 3304.79,3830.66 3367.78,3830.66 3399.28,3830.66 3430.77,3830.66 3462.27,3830.66 3588.25,3830.66 3178.81,3893.66 3210.3,3893.66 3241.8,3893.66 3273.29,3893.66 3304.79,3893.66 3367.78,3893.66 3399.28,3893.66 3430.77,3893.66 3462.27,3893.66 3493.77,3893.66 3241.8,3925.15 3273.29,3925.15 3304.79,3925.15 3367.78,3925.15 3399.28,3925.15 3430.77,3925.15 3462.27,3925.15 3588.25,3925.15 3178.81,3956.65 3210.3,3956.65 3241.8,3956.65 3273.29,3956.65 3304.79,3956.65 3367.78,3956.65 3399.28,3956.65 3430.77,3956.65 3462.27,3956.65 3493.77,3956.65 3525.26,3956.65 3556.76,3956.65 3588.25,3956.65 3619.75,3956.65 3178.81,3988.14 3210.3,3988.14 3273.29,3988.14 3304.79,3988.14 3399.28,3988.14 3430.77,3988.14 3493.77,3988.14 3525.26,3988.14 3588.25,3988.14 3178.81,4019.64 3210.3,4019.64 3273.29,4019.64 3304.79,4019.64 3399.28,4019.64 3430.77,4019.64 3493.77,4019.64 3525.26,4019.64 3588.25,4019.64 3619.75,4082.63
  other v3: 6960.58,6278.44 7000.58,6278.44 7040.58,6278.44 7330.58,6278.44 7370.58,6278.44 7410.58,6278.44 6960.58,6318.44 7410.58,6318.44 6960.58,6358.44 7410.58,6358.44 6960.58,6844.7 7000.58,6844.7 7040.58,6844.7 7080.58,6844.7 7120.58,6844.7 7160.58,6844.7 7210.58,6844.7 7250.58,6844.7 7290.58,6844.7 7330.58,6844.7 7370.58,6844.7 7410.58,6844.7 6960.58,6884.7 7000.58,6884.7 7040.58,6884.7 7080.58,6884.7 7120.58,6884.7 7160.58,6884.7 7210.58,6884.7 7250.58,6884.7 7290.58,6884.7 7330.58,6884.7 7370.58,6884.7 7410.58,6884.7 6960.58,6924.7 7000.58,6924.7 7040.58,6924.7 7080.58,6924.7 7120.58,6924.7 7160.58,6924.7 7210.58,6924.7 7250.58,6924.7 7290.58,6924.7 7330.58,6924.7 7370.58,6924.7 7410.58,6924.7 6960.58,6964.7 7000.58,6964.7 7040.58,6964.7 7080.58,6964.7 7120.58,6964.7 7160.58,6964.7 7210.58,6964.7 7250.58,6964.7 7290.58,6964.7 7330.58,6964.7 7370.58,6964.7 7410.58,6964.7
  other v4: 3084.06,726.36 3162.8,726.36 6255.33,804.98 6302.57,804.98 6349.81,804.98 6255.33,852.23 6302.57,852.23 6349.81,852.23 6255.33,899.47 6302.57,899.47 6349.81,899.47 5040.99,934.76 5084.29,934.76 5127.6,934.76 5170.91,934.76 5214.22,934.76 5257.52,934.76 5300.83,934.76 6255.33,946.72 6302.57,946.72 6349.81,946.72 5040.99,978.07 5084.29,978.07 5127.6,978.07 5170.91,978.07 5214.22,978.07 5257.52,978.07 5300.83,978.07 6255.33,993.96 6302.57,993.96 6349.81,993.96 450.24,996.68 497.49,996.68 544.73,996.68 591.97,996.68 639.22,996.68 686.46,996.68 733.71,996.68 780.95,996.68 6255.33,1041.2 6302.57,1041.2 6349.81,1041.2 450.24,1043.93 497.49,1043.93 544.73,1043.93 591.97,1043.93 639.22,1043.93 686.46,1043.93 733.71,1043.93 780.95,1043.93 6255.33,1088.45 6302.57,1088.45 6349.81,1088.45 450.24,1091.17 497.49,1091.17 544.73,1091.17 591.97,1091.17 639.22,1091.17 686.46,1091.17 733.71,1091.17 780.95,1091.17 6837.59,1226.98 6887.44,1226.98 6937.28,1226.98 6794.92,1269.65 6887.44,1269.65 6979.96,1269.65 6794.92,1319.5 6837.59,1319.5 6937.28,1319.5 6979.96,1319.5 6794.92,1369.34 6887.44,1369.34 6937.28,1369.34 6979.96,1369.34 6837.59,1412.02 6887.44,1412.02 7407.92,2401.39 7486.66,2401.39 5199.43,2924.93 5161.24,2963.12 5199.43,2963.12 5237.62,2963.12 5199.43,3001.31 2136.34,3300.69 2104.84,3344.79 2136.34,3344.79 2167.84,3344.79 2104.84,3398.33 2136.34,3398.33 2167.84,3398.33 2136.34,3442.42 5068.16,4610.64 5111.47,4610.64 3577.99,4994.86 3621.3,4994.86 3664.61,4994.86 3707.91,4994.86 3751.22,4994.86 3577.99,5042.1 3621.3,5042.1 3664.61,5042.1 3707.91,5042.1 3751.22,5042.1 3577.99,5089.35 3621.3,5089.35 3664.61,5089.35 3707.91,5089.35 3751.22,5089.35 7389.35,5108.51 7361.79,5136.07 7389.35,5136.07 7416.91,5136.07 3577.99,5136.59 3621.3,5136.59 3664.61,5136.59 3707.91,5136.59 3751.22,5136.59 7389.35,5163.63 3577.99,5183.84 3621.3,5183.84 3664.61,5183.84 3707.91,5183.84 3751.22,5183.84 3577.99,5231.08 3621.3,5231.08 3664.61,5231.08 3707.91,5231.08 3751.22,5231.08 3577.99,5278.32 3621.3,5278.32 3664.61,5278.32 3707.91,5278.32 3751.22,5278.32 3577.99,5325.57 3621.3,5325.57 3664.61,5325.57 3707.91,5325.57 3751.22,5325.57 3577.99,5372.81 3621.3,5372.81 3664.61,5372.81 3707.91,5372.81 3751.22,5372.81 3109.92,5411.24 3161.1,5411.24 3577.99,5420.06 3621.3,5420.06 3664.61,5420.06 3707.91,5420.06 3751.22,5420.06 3109.92,5462.42 3161.1,5462.42 3577.99,5467.3 3621.3,5467.3 3664.61,5467.3 3707.91,5467.3 3751.22,5467.3 3109.92,5513.6 3161.1,5513.6 3109.92,5564.78 3161.1,5564.78 1446.81,6502.84 1505.86,6502.84 1887.85,6502.68 1946.91,6502.68 3698.51,6502.68 3757.57,6502.68 3257.78,6503.64 3316.84,6503.64
  other v5: 7103.75,3660.06 4062.97,4501 3927.11,5298.2 1335.78,6449.26 3851.22,6458.27 3070.53,6474.57 3845.56,6545.14 2036.99,6545.86 1361.03,6547.16
  other v7: 7608.83,2871.32 7667.88,2871.32 7608.83,2930.38 7667.88,2930.38 7608.83,2989.43 7667.88,2989.43
GPI2: SW6.1 U41.21 | length 3610.2
  Top Layer w8: U41.21@3812.24,5398.4 3848.6,5398.4 3863.31,5413.12 v5(3884.7,5413.1) ; SW6.1@4460.32,2233.56 v1(4460.32,2303.66)
  SIG_1 w6: v5(3884.7,5413.1) 3903.34,5394.47 3931.6,5394.47 3998.49,5327.59 3998.49,4991.79 4486.76,4503.52 4486.76,4379.14 4486.76,4265.28 4369.54,4148.07 4369.54,2394.44 v1(4460.32,2303.66)
GPI5: SW7.1 U41.28 | length 4458.2
  Top Layer w8: v5(3476.56,5397.47) 3477.02,5397.94 3516.5,5397.94 U41.28@3516.97,5398.4 ; SW7.1@4786.64,2231.96 v1(4786.64,2302.06)
  SIG_1 w6: v5(3476.56,5397.47) 3476.56,5360.58 3463.89,5347.92 3448.82,5347.92 3429.91,5329 3429.91,4989.19 3500.62,4918.48 4037.53,4918.48 4462.65,4493.36 4462.65,4273.06 4334.46,4144.88 4334.46,2376.16 4432.26,2278.37 4511.22,2278.37 4534.92,2302.06 v1(4786.64,2302.06)
GPIO14: U32.B11 U52.19 | length 2594.8
  Top Layer w8: v1(5265.21,4325.82) U52.19@5320.04,4325.82
  Top Layer w9.9: v2(3084.32,3925.15) U32.B11@3100.07,3909.4
  SIG_2 w4.5: v2(3084.32,3925.15) 3099.48,3909.99 3099.48,3882.35 3113.66,3868.16 3587.74,3868.16 3603.84,3884.26 3603.84,3904.69
  SIG_2 w6: 3603.84,3904.69 3615.54,3916.39 3628.57,3916.39 3696.11,3983.94 3778.75,3983.94 3795.02,3967.67 4250.03,3967.67 4668.75,4386.38 4826.09,4386.38 4841.7,4401.99 4928.77,4401.99 4939.18,4412.4 5196.09,4412.4 5265.21,4343.28 v1(5265.21,4325.82)
GPIO75: J11.19 U32.L3 | length 4171.8
  Top Layer w8: J11.19@411.42,5629.8 v1(449.81,5629.8)
  Top Layer w9.9: U32.L3@3383.53,3657.44 v2(3399.28,3641.69)
  SIG_3 w4.5: v1(449.81,5629.8) 449.81,5587.36 496.02,5541.14 496.02,5460.26 716.29,5240 1263.71,5240 1277.71,5226 1832.63,5226 1938.21,5120.42 1938.21,5003.03 2406.98,4534.26 2406.98,4480.3 2458.67,4428.61 2481.72,4428.61 2504.81,4405.52 2586.2,4405.52 2987.49,4004.22 3217.17,4004.22 3226.4,3994.99 3226.4,3884.68 3233.3,3877.78 3310.52,3877.78 3347.67,3840.63 3347.67,3668.29 3358.39,3657.56 3383.4,3657.56 v2(3399.28,3641.69)
GPIO79: U32.B5 U56.3 | length 5261.6
  Top Layer w8: v1(7365.36,4994.01) 7365.36,5033.24 7378.59,5046.47 7378.59,5060.35 U56.3@7379.51,5061.27
  Top Layer w9.9: v2(3084.32,3704.68) U32.B5@3100.07,3720.43
  SIG_3 w4.5: v2(3084.32,3704.68) 3100.35,3688.64 3186.74,3688.64 3194.39,3680.99 3194.39,3632.6 3200.97,3626.02 3408.25,3626.02 3414.98,3632.75 3414.98,3964.19 3422.99,3972.19 3633.48,3972.19 3890.01,3972.19 4357.13,4439.31 4540.88,4439.31 4560.86,4419.33 4720.57,4419.33 4748.31,4447.07 5235.02,4447.07 5406.01,4618.06 5746.77,4618.06 5766.31,4637.6 6094.86,4637.6 6104.02,4628.44 6395.31,4628.44 6590.73,4823.86 6770.88,4823.86 6816.73,4778.01 7123.65,4778.01 7140.64,4795 7142.93,4795 7153.04,4805.1 7153.04,4807.39 7339.65,4994.01 v1(7365.36,4994.01)
GPIO81: R446.2 U32.A3 U54.32 | length 4009.5
  Top Layer w8: v2(6450.08,3097.5) 6479.62,3127.05 U54.32@6550.74,3127.05 6550.74,3188 R446.2@6501.84,3236.89
  Top Layer w9.9: v2(3052.82,3641.69) U32.A3@3068.57,3657.44
  SIG_2 w4.5: v2(3052.82,3641.69) 3068.26,3626.24 3639.86,3626.24
  SIG_2 w6: 3639.86,3626.24 3744.53,3730.92 3794.29,3730.92 3803.34,3739.96 3983.48,3739.96 4016.5,3772.98 4984.56,3772.98 5342.82,3414.72 5928.3,3414.72 6245.52,3097.5 v2(6450.08,3097.5)
GPIO85: U5.14 U32.L17 | length 4265.5
  Top Layer w8: v1(1624.94,1513.61) U5.14@1624.94,1534.94
  Top Layer w9.9: U32.L17@3383.53,4098.38 v2(3399.28,4114.13)
  SIG_2 w6: v1(1624.94,1513.61) 1624.94,1647.75 1691.92,1714.73 1691.92,1948.03 1809.74,2065.86 1809.74,2222.67 1681.68,2350.74 1681.68,2766.69 2105.08,3190.1 2393.39,3190.1 2757.34,3554.04 2757.34,4194.19 2848.26,4285.1 3284.66,4285.1 3415.98,4153.79 3415.98,4130.83 v2(3399.28,4114.13)
GPIO86: U6.8 U7.8 U7.14 U32.L18 | length 3332.7
  Top Layer w8: U6.8@1786.01,2859.25 v1(1786.01,2825.63) 1833.25,2778.39 U7.8@1833.25,2598.99 1871.56,2598.99 1885.45,2585.1 1885.45,2309.35 1875.09,2298.99 U7.14@1833.25,2298.99
  Top Layer w9.9: U32.L18@3383.53,4129.88 v2(3399.28,4145.62)
  SIG_2 w6: v1(1786.01,2825.63) 2126.32,3165.95 2405.45,3165.95 2779.59,3540.09 2779.59,4185.1 2863.87,4269.37 3275.53,4269.37 v2(3399.28,4145.62)
GPIO107: U32.E16 U56.2 | length 4737.2
  Top Layer w8: v1(7340.07,5019.85) 7352.36,5032.14 7352.36,5038.63 7358.9,5045.17 7358.9,5060.35 U56.2@7359.82,5061.27
  Top Layer w9.9: v2(3178.81,4082.63) U32.E16@3194.55,4066.88
  SIG_3 w4.5: v2(3178.81,4082.63) 3163.64,4067.47 3163.64,4042.34 3176.16,4029.83 3262,4029.83 3267,4034.83 3779.38,4034.83 3783.5,4038.95 3796.91,4038.95 3801.04,4034.83 3889.63,4034.83 3987.97,4133.17 3987.97,4136.71 3990.51,4139.25 3990.51,4176.03 4306.09,4491.61 5246.91,4491.61 5417.02,4661.72 6103.73,4661.72 6107.9,4665.89 6401.82,4665.89 6577.56,4841.63 7161.86,4841.63 v1(7340.07,5019.85)
GPIO108: U32.F16 | length 22.3
  Top Layer w9.9: v2(3210.3,4082.63) U32.F16@3226.05,4066.88
GPIO112: U32.E18 U50.3 | length 2423.1
  Top Layer w8: v1(5224.82,3872.47) 5247.91,3872.47 5327.55,3792.82 U50.3@5327.55,3726.74
  Top Layer w9.9: v2(3178.81,4145.62) U32.E18@3194.55,4129.88
  PWR/SIG_1 w6: v2(3178.81,4145.62) 3195.28,4129.15 3633.48,4129.15 3666.12,4129.15 3693.68,4156.71 3963.05,4156.71 3967.31,4152.44 3981.34,4152.44 3985.61,4156.71 4180.29,4156.71 4419.85,3917.15 5203.22,3917.15 5224.82,3895.55 v1(5224.82,3872.47)
GPIO124: U32.A16 U50.4 | length 3809.6
  Top Layer w8: U50.4@5307.87,3726.74 v1(5307.87,3768.47)
  Top Layer w9.9: v2(3052.82,4082.63) U32.A16@3068.57,4066.88
  PWR/SIG_1 w4.5: v2(3052.82,4082.63) 3068.74,4098.55 3124.3,4098.55 3131.79,4106.05 3131.79,4160.62 3146.82,4175.65 3168.49,4175.65 3175.14,4182.3
  PWR/SIG_1 w6: 3175.14,4182.3 3398.52,4182.3 3432.88,4216.66 4217.15,4216.66 4770.85,4770.37 5412.27,4770.37 5441.48,4741.16 5441.48,3905.15 5307.87,3771.54 v1(5307.87,3768.47)
GPIO125: U8.1 U32.D13 | length 2419.3
  Top Layer w8: v1(2283.51,2427.14) U8.1@2305.62,2427.14
  Top Layer w9.9: v2(3147.31,3988.14) U32.D13@3163.06,3972.4
  PWR/SIG_1 w4.5: 2993.91,3840.35 2993.91,3867.23 3036.54,3909.87 3063.63,3909.87 3068.77,3915.01 3068.77,3932.6 3077.66,3941.5 3126.3,3941.5 3131.44,3946.64 3131.44,3972.27 v2(3147.31,3988.14)
  PWR/SIG_1 w6: v1(2283.51,2427.14) 2283.51,2386.95 2329.12,2341.33 2440.5,2341.33 2586.63,2487.47 2885.28,2487.47 2989.05,2591.24 2989.05,3835.49 2993.91,3840.35
GPO2: R344.2 U41.23 | length 179.2
  Top Layer w8: U41.23@3812.24,5437.77 3846.89,5437.77 3856.87,5447.75 3856.87,5577.56 R344.2@3857.31,5578
GPO3: R345.2 U41.26 | length 196.3
  Top Layer w8: R345.2@3458.18,5590.08 3458.18,5462.99 3483.4,5437.77 U41.26@3516.97,5437.77
HGATE_4: Q2.4 Q4.4 R17.1 U1.14 | length 1104.4
  Top Layer w8: U1.14@5577.92,4791.35 5603.12,4791.35 v1(5624.5,4769.98) ; Q4.4@6116.58,5059.2 v1(6153.11,5059.2) ; Q2.4@6406.79,5059.2 v1(6442.95,5059.2) 6479.11,5059.2 R17.1@6480.43,5060.51
  SIG_3 w6: v1(5624.5,4769.98) 5674.19,4769.98 5963.41,5059.2 v1(6153.11,5059.2) v1(6442.95,5059.2)
I2C0_SCL: J15.2 J20.12 R221.1 U32.A13 U36.8 U37.6 U43.33 U55.19 | length 8822.7
  Top Layer w8: U43.33@1117.5,4638.62 1182.42,4638.62 v1(1202.1,4658.3) ; v1(2264.97,4298.02) 2276.39,4309.43 U36.8@2351.69,4309.43 2351.69,4270.9 2331.64,4250.85 U37.6@2331.64,4188.41 2331.64,4141.3 2348.85,4124.09 2541.26,4124.09 J15.2@2583.63,4081.72 2662.55,4002.8 2800.18,4002.8 2845.51,3957.48 2960.64,3957.48 R221.1@2984.93,3981.77 2991.3,3988.14 v2(3052.82,3988.14) U32.A13@3068.57,3972.4 ; U55.19@5274.23,2913.9 5291.09,2913.9 v1(5301.45,2903.54)
  Top Layer w10: v1(2561.03,1399.74) J20.12@2561.03,1508.37
  SIG_3 w6: v1(1202.1,4658.3) 1978.84,4658.3 2275.64,4361.5 2275.64,4308.68 v1(2264.97,4298.02)
  SIG_2 w6: v2(3052.82,3988.14) 3033.55,3988.14 2974.41,3929 2974.41,3536.43 3048.17,3462.67 3764.52,3462.67 3805.72,3503.87 3925.15,3503.87 4111.51,3690.22 4213.84,3690.22 4335.46,3568.6 4335.46,3519.32 4546.46,3308.31 4760.38,3308.31 5165.13,2903.56 5234.92,2903.56 5248.81,2917.46 5287.54,2917.46 v1(5301.45,2903.54)
  Bottom Layer w8: v1(2561.03,1399.74) 2518.57,1442.21 2518.57,1851.17 2807.11,2139.72 2807.11,2772.66 2583.63,2996.14 J15.2@2583.63,4081.72
I2C0_SDA: J15.3 J20.11 R222.1 U32.B13 U36.7 U37.5 U43.34 U55.20 | length 8704.9
  Top Layer w8: U43.34@1117.5,4613.62 1198.28,4613.62 v1(1217.22,4632.56) ; v1(2248.57,4324.98) 2258.61,4335.02 U36.7@2351.69,4335.02 2389,4335.02 2399.65,4324.37 2399.65,4262.7 2381.64,4244.69 U37.5@2381.64,4188.41 2576.94,4188.41 J15.3@2683.63,4081.72 2716.37,4048.98 2963.7,4048.98 R222.1@2984.93,4027.75 3014.73,4027.75 v1@3022.72,4019.76 ; U55.20@5274.23,2933.59 5313.96,2933.59 v1(5323.53,2924.03)
  Top Layer w9.9: v2(3084.32,3988.14) U32.B13@3100.07,3972.4
  Top Layer w10: J20.11@2561.03,1703.25 v1(2561.03,1811.89)
  SIG_3 w6: v1(1217.22,4632.56) 1981.45,4632.56 2248.57,4365.44 v1(2248.57,4324.98)
  SIG_2 w4.5: v1(3022.72,4019.64) 3038.15,4004.2 3068.26,4004.2 v2(3084.32,3988.14)
  SIG_2 w6: v1(3022.72,4019.64) 2998.63,4019.64 2933.11,3954.12 2933.11,3676.66 2923.23,3666.79 2923.23,3525.83 3030.07,3418.98 3182.01,3418.98 3212.47,3449.44 3310.33,3449.44 3343.64,3416.13 3501.96,3416.13 3529.66,3443.82 3906.65,3443.82 4137.25,3674.43 4195.94,3674.43 4295.49,3574.87 4295.49,3507.93 4520.05,3283.37 4759.36,3283.37 4876.13,3166.61 4876.13,3110.39 4984.95,3001.56 5034.78,3001.56 5150.21,2886.13 5241.24,2886.13 5259.16,2868.22 5312.9,2868.22 5323.53,2878.84 v1(5323.53,2924.03)
  Bottom Layer w8: v1(2561.03,1811.89) 2898.84,2149.69 2898.84,2724.22 2610.68,3012.38 2610.68,4008.77 J15.3@2683.63,4081.72
I2C1_SDA: R363.2 U32.C8 | length 164.8
  Top Layer w8: R363.2@2990.2,3790.57 v1(3013.52,3790.57)
  Top Layer w9.9: v2(3115.81,3799.17) U32.C8@3131.56,3814.92
  Bottom Layer w5: v1(3013.52,3790.57) 3013.52,3790.8 3037.86,3815.14 3099.84,3815.14 v2(3115.81,3799.17)
I2S_FSYNC_24: R74.1 R76.1 R77.1 R78.1 | length 2024.7
  Top Layer w8: R77.1@1697.78,6551.89 v1(1697.78,6587.35) ; R78.1@2637.82,6623.43 v1(2637.82,6661.81) ; R74.1@3467.84,6511.95 v1(3467.84,6550.34)
  Top Layer w9.9: R78.1@2637.82,6623.43 2638.95,6622.3 R76.1@2638.95,6558.48
  Bottom Layer w8: v1(1697.78,6587.35) 1772.24,6661.81 v1(2637.82,6661.81) 3356.37,6661.81 v1(3467.84,6550.34)
I2S_FSYNC_ETH_MCU: R78.2 U18.4 U32.G15 | length 3111.6
  Top Layer w9.9: v1(2548.51,5912.39) 2497.12,5963.78 2497.12,6493.47 2511.52,6507.87 2551.3,6507.87 2574.45,6531.02 U18.4@2574.45,6559.06 2574.83,6559.44 R78.2@2574.83,6623.43 ; v2(3241.8,4051.14) U32.G15@3257.55,4035.39
  SIG_3 w3.6: v1(2548.51,5912.39) 2548.51,5076.93 2755.4,4870.04 2755.4,4558.02 2840.27,4473.15 2840.27,4379.56 2930.95,4288.88 3192.25,4288.88 3225.53,4255.61 3225.53,4158.4 3225.53,4067.41 v2(3241.8,4051.14)
I2S_SCLK_ETH_24: R75.2 R79.2 U14.2 U15.2 | length 1956.6
  Top Layer w8: v1(2804.76,6437.26) U15.2@2804.76,6470.72 ; v1(2988.06,6437.2) U14.2@2988.06,6470.67
  Bottom Layer w8: R79.2@1476.79,6239.52 2072.74,6239.52 2230.72,6397.51 2765.01,6397.51 v1(2804.76,6437.26) 2804.81,6437.2 v1(2988.06,6437.2) 3068.95,6356.31 3068.95,6289.44 3122.24,6236.15 R75.2@3162.07,6236.15
I2S_SCLK_ETH_MCU: U15.4 U32.G17 | length 3032.1
  Top Layer w9.9: v1(2589.54,5856.82) 2856.41,6123.68 2856.41,6500.01 2830.35,6526.07 U15.4@2830.35,6559.3 ; v2(3241.8,4114.13) U32.G17@3257.55,4098.38
  SIG_3 w3.6: v1(2589.54,5856.82) 2589.54,5154.18 2621.26,5122.46 2621.26,5076.66 2791.59,4906.33 2791.59,4566.54 2867.86,4490.27 2867.86,4374.29 2892.63,4349.52 3163.19,4349.52 3259.52,4253.19 3259.52,4158.4 3259.52,4131.85 v2(3241.8,4114.13)
I2t_19: C401.1 U56.12 | length 148.7
  Top Layer w8: U56.12@7464.15,5185.29 7489.07,5185.29 7543.13,5239.35 C401.1@7543.13,5286.66
IMON: C403.1 R308.1 R473.2 U56.9 | length 4815
  Top Layer w8: U56.9@7464.15,5126.23 7553.73,5126.23 7568.01,5111.95 v1(7568.1,5111.95) C403.1@7604.61,5111.95
  Top Layer w15: R308.1@4867.53,2807.43 v1(4906.67,2807.43)
  PWR/SIG_1 w6: v1(4906.67,2807.43) 5603.39,2807.43 5651.86,2758.96 6233.15,2758.96 6239.67,2765.48 6820.95,2765.48 7209.89,3154.42 7209.89,3726.28 7493.88,4010.26 7493.88,4159.81 7525.52,4191.45 7525.52,5069.38 v1(7568.1,5111.95)
  Bottom Layer w8: v1(7568.1,5111.95) R473.2@7604.61,5111.95
IN0_MSDI: C133.2 J29.C1 R180.1 | length 213.6
  Top Layer w8: J29.C1@2298.37,411.32 C133.2@2298.37,483.45 2316.93,483.45 2324.79,491.31 R180.1@2324.79,603.15
IN1_MSDI: C134.2 J29.B1 R181.1 | length 350.1
  Top Layer w8: J29.B1@2298.37,311.32 2383.97,396.92 C134.2@2383.97,484.44 2402.53,484.44 2410.39,492.29 R181.1@2410.39,604.13
IN2_MSDI: C137.2 J29.B15 R183.1 | length 333.3
  Bottom Layer w8: J29.B15@898.37,311.32 948.11,361.06 C137.2@948.11,482.47 966.67,482.47 974.52,490.33 R183.1@974.53,602.16
IN3_MSDI: C138.2 J29.C16 R184.1 | length 213.8
  Top Layer w8: J29.C16@798.37,411.32 798.37,483.01 C138.2@797.93,483.45 816.49,483.45 824.34,491.31 R184.1@824.34,603.15
IN4_MSDI: C140.2 J29.C15 R186.1 | length 214
  Top Layer w8: J29.C15@898.37,411.32 898.37,482.51 C140.2@897.43,483.45 915.98,483.45 923.84,491.31 R186.1@923.84,603.15
IN5_MSDI: C141.2 J29.C14 R188.1 | length 213.8
  Top Layer w8: J29.C14@998.37,411.32 998.37,483.03 C141.2@998.8,483.45 1017.35,483.45 1025.21,491.31 R188.1@1025.21,603.15
IN6_MSDI: C142.2 J29.B13 R189.1 | length 333.4
  Bottom Layer w8: J29.B13@1098.37,311.32 1148.46,361.4 C142.2@1148.46,482.47 1167.01,482.47 1174.87,490.33 R189.1@1174.87,602.16
IN7_MSDI: C143.2 J29.C13 R190.1 | length 213.6
  Top Layer w8: J29.C13@1098.37,411.32 1098.37,483.43 1116.91,483.45 1124.77,491.31 R190.1@1124.77,603.15
IN8_MSDI: C144.2 J29.C12 R192.1 | length 213.7
  Top Layer w8: J29.C12@1198.37,411.32 1198.37,483.27 C144.2@1198.56,483.45 1217.11,483.45 1224.97,491.31 R192.1@1224.97,603.15
IN9_MSDI: C146.2 J29.B11 R193.1 | length 333.3
  Bottom Layer w8: J29.B11@1298.37,311.32 1348.21,361.15 C146.2@1348.21,482.47 1366.76,482.47 1374.62,490.33 R193.1@1374.62,602.16
IN10_MSDI: C149.2 J29.C11 R194.1 | length 213.8
  Top Layer w8: J29.C11@1298.37,411.32 1298.37,483.08 C149.2@1298,483.45 1316.55,483.45 1324.41,491.31 R194.1@1324.41,603.15
IN11_MSDI: C151.2 J29.C10 R195.1 | length 213.7
  Top Layer w8: J29.C10@1398.37,411.32 1398.37,483.41 C151.2@1398.42,483.45 1416.98,483.45 1424.83,491.31 R195.1@1424.83,603.15
IN12_MSDI: C153.2 J29.B9 R196.1 | length 333.4
  Bottom Layer w8: J29.B9@1498.37,311.32 1548.37,361.32 C153.2@1548.37,482.47 1566.93,482.47 1574.79,490.33 R196.1@1574.79,602.16
IN13_MSDI: C156.2 J29.C9 R197.1 | length 213.6
  Top Layer w8: J29.C9@1498.37,411.32 C156.2@1498.37,483.45 1516.93,483.45 1524.79,491.31 R197.1@1524.79,603.15
IN14_MSDI: C159.2 J29.C8 R199.1 | length 213.6
  Top Layer w8: J29.C8@1598.37,411.32 C159.2@1598.37,483.45 1616.93,483.45 1624.79,491.31 R199.1@1624.79,603.15
IN15_MSDI: C150.2 J29.C7 R198.1 | length 213.6
  Top Layer w8: J29.C7@1698.37,411.32 C150.2@1698.37,483.45 1716.93,483.45 1724.79,491.31 R198.1@1724.79,603.15
IN16_MSDI: C152.2 J29.B7 R200.1 | length 333.4
  Bottom Layer w8: J29.B7@1698.37,311.32 1748.37,361.32 C152.2@1748.37,482.47 1766.93,482.47 1774.79,490.33 R200.1@1774.79,602.16
IN17_MSDI: C155.2 J29.C6 R201.1 | length 213.6
  Top Layer w8: J29.C6@1798.37,411.32 C155.2@1798.37,483.45 1816.93,483.45 1824.79,491.31 R201.1@1824.79,603.15
IN18_MSDI: C158.2 J29.C5 R202.1 | length 213.6
  Top Layer w8: J29.C5@1898.37,411.32 C158.2@1898.37,483.45 1916.93,483.45 1924.79,491.31 R202.1@1924.79,603.15
IN19_MSDI: C161.2 J29.B5 R203.1 | length 333.4
  Bottom Layer w8: J29.B5@1898.37,311.32 1948.37,361.32 C161.2@1948.37,482.47 1966.93,482.47 1974.79,490.33 R203.1@1974.79,602.16
IN20_MSDI: C154.2 J29.C4 R204.1 | length 213.6
  Top Layer w8: J29.C4@1998.37,411.32 C154.2@1998.37,483.45 2016.93,483.45 2024.79,491.31 R204.1@2024.79,603.15
IN21_MSDI: C157.2 J29.C3 R205.1 | length 213.6
  Top Layer w8: J29.C3@2098.37,411.32 C157.2@2098.37,483.45 2116.93,483.45 2124.79,491.31 R205.1@2124.79,603.15
IN22_MSDI: C160.2 J29.B3 R206.1 | length 333.4
  Bottom Layer w8: J29.B3@2098.37,311.32 2148.37,361.32 C160.2@2148.37,482.47 2166.93,482.47 2174.79,490.33 R206.1@2174.79,602.16
IN23_MSDI: C162.2 J29.C2 R207.1 | length 213.6
  Top Layer w8: J29.C2@2198.37,411.32 C162.2@2198.37,483.45 2216.93,483.45 2224.79,491.31 R207.1@2224.79,603.15
IN+_4: C13.2 R32.1 U2.4 | length 158.6
  Top Layer w8: R32.1@6651.01,5279.35 6651.01,5237.75 C13.2@6646.02,5232.76 6646.02,5205.27 6650.71,5200.59 6669.57,5200.59 6687.51,5182.64 6687.82,5182.33 6687.82,5151.65 U2.4@6688.13,5151.34
IN-_4: C13.1 R33.1 U2.5 | length 169.4
  Top Layer w8: v5(6661.74,5184.65) v5@6662.17,5184.65 ; v5@6662.14,5184.25 6662.14,5151.74 U2.5@6662.54,5151.34 ; R33.1@6703.51,5279.35 6703.51,5238.27 C13.1@6709.01,5232.76 ; v5@6708.93,5198.58 v5(6709.04,5198.47) C13.1@6709.04,5232.74
  Bottom Layer w8: v5@6662.17,5184.65 6676.1,5198.58 v5@6708.93,5198.58
INA_VS_4: C12.1 U2.3 U3.5 U3.6 | length 129.1
  Top Layer w10: U2.3@6688.13,5064.73 6688.13,5015.51 6688.13,4961.32 6688.13,4935.93 U3.5@6688.33,4935.73
INH_ETH: D40.2 J11.12 J12.36 J13.36 | length 3228
  Top Layer w8: J11.12@588.58,5755.78 v1(626.97,5755.78) ; v1(1540.3,6109.41) J13.36@1540.3,6147.8 ; v1(3312.57,6036.3) 3312.57,5979.02 3328.97,5962.62 3350.84,5962.62 D40.2@3350.96,5962.5 ; J12.36@3350.96,6147.8 D40.2@3350.96,5962.5 ; D40.2@3352.04,5962.5 D40.2@3350.96,5962.5
  Bottom Layer w8: v1(626.97,5755.78) 1095.85,5755.78 1449.48,6109.41 v1(1540.3,6109.41) 1613.41,6036.3 v1(3312.57,6036.3)
INH_TCAN1043A: R39.1 R41.2 R335.1 U10.8 U41.6 | length 6372.9
  Top Layer w8: v1(907.38,3093.62) U10.8@907.38,3129.16 ; v1(1636.7,1721.13) R39.1@1679.4,1721.13 ; U41.6@3812.24,5103.13 3854.3,5103.13 v1(3878.9,5078.53)
  Bottom Layer w8: R41.2@1679.4,1721.13 v1(1636.7,1721.13) 1596.99,1760.83 1263.06,1760.83 677.21,2346.67 677.21,2964.89 751.74,3039.42 853.18,3039.42 v1(907.38,3093.62) 934.45,3120.69 934.45,3198.65 1228.77,3492.97 1500.97,3492.97 2089.34,4081.34 2089.34,4282.55 2293.92,4487.12 2605.8,4487.12 2691.06,4572.38 2960.55,4572.38 3003.38,4615.21 3495.3,4615.21 3840.39,4960.3 R335.1@3898.93,4960.3 3898.93,5007.28 3878.9,5027.31 v1(3878.9,5078.53)
INP_G_TPS1211: U42.2 U54.24 | length 715
  Top Layer w8: U54.24@6708.22,3127.05 6708.22,3175.9 6695.3,3188.82 6695.3,3477.42 6695.3,3496.97 6695.3,3636.71 6723.78,3665.18 6824.91,3665.18 6834.6,3674.88 U42.2@6834.6,3719.72
INP_TPS1211: U42.3 U54.25 | length 714.3
  Top Layer w8: v2(6662.7,3288.99) 6661.8,3288.09 6661.8,3201.93 6688.54,3175.19 U54.25@6688.54,3127.05 ; v1(6854.29,3664.77) U42.3@6854.29,3719.72
  Bottom Layer w8: v2(6662.7,3288.99) 6662.7,3291.45 6625.54,3328.62 6625.54,3436.02 v1(6854.29,3664.77)
INT_MSDI: D19.2 R182.2 U49.3 U51.2 | length 9956.8
  Top Layer w8: R182.2@556.54,669.68 556.32,669.9 D19.2@556.32,762.16 v1(592.74,762.16) ; U51.2@4710.5,4206.93 v1(4766.42,4206.93) 4800.89,4206.93 4806.51,4212.55 4806.97,4212.55 4808.41,4213.99 4811.66,4213.99 4813.56,4215.9 U49.3@4836.2,4215.9
  SIG_2 w6: v1(592.74,762.16) 1450.07,762.16 2781.64,2093.72 4886.12,2093.72 5243.75,2451.35 6219.9,2451.35 6689.52,2920.97 6689.52,3350.59 6234.83,3805.28 5668.18,3805.28 5628.78,3844.67 5385.06,3844.67 5022.8,4206.93 v1(4766.42,4206.93)
INT_VREF1_10: S1.1
INT_VREF2_10: S1.4
IOC_19: R471.2 U56.11 | length 167.8
  Top Layer w8: U56.11@7464.15,5165.6 7502.07,5165.6 7568.1,5231.63 ; 7568.13,5231.66 R471.2@7604.61,5231.66
ISCP_14: C405.1 R383.2 U42.19 | length 210
  Top Layer w8: R383.2@6754.75,3967.93 6791.83,3967.93 6806,3953.75 6806,3952.92 v5(6819.35,3939.57) 6819.35,3937.98 6832.7,3924.63 6832.7,3894.86 U42.19@6834.6,3892.95
  Bottom Layer w8: v5(6819.35,3939.57) C405.1@6819.35,4019.76
ITMPO: C402.1 R312.1 R470.1 U56.10 | length 4983.9
  Top Layer w8: U56.10@7464.15,5145.92 7542.75,5145.92 v1(7568.1,5171.25) C402.1@7604.61,5171.25
  Top Layer w15: R312.1@4868.16,2650.95 4913.59,2650.95 v1(4926.73,2637.8)
  PWR/SIG_1 w6: v1(4926.73,2637.8) 6775.75,2637.8 7220.23,3082.28 7220.23,3691.57 7522.23,3993.57 7522.23,4143.42 7574.27,4195.46 7574.27,4979.69 7594.34,4999.76 7594.34,5145.01 v1(7568.1,5171.25)
  Bottom Layer w8: v1(7568.1,5171.25) R470.1@7604.61,5171.25
LATCH_TPS1HC30: R118.1 U54.11 | length 686.6
  Top Layer w8: U54.11@6747.59,2953.82 6747.59,2877.04 6769.06,2855.57 7201.94,2855.57 7220.59,2874.23 7295.47,2874.23 R118.1@7327.52,2906.28
LHI_HCS: R83.2 R95.2 R99.2 R337.1 U41.27 | length 15260
  Top Layer w8: U41.27@3516.97,5418.09 3475.01,5418.09 v5(3471.1,5422) 3414.72,5478.38 3414.72,5709.25 3464.68,5759.22 4122.12,5759.22 v1(4192.43,5688.9)
  SIG_1 w6: v1(3765.39,1229.51) 4063.66,1229.51 4217.37,1075.8 4754.97,1075.8 4812.53,1018.25 5993.23,1018.25 6082.49,928.99 6424.83,928.99 6749.59,604.23 7597.71,604.23 7725.49,732.01 7725.49,2983.17 v2(7657.55,3051.11) 7589.62,3119.04 7589.62,3212.36 7644.36,3267.1 7644.36,4409.7 7542.21,4511.85 7542.21,4809.35 7491.65,4859.91 7201.93,4859.91 6953.65,5108.19 6865.11,5108.19 6845.9,5127.39 6695.03,5127.39 6642.91,5179.51 6499.99,5179.51 6479.99,5159.5 6288.81,5159.5 5993.06,4863.76 5812.32,4863.76 5554.27,4605.71 5316.81,4605.71 5125.53,4414.43 4932.38,4414.43 4920.38,4402.43 4862.54,4402.43 4739.08,4525.89 4739.08,4528.23 4608.5,4658.81 4608.5,4869.3 4503.55,4974.25 4503.55,5377.78 v1(4192.43,5688.9)
  Bottom Layer w8: R95.2@3430.5,1112.92 3500.56,1112.92 3571.49,1183.86 3719.73,1183.86 v1(3765.39,1229.51) 3825.8,1289.93 R83.2@3825.8,1358.76 ; v5(3471.1,5422) 3499.16,5422 R337.1@3503.06,5418.09 ; R99.2@7398.54,3181.89 7398.54,3180.91 7413.24,3166.21 7414.23,3166.21 7529.33,3051.11 v2(7657.55,3051.11)
LIN0_RXD: R73.1 U11.10 U32.B6 | length 1111.6
  Top Layer w9.9: v2(3084.32,3736.18) U32.B6@3100.07,3751.92
  SIG_3 w4.5: v1(2284.93,3330.33) 2295.68,3341.08 2583.41,3341.08 2958.96,3716.63 3011.68,3716.63 3048.17,3753.12 3067.38,3753.12 v2(3084.32,3736.18)
  Bottom Layer w8: U11.10@2201.3,3302.66 2277.34,3302.66 2277.84,3302.17 2284.93,3309.26 v1(2284.93,3330.33)
LIN0_TXD: U11.12 U32.A4 | length 1156.5
  Top Layer w8: v1(2265.89,3255.77) 2439.42,3255.77 2594.5,3410.84 2594.5,3529.74 2648.28,3583.52 2811.93,3583.52 2903.33,3674.92 3054.55,3674.92 U32.A4@3068.57,3688.93
  Bottom Layer w8: U11.12@2165.87,3267.23 2202.34,3267.23 2213.8,3255.77 v1(2265.89,3255.77)
LIN1_RXD: R65.1 U10.1 U32.A9 | length 2600.4
  Top Layer w8: R65.1@1010.13,3071.43 1009.74,3071.82 U10.1@1009.74,3129.16 980.79,3129.16 953.42,3156.54 953.42,3189.22 986.92,3222.73 1048.02,3222.73 1280.74,3455.45 1803.33,3455.45 2235.47,3887.58 2853.87,3887.58 2920,3821.45 3040.11,3821.45 3058.32,3839.66 3058.47,3839.66 3061.34,3842.54 3062.6,3842.54 3066.47,3846.41 U32.A9@3068.57,3846.41
LIN1_TXD: U10.4 U32.B9 | length 2406.5
  Top Layer w5: 2912.69,3811.01 3044.43,3811.01 3062.64,3829.23 3082.88,3829.23 U32.B9@3100.07,3846.41
  Top Layer w8: U10.4@1009.74,3205.93 1051.64,3205.93 1287.31,3441.61 1809.78,3441.61 2240.6,3872.42 2851.28,3872.42 2912.69,3811.01
LIN2_RXD: R69.1 U11.1 U32.B8 | length 1527.9
  Top Layer w9.9: v2(3084.32,3799.17) U32.B8@3100.07,3814.92
  SIG_3 w4.5: v1(2330.65,3517.82) 2310.9,3498.08 2221.32,3498.08 2200.27,3477.03 2200.27,3392.08 2226.07,3366.29 2310.13,3366.29 2334.61,3390.76 2596.01,3390.76 2975.3,3770.05 3024.19,3770.05 3053.31,3799.17 v2(3084.32,3799.17)
  Bottom Layer w8: U11.1@2165.87,3475.89 2213.75,3475.89 2220.66,3482.79 2234.47,3482.79 2241.37,3475.89 2277.36,3475.89 R69.1@2277.84,3476.37 2277.84,3496.05 2287.81,3506.02 2318.78,3506.02 v1(2330.65,3517.82) v1(2330.65,3517.82)
LIN2_TXD: U11.3 U32.A8 | length 1022.4
  Top Layer w8: v1(2254.19,3449.04) 2255.48,3449.04 2292.69,3486.25 2336.91,3486.25 2622.41,3771.75 3025.4,3771.75 3039.05,3785.39 U32.A8@3068.57,3814.92
  Bottom Layer w8: U11.3@2201.3,3440.45 2245.61,3440.45 v1(2254.19,3449.04)
LIN3_RXD: R71.1 U11.4 U32.C11 | length 1171.8
  Top Layer w9.9: v2(3115.81,3925.15) U32.C11@3131.56,3909.4
  SIG_3 w4.5: v1(2284.93,3448.44) 2286.48,3449.99 2298.07,3449.99 2624.83,3776.75 2844.72,3776.75 2951.79,3883.82 2979.41,3883.82 3036.86,3941.27 3099.7,3941.27 v2(3115.81,3925.15)
  Bottom Layer w8: U11.4@2201.3,3420.77 2277.34,3420.77 R71.1@2277.84,3420.28 2284.93,3427.37 v1(2284.93,3448.44)
LIN4_RXD: R72.1 U11.7 U32.A10 | length 1106.9
  Top Layer w9.9: v2(3052.82,3893.66) U32.A10@3068.57,3877.91
  SIG_3 w4.5: v1(2284.93,3389.39) 2286.25,3390.7 2298.3,3390.7 2349.48,3441.88 2424.94,3441.88 2562.62,3579.55 2738.74,3579.55 3039.05,3879.86 v2@3052.82,3893.64
  Bottom Layer w8: U11.7@2201.3,3361.71 2277.34,3361.71 2277.84,3361.22 2284.93,3368.31 v1(2284.93,3389.39)
LIN4_TXD: U11.9 U32.C9 | length 1248
  Top Layer w9.9: v2(3115.81,3830.66) U32.C9@3131.56,3846.41
  SIG_3 w4.5: v1(2254.19,3330.93) 2274.76,3310.36 2313.93,3310.36 2331.1,3327.53 2621.51,3327.53 2915.03,3621.04 2958.48,3621.04 3057.78,3720.34 3126.05,3720.34 3131.47,3725.76 3131.47,3815 v2(3115.81,3830.66)
  Bottom Layer w8: U11.9@2201.3,3322.34 2245.61,3322.34 v1(2254.19,3330.93)
LPM_TPS4HC120: R146.1 U49.4 U55.4 | length 3947.3
  Top Layer w8: U49.4@4836.2,4196.21 4881.76,4196.21 v1(4893.18,4184.8) ; U55.4@5189.58,3037.92 v1(5189.58,3204.74)
  SIG_1 w6: v5(4764.88,1195.65) 4802.86,1195.65 4887.37,1280.16 4887.37,1650.66 5209.05,1972.34 5209.05,2875.93 5218.4,2885.27 5218.4,3018.39 5189.58,3047.2 v1(5189.58,3204.74) 4871.78,3522.54 4871.78,3915.25 4990.68,4034.15 5058.47,4034.15 5109.96,4085.64 5109.96,4136.18 5061.34,4184.8 v1(4893.18,4184.8)
  Bottom Layer w8: R146.1@4747.44,1160.67 4750.1,1163.33 4750.1,1180.88 4762.22,1180.88 4764.88,1183.54 v5(4764.88,1195.65)
MCU_INTn: R327.2 U32.D14 U40.5 | length 2048.9
  Top Layer w8: U40.5@3261.32,2454.78 3280.84,2454.78 v1(3295.59,2440.03)
  Top Layer w9.9: v2(3147.31,4019.64) U32.D14@3163.06,4003.89
  SIG_1 w4.5: v2(3147.31,4019.64) 3162.68,4004.27 3162.68,3881.22 3194.8,3849.1 3194.8,3565.58 3169.27,3540.05 3120.76,3540.05 2854.71,3274 2854.71,2923.99 3295.59,2483.11 v1(3295.59,2440.03)
  Bottom Layer w8: R327.2@3261.32,2438.12 3293.68,2438.12 v1(3295.59,2440.03)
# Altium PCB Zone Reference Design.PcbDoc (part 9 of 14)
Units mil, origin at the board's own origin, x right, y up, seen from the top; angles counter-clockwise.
Board outline 8858.11 x 7047.08 mil, 16 copper layers (Top Layer, GND_1, SIG_1, GND_2, PWR/SIG_1, GND_3, PWR_1, PWR_2, GND_4, PWR/SIG_2, GND_5, SIG_2, GND_6, SIG_3, GND_7, Bottom Layer), stack 80.368 mil thick; 1131 components, 808 nets, 3825 pads, 3523 vias.
Unrouted connection lines stored in the file: 563.

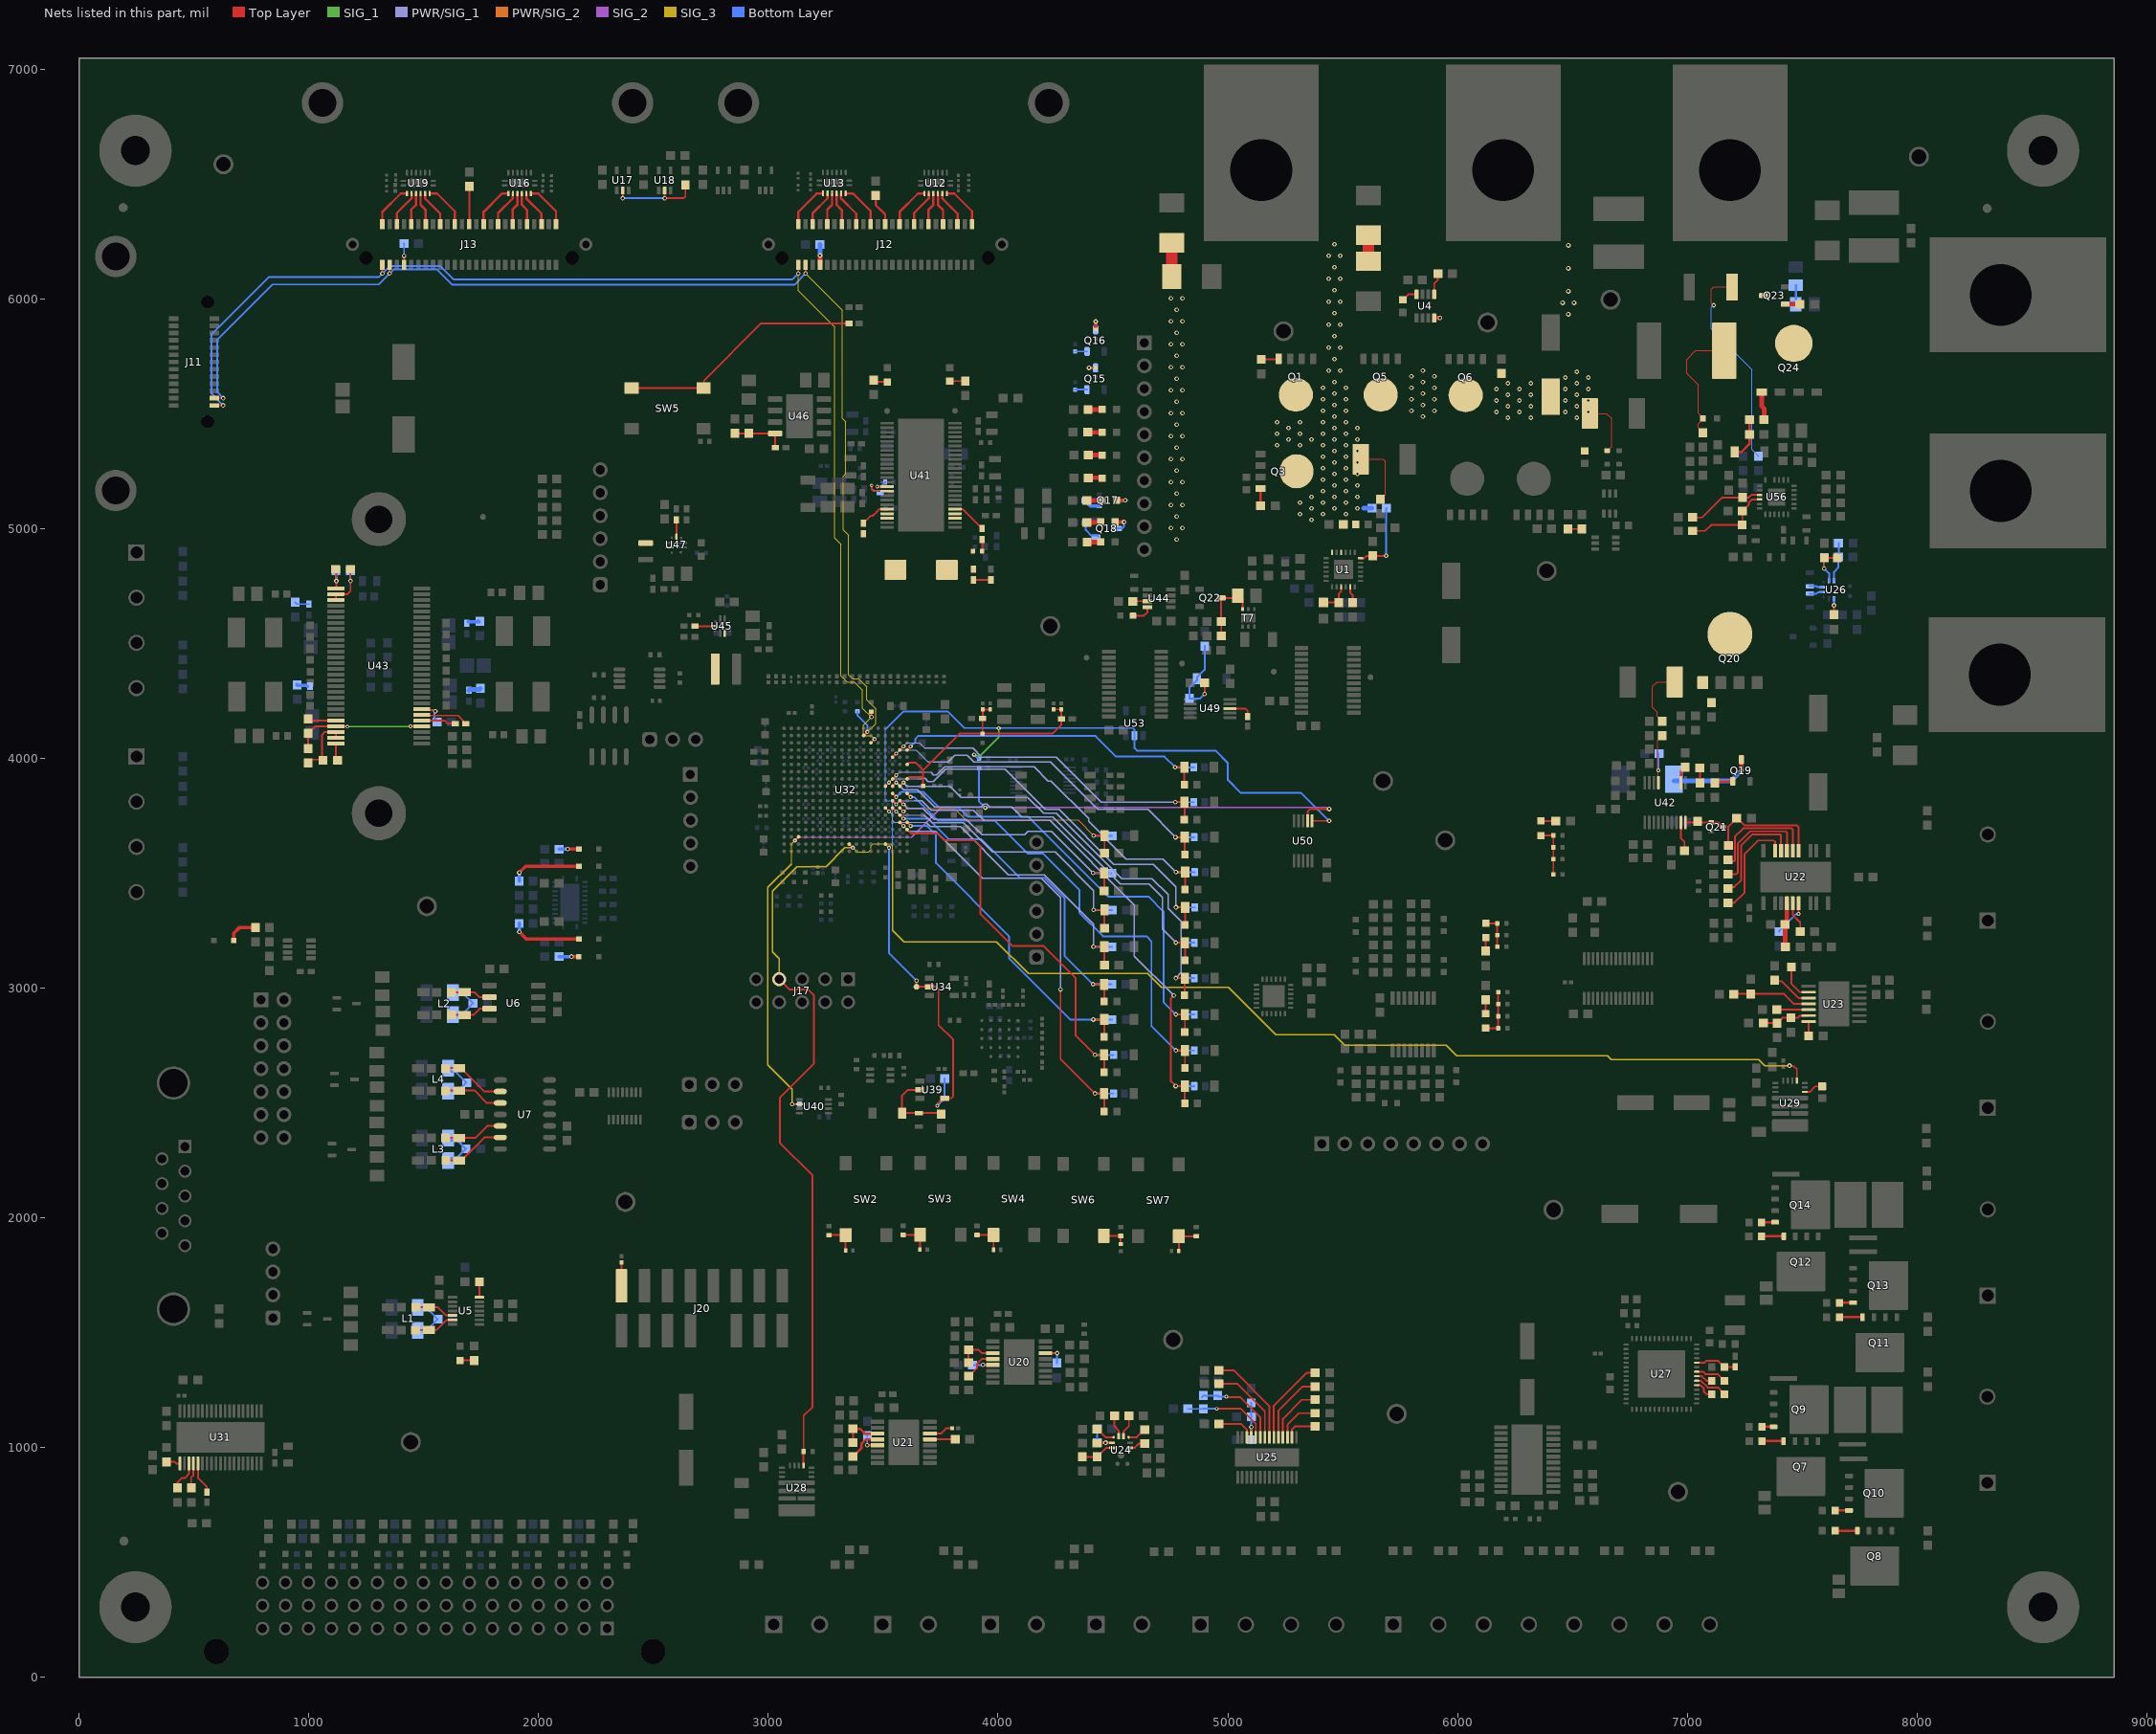
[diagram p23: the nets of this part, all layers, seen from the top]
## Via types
v1: diameter 20, hole 10, Top Layer to Bottom Layer, tented both sides, 2450 vias
v2: diameter 18, hole 8, Top Layer to Bottom Layer, tented both sides, 400 vias
v3: diameter 32, hole 16, Top Layer to Bottom Layer, tented both sides, 348 vias
v4: diameter 19.68, hole 7.87, Top Layer to Bottom Layer, tented both sides, 245 vias
v5: diameter 16, hole 8, Top Layer to Bottom Layer, tented both sides, 60 vias
v6: diameter 16, hole 8, Top Layer to Bottom Layer, 14 vias
v7: diameter 24.8, hole 12.99, Top Layer to Bottom Layer, tented both sides, 6 vias

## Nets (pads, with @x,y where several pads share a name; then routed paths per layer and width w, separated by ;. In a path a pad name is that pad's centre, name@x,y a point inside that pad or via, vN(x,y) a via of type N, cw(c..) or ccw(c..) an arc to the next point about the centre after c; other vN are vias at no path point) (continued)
MCU_PORz: R292.1 R477.1 TP7.1 U32.R2 U34.2 U39.4 U50.1 U53.2 | length 4576.5
  Top Layer w8: v1(3644.68,3031.39) TP7.1@3644.68,3004.52 3644.81,3004.66 U34.2@3700.6,3004.66 3729.2,3004.66 3740.85,2993 3740.85,2838.36 3804.67,2774.54 3804.67,2527.89 3795.74,2518.97 U39.4@3767.21,2518.97 3759.33,2518.97 3737.25,2496.89 3737.25,2488.87 v5(3735.72,2487.34) ; U50.1@5366.92,3726.74 5367.25,3727.07 v1(5441.19,3727.07)
  Top Layer w9.9: U32.R2@3509.51,3625.94 v2(3525.26,3610.19)
  SIG_1 w6: v2(3895.36,4014.96) 3897.65,4012.66 3905.08,4012.66 3908.47,4009.28 3921.03,4009.28 4003.16,4091.41 v2(4003.16,4130.42)
  Bottom Layer w5: 3509.49,4124.8 3509.49,3821.77 3516.45,3814.81 3534.07,3814.81 3541.22,3807.66 3541.22,3626.15 v2(3525.26,3610.19)
  Bottom Layer w8: 3509.49,4124.8 3587.54,4202.86 3782.33,4202.86 3854.01,4131.19 v2@4002.4,4131.19 ; v2(3525.26,3610.19) 3525.26,3150.8 v1(3644.68,3031.39) ; v5(3735.72,2487.34) 3767.63,2519.25 R477.1@3767.63,2606.32 ; v2(3895.36,4014.96) 3907.92,4002.39 3911.18,4002.39 3916.53,3997.04 R292.1@3916.53,3996.55 ; v2(4003.16,4130.42) v2@4002.4,4131.19 ; v1(5441.19,3727.07) 5440.79,3727.07 5319.36,3848.49 5056.89,3848.49 4999.71,3905.67 4999.71,3979.32 4946.47,4032.56 4604.33,4032.56 4593.79,4043.1 U53.2@4593.79,4098.55 4593.79,4123.65 4586.25,4131.19 v2@4002.4,4131.19
MCU_WARMRSTn: R293.1 R330.2 U32.C3 U40.2 U50.2 | length 4038.7
  Top Layer w8: v1(3103.27,2494.15) U40.2@3135.33,2494.15 ; U50.2@5347.24,3726.74 5347.24,3767.54 5358.39,3778.7 5440.89,3778.7 v1(5441.19,3778.4)
  Top Layer w9.9: v2(3115.81,3641.69) U32.C3@3131.56,3657.44
  SIG_3 w4.5: 3100.33,3539.5 3100.33,3626.2 v2(3115.81,3641.69)
  SIG_3 w6: 3100.33,3539.5 2997.85,3437.02 2997.85,2664.91 3103.27,2559.48 v1(3103.27,2494.15)
  SIG_2 w4.5: v2(3115.81,3641.69) 3131,3656.87 3623.93,3656.87
  SIG_2 w6: 3623.93,3656.87 3752.46,3785.4 3943.14,3785.4 v2(3944.59,3783.95) 3946.04,3785.4 5430.4,3785.4 5437.4,3778.4 v1(5441.19,3778.4)
  Bottom Layer w8: v1(3103.27,2494.15) R330.2@3135.33,2494.15 ; R293.1@3916.58,3955.93 3916.58,3811.97 v2(3944.59,3783.95) ; v1(5441.19,3778.4) v1@5441.33,3778.55
MDC_ETH: J11.24 J12.48 J13.48 R239.1 U32.M17 | length 5406.5
  Top Layer w8: J11.24@588.58,5566.8 v1(626.97,5566.8) ; v1(1351.32,6109.41) J13.48@1351.32,6147.8 ; v1(3161.98,6109.41) J12.48@3161.98,6147.8
  Top Layer w9.9: U32.M17@3415.03,4098.38 v2(3430.77,4114.13)
  SIG_3 w4.5: v1(3161.98,6109.41) 3322.39,5949 3322.39,5478.43 3335.82,5464.99 3335.82,5236.58 3326.05,5226.81 3326.05,4993.08 3348.86,4970.26 3348.86,4362.44 3366.13,4345.17 3393.3,4345.17 3427.43,4311.04 3427.43,4254.25 3466.89,4214.79 3466.89,4150.25 v2(3430.77,4114.13)
  Bottom Layer w8: v1(626.97,5566.8) 601.26,5592.51 601.26,5821.71 841.45,6061.9 1303.82,6061.9 v1(1351.32,6109.41) 1369.98,6128.06 1556.15,6128.06 1623.91,6060.3 3112.87,6060.3 v1(3161.98,6109.41) ; R239.1@3387.29,4203.01 3387.29,4186.62 3430.77,4143.14 v2(3430.77,4114.13)
MDIO_ETH: J11.26 J12.50 J13.50 R238.1 U32.N16 | length 5429.4
  Top Layer w8: J11.26@588.58,5535.31 v1(626.97,5535.31) ; v1(1319.83,6109.41) J13.50@1319.83,6147.8 ; v1(3130.48,6109.41) J12.50@3130.48,6147.8 ; v1(3448.47,4178.71) R238.1@3448.47,4202.87
  Top Layer w9.9: U32.N16@3446.52,4066.88 v2(3462.27,4082.63)
  SIG_3 w4.5: v1(3130.48,6109.41) 3130.48,6034.46 3289.43,5875.51 3289.43,4956.91 3315.62,4930.73 3315.62,4357.59 3341.91,4331.3 3374.09,4331.3 3410.16,4295.22 3410.16,4217.02 v1(3448.47,4178.71) 3413.71,4143.95 3413.71,4107.12 3422.59,4098.24 3446.66,4098.24 v2(3462.27,4082.63)
  Bottom Layer w8: v1(626.97,5535.31) 576.11,5586.17 576.11,5844.43 826.28,6094.6 1305.02,6094.6 v1(1319.83,6109.41) 1352.07,6141.65 1572,6141.65 1629.35,6084.3 3105.38,6084.3 v1(3130.48,6109.41)
nCS: J17.7 R167.2 U28.13 U29.13 U32.K2 | length 8020.6
  Top Layer w6: v1(7444.81,2661.27) 7461.39,2661.27 7476.81,2645.85 U29.13@7476.81,2596.27
  Top Layer w8: J17.7@3046.96,3037.36 3092.24,2992.08 3174.38,2992.08 3198.96,2967.51 3198.96,2670.34 3049.86,2521.24 3049.86,2325.1 3192.16,2182.8 3192.16,1176.62 3153.45,1137.91 R167.2@3153.45,982.48 3152.96,981.99 U28.13@3152.96,921.24
  Top Layer w9.9: U32.K2@3352.03,3625.94 v2(3367.78,3610.19)
  SIG_3 w4.5: v2(3367.78,3610.19) 3385.81,3592.17 3436.44,3592.17 3446.54,3602.27 3446.54,3617.67 3455.29,3626.43 3533.43,3626.43 3541.04,3618.82 3541.04,3590.28
  SIG_3 w6: J17.7@3046.96,3037.36 3046.96,3127.69 3018.53,3156.12 3018.53,3421.05 3125.13,3527.65 3250.51,3527.65 3333.05,3610.19 v2(3367.78,3610.19) ; 3541.04,3590.28 3541.04,3250.64 3591.11,3200.57 3993.76,3200.57 4131.6,3062.73 4649.91,3062.73 4711.08,3001.56 5003.58,3001.56 5209.04,2796.1 5463.47,2796.1 5509.55,2750.03 5950.72,2750.03 5996.95,2703.79 6653.06,2703.79 6668.09,2688.76 7310.62,2688.76 7338.11,2661.27 v1(7444.81,2661.27)
NetC5_2: C5.2 R17.2 | length 59.5
  Top Layer w8: R17.2@6480.43,4997.52 C5.2@6539.98,4997.52
NetC6_2: C6.2 C7.1 C11.1 C14.1 C15.1 Q1.5 Q3.5 Q5.5 Q6.5 R15.1 R16.2 R20.2 R30.1 R32.2 U1.22 U1.24 U4.8 | length 518.6
  Top Layer w5: 5617.08,5300.9 5674.93,5300.9 5685.64,5290.18 5685.64,5147.25 R16.2@5665,5126.61 ; 6614.68,5500.4 6648.51,5500.4 6670.06,5478.85 6670.06,5355.1 6653.36,5338.4 R32.2@6651.01,5338.4
  Top Layer w20: U4.8@5900.97,5916.05 v1(5923.73,5916.05)
  Bottom Layer w20: 5591.05,5088.43 R20.2@5627.73,5088.43
  other v1: 4777.4,4951.62 4752.4,5001.62 4802.4,5001.62 5364.18,5036.87 4777.4,5051.62 5314.18,5061.87 5414.18,5061.87 5514.18,5061.87 5364.18,5086.87 5464.18,5086.87 5564.18,5086.87 4752.4,5101.62 4802.4,5101.62 5314.18,5111.87 5414.18,5111.87 5514.18,5111.87 5364.18,5136.87 5464.18,5136.87 5564.18,5136.87 4777.4,5151.62 5414.18,5161.87 5514.18,5161.87 5464.18,5186.87 5564.18,5186.87 4752.4,5201.62 4802.4,5201.62 5414.18,5211.87 5514.18,5211.87 5464.18,5236.87 5564.18,5236.87 4777.4,5251.62 5414.18,5261.87 5514.18,5261.87 5464.18,5286.87 5564.18,5286.87 4752.4,5301.62 4802.4,5301.62 5414.18,5311.87 5514.18,5311.87 5464.18,5336.87 5564.18,5336.87 4777.4,5351.62 5214.18,5361.87 5314.18,5361.87 5414.18,5361.87 5514.18,5361.87 5264.18,5386.87 5364.18,5386.87 5464.18,5386.87 5564.18,5386.87 4752.4,5401.62 4802.4,5401.62 5214.18,5411.87 5314.18,5411.87 5414.18,5411.87 5514.18,5411.87 5264.18,5436.87 5464.18,5436.87 5564.18,5436.87 4777.4,5451.62 5214.18,5461.87 5314.18,5461.87 5414.18,5461.87 5514.18,5461.87 6219.18,5481.87 6319.18,5481.87 6519.18,5481.87 5464.18,5486.87 5849.18,5486.87 4752.4,5501.62 4802.4,5501.62 6169.18,5506.87 6269.18,5506.87 6469.18,5506.87 6569.18,5506.87 5414.18,5511.87 5514.18,5511.87 5799.18,5511.87 5899.18,5511.87 6219.18,5531.87 6319.18,5531.87 6519.18,5531.87 5464.18,5536.87 5849.18,5536.87 4777.4,5551.62 6169.18,5556.87 6269.18,5556.87 6469.18,5556.87 6569.18,5556.87 5414.18,5561.87 5514.18,5561.87 5799.18,5561.87 5899.18,5561.87 6219.18,5581.87 6319.18,5581.87 6519.18,5581.87 5464.18,5586.87 5849.18,5586.87 4752.4,5601.62 4802.4,5601.62 6169.18,5606.87 6269.18,5606.87 6469.18,5606.87 6569.18,5606.87 5414.18,5611.87 5514.18,5611.87 5799.18,5611.87 5899.18,5611.87 6219.18,5631.87 6319.18,5631.87 6519.18,5631.87 5464.18,5636.87 5849.18,5636.87 4777.4,5651.62 6469.18,5656.87 6569.18,5656.87 5799.18,5661.87 5899.18,5661.87 6519.18,5681.87 5439.18,5686.87 5489.18,5686.87 5849.18,5686.87 4752.4,5701.62 4802.4,5701.62 5464.18,5736.87 4777.4,5751.62 5439.18,5786.87 5489.18,5786.87 4752.4,5801.62 4802.4,5801.62 5464.18,5836.87 4777.4,5851.62 5439.18,5886.87 5489.18,5886.87 4752.4,5901.62 4802.4,5901.62 6482.19,5932.04 5464.18,5936.87 4777.4,5951.62 6457.19,5982.04 6507.19,5982.04 5439.18,5986.87 5489.18,5986.87 4752.4,6001.62 4802.4,6001.62 6482.19,6032.04 5464.18,6036.87 5439.18,6086.87 5489.18,6086.87 6482.19,6132.04 5464.18,6136.87 5439.18,6186.87 5489.18,6186.87 6482.19,6232.04 5464.18,6236.87
NetC9_1: C9.1 R20.1 U1.18 | length 324.2
  Top Layer w8: U1.18@5577.92,4870.09 5594.3,4870.09 5604.68,4880.48 C9.1@5630.4,4880.48 v1(5689.19,4880.48)
  Bottom Layer w8: v1(5689.19,4880.48) 5689.19,5086.9 R20.1@5690.73,5088.43
NetC10_1: C10.1 R31.1 U1.9 | length 140.7
  Top Layer w8: R31.1@5415.72,4677.27 5415.79,4677.34 C10.1@5483.73,4677.34 5483.73,4715.35 5493.27,4724.88 U1.9@5493.27,4746.07
NetC16_2: C16.2 U4.4 | length 68.9
  Top Layer w8: C16.2@5762.23,5995.07 5785.56,6018.41 U4.4@5821.47,6018.41
NetC20_2: C20.2 R37.1 R38.2 | length 216.6
  Bottom Layer w8: R37.1@1473.96,1509.09 1512.26,1509.09 C20.2@1560.83,1557.66 ; R38.2@1473.96,1609.88 1508.81,1609.88 1546.13,1572.56 1546.13,1572.37 C20.2@1560.83,1557.66 ; C20.2@1561.82,1557.66 C20.2@1560.83,1557.66
NetC25_2: C25.2 R43.1 R44.2 | length 215.6
  Bottom Layer w8: R43.1@1626.88,2882.81 1664.23,2882.81 1699.06,2917.64 1699.06,2918.63 C25.2@1713.76,2933.33 ; R44.2@1626.88,2980.01 1667.08,2980.01 C25.2@1713.76,2933.33 ; C25.2@1714.74,2933.33 C25.2@1713.76,2933.33
NetC29_2: C29.2 R47.1 R48.2 | length 195.8
  Bottom Layer w10: R47.1@1606.11,2247.97 1616.94,2258.8 1641.78,2258.8 C29.2@1682.99,2300 ; R48.2@1606.11,2347.15 1616.94,2336.33 1646.66,2336.33 C29.2@1682.99,2300 ; C29.2@1683.97,2300 C29.2@1682.99,2300
NetC34_2: C34.2 R51.1 R52.2 | length 202.9
  Bottom Layer w8: R51.1@1604.91,2551.94 R51.1@1606.11,2550.73 1648.59,2550.73 C34.2@1685.52,2587.67 ; R52.2@1606.11,2650.7 1622.65,2634.17 1639.02,2634.17 C34.2@1685.52,2587.67 ; C34.2@1686.5,2587.67 C34.2@1685.52,2587.67
NetC58_1: C58.1 R80.2 U20.3 | length 169.1
  Top Layer w8: R80.2@3871.77,1368.24 C58.1@3871.77,1425.27 3913.93,1425.27 3929.26,1409.94 U20.3@3977.5,1409.94
NetC64_1: C64.1 R92.2 U21.3 | length 174.6
  Top Layer w10: R92.2@3368.82,1019.87 C64.1@3368.82,1080.12 3400.31,1080.12 3420.51,1059.93 U21.3@3474.84,1059.93
NetC71_1: C71.1 R100.2 U22.4 | length 196
  Top Layer w20: R100.2@7426.41,3179.16 C71.1@7426.41,3275.44 ; C71.1@7433.63,3268.75 U22.4@7433.63,3368.52
NetC83_1: C83.1 R111.2 R114.2 U24.9 | length 171.6
  Top Layer w8: R114.2@4430.48,1017.49 4433.05,1020.06 v1(4468.01,1020.06) U24.9@4502.97,1020.06
  Bottom Layer w8: R111.2@4432.11,1081.58 4431.68,1081.16 C83.1@4431.68,1020.06 v1(4468.01,1020.06)
NetC84_1: C84.1 R124.1 R127.2 U23.6 | length 211.5
  Top Layer w8: R124.1@7330.54,2846.53 C84.1@7390.54,2846.53 7413.96,2869.95 R127.2@7451.54,2869.95 7452.02,2869.47 7480.55,2869.47 7490.28,2879.19 U23.6@7528.12,2879.19
NetC92_1: C92.1 R128.2 R131.2 U26.9 | length 218.1
  Top Layer w8: v1(7595.95,4825.02) C92.1@7595.95,4871.45 R128.2@7653.99,4871.45
  Bottom Layer w8: R131.2@7595.95,4873.54 v1(7595.95,4825.02) 7616.96,4804.01 U26.9@7616.96,4768.63
NetC95_1: C95.1 R147.1 R148.2 U25.11 | length 205.3
  Top Layer w8: U25.11@5102.01,1043.03 v1(5102.01,1088.67)
  Bottom Layer w8: R148.2@5102.01,1033.79 v1(5102.01,1088.67) C95.1@5102.01,1133.5 R147.1@5102.01,1193.5
NetC101_1: C101.1 R153.2 U27.38 | length 182.2
  Top Layer w8: U27.38@7040.98,1368.71 7075.29,1368.71 7083.11,1376.53 7134.17,1376.53 C101.1@7161.62,1349.08 7206.98,1349.08 R153.2@7208.08,1350.18
NetC102_1: C102.1 U27.36 | length 137.1
  Top Layer w8: U27.36@7040.98,1329.34 7068.33,1329.34 7078.61,1319.06 7132.04,1319.06 C102.1@7161.62,1289.48
NetC102_2: C102.2 U27.35 | length 73.9
  Top Layer w8: U27.35@7040.98,1309.65 7063.17,1309.65 7083.34,1289.48 C102.2@7106.5,1289.48
NetC103_1: C103.1 U27.34 | length 144.7
  Top Layer w8: U27.34@7040.98,1289.97 7059.12,1289.97 7088.81,1260.28 7133.14,1260.28 C103.1@7161.62,1231.8
NetC103_2: C103.2 U27.33 | length 89.1
  Top Layer w8: U27.33@7040.98,1270.28 7057.97,1270.28 7072,1256.25 7072,1243.17 7083.37,1231.8 C103.2@7106.5,1231.8
NetC117_1: C117.1 U29.10 | length 85.3
  Top Layer w8: U29.10@7511.26,2547.06 7532.93,2547.06 7557.06,2571.19 C117.1@7586.55,2571.19
NetC145_2: C145.2 U31.20 | length 62
  Top Layer w8: C145.2@379.37,936.76 416.46,936.76 423.47,929.75 U31.20@438.43,929.75
NetC147_2: C147.2 U31.23 | length 110.6
  Top Layer w8: C147.2@487.64,823.26 487.64,868.7 497.49,878.55 U31.23@497.49,929.75
NetC148_2: C148.2 U31.22 | length 134.9
  Top Layer w8: C148.2@428.59,823.26 428.59,848.8 446.17,866.39 459.91,866.39 477.8,884.28 U31.22@477.8,929.75
NetC228_1: C228.1 D21.1 R294.2 U32.V15 | length 1452.4
  Top Layer w8: v1(4770.63,3960.51) 4810.09,3960.51 D21.1@4810.55,3960.06 4810.55,3884.33 R294.2@4810.83,3884.05
  Top Layer w9.9: U32.V15@3604,4035.39 v2(3619.75,4051.14)
  Bottom Layer w8: v2(3619.75,4051.14) 3639.95,4071.34 3639.95,4083.9 3652.06,4096.01 4424.44,4096.01 4513.95,4006.5 4724.64,4006.5 v1(4770.63,3960.51) 4771.09,3960.06 C228.1@4851.39,3960.06
NetC229_1: C229.1 D22.1 R296.2 U32.U15 | length 1516.4
  Top Layer w8: v1(4771.5,3808.69) 4810.96,3808.69 D22.1@4811.41,3808.23 4811.41,3733.39 R296.2@4810.25,3732.23
  Top Layer w9.9: U32.U15@3572.51,4035.39 v2(3588.25,4051.14)
  PWR/SIG_1 w4.5: v2(3588.25,4051.14) 3603.85,4066.73 3657.32,4066.73 3680.88,4043.17
  PWR/SIG_1 w6: 3680.88,4043.17 3889.69,4043.17 3928.43,4004.42 4253.49,4004.42 4449.22,3808.69 v1(4771.5,3808.69)
  Bottom Layer w8: v1(4771.5,3808.69) 4771.95,3808.23 C229.1@4852.26,3808.23
NetC230_1: C230.1 C231.1 C232.1 C233.1 C234.1 C235.1 R297.2 R299.2 U32.V11 U32.V13 | length 1152.7
  Top Layer w8: U32.V11@3604,3909.4 3612.65,3918.05 3673.58,3918.05 ; U32.V13@3604,3972.4 3612.32,3980.72 3633.48,3980.72 3641.34,3980.72 3673.58,3948.47 ; R297.2@3673.58,3878.61 3673.58,3918.05 ; C234.1@3965.6,4212.1 C235.1@3932.51,4212.1 3932.51,4172.23 C233.1@3932.41,4172.12 R299.2@3932.41,4106.65 ; C231.1@4240.94,4212.41 C232.1@4275.6,4212.41 C230.1@4275.6,4170.98 4275.6,4146.25 4236,4106.65 4100.27,4106.65 R299.2@3932.41,4106.65 ; 3673.58,3918.05 3673.58,3948.47 ; 3673.58,3948.47 3831.75,4106.65 R299.2@3932.41,4106.65
NetC236_1: C236.1 D23.1 R298.2 U32.T14 | length 1623.2
  Top Layer w8: v1(4772.33,3655.73) 4811.79,3655.73 D23.1@4812.25,3655.28 4812.25,3579.85 R298.2@4812.83,3579.27
  Top Layer w9.9: U32.T14@3541.01,4003.89 v2(3556.76,4019.64)
  PWR/SIG_1 w4.5: v2(3556.76,4019.64) 3572.44,4035.33 3633.48,4035.33 3642.61,4035.33 3695.66,3982.28
  PWR/SIG_1 w6: 3695.66,3982.28 3782.36,3982.28 3811.67,4011.58 3865.85,4011.58 3895.15,3982.28 4227.34,3982.28 4433.51,3776.1 4651.96,3776.1 v1(4772.33,3655.73)
  Bottom Layer w8: v1(4772.33,3655.73) 4772.79,3655.28 C236.1@4853.09,3655.28
NetC237_1: C237.1 D25.1 R301.2 U32.U7 | length 1110.2
  Top Layer w8: v1(4415.84,3662.72) 4463.17,3662.72 D25.1@4463.63,3662.27 4463.37,3662.01 R301.2@4463.37,3586.21
  Top Layer w9.9: U32.U7@3572.51,3783.42 v2(3588.25,3767.67)
  PWR/SIG_2 w4.5: v2(3588.25,3767.67) 3602.49,3781.91 3808.72,3781.91 3860.26,3730.37 4348.19,3730.37 v1(4415.84,3662.72)
  Bottom Layer w8: v1(4415.84,3662.72) 4416.29,3662.27 C237.1@4496.6,3662.27
NetC238_1: C238.1 D24.1 R300.2 U32.T11 | length 1661.3
  Top Layer w8: v1(4774.55,3503.94) 4814.01,3503.94 D24.1@4814.46,3503.48 4814.46,3427.74 R300.2@4814.2,3427.48
  Top Layer w9.9: U32.T11@3541.01,3909.4 v2(3556.76,3925.15)
  PWR/SIG_1 w4.5: v2(3556.76,3925.15) 3571.55,3939.94 3704.47,3939.94
  PWR/SIG_1 w6: 3704.47,3939.94 3704.98,3939.94 3708.5,3936.43 3708.5,3936.37 3718.42,3926.45 3732.45,3926.45 3768.41,3962.41 4156.75,3962.41 4218.33,3900.82 4231.17,3900.82 4394.57,3737.43 4394.57,3724.61 4557.97,3561.22 4717.27,3561.22 v1(4774.55,3503.94)
  Bottom Layer w8: v1(4774.55,3503.94) 4775,3503.48 C238.1@4855.31,3503.48
NetC239_1: C239.1 D27.1 R303.2 U32.U8 | length 1191
  Top Layer w8: v1(4413.64,3500.21) 4460.98,3500.21 D27.1@4461.43,3499.75 4461.52,3499.66 R303.2@4461.52,3421.36
  Top Layer w9.9: U32.U8@3572.51,3814.92 v2(3588.25,3799.17)
  PWR/SIG_1 w6: v2(3588.25,3799.17) 3605.18,3782.24 3672.37,3782.24 3721.05,3733.56 3862.53,3733.56 3930.03,3666.06 4115.57,3666.06 4130.26,3680.75 4233.1,3680.75 v1(4413.64,3500.21)
  Bottom Layer w8: v1(4413.64,3500.21) 4414.1,3499.75 C239.1@4494.4,3499.75
NetC240_1: C240.1 D26.1 R302.2 U32.R10 | length 1806.4
  Top Layer w8: v1(4774.52,3350.59) 4813.98,3350.59 D26.1@4814.44,3350.13 4814.44,3275.59 R302.2@4812.98,3274.13
  Top Layer w9.9: U32.R10@3509.51,3877.91 v2(3525.26,3893.66)
  PWR/SIG_1 w4.5: v2(3525.26,3893.66) 3541.08,3909.47 3674.54,3909.47
  PWR/SIG_1 w6: 3674.54,3909.47 3676.79,3911.72 3681.76,3911.72 3695.13,3898.36 3718.42,3898.36 3772.53,3952.47 4029.35,3952.47 4205.56,3776.27 4265.6,3776.27 4503.55,3538.32 4676.33,3538.32 4774.52,3440.12 v1(4774.52,3350.59)
  Bottom Layer w8: v1(4774.52,3350.59) 4774.98,3350.13 C240.1@4855.28,3350.13
NetC241_1: C241.1 D29.1 R305.2 U32.T7 | length 1315.5
  Top Layer w8: v1(4415.65,3339.75) 4462.12,3339.75 4463.01,3338.87 R305.2@4463.01,3259.76
  Top Layer w9.9: U32.T7@3541.01,3783.42 v2(3556.76,3767.67)
  PWR/SIG_1 w4.5: v2(3556.76,3767.67) 3572.22,3752.21 3678.71,3752.21
  PWR/SIG_1 w6: 3678.71,3752.21 3713,3717.93 3849.21,3717.93 3976.06,3591.07 4248.54,3591.07 4415.65,3423.96 v1(4415.65,3339.75)
  Bottom Layer w8: v1(4415.65,3339.75) 4416.11,3339.3 C241.1@4496.42,3339.3
NetC242_1: C242.1 D28.1 R304.2 U32.T10 | length 1816.1
  Top Layer w8: v1(4773.7,3197.08) 4813.16,3197.08 D28.1@4813.62,3196.62 4813.62,3121.64 R304.2@4812.59,3120.62
  Top Layer w9.9: U32.T10@3541.01,3877.91 v2(3556.76,3893.66)
  PWR/SIG_1 w6: v2(3556.76,3893.66) 3588.38,3862.04 3649.68,3862.04 3724.47,3787.25 3925.35,3787.25 3937.99,3799.89 3951.19,3799.89 3963.83,3787.25 4059.96,3787.25 4102.94,3744.27 4238.8,3744.27 4531.2,3451.87 4656.13,3451.87 4714.96,3393.04 4714.96,3255.81 v1(4773.7,3197.08)
  Bottom Layer w8: v1(4773.7,3197.08) 4774.15,3196.62 C242.1@4854.46,3196.62
NetC243_1: C243.1 D31.1 R307.2 U32.R7 | length 1436.3
  Top Layer w8: v1(4414.89,3179.28) 4462.23,3179.28 D31.1@4462.68,3178.83 4462.68,3099.12 R307.2@4462.84,3098.97
  Top Layer w9.9: U32.R7@3509.51,3783.42 v2(3525.26,3767.67)
  PWR/SIG_1 w4.5: v2(3525.26,3767.67) 3540.99,3751.95 3540.99,3727.86 3547.28,3721.56 3686.58,3721.56
  PWR/SIG_1 w6: 3686.58,3721.56 3705.85,3702.29 3836.01,3702.29 4045.68,3492.62 4200.1,3492.62 4414.89,3277.83 v1(4414.89,3179.28)
  Bottom Layer w8: v1(4414.89,3179.28) 4415.34,3178.83 C243.1@4495.65,3178.83
NetC244_1: C244.1 D30.1 R306.2 U32.U10 | length 1965.6
  Top Layer w8: v1(4773.48,3042.47) 4809.45,3042.47 4811.65,3040.27 R306.2@4811.65,2967.15
  Top Layer w9.9: U32.U10@3572.51,3877.91 v2(3588.25,3893.66)
  PWR/SIG_1 w6: v2(3588.25,3893.66) 3604.06,3877.85 3789.98,3877.85 3838.42,3829.4 4128.82,3829.4 4197.96,3760.27 4253.58,3760.27 4538.4,3475.45 4669.69,3475.45 4739.74,3405.4 4739.74,3346.5 4797.05,3289.18 4797.05,3066.04 v1(4773.48,3042.47)
  Bottom Layer w8: v1(4773.48,3042.47) 4773.94,3042.02 C244.1@4854.25,3042.02
NetC245_2: C245.2 D33.1 R309.2 U32.U6 | length 1497.6
  Top Layer w8: v1(4413.83,3015.75) 4461.02,3015.75 4461.55,3015.23 R309.2@4461.55,2939.88
  Top Layer w9.9: U32.U6@3572.51,3751.92 v2(3588.25,3736.18)
  Bottom Layer w8: v2(3588.25,3736.18) 3697.91,3736.18 3787.3,3646.78 3928.29,3646.78 4095.77,3479.31 4201.36,3479.31 4289.23,3391.44 4289.23,3140.35 v1(4413.83,3015.75) 4414.29,3015.3 C245.2@4494.59,3015.3
NetC246_1: C246.1 D32.1 R308.2 U32.T9 | length 2078.2
  Top Layer w8: v1(4773.36,2884.47) 4812.83,2884.47 D32.1@4813.28,2884.01 4813.28,2808.53 R308.2@4812.3,2807.55
  Top Layer w9.9: U32.T9@3541.01,3846.41 v2(3556.76,3830.66)
  Bottom Layer w8: v2(3556.76,3830.66) 3578.89,3852.79 3633.48,3852.79 3675.6,3852.79 3746.37,3782.02 3831.62,3782.02 3868.59,3745.05 4130.91,3745.05 4478.44,3397.52 4654.97,3397.52 4720.26,3332.23 4720.26,2937.57 v1(4773.36,2884.47) 4773.82,2884.01 C246.1@4854.13,2884.01
NetC249_2: C249.2 D34.1 R311.2 U32.V5 | length 1497
  Top Layer w8: v1(4414.49,2862.23) 4460.53,2862.23 4461.63,2861.12 R311.2@4461.63,2787.35
  Top Layer w9.9: U32.V5@3604,3720.43 v2(3619.75,3704.68)
  Bottom Layer w8: v2(3619.75,3704.68) 3691.18,3704.68 3729.29,3666.57 3729.29,3543.19 4047.8,3224.67 4047.8,3128.41 4313.99,2862.23 v1(4414.49,2862.23) 4414.94,2861.77 C249.2@4495.25,2861.77
NetC250_1: C250.1 D35.1 R312.2 U32.V9 | length 2104.4
  Top Layer w8: v1(4773.37,2727.96) 4812.83,2727.96 D35.1@4813.28,2727.51 4813.28,2651.19 R312.2@4813.04,2650.95
  Top Layer w9.9: U32.V9@3604,3846.41 v2(3619.75,3830.66)
  Bottom Layer w8: v2(3619.75,3830.66) 3633.48,3830.66 3635.01,3830.66 3737.52,3728.15 3984.68,3728.15 4128.34,3584.49 4194.76,3584.49 4354.86,3424.39 4354.86,3325.61 4456.2,3224.27 4646.1,3224.27 4667.39,3202.98 4667.39,2833.94 v1(4773.37,2727.96) 4773.82,2727.51 C250.1@4854.13,2727.51
NetC251_1: C251.1 D36.1 R313.2 U32.V4 | length 1740.9
  Top Layer w8: U32.V4@3604,3688.93 3620.23,3672.7 3735.81,3672.7 3765.94,3642.56 3897.55,3642.56 3922.17,3617.94 3922.17,3322.04 4062.65,3181.56 4198.85,3181.56 4336.75,3043.67 4336.75,2793.86 v1(4422.12,2708.49) 4422.57,2708.04 D36.1@4462.04,2708.04 D36.1@4462.04,2708.04 R313.2@4461.98,2632.12
  Bottom Layer w8: v1(4422.12,2708.49) 4422.57,2708.04 C251.1@4502.88,2708.04
NetC252_1: C252.1 D37.1 R314.2 U32.T8 | length 2323.6
  Top Layer w8: v1(4764.97,2967.07) 4752.48,2954.59 4752.48,2593.2 4773.03,2572.65 4808.36,2572.65 4810.78,2570.23 4812.55,2572.01 R314.2@4812.55,2496.98
  Top Layer w9.9: U32.T8@3541.01,3814.92 v2(3556.76,3799.17)
  PWR/SIG_1 w4.5: v2(3556.76,3799.17) 3572.58,3814.99 3633.48,3814.99
  PWR/SIG_1 w6: 3633.48,3814.99 3668.55,3814.99 3710.14,3773.39 3892.75,3773.39 3937.87,3728.27 4225.68,3728.27 4593.42,3360.52 4593.42,3138.62 v1(4764.97,2967.07)
  Bottom Layer w8: v1@4773.03,2572.65 4773.49,2572.2 C252.1@4853.8,2572.2
  other v1: 4773.26,2572.43
NetC253_1: C253.1 D38.1 R315.2 U32.U5 | length 1948.9
  Top Layer w8: v1(4271.69,2993.13) 4271.69,2690.8 v1(4422.12,2540.37) 4461.58,2540.37 D38.1@4462.04,2539.91 R315.2@4462.04,2461.83
  Top Layer w9.9: U32.U5@3572.51,3720.43 v2(3588.25,3704.68)
  PWR/SIG_1 w4.5: v2(3588.25,3704.68) 3611.79,3681.14
  PWR/SIG_1 w6: 3611.79,3681.14 3729.01,3681.14 3933.26,3476.9 4187.84,3476.9 4271.69,3393.05 v1(4271.69,2993.13)
  Bottom Layer w8: v1(4422.12,2540.37) 4422.57,2539.91 C253.1@4502.88,2539.91
NetC256_1: C256.1 R320.2 SW2.4 | length 139.4
  Top Layer w8: R320.2@3263.73,1923.82 3263.9,1923.65 SW2.4@3336.17,1923.65 3336.28,1923.53 C256.1@3336.28,1856.84
NetC259_1: C259.1 R326.2 SW3.4 | length 137.7
  Top Layer w8: R326.2@3587.16,1924.87 R326.2@3587.16,1924.87 SW3.4@3660.19,1924.93 3660.19,1860.73 C259.1@3659.88,1860.42
NetC260_1: C260.1 R328.2 SW4.4 | length 136.1
  Top Layer w8: R328.2@3908.43,1924.45 SW4.4@3980.02,1924.49 3980.26,1924.17 C260.1@3980.26,1860.02
NetC277_1: C277.1 R331.2 | length 76
  Top Layer w8: R331.2@3893.1,4775.73 3968.96,4775.73 C277.1@3969.04,4775.65
NetC278_1: C278.1 L6.2 U41.45 U41.46
NetC278_2: C278.2 U41.44 | length 130
  Top Layer w8: C278.2@3413.69,5023.25 3445.15,5054.71 3452.74,5054.71 3457.13,5059.1 3460.19,5059.1 3471.32,5070.23 3471.32,5073.29 3481.47,5083.44 U41.44@3516.97,5083.44
NetC279_1: C279.1 R332.2 | length 50.6
  Top Layer w8: R332.2@3930.42,4901.1 C279.1@3930.44,4951.65
NetC279_2: C279.2 U41.5 | length 153.5
  Top Layer w8: U41.5@3812.24,5083.44 3812.38,5083.31 3846.55,5083.31 3930.44,4999.42 C279.2@3930.44,4998.89
NetC293_1: C293.1 U41.39 | length 87.3
  Top Layer w8: v5(3473.87,5181.92) 3516.92,5181.92 U41.39@3516.97,5181.87
  Bottom Layer w8: v5(3473.87,5181.92) 3491.01,5181.92 3508.21,5199.12 C293.1@3508.21,5201.84
NetC295_2: C295.2 U41.40 | length 156.4
  Top Layer w8: v5(3449.35,5187.08) 3449.35,5171.02 3458.18,5162.18 U41.40@3516.97,5162.18
  Bottom Layer w8: v5(3449.35,5187.08) 3449.35,5173.4 3460.76,5161.99 3492.02,5161.99 C295.2@3497.68,5156.33
NetC302_1: C302.1 R346.2 SW6.3 | length 108.5
  Top Layer w8: SW6.3@4460.32,1920.57 4461.01,1919.88 R346.2@4533.71,1919.88 4534.02,1919.57 4534.02,1885.61 C302.1@4534.33,1885.3
NetC303_1: C303.1 R347.2 SW7.3 | length 140.2
  Top Layer w8: C303.1@4786.66,1854.75 4786.66,1918.95 4786.78,1919.11 R347.2@4862.6,1919.11
NetC304_2: C304.2 R369.2 | length 60.3
  Top Layer w10: C304.2@7054.81,3957.92 7055.19,3957.54 R369.2@7055.19,3897.78
NetC308_2: C308.2 U42.12 | length 74.4
  Top Layer w10: U42.12@6972.4,3892.95 6972.4,3942.59 C308.2@6989.92,3960.12
NetC309_1: C309.1 U42.9 | length 128.2
  Top Layer w8: U42.9@6972.4,3719.72 6972.4,3649.89 6987.64,3634.65 C309.1@6987.64,3597.83
NetC328_1: C328.1 C332.2 U43.54 U43.55 | length 266.6
  Top Layer w8: C332.2@988.99,3985.37 C332.2@989.84,3984.52 ; C332.2@994.19,3993.64 C328.1@1055.08,3993.64 ; C328.1@1070.62,3993.06 1057.18,4006.5 1057.18,4101.74 1069.06,4113.62 1117.5,4113.62 U43.55@1117.5,4088.62
NetC328_2: C328.2 U43.56 | length 70.2
  Top Layer w8: U43.56@1117.5,4063.62 1117.5,3994.21 C328.2@1118.07,3993.64
NetC332_1: C332.1 C334.1 U43.4 U43.53 | length 575.6
  Top Layer w8: C334.1@997.26,4108.56 1005.9,4117.2 1005.9,4118.18 1011.96,4124.24 1013.93,4124.24 1027.82,4138.14 1117.02,4138.14 1117.38,4138.49 1118.05,4137.82 1166.29,4137.82 v5(1167.07,4137.04) ; C332.1@997.42,4041.68 C334.1@997.42,4108.53 ; v5(1441.77,4139.06) 1442,4138.83 1491.23,4138.83 U43.4@1491.46,4138.6
  SIG_1 w6: v5(1167.07,4137.04) 1168.08,4138.05 1440.76,4138.05 v5(1441.77,4139.06)
NetC333_2: C333.2 R386.1 | length 54.8
  Bottom Layer w20: C333.2@1696.53,4294.82 1696.53,4296.43 1698.34,4298.24 1741.82,4298.24 R386.1@1746.9,4303.32
NetC334_2: C334.2 U43.52 | length 123.9
  Top Layer w8: C334.2@993.58,4163.62 U43.52@1117.5,4163.62
NetC335_1: C335.1 U43.7 | length 170.8
  Top Layer w8: U43.7@1491.46,4213.6 1495.07,4209.99 1540.86,4209.99 1547.06,4203.79 v1(1550.31,4203.79)
  Bottom Layer w8: C335.1@1547.19,4163.85 C335.1@1547.19,4175.47 ; v1(1550.31,4203.79) 1550.31,4200.54 1547.19,4203.67 v1@1547.19,4200.54 ; C335.1@1558.81,4163.85 C335.1@1547.19,4175.47 ; C335.1@1547.19,4175.47 v1@1547.19,4200.54 ; v1@1547.19,4200.54 1547.19,4178.55 v1@1547.19,4200.54
NetC337_1: C337.1 U43.6 | length 208.1
  Top Layer w8: U43.6@1491.46,4188.6 1494.75,4185.31 1648.79,4185.31 C337.1@1683.73,4150.37
NetC337_2: C337.2 U43.5 | length 150.5
  Top Layer w8: U43.5@1491.46,4163.6 1590.41,4163.62 1603.66,4150.37 C337.2@1636.48,4150.37
NetC343_2: C343.2 R389.1 | length 52.8
  Bottom Layer w15: C343.2@1692.88,4593.62 1741,4593.62 R389.1@1737.72,4596.9
NetC350_1: C350.1 C351.1 U43.29 | length 122
  Top Layer w8: U43.29@1117.5,4738.62 1119.72,4740.84 1119.72,4812.42 C350.1@1117.64,4814.51
  Bottom Layer w8: C351.1@1117.64,4814.51 1119.72,4812.42 v1(1119.72,4771.04)
NetC350_2: C350.2 C351.2 U43.30 U43.31 | length 225.4
  Top Layer w8: U43.31@1117.5,4688.62 1117.5,4713.62 1167.76,4713.62 1181.01,4726.87 1181.01,4814.12 C350.2@1180.63,4814.51
  Bottom Layer w8: C351.2@1180.63,4814.51 1181.01,4814.12 v1(1181.01,4771.04)
NetC352_2: C352.2 R396.1 | length 47.7
  Bottom Layer w15: R396.1@948.98,4319.38 952.61,4315.75 990.01,4315.75 C352.2@993.65,4312.11
NetC357_2: C357.2 R397.1 | length 63.1
  Bottom Layer w8: R397.1@940.47,4678.09 947.96,4670.6 C357.2@1000.51,4670.64
NetC359_1: C359.1 Q22.3 R398.2 R402.2 T7.6 | length 305.4
  Top Layer w8: R398.2@4971.57,4532.77 R402.2@4971.57,4594.06 4971.34,4594.29 Q22.3@4971.34,4697.12 5064.06,4697.12 5064.22,4696.95 T7.6@5064.22,4649.02
NetC361_1: C361.1 U44.7 | length 63.6
  Top Layer w8: C361.1@4586.74,4682.35 4587.25,4682.87 U44.7@4650.12,4682.87
NetC362_2: C362.2 U44.8 | length 91.2
  Top Layer w8: C362.2@4587.19,4619.82 4634.4,4619.82 4650.12,4635.54 U44.8@4650.12,4657.28
NetC363_2: C363.2 R407.1 R408.2 U46.4 | length 236.2
  Top Layer w8: R407.1@2854.41,5413.4 2854.81,5413.01 U46.4@3029.21,5413.01 3029.21,5352.45 R408.2@3029.66,5351.99
NetC369_1: C369.1 U45.8 | length 82.4
  Top Layer w8: C369.1@2680.71,4574.25 U45.8@2763.09,4574.25
NetC372_1: C372.1 U47.8 | length 72.5
  Top Layer w8: U47.8@2599.81,4964.4 2599.81,5036.84 C372.1@2599.87,5036.89
NetC389_1: C389.1 R456.1 | length 83.1
  Bottom Layer w10: R456.1@7472.6,5975.41 C389.1@7472.6,6058.46
NetC391_1: C391.1 C392.1 R458.1 U56.22 | length 395
  Top Layer w8: R458.1@7023.02,4989.19 7078.05,4989.19 7104.03,5015.17 C391.1@7239.26,5015.17 ; C391.1@7238.06,5010.01 7239.79,5011.74 C392.1@7239.79,5074.75 7240.78,5074.75 7255.48,5089.45 7255.48,5091.14 7268.13,5103.79 7268.13,5113.14 7281.22,5126.23 U56.22@7314.55,5126.23
NetC396_2: C396.2 R465.1 U56.21 | length 332.2
  Top Layer w8: R465.1@7023.02,5047.62 7065.7,5047.62 7152.19,5134.11 7203.71,5134.11 C396.2@7240.43,5134.11 7267.4,5134.11 7279.21,5145.92 U56.21@7314.55,5145.92
NetC405_2: C405.2 R372.1 U42.17 | length 286
  Top Layer w5: U42.17@6873.97,3892.95 6873.7,3893.23 v5(6873.7,3947.21) 6871.84,3949.07 6871.84,4077.6 6890.9,4096.65 R372.1@6890.9,4097.64
  Bottom Layer w8: v5(6873.7,3947.21) C405.2@6873.7,4019.76
NetD1_1: D1.1 R4.1 R7.1 R8.1 R10.1 | length 223.2
  Top Layer w8: D1.1@6363,3663.31 6363.08,3663.38 R4.1@6417.06,3663.38 R10.1@6417.06,3560.18 R8.1@6417.06,3494.26
NetD1_2: D1.2 R1.1 | length 65.7
  Top Layer w8: D1.2@6363,3726.31 6363.93,3725.38 R1.1@6428.29,3725.38
NetD2_1: D2.1 R5.1 R11.1 R13.1 R14.1 | length 209.8
  Top Layer w8: D2.1@6122.29,2824.91 6122.43,2825.05 6176.72,2825.05 6176.72,2876.84 6176.72,2928.62 R14.1@6176.72,2980.41
NetD2_2: D2.2 R2.1 | length 59.9
  Top Layer w8: D2.2@6122.29,2887.9 6122.29,2947.27 R2.1@6122.67,2947.65
NetD3_1: D3.1 R6.1 R9.1 R12.1 | length 152.1
  Top Layer w8: D3.1@6122.86,3280.99 6123.85,3280 6124.59,3280.74 R9.1@6172.34,3280.74 R6.1@6172.34,3229.39 R12.1@6172.34,3178.83
NetD3_2: D3.2 R3.1 | length 58.4
  Top Layer w8: R3.1@6122.39,3159.76 6122.86,3160.23 D3.2@6122.86,3218
NetD4_2: D4.2 D5.2 | length 147.1
  Top Layer w50: D4.2@4756.12,6095.71 D5.2@4756.12,6242.83
NetD6_2: D6.2 D7.2 | length 113.3
  Top Layer w50: D7.2@5611.72,6275.79 5611.72,6163.38 D6.2@5612.33,6162.76
NetD13_1: D13.1 R64.2 | length 137.1
  Top Layer w15: D13.1@673.14,3206.05 673.14,3237.8 698.61,3263.26 R64.2@767.96,3263.26
NetD14_1: D14.1 R66.2 | length 85.8
  Top Layer w15: v1(2126.43,3603.86) D14.1@2175.82,3603.86
  Bottom Layer w15: R66.2@2090.01,3603.86 v1(2126.43,3603.86)
NetD15_1: D15.1 R67.2 | length 308.3
  Top Layer w15: v1(1915.7,3501.54) 1943.99,3529.82 D15.1@2175.82,3529.82
  Bottom Layer w15: R67.2@1915.7,3465.12 v1(1915.7,3501.54)
NetD16_1: D16.1 R68.2 | length 309.3
  Top Layer w15: v1(1915.77,3243.81) 1946.55,3213.03 D16.1@2175.86,3213.03
  Bottom Layer w15: v1(1915.77,3243.81) R68.2@1915.77,3280.23
NetD17_1: D17.1 R70.2 | length 85.1
  Top Layer w15: v1(2142.89,3136.1) D17.1@2175.08,3136.1
  Bottom Layer w15: R70.2@2090.01,3136.1 v1(2142.89,3136.1)
NetD19_1: D19.1 U31.24 | length 140.5
  Top Layer w8: U31.24@517.17,929.75 517.17,868.06 556.32,828.91 D19.1@556.32,805.46
NetD39_1: D39.1 R324.2 R325.2 U39.2 | length 336.8
  Top Layer w8: U39.2@3658.94,2556.37 3606.72,2556.37 3582.03,2531.68 D39.1@3582.03,2454.14 3582.77,2454.88 R325.2@3655.25,2454.88 3747.71,2454.88 R324.2@3752.04,2450.56
NetD41_2: D41.2 SW5.2 SW5.4 | length 1088.2
  Top Layer w8: SW5.4@2402.99,5611.02 2403.11,5610.91 SW5.4@2404.7,5610.91 SW5.2@2717.69,5610.91 2720.26,5613.47 2720.26,5643.81 2968.59,5892.14 D41.2@3356.91,5892.14
NetD42_1: D42.1 R344.1 | length 67.7
  Top Layer w8: D42.1@3789.6,5641 R344.1@3857.31,5641
NetD43_2: D43.2 R345.1 | length 62.4
  Top Layer w8: R345.1@3458.36,5645.29 3466.6,5637.06 D43.2@3517.33,5637.06
NetD44_2: D44.2 R349.2 | length 68
  Top Layer w20: R349.2@4379.43,4939.93 4445.87,4939.93 D44.2@4447.01,4941.07
NetD45_2: D45.2 R350.1 | length 67.8
  Top Layer w20: R350.1@4384.94,5319.52 4452.08,5319.52 D45.2@4452.52,5319.09
NetD46_2: D46.2 R351.2 | length 67.9
  Top Layer w20: R351.2@4384.94,5219.99 4451.62,5219.99 D46.2@4452.52,5219.09
NetD47_2: D47.2 R352.1 | length 68.8
  Top Layer w20: R352.1@4383.76,5517.31 D47.2@4452.52,5517.31
NetD48_2: D48.2 R353.1 | length 70.6
  Top Layer w20: R353.1@4381.92,5418.51 D48.2@4452.52,5418.51
NetD49_1: D49.1 Q17.3 | length 76.5
  Top Layer w15: D49.1@4515.51,5122.39 v1(4553.77,5122.39)
  Bottom Layer w15: Q17.3@4515.51,5122.39 v1(4553.77,5122.39)
NetD49_2: D49.2 R354.2 | length 74.4
  Top Layer w20: R354.2@4378.6,5121.35 4451.47,5121.35 D49.2@4452.52,5122.39
NetD50_1: D50.1 Q18.3 | length 98.9
  Top Layer w15: D50.1@4510,5027.6 v1(4548.26,5027.6)
  Bottom Layer w8: Q18.3@4510.28,4999.91 4539.64,4999.91 4548.26,5008.53 v1(4548.26,5027.6)
NetD50_2: D50.2 R355.2 | length 68.9
  Top Layer w20: R355.2@4378.94,5025.58 4444.98,5025.58 D50.2@4447.01,5027.6
NetD51_2: D51.2 Q15.3 | length 57.9
  Top Layer w10: v1(4395.55,5698.53) 4424.06,5698.53 D51.2@4424.45,5698.93
  Bottom Layer w10: v1(4395.55,5698.53) Q15.3@4424.44,5698.53
NetD52_2: D52.2 Q16.3 | length 71.5
  Top Layer w15: D52.2@4424.71,5864.65 v1(4424.71,5900.38)
  Bottom Layer w15: Q16.3@4424.71,5864.65 v1(4424.71,5900.38)
NetD54_2: D54.2 R384.1 | length 62.1
  Top Layer w8: D54.2@1657.87,1378.07 1719.73,1378.07 R384.1@1719.89,1378.24
NetD55_2: D55.2 U49.8 | length 104.3
  Top Layer w8: U49.8@5009.43,4215.9 5075.37,4215.9 5085.98,4205.28 D55.2@5085.98,4181.96
NetD57_2: D57.2 R463.1 R467.1 | length 180
  Top Layer w10: D57.2@7206.02,5333 7236.59,5333 7270.36,5366.77 R467.1@7270.36,5409.57 7270.36,5467.45 R463.1@7271.05,5468.14
NetD58_1: D58.1 R442.1 R443.1 R444.2 | length 373.8
  Top Layer w8: v1@4898.9,4283.02 R443.1@4898.9,4327.95
  Bottom Layer w8: v1(4898.37,4278.64) 4879.48,4259.75 R444.2@4833.01,4259.77 4833.01,4306.38 4865.67,4339.04 D58.1@4865.67,4345.04 4865.67,4351.05 4898.9,4384.29 R442.1@4898.9,4488.16
NetJ12_1: J12.1 U12.15 | length 196.6
  Top Layer w9.9: U12.15@3777.25,6457.41 3809.56,6457.41 3886.39,6380.58 J12.1@3886.39,6324.96
NetJ12_5: J12.5 U12.14 | length 159.7
  Top Layer w9.9: U12.14@3757.57,6457.41 3757.57,6436.09 3823.4,6370.26 J12.5@3823.4,6324.96
NetJ12_9: J12.9 U12.13 | length 141.8
  Top Layer w9.9: U12.13@3737.88,6457.41 3737.88,6408.37 3760.4,6385.84 J12.9@3760.4,6324.96
NetJ12_13: J12.13 U12.12 | length 141.1
  Top Layer w9.9: J12.13@3697.41,6324.96 3697.41,6387.29 3718.2,6408.08 U12.12@3718.2,6457.41
NetJ12_17: J12.17 U12.11 | length 159
  Top Layer w9.9: J12.17@3634.42,6324.96 3634.42,6372.79 3698.51,6436.88 U12.11@3698.51,6457.41
NetJ12_21: J12.21 U12.10 | length 193.1
  Top Layer w9.9: J12.21@3571.43,6324.96 3571.43,6377.6 3651.24,6457.41 U12.10@3678.82,6457.41
NetJ12_25: J12.25 R74.2 | length 140.8
  Top Layer w9.9: R74.2@3467.84,6448.96 3467.84,6407 3508.44,6366.41 J12.25@3508.44,6324.96
NetJ12_29: J12.29 U13.7 | length 196.6
  Top Layer w9.9: U13.7@3336.31,6457.41 3368.62,6457.41 3445.44,6380.58 J12.29@3445.44,6324.96
NetJ12_33: J12.33 U13.6 | length 159.7
  Top Layer w9.9: U13.6@3316.62,6457.41 3316.62,6436.09 3382.45,6370.26 J12.33@3382.45,6324.96
NetJ12_37: J12.37 U13.5 | length 141.8
  Top Layer w9.9: U13.5@3296.94,6457.41 3296.94,6408.37 3319.46,6385.84 J12.37@3319.46,6324.96
NetJ12_41: J12.41 U13.4 | length 141.1
  Top Layer w9.9: J12.41@3256.47,6324.96 3256.47,6387.29 3277.25,6408.08 U13.4@3277.25,6457.41
NetJ12_44: J12.44 R75.1 | length 88.4
  Top Layer w20: J12.44@3224.97,6147.8 v1(3224.97,6187.8)
  Bottom Layer w20: v1(3224.97,6187.8) 3224.97,6236.05 R75.1@3225.06,6236.15
NetJ12_45: J12.45 U13.3 | length 159
  Top Layer w9.9: J12.45@3193.47,6324.96 3193.47,6372.79 3257.57,6436.88 U13.3@3257.57,6457.41
NetJ12_49: J12.49 U13.2 | length 193.1
  Top Layer w9.9: J12.49@3130.48,6324.96 3130.48,6377.6 3210.3,6457.41 U13.2@3237.88,6457.41
NetJ13_1: J13.1 U16.15 | length 196.6
  Top Layer w9.9: U16.15@1966.6,6457.41 1998.91,6457.41 2075.73,6380.58 J13.1@2075.73,6324.96
NetJ13_5: J13.5 U16.14 | length 159.7
  Top Layer w9.9: U16.14@1946.91,6457.41 1946.91,6436.09 2012.74,6370.26 J13.5@2012.74,6324.96
NetJ13_9: J13.9 U16.13 | length 141.8
  Top Layer w9.9: U16.13@1927.22,6457.41 1927.22,6408.37 1949.75,6385.84 J13.9@1949.75,6324.96
NetJ13_13: J13.13 U16.12 | length 141.1
  Top Layer w9.9: J13.13@1886.76,6324.96 1886.76,6387.29 1907.54,6408.08 U16.12@1907.54,6457.41
NetJ13_17: J13.17 U16.11 | length 159
  Top Layer w9.9: J13.17@1823.76,6324.96 1823.76,6372.79 1887.85,6436.88 U16.11@1887.85,6457.41
NetJ13_21: J13.21 U16.10 | length 193.1
  Top Layer w9.9: J13.21@1760.77,6324.96 1760.77,6377.6 1840.59,6457.41 U16.10@1868.17,6457.41
NetJ13_25: J13.25 R77.2 | length 163.9
  Top Layer w8: J13.25@1697.78,6324.96 R77.2@1697.78,6488.9
NetJ13_29: J13.29 U19.7 | length 196.6
  Top Layer w9.9: U19.7@1525.65,6457.41 1557.96,6457.41 1634.79,6380.58 J13.29@1634.79,6324.96
NetJ13_33: J13.33 U19.6 | length 159.7
  Top Layer w9.9: U19.6@1505.97,6457.41 1505.97,6436.09 1571.8,6370.26 J13.33@1571.8,6324.96
NetJ13_37: J13.37 U19.5 | length 141.8
  Top Layer w9.9: U19.5@1486.28,6457.41 1486.28,6408.37 1508.8,6385.84 J13.37@1508.8,6324.96
NetJ13_41: J13.41 U19.4 | length 141.1
  Top Layer w9.9: J13.41@1445.81,6324.96 1445.81,6387.29 1466.6,6408.08 U19.4@1466.6,6457.41
NetJ13_44: J13.44 R79.1 | length 91.9
  Top Layer w8: J13.44@1414.32,6147.8 v1(1414.32,6186.18)
  Bottom Layer w8: R79.1@1413.8,6239.52 1414.32,6239.01 v1(1414.32,6186.18)
NetJ13_45: J13.45 U19.3 | length 159
  Top Layer w9.9: J13.45@1382.82,6324.96 1382.82,6372.79 1446.91,6436.88 U19.3@1446.91,6457.41
NetJ13_49: J13.49 U19.2 | length 193.1
  Top Layer w9.9: J13.49@1319.83,6324.96 1319.83,6377.6 1399.64,6457.41 U19.2@1427.23,6457.41
NetJ20_15: J20.15 R367.2 | length 102.1
  Top Layer w8: J20.15@2361.03,1703.25 R367.2@2361.03,1805.34
NetL1_1: L1.1 R36.1 U5.13 | length 178.8
  Top Layer w8: R36.1@1464.58,1510 1465.66,1511.08 L1.1@1523.09,1511.08 1555.28,1511.08 1598.83,1554.62 U5.13@1624.94,1554.62
NetL1_2: L1.2 R40.1 U5.12 | length 173.8
  Top Layer w8: R40.1@1465.9,1610 1466.4,1609.5 L1.2@1523.09,1609.5 1561.88,1609.5 1597.08,1574.31 U5.12@1624.94,1574.31
NetL2_1: L2.1 R42.1 U6.7 | length 177.6
  Top Layer w8: R42.1@1619.7,2882 1619.84,2882.14 L2.1@1678.26,2882.14 1715.36,2882.14 1742.47,2909.25 U6.7@1786.01,2909.25
NetL2_2: L2.2 R45.1 U6.6 | length 175.4
  Top Layer w8: R45.1@1619.7,2980 1620.26,2980.57 L2.2@1678.26,2980.57 1721.49,2980.57 1742.81,2959.25 U6.6@1786.01,2959.25
NetL3_1: L3.1 R46.1 U7.13 | length 278.6
  Top Layer w8: R46.1@1596.68,2250 1597.95,2248.73 L3.1@1654.32,2248.73 1663.24,2248.73 1763.49,2348.99 U7.13@1833.25,2348.99
NetL3_2: L3.2 R49.1 U7.12 | length 258.5
  Top Layer w8: R49.1@1596.26,2347 1596.41,2347.15 L3.2@1654.32,2347.15 1724.04,2347.15 1775.87,2398.99 U7.12@1833.25,2398.99
NetL4_1: L4.1 R50.1 U7.10 | length 259.5
  Top Layer w8: R50.1@1596.26,2552 1596.94,2552.68 L4.1@1653.84,2552.68 1721.95,2552.68 1775.64,2498.99 U7.10@1833.25,2498.99
NetL4_2: L4.2 R53.1 U7.9 | length 279.7
  Top Layer w8: R53.1@1596.26,2650 1597.36,2651.1 L4.2@1653.84,2651.1 1662.62,2651.1 1764.73,2548.99 U7.9@1833.25,2548.99
NetL6_1: L6.1 R331.1 R332.1 U41.3 U41.4
NetL11_1: L11.1 U45.2
NetL12_1: L12.1 U47.2
NetQ1_4: Q1.4 R19.2 | length 77.3
  Top Layer w8: Q1.4@5218.31,5735.85 Q1.4@5221.03,5738.58
  Top Layer w10: R19.2@5144.87,5735.85 Q1.4@5218.31,5735.85
NetQ3_4: Q3.4 R18.2 | length 76.1
  Top Layer w8: R18.2@5142.32,5098.61 R18.2@5143.26,5097.68
  Top Layer w10: R18.2@5142.32,5098.61 Q3.4@5142.32,5173.42
NetQ7_4: Q7.4 R152.2 | length 94.2
  Top Layer w10: R152.2@7325.04,1026.32 7325.84,1027.13 Q7.4@7418.89,1027.13
NetQ8_4: Q8.4 R151.1 | length 97.2
  Top Layer w10: R151.1@7643.36,637.01 Q8.4@7740.59,637.01
NetQ9_4: Q9.4 R157.2 | length 51.1
  Top Layer w10: R157.2@7324.56,1089.57 7324.67,1089.68 Q9.4@7375.66,1089.68
NetQ10_4: Q10.4 R156.1 | length 60.7
  Top Layer w10: R156.1@7643.36,725.11 Q10.4@7704.09,725.11
NetQ11_4: Q11.4 R160.2 | length 100.7
  Top Layer w10: R160.2@7661.77,1566.64 Q11.4@7762.5,1566.64
NetQ12_4: Q12.4 R161.2 | length 97.7
  Top Layer w10: R161.2@7322.77,1918.09 7323.41,1918.73 Q12.4@7420.26,1918.73
NetQ13_4: Q13.4 R163.2 | length 60.6
  Top Layer w10: R163.2@7661.77,1629.54 Q13.4@7722.33,1629.54
NetQ14_4: Q14.4 R164.2 | length 59.1
  Top Layer w10: R164.2@7323.25,1979.32 7324.06,1980.12 Q14.4@7382.06,1980.12
NetQ15_2: Q15.2 R356.1 | length 51.3
  Bottom Layer w8: R356.1@4335.81,5603.91 4335.94,5604.05 Q15.2@4387.03,5604.05
NetQ16_2: Q16.2 R348.1 | length 51.9
  Bottom Layer w8: R348.1@4335.44,5770.09 4387.23,5770.09 Q16.2@4387.31,5770.16
NetQ17_1: Q17.1 R357.2 | length 72.3
  Bottom Layer w15: R357.2@4378.6,5121.35 4403.14,5096.8 Q17.1@4440.71,5096.8
NetQ18_1: Q18.1 R358.2 | length 101.4
  Bottom Layer w8: R358.2@4381.23,5024.82 4381.23,4992.62 4404.71,4969.14 4431.35,4969.14 Q18.1@4437.99,4962.5
NetQ19_1: Q19.1 R368.2 | length 82.2
  Top Layer w8: Q19.1@7197.37,3898.06 Q19.1@7198.16,3898.85
  Top Layer w10: R368.2@7116.24,3898.06 Q19.1@7197.37,3898.06
NetQ19_3: Q19.3 R474.2 | length 359.9
  Top Layer w20: v1(7235.56,3946.09) Q19.3@7235.56,3993.34
  Bottom Layer w20: R474.2@6941.76,3900.45 7189.92,3900.45 v1(7235.56,3946.09)
NetQ20_1: Q20.1 R475.2
NetQ20_5: Q20.5 R370.2 R372.2 | length 272.9
  Top Layer w5: R372.2@6890.9,4160.63 6869.19,4182.33 6869.19,4200.43 6849.05,4220.56 6849.05,4312.33 6867.89,4331.17 R370.2@6945.08,4331.17
NetQ21_1: Q21.1 Q21.3 R379.2 U42.10 | length 171.2
  Top Layer w8: U42.10@6992.09,3719.72 7054.61,3719.72 7103.55,3719.72 Q21.1@7103.87,3720.04 7135.36,3720.04 Q21.3@7155.05,3700.35
NetQ23_1: Q23.1 R455.2 | length 64.5
  Top Layer w8: R455.2@7488.82,5976 R455.2@7490.04,5977.22
  Top Layer w20: Q23.1@7426.04,5976 R455.2@7488.82,5976
NetQ23_3: Q23.3 R452.2 R454.2 | length 913.7
  Top Layer w5: v1(7115.03,5971.36) 7105.03,5981.36 7105.03,6040.04 7115.44,6050.45 R452.2@7195.29,6050.45
  Bottom Layer w5: v1(7115.03,5971.36) 7104.83,5961.17 7104.83,5867.59 7281.89,5690.53 7281.89,5342.49 R454.2@7310.09,5314.29
NetQ24_1: Q24.1 R463.2 | length 128.8
  Top Layer w20: Q24.1@7323.79,5592.73 7323.79,5532.14 7334.05,5521.88 R463.2@7334.05,5468.14
NetQ24_5: Q24.5 R457.2 R460.2 RNTC_1.2 | length 544.5
  Top Layer w5: R460.2@7068.34,5416.61 7047.15,5437.8 7047.15,5455.77 7068.34,5476.96 RNTC_1.2@7068.34,5479.19 7068.34,5481.41 7048.11,5501.64 7048.11,5623.39 6997.51,5674 6997.51,5734.49 7036.5,5773.48 R457.2@7161.06,5773.48
NetR29_2: R29.2 U1.11 | length 72.9
  Top Layer w8: U1.11@5532.64,4746.07 5532.64,4721.1 5542.62,4711.11 R29.2@5542.62,4677.34
NetR34_1: R34.1 U4.1 | length 97
  Top Layer w8: U4.1@5898.24,6018.41 5898.24,6065.47 5914.75,6081.98 R34.1@5914.75,6108.58
NetR39_2: R39.2 U5.7 | length 68.4
  Top Layer w8: R39.2@1742.39,1721.13 1743.05,1720.47 U5.7@1743.05,1653.05
NetR76_2: R76.2 U17.2 U18.2 | length 393.7
  Top Layer w8: v1(2366.11,6437.26) U17.2@2366.11,6470.72 ; U18.2@2548.86,6470.47 v1(2548.86,6437.01) 2631.01,6437.01 2638.95,6444.95 R76.2@2638.95,6495.49
  Bottom Layer w8: v1(2366.11,6437.26) 2548.61,6437.26 v1(2548.86,6437.01)
NetR82_1: R82.1 U20.4 | length 146.9
  Top Layer w8: R82.1@3871.77,1309.91 3908.67,1346.81 3908.67,1364.5 3928.52,1384.35 U20.4@3977.5,1384.35
NetR83_1: R83.1 U20.5 | length 88.7
  Top Layer w8: v1(3934.41,1358.76) U20.5@3977.5,1358.76
  Bottom Layer w8: R83.1@3888.8,1358.76 v1(3934.41,1358.76)
NetR89_2: R89.2 U20.14 | length 94.5
  Top Layer w8: U20.14@4205.84,1409.94 v1(4257.05,1409.94)
  Bottom Layer w8: R89.2@4257.05,1366.65 v1(4257.05,1409.94)
NetR94_1: R94.1 U21.4 | length 148
  Top Layer w10: R94.1@3368.82,960.82 3369.39,960.82 3405.96,997.39 3405.96,1017.05 3423.25,1034.34 U21.4@3474.84,1034.34
NetR95_1: R95.1 U21.5 | length 85.5
  Top Layer w10: v1(3430.5,1008.75) U21.5@3474.84,1008.75
  Bottom Layer w8: v1(3430.5,1008.75) R95.1@3430.5,1049.93
NetR97_2: R97.2 U21.13 | length 110.1
  Top Layer w8: U21.13@3703.19,1034.34 R97.2@3813.31,1034.34
NetR98_2: R98.2 U21.14 | length 106
  Top Layer w8: U21.14@3703.19,1059.93 3751.02,1059.93 3773.63,1082.54 R98.2@3799.82,1082.54
NetR99_1: R99.1 U22.6 | length 164.8
  Top Layer w8: v2(7484.16,3322.24) 7484.48,3322.56 7484.48,3368.19 U22.6@7484.81,3368.52
  Bottom Layer w8: R99.1@7398.54,3244.89 7398.54,3245.87 7472.99,3320.32 7482.24,3320.32 v2(7484.16,3322.24)
NetR101_1: R101.1 R102.1 U22.13 | length 534.8
  Top Layer w8: R102.1@7172.86,3610.53 7178.91,3616.58 7178.91,3702.25 R101.1@7215.59,3738.94 7216.58,3738.94 7248.16,3707.35 7477.8,3707.35 7484.81,3700.35 U22.13@7484.81,3596.86
NetR104_2: R104.2 U22.14 | length 501.1
  Top Layer w8: R104.2@7172.86,3550.2 7202.4,3550.2 7207.08,3554.88 7207.08,3657.85 7243.59,3694.35 7454.53,3694.35 7459.22,3689.67 U22.14@7459.22,3596.86
NetR105_2: R105.2 U22.15 | length 488
  Top Layer w8: R105.2@7178.12,3495.19 7212.84,3495.19 7220.67,3503.02 7220.67,3628.75 7273.28,3681.35 7428.94,3681.35 7433.63,3676.67 U22.15@7433.63,3596.86
NetR108_2: R108.2 U22.16 | length 491.7
  Top Layer w8: R108.2@7172.86,3429.66 7182.45,3439.24 7205.05,3439.24 7234.47,3468.66 7234.47,3620.39 7282.43,3668.35 7403.35,3668.35 7408.04,3663.67 U22.16@7408.04,3596.86
NetR109_1: R109.1 U22.5 | length 138.1
  Top Layer w8: U22.5@7459.22,3368.52 7459.22,3317.07 7491.81,3284.47 R109.1@7491.81,3243.94
NetR110_2: R110.2 U22.17 | length 456.4
  Top Layer w8: R110.2@7178.05,3369.39 7179.12,3370.46 7205.05,3370.46 7249.13,3414.55 7249.13,3582.99 7307.69,3641.55 7375.45,3641.55 7382.45,3634.55 U22.17@7382.45,3596.86
NetR112_2: R112.2 U24.7 | length 97
  Top Layer w8: R112.2@4506.56,1137.95 4506.56,1091.59 4524.5,1073.65 U24.7@4524.5,1048.41
NetR113_2: R113.2 U23.2 | length 163.1
  Top Layer w8: R113.2@7453.1,3091.4 7453.1,3018.65 7490.19,2981.56 U23.2@7528.12,2981.56
NetR115_2: R115.2 U24.8 | length 83.2
  Top Layer w8: R115.2@4430.48,1079.83 4431.46,1079.83 4467.56,1043.74 U24.8@4498.68,1043.74
NetR116_2: R116.2 U23.3 | length 177.5
  Top Layer w8: R116.2@7380.39,3027.83 7411.74,3027.83 7483.6,2955.97 U23.3@7528.12,2955.97
NetR117_2: R117.2 U24.6 | length 99.3
  Top Layer w8: U24.6@4546.15,1048.41 4546.15,1069.65 4569.51,1093.01 R117.2@4569.51,1138.01
NetR118_2: R118.2 U23.5 | length 138.2
  Top Layer w8: R118.2@7390.51,2906.28 7392,2904.79 U23.5@7528.12,2904.79
NetR119_1: R119.1 R121.2 U23.4 | length 344.6
  Top Layer w8: R121.2@7202.65,2976.48 7205.11,2974.01 7421.05,2974.01 7464.68,2930.38 U23.4@7528.12,2930.38
NetR120_2: R120.2 U24.5 | length 84.4
  Top Layer w8: U24.5@4568.05,1043.74 4603.54,1043.74 4637.45,1077.64 R120.2@4638.44,1077.64
NetR122_2: R122.2 U23.7 | length 63.6
  Top Layer w8: R122.2@7528.07,2789.99 R122.2@7528.07,2789.99 U23.7@7528.12,2853.6
NetR123_1: R123.1 R125.1 U24.10 | length 152.2
  Top Layer w8: R125.1@4366.13,958.89 R123.1@4430.5,958.89 ; R123.1@4431.53,958.84 4471.09,998.41 U24.10@4502.97,998.41
NetR126_2: R126.2 U24.3 | length 72.1
  Top Layer w8: U24.3@4573.84,998.41 4595.34,998.41 4613.37,1016.44 R126.2@4638.44,1016.44
NetR129_2: R129.2 U25.2 | length 141.9
  Top Layer w8: U25.2@5279.18,1043.03 5279.18,1078.58 5291.66,1091.07 R129.2@5380.38,1091.07
NetR130_2: R130.2 U26.7 | length 57.4
  Bottom Layer w8: R130.2@7532.63,4748.03 7562.81,4748.03 7566.81,4744.03 U26.7@7588.42,4744.03
NetR132_2: R132.2 U25.3 | length 197.3
  Top Layer w8: U25.3@5259.49,1043.03 5259.49,1098.8 5309.37,1148.67 R132.2@5380.38,1148.67
NetR133_2: R133.2 U26.6 | length 58.8
  Bottom Layer w8: R133.2@7532.3,4715.82 7561.47,4715.82 7568.02,4722.37 U26.6@7588.42,4722.37
NetR134_2: R134.2 U25.4 | length 256.3
  Top Layer w8: U25.4@5239.81,1043.03 5239.81,1124.65 5322.25,1207.1 R134.2@5380.38,1207.1
NetR135_1: R135.1 R137.1 U26.10 | length 176.2
  Bottom Layer w8: U26.10@7638.61,4768.63 7638.61,4810.92 7657.01,4829.32 7657.01,4873.54 7658.76,4875.29 R137.1@7658.76,4936.52
NetR136_2: R136.2 U25.5 | length 319.9
  Top Layer w8: U25.5@5220.12,1043.03 5220.12,1158.56 5326.57,1265.01 R136.2@5380.38,1265.01
NetR138_1: R138.1 U26.3 | length 73.9
  Top Layer w8: R138.1@7638.61,4623.88 v1(7638.61,4664.96)
  Bottom Layer w8: v1(7638.61,4664.96) U26.3@7638.61,4697.77
NetR139_2: R139.2 U25.8 | length 363.3
  Top Layer w8: R139.2@4961.43,1277.18 5040.75,1277.18 5161.07,1156.86 U25.8@5161.07,1043.03
NetR140_2: R140.2 U25.7 | length 420.4
  Top Layer w8: R140.2@4961.43,1335.18 5025.31,1335.18 5180.75,1179.74 U25.7@5180.75,1043.03
NetR141_1: R141.1 R145.2 U25.9 | length 382.8
  Top Layer w8: v5(4993.57,1220.39) 4994.88,1219.08 5052.4,1219.08 5141.38,1130.1 U25.9@5141.38,1043.03
  Bottom Layer w8: R141.1@4887.32,1219.08 R141.1@4892.67,1224.43 ; R141.1@4892.67,1225.28 R145.2@4956.81,1225.28 4961.69,1220.39 v5(4993.57,1220.39)
NetR142_1: R142.1 R146.2 U25.10 | length 382.2
  Top Layer w8: v5(4951.43,1167.65) 5056.79,1167.65 5121.7,1102.74 U25.10@5121.7,1043.03
  Bottom Layer w8: R146.2@4826.12,1167.55 R142.1@4892.73,1167.55 4892.83,1167.65 v5(4951.43,1167.65)
NetR144_2: R144.2 U25.6 | length 377.7
  Top Layer w8: U25.6@5200.44,1043.03 5200.44,1181.97 5342.36,1323.89 R144.2@5380.38,1323.89
NetR149_2: R149.2 U25.12 | length 165.4
  Top Layer w8: R149.2@4961.43,1101.22 5058.98,1101.22 5082.33,1077.88 U25.12@5082.33,1043.03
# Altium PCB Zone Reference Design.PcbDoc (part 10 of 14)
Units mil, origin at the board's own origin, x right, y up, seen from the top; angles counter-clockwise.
Board outline 8858.11 x 7047.08 mil, 16 copper layers (Top Layer, GND_1, SIG_1, GND_2, PWR/SIG_1, GND_3, PWR_1, PWR_2, GND_4, PWR/SIG_2, GND_5, SIG_2, GND_6, SIG_3, GND_7, Bottom Layer), stack 80.368 mil thick; 1131 components, 808 nets, 3825 pads, 3523 vias.
Unrouted connection lines stored in the file: 563.

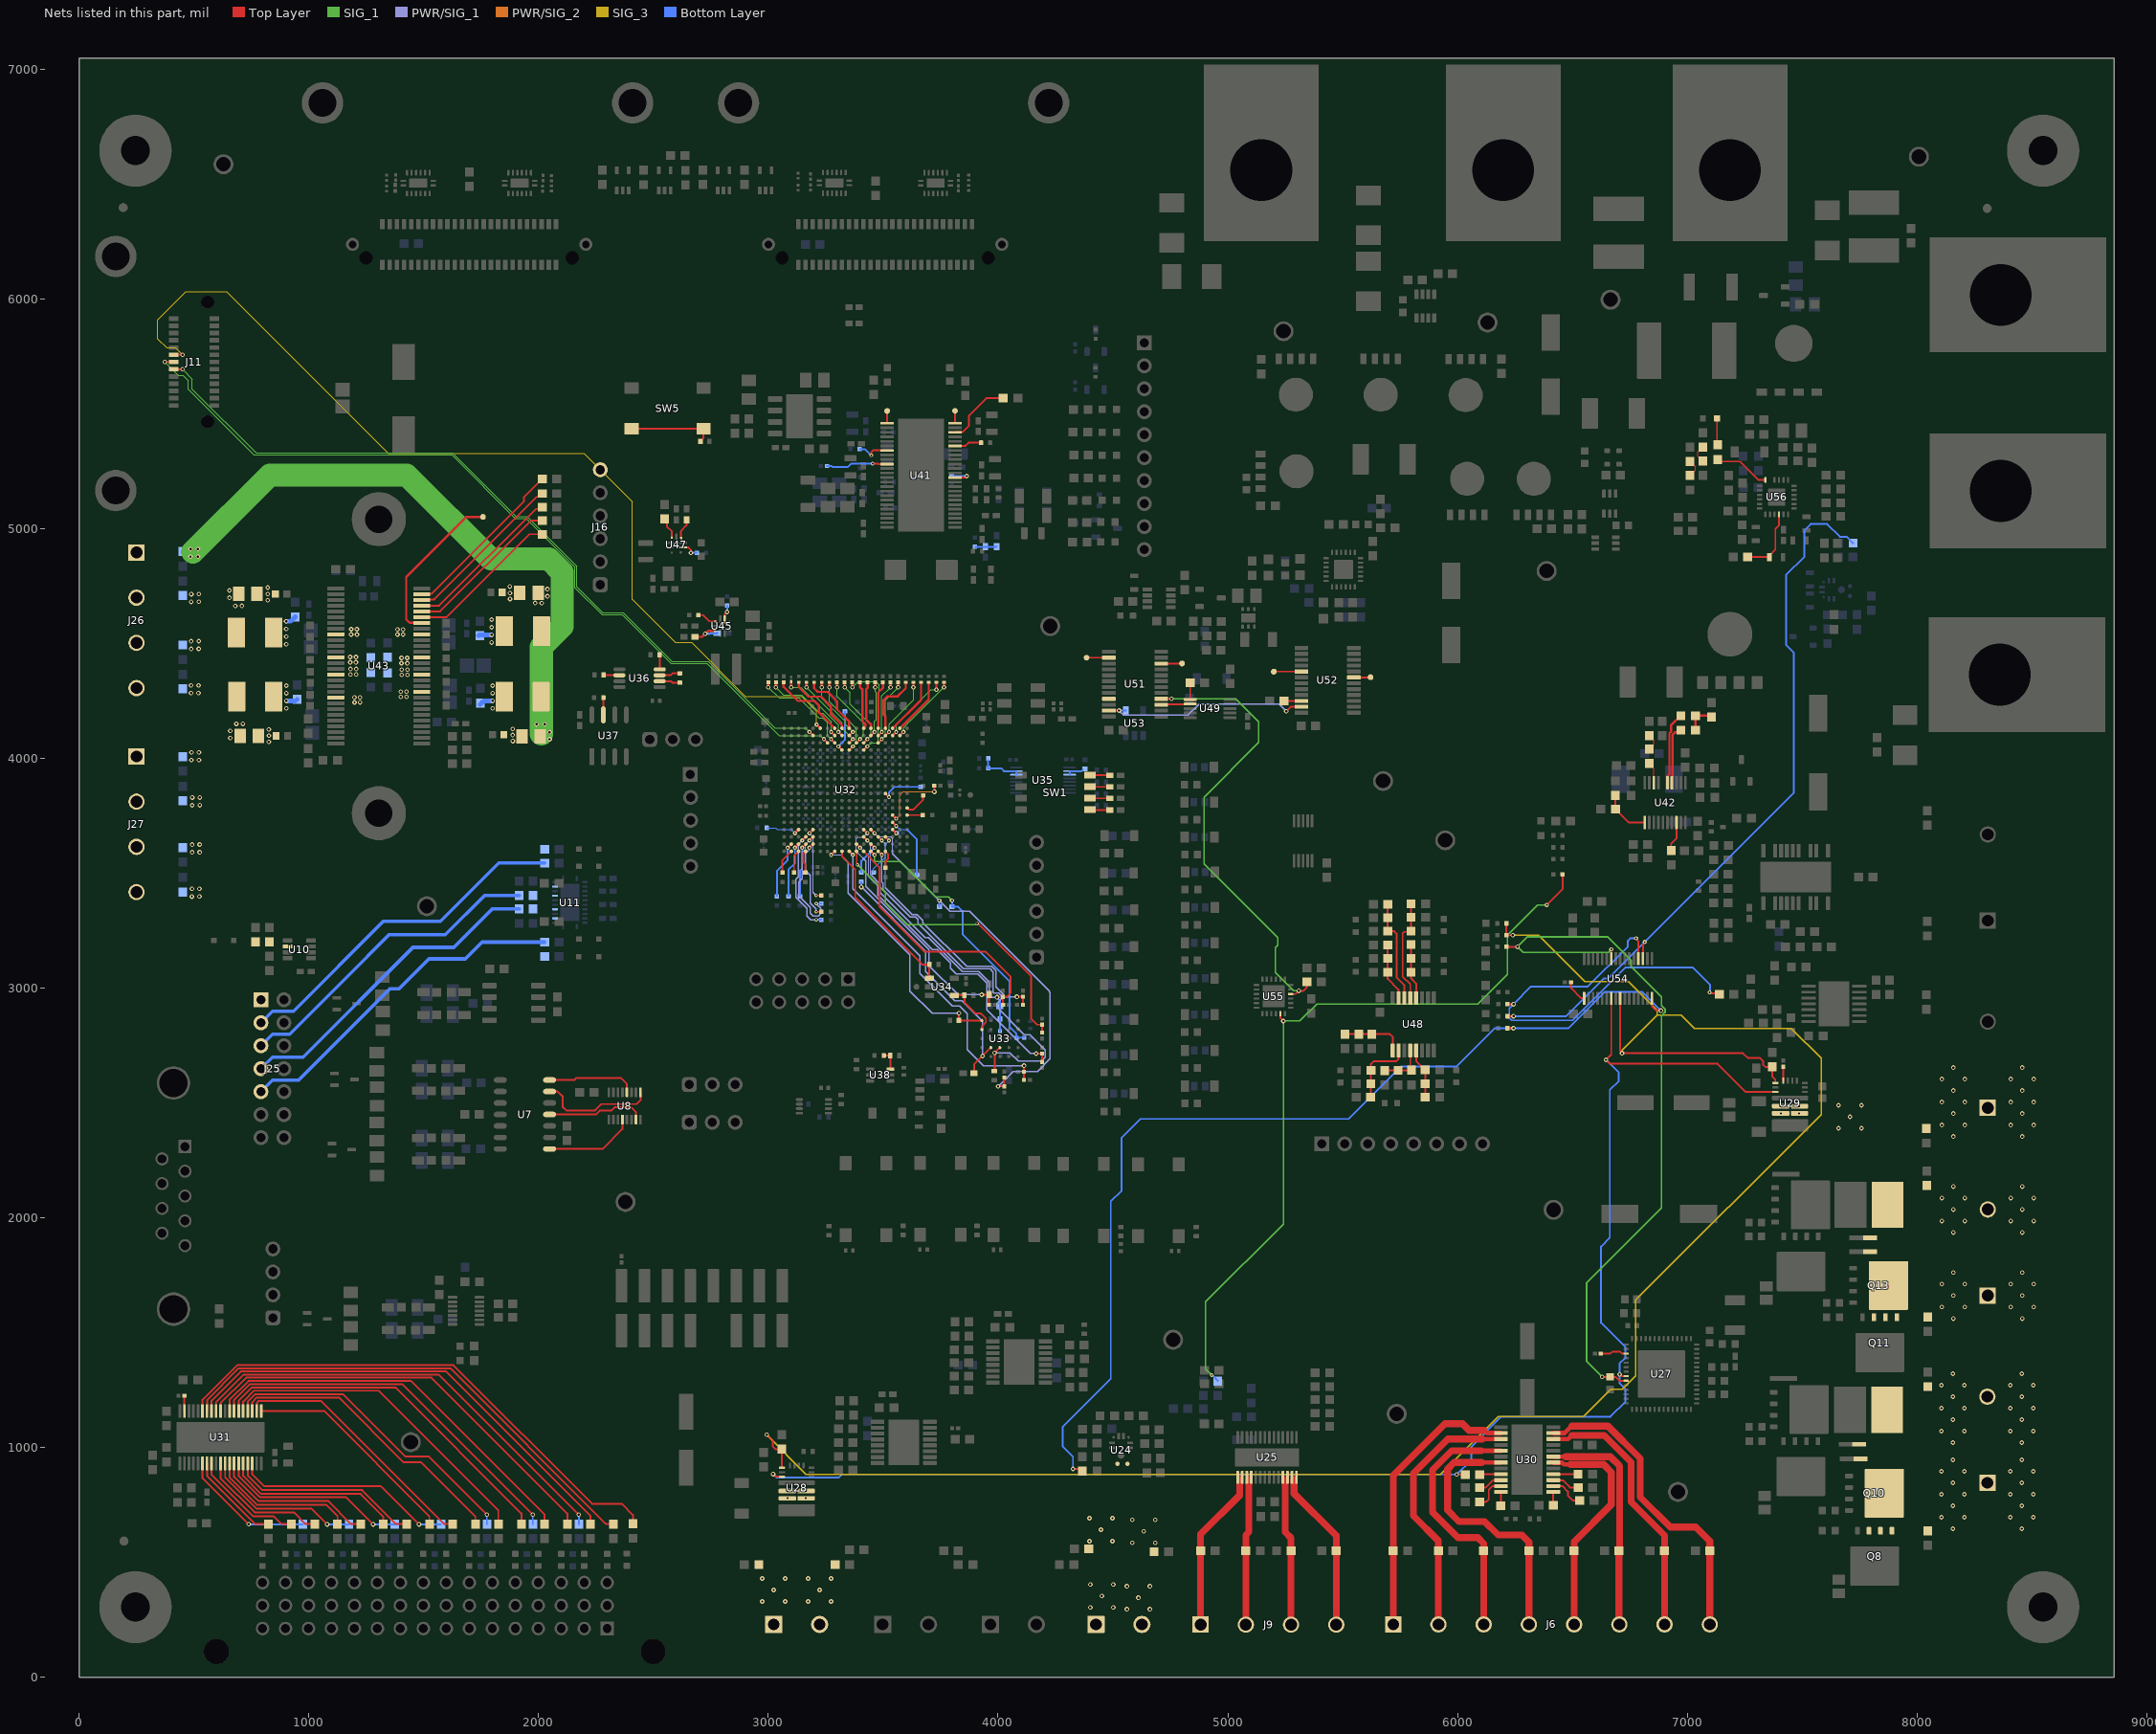
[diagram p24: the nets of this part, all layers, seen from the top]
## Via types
v1: diameter 20, hole 10, Top Layer to Bottom Layer, tented both sides, 2450 vias
v2: diameter 18, hole 8, Top Layer to Bottom Layer, tented both sides, 400 vias
v3: diameter 32, hole 16, Top Layer to Bottom Layer, tented both sides, 348 vias
v4: diameter 19.68, hole 7.87, Top Layer to Bottom Layer, tented both sides, 245 vias
v5: diameter 16, hole 8, Top Layer to Bottom Layer, tented both sides, 60 vias
v6: diameter 16, hole 8, Top Layer to Bottom Layer, 14 vias
v7: diameter 24.8, hole 12.99, Top Layer to Bottom Layer, tented both sides, 6 vias

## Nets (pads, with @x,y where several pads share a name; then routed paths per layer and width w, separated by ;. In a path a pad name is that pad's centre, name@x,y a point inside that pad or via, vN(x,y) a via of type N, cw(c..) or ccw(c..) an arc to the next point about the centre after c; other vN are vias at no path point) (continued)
NetR159_2: R159.2 U27.3 | length 116.8
  Top Layer w8: R159.2@6623.84,1408.08 6664.92,1408.08 6673.13,1416.29 6707.65,1416.29 6715.86,1408.08 U27.3@6733.89,1408.08
NetR170_2: R170.2 U29.16 | length 60.8
  Top Layer w8: U29.16@7417.76,2596.27 7417.99,2596.5 R170.2@7417.99,2656.95
NetR171_2: R171.2 U30.24 | length 59.9
  Top Layer w8: R171.2@6188.12,746.22 6188.12,805.69 U30.24@6188.4,805.97
NetR172_2: R172.2 U30.21 | length 92.8
  Top Layer w8: R172.2@6095.95,881.97 6096.73,882.74 U30.21@6188.4,882.74
NetR173_2: R173.2 U30.23 | length 145.4
  Top Layer w8: R173.2@6095.95,762.53 6125.2,762.53 6135.76,773.09 6135.76,814.71 6152.61,831.56 U30.23@6188.4,831.56
NetR174_2: R174.2 U30.22 | length 106.2
  Top Layer w8: R174.2@6095.95,824.01 6120.91,824.01 6154.05,857.15 U30.22@6188.4,857.15
NetR175_2: R175.2 U30.2 | length 151.2
  Top Layer w8: U30.2@6416.74,831.56 6456.89,831.56 6480.31,808.14 6480.31,789.82 6502.37,767.75 R175.2@6530.73,767.75
NetR176_2: R176.2 U30.3 | length 121
  Top Layer w8: U30.3@6416.74,857.15 6417.79,856.1 6458.27,856.1 6489.04,825.33 R176.2@6524.54,825.33
NetR177_2: R177.2 U30.4 | length 107.5
  Top Layer w8: U30.4@6416.74,882.74 6524,882.74 R177.2@6524.16,882.89
NetR179_2: R179.2 U30.1 | length 57.7
  Top Layer w8: U30.1@6416.74,805.97 6416.74,749.23 R179.2@6417.43,748.54
NetR180_2: R180.2 U31.13 | length 2153.8
  Top Layer w8: U31.13@556.54,1158.1 556.54,1205.79 694.51,1343.76 1615.44,1343.76 2293.07,666.14 R180.2@2324.79,666.14
NetR181_2: R181.2 U31.14 | length 2293.7
  Top Layer w8: U31.14@536.86,1158.1 536.86,1207.22 687.56,1357.92 1629.41,1357.92 2232.62,754.71 2361.24,754.71 2410.39,705.57 R181.2@2410.39,667.12
NetR183_2: R183.2 U31.25 | length 584.4
  Top Layer w8: U31.25@536.86,929.75 536.86,866.36 v1(738.06,665.15)
  Bottom Layer w8: v1(738.06,665.15) R183.2@974.53,665.15
NetR184_2: R184.2 U31.26 | length 408.1
  Top Layer w8: U31.26@556.54,929.75 556.54,876.64 767.04,666.14 R184.2@824.34,666.14
NetR186_2: R186.2 U31.27 | length 485.3
  Top Layer w8: U31.27@576.23,929.75 576.23,881.04 757.54,699.73 847.87,699.73 881.45,666.14 R186.2@923.84,666.14
NetR187_1: R187.1 U31.18 | length 65.7
  Top Layer w8: U31.18@458.12,1158.1 R187.1@458.12,1223.81
NetR188_2: R188.2 U31.29 | length 556.8
  Top Layer w8: U31.29@615.6,929.75 615.6,864.84 763.9,716.54 934.37,716.54 984.77,666.14 R188.2@1025.21,666.14
NetR189_2: R189.2 U31.30 | length 685.1
  Top Layer w8: U31.30@635.28,929.75 635.28,868.79 770.71,733.36 1011.17,733.36 v1(1079.75,664.78)
  Bottom Layer w8: v1(1079.75,664.78) 1080.12,665.15 R189.2@1174.8,665.15
NetR190_2: R190.2 U31.31 | length 634.4
  Top Layer w8: U31.31@654.97,929.75 654.97,869.1 773.44,750.63 1074.2,750.63 1124.77,700.06 R190.2@1124.77,666.14
NetR192_2: R192.2 U31.32 | length 693.8
  Top Layer w8: U31.32@674.65,929.75 674.65,871.23 779.35,766.53 1082.77,766.53 1183.16,666.14 R192.2@1224.97,666.14
NetR193_2: R193.2 U31.33 | length 821.6
  Top Layer w8: U31.33@694.34,929.75 694.34,875.18 786.62,782.89 1161.46,782.89 v1(1279.57,664.78)
  Bottom Layer w8: v1@1279.94,665.15 R193.2@1374.62,665.15
NetR194_2: R194.2 U31.34 | length 770
  Top Layer w8: U31.34@714.02,929.75 714.02,875.28 792.28,797.02 1225.09,797.02 1324.41,697.7 R194.2@1324.41,666.14
NetR195_2: R195.2 U31.35 | length 830.9
  Top Layer w8: U31.35@733.71,929.75 733.71,877.48 797.59,813.59 1231.88,813.59 1379.34,666.14 R195.2@1424.83,666.14
NetR196_2: R196.2 U31.36 | length 958.4
  Top Layer w8: U31.36@753.39,929.75 753.39,882.57 804.29,831.67 1312.84,831.67 v1(1479.73,664.78)
  Bottom Layer w8: v1@1480.11,665.15 R196.2@1574.79,665.15
NetR197_2: R197.2 U31.1 | length 955.4
  Top Layer w8: U31.1@792.76,1158.1 1066.27,1158.1 1524.79,699.58 R197.2@1524.79,666.14
NetR198_2: R198.2 U31.3 | length 1264.5
  Top Layer w8: U31.3@753.39,1158.1 753.39,1196.25 773.56,1216.43 1130.6,1216.43 1412.62,934.41 1488.34,934.41 1724.79,697.96 R198.2@1724.79,666.14
NetR199_2: R199.2 U31.2 | length 1112
  Top Layer w8: U31.2@773.08,1158.1 773.08,1192.7 782.21,1201.84 1052.96,1201.84 1588.66,666.14 R199.2@1624.79,666.14
NetR200_2: R200.2 U31.4 | length 1354.7
  Top Layer w8: U31.4@733.71,1158.1 733.71,1199.56 765.61,1231.47 1148.76,1231.47 1420.86,959.37 1522.19,959.37 v1(1774.79,706.77)
  Bottom Layer w8: R200.2@1774.79,665.15 v1(1774.79,706.77)
NetR201_2: R201.2 U31.5 | length 1447.3
  Top Layer w8: U31.5@714.02,1158.1 714.02,1199.48 761.25,1246.71 1304.16,1246.71 1824.79,726.08 R201.2@1824.79,666.14
NetR202_2: R202.2 U31.6 | length 1571.7
  Top Layer w8: U31.6@694.34,1158.1 694.34,1202.86 751.62,1260.13 1376.33,1260.13 1924.79,711.68 R202.2@1924.79,666.14
NetR203_2: R203.2 U31.7 | length 1653.6
  Top Layer w8: U31.7@674.65,1158.1 674.65,1206.31 743.19,1274.85 1406.64,1274.85 v1(1974.72,706.77)
  Bottom Layer w8: R203.2@1974.72,665.15 v1(1974.72,706.77)
NetR204_2: R204.2 U31.8 | length 1735.4
  Top Layer w8: U31.8@654.97,1158.1 654.97,1206.61 737.15,1288.8 1444.91,1288.8 2024.79,708.92 R204.2@2024.79,666.14
NetR205_2: R205.2 U31.10 | length 1879.7
  Top Layer w8: U31.10@615.6,1158.1 615.6,1191.62 727.22,1303.24 1533.55,1303.24 2124.79,712 R205.2@2124.79,666.14
NetR206_2: R206.2 U31.11 | length 1961.1
  Top Layer w8: U31.11@595.91,1158.1 595.91,1195.76 717.06,1316.91 1564.64,1316.91 v1(2174.79,706.77)
  Bottom Layer w8: R206.2@2174.79,665.15 v1(2174.79,706.77)
NetR207_2: R207.2 U31.12 | length 2043.4
  Top Layer w8: U31.12@576.23,1158.1 576.23,1203.46 703.29,1330.52 1597.36,1330.52 2224.79,703.1 R207.2@2224.79,666.14
NetR208_1: R208.1 U32.T4 | length 22.3
  Top Layer w9.9: U32.T4@3541.01,3688.93 v2(3556.76,3673.18)
NetR209_2: R209.2 U32.R9 | length 190.3
  Top Layer w9.9: U32.R9@3509.51,3846.41 v2(3525.26,3830.66)
  Bottom Layer w8: v2(3525.26,3830.66) 3525.26,3851.28 3548.93,3874.94 3633.48,3874.94 R209.2@3662.86,3874.94
NetR211_2: R211.2 U32.J15 | length 186.6
  Top Layer w9.9: v2(3304.79,4051.14) U32.J15@3320.54,4035.39
  Bottom Layer w8: v2(3304.79,4051.14) 3333.41,4079.76 R211.2@3333.41,4203.59
NetR214_2: R214.2 U32.B2 | length 253.2
  Top Layer w9.9: v2(3084.32,3610.19) U32.B2@3100.07,3625.94
  Bottom Layer w8: R214.2@3037.27,3398.73 3037.27,3509.05 3084.32,3556.1 v2(3084.32,3610.19)
NetR215_2: R215.2 U32.B1 | length 109.1
  Top Layer w8: R215.2@3061.31,3501.38 3061.31,3555.69 U32.B1@3100.07,3594.44
NetR216_2: R216.2 U32.D3 | length 452.1
  Top Layer w9.9: v2(3147.31,3641.69) U32.D3@3163.06,3657.44
  PWR/SIG_1 w4.5: 3131.16,3625.54 v2(3147.31,3641.69)
  PWR/SIG_1 w6: 3131.16,3625.54 3131.16,3483.24 3120.04,3472.11 3120.04,3394.86 3167.94,3346.95 3167.94,3313.21 3185.02,3296.13 v5(3208.39,3296.13)
  Bottom Layer w8: v5(3208.39,3296.13) R216.2@3231.07,3296.13
NetR217_2: R217.2 U32.D2 | length 237.7
  Top Layer w9.9: v2(3147.31,3610.19) U32.D2@3163.06,3625.94
  Bottom Layer w8: R217.2@3137.71,3398.73 3137.71,3509.53 3147.31,3519.13 v2(3147.31,3610.19)
NetR218_2: R218.2 U32.C2 | length 245.4
  Top Layer w9.9: v2(3115.81,3610.19) U32.C2@3131.56,3625.94
  Bottom Layer w8: R218.2@3087.67,3398.73 3087.67,3514.52 3115.81,3542.66 v2(3115.81,3610.19)
NetR219_2: R219.2 U32.C1 | length 101.3
  Top Layer w8: R219.2@3111.6,3501.38 3111.6,3574.48 U32.C1@3131.56,3594.44
NetR220_2: R220.2 U32.E2 | length 350.4
  Top Layer w8: v5(3207.74,3331.46) R220.2@3231.07,3331.46
  Top Layer w9.9: v2(3178.81,3610.19) U32.E2@3194.55,3625.94
  PWR/SIG_1 w4: 3161.83,3582.48 3178.81,3599.45 v2(3178.81,3610.19)
  PWR/SIG_1 w6: 3161.83,3582.48 3161.83,3510.44 3181.9,3490.38 3181.9,3368.96 3207.74,3343.12 v5(3207.74,3331.46)
NetR223_2: R223.2 U32.K17 | length 293.9
  Top Layer w9.9: v1(3232.43,4308.34) R223.2@3232.43,4329.73 ; U32.K17@3352.03,4098.38 v2(3367.78,4114.13)
  SIG_1 w3.6: v1(3232.43,4308.34) 3232.43,4261.14 3333.97,4159.6 3333.97,4147.94 v2(3367.78,4114.13)
NetR224_2: R224.2 U32.E3 | length 507.9
  Top Layer w9.9: v2(3178.81,3641.69) U32.E3@3194.55,3657.44
  PWR/SIG_1 w4.5: 3147.24,3565.14 3147.24,3589.72 3162.59,3605.07 3162.59,3625.47 v2(3178.81,3641.69)
  PWR/SIG_1 w6: 3147.24,3565.14 3147.24,3475.32 3132.28,3460.35 3132.28,3400.82 3182.96,3350.14 3182.96,3326.02 3195.47,3313.51 3218.24,3313.51 3229.39,3324.66 3229.39,3345.78 v5(3208.39,3366.78)
  Bottom Layer w8: v5(3208.39,3366.78) R224.2@3231.07,3366.78
NetR225_2: R225.2 U32.K18 | length 288.7
  Top Layer w9.9: R225.2@3199.18,4329.73 3199.18,4303.7 3214.62,4288.27 3258.16,4288.27 3299.5,4246.93 3299.5,4212.02 3343.47,4168.05 3352.03,4159.48 3352.03,4158.4 U32.K18@3352.03,4129.88
NetR226_2: R226.2 U32.J18 | length 310.5
  Top Layer w9.9: R226.2@3132.67,4329.73 3132.67,4309.22 3174.39,4267.51 3230.43,4267.51 3271.48,4226.46 3271.48,4192.63 3320.54,4143.57 U32.J18@3320.54,4129.88
NetR227_2: R227.2 U32.D1 | length 101
  Top Layer w8: R227.2@3161.13,3501.38 3161.13,3537.65 3152.51,3546.27 3152.51,3583.89 U32.D1@3163.06,3594.44
NetR228_2: R228.2 U32.J17 | length 346.8
  Top Layer w9.9: v1(3099.42,4308.34) R228.2@3099.42,4329.73 ; v2(3304.79,4114.13) U32.J17@3320.54,4098.38
  SIG_1 w3.6: v1(3099.42,4308.34) 3140.23,4308.34 3304.79,4143.78 v2(3304.79,4114.13)
NetR229_2: R229.2 U32.E4 | length 328.7
  Top Layer w8: v5(3207.74,3402.11) R229.2@3231.07,3402.11
  Top Layer w9.9: v2(3178.81,3673.18) U32.E4@3194.55,3688.93
  PWR/SIG_1 w4.5: v2(3178.81,3673.18) 3194.81,3657.18 3194.81,3415.04
  PWR/SIG_1 w6: 3194.81,3415.04 v5(3207.74,3402.11)
NetR230_2: R230.2 U32.K16 | length 353
  Top Layer w9.9: v1(3165.93,4308.34) R230.2@3165.93,4329.73 ; U32.K16@3352.03,4066.88 v2(3367.78,4082.63)
  SIG_1 w3.6: v1(3165.93,4308.34) 3320.3,4153.96 3320.3,4130.11 v2(3367.78,4082.63)
NetR231_2: R231.2 U32.K15 | length 356
  Top Layer w9.9: v1(3265.69,4308.34) R231.2@3265.69,4329.73 ; U32.K15@3352.03,4035.39 v2(3367.78,4051.14)
  SIG_1 w3.6: v1(3265.69,4308.34) 3265.69,4245.8 3383.31,4128.18 3383.31,4066.66 v2(3367.78,4051.14)
NetR232_2: R232.2 U32.M16 | length 323.2
  Top Layer w9.9: v1(3332.19,4308.34) R232.2@3332.19,4329.73 ; U32.M16@3415.03,4066.88 v2(3430.77,4082.63)
  SIG_1 w3.6: v1(3332.19,4308.34) 3355.73,4284.8 3355.73,4234.21 3446.46,4143.49 3446.46,4098.32 v2(3430.77,4082.63)
NetR233_2: R233.2 U32.M15 | length 480.8
  Top Layer w9.9: v1(3365.45,4308.34) R233.2@3365.45,4329.73 ; U32.M15@3415.03,4035.39 v2(3430.77,4051.14)
  SIG_1 w3.6: v1(3365.45,4308.34) 3390.3,4333.19 3467.68,4333.19 3483.24,4317.63 3483.24,4285.74 3477.84,4280.34 3477.84,4073.62 3471.08,4066.85 3446.49,4066.85 v2(3430.77,4051.14)
NetR234_2: R234.2 U32.H17 | length 390.4
  Top Layer w9.9: v1(3032.91,4308.34) R234.2@3032.91,4329.73 ; v2(3273.29,4114.13) U32.H17@3289.04,4098.38
  SIG_1 w3.6: v1(3032.91,4308.34) 3066.43,4274.82 3145.49,4274.82 3225.17,4195.14 3236.52,4195.14 3273.29,4158.37 v2(3273.29,4114.13)
NetR235_2: R235.2 U32.H16 | length 444
  Top Layer w9.9: v1(2999.66,4308.34) R235.2@2999.66,4329.73 ; v2(3273.29,4082.63) U32.H16@3289.04,4066.88
  SIG_1 w3.6: v1(2999.66,4308.34) 3046.21,4261.78 3132.68,4261.78 3219.16,4175.31 3237.34,4175.31 3257.66,4154.99 3257.66,4098.27 v2(3273.29,4082.63)
NetR236_2: R236.2 U32.L16 | length 323.7
  Top Layer w9.9: v1(3298.94,4308.34) R236.2@3298.94,4329.73 ; U32.L16@3383.53,4066.88 v2(3399.28,4082.63)
  SIG_1 w3.6: v1(3298.94,4308.34) 3298.94,4268.86 3414.73,4153.07 3414.73,4098.09 v2(3399.28,4082.63)
NetR237_2: R237.2 U32.H18 | length 334.3
  Top Layer w9.9: R237.2@3066.17,4329.73 3066.17,4310.88 3128.44,4248.6 3200.39,4248.6 3220.75,4228.25 3220.75,4198.17 3260.52,4158.4 U32.H18@3289.04,4129.88
NetR240_2: R240.2 U32.C4 | length 155.1
  Top Layer w9.9: v2(3115.81,3673.18) U32.C4@3131.56,3688.93
  Bottom Layer w5: R240.2@2992.69,3696.72 3032,3696.72 3039.76,3688.96 3100.04,3688.96 v2(3115.81,3673.18)
NetR241_1: R241.1 U32.U17 | length 311.6
  Top Layer w9.9: U32.U17@3572.51,4098.38 v2(3588.25,4114.13) ; v1(3764.48,4308.34) R241.1@3764.48,4329.73
  SIG_1 w3.6: v2(3588.25,4114.13) 3588.25,4132.11 3605.49,4149.34 cw(c3619.75,4145.62) 3616.03,4159.88 v1(3764.48,4308.34)
NetR242_1: R242.1 U32.T17 | length 324.5
  Top Layer w9.9: U32.T17@3541.01,4098.38 v2(3556.76,4114.13) ; v1(3731.28,4297.49) R242.1@3731.26,4329.7
  SIG_1 w3.6: v2(3556.76,4114.13) 3556.76,4147.45 3706.8,4297.49 v1(3731.28,4297.49)
NetR243_1: R243.1 U32.U18 | length 251.8
  Top Layer w9.9: U32.U18@3572.51,4129.88 3697.98,4255.35 R243.1@3697.98,4329.73
NetR244_1: R244.1 U32.T18 | length 251.1
  Top Layer w9.9: U32.T18@3541.01,4129.88 3664.72,4253.59 R244.1@3664.72,4329.73
NetR245_1: R245.1 U32.R18 | length 270.2
  Top Layer w9.9: U32.R18@3509.51,4129.88 3509.51,4180.39 3500.45,4189.45 3500.45,4250.84 3518.85,4269.23 3563.33,4269.23 3598.22,4304.12 R245.1@3598.22,4329.73
NetR246_1: R246.1 U32.R17 | length 281.9
  Top Layer w9.9: U32.R17@3509.51,4098.38 v2(3525.26,4114.13) ; v1(3631.47,4308.34) R246.1@3631.47,4329.73
  SIG_1 w3.6: v2(3525.26,4114.13) 3525.26,4147.61 3631.47,4253.82 v1(3631.47,4308.34)
NetR247_1: R247.1 U32.P16 | length 298.9
  Top Layer w9.9: U32.P16@3478.02,4066.88 v2(3493.77,4082.63) ; v1(3564.96,4308.34) R247.1@3564.96,4329.73
  SIG_1 w3.6: v2(3493.77,4082.63) 3509.54,4098.41 3509.54,4252.92 v1(3564.96,4308.34)
NetR248_1: R248.1 U32.P17 | length 253.6
  Top Layer w9.9: U32.P17@3478.02,4098.38 v2(3493.77,4114.13) ; v1(3531.71,4308.34) R248.1@3531.71,4329.73
  SIG_1 w3.6: v2(3493.77,4114.13) 3493.77,4270.39 v1(3531.71,4308.34)
NetR249_1: R249.1 U32.P18 | length 208.3
  Top Layer w9.9: U32.P18@3478.02,4129.88 3478.02,4284.99 3498.46,4305.43 R249.1@3498.46,4329.73
NetR250_1: R250.1 U32.N17 | length 242.2
  Top Layer w9.9: U32.N17@3446.52,4098.38 v2(3462.27,4114.13) ; v1(3465.2,4308.34) R250.1@3465.2,4329.73
  SIG_1 w3.6: v2(3462.27,4114.13) 3462.27,4160.8 3468.99,4167.51 3468.99,4285.88 3465.2,4289.67 v1(3465.2,4308.34)
NetR251_1: R251.1 U32.M18 | length 212.1
  Top Layer w9.9: R251.1@3398.7,4329.73 3398.7,4309.58 3409.18,4299.11 3409.18,4161.95 3421.68,4149.45 3421.68,4136.53 U32.M18@3415.03,4129.88
NetR252_1: R252.1 U32.N18 | length 210.3
  Top Layer w9.9: R252.1@3431.95,4329.73 3431.95,4304.97 3426.57,4299.59 3426.57,4167.18 3446.52,4147.23 U32.N18@3446.52,4129.88
NetR253_2: R253.2 U32.N2 | length 154
  Top Layer w9.9: U32.N2@3446.52,3625.94 v2(3462.27,3610.19)
  Bottom Layer w8: R253.2@3404.51,3502.36 3404.51,3552.43 3417.22,3565.14 v2(3462.27,3610.19)
NetR262_2: R262.2 U32.R3 | length 189.3
  Top Layer w9.9: U32.R3@3509.51,3657.44 v2(3525.26,3641.69)
  Bottom Layer w5: R262.2@3458.29,3502.36 3458.29,3517.96 3509.39,3569.05 3509.39,3625.81 v2(3525.26,3641.69)
NetR279_1: R279.1 SW1.8 | length 86.7
  Top Layer w8: SW1.8@4399.35,3925.48 4399.72,3925.11 R279.1@4485.88,3925.11
NetR280_1: R280.1 SW1.7 | length 86.8
  Top Layer w8: SW1.7@4399.35,3875.48 4399.96,3874.88 R280.1@4485.88,3874.88
NetR281_1: R281.1 SW1.6 | length 86.7
  Top Layer w8: SW1.6@4399.35,3825.48 4399.75,3825.08 R281.1@4485.88,3825.08
NetR282_1: R282.1 SW1.5 | length 87
  Top Layer w8: SW1.5@4399.35,3775.48 4400.59,3774.25 R282.1@4485.88,3774.25
NetR283_1: R283.1 U35.2 U35.3 | length 74.2
  Bottom Layer w8: U35.3@4311.55,3927.7 U35.2@4311.55,3943.45 4362.89,3943.45 R283.1@4367.93,3948.48
NetR292_2: R292.2 R293.2 U35.14 U35.15 | length 177.9
  Bottom Layer w8: R292.2@3956.93,3990.54 3956.93,3955.93 4013.22,3955.93 4025.7,3943.45 U35.15@4079.27,3943.45 U35.14@4079.27,3927.7
NetR295_1: R295.1 U32.V6 | length 68.7
  Top Layer w8: U32.V6@3604,3751.92 3672.27,3751.92 R295.1@3672.59,3752.25
NetR297_1: R297.1 U32.V7 | length 110.8
  Top Layer w8: U32.V7@3604,3783.42 3612.09,3775.33 3630.79,3775.33 3673.58,3818.12 R297.1@3673.58,3838.25
NetR310_2: R310.2 U32.T6 | length 313.5
  Top Layer w8: v1(3722.48,3853.44) R310.2@3722.48,3879.71
  Top Layer w9.9: U32.T6@3541.01,3751.92 v2(3556.76,3736.18)
  PWR/SIG_2 w4.5: v2(3556.76,3736.18) 3571.47,3750.89 3571.47,3837.44 3587.47,3853.44 v1(3722.48,3853.44)
NetR316_2: R316.2 U36.6 | length 69.1
  Top Layer w8: R316.2@2283.02,4361.72 2284.13,4360.61 U36.6@2351.69,4360.61
NetR317_2: R317.2 U36.4 | length 64.3
  Top Layer w8: R317.2@2526.73,4450.44 2526.88,4450.28 U36.4@2526.88,4386.2
NetR318_1: R318.1 U37.7 | length 75.4
  Top Layer w8: U37.7@2281.64,4188.41 2281.64,4263.48 R318.1@2281.89,4263.73
NetR319_1: R319.1 U36.2 | length 90.7
  Top Layer w8: U36.2@2526.88,4335.02 2575.71,4335.02 2582.18,4328.55 R319.1@2614.93,4328.55
NetR319_2: R319.2 U36.3 | length 91.5
  Top Layer w8: U36.3@2526.88,4360.61 2574.53,4360.61 2582.82,4368.9 R319.2@2614.93,4368.9
NetR321_2: R321.2 R322.2 U38.6 | length 87.1
  Top Layer w8: R322.2@3502.72,2705.37 3502.9,2705.19 R321.2@3530.89,2705.19 3531.53,2704.55 U38.6@3531.53,2646.59
NetR329_2: R329.2 U32.R1 | length 81.6
  Top Layer w8: U32.R1@3509.51,3594.44 3520.65,3583.3 3520.65,3561.22 3509.74,3550.31 R329.2@3509.74,3522
NetR333_1: R333.1 R334.2 R335.2 | length 95.1
  Bottom Layer w8: R335.2@3898.93,4919.94 3992.56,4919.94 R333.1@3993.63,4921.02
NetR339_2: R339.2 U41.19 | length 119.2
  Top Layer w8: U41.19@3812.24,5359.03 3857.55,5359.03 3871.52,5373.01 R339.2@3925.61,5373.01
NetR340_2: R340.2 U41.34 | length 270.7
  Top Layer w8: v5(3453.58,5282.19) 3476.79,5282.19 3478.69,5280.29 U41.34@3516.97,5280.29
  Bottom Layer w8: R340.2@3254.75,5271.31 3275.1,5271.31 3278.9,5267.51 3346.43,5267.51 3361.11,5282.19 v5(3453.58,5282.19)
NetR341_1: R341.1 U41.31 | length 147.6
  Top Layer w8: v5(3447.65,5317.99) 3447.72,5318.07 3447.72,5331.34 3455.73,5339.35 U41.31@3516.97,5339.35
  Bottom Layer w8: R341.1@3397.2,5345.11 3420.53,5345.11 v5(3447.65,5317.99)
NetR342_1: R342.1 U41.12 | length 118.9
  Top Layer w8: U41.12@3812.24,5221.24 3812.63,5221.63 3854.17,5221.63 3860.01,5227.47 v1(3863.32,5227.47)
  Bottom Layer w8: R342.1@3798.28,5226.88 3862.72,5226.88 v1(3863.32,5227.47)
NetR343_2: R343.2 SW5.1 SW5.3 | length 374.1
  Top Layer w8: SW5.3@2404.7,5433.74 SW5.1@2717.69,5433.74 2717.69,5393.64 2704.22,5380.16 R343.2@2704.22,5378.2
NetR371_1: R371.1 R373.1 | length 75.7
  Top Layer w5: R373.1@6833.7,4039.32 6833.7,4040.31 6849.9,4056.51 6850.07,4056.51 6854.23,4060.66 6854.23,4076.46 6850.23,4080.45 6849.97,4080.45 6839.23,4091.2 6839.23,4091.68 6833.99,4096.91 6833.77,4096.91 R371.1@6833.77,4097.64
NetR373_2: R373.2 U42.18 | length 92.5
  Top Layer w5: R373.2@6833.7,3976.33 6833.7,3975.35 6849.9,3959.15 6850.89,3959.15 6854.29,3955.74 U42.18@6854.29,3892.95
NetR374_1: R374.1 R375.1 U42.1 | length 212.1
  Top Layer w8: R374.1@6686.95,3838.02 R375.1@6686.95,3777.95 6745.19,3719.72 U42.1@6814.92,3719.72
NetR376_1: R376.1 R377.1 R475.1 | length 125.4
  Top Layer w8: R475.1@7094.39,4178.01 R475.1@7099.51,4183.13
  Top Layer w10: R376.1@7034.92,4126.46 R377.1@7034.92,4185.12 R475.1@7094.44,4185.12
NetR376_2: R376.2 U42.14 | length 256.4
  Top Layer w10: U42.14@6933.03,3892.95 6933.94,3893.86 6933.94,3920.09 6935.95,3922.11 6935.95,4102.1 6946.61,4112.76 6958.23,4112.76 R376.2@6971.93,4126.46
NetR377_2: R377.2 U42.15 | length 317
  Top Layer w10: U42.15@6913.35,3892.95 6914.25,3893.86 6914.25,3922.4 6922.02,3930.17 6922.02,4107.87 6929.85,4115.7 6929.85,4144.02 6970.95,4185.12 R377.2@6971.93,4185.12
NetR382_2: R382.2 U42.8 | length 131.6
  Top Layer w8: R382.2@6929.38,3597.8 6929.38,3626.74 6952.72,3650.07 U42.8@6952.72,3719.72
NetR387_2: R387.2 U43.27 | length 743.5
  Top Layer w8: U43.27@1491.46,4713.6 1493.42,4715.52 1534.63,4715.52 1935.68,5116.57 1935.68,5134.49 2000.57,5199.38 2000.57,5200.36 2015.27,5215.06 R387.2@2016.25,5215.06
NetR388_2: R388.2 U43.26 | length 716
  Top Layer w8: U43.26@1491.46,4688.6 1493.33,4690.43 1545.8,4690.43 1992.28,5136.91 2001,5136.91 R388.2@2015.7,5151.61
NetR390_2: R390.2 U43.25 | length 701.9
  Top Layer w8: U43.25@1491.46,4663.6 1567.24,4663.62 1988.7,5085.08 2008.2,5085.08 R390.2@2015.7,5092.57
NetR391_2: R391.2 U43.24 | length 687.8
  Top Layer w8: U43.24@1491.46,4638.6 1571.51,4638.62 1966.42,5033.53 R391.2@2015.7,5033.53
NetR392_2: R392.2 U43.23 | length 673.7
  Top Layer w8: U43.23@1491.46,4613.6 1599.24,4613.62 1960.11,4974.49 R392.2@2015.7,4974.49
NetR404_2: R404.2 U45.5 | length 64.4
  Top Layer w8: U45.5@2810.33,4604.27 2810.33,4626.1 v1(2820.5,4636.27)
  Bottom Layer w8: R404.2@2820.21,4664.37 2820.5,4664.09 v1(2820.5,4636.27)
NetR406_1: R406.1 R409.2 U45.9 | length 150.3
  Top Layer w10: R409.2@2680.71,4527.97 2712.06,4527.97 v1(2725.17,4541.08) 2738.29,4554.2 U45.9@2767.89,4554.2
  Bottom Layer w10: v1(2725.17,4541.08) 2746.35,4541.08 2749,4543.74 R406.1@2776.37,4543.74
NetR411_2: R411.2 U45.7 | length 85.4
  Top Layer w8: R411.2@2695.3,4622.54 2715.4,4622.54 2742.53,4595.41 U45.7@2769.49,4595.41
NetR413_2: R413.2 U47.5 | length 75.8
  Top Layer w8: U47.5@2629.83,4917.15 2651.7,4917.15 2663.09,4905.76 v1(2663.09,4893.66)
  Bottom Layer w8: v1(2663.09,4893.66) R413.2@2688.81,4893.66
NetR415_1: R415.1 U47.9 | length 94.9
  Top Layer w8: R415.1@2547.72,5041 2558.47,5030.25 2558.47,5007.69 2580,4986.16 2580,4959.84 U47.9@2579.76,4959.6
NetR417_1: R417.1 U47.7 | length 89.7
  Top Layer w8: U47.7@2620.97,4958 2619.47,4959.5 2619.47,4988.77 2644.08,5013.38 R417.1@2644.08,5036.89
NetR418_1: R418.1 R426.2 R434.2 U48.13 | length 454.5
  Top Layer w8: U48.13@5794.14,2955.64 5794.14,3015.85 5761.07,3048.93 5761.07,3236.99 5767.97,3243.9 5794.18,3243.9 R426.2@5797.39,3247.11 R434.2@5797.39,3307.26 R418.1@5797.39,3366.01
NetR419_1: R419.1 R427.2 R435.2 U48.14 | length 454.4
  Top Layer w8: R419.1@5696.18,3363.61 R435.2@5696.18,3304.92 R427.2@5696.18,3246.2 5724.25,3246.2 5734.69,3235.76 5734.69,3045.23 5768.55,3011.37 U48.14@5768.55,2955.64
NetR420_1: R420.1 R428.2 R436.2 U48.15 | length 251.3
  Top Layer w8: R420.1@5696.18,3187.59 R436.2@5696.18,3128.57 R428.2@5696.18,3068.62 5696.18,3039.13 5742.96,2992.35 U48.15@5742.96,2955.64
NetR421_1: R421.1 R429.2 R437.2 U48.12 | length 241.6
  Top Layer w8: R421.1@5797.39,3187.99 R437.2@5797.39,3128.13 R429.2@5797.39,3068.7 5797.39,3041.19 5819.73,3018.85 U48.12@5819.73,2955.64
NetR422_1: R422.1 R430.2 R438.2 U48.5 | length 220.4
  Top Layer w8: U48.5@5819.73,2727.3 5819.73,2681.22 5855.41,2645.53 5856.4,2645.53 R430.2@5859.4,2642.54 5859.4,2582.44 R438.2@5859.26,2582.31 R422.1@5859.31,2523.95 R422.1@5859.31,2523.95
NetR423_1: R423.1 R431.2 R439.2 U48.1 | length 271.5
  Top Layer w8: R423.1@5510.54,2798.89 R439.2@5570.05,2798.89 R431.2@5627.59,2798.89 5705.56,2798.89 5717.37,2787.08 U48.1@5717.37,2727.3
NetR424_1: R424.1 R432.2 R440.2 U48.2 | length 310.5
  Top Layer w8: R424.1@5621.98,2524.6 5622.53,2525.16 R440.2@5622.53,2583.4 5622.7,2583.56 R432.2@5622.7,2641.26 5622.7,2668.61 5633.84,2679.76 5732.33,2679.76 5742.96,2690.38 U48.2@5742.96,2727.3
NetR425_1: R425.1 R433.2 R441.2 U48.4 | length 203.6
  Top Layer w8: R433.2@5683.23,2640.75 5741.19,2640.75 R441.2@5741.46,2641.02 5741.6,2641.16 R425.1@5798.67,2641.16 5794.14,2645.68 U48.4@5794.14,2727.3
NetR443_2: R443.2 U49.1 | length 72.8
  Top Layer w8: R443.2@4835.91,4327.95 4836.2,4327.66 U49.1@4836.2,4255.27
NetR445_2: R445.2 U52.22 | length 75.9
  Top Layer w8: R445.2@5244.36,4249.48 5319.61,4249.48 U52.22@5320.04,4249.05
NetR449_2: R449.2 U54.1 | length 101.7
  Top Layer w8: R449.2@6493.37,3024.76 6493.37,2999.25 6537.52,2955.09 6549.47,2955.09 U54.1@6550.74,2953.82
NetR459_1: R459.1 R461.2 | length 79.6
  Top Layer w5: R461.2@7011.89,5230.14 7034.69,5252.94 7034.69,5268.06 R459.1@7011.89,5290.86
NetR460_1: R460.1 R462.2 | length 78.5
  Top Layer w5: R462.2@7068.34,5292.94 7046.78,5314.5 7046.78,5332.06 R460.1@7068.34,5353.62
NetR466_1: R466.1 U56.18 | length 245.3
  Top Layer w8: R466.1@7131.83,5300.15 7140.82,5291.16 7229.99,5291.16 7310.27,5210.88 U56.18@7340.14,5210.88
NetR466_2: R466.2 RNTC_1.1 | length 117.1
  Top Layer w8: RNTC_1.1@7129.36,5479.19 7129.36,5429.27 7129.36,5365.61 R466.2@7131.83,5363.14
NetR476_1: R476.1 U41.22 | length 297.7
  Top Layer w8: U41.22@3812.24,5418.09 3814.15,5419.99 3845.99,5419.99 3873.85,5447.85 3873.85,5491.9 3948.67,5566.72 R476.1@4022.53,5566.72
NetR479_2: R479.2 R482.2 U56.4 | length 298.3
  Top Layer w8: R479.2@7262.81,4875.04 R482.2@7357.65,4875.04 7357.65,4882.92 7383.3,4908.56 7383.3,4997.87 7399.19,5013.77 U56.4@7399.19,5061.27
NetTP6_1: TP6.1 U32.T5 | length 290.9
  Top Layer w9.9: U32.T5@3541.01,3720.43 v2(3556.76,3704.68)
  Bottom Layer w5: v2(3556.76,3704.68) 3572.39,3689.04 3604.14,3689.04 ; TP6.1@3646.41,3491.81 TP6.1@3646.48,3491.88
  Bottom Layer w8: 3604.14,3689.04 3646.48,3646.7 TP6.1@3646.48,3491.88
NetTP8_1: TP8.1 U41.24 | length 54.3
  Top Layer w8: U41.24@3812.24,5457.46 3812.24,5511.55 TP8.1@3812.36,5511.67
NetTP9_1: TP9.1 U41.25 | length 53.8
  Top Layer w8: U41.25@3516.97,5457.46 3516.97,5511.04 TP9.1@3517.1,5511.17
NetTP22_1: TP22.1 U43.22 | length 700.4
  Top Layer w9.9: U43.22@1491.46,4588.6 1439.18,4588.6 1423.88,4603.9 1423.88,4787.88 1686.06,5050.06 TP22.1@1757.78,5050.06
NetTP23_1: TP23.1 U52.7 | length 72.5
  Top Layer w8: U52.7@5548.39,4351.41 TP23.1@5620.91,4351.41
NetTP24_1: TP24.1 U52.17 | length 110.2
  Top Layer w8: TP24.1@5210.07,4376.44 5210.35,4376.72 5319.76,4376.72 U52.17@5320.04,4377
NetTP25_1: TP25.1 U51.10 | length 80.3
  Top Layer w8: U51.10@4710.5,4411.66 4710.6,4411.76 4790.62,4411.76 TP25.1@4790.72,4411.86
NetTP26_1: TP26.1 U51.14 | length 87.4
  Top Layer w8: TP26.1@4394.79,4437.25 U51.14@4482.15,4437.25
NetU7_1: U7.1 U8.4 | length 394.3
  Top Layer w8: U7.1@2047.82,2298.99 2278.13,2298.99 2364.67,2385.53 U8.4@2364.67,2427.14
NetU7_4: U7.4 U8.7 | length 430.4
  Top Layer w8: U7.4@2047.82,2448.99 2249.65,2448.99 2265.91,2465.25 2316.11,2465.25 2332.07,2481.21 2401.65,2481.21 2423.73,2459.14 U8.7@2423.73,2427.14
NetU7_6: U7.6 U8.9 | length 507.9
  Top Layer w8: U7.6@2047.82,2548.99 2082.89,2548.99 2104.77,2527.11 2104.77,2482.5 2120.48,2466.8 2245.58,2466.8 2273,2494.21 2425.87,2494.21 2443.41,2511.75 U8.9@2443.41,2545.25
NetU7_7: U7.7 U8.12 | length 387.6
  Top Layer w8: U7.7@2047.82,2598.99 2155.15,2598.99 2164.6,2608.43 2357.04,2608.43 2384.36,2581.11 U8.12@2384.36,2545.25
NetU51_23: U51.23 U52.23 U53.4 | length 917.1
  Top Layer w8: U51.23@4482.15,4206.93 v1(4526.59,4206.93) ; v1(5254.41,4203.7) 5274.16,4223.46 U52.23@5320.04,4223.46
  PWR/SIG_1 w6: v1(4526.59,4206.93) 4546.97,4186.55 4826.75,4186.55 4874.8,4234.6 5223.51,4234.6 v1(5254.41,4203.7)
  Bottom Layer w8: v1(4526.59,4206.93) 4556.27,4206.93 U53.4@4556.39,4206.81
nFAULT_DRV8145: R6.2 R9.2 R165.1 R166.1 U28.1 U29.1 U54.9 | length 8822.9
  Top Layer w8: v1(2993.29,1054.59) 3019.74,1028.14 3019.74,1002.88 3030.62,992 R165.1@3059.14,992 3059.45,991.68 U28.1@3059.45,911.4 ; R9.2@6212.7,3280.74 R6.2@6212.7,3229.39 v1(6240.42,3229.39) ; U54.9@6708.22,2953.82 6708.22,2726.52 6715.85,2718.89 v1(6715.85,2715.64) 7242.72,2715.64 7264.16,2694.21 7316.68,2694.21 7330.12,2680.76 7330.12,2665.78 7340.25,2655.65 R166.1@7369.31,2655.65 7369.31,2615.03 7383.31,2601.03 U29.1@7383.31,2586.43
  SIG_3 w6: v1(2993.29,1054.59) 3164.82,883.07 5924.81,883.07 6176.46,1134.72 6548.63,1134.72 6667.36,1253.46 6716.99,1253.46 6775.6,1312.07 6775.6,1641.57 7582.75,2448.72 7582.75,2693.73 7452.44,2824.04 7031.16,2824.04 6972.93,2882.27 6868.11,2882.27 ; v1(6240.42,3229.39) 6352.57,3229.39 6555.39,3026.57 6744.55,3026.57 6868.11,2903 6868.11,2882.27 ; v1(6715.85,2715.64) 6716.1,2715.88 6716.1,2730.26 6868.11,2882.27
nFAULT_TPS1HC04: R13.2 R137.2 U54.19 | length 3172.8
  Top Layer w8: R13.2@6217.07,2876.62 v1(6243.32,2876.62) ; U54.19@6806.65,3127.05 6806.65,3188.55 6814.86,3196.77 v2(6814.86,3199.47)
  Bottom Layer w8: v1(6243.32,2876.62) 6472.58,2876.62 6637.59,3041.63 6657.02,3041.63 v2(6814.86,3199.47) 7463.28,3847.9 7463.28,4459.74 7429.41,4493.61 7429.41,4796.55 7509.46,4876.6 7509.46,4991.06 7536.97,5018.57 7608.68,5018.57 7664.09,4963.16 7694.13,4963.16 R137.2@7721.75,4935.54
nFAULT_TPS1HC30: R5.2 R121.1 U54.20 | length 1936.9
  Top Layer w8: R5.2@6217.07,2928.84 v1(6243.32,2928.84) ; v2(6776.91,3215.99) 6776.91,3213.29 6786.96,3203.24 U54.20@6786.96,3127.05 ; v5(7097.37,2980.54) 7099.53,2980.54 7103.59,2976.48 R121.1@7139.65,2976.48
  Bottom Layer w8: v2(6776.91,3215.99) 6752.31,3215.99 6740.87,3204.56 6740.87,3194.31 6741.26,3193.92 6741.26,3179.89 6566.98,3005.61 6320.09,3005.61 v1(6243.32,2928.84) 6225.38,2910.9 6225.38,2869.19 6235.89,2858.68 6500.18,2858.68 6730.95,3089.46 7022.99,3089.46 7098.57,3013.88 7098.57,2980.54 v5(7097.37,2980.54)
nFAULT_TPS2HC08: R11.2 R125.2 U54.16 | length 4361.1
  Top Layer w8: R11.2@6217.07,2824.41 v1(6243.32,2824.41) ; U54.16@6846.02,2953.82 6846.29,2953.55 6846.29,2919.43 6862.94,2902.78 6883.14,2902.78 v1(6885.05,2900.86)
  Top Layer w10: v1(4326.01,906.05) 4355.98,906.05 R125.2@4366.13,895.9
  Bottom Layer w8: v1(4326.01,906.05) 4326.01,958.76 4281.79,1002.97 4281.79,1089.74 4490.52,1298.47 4490.52,2070.34 4537.58,2117.39 4537.58,2347.96 4619.2,2429.59 5525.83,2429.59 5754.4,2658.16 5997.04,2658.16 6163.28,2824.41 v1(6243.32,2824.41) 6482.78,2824.41 6640.02,2981.64 6804.27,2981.64 v1(6885.05,2900.86)
nFAULT_TPS4HC120: R8.2 R145.1 U55.17 | length 3386.4
  Top Layer w8: U55.17@5228.95,2888.31 5228.95,2868.18 v1(5241.65,2855.48) ; v2(6388.02,3360.75) 6457.41,3430.14 R8.2@6457.41,3494.26
  SIG_1 w6: v5(4929.94,1314.75) 4903.84,1340.85 4903.84,1633.91 5241.65,1971.72 v1(5241.65,2855.48) 5314,2855.48 5387.29,2928.78 6087.41,2928.78 6217.07,3058.44 6217.07,3230 6347.83,3360.75 v2(6388.02,3360.75)
  Bottom Layer w8: v5(4929.94,1314.75) 4931.31,1314.75 4956.81,1289.25 R145.1@4956.81,1288.27
nFLT_DRV8714: R12.2 R155.2 U27.9 U54.26 | length 3220.9
  Top Layer w8: R12.2@6212.7,3178.83 v1(6260.87,3178.83) ; v1(6629.71,1306.79) R155.2@6663.53,1306.79 6687.38,1306.79 6704.2,1289.97 U27.9@6733.89,1289.97 ; U54.26@6668.85,3127.05 6669.02,3127.22 6669.02,3167.53 v2(6669.18,3167.69)
  SIG_1 w6: v1(6260.87,3178.83) 6284.84,3154.86 6656.34,3154.86 v2(6669.18,3167.69)
  SIG_1 w8: v1(6260.87,3178.83) 6304.38,3222.34 6651.4,3222.34 6755.48,3118.26 6755.48,3092.84 6887.82,2960.49 6887.82,2923.47 6902.99,2908.29 6902.99,2893.43 6887.82,2878.26 6887.82,2042.61 6562.48,1717.28 6562.48,1374.01 v1(6629.71,1306.79)
nINT_TCAL9539_26: R451.2 U51.4 U55.22 | length 2036.2
  Top Layer w8: U51.4@4710.5,4258.11 v1(4754.94,4258.11) ; U55.22@5274.23,2972.96 5294.92,2972.96 v1(5309.16,2987.19) 5329.85,2987.19 5344.09,3001.43 R451.2@5344.09,3027.05
  SIG_1 w6: v1(4754.94,4258.11) 5034.21,4258.11 5134.9,4157.42 5134.9,4068.68 4896.23,3830.01 4896.23,3539.6 5217.61,3218.22 5217.61,3185.37 5206.8,3174.56 5206.8,3066.15 5285.76,2987.19 v1(5309.16,2987.19)
nSLEEP_DRV8145: R172.1 U27.8 U28.3 U29.3 U54.7 | length 6678.4
  Top Layer w8: v1(3020.94,883.76) 3032.67,872.03 U28.3@3059.45,872.03 ; v1(5996.28,881.97) R172.1@6032.96,881.97 ; U54.7@6668.85,2953.82 6668.85,2709.66 v1(6646.05,2686.85) 6663.23,2669.67 7131.66,2669.67 7254.27,2547.06 U29.3@7383.31,2547.06 ; v1(6705.34,1317.34) 6713.03,1309.65 U27.8@6733.89,1309.65
  Bottom Layer w8: v1(3020.94,883.76) 3037.01,867.7 3305.47,867.7 3319.74,881.97 v1(5996.28,881.97) 6059.88,945.57 6059.88,1003.05 6190.22,1133.39 6665.8,1133.39 6730.49,1198.08 6730.49,1253.82 6705.34,1278.97 v1(6705.34,1317.34) 6705.34,1364.74 6730.49,1389.88 6730.49,1435.56 6624.45,1541.59 6624.45,1873.63 6662.91,1912.09 6662.91,2555.72 6701.37,2594.18 6701.37,2631.53 v1(6646.05,2686.85)
nWKRQ_CAN_MCU: U51.21
nWKRQ_CAN_MUX: U49.2 U51.3 | length 127
  Top Layer w8: U51.3@4710.5,4232.52 4712.02,4234.05 4834.67,4234.05 U49.2@4836.2,4235.58
OA3_ED/SPI_CS_ETH3: J11.11 J16.6 U32.F18 | length 4263.1
  Top Layer w8: J11.11@411.42,5755.78 v1(449.81,5755.78)
  Top Layer w9.9: v2(3210.3,4145.62) U32.F18@3226.05,4129.88
  SIG_3 w4.5: v1(449.81,5755.78) 418.97,5786.62 380.35,5786.62 342.16,5824.81 342.16,5908.14 465.42,6031.39 641.15,6031.39 1346.14,5326.4 2197.35,5326.4 J16.6@2268.87,5254.88 2408.37,5115.38 2408.37,4691.14 2595.67,4503.84 2665.5,4503.84 2900.25,4269.09 3144.96,4269.09 3210.3,4203.75 v2(3210.3,4145.62)
OA3_RX_ETH3: J11.13 U32.G16 | length 3683
  Top Layer w8: v1(373.03,5724.28) J11.13@411.42,5724.28
  Top Layer w9.9: v2(3241.8,4082.63) U32.G16@3257.55,4066.88
  SIG_1 w4: v1(373.03,5724.28) 431.56,5665.75 452.09,5665.75 475.46,5642.39 475.46,5605.96 761.24,5320.18 1621.68,5320.18 1898.18,5043.68 1945.93,5043.68 2158.34,4831.26 2158.34,4742.05 2275.68,4624.71 2364.34,4624.71 2577.16,4411.88 2732.67,4411.88 3046.17,4098.38 3226.05,4098.38 v2(3241.8,4082.63)
OA3_TX_ETH3: J11.15 U32.E17 | length 3521.3
  Top Layer w8: J11.15@411.42,5692.79 v1(449.81,5692.79)
  Top Layer w9.9: v2(3178.81,4114.13) U32.E17@3194.55,4098.38
  SIG_1 w4.5: v1(449.81,5692.79) 492.45,5650.14 492.45,5606.59 769.82,5329.23 1624.2,5329.23 1901.57,5051.86 1949.32,5051.86 2166.53,4834.65 2166.53,4745.44 2279.07,4632.89 2367.73,4632.89 2580.02,4420.61 2738.72,4420.61 3028.68,4130.65 3162.28,4130.65 v2(3178.81,4114.13)
OSPI0_CLK_9: R253.1 R276.2 U33.B2 | length 1136.8
  Top Layer w8: R276.2@3895.35,2628.34 3895.35,2666.78 v1(3931.99,2703.42) U33.B2@3968.63,2740.06
  PWR/SIG_1 w6: v1(3404.51,3438.87) 3684.72,3158.67 3684.72,3071.21 3812.1,2943.83 3842.29,2943.83 3931.99,2854.13 v1(3931.99,2703.42)
  Bottom Layer w8: v1(3404.51,3438.87) R253.1@3404.51,3462.01
OSPI0_CSN0_9: R264.2 U32.P1 U33.C2 | length 1676.5
  Top Layer w8: R264.2@3985.21,2637.39 v1(3985.21,2717.27) U33.C2@4008,2740.06
  Top Layer w9.9: U32.P1@3478.02,3594.44 v2(3493.77,3578.69)
  PWR/SIG_1 w6: v2(3493.77,3578.69) 3493.77,3459.97 3498.29,3455.44 3498.29,3427.45 3617.47,3308.27 3641.56,3308.27 3651.52,3298.31 3651.52,3280.74 3849.73,3082.54 3966.33,3082.54 3978.94,3069.93 3978.94,2980.47 3982.45,2976.96 4002.71,2976.96 4013.25,2966.41 4013.25,2951.5 3996.23,2934.48 3996.23,2914.91 4114.47,2796.67 4138.94,2796.67 4206.19,2729.43 4206.19,2697.45 4189.44,2680.69 4088.13,2680.69 4051.56,2717.27 v1(3985.21,2717.27)
OSPI0_D0_9: R261.1 R266.2 R284.1 U32.N1 | length 1219
  Top Layer w9.9: U32.N1@3446.52,3594.44 v2(3462.27,3578.69)
  SIG_1 w6: v2(3462.27,3578.69) 3462.29,3553.99 3465.8,3550.48 3573.54,3550.48 3727.97,3396.05 3783.55,3396.05 v2(3799.49,3380.11)
  Bottom Layer w8: v2(3799.49,3380.11) 3799.56,3380.05 R284.1@3799.56,3353.08 ; R284.1@3799.65,3353.1 3826.67,3353.1 3845.63,3334.14 3845.63,3232.73 4050.42,3027.94 4050.42,2829 4079.76,2799.66 4079.76,2783.5 R261.1@4114.12,2783.51
OSPI0_D1_9: R260.1 R267.2 R285.1 U32.N4 | length 1773.5
  Top Layer w8: v1(4000.15,2571.37) R260.1@4027.24,2571.37 4027.58,2571.71 R267.2@4027.58,2609.93
  Top Layer w9.9: U32.N4@3446.52,3688.93 v2(3462.27,3673.18)
  PWR/SIG_1 w4.5: v2(3462.27,3673.18) 3476.61,3658.85 3533.1,3658.85 3541.26,3650.69 3541.26,3583.49
  PWR/SIG_1 w6: 3541.26,3583.49 3790.49,3334.26 3875.51,3334.26 4221.27,2988.5 4221.27,2985.29 4226.78,2979.78 4226.78,2691.06 4172.18,2636.46 4065.24,2636.46 v1(4000.15,2571.37)
  Bottom Layer w8: v2@3742.72,3379.68 3743.87,3378.53 3743.87,3354.19 R285.1@3745.02,3353.04
  other v2: 3744.63,3380.11
OSPI0_D2_9: R259.1 R268.2 U32.M4 | length 1123.3
  Top Layer w8: v1(3928.96,2970.19) R259.1@3960.94,2970.19 3960.52,2969.77 R268.2@3960.52,2925.84
  Top Layer w9.9: U32.M4@3415.03,3688.93 v2(3430.77,3673.18)
  PWR/SIG_1 w4.5: 3411.94,3565.14 3382.94,3594.14 3382.94,3650.91 3389.02,3656.98 3414.57,3656.98 v2(3430.77,3673.18)
  PWR/SIG_1 w6: 3411.94,3565.14 3424.21,3552.87 3424.21,3441.64 3699.63,3166.21 3699.63,3096.04 3825.48,2970.19 v1(3928.96,2970.19)
OSPI0_D3_9: R258.1 R269.2 U32.P3 | length 1115.5
  Top Layer w8: v1(4081.81,2961.38) R258.1@4108.13,2961.38 4108.4,2961.11 R269.2@4108.4,2925.84
  Top Layer w9.9: U32.P3@3478.02,3657.44 v2(3493.77,3641.69)
  PWR/SIG_1 w4.5: v2(3493.77,3641.69) 3509.28,3626.17 3509.28,3586.16 3510.02,3585.43 3510.02,3571.96 3509.28,3571.23 3509.28,3435.5
  PWR/SIG_1 w6: 3509.29,3435.48 3625.51,3319.27 3646.11,3319.27 3672.54,3292.84 3672.54,3284.23 3863.23,3093.54 3970.89,3093.54 3989.94,3074.49 3989.94,3005.28 4024.25,2970.97 4024.25,2964.9 4027.77,2961.38 v1(4081.81,2961.38)
OSPI0_D4: R257.1 R270.2 U32.M1 | length 1111.9
  Top Layer w8: U32.M1@3415.03,3594.44 3483.44,3526.03 3483.44,3354.3 3680.51,3157.24 3945.95,3157.24 4053.81,3049.38 4053.81,2977.15 4038,2961.33 R257.1@4021.42,2961.33 4021.42,2926.03 R270.2@4021.23,2925.84
OSPI0_D5: R256.1 R271.2 U32.L1 | length 1325.8
  Top Layer w8: U32.L1@3383.53,3594.44 3384.72,3593.25 3384.72,3541.44 3388.57,3537.58 v5(3388.57,3535.42) ; v5(3909.1,3279.55) 3910.63,3278.02 3916.4,3278.02 3978.9,3215.51 4144.29,3050.12 4144.29,2864.81 4169.2,2839.91 R256.1@4192.38,2839.91 R271.2@4192.38,2805.59
  SIG_1 w6: v5(3388.57,3535.42) 3509.2,3414.79 3509.2,3369.73 3603.6,3275.33 3902.18,3275.33 3906.39,3279.55 v5(3909.1,3279.55)
OSPI0_D6: R255.1 R272.2 U32.L2 | length 1378.9
  Top Layer w8: v1(4165.39,2713.92) R272.2@4192.38,2713.92 R255.1@4192.38,2677.97
  Top Layer w9.9: U32.L2@3383.53,3625.94 v2(3399.28,3610.19)
  PWR/SIG_1 w4.5: v2(3399.28,3610.19) 3436.35,3573.12 3436.35,3486.27
  PWR/SIG_1 w6: 3436.35,3486.27 3476.29,3446.33 3476.29,3405.11 3714.15,3167.26 3733.89,3167.26 3791.83,3109.32 3791.83,3086.57 3817.87,3060.54 3911.06,3060.54 3951.51,3020.08 3951.51,2903.98 4105.48,2750.01 4141.57,2713.92 v1(4165.39,2713.92)
OSPI0_D7: R254.1 R273.2 U32.K1 | length 1432.2
  Top Layer w8: R273.2@4112.77,2634.13 v1(4112.77,2661.47) ; R254.1@4112.78,2599.2 R273.2@4112.77,2634.13
  Top Layer w9.9: U32.K1@3352.03,3594.44 v2(3367.78,3578.69)
  PWR/SIG_1 w6: v2(3367.78,3578.69) 3367.78,3431.92 3659.47,3140.23 3659.47,3062.59 3800.52,2921.53 3831.58,2921.53 3865.88,2887.24 3865.88,2731.35 3935.76,2661.47 v1(4112.77,2661.47)
OSPI0_DQS: R263.1 R274.2 R275.2 U32.M3 | length 1158.1
  Top Layer w9.9: U32.M3@3415.03,3657.44 v2(3430.77,3641.69)
  PWR/SIG_1 w4.5: v2(3430.77,3641.69) 3445.85,3626.61 3445.85,3491.58
  PWR/SIG_1 w6: 3446.6,3491.58 3487.29,3450.88 3487.29,3414.45 3682.2,3219.55 3697.16,3219.55 3845.17,3071.54 3915.61,3071.54 3962.51,3024.64 3962.51,2962.47 3966.03,2958.96 v1(3995.25,2958.96)
  Bottom Layer w8: v1(3995.25,2958.96) 4007.9,2946.31 R275.2@4007.9,2919.82 4007.81,2919.72 4007.81,2864.49 R274.2@4007.81,2811.75
OSPI0_ECS: R265.1 U32.H1 U33.A5 | length 1165.7
  Top Layer w8: v1(3829.54,2889.8) R265.1@3829.54,2858.54 3829.91,2858.18 U33.A5@3929.26,2858.18
  Top Layer w9.9: v2(3273.29,3578.69) U32.H1@3289.04,3594.44
  PWR/SIG_1 w4.5: v2(3273.29,3578.69) 3315.16,3578.69 3328.72,3565.14
  PWR/SIG_1 w6: 3328.72,3565.14 3346.97,3546.89 3346.97,3412.11 3616.21,3142.87 3616.21,2986.24 3712.65,2889.8 v1(3829.54,2889.8)
OSPI0_RESET_OUTn: R277.1 U32.J1 U34.1 | length 728.3
  Top Layer w8: U32.J1@3320.54,3594.44 3320.54,3573.46 3328.86,3565.14 3378.48,3515.52 3378.48,3392.95 3669.57,3101.86 R277.1@3700.83,3101.86 3700.6,3101.64 U34.1@3700.6,3042.06
OSPI0_RST#_9: R278.1 U33.A4 U34.4 | length 253.3
  Top Layer w8: U34.4@3808.87,2967.25 3809.51,2967.89 R278.1@3853.52,2967.89 3853.52,2938.52 3903.41,2888.63 3926.04,2888.63 3947,2867.67 3947,2850.24 3929.26,2832.5 U33.A4@3929.26,2818.81
OUT0_LS_DRV81242: C125.1 J6.5 U30.6 | length 999.6
  Top Layer w20: U30.6@6416.74,933.92 6417.88,932.78 6456.15,932.78 6463.35,925.57 6491.31,925.57
  Top Layer w30: 6491.31,925.57 6635.53,925.57 6669.27,891.84 6669.27,750.81 6507.3,588.84 C125.1@6507.3,550 J6.5@6507.3,229.26
OUT1_DRV8145: C118.2 J4.1 U29.5 U29.6 U29.8 U29.9
  other v1: 8157.98,2353.03 8457.98,2353.03 7658.19,2389.07 7758.19,2389.07 8107.98,2403.03 8207.98,2403.03 8407.98,2403.03 8507.98,2403.03 7708.19,2439.07 8157.98,2453.03 8457.98,2453.03 7658.19,2489.07 7758.19,2489.07 8107.98,2503.03 8207.98,2503.03 8407.98,2503.03 8507.98,2503.03 8157.98,2553.03 8457.98,2553.03 8107.98,2603.03 8207.98,2603.03 8407.98,2603.03 8507.98,2603.03 8157.98,2653.03 8457.98,2653.03
  other v4: 7407.92,2453.55 7486.66,2453.55 7407.92,2485.05 7486.66,2485.05
OUT1_DRV8245: C115.2 J2.2 U28.8 U28.9
  other v1: 3173.25,329.26 3273.25,329.26 3223.25,379.26 3173.25,429.26 3273.25,429.26
  other v4: 3162.8,778.52 3162.8,810.02
OUT1_DRV8714: C104.1 J7.1 NT2.2 Q8.1 Q8.2 Q8.3 Q10.5 Q10.6 Q10.7 Q10.8 Q10.9@7857.63,800.11
  other v1: 8156.25,645.75 8456.25,645.75 8106.25,695.75 8206.25,695.75 8406.25,695.75 8506.25,695.75 8156.25,745.75 8456.25,745.75 8106.25,795.75 8206.25,795.75 8406.25,795.75 8506.25,795.75 8156.25,845.75 8456.25,845.75 8106.25,895.75 8206.25,895.75 8406.25,895.75 8506.25,895.75 8156.25,945.75 8456.25,945.75
OUT1_LS_DRV81242: C126.1 J6.4 U30.19 | length 1192.1
  Top Layer w20: 6104.76,933.92 U30.19@6188.4,933.92
  Top Layer w30: 6104.76,933.92 5985.19,933.92 5956.35,905.08 5956.35,726.93 6006.19,677.09 6117.5,677.09 6176.13,618.46 6279.33,618.46 6310.45,587.34 C126.1@6310.45,550 J6.4@6310.45,229.26
OUT1_TLIN1024A: C50.1 J25.3 R66.1 U11.22 | length 1523.8
  Bottom Layer w15: J25.3@791.28,2848.11 841.66,2898.5 932.77,2898.5 1323.57,3289.3 1573.09,3289.3 1827.29,3543.49 C50.1@2027.02,3543.49
OUT1_TPS2HC08: C76.1 J10.2 U24.1
  other v1: 4560.59,295.25 4660.59,295.25 4610.59,345.25 4560.59,395.25 4660.59,395.25 4584.27,584.05 4684.27,584.05 4634.27,634.05 4584.27,684.05 4684.27,684.05
OUT1_TPS4HC120: C85.1 J9.4 U25.27 U25.28 | length 708
  Top Layer w30: 5288.57,860.41 5288.57,798.57 5472.03,615.11 C85.1@5472.03,550 J9.4@5472.03,228.37
OUT2_DRV8245: C119.2 J2.1 U28.5 U28.6
  other v1: 2973.25,329.26 3073.25,329.26 3023.25,379.26 2973.25,429.26 3073.25,429.26
  other v4: 3084.06,778.52 3084.06,810.02
OUT2_DRV8714: C107.1 J7.2 NT1.1 R154.2
  other v1: 8156.25,1020.55 8456.25,1020.55 8106.25,1070.55 8206.25,1070.55 8406.25,1070.55 8506.25,1070.55 8156.25,1120.55 8456.25,1120.55 8106.25,1170.55 8206.25,1170.55 8406.25,1170.55 8506.25,1170.55 8156.25,1220.55 8456.25,1220.55 8106.25,1270.55 8206.25,1270.55 8406.25,1270.55 8506.25,1270.55 8156.25,1320.55 8456.25,1320.55
OUT2_LS_DRV81242: C127.1 J6.6 U30.7 | length 997.2
  Top Layer w20: U30.7@6416.74,959.51 6470.34,959.51
  Top Layer w30: 6470.34,959.51 6664.93,959.51 6705.28,919.16 6705.28,553.04 C127.1@6702.24,550 6702.24,231.17 J6.6@6704.15,229.26
OUT2_TLIN1024A: C51.1 J25.5 R67.1 U11.20 | length 1395.3
  Bottom Layer w15: J25.5@791.28,2748.11 841.23,2798.06 915.96,2798.06 1160.13,3042.23 1348.79,3230.89 1593.76,3230.89 1765,3402.13 R67.1@1915.7,3402.13
OUT2_TPS2HC08: C81.1 J10.1 U24.11
  other v1: 4401.57,302.7 4501.57,302.7 4451.57,352.7 4401.57,402.7 4501.57,402.7 4397.88,591.5 4497.88,591.5 4447.88,641.5 4397.88,691.5 4497.88,691.5
OUT2_TPS4HC120: C91.1 J9.3 U25.25 U25.26 | length 642.8
  Top Layer w30: 5249.2,860.41 5249.2,631.48 5275.18,605.5 C91.1@5275.18,550 J9.3@5275.18,228.37
OUT3_DRV8714: C110.1 J8.1 NT5.2 Q11.1 Q11.2 Q11.3 Q13.5 Q13.6 Q13.7 Q13.8 Q13.9@7875.87,1704.54
  other v1: 8157.98,1560.64 8457.98,1560.64 8107.98,1610.64 8207.98,1610.64 8407.98,1610.64 8507.98,1610.64 8157.98,1660.64 8457.98,1660.64 8107.98,1710.64 8207.98,1710.64 8407.98,1710.64 8507.98,1710.64 8157.98,1760.64 8457.98,1760.64
OUT3_HS_DRV81242: C128.1 J6.3 U30.17 | length 1147.6
  Top Layer w20: 6104.14,985.1 U30.17@6188.4,985.1
  Top Layer w30: 6104.14,985.1 5973.96,985.1 5891.09,902.23 5891.09,717.17 6001.22,607.03 6087.94,607.03 6113.6,581.37 C128.1@6113.6,550 J6.3@6113.6,229.26
OUT3_TLIN1024A: C52.1 J25.7 R68.1 U11.17 | length 1412.4
  Bottom Layer w15: J25.7@791.28,2648.11 841.05,2697.89 974.55,2697.89 1452.74,3176.08 1631.5,3176.08 1798.64,3343.22 R68.1@1915.77,3343.22
OUT3_TPS4HC120: C93.1 J9.2 U25.17 U25.18 | length 637.6
  Top Layer w30: J9.2@5078.33,228.37 C93.1@5078.33,550 5078.33,618.09 5091.72,631.48 5091.72,860.41
OUT4__HS_DRV81242: C129.1 J6.7 U30.10 | length 1160.5
  Top Layer w20: U30.10@6416.74,1036.28 6480.97,1036.28 6497.02,1052.33
  Top Layer w30: 6497.02,1052.33 6638.94,1052.33 6755.57,935.69 6755.57,762.31 6901,616.88 C129.1@6901,550 J6.7@6901,229.26
OUT4_DRV8714: C111.1 J8.2 NT4.1 R162.2
  other v1: 8157.98,1935.44 8457.98,1935.44 8107.98,1985.44 8207.98,1985.44 8407.98,1985.44 8507.98,1985.44 8157.98,2035.44 8457.98,2035.44 8107.98,2085.44 8207.98,2085.44 8407.98,2085.44 8507.98,2085.44 8157.98,2135.44 8457.98,2135.44
OUT4_TLIN1024A: C53.1 J25.9 R70.1 U11.15 | length 1505.3
  Bottom Layer w15: J25.9@791.28,2548.11 840.99,2597.83 955.07,2597.83 1352.78,2995.54 1392.55,2995.54 1523.07,3126.06 1680.72,3126.06 1753.65,3198.99 C53.1@2027.02,3198.99
OUT4_TPS4HC120: C94.1 J9.1 U25.15 U25.16 | length 702.8
  Top Layer w30: J9.1@4881.48,228.37 C94.1@4881.48,550 4881.48,621.9 5052.35,792.77 5052.35,860.41
OUT5_HS_DRV81242: C130.1 J6.2 U30.15 | length 1145.2
  Top Layer w20: 6107.27,1036.28 U30.15@6188.4,1036.28
  Top Layer w30: J6.2@5916.75,229.26 5916.69,229.32 C130.1@5916.69,550 5916.69,592.39 5807.37,701.72 5807.37,885.85 5957.8,1036.28 6107.27,1036.28
OUT6_HS_DRV81242: C131.1 J6.8 U30.11 | length 1362.6
  Top Layer w20: U30.11@6416.74,1061.87 6465.64,1061.87 6479.76,1076 6480.21,1076 6496.95,1092.74
  Top Layer w30: 6496.95,1092.74 6654.73,1092.74 6795.06,952.41 6795.06,783.67 6925.83,652.91 7036.52,652.91 7097.85,591.58 C131.1@7097.85,550 J6.8@7097.85,229.26
OUT7_HS_DRV81242: C132.1 J6.1 U30.14 | length 1227.3
  Top Layer w20: 6116.04,1073.95 6128.12,1061.87 U30.14@6188.4,1061.87
  Top Layer w30: J6.1@5719.9,229.26 C132.1@5719.9,550 5719.9,877.68 5945.3,1103.08 6021.61,1103.08 6050.74,1073.95 6116.04,1073.95
OUT_1M_J1_25: C353.2 C354.1 C356.1 J27.4 U43.37
  other v1: 490.83,3397.55 523.54,3397.91 491.2,3430.99 523.74,3431.27 1183.98,4538.18 1209.29,4537.84 1184.32,4561.13 1208.95,4561.13 820.81,4687.45 820.81,4714.66 820.81,4742.36
OUT_1P1_25: C336.1 L10.1 R397.2 U43.41 | length 47.1
  Bottom Layer w20: v1(901.55,4595.38) 920.76,4595.38 R397.2@940.47,4615.09
  other v1: 1180.08,4417.21 1204.72,4417.21 1179.74,4440.5 1205.06,4440.16 901.55,4495.96 901.55,4529.1 901.55,4562.24
OUT_1P_J1_25: C353.1 C355.1 J27.3 L10.2
  other v1: 491.68,3590.06 524.39,3590.42 492.04,3623.5 524.59,3623.78 679.76,4662.27 708.47,4662.77 654.57,4698.03 654.06,4729.77
OUT_2M_J1_25: C345.2 C347.1 C349.1 J27.2 U43.48
  other v1: 491.99,3794.92 524.71,3795.29 492.36,3828.37 524.91,3828.65 825.52,4071.11 826.04,4098.12 825.78,4124.62 1198.71,4242.4 1223.11,4242.81 1198.57,4264.3 1222.97,4264.3
OUT_2P1_25: C340.1 L9.1 R396.2 U43.44 | length 49.6
  Bottom Layer w20: v1(902.35,4249.22) 941.81,4249.22 R396.2@948.98,4256.39
  other v1: 902.35,4216.09 902.35,4282.36 902.35,4315.5 1181.19,4364.76 1205.83,4364.76 1180.85,4388.05 1206.16,4387.71
OUT_2P_J1_25: C345.1 C348.1 J27.1 L9.2
  other v1: 488.72,3991.3 521.43,3991.66 489.09,4024.75 521.63,4025.02 657.51,4087.65 657.51,4118.52 684.53,4149.4 712.65,4149.4
OUT_3M_J1_25: C338.2 C339.1 C342.1 J26.4 U43.20
  other v1: 486.72,4282.89 519.44,4283.26 487.09,4316.34 519.64,4316.62 1385.9,4538.26 1410.3,4538.26 1385.76,4559.75 1410.16,4560.16 1875.63,4692.93 1875.17,4718.6 1874.7,4747.07
OUT_3P1_25: C344.1 L8.1 R389.2 U43.16 | length 57.8
  Bottom Layer w20: R389.2@1738.67,4533.45 1741.74,4536.52 v1(1795.22,4536.52)
  other v1: 1403.04,4413.36 1428.35,4413.02 1403.37,4436.31 1428.01,4436.31 1795.22,4503.39 1795.22,4569.66 1795.22,4602.8
OUT_3P_J1_25: C338.1 C341.1 J26.3 L8.2
  other v1: 487.57,4475.4 520.29,4475.77 487.94,4508.85 520.49,4509.13 1985.41,4675.17 2013.47,4674.51 2038.47,4704.46 2038.47,4735.81
OUT_4M_J1_25: C327.2 C329.1 C331.1 J26.2 U43.10
  other v1: 1887.61,4074.45 1887.23,4100.49 1887.23,4127.31 1399.95,4266.36 1424.58,4266.36 1424.92,4289.31 1399.61,4289.65 487.89,4680.27 520.6,4680.64 488.26,4713.72 520.8,4713.99
OUT_4P1_25: C346.1 L7.1 R386.2 U43.13 | length 61.8
  Bottom Layer w20: R386.2@1745.12,4232.9 1745.12,4233.88 1753.82,4242.58 1754.8,4242.58 1761.54,4249.32 v1(1799.58,4249.32)
  other v1: 1799.58,4216.18 1799.58,4282.46 1799.58,4315.6 1403.98,4362.21 1429.29,4361.87 1404.32,4385.16 1428.95,4385.16
OUT_4P_J1_25: C327.1 C330.1 J26.1 L7.2 | length 2662.3
  SIG_1 w100: 495.39,4897.54 830.23,5232.37 1425.85,5232.37 1791.55,4866.67 2043.83,4866.67 2102.41,4808.09 2102.41,4574.03 2012.09,4483.72 2012.09,4147.12 2012.09,4104.6
  other v1: 2047.93,4082.36 2048.14,4112.84 1991.2,4147.12 2026.35,4147.77 484.61,4876.65 517.33,4877.01 484.98,4910.09 517.53,4910.37
OUT_TLIN1021A: C47.1 J25.1 R64.1 U10.6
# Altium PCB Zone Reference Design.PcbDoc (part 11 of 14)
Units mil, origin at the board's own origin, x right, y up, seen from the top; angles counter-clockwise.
Board outline 8858.11 x 7047.08 mil, 16 copper layers (Top Layer, GND_1, SIG_1, GND_2, PWR/SIG_1, GND_3, PWR_1, PWR_2, GND_4, PWR/SIG_2, GND_5, SIG_2, GND_6, SIG_3, GND_7, Bottom Layer), stack 80.368 mil thick; 1131 components, 808 nets, 3825 pads, 3523 vias.
Unrouted connection lines stored in the file: 563.

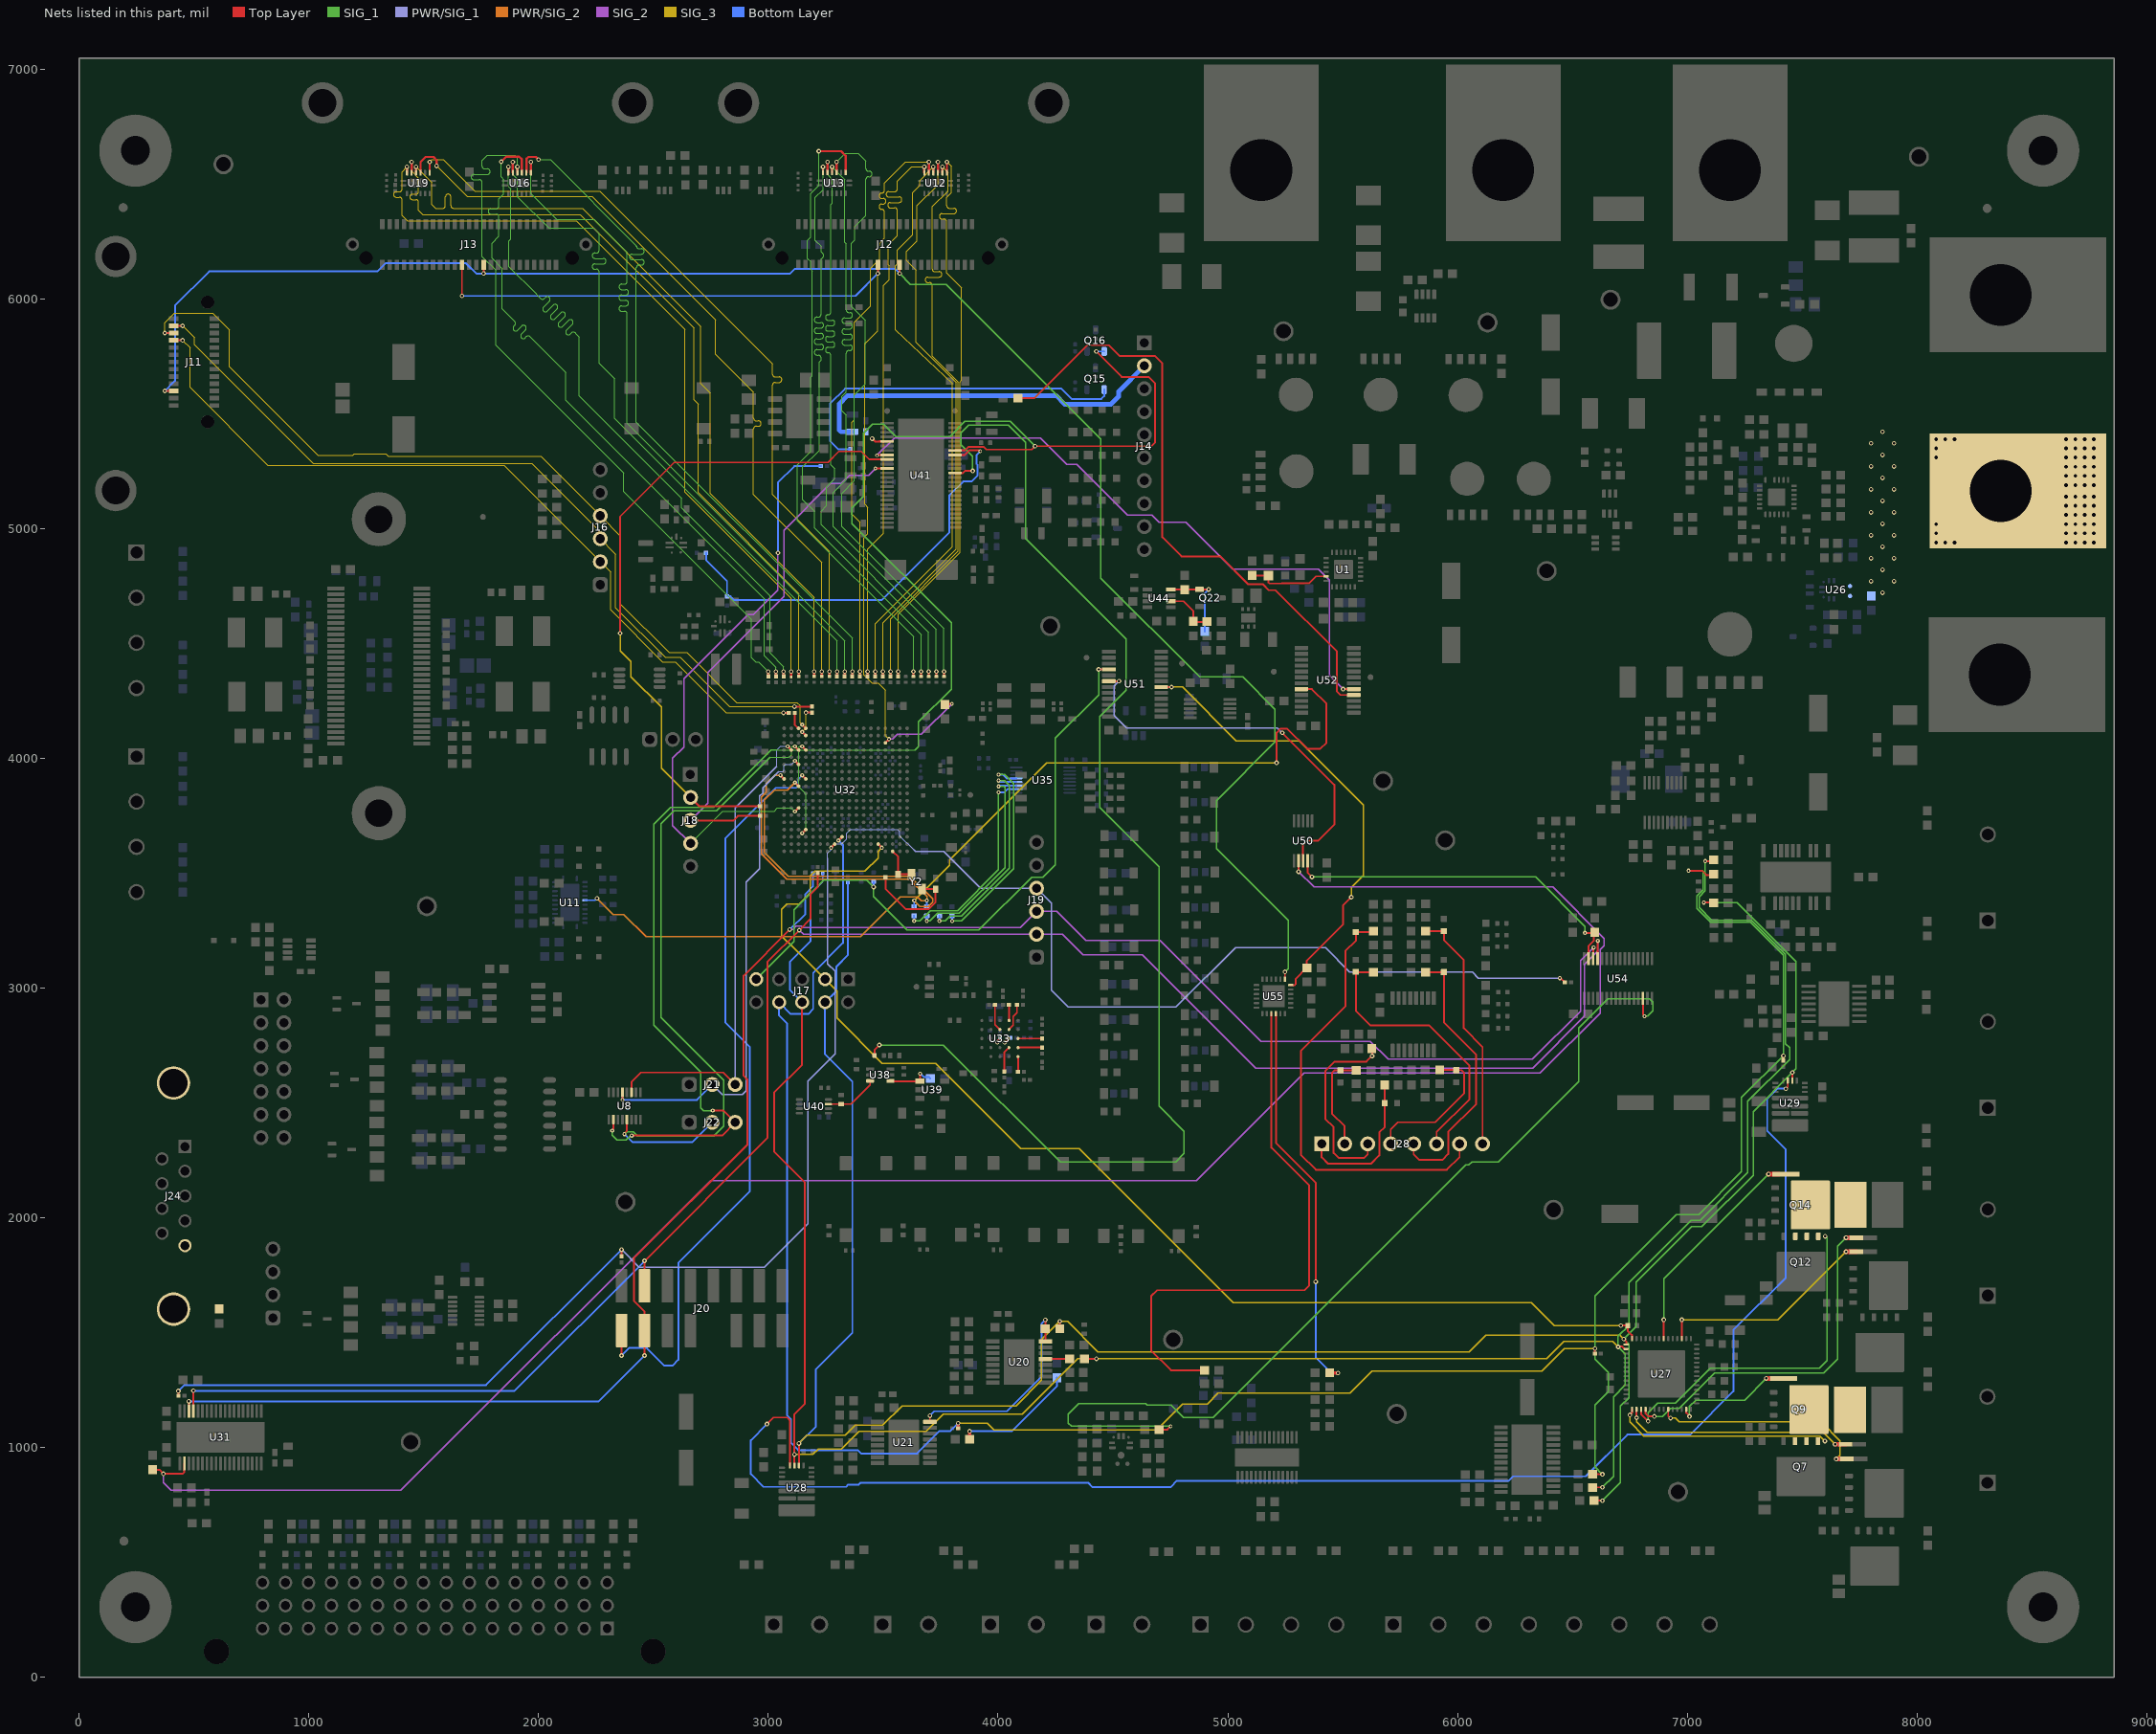
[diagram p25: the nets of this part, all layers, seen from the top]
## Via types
v1: diameter 20, hole 10, Top Layer to Bottom Layer, tented both sides, 2450 vias
v2: diameter 18, hole 8, Top Layer to Bottom Layer, tented both sides, 400 vias
v3: diameter 32, hole 16, Top Layer to Bottom Layer, tented both sides, 348 vias
v4: diameter 19.68, hole 7.87, Top Layer to Bottom Layer, tented both sides, 245 vias
v5: diameter 16, hole 8, Top Layer to Bottom Layer, tented both sides, 60 vias
v6: diameter 16, hole 8, Top Layer to Bottom Layer, 14 vias
v7: diameter 24.8, hole 12.99, Top Layer to Bottom Layer, tented both sides, 6 vias

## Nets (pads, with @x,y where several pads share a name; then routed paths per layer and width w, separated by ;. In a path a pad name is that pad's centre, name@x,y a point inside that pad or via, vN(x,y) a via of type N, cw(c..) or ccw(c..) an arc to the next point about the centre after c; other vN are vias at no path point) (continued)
OUT_TPS1HC04: C86.1 T3.1 U26.1 U26.11
  other v1: 7850.2,4719.9 7800.2,4769.9 7900.2,4769.9 7850.2,4819.9 7800.2,4869.9 7900.2,4869.9 7850.2,4919.9 7800.2,4969.9 7900.2,4969.9 7850.2,5019.9 7800.2,5069.9 7900.2,5069.9 7850.2,5119.9 7800.2,5169.9 7900.2,5169.9 7850.2,5219.9 7800.2,5269.9 7900.2,5269.9 7850.2,5319.9 7800.2,5369.9 7900.2,5369.9 7850.2,5419.9
  other v3: 8082.98,4938.52 8122.98,4938.52 8162.98,4938.52 8649.25,4938.52 8689.25,4938.52 8729.25,4938.52 8769.25,4938.52 8082.98,4978.52 8649.25,4978.52 8689.25,4978.52 8729.25,4978.52 8769.25,4978.52 8082.98,5018.52 8649.25,5018.52 8689.25,5018.52 8729.25,5018.52 8769.25,5018.52 8649.25,5058.52 8689.25,5058.52 8729.25,5058.52 8769.25,5058.52 8649.25,5098.52 8689.25,5098.52 8729.25,5098.52 8769.25,5098.52 8649.25,5138.52 8689.25,5138.52 8729.25,5138.52 8769.25,5138.52 8649.25,5188.52 8689.25,5188.52 8729.25,5188.52 8769.25,5188.52 8649.25,5228.52 8689.25,5228.52 8729.25,5228.52 8769.25,5228.52 8649.25,5268.52 8689.25,5268.52 8729.25,5268.52 8769.25,5268.52 8082.98,5308.52 8649.25,5308.52 8689.25,5308.52 8729.25,5308.52 8769.25,5308.52 8082.98,5348.52 8649.25,5348.52 8689.25,5348.52 8729.25,5348.52 8769.25,5348.52 8082.98,5388.52 8122.98,5388.52 8162.98,5388.52 8649.25,5388.52 8689.25,5388.52 8729.25,5388.52 8769.25,5388.52
OV_4: R23.2 R24.2 U1.5 | length 366.9
  Top Layer w8: R23.2@5106.46,4795.51 5107.86,4794.11 R24.2@5176.42,4794.11 5176.42,4764.6 5181.11,4759.91 5233.21,4759.91 5233.97,4760.67 5352.35,4760.67 5383.03,4791.35 U1.5@5428.31,4791.35
P15_TCAL9539: R140.1 U55.15 | length 2464.3
  Top Layer w8: R140.1@4898.44,1335.18 4751.96,1335.18 4666.25,1420.89 4666.25,1657.9 4692.44,1684.09 5334.02,1684.09 5354.45,1704.52 5354.45,2139.34 5189.58,2304.2 U55.15@5189.58,2888.31
P16_TCAL9539: R144.1 U55.16 | length 1728.8
  Top Layer w8: U55.16@5209.27,2888.31 5209.27,2325.36 5382.48,2152.15 v1(5382.48,1720.67)
  Top Layer w15: R144.1@5443.38,1323.89 v1(5479.38,1323.89)
  Bottom Layer w8: v1(5382.48,1720.67) 5382.48,1392.62 5451.2,1323.89 v1(5479.38,1323.89)
P23_TXE8116: R120.1 U54.14 | length 4197.4
  Top Layer w8: R120.1@4701.43,1077.64 4736.57,1077.64 4750.37,1091.45 v5(4751.05,1091.45) ; U54.14@6806.65,2953.82 6806.65,2886.07 6812.41,2880.31 6812.41,2877.45 v5(6813.94,2875.92)
  SIG_1 w6: v5(4751.05,1091.45) 4319.35,1091.45 4305.71,1105.08 4305.71,1145.5 4351.16,1190.95 4642.47,1190.95 4649.47,1183.95 4753.7,1183.95 4806.75,1130.91 4936.07,1130.91 6035.15,2229.99 6049.2,2229.99 6062.31,2243.1 6178.15,2243.1 6526.47,2591.41 6526.47,2824.84 6654.71,2953.08 6834.74,2953.08 6849.98,2937.84 6849.98,2899.91 6827.4,2877.33 6815.35,2877.33 v5(6813.94,2875.92)
PLDO2_OUT_3: C300.1 C301.1 J14.2 U41.29 | length 1684.7
  Top Layer w10: v1(3451.95,5390.41) 3452.62,5390.41 3465.56,5377.47 3484.84,5377.47 3485.18,5377.81 3516.06,5377.81 U41.29@3516.97,5378.72
  Bottom Layer w20: C301.1@3365.6,5420.7 3316.44,5420.7 3308.94,5428.2 3308.94,5542.14 3344.56,5577.76 4252.2,5577.76 4289.4,5540.56 4491.55,5540.56 4524.85,5573.87 4524.85,5595.77 J14.2@4636.77,5707.69
PMIC_DIAG_1: U41.32 U52.5 | length 2849.3
  Top Layer w8: v5(3472.65,5317.99) 3474.15,5319.49 3516.8,5319.49 U41.32@3516.97,5319.66 ; v1(5501.71,4300.23) U52.5@5548.39,4300.23
  SIG_2 w6: v5(3472.65,5317.99) 3548.35,5393.69 4184.73,5393.69 4299.24,5279.18 4342.71,5279.18 4563.88,5058.01 4669.89,5058.01 4701.16,5026.74 4817.08,5026.74 5020.71,4823.11 5394.42,4823.11 5442.43,4775.09 5442.43,4647.99 5441.48,4647.03 5441.48,4360.46 v1(5501.71,4300.23)
PMIC_EN_OUT: R404.1 R413.1 U41.17 | length 1878
  Top Layer w8: U41.17@3812.24,5319.66 3854.37,5319.66 3874.07,5339.36 3914.86,5339.36 3918.85,5335.36 v5(3922.15,5335.36)
  Bottom Layer w8: R413.1@2729.16,4893.66 2729.16,4861.51 2820.21,4770.46 R404.1@2820.21,4704.73 2835.06,4704.73 2852.29,4687.49 3492.54,4687.49 3788.08,4983.03 3788.08,5144.55 3848.05,5204.52 3885.31,5204.52 3911.3,5230.51 3911.3,5276.34 3905.88,5281.76 3905.88,5319.09 v5(3922.15,5335.36)
PMIC_nINT_1: R476.2 U52.4 | length 2733.9
  Top Layer w8: R476.2@4085.52,5566.72 4157.74,5566.72 4388.18,5797.15 4481.81,5797.15 4527.87,5751.1 4682.14,5751.1 4715.14,5718.1 4715.14,4961.31 4798.04,4878.42 4966.59,4878.42 5088.06,4756.95 5152.15,4756.95 5178.14,4730.97 5207.5,4730.97 5475.01,4463.46 5475.01,4289.89 5490.26,4274.64 U52.4@5548.39,4274.64
PMIC_nRST: R322.1 U41.13 | length 5676.6
  Top Layer w8: R322.1@3462.36,2705.37 3462.36,2730.37 v1(3483.28,2751.29) ; U41.13@3812.24,5240.92 3845.92,5240.92 3855.27,5250.27 v1(3889.63,5250.27)
  SIG_1 w6: v1(3483.28,2751.29) 3762.18,2751.29 4271.09,2242.38 4773.16,2242.38 4810.02,2279.24 4810.02,2375.84 4700.71,2485.15 4700.71,3527.43 4442.91,3785.23 4442.91,4181.74 4557.19,4296.01 4557.19,4517.74 4119.03,4955.9 4119.03,5375.19 4044.92,5449.3 3872.43,5449.3 3839.05,5415.92 3839.05,5363.72 3889.63,5313.14 v1(3889.63,5250.27)
PORz_RST_12: R323.2 U38.3 U40.7 | length 234.5
  Top Layer w8: U40.7@3261.32,2494.15 R323.2@3316.66,2494.16 3360.31,2494.16 3442.95,2576.8 U38.3@3442.95,2595.41
PORz_VMAIN_12: R477.2 U38.4 U39.1 | length 212.5
  Top Layer w8: U38.4@3531.53,2595.41 3533.17,2593.77 U39.1@3658.94,2593.77 3661.02,2595.86 v5(3661.02,2625.65)
  Bottom Layer w8: v5(3661.02,2625.65) 3663.19,2625.65 3677.64,2611.2 3699.75,2611.2 R477.2@3704.64,2606.32
PR0_PRU0_GPIO0: R223.1 U19.12 | length 3435
  Top Layer w9.9: U19.12@1486.28,6547.96 1486.28,6595.09 1508.17,6616.98 1542.52,6616.98 1555.89,6603.61 v1@1555.89,6579.61 ; R223.1@3232.43,4355.71 v1(3232.43,4377.1)
  SIG_3 w3.6: v1(1555.89,6577.61) 1688.66,6444.84 2232.19,6444.84 2769.87,5907.16 2769.87,5758.36 2935.45,5592.77 2935.45,5481.68 2935.45,5479.87 ccw(c2947.25,5479.87) 2947.25,5468.07 2956.26,5468.07 cw(c2956.26,5456.27) 2956.26,5444.47 2947.25,5444.47 ccw(c2947.25,5432.67) 2935.45,5432.67 2935.45,5357.45 2935.45,5147.74 3232.43,4850.75 3232.43,4405.96 v1(3232.43,4377.1)
PR0_PRU0_GPIO1: R225.1 U19.13 | length 3437.3
  Top Layer w9.9: U19.13@1466.6,6547.96 v1(1466.6,6573.35) ; R225.1@3199.18,4355.71 v1(3199.18,4377.1)
  SIG_3 w3.6: v1(1466.6,6573.35) 1535.03,6504.91 1535.03,6410.28 1551.69,6393.62 1580.75,6393.62 1582.55,6393.62 ccw(c1582.55,6405.42) 1594.35,6405.42 1594.35,6443.11 cw(c1606.15,6443.11) 1617.95,6443.11 1617.95,6405.42 ccw(c1629.75,6405.42) 1629.75,6393.62 1658.2,6393.62 2190.64,6393.62 2704.99,5879.28 2704.99,5630.93 2746.73,5589.19 2746.73,5151.6 3199.1,4699.23 3199.1,4377.18 v1(3199.18,4377.1)
PR0_PRU0_GPIO2: R226.1 U19.14 | length 3443.4
  Top Layer w9.9: U19.14@1446.91,6547.96 v1(1446.91,6595.09) ; R226.1@3132.67,4355.71 v1(3132.67,4377.1)
  SIG_3 w3.6: v1(1446.91,6595.09) 1446.91,6555.05 1477.44,6524.52 1477.44,6503.33 1477.44,6466.55 cw(c1465.64,6466.55) 1465.64,6454.75 1450.75,6454.75 ccw(c1450.75,6442.95) 1450.75,6431.15 1465.64,6431.15 cw(c1465.64,6419.35) 1477.44,6419.35 1477.44,6417.55 1477.44,6384.33 1494.92,6366.85 2180.96,6366.85 2676.14,5871.68 2676.14,5559.4 2694.97,5540.57 2694.97,5154.87 3132.67,4717.16 v1(3132.67,4377.1)
PR0_PRU0_GPIO3: R228.1 U19.15 | length 3438.8
  Top Layer w9.9: U19.15@1427.23,6547.96 v1(1427.23,6573.35) ; R228.1@3099.42,4355.71 v1(3099.42,4377.1)
  SIG_3 w3.6: v1(1427.23,6573.35) 1405.65,6551.78 1405.65,6494.67 1405.65,6477 cw(c1393.85,6477) 1393.85,6465.2 1380.08,6465.2 ccw(c1380.08,6453.4) 1380.08,6441.6 1393.85,6441.6 cw(c1393.85,6429.8) 1405.65,6429.8 1405.65,6427.99 1405.65,6362.15 1428.96,6338.84 2164.31,6338.84 2636.82,5866.33 2636.82,5158.89 3099.42,4696.28 v1(3099.42,4377.1)
PR0_PRU0_GPIO6: R231.1 U19.10 | length 3436.2
  Top Layer w9.9: U19.10@1525.65,6547.96 v1(1525.65,6595.09) ; R231.1@3265.69,4355.71 v1(3265.69,4377.1)
  SIG_3 w3.6: v1(1525.65,6595.09) 1536.05,6605.49 1584.57,6605.49 1721.95,6468.11 2266.63,6468.11 3018.43,5716.3 3018.43,5672.88 3018.43,5671.08 ccw(c3030.23,5671.08) 3030.23,5659.28 3047.11,5659.28 cw(c3047.11,5647.48) 3047.11,5635.68 3030.23,5635.68 ccw(c3030.23,5623.88) 3018.43,5623.88 3018.43,5595.42 3018.43,5146.81 3265.69,4899.56 v1(3265.69,4377.1)
PR0_PRU0_GPIO11: R232.1 U16.2 | length 3123.3
  Top Layer w9.9: U16.2@1966.6,6547.96 v1(1966.59,6595.09) ; R232.1@3332.19,4355.71 v1(3332.19,4377.1)
  SIG_1 w3.6: v1(1966.59,6595.09) 1966.59,6456.89 2078.52,6344.97 2241.19,6344.97 2385.4,6200.77 2385.4,6117.4 2385.4,6074.89 cw(c2373.6,6074.89) 2373.6,6063.09 2361.7,6063.09 ccw(c2361.7,6051.29) 2361.7,6039.49 2379.5,6039.49 cw(c2379.5,6027.69) 2379.5,6015.89 2361.7,6015.89 ccw(c2361.7,6004.09) 2361.7,5992.29 2379.5,5992.29 cw(c2379.5,5980.49) 2379.5,5968.69 2361.7,5968.69 ccw(c2361.7,5956.89) 2361.7,5945.09 2373.6,5945.09 cw(c2373.6,5933.29) 2385.4,5933.29 2385.4,5931.48 2385.4,5457.91 3332.19,4511.12 v1(3332.19,4377.1)
PR0_PRU0_GPIO12: R233.1 U16.3 | length 3123.2
  Top Layer w9.9: U16.3@1946.91,6547.96 1946.91,6608.16 1955.64,6616.88 1987.88,6616.88 v1(1999.66,6605.1) ; R233.1@3365.45,4355.71 v1(3365.45,4377.1)
  SIG_1 w3.6: v1(1999.66,6605.1) 2051.42,6605.1 2425.42,6231.1 2425.42,6229.3 ccw(c2437.22,6229.3) 2437.22,6217.5 2447.82,6217.5 cw(c2447.82,6205.7) 2447.82,6193.9 2407.22,6193.9 ccw(c2407.22,6182.1) 2407.22,6170.3 2447.82,6170.3 cw(c2447.82,6158.5) 2447.82,6146.7 2437.22,6146.7 ccw(c2437.22,6134.9) 2425.42,6134.9 2425.42,6103.41 2425.42,5461.92 3365.45,4521.89 v1(3365.45,4377.1)
PR0_PRU0_GPIO13: R234.1 U16.4 | length 3130
  Top Layer w9.9: v1(1836.91,6595.8) 1858.84,6617.73 1915.35,6617.73 1927.22,6605.86 U16.4@1927.22,6547.96 ; R234.1@3032.91,4355.71 v1(3032.91,4377.1)
  SIG_1 w3.6: v1(1836.91,6595.8) 1836.91,6529.33 1847.98,6518.26 1847.98,6455.49 1827.58,6435.1 1827.58,6403.49 cw(c1815.78,6403.49) 1815.78,6391.69 1792.58,6391.69 ccw(c1792.58,6379.89) 1792.58,6368.09 1815.78,6368.09 cw(c1815.78,6356.29) 1827.58,6356.29 1827.58,6354.48 1827.58,6271.12 1796.98,6240.52 1796.98,6175.82 1841.94,6130.85 1841.94,5954.92 1864.53,5932.34 1865.8,5931.07 1896.2,5900.67 cw(c1887.86,5892.32) 1896.2,5883.98 1891.68,5879.46 ccw(c1900.02,5871.11) 1891.68,5862.77 ccw(c1900.02,5871.11) 1908.36,5862.77 1926.04,5880.44 cw(c1934.38,5872.1) 1942.73,5863.76 1925.05,5846.08 ccw(c1933.39,5837.74) 1925.05,5829.39 ccw(c1933.39,5837.74) 1941.74,5829.39 1946.26,5833.92 cw(c1954.61,5825.57) 1962.95,5833.92 1964.22,5832.64 2118.8,5678.07 2118.8,5558.05 2982.45,4694.4 2982.45,4445.53 3032.91,4395.06 v1(3032.91,4377.1)
PR0_PRU0_GPIO14: R235.1 U16.5 | length 3137.3
  Top Layer w9.9: U16.5@1907.54,6547.96 v1(1907.54,6573.35) ; R235.1@2999.66,4355.71 v1(2999.66,4377.1)
  SIG_1 w3.6: v1(1907.54,6573.35) 1907.54,6614.2 1897.18,6624.56 1776.94,6624.56 1753.96,6601.58 1753.96,6576.54 ccw(c1765.76,6576.54) 1765.76,6564.74 1776.88,6564.74 cw(c1776.88,6552.94) 1776.88,6541.14 1718.27,6541.14 ccw(c1718.27,6529.34) 1718.27,6517.54 1742.16,6517.54 cw(c1742.16,6505.74) 1753.96,6505.74 1753.96,6503.94 1753.96,6183.26 1813.65,6123.58 1813.65,5797.42 2370.85,5240.22 2370.85,5159.34 2926.52,4603.67 2926.52,4436.96 2944.86,4418.62 2958.14,4418.62 v1(2999.66,4377.1)
PR0_PRU0_GPIO15: R236.1 U16.6 | length 3123.8
  Top Layer w9.9: U16.6@1887.85,6547.96 v1(1887.85,6595.09) ; R236.1@3298.94,4355.71 v1(3298.94,4377.1)
  SIG_1 w3.6: v1(1887.85,6595.09) 1887.85,6541.53 1908.71,6520.68 1908.71,6443.05 2044.82,6306.93 2238.33,6306.93 2263.36,6281.9 2263.36,6228.12 2263.36,6210.58 cw(c2251.56,6210.58) 2251.56,6198.78 2245.16,6198.78 ccw(c2245.16,6186.98) 2245.16,6175.18 2281.56,6175.18 cw(c2281.56,6163.38) 2281.56,6151.58 2245.16,6151.58 ccw(c2245.16,6139.78) 2245.16,6127.98 2251.56,6127.98 cw(c2251.56,6116.18) 2263.36,6116.18 2263.36,6114.38 2263.36,5718.68 2331.33,5650.71 2331.33,5477.71 3298.94,4510.1 v1(3298.94,4377.1)
PR0_PRU0_GPIO16: R237.1 U16.7 | length 3134.8
  Top Layer w9.9: U16.7@1868.17,6547.96 v1(1868.17,6573.35) ; R237.1@3066.17,4355.71 v1(3066.17,4377.1)
  SIG_1 w3.6: v1(1868.17,6573.35) 1868.17,6488.25 1879.15,6477.27 1879.15,6258.7 1871.02,6250.57 1871.02,6138.6 1988.35,6021.27 1989.62,6020 2008.9,6000.73 ccw(c2017.24,6009.07) 2025.58,6000.73 2030.11,6005.25 cw(c2038.45,5996.91) 2046.8,6005.25 cw(c2038.45,5996.91) 2046.8,5988.57 2021.06,5962.83 ccw(c2029.4,5954.48) 2037.75,5946.14 2063.48,5971.88 cw(c2071.83,5963.53) 2080.17,5971.88 cw(c2071.83,5963.53) 2080.17,5955.19 2054.43,5929.45 ccw(c2062.78,5921.11) 2054.43,5912.76 ccw(c2062.78,5921.11) 2071.12,5912.76 2096.86,5938.5 cw(c2105.2,5930.16) 2113.55,5938.5 cw(c2105.2,5930.16) 2113.55,5921.81 2087.81,5896.08 ccw(c2096.15,5887.73) 2087.81,5879.39 ccw(c2096.15,5887.73) 2104.5,5879.39 2130.23,5905.13 cw(c2138.58,5896.78) 2146.92,5888.44 2121.18,5862.7 ccw(c2129.53,5854.36) 2121.18,5846.01 ccw(c2129.53,5854.36) 2137.87,5846.01 2142.4,5850.54 cw(c2150.74,5842.19) 2159.08,5850.54 2160.36,5849.27 2176.6,5833.02 2176.6,5575.94 2622.36,5130.18 2622.36,5089.79 3006.75,4705.41 3006.75,4458.06 3066.17,4398.64 v1(3066.17,4377.1)
PR0_PRU1_GPIO8: J11.5 J16.4 U32.D18 | length 3956.8
  Top Layer w8: v1(373.03,5850.27) J11.5@411.42,5850.27
  Top Layer w9.9: v2(3147.31,4145.62) U32.D18@3163.06,4129.88
  SIG_3 w4.5: v1(373.03,5850.27) 373.03,5895.41 415.33,5937.71 580.92,5937.71 654.09,5864.54 654.09,5704.09 1040.5,5317.67 1190.87,5317.67 1197.9,5324.71 1335.9,5324.71 1346.45,5314.16 2009.59,5314.16 J16.4@2268.87,5054.88 2356.76,4966.99 2356.76,4670.86 2567.18,4460.44 2644.61,4460.44 2862.85,4242.2 3125.11,4242.2 3139.16,4228.14 3139.16,4153.77 v2(3147.31,4145.62)
PR0_PRU1_GPIO9: R359.2 U32.C18 | length 74.3
  Top Layer w8: R359.2@3114.78,4197.27 3114.78,4146.66 U32.C18@3131.56,4129.88
PR0_PRU1_GPIO10: R360.2 U32.D17 | length 138.3
  Top Layer w8: v1(3164.23,4198.16) R360.2@3189.23,4198.16
  Top Layer w9.9: v2(3147.31,4114.13) U32.D17@3163.06,4098.38
  SIG_3 w4.5: v2(3147.31,4114.13) 3163.46,4130.28 3163.46,4197.39 v1(3164.23,4198.16)
PR0_PRU1_GPIO18: J22.3 U8.2 U32.C15 | length 2920.9
  Top Layer w8: v2(2320.43,2378.31) 2320.43,2381.02 2325.3,2385.88 U8.2@2325.3,2427.14 ; v2(2405.09,2357.27) 2798.41,2357.27 J22.3@2855.83,2414.69 2804.79,2465.73 v2(2757.69,2465.73)
  Top Layer w9.9: v2(3115.81,4051.14) U32.C15@3131.56,4035.39
  SIG_1 w4.5: 3039.05,4035.69 3090.34,4035.69 3105.79,4051.14 v2(3115.81,4051.14)
  SIG_1 w6: v2(2320.43,2378.31) 2320.43,2357.97 2341.53,2336.87 2381.44,2336.87 2401.84,2357.27 v2(2405.09,2357.27) ; v2(2757.69,2465.73) 2756.58,2464.62 2718.52,2464.62 2705.9,2477.24 2705.9,2634.17 2501.43,2838.64 2501.43,3711.94 2574.97,3785.48 2760.86,3785.48 3011.07,4035.69 3039.05,4035.69
PR0_PRU1_GPIO19: J22.2 U8.5 U32.D15 | length 3174.4
  Top Layer w8: v2(2373.77,2363.5) 2373.77,2366.21 2384.36,2376.8 U8.5@2384.36,2427.14
  Top Layer w9.9: v2(3147.31,4051.14) U32.D15@3163.06,4035.39
  SIG_1 w4.5: 3007.87,4003.47 3089.52,4003.47 3100.46,4014.42 3100.46,4028.55 3107.42,4035.51 3121.91,4035.51 3137.54,4051.14 v2(3147.31,4051.14)
  SIG_1 w6: v2(2373.77,2363.5) 2374.26,2363.5 2385.03,2374.27 2412.13,2374.27 2429.37,2357.03 2763.39,2357.03 2805.42,2399.06 2805.42,2598.49 2532.2,2871.71 2532.2,3714.26 2588.46,3770.52 2774.92,3770.52 3007.87,4003.47
  Bottom Layer w8: v2(2373.77,2363.5) 2387.09,2350.19 2387.09,2349.82 2397.63,2339.27 2398,2339.27 2408.4,2328.88 2670.02,2328.88 J22.2@2755.83,2414.69
PWM_ETH_1: J12.28 J13.28 R478.2 U32.R16 | length 4542.2
  Top Layer w8: v1(1666.28,6011.85) J13.28@1666.28,6147.8 ; v1(3476.94,6109.41) J12.28@3476.94,6147.8 ; R478.2@3768.76,4233.17 3771.51,4235.91 v5(3798.95,4235.91)
  Top Layer w9.9: U32.R16@3509.51,4066.88 v2(3525.26,4082.63)
  SIG_3 w4.5: v1(3476.94,6109.41) 3476.94,5860.26 3419.36,5802.69 3419.36,5105.85 3433.38,5091.83 3433.38,4976.62 3415.31,4958.55 3415.31,4361.54 3450.4,4326.44 3478.82,4326.44 3509.65,4295.62 3509.65,4098.25 v2(3525.26,4082.63)
  SIG_2 w6: v2(3525.26,4082.63) 3541.29,4082.63 3561.85,4103.19 3666.08,4103.19 v5@3798.88,4235.99
  Bottom Layer w8: v1(1666.28,6011.85) 3379.38,6011.85 v1(3476.94,6109.41)
R_OSPI0_D0_9: R266.1 U33.D3 | length 59.1
  Top Layer w8: v1@4028.73,2760.79 U33.D3@4047.37,2779.44
  Bottom Layer w8: v1@4028.73,2760.79 4047.42,2779.48 R266.1@4053.76,2779.48
  other v1: 4028.73,2762.85
R_OSPI0_D1_9: R267.1 U33.D2 | length 112.3
  Top Layer w8: R267.1@4027.58,2635.92 4027.58,2720.27 U33.D2@4047.37,2740.06
R_OSPI0_D2_9: R268.1 U33.C4 | length 115.9
  Top Layer w8: R268.1@3986.5,2925.84 3986.5,2840.31 U33.C4@4008,2818.81
R_OSPI0_D3_9: R269.1 U33.D4 | length 121.6
  Top Layer w8: U33.D4@4047.37,2818.81 4065.67,2837.1 4065.67,2875.05 4082.42,2891.8 R269.1@4082.42,2925.84
R_OSPI0_D4_9: R270.1 U33.D5 | length 67.7
  Top Layer w8: R270.1@4047.22,2925.84 4047.37,2925.69 U33.D5@4047.37,2858.18
R_OSPI0_D5_9: R271.1 U33.E3 | length 105.7
  Top Layer w8: U33.E3@4086.74,2779.44 4192.21,2779.44 R271.1@4192.38,2779.61
R_OSPI0_D6_9: R272.1 U33.E2 | length 105.7
  Top Layer w8: U33.E2@4086.74,2740.06 4192.22,2740.06 R272.1@4192.38,2739.9
R_OSPI0_D7_9: R273.1 U33.E1 | length 66.6
  Top Layer w8: U33.E1@4086.74,2700.69 4086.74,2634.18 R273.1@4086.79,2634.13
R_OSPI0_DQS_9: R274.1 U33.C3 | length 53.2
  Top Layer w8: v1@3991.41,2762.85 U33.C3@4008,2779.44
  Bottom Layer w8: v1@3991.41,2762.85 4007.81,2779.24 R274.1@4007.81,2785.76
  other v1: 3996.49,2762.85
RESET_ETH_1: J11.21 J12.22 J13.22 U55.1 | length 7962.2
  Top Layer w8: v1(373.03,5598.3) J11.21@411.42,5598.3 ; v1(1760.77,6109.41) J13.22@1760.77,6147.8 ; v1(3571.43,6109.41) J12.22@3571.43,6147.8 ; U55.1@5248.64,3037.92 v1(5248.64,3069.73)
  SIG_1 w6: v1(3571.43,6109.41) 3618.15,6062.68 3774.1,6062.68 4447.67,5389.11 4447.67,4783.39 4877.47,4353.59 5065.22,4353.59 5205.72,4213.09 5205.72,4070.01 4950.77,3815.06 4950.77,3606.23 5262.64,3294.36 5262.64,3083.74 v1(5248.64,3069.73)
  Bottom Layer w8: v1(373.03,5598.3) 417.53,5642.8 417.53,5969.99 566.28,6118.74 1298.13,6118.74 1333.73,6154.34 1684.07,6154.34 1729,6109.41 v1(1760.77,6109.41) 1761.27,6108.91 3094.88,6108.91 3116.24,6130.27 3550.57,6130.27 v1(3571.43,6109.41)
RESET_MSDI: R191.1 U31.21 U50.7 | length 9182.5
  Top Layer w8: R191.1@320.32,902 349.26,902 v1(366.43,884.83) 449.66,884.83 458.12,893.29 U31.21@458.12,929.75 ; v1(5307.87,3505.65) U50.7@5307.87,3553.51
  SIG_2 w6: v1(366.43,884.83) 366.43,846.78 400.08,813.13 1400.42,813.13 2748.57,2161.28 4863.86,2161.28 5331.24,2628.66 6359.03,2628.66 6620.46,2890.09 6620.46,3166.33 6638.53,3184.4 6638.53,3214.96 6414.6,3438.89 5374.63,3438.89 v1(5307.87,3505.65)
RESET_TCAL: R450.2 U51.6 U55.24 | length 2016.7
  Top Layer w8: U51.6@4710.5,4309.29 v1(4754.94,4309.29) ; U55.24@5274.23,3012.33 5291.24,3012.33 5295.93,3017.02 5295.93,3039.89 5343.1,3087.06 R450.2@5344.09,3087.06 5344.09,3118.26 5502,3276.17 5502,3359.64 v1(5537.27,3394.92)
  SIG_3 w6: v1(4754.94,4309.29) 4802.21,4309.29 5036.1,4075.41 5310.07,4075.41 5589.85,3795.62 5589.85,3490.65 5537.27,3438.07 v1(5537.27,3394.92)
RESET_TCAL_TPLD_28: U50.8 U51.18 | length 1699.2
  Top Layer w8: U51.18@4482.15,4334.89 v1(4526.59,4334.89) ; v1(5236.96,4110.28) 5463.41,3883.83 5463.41,3710.5 5392.73,3639.81 5345.64,3639.81 5327.55,3621.72 U50.8@5327.55,3553.51
  PWR/SIG_1 w6: v1(4526.59,4334.89) 4505.68,4313.97 4505.68,4185.79 4559.37,4132.09 5215.15,4132.09 v1(5236.96,4110.28)
RESET_TPS_1: Q22.1 R400.1 R442.2 U44.4 | length 354.8
  Top Layer w8: U44.4@4752.48,4734.05 4752.72,4734.29 4916.25,4734.29 v1(4916.49,4734.52)
  Bottom Layer w8: R442.2@4898.9,4551.15 4898.9,4716.94 v1(4916.49,4734.52)
RESET_TXE: R448.2 U50.9 U54.31 | length 1548.7
  Top Layer w8: U50.9@5347.24,3553.51 5347.24,3501.87 v1(5366.25,3482.86) ; v2(6554.61,3239.27) R448.2@6593.69,3239.27 ; U54.31@6570.43,3127.05 6570.43,3183.31 6593.69,3206.57 R448.2@6593.69,3239.27 ; R448.2@6596.23,3241.82 R448.2@6593.69,3239.27
  SIG_1 w6: v1(5366.25,3482.86) 6338.93,3482.86 6554.61,3267.18 v2(6554.61,3239.27)
RGMII1_RD0: R241.2 U13.12 | length 2759.8
  Top Layer w9.9: U13.12@3296.94,6547.96 v1(3296.94,6595.09) ; R241.2@3764.48,4355.71 v1(3764.48,4377.1)
  SIG_1 w3.6: v1(3296.94,6595.09) 3334.33,6632.48 3391.66,6632.48 3424.96,6599.18 3424.96,6568.22 3424.96,6566.41 ccw(c3436.76,6566.41) 3436.76,6554.61 3440.31,6554.61 cw(c3440.31,6542.81) 3440.31,6531.01 3436.76,6531.01 ccw(c3436.76,6519.21) 3424.96,6519.21 3424.96,6502.8 3424.96,6426.87 3424.96,6362.56 3376.26,6313.86 3376.26,6254.99 3362.13,6240.86 3362.13,5965.35 3422.84,5904.64 3422.84,5629.23 3375.11,5581.5 3375.11,5206.82 3320.06,5151.77 3320.06,5007.82 3764.48,4563.4 v1(3764.48,4377.1)
RGMII1_RD1: R242.2 U13.13 | length 2744.4
  Top Layer w9.9: U13.13@3277.25,6547.96 v1(3277.25,6573.35) ; R242.2@3731.23,4355.71 v1(3731.23,4377.1)
  SIG_1 w3.6: v1(3277.25,6573.35) 3333.02,6517.58 3333.02,6244.99 3338.74,6239.27 3338.74,5953.28 3338.74,5951.48 ccw(c3350.54,5951.48) 3350.54,5939.68 3354.76,5939.68 cw(c3354.76,5927.88) 3354.76,5916.08 3332.18,5916.08 ccw(c3332.18,5904.28) 3332.18,5892.48 3354.76,5892.48 cw(c3354.76,5880.68) 3354.76,5868.88 3332.18,5868.88 ccw(c3332.18,5857.08) 3332.18,5845.28 3354.76,5845.28 cw(c3354.76,5833.48) 3354.76,5821.68 3332.18,5821.68 ccw(c3332.18,5809.88) 3332.18,5798.08 3354.76,5798.08 cw(c3354.76,5786.28) 3354.76,5774.48 3350.54,5774.48 ccw(c3350.54,5762.68) 3338.74,5762.68 3338.74,5746.16 3338.74,5593.5 3320.35,5575.11 3320.35,5512.56 3338.74,5494.17 3338.74,5211.06 3282.73,5155.05 3282.73,5008.9 3731.23,4560.4 v1(3731.23,4377.1)
RGMII1_RD2: R243.2 U13.14 | length 2740.7
  Top Layer w9.9: U13.14@3257.57,6547.96 v1(3257.57,6595.09) ; R243.2@3697.98,4355.71 v1(3697.98,4377.1)
  SIG_1 w3.6: v1(3257.57,6595.09) 3257.57,6539.78 3278.67,6518.68 3278.67,6416.01 3272.2,6409.54 3272.2,5959.23 3272.2,5941.64 cw(c3260.4,5941.64) 3260.4,5929.84 3259.94,5929.84 ccw(c3259.94,5918.04) 3259.94,5906.24 3278.05,5906.24 cw(c3278.05,5894.44) 3278.05,5882.64 3259.94,5882.64 ccw(c3259.94,5870.84) 3259.94,5859.04 3278.05,5859.04 cw(c3278.05,5847.24) 3278.05,5835.44 3259.94,5835.44 ccw(c3259.94,5823.64) 3259.94,5811.84 3278.05,5811.84 cw(c3278.05,5800.04) 3278.05,5788.24 3259.94,5788.24 ccw(c3259.94,5776.44) 3259.94,5764.64 3260.4,5764.64 cw(c3260.4,5752.84) 3272.2,5752.84 3272.2,5751.04 3272.2,5277.2 3288.73,5260.67 3288.73,5215.24 3253.42,5179.94 3253.42,5098.52 3229.52,5074.62 3229.52,5016.03 3697.98,4547.58 v1(3697.98,4377.1)
RGMII1_RD3: R244.2 U13.15 | length 2748.3
  Top Layer w9.9: U13.15@3237.88,6547.96 v1(3237.88,6573.35) ; R244.2@3664.72,4355.71 v1(3664.72,4377.1)
  SIG_1 w3.6: v1(3237.88,6573.35) 3237.88,6473.96 3204.11,6440.19 3204.11,6254.09 3228.5,6229.7 3229.56,6228.64 3229.56,6203.82 3230.61,6202.77 3231.08,6202.3 cw(c3224.97,6187.8) 3231.08,6173.29 3230.61,6172.82 3229.56,6171.77 3229.56,5947.03 3229.56,5931.44 cw(c3217.76,5931.44) 3217.76,5919.64 3211.36,5919.64 ccw(c3211.36,5907.84) 3211.36,5896.04 3228.81,5896.04 cw(c3228.81,5884.24) 3228.81,5872.44 3211.36,5872.44 ccw(c3211.36,5860.64) 3211.36,5848.84 3228.81,5848.84 cw(c3228.81,5837.04) 3228.81,5825.24 3211.36,5825.24 ccw(c3211.36,5813.44) 3211.36,5801.64 3228.81,5801.64 cw(c3228.81,5789.84) 3228.81,5778.04 3211.36,5778.04 ccw(c3211.36,5766.24) 3211.36,5754.44 3217.76,5754.44 cw(c3217.76,5742.64) 3229.56,5742.64 3229.56,5740.84 3229.56,5731.85 3222.4,5724.7 3222.4,5339.85 3149.85,5267.3 3149.85,5125.34 3201.46,5073.74 3201.46,5000.67 3664.72,4537.4 v1(3664.72,4377.1)
RGMII1_RXC: R246.2 U13.10 | length 2750.4
  Top Layer w9.9: v1(3219.47,6641.71) 3316.67,6641.71 3336.31,6622.07 U13.10@3336.31,6547.96 ; R246.2@3631.47,4355.71 v1(3631.47,4377.1)
  SIG_1 w3.6: v1(3219.47,6641.71) 3219.47,6493 3183.75,6457.29 3183.75,6453.75 3183.75,6374.63 3183.75,6267.45 3170.53,6254.24 3170.53,6175.12 3183.72,6161.94 3183.72,6127.91 3191.26,6120.37 3191.26,5664.26 3183.72,5656.72 3183.72,5334.09 3125.88,5276.26 3125.88,5033.9 3631.47,4528.31 v1(3631.47,4377.1)
RGMII1_TD0: R247.2 U12.2 | length 2564.7
  Top Layer w9.9: R247.2@3564.96,4355.71 v1(3564.96,4377.1) ; U12.2@3777.25,6547.96 v1(3777.25,6595.09)
  SIG_3 w3.6: v1(3564.96,4377.1) 3564.96,4626.6 3833.76,4895.39 3833.76,5637.26 3841.59,5645.1 3841.59,6046.68 3776.16,6112.1 3776.16,6194.29 3776.05,6194.4 3776.05,6332.75 3776.05,6334.55 ccw(c3764.25,6334.55) 3764.25,6346.35 3755.82,6346.35 cw(c3755.82,6358.15) 3755.82,6369.95 3807.2,6369.95 ccw(c3807.2,6381.75) 3807.2,6393.55 3787.85,6393.55 cw(c3787.85,6405.35) 3776.05,6405.35 3776.05,6439.84 3797.04,6460.82 3797.04,6575.31 v1(3777.25,6595.09)
RGMII1_TD1: R248.2 U12.3 | length 2565
  Top Layer w9.9: R248.2@3531.71,4355.71 v1(3531.71,4377.1) ; U12.3@3757.57,6547.96 v1(3757.57,6573.35)
  SIG_3 w3.6: v1(3531.71,4377.1) 3531.71,4606.5 3826.22,4901.01 3826.22,5637.26 3713.15,5750.33 3713.15,6056.72 3713.15,6058.52 ccw(c3701.35,6058.52) 3701.35,6070.32 3694.65,6070.32 cw(c3694.65,6082.12) 3694.65,6093.92 3743.74,6093.92 ccw(c3743.74,6105.72) 3743.74,6117.52 3724.95,6117.52 cw(c3724.95,6129.32) 3713.15,6129.32 3713.15,6145.83 3713.15,6400.55 3781.46,6468.86 3781.46,6549.46 v1(3757.57,6573.35)
RGMII1_TD2: R249.2 U12.4 | length 2565.6
  Top Layer w9.9: R249.2@3498.46,4355.71 v1(3498.46,4377.1) ; U12.4@3737.88,6547.96 v1(3737.88,6595.09)
  SIG_3 w3.6: v1(3498.46,4377.1) 3498.46,4588.85 3818.68,4909.08 3818.68,5634.14 3643.45,5809.38 3643.45,5951.6 3643.45,6040.25 3643.45,6123.74 3601.52,6165.67 3601.52,6205.74 3646.73,6250.96 3646.73,6404.38 3737.88,6495.52 v1(3737.88,6595.09)
RGMII1_TD3: R250.2 U12.5 | length 2571.6
  Top Layer w9.9: R250.2@3465.2,4355.71 v1(3465.2,4377.1) ; U12.5@3718.2,6547.96 v1(3718.2,6573.35)
  SIG_3 w3.6: v1(3465.2,4377.1) 3465.2,4584.44 3800.59,4919.83 3800.59,5629.65 3553.26,5864.28 3553.26,5869.51 3553.26,6051.52 ; 3553.26,6036.51 3553.26,6143.34 3561.39,6151.47 3561.39,6211.3 3627.99,6277.89 3627.99,6350.11 3627.99,6441.91 3627.99,6461.77 3659.25,6493.04 3659.25,6514.41 v1(3718.2,6573.35)
RGMII1_TX_CTL: R251.2 U12.6 | length 2567.8
  Top Layer w9.9: R251.2@3398.7,4355.71 v1(3398.7,4377.1) ; U12.6@3698.51,6547.96 v1(3698.51,6595.09)
  SIG_3 w3.6: v1(3398.7,4377.1) 3398.7,4396.72 3398.7,5026.5 3363.77,5061.43 3363.77,5462.54 3373.32,5472.09 3373.32,5897.46 3443.97,5968.11 3443.97,6132.7 3483.94,6172.68 3483.94,6241.36 3505.54,6262.95 3505.54,6375.19 3505.54,6376.99 ccw(c3493.74,6376.99) 3493.74,6388.79 3493.42,6388.79 cw(c3493.42,6400.59) 3493.42,6412.39 3500.61,6412.39 ccw(c3500.61,6424.19) 3500.61,6435.99 3493.42,6435.99 cw(c3493.42,6447.79) 3493.42,6459.59 3493.74,6459.59 ccw(c3493.74,6471.39) 3505.54,6471.39 3505.54,6494.27 3505.54,6503.37 3597.26,6595.09 v1(3698.51,6595.09)
RGMII1_TXC: R252.2 U12.7 | length 2563.2
  Top Layer w9.9: R252.2@3431.95,4355.71 v1(3431.95,4377.1) ; U12.7@3678.83,6547.96 v1(3678.83,6573.35)
  SIG_3 w3.6: 3431.92,4402.59 3431.92,4909.72 3501.38,4979.18 3501.38,6057.23 3525.96,6081.81 3525.96,6143.61 3521.83,6147.74 3521.83,6234.33 3561.8,6274.3 3561.8,6381.72 3561.8,6383.52 ccw(c3550,6383.52) 3550,6395.32 3531.05,6395.32 cw(c3531.05,6407.12) 3531.05,6418.92 3569.55,6418.92 ccw(c3569.55,6430.72) 3569.55,6442.52 3524.18,6442.52 cw(c3524.18,6454.32) 3524.18,6466.12 3550,6466.12 ccw(c3550,6477.92) 3561.8,6477.92 3561.8,6495.26 3561.8,6510.79 3624.36,6573.35 v1(3678.83,6573.35) ; v1(3431.95,4377.1) 3431.95,4402.56
RXD2_TCAN1046_UART: J21.2 U8.13 U32.C13 | length 2197.1
  Top Layer w8: v5(2364.67,2512.62) U8.13@2364.67,2545.25
  Top Layer w9.9: v2(3115.81,3988.14) U32.C13@3131.56,3972.4
  PWR/SIG_1 w4.5: 3045.48,3940.8 3062.83,3940.8 3067.12,3945.09 3067.12,3966.53 3073.55,3972.97 3100.64,3972.97 v2(3115.81,3988.14)
  PWR/SIG_1 w6: J21.2@2755.83,2579.3 2800.26,2534.87 2886.63,2534.87 2903.88,2552.12 2903.88,3460.08 2962.75,3518.95 2962.75,3834.71 2975.99,3847.96 2975.99,3871.32 3045.48,3940.8
  Bottom Layer w8: v5(2364.67,2512.62) 2689.15,2512.62 J21.2@2755.83,2579.3
S0_TMUX1308: C374.2 J28.8 R426.1 | length 1073.4
  Top Layer w8: R426.1@5860.38,3247.11 C374.2@5937.75,3247.11 ; C374.2@5940.38,3247.11 5940.38,3207.55 6026.55,3121.38 6026.55,2824.52 6108.74,2742.34 J28.8@6108.74,2320.81
S1_TMUX1308: C375.2 J28.7 R427.1 | length 1941.9
  Top Layer w8: C375.2@5557.43,3243.52 5557.43,3205.21 5511.93,3159.71 5511.93,2918.85 5318.16,2725.08 5318.16,2273.45 5383.49,2208.12 5952.93,2208.12 6008.74,2263.92 J28.7@6008.74,2320.81 ; C375.2@5559.26,3243.52 5630.51,3243.52 R427.1@5633.19,3246.2
S2_TMUX1308: C376.2 J28.6 R428.1 | length 1238.7
  Top Layer w8: R428.1@5633.19,3068.62 5558.17,3068.62 C376.2@5557.43,3069.36 5557.43,2899.46 5620.65,2836.23 5876.88,2836.23 6051.75,2661.36 6051.75,2515.81 5908.74,2372.79 J28.6@5908.74,2320.81
S3_TMUX1308: C377.2 J28.5 R429.1 | length 1191.6
  Top Layer w8: J28.5@5808.74,2320.81 5808.74,2276.33 5834.02,2251.05 5933.94,2251.05 5959.81,2276.92 5959.81,2372.41 6080.14,2492.74 6080.14,2709.95 5940.38,2849.72 C377.2@5940.38,3068.7 ; R429.1@5860.38,3068.7 5927,3068.7 C377.2@5933.2,3062.5
S4_TMUX1308: C378.2 J28.4 R430.1 | length 639.2
  Top Layer w8: J28.4@5708.74,2320.81 5708.74,2382.91 5740.87,2415.04 5902.56,2415.04 6028.05,2540.53 6028.05,2631.32 6017.52,2641.85 C378.2@6004.89,2641.85 ; R430.1@5922.39,2642.54 C378.2@5996.61,2642.54
S5_TMUX1308: C379.2 J28.3 R431.1 | length 877.9
  Top Layer w8: J28.3@5608.74,2320.81 5608.74,2275.11 5593.45,2259.82 5481.92,2259.82 5460.58,2281.17 5460.58,2393.51 5424,2430.09 5424,2638.48 5464.42,2678.9 5603.62,2678.9 v1(5628.18,2703.46) 5628.18,2735.31 R431.1@5627.59,2735.89
  Bottom Layer w8: C379.2@5627.59,2735.89 5628.18,2735.31 v1(5628.18,2703.46)
S6_TMUX1308: C380.2 J28.2 R432.1 | length 443
  Top Layer w8: J28.2@5508.74,2320.81 5508.74,2397.88 5453.2,2453.43 5453.2,2629.45 5465,2641.26 5479.71,2641.26 R432.1@5559.71,2641.26
S7_TMUX1308: C381.2 J28.1 R433.1 | length 652.3
  Top Layer w8: J28.1@5408.74,2320.81 5408.74,2262.1 5436.02,2234.81 5623.29,2234.81 5659.25,2270.78 5659.25,2370.79 5683.23,2394.77 R433.1@5683.23,2577.76
SAFE_OUT1_2: Q15.1 R341.2 | length 1537.2
  Bottom Layer w8: R341.2@3356.85,5345.11 3304.36,5345.11 3268.81,5380.66 3268.81,5543.51 3333.6,5608.3 4276,5608.3 4320.63,5563.68 4449.69,5563.68 4461.84,5575.82 Q15.1@4461.84,5604.05
SAFETY_ERRORn: Q16.1 U32.D4 U41.18 | length 4908.2
  Top Layer w8: U41.18@3812.24,5339.35 3855.65,5339.35 3870.7,5354.4 3938.65,5354.4 3949.91,5343.14 4146.4,5343.14 v1(4160.95,5357.69) 4666.62,5357.69 4683.74,5374.81 4683.74,5629.96 4654.28,5659.43 4538.16,5659.43 v1(4427.42,5770.16)
  Top Layer w9.9: v2(3147.31,3673.18) U32.D4@3163.06,3688.93
  SIG_1 w4.5: v2(3147.31,3673.18) 3163.25,3689.12 3163.25,3843.44 3131.6,3875.08 3131.6,4027.23 3139.66,4035.29 3633.48,4035.29 3638.43,4035.29
  SIG_1 w6: 3638.43,4035.29 3653.5,4050.35 3653.5,4157.19 3796.5,4300.2 3796.5,4588.35 3363.98,5020.87 3363.98,5089.47 3414.15,5139.64 3414.15,5414.02 3454.17,5454.03 3500.53,5454.03 3554.52,5400.04 3789.84,5400.04 3855.98,5466.19 4052.46,5466.19 v1(4160.95,5357.69)
  Bottom Layer w8: v1(4427.42,5770.16) Q16.1@4462.11,5770.16
SCLK: J17.4 R85.1 R110.1 R175.1 R361.1 U27.1 U28.14 U29.14 | length 10160.9
  Top Layer w8: U28.14@3133.27,921.24 v1(3133.27,1016.66) ; R85.1@4268.65,1516.22 v1(4268.65,1548.84) ; R175.1@6593.73,767.75 v1(6630.41,767.75) ; v1(6723.63,1471.74) 6733.89,1461.48 U27.1@6733.89,1447.45 ; v2(7071.83,3371.31) 7118.25,3371.31 R110.1@7118.91,3370.65 ; U29.14@7457.13,2596.27 v1(7457.13,2631.95)
  SIG_1 w6: v1(6630.41,767.75) 6709.56,846.9 6709.56,1178.99 6746.12,1215.56 6746.12,1449.25 v1(6723.63,1471.74) 6776.58,1524.69 6776.58,1718.57 7018.02,1960.01 7062.39,1960.01 7286.54,2184.16 7286.54,2461.36 v1(7457.13,2631.95) 7472.46,2647.27 7472.46,3115.34 7216.49,3371.31 v2(7071.83,3371.31)
  SIG_3 w6: v1(3133.27,1016.66) 3168.52,1051.91 3334,1051.91 3378.1,1096.01 3497.82,1096.01 3582.09,1180.29 4077.5,1180.29 4189.34,1292.13 4189.34,1469.52 v1(4268.65,1548.84) 4269.12,1548.37 4302.06,1548.37 4435.21,1415.22 6051.33,1415.22 6124.05,1487.95 6707.42,1487.95 v1(6723.63,1471.74)
  Bottom Layer w8: v1(3133.27,1016.66) 3206.94,1090.33 3206.94,1339.3 3365.88,1498.23 3365.88,2591.98 3246.96,2710.89 J17.4@3246.96,2937.36 3296.07,2986.47 3296.07,3092.75 3346.34,3143.02 3346.34,3459.8 R361.1@3346.21,3459.93
SCLK_15: R85.2 U20.16 U21.16 | length 931.1
  Top Layer w8: U21.16@3703.19,1111.11 v1(3703.19,1137.47) ; v1(4205.66,1555.2) R85.2@4205.66,1516.22 4205.84,1516.04 U20.16@4205.84,1461.12
  Bottom Layer w8: v1(3703.19,1137.47) 3722.86,1157.14 4038.19,1157.14 4189.8,1308.76 4189.8,1539.34 v1(4205.66,1555.2)
SCLK_IO: J19.2 J20.13 R365.1 U31.16 U54.29 | length 8585.2
  Top Layer w8: U31.16@497.49,1158.1 v1(497.49,1246.15) ; v1(2461.03,1811.89) 2996.06,2346.91 2996.06,3112.46 v1(3134.71,3251.11) 3183.54,3299.94 3183.54,3406.91 3214.73,3438.1 3214.73,3500.23 R365.1@3214.82,3500.32 ; U54.29@6609.8,3127.05 6610.16,3127.42 6610.16,3204.33 v2(6610.52,3204.69)
  Top Layer w10: J20.13@2461.03,1703.25 v1(2461.03,1811.89)
  SIG_2 w6: v1(3134.71,3251.11) 3152.42,3233.4 J19.2@4167.42,3233.4 4279.45,3233.4 4369.11,3143.74 4628.77,3143.74 5121.67,2650.84 6326.61,2650.84 6552.5,2876.73 6552.5,3103.28 6610.52,3161.3 v2(6610.52,3204.69)
  Bottom Layer w8: v1(497.49,1246.15) 1895.3,1246.15 v1(2461.03,1811.89)
SCLK_PMIC: J18.2 R363.1 U41.33 | length 2963
  Top Layer w7: v1(2354.77,4543.83) 2354.77,5052.21 2590.16,5287.61 3259.42,5287.61 3306.83,5335.01 3404.46,5335.01 3438.94,5300.53 3516.42,5300.53 U41.33@3516.97,5299.98
  Top Layer w8: J18.2@2661.16,3828.88 2699.46,3790.57 R363.1@2964.21,3790.57
  SIG_3 w6: v1(2354.77,4543.83) 2354.77,4467.19 2401.94,4420.02 2401.94,4354.98 2534.55,4222.38 2534.55,3955.48 J18.2@2661.16,3828.88
SDFM_CLK2: J21.3 U8.11 U32.B15 | length 2142.8
  Top Layer w8: U8.11@2404.04,2545.25 2404.04,2590.4 2445.27,2631.63 2803.5,2631.63 J21.3@2855.83,2579.3
  Top Layer w9.9: v2(3084.32,4051.14) U32.B15@3100.07,4035.39
  PWR/SIG_1 w4.5: 3037.67,3965.27 3037.67,4035.9 3052.9,4051.14 v2(3084.32,4051.14)
  PWR/SIG_1 w6: J21.3@2855.83,2579.3 2855.83,3783.43 3037.67,3965.27
SDI: J17.6 R88.1 R104.1 R176.1 R362.1 U27.2 U28.15 | length 10144.7
  Top Layer w8: U28.15@3113.59,921.24 v1(3113.59,968.8) 3113.59,1144.06 3158.51,1188.98 3158.51,2154.5 3024.54,2288.46 3024.54,2543.45 3146.96,2665.87 J17.6@3146.96,2937.36 ; R88.1@4375.29,1385.6 v1(4427.79,1385.6) ; R176.1@6587.54,825.33 6587.93,825.73 v1(6630.41,825.73) ; v1(6698.99,1437.24) 6700.74,1438.99 6715.86,1438.99 6721.12,1433.73 6721.4,1433.73 6726.08,1429.04 6726.08,1428.88 6727.2,1427.76 U27.2@6733.89,1427.76 ; v2(7078.2,3551.58) 7118.79,3551.58 R104.1@7118.91,3551.46
  SIG_1 w6: v1(6630.41,825.73) 6678.54,873.86 6678.54,1219.72 6730.16,1271.34 6730.16,1406.07 v1(6698.99,1437.24) 6698.99,1483.63 6745.79,1530.42 6745.79,1717.46 7017.07,1988.73 7056.64,1988.73 7263.4,2195.5 7263.4,2505.71 7445.23,2687.54 7445.23,2739.93 7427.93,2757.24 7427.93,3145.82 7279.01,3294.73 7107.14,3294.73 7052.46,3349.41 7052.46,3396.56 7078.2,3422.3 v2(7078.2,3551.58)
  SIG_3 w6: v1(3113.59,968.8) 3193.05,968.8 3217.67,993.41 3318.8,993.41 3394.38,1068.99 3686.06,1068.99 3761.64,1144.58 4105.48,1144.58 4346.5,1385.6 v1(4427.79,1385.6) 6388.04,1385.6 6462.81,1460.37 6675.86,1460.37 v1(6698.99,1437.24)
  Bottom Layer w8: J17.6@3146.96,2937.36 3094.45,2989.86 3094.45,3113.92 3183.51,3202.98 3183.51,3408.72 3236.74,3461.96 R362.1@3236.74,3498.78
SDI_15: R88.2 U20.13 | length 107
  Top Layer w8: U20.13@4205.84,1384.35 4311.05,1384.35 R88.2@4312.3,1385.6
SDI_IO: J19.3 J20.14 R366.1 U31.17 U54.30 | length 8745.8
  Top Layer w8: U31.17@477.8,1158.1 v1(477.8,1200.18) ; J20.14@2461.03,1508.37 2461.03,1590.87 2414.32,1637.58 2414.32,1823.35 2908.69,2317.72 2908.69,2600.66 2892.05,2617.3 2892.05,3052.68 v1(3093.24,3253.87) ; U54.30@6590.11,3127.05 6590.11,3167.36 6590.95,3168.2 6590.95,3174.15 v2(6592.21,3175.41)
  Top Layer w10: v1(2461.03,1399.74) J20.14@2461.03,1508.37
  SIG_2 w6: v1(3093.24,3253.87) 3094.58,3255.21 3106.76,3255.21 3120.66,3269.11 3142.17,3269.11 3147.86,3263.41 4097.44,3263.41 J19.3@4167.42,3333.4 4255.49,3333.4 4381.96,3206.93 4704.55,3206.93 5144.08,2767.39 5619.18,2767.39 5697.45,2689.12 6325.49,2689.12 6534.76,2898.39 6534.76,3117.96 v2(6592.21,3175.41)
  Bottom Layer w8: v1(477.8,1200.18) 2261.47,1200.18 v1(2461.03,1399.74) ; v1(3093.24,3253.87) 3161.29,3321.92 3161.29,3408.44 3193.88,3441.03 R366.1@3193.88,3498.78
SDI_PMIC: J18.3 R364.1 U41.35 | length 2302.6
  Top Layer w8: J18.3@2661.16,3728.88 2848.5,3728.88 2867.87,3748.25 R364.1@2964.16,3748.25 ; v5@3466.09,5260.61 U41.35@3516.97,5260.61
  SIG_2 w6: J18.3@2661.16,3728.88 2736.83,3804.55 2736.83,4372.99 3068.17,4704.33 3068.17,4992.09 3270.56,5194.48 3317.17,5194.48 3353.68,5230.99 3436.47,5230.99 v5(3465.94,5260.46)
SDO_DRV8245_18: U28.16 U29.15 | length 6587.1
  Top Layer w8: v1(2993.98,1101.22) 3022.83,1130.06 3082.31,1130.06 3093.9,1118.48 U28.16@3093.9,921.24 ; v1(7428.77,2560.72) 7437.44,2569.39 U29.15@7437.44,2596.27
  Bottom Layer w6: 3075.99,828.08 3183.45,828.08
  Bottom Layer w8: v1(2993.98,1101.22) 2923.48,1030.71 2923.48,884.01 2979.4,828.08 3075.99,828.08 ; 3183.45,828.08 3338.58,828.08 3347.92,837.42 3393.95,837.42 3402.17,845.65 4391.77,845.65 4409.82,827.6 4751.9,827.6 4778.58,854.28 6223.42,854.28 6243.04,873.9 6557.57,873.9 6739.63,1055.96 7012.49,1055.96 7200.76,1244.23 7200.76,1510.23 7428.77,1738.24 7428.77,2295.55 7347.84,2376.48 7347.84,2516.42 7392.62,2561.2 7428.29,2561.2 v1(7428.77,2560.72)
SDO_IO: J19.4 R187.2 R367.1 R449.1 U32.H2 | length 8846.5
  Top Layer w8: R187.2@432.13,1223.81 v1(432.13,1245.22) ; R367.1@2361.03,1831.32 v1(2361.03,1860.52) ; v2(6444.89,3042.51) 6446.81,3040.59 6450.77,3040.59 6466.6,3024.76 R449.1@6467.39,3024.76
  Top Layer w9.9: v2(3273.29,3610.19) U32.H2@3289.04,3625.94
  PWR/SIG_1 w4.5: 3257.51,3565.14 3257.51,3586.72 3273.29,3602.51 v2(3273.29,3610.19) 3289.74,3626.63 3319.86,3626.63 3341.73,3648.5 3341.73,3672.87 3357.97,3689.11 3561.35,3689.11 3571.88,3678.59 3571.88,3660.78 3633.48,3599.18
  PWR/SIG_1 w6: v1(2361.03,1860.52) 2437.62,1783.94 2982.51,1783.94 3172.04,1973.47 3172.04,2594.34 3290.21,2712.51 3290.21,3072.38 3257.51,3105.09 3257.51,3565.14 ; 3633.48,3599.18 3639.76,3592.89 3764.35,3592.89 3923.84,3433.4 J19.4@4167.42,3433.4 4232.27,3368.56 4232.27,2989.85 4305.68,2916.44 4774.77,2916.44 5033.51,3175.18 5424.96,3175.18 5530.68,3069.47 6064.06,3069.47 6091.02,3042.51 v2(6444.89,3042.51)
  Bottom Layer w8: v1(432.13,1245.22) 457.46,1270.55 1771.06,1270.55 v1(2361.03,1860.52)
SDO_LD: J17.8 R98.1 R105.1 R159.1 R170.1 R177.1 U32.J3 | length 10308.6
  Top Layer w8: R177.1@6587.15,882.89 6587.31,882.74 v1(6630.41,882.74) ; R159.1@6597.86,1408.08 v1(6597.86,1430.22) ; v2(7005.71,3509.92) 7064.49,3509.92 7083.23,3491.19 R105.1@7118.91,3491.19 ; R170.1@7417.99,2682.93 v1(7417.99,2703.75)
  Top Layer w9.9: v2(3304.79,3641.69) U32.J3@3320.54,3657.44
  Top Layer w15: R98.1@3825.8,1082.54 v1(3825.8,1104.54)
  SIG_1 w6: v1(6630.41,882.74) 6597.86,915.28 6597.86,1183.36 6656,1241.51 6656,1324.97 6597.86,1383.12 v1(6597.86,1430.22) 6597.86,1658.76 6952.45,2013.36 7049.1,2013.36 7236.49,2200.74 7236.49,2522.25 v1(7417.99,2703.75) 7417.99,3141.7 7274.9,3284.8 7103.02,3284.8 7042.53,3345.3 7042.53,3400.67 7068.27,3426.41 7068.27,3505.48 7063.82,3509.92 v2(7005.71,3509.92)
  SIG_3 w6: v1(3825.8,1104.54) 3953.11,1104.54 3981.65,1076 4690.89,1076 4802.93,1188.04 4910.36,1188.04 4957.72,1235.4 5531.81,1235.4 5627.68,1331.27 6366.12,1331.27 6465.07,1430.22 v1(6597.86,1430.22)
  Bottom Layer w8: v2(3304.79,3641.69) 3324.64,3621.84 3324.64,3195.01 3195.07,3065.44 3195.07,2907.85 3173.48,2886.26 3098.06,2886.26 J17.8@3046.96,2937.36 3046.96,2880.11 3082.07,2845 3082.07,1138.16 3098.67,1121.56 3098.67,1018.62 3129.95,987.34 3389.6,987.34 3403.78,973.16 3647.98,973.16 3745.59,1070.76 3792.03,1070.76 v1(3825.8,1104.54)
SDO_PMIC: J18.4 R340.1 U32.C7 | length 2570.5
  Top Layer w9.9: v2(3115.81,3767.67) U32.C7@3131.56,3783.42
  SIG_1 w4.5: J18.4@2661.16,3628.88 2801.64,3769.36 3025.54,3769.36 3039.47,3783.3 3100.19,3783.3 v2(3115.81,3767.67)
  SIG_2 w6: J18.4@2661.16,3628.88 2583.45,3706.58 2583.45,3998.95 2632.36,4047.85 2632.36,4344.86 2911.47,4623.97 2934.13,4623.97 3004.37,4694.21 3041.78,4731.62 v1(3041.78,4893.38)
  Bottom Layer w8: v1(3041.78,4893.38) 3041.78,5200.28 3112.81,5271.31 R340.1@3228.76,5271.31
SDO_TPS2HCS10_15: R89.1 R97.1 | length 534.7
  Top Layer w15: R97.1@3876.3,1034.34 v1(3876.3,1070.34)
  Bottom Layer w8: v1(3876.3,1070.34) 4060.03,1070.34 4257.05,1267.36 R89.1@4257.05,1303.66
SENSE_5: R402.1 R403.2 U44.2 | length 221.9
  Top Layer w8: U44.2@4752.48,4682.87 4807.25,4682.87 4848.94,4641.18 4848.94,4593.07 4907.59,4593.07 R402.1@4908.57,4594.06
SH1_17: NT2.1 U27.23 | length 953.4
  Top Layer w8: U27.23@6916.96,1165.95 6916.96,1137.19 v1(6926.94,1127.21)
  Top Layer w20: v1(7648.68,949.23) NT2.1@7693.83,949.23
  SIG_3 w6: v1(6926.94,1127.21) 6947.52,1127.21 6964.55,1110.18 7583.3,1110.18 7665.49,1027.99 7665.49,966.04 v1(7648.68,949.23)
SH2_17: NT3.1 U27.27 | length 511.7
  Top Layer w8: U27.27@6995.7,1165.95 6995.7,1150.16 7010.87,1135 7010.75,1134.88 v1(7009.51,1134.88)
  Top Layer w20: v1(7343.78,1300.21) NT3.1@7388.94,1300.21
  SIG_1 w6: v1(7009.51,1134.88) 7009.51,1177.72 7037.53,1205.74 7249.32,1205.74 v1(7343.78,1300.21)
SH3_17: NT5.1 U27.45 | length 965.1
  Top Layer w8: U27.45@6976.02,1473.04 v1(6976.02,1555.55)
  Top Layer w20: v1(7690.77,1851.79) NT5.1@7735.93,1851.79
  SIG_3 w6: v1(6976.02,1555.55) 7394.54,1555.55 v1(7690.77,1851.79)
SH4_17: NT6.1 U27.49 | length 950.6
  Top Layer w8: U27.49@6897.28,1473.04 v1(6897.28,1555.55)
  Top Layer w20: v1(7353.64,2189.46) NT6.1@7398.79,2189.46
  SIG_1 w6: v1(6897.28,1555.55) 6897.28,1733.1 v1(7353.64,2189.46)
SHIELD_GND: J24.5 J24.10 J24.11 R385.2
SN1_N1_17: NT1.2 U27.16 | length 1005
  Top Layer w8: v1(6779.17,1128.95) U27.16@6779.17,1165.95
  Top Layer w20: v1(7643.21,1013.61) NT1.2@7688.37,1013.61
  SIG_3 w6: v1(6779.17,1128.95) 6779.17,1110.15 6824.18,1065.14 7591.68,1065.14 v1(7643.21,1013.61)
SN2_N1_17: NT4.2 U27.18 | length 1551.9
  Top Layer w8: U27.18@6818.54,1165.95 6818.54,1146.51 6830.51,1134.54 v1(6856.24,1134.54)
  Top Layer w20: v1(7690.77,1912.57) NT4.2@7735.93,1912.57
  SIG_1 w6: v1(6856.24,1134.54) 6892.37,1134.54 6926.99,1169.16 6964.83,1169.16 7119.66,1323.99 7593.51,1323.99 7653.18,1383.66 7653.18,1874.97 v1(7690.77,1912.57)
SOC_CLK_IN_12: C261.1 U32.T1 Y2.1 | length 167.4
  Top Layer w8: U32.T1@3541.01,3594.44 3565.03,3570.43 C261.1@3565.03,3494.17 3621.89,3494.17 Y2.1@3622.12,3494.4
SOC_CLK_OUT_12: C262.2 R329.1 Y2.3 | length 433.2
  Top Layer w8: R329.1@3509.74,3481.65 3509.74,3431.97 3599.54,3342.17 3697.8,3342.17 3726.63,3371 3726.63,3387.57 3727.22,3388.15 3727.22,3430.42 Y2.3@3669.37,3430.42
SOP0_9: R284.2 U35.13 | length 922.7
  SIG_1 w6: v5(3800.61,3291.27) 3840.42,3291.27 4067.31,3518.16 4067.31,3889.21 4028.24,3928.28 v2@3999.37,3928.28
  Bottom Layer w8: R284.2@3799.6,3313.67 3800.1,3313.16 3800.1,3291.78 v5(3800.61,3291.27) ; v2(4001.99,3928.28) 4020.81,3928.28 4037.14,3911.95 U35.13@4079.27,3911.95
SOP1_9: R285.2 U35.12 | length 918.8
  SIG_1 w6: v2(3744.57,3291.27) 3769.42,3291.27 3791.56,3313.41 3840.47,3313.41 4048.67,3521.62 4048.67,3880.95 4028.46,3901.16 v2@3999.59,3901.16
  Bottom Layer w8: v2(3744.57,3291.27) 3744.79,3291.49 3744.79,3313.45 R285.2@3745.02,3313.67 ; v2(4001.99,3902.61) 4004.7,3902.61 4011.11,3896.2 U35.12@4079.27,3896.2
SOP2_9: R286.2 U35.11 | length 916.9
  SIG_1 w6: v2(3689.54,3291.27) 3689.66,3291.39 3702.88,3291.39 3736.3,3324.8 3831.22,3324.8 4030.21,3523.8 4030.21,3872.92 4026.7,3876.44 v2@4001.99,3876.44
  Bottom Layer w8: v2(3689.54,3291.27) R286.2@3689.55,3313.67 ; v2(4001.99,3876.95) 4004.7,3876.95 4008.21,3880.46 U35.11@4079.27,3880.46
SOP3_9: R287.2 U35.10 | length 902
  SIG_1 w6: v2(3634.52,3291.27) 3659.51,3291.27 3704.43,3336.19 3823.31,3336.19 4001.99,3514.87 v2(4001.99,3851.28)
  Bottom Layer w8: R287.2@3634.27,3313.53 R287.2@3634.42,3313.67 3634.47,3313.62 v2(3634.52,3291.27) v2(3634.52,3291.27) ; v2(4001.99,3851.28) 4027.59,3851.28 4041.02,3864.71 U35.10@4079.27,3864.71
SP1_P1_17: NT3.2 Q7.1 Q7.2 Q7.3 Q9.5 Q9.6 Q9.7 Q9.8 Q9.9@7529.2,1164.68 R154.1 U27.15 | length 942.9
  Top Layer w8: v1(6750.05,1140.82) 6759.48,1150.25 U27.15@6759.48,1165.95
  SIG_3 w6: v1(6750.05,1140.82) 6750.05,1110.21 6810.71,1049.56 7576.46,1049.56 v1(7598.89,1027.13)
SP2_P1_17: NT6.2 Q12.1 Q12.2 Q12.3 Q14.5 Q14.6 Q14.7 Q14.8 Q14.9@7535.6,2055.12 R162.1 U27.17 | length 1520.1
  Top Layer w8: U27.17@6798.85,1165.95 6798.85,1144.36 v1(6829.49,1113.72)
  SIG_1 w6: v1(6829.49,1113.72) 6829.49,1150.36 6870.54,1191.4 6947.9,1191.4 7100.33,1343.83 7575.39,1343.83 7609.02,1377.45 7609.02,1909.97 v1(7600.26,1918.73)
SPI0_CLK: R286.1 U11.6 U32.A11 | length 2893.5
  Top Layer w9.9: v2(3052.82,3925.15) U32.A11@3068.57,3909.4
  PWR/SIG_2 w6: v1(2254.19,3389.99) 2324.6,3319.58 2370.03,3319.58 2467.34,3222.27 3400.34,3222.27 3574.11,3396.05 3649.46,3396.05 3665.4,3380.11 v2(3689.78,3380.11) 3689.78,3398.52 3614.45,3473.85 3080.94,3473.85 2970.89,3583.9 2970.89,3831.12 2991.93,3852.16 2991.93,3888.98 3028.1,3925.15 v2(3052.82,3925.15)
  Bottom Layer w8: U11.6@2201.3,3381.4 2245.61,3381.4 v1(2254.19,3389.99) ; R286.1@3689.55,3353.04 3689.93,3353.42 3689.93,3379.74 v2@3690.31,3380.11
SPI0_D0: R287.1 U32.C10 U52.20 | length 3916.8
  Top Layer w8: v1(5212.27,3979.52) 5212.27,4110.95 5229.53,4128.22 5257.82,4128.22 5345.49,4040.55 5402.63,4040.55 5429.25,4067.17 5429.25,4236.76 5365.78,4300.23 U52.20@5320.04,4300.23
  Top Layer w9.9: v2(3115.81,3893.66) U32.C10@3131.56,3877.91
  PWR/SIG_2 w6: v2(3115.81,3893.66) 3082.73,3860.57 3025.59,3860.57 2982.99,3817.97 2982.99,3589.16 3086.08,3486.07 3616.29,3486.07 3714.8,3387.55 3714.8,3372.97 3696.49,3354.66 3660.38,3354.66 v2(3634.92,3380.11)
  SIG_3 w6: v2(3634.92,3380.11) 3788.82,3534.01 3788.82,3556.69 4211.65,3979.52 v1(5212.27,3979.52)
  Bottom Layer w8: R287.1@3634.42,3353.04 3634.67,3353.3 3634.67,3379.35 v2@3634.92,3379.6
SPI5_CLK: J11.7 J16.2 R359.1 | length 3547.8
  Top Layer w8: J11.7@411.42,5818.77 v1(449.81,5818.77) ; v1(3065.57,4197.27) R359.1@3088.8,4197.27
  SIG_3 w4.5: v1(449.81,5818.77) 450.69,5818.77 482.57,5786.89 482.57,5613.1 820.96,5274.71 1849.04,5274.71 J16.2@2268.87,4854.88 2313.51,4810.23 2313.51,4644.66 2539.31,4418.86 2595.23,4418.86 2816.82,4197.27 v1(3065.57,4197.27)
SPI5_SDI: J11.3 J16.3 R360.1 | length 3635.6
  Top Layer w8: J11.3@411.42,5881.77 v1(449.81,5881.77) ; v1(3114.23,4224.15) R360.1@3189.23,4224.15
  SIG_3 w4.5: v1(449.81,5881.77) 501.8,5829.77 501.8,5800.35 1019.01,5283.14 1970.03,5283.14 2261.7,4991.47 2261.7,4962.05 2335.65,4888.1 2335.65,4654.8 2551.44,4439.01 2616.28,4439.01 2831.15,4224.15 v1(3114.23,4224.15)
SPI6_CS3_6: J20.16 U32.D11 | length 3341.6
  Top Layer w9.9: v2(3147.31,3925.15) U32.D11@3163.06,3909.4
  Top Layer w10: v1(2361.03,1399.74) J20.16@2361.03,1508.37
  Bottom Layer w5: 3121.51,3870.77 3131.34,3880.61 3131.34,3909.18 v2(3147.31,3925.15)
  Bottom Layer w8: v1(2361.03,1399.74) 2393.47,1432.17 2470.56,1432.17 2547.29,1355.44 2582.15,1355.44 2607.97,1381.26 2607.97,1803.41 2919.82,2115.26 2919.82,2742.41 2813.16,2849.07 2813.16,3651.56 3032.37,3870.77 3039.05,3870.77 3121.51,3870.77
SPI7_CS2: J17.9 R262.1 U51.16 | length 2787.5
  Top Layer w8: v1(4437.71,4386.07) U51.16@4482.15,4386.07
  SIG_1 w6: J17.9@2946.96,3037.36 3112.49,3202.89 3112.49,3340.09 3240.21,3467.81 3429.36,3467.81 v1(3458.29,3438.87) 3458.29,3397.94 3603.88,3252.35 3916.64,3252.35 4146.11,3481.82 4195.23,3481.82 4249.08,3535.67 4249.08,4086.36 4437.71,4274.98 v1(4437.71,4386.07)
  Bottom Layer w8: v1(3458.29,3438.87) R262.1@3458.29,3462.01
SPI7_CS5: J17.3 R158.2 U27.56 U32.P2 | length 5264
  Top Layer w8: v1(6710.53,1530.08) R158.2@6740.83,1530.08 6740.83,1507.68 6759.48,1489.02 U27.56@6759.48,1473.04
  Top Layer w9.9: U32.P2@3478.02,3625.94 v2(3493.77,3610.19)
  SIG_3 w6: v2(3493.77,3610.19) 3477.31,3593.73 3477.31,3564.38 3420.46,3507.54 3202.97,3507.54 3183.19,3487.76 3183.19,3442.73 3183.19,3414.04 3133.84,3364.68 3080.29,3364.68 3058.18,3342.57 3058.18,3226.14 3111.26,3173.06 J17.3@3246.96,3037.36 3298.83,2985.49 3298.83,2868.55 3495.41,2671.96 3727.43,2671.96 4098.22,2301.17 4352.14,2301.17 5023.18,1630.13 6321.85,1630.13 6421.89,1530.08 v1(6710.53,1530.08)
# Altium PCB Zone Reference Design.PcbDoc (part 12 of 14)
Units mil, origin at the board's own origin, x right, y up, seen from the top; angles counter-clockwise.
Board outline 8858.11 x 7047.08 mil, 16 copper layers (Top Layer, GND_1, SIG_1, GND_2, PWR/SIG_1, GND_3, PWR_1, PWR_2, GND_4, PWR/SIG_2, GND_5, SIG_2, GND_6, SIG_3, GND_7, Bottom Layer), stack 80.368 mil thick; 1131 components, 808 nets, 3825 pads, 3523 vias.
Unrouted connection lines stored in the file: 563.

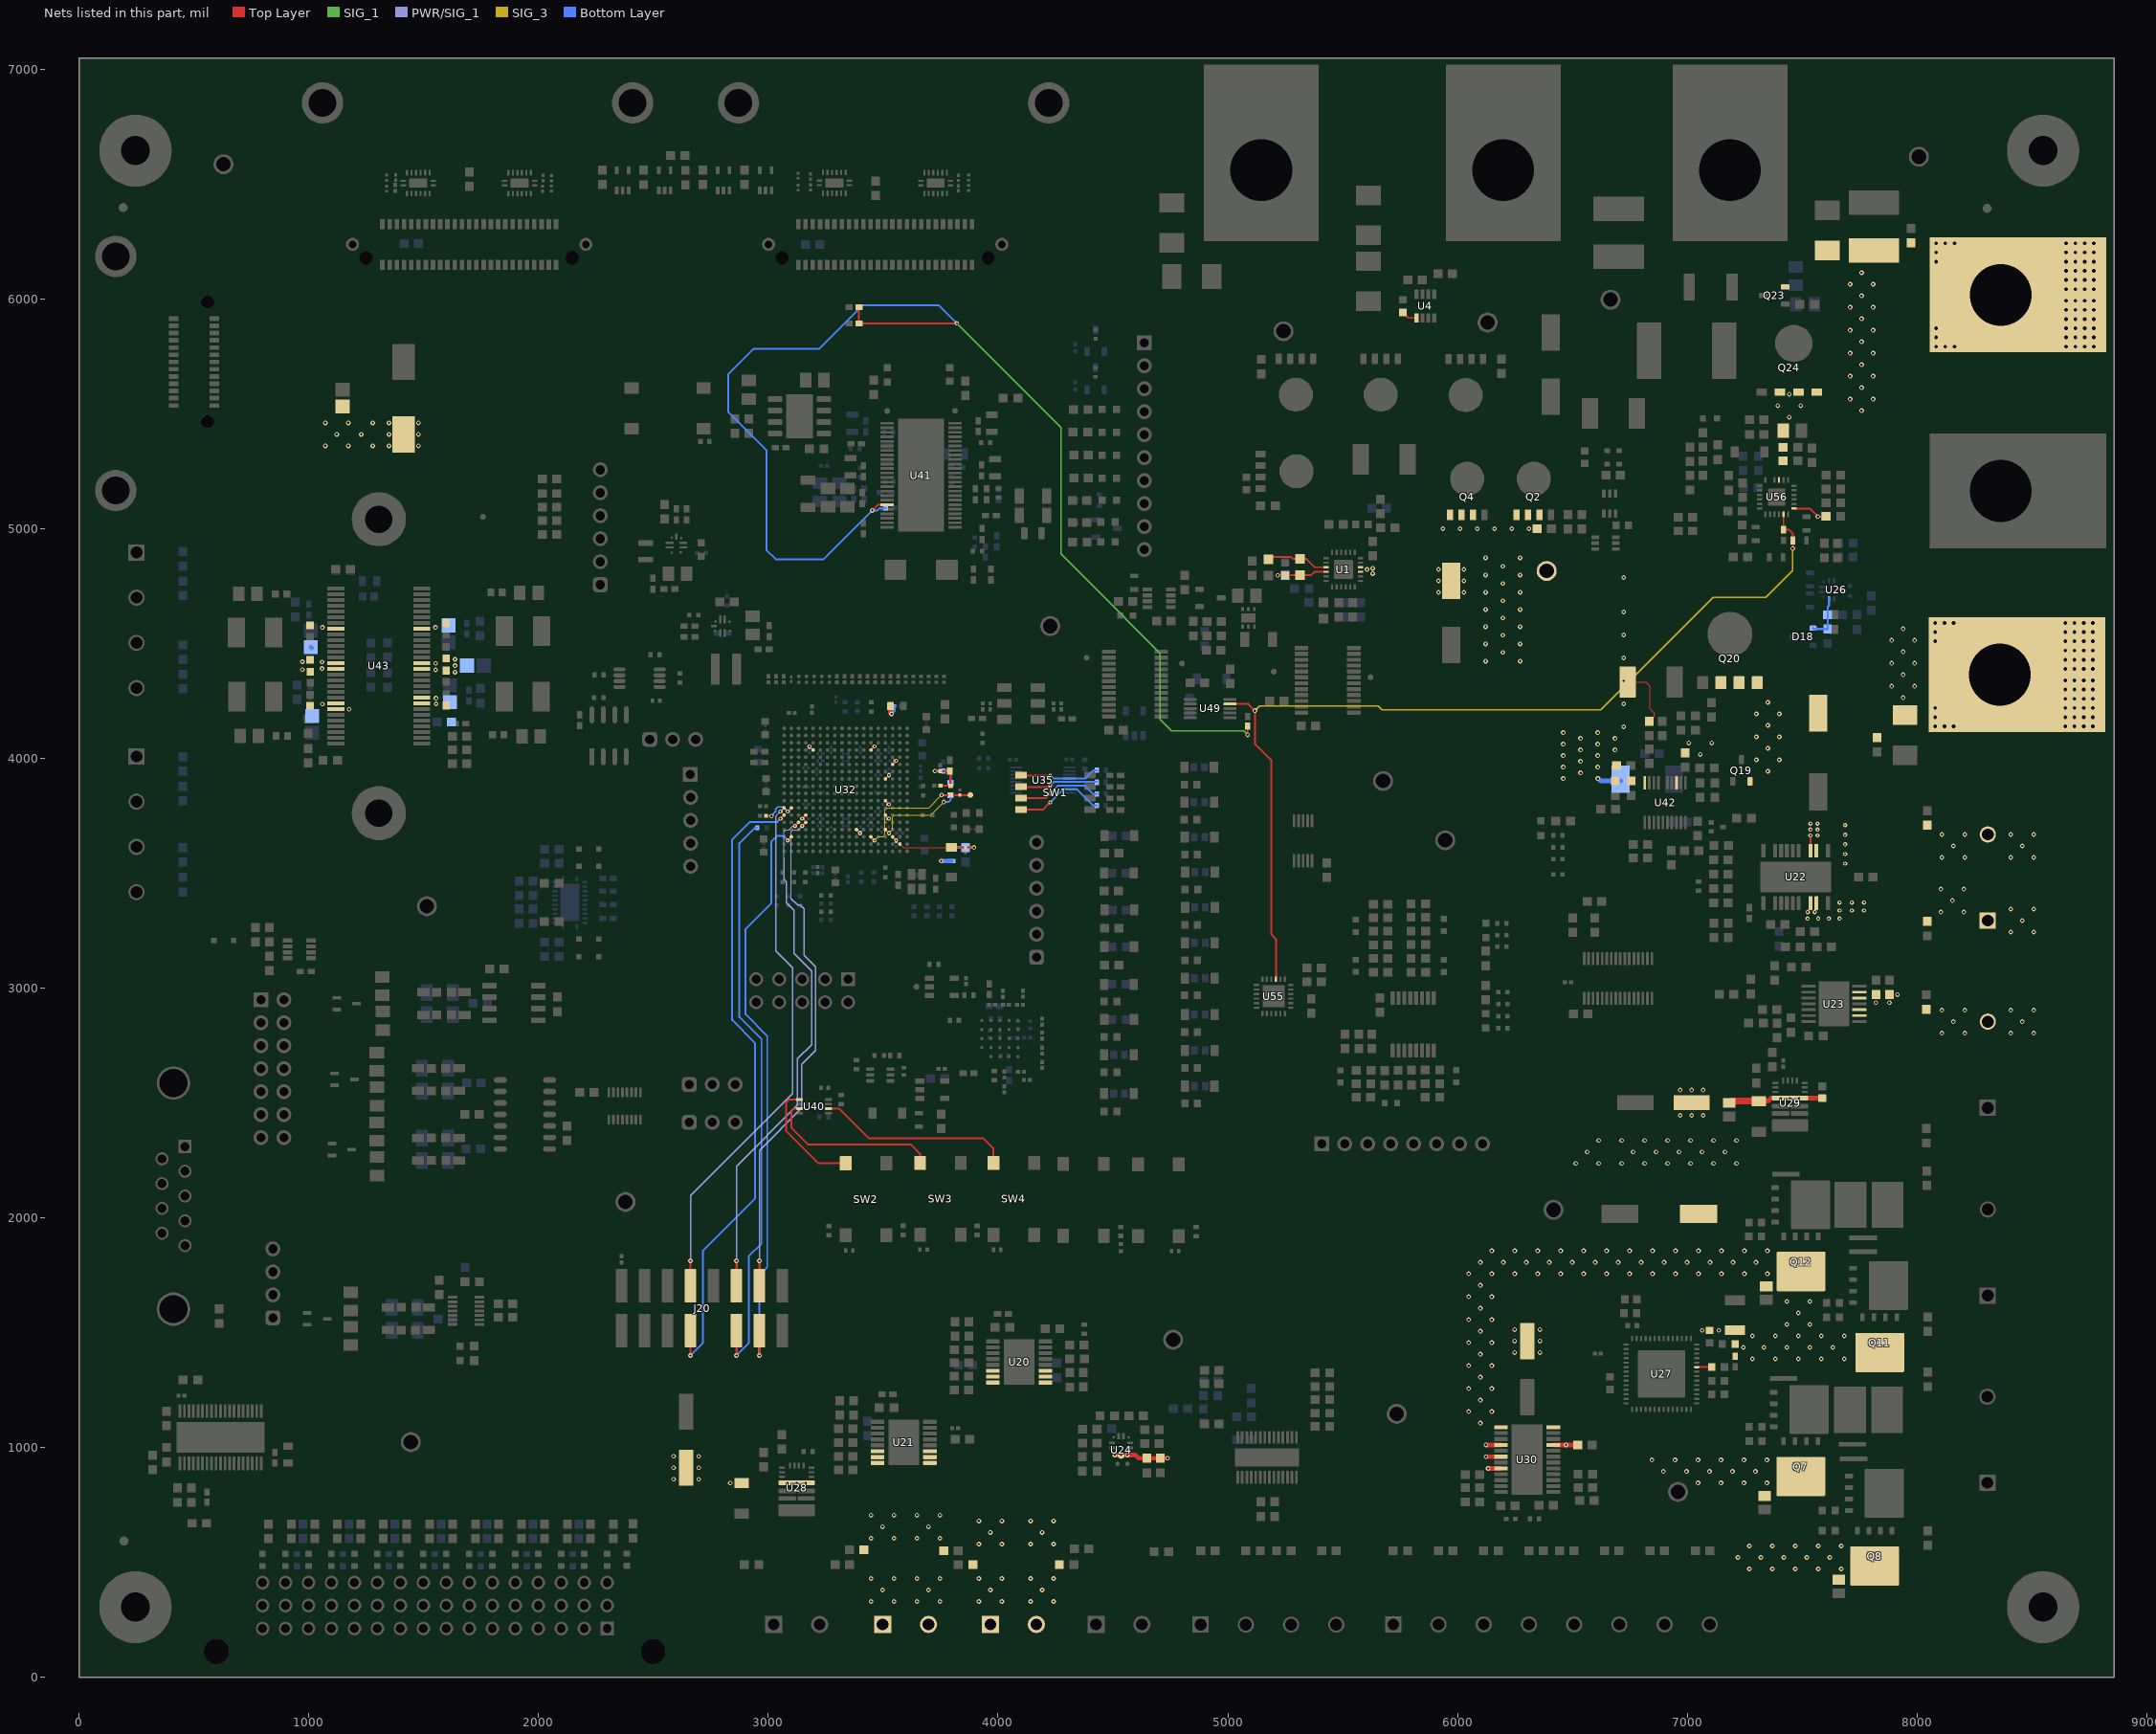
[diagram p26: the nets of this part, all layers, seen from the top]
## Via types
v1: diameter 20, hole 10, Top Layer to Bottom Layer, tented both sides, 2450 vias
v2: diameter 18, hole 8, Top Layer to Bottom Layer, tented both sides, 400 vias
v3: diameter 32, hole 16, Top Layer to Bottom Layer, tented both sides, 348 vias
v4: diameter 19.68, hole 7.87, Top Layer to Bottom Layer, tented both sides, 245 vias
v5: diameter 16, hole 8, Top Layer to Bottom Layer, tented both sides, 60 vias
v6: diameter 16, hole 8, Top Layer to Bottom Layer, 14 vias
v7: diameter 24.8, hole 12.99, Top Layer to Bottom Layer, tented both sides, 6 vias

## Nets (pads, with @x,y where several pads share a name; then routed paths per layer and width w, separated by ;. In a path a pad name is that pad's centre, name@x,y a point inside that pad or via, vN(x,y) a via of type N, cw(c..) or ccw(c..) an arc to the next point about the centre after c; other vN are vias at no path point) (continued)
SRC: C393.1 C394.1 C397.1 C398.1 C399.1 D56.1 Q23.2 Q24.2 Q24.3 Q24.4 T1.1 U56.15
  other v1: 7443.59,5484.05 7758.9,5512.6 7393.59,5534.05 7493.59,5534.05 7708.9,5562.6 7808.9,5562.6 7443.59,5584.05 7758.9,5612.6 7708.9,5662.6 7808.9,5662.6 7758.9,5712.6 7708.9,5762.6 7808.9,5762.6 7758.9,5812.6 7708.9,5862.6 7808.9,5862.6 7758.9,5912.6 7708.9,5962.6 7808.9,5962.6 7758.9,6012.6 7708.9,6062.6 7808.9,6062.6 7758.9,6112.6
  other v3: 8082.98,5791.12 8122.98,5791.12 8162.98,5791.12 8649.25,5791.12 8689.25,5791.12 8729.25,5791.12 8769.25,5791.12 8082.98,5831.12 8649.25,5831.12 8689.25,5831.12 8729.25,5831.12 8769.25,5831.12 8082.98,5871.12 8649.25,5871.12 8689.25,5871.12 8729.25,5871.12 8769.25,5871.12 8649.25,5911.12 8689.25,5911.12 8729.25,5911.12 8769.25,5911.12 8649.25,5951.12 8689.25,5951.12 8729.25,5951.12 8769.25,5951.12 8649.25,5991.12 8689.25,5991.12 8729.25,5991.12 8769.25,5991.12 8649.25,6041.12 8689.25,6041.12 8729.25,6041.12 8769.25,6041.12 8649.25,6081.12 8689.25,6081.12 8729.25,6081.12 8769.25,6081.12 8649.25,6121.12 8689.25,6121.12 8729.25,6121.12 8769.25,6121.12 8082.98,6161.12 8649.25,6161.12 8689.25,6161.12 8729.25,6161.12 8769.25,6161.12 8082.98,6201.12 8649.25,6201.12 8689.25,6201.12 8729.25,6201.12 8769.25,6201.12 8082.98,6241.12 8122.98,6241.12 8162.98,6241.12 8649.25,6241.12 8689.25,6241.12 8729.25,6241.12 8769.25,6241.12
SW_4: R22.1 R24.1 U1.3 | length 275.4
  Top Layer w8: R24.1@5176.42,4865.02 5187.66,4876.25 5274.14,4876.25 5283.44,4866.94 R22.1@5314.53,4866.94 5341.68,4866.94 5377.9,4830.72 U1.3@5428.31,4830.72
SW_PB_INTn_12: SW3.2 U40.3 | length 756.6
  Top Layer w8: U40.3@3135.33,2474.47 3113.16,2474.47 3101.11,2462.42 3101.11,2390.8 3173.1,2318.81 3619.19,2318.81 3660.19,2277.82 SW3.2@3660.19,2237.92
SW_PB_PORz_12: SW2.2 U40.1 | length 504.6
  Top Layer w8: U40.1@3135.33,2513.84 3089.78,2513.84 3077.78,2501.84 3077.78,2375.83 3216.97,2236.64 SW2.2@3336.17,2236.64
SW_PB_RESETz_12: SW4.2 U40.6 | length 853.2
  Top Layer w8: U40.6@3261.32,2474.47 3307.79,2474.47 3436.8,2345.45 3934.13,2345.45 3980.02,2299.56 SW4.2@3980.02,2237.49
SW_SOP0_9: R291.2 SW1.1 U35.4 | length 351.2
  Top Layer w8: SW1.1@4099.35,3925.48 4101.65,3923.19 v2(4227.08,3923.19)
  Bottom Layer w8: v2(4227.08,3923.19) 4229.79,3923.19 4241.02,3911.95 U35.4@4311.55,3911.95 4380.6,3911.95 4416.02,3947.38 R291.2@4430.32,3947.38
SW_SOP1_9: R290.2 SW1.2 U35.5 | length 336.5
  Top Layer w8: SW1.2@4099.35,3875.48 4100.09,3874.74 v2@4226.14,3874.74
  Bottom Layer w8: v2(4227.08,3881.39) v2(4227.08,3881.39) 4241.96,3896.21 U35.5@4311.55,3896.21 R290.2@4430.32,3896.21
SW_SOP2_9: R289.2 SW1.3 U35.6 | length 368.8
  Top Layer w8: SW1.3@4099.35,3825.48 4206.57,3825.48 v2(4227.08,3846)
  Bottom Layer w8: v2(4227.08,3846) 4261.54,3880.46 U35.6@4311.55,3880.46 4376.09,3880.46 4411.19,3845.35 4429.1,3845.35 R289.2@4430.32,3844.14
SW_SOP3_9: R288.2 SW1.4 U35.7 | length 391.3
  Top Layer w8: SW1.4@4099.35,3775.48 4195.16,3775.48 v2@4222.83,3803.15
  Bottom Layer w8: v2(4227.08,3807.4) 4284.39,3864.71 U35.7@4311.55,3864.71 4342.51,3864.71 4413.16,3794.06 4430.09,3794.06 R288.2@4430.32,3793.83
TCLK_6: J20.4 U32.B3 | length 2557.2
  Top Layer w9.9: v2(3084.32,3641.69) U32.B3@3100.07,3657.44
  Top Layer w10: v1(2961.03,1399.74) J20.4@2961.03,1508.37
  Bottom Layer w8: v1(2961.03,1399.74) 2961.03,1749.93 2994.98,1783.88 2994.98,2790.71 2900.44,2885.25 2900.44,3256.52 3013.61,3369.69 3013.61,3637.64 3036.88,3660.91 3065.09,3660.91 v2(3084.32,3641.69)
TDI_6: J20.5 U32.C5 | length 2242.8
  Top Layer w9.9: v2(3115.81,3704.68) U32.C5@3131.56,3720.43
  Top Layer w10: J20.5@2861.03,1703.25 v1(2861.03,1811.89)
  PWR/SIG_1 w4.5: 3068.14,3565.14 3068.14,3680.03 3075.88,3687.76 3087.81,3687.76 3104.72,3704.68 v2(3115.81,3704.68)
  PWR/SIG_1 w6: v1(2861.03,1811.89) 2861.03,2223.36 3126.79,2489.11 3126.79,2690.98 3188.95,2753.15 3188.95,3073.49 3112.67,3149.77 3112.67,3338.5 3079.41,3371.76 3079.41,3461.03 3068.14,3472.3 3068.14,3565.14
TDO_6: J20.6 R240.1 | length 2529.8
  Top Layer w10: v1(2861.03,1399.74) J20.6@2861.03,1508.37
  Bottom Layer w8: v1(2861.03,1399.74) 2914.42,1453.13 2914.42,1830.85 2970.17,1886.6 2970.17,2776.75 2873.95,2872.97 2873.95,3629.79 2940.88,3696.72 R240.1@2952.33,3696.72
TMR_19: C404.1 R472.2 U56.7 | length 189.7
  Top Layer w8: U56.7@7464.15,5086.86 7532.95,5086.86 v1(7568.1,5051.74) ; v1@7569.91,5051.74 C404.1@7604.61,5051.74
  Bottom Layer w8: v1(7568.1,5051.74) R472.2@7604.61,5051.74
TMS_6: J20.3 U32.D5 | length 2208.8
  Top Layer w9.9: v2(3147.31,3704.68) U32.D5@3163.06,3720.43
  Top Layer w10: J20.3@2961.03,1703.25 v1(2961.03,1811.89)
  PWR/SIG_1 w4.5: 3100.16,3387.71 3100.16,3681.16 3106.82,3687.82 3130.45,3687.82 v2(3147.31,3704.68)
  PWR/SIG_1 w6: v1(2961.03,1811.89) 2961.03,2292.57 3145.9,2477.44 3145.9,2666.93 3205.93,2726.96 3205.93,3092.13 3155.45,3142.61 3155.45,3343.46 3139.38,3359.53 3128.34,3359.53 3100.16,3387.71
TPS1HC04_IC_GND: C90.2 D18.1 R143.2 U26.4 | length 203.7
  Bottom Layer w10: D18.1@7547.33,4565.87 7551.61,4561.59 R143.2@7610.39,4561.59 7611.24,4562.43 C90.2@7611.24,4623.97 7611.24,4659.64 7616.96,4665.36 U26.4@7616.96,4697.77
UART0_CTS: R364.2 U32.B7 | length 147.2
  Top Layer w8: R364.2@2990.14,3748.25 v1(3013.47,3748.25)
  Top Layer w9.9: v2(3084.32,3767.67) U32.B7@3100.07,3783.42
  Bottom Layer w8: v1(3013.47,3748.25) 3031.2,3765.98 3031.2,3776.75 3041.86,3787.41 3064.58,3787.41 v2(3084.32,3767.67)
UART0_RX_6: J20.9 U32.A7 | length 2309.1
  Top Layer w9.9: v2(3052.82,3767.67) U32.A7@3068.57,3783.42
  Top Layer w10: J20.9@2661.03,1703.25 v1(2661.03,1811.89)
  PWR/SIG_1 w4.5: 3032.45,3747.3 v2(3052.82,3767.67)
  PWR/SIG_1 w6: v1(2661.03,1811.89) 2661.03,2095.65 3104.99,2539.61 3104.99,3087.99 3032.45,3160.52 3032.45,3747.3
UART0_TX_6: J20.10 U32.A6 | length 2782
  Top Layer w9.9: v2(3052.82,3736.18) U32.A6@3068.57,3751.92
  Top Layer w10: v1(2661.03,1399.74) J20.10@2661.03,1508.37
  Bottom Layer w8: v1(2661.03,1399.74) 2714.71,1453.41 2714.71,1854.76 2941.53,2081.58 2941.53,2760.6 2842.11,2860.03 2842.11,3645.05 2918.14,3721.08 3037.73,3721.08 3039.05,3722.4 v2(3052.82,3736.18)
UVLO_4: C8.2 R21.2 R22.2 U1.4 | length 250.4
  Top Layer w8: v1(5217.2,4795.54) C8.2@5249.7,4795.54 ; C8.2@5249.21,4795.05 C8.2@5249.7,4795.54 ; U1.4@5428.31,4811.03 5376.74,4811.03 5361.74,4796.03 R22.2@5314.53,4796.03 5250.2,4796.03 C8.2@5249.7,4795.54
  Bottom Layer w8: v1(5217.2,4795.54) 5248.71,4795.54 R21.2@5249.21,4795.05
VCAP_4: C16.1 U4.5 | length 69.1
  Top Layer w8: C16.1@5762.23,5939.96 5786.13,5916.05 U4.5@5821.47,5916.05
VCP_17: C101.2 U27.37 | length 65.5
  Top Layer w8: U27.37@7040.98,1349.02 7106.44,1349.02 C101.2@7106.5,1349.08
VDDA18_LDO: C213.1 C214.1 C215.1 C216.1 C217.1 C247.2 C248.2 FB2.1 R210.2 R310.1 U32.R6 U32.R8 U32.R11 U32.T13 | length 377.8
  Top Layer w8: v1(3725.44,3943.38) C248.2@3748.32,3943.38 3748.42,3943.28 C247.2@3789.9,3943.28 3791.71,3941.46 3791.71,3881.4 R210.2@3793.53,3879.58 ; R310.1@3748.47,3879.71 3748.53,3879.65 R210.2@3793.53,3879.58 ; R210.2@3793.53,3879.58 R210.2@3793.53,3879.58
  Top Layer w9.9: U32.R6@3509.51,3751.92 v2(3525.26,3736.18) ; U32.R8@3509.51,3814.92 v2(3525.26,3799.17) ; U32.R11@3509.51,3909.4 v2(3525.26,3925.15) ; U32.T13@3541.01,3972.4 v2(3556.76,3988.14)
  Bottom Layer w10: v1(3725.44,3943.38) 3760.63,3943.38 C213.1@3761.22,3943.97 3782.12,3943.97 3793.06,3933.04 FB2.1@3793.06,3891.42
VDDA18_OSC_PLL_AM26x_7: C218.1 FB2.2 U32.R4 | length 403.4
  Top Layer w9.9: U32.R4@3509.51,3688.93 v2(3525.26,3673.18)
  SIG_3 w4.5: v2(3525.26,3673.18) 3541.15,3689.07 3541.15,3745.68 3547.71,3752.24 3707.23,3752.24 v1(3763.87,3808.88)
  Bottom Layer w8: v1(3763.87,3808.88) 3783.75,3808.88 3793.06,3818.18 FB2.2@3793.06,3838.27
VDDS18_LDO: C200.1 C201.1 C202.1 C203.1 C204.1 C205.1 U32.D6 U32.E15 U32.L4 U32.N15 U32.T3 | length 187.6
  Top Layer w9.9: v2(3147.31,3736.18) U32.D6@3163.06,3751.92 ; v2(3178.81,4051.14) U32.E15@3194.55,4035.39 ; U32.L4@3383.53,3688.93 v2(3399.28,3673.18) ; U32.N15@3446.52,4035.39 v2(3462.27,4051.14) ; U32.T3@3541.01,3657.44 v2(3556.76,3641.69)
  Top Layer w20: C200.1@3531.41,4226.86 3531.41,4196.97 v1(3536.04,4192.35)
  Bottom Layer w10: v1(3536.04,4192.35) 3548.74,4205.05 C201.1@3548.74,4226.86
VOUT1_TPS2HCS05: C70.1 J1.1 U22.7 U22.8 | length 86.3
  Top Layer w8: v2(7524.42,3329.68) 7526.33,3331.6 7526.33,3338.19 7535.99,3347.85 U22.7@7535.99,3368.52 ; v2@7554.67,3328.76 7554.67,3331.46 7556.85,3333.64 7556.85,3363.78 U22.8@7561.58,3368.52
  other v1: 8407.98,3242.92 8507.98,3242.92 8457.98,3292.92 8104.32,3329.84 8204.32,3329.84 8407.98,3342.92 8507.98,3342.92 8154.32,3379.84 8104.32,3429.84 8204.32,3429.84
  other v2: 7523.16,3301.95 7569.73,3301.95 7616.31,3301.95 7662.88,3301.95 7554.67,3329.68 7662.88,3336.58 7715.98,3336.58 7769.07,3336.58 7662.88,3371.21 7715.98,3371.21 7769.07,3371.21
VOUT1_TPS2HCS08: C65.1 J5.1 U21.6 U21.7 U21.8
  other v1: 3447.31,329.26 3547.31,329.26 3497.31,379.26 3447.31,429.26 3547.31,429.26 3447.31,604.26 3547.31,604.26 3497.31,654.26 3447.31,704.26 3547.31,704.26
VOUT1_TPS2HCS10: C59.1 J3.1 U20.6 U20.7 U20.8
  other v1: 3916.47,329.26 4016.47,329.26 3966.47,379.26 3916.47,429.26 4016.47,429.26 3916.47,579.26 4016.47,579.26 3966.47,629.26 3916.47,679.26 4016.47,679.26
VOUT2_TPS2HCS05: C72.1 J1.2 U22.11 U22.12 | length 67.5
  Top Layer w8: U22.12@7535.99,3596.86 v2@7535.97,3664.3
  other v1: 8107.98,3567.72 8207.98,3567.72 8407.98,3567.72 8507.98,3567.72 8157.98,3617.72 8457.98,3617.72 8107.98,3667.72 8207.98,3667.72 8407.98,3667.72 8507.98,3667.72
  other v2: 7687.18,3540.68 7687.18,3582.57 7687.18,3624.47 7535.96,3663.64 7566.61,3663.64 7687.18,3666.36 7535.96,3689.18 7566.61,3689.18 7687.18,3708.26 7535.96,3714.73 7566.61,3714.73
VOUT2_TPS2HCS08: C68.1 J5.2 U21.9 U21.10 U21.11
  other v1: 3647.31,329.26 3747.31,329.26 3697.31,379.26 3647.31,429.26 3747.31,429.26 3647.31,604.26 3747.31,604.26 3697.31,654.26 3647.31,704.26 3747.31,704.26
VOUT2_TPS2HCS10: C62.1 J3.2 U20.9 U20.10 U20.11
  other v1: 4141.47,329.26 4241.47,329.26 4191.47,379.26 4141.47,429.26 4241.47,429.26 4141.47,579.26 4241.47,579.26 4191.47,629.26 4141.47,679.26 4241.47,679.26
VOUT_TPS1HC30_13: C82.1 J4.2 U23.9 U23.10
  other v1: 8107.98,2802.83 8207.98,2802.83 8407.98,2802.83 8507.98,2802.83 8157.98,2852.83 8457.98,2852.83 8107.98,2902.83 8207.98,2902.83 8407.98,2902.83 8507.98,2902.83
VOUT_TPS1211: C305.1 C306.1 C308.1 D53.1 Q19.2 Q20.2 Q20.3 Q20.4 T2.1 U42.13
  other v1: 7350.53,3942.53 7300.53,3992.53 7400.53,3992.53 7056.37,4015.85 7350.53,4042.53 7006.37,4065.85 7106.37,4065.85 7300.53,4092.53 7400.53,4092.53 7350.53,4142.53 7300.53,4192.53 7400.53,4192.53 7350.53,4242.53 7939.22,4262.79 7889.22,4312.79 7989.22,4312.79 7939.22,4362.79 7889.22,4412.79 7989.22,4412.79 7939.22,4462.79 7889.22,4512.79 7989.22,4512.79 7939.22,4562.79
  other v3: 8078.94,4138.44 8118.94,4138.44 8158.94,4138.44 8645.21,4138.44 8685.21,4138.44 8725.21,4138.44 8765.21,4138.44 8078.94,4178.44 8645.21,4178.44 8685.21,4178.44 8725.21,4178.44 8765.21,4178.44 8078.94,4218.44 8645.21,4218.44 8685.21,4218.44 8725.21,4218.44 8765.21,4218.44 8645.21,4258.44 8685.21,4258.44 8725.21,4258.44 8765.21,4258.44 8645.21,4298.44 8685.21,4298.44 8725.21,4298.44 8765.21,4298.44 8645.21,4338.44 8685.21,4338.44 8725.21,4338.44 8765.21,4338.44 8645.21,4388.44 8685.21,4388.44 8725.21,4388.44 8765.21,4388.44 8645.21,4428.44 8685.21,4428.44 8725.21,4428.44 8765.21,4428.44 8645.21,4468.44 8685.21,4468.44 8725.21,4468.44 8765.21,4468.44 8078.94,4508.44 8645.21,4508.44 8685.21,4508.44 8725.21,4508.44 8765.21,4508.44 8078.94,4548.44 8645.21,4548.44 8685.21,4548.44 8725.21,4548.44 8765.21,4548.44 8078.94,4588.44 8118.94,4588.44 8158.94,4588.44 8645.21,4588.44 8685.21,4588.44 8725.21,4588.44 8765.21,4588.44
VPP_1V8_7: C185.1 R210.1 TP5.1 U32.N3 | length 580.7
  Top Layer w8: v1(3754.18,3839.23) R210.1@3793.53,3839.23 3873.83,3839.23 TP5.1@3874.32,3839.72
  Top Layer w9.9: U32.N3@3446.52,3657.44 v2(3462.27,3641.69)
  SIG_3 w4.5: v2(3462.27,3641.69) 3478.71,3658.13 3500.55,3658.13 3508.41,3665.99 3508.41,3775.93 3516.56,3784.08 3699.03,3784.08 v1(3754.18,3839.23)
VS: C3.1 C4.1 C77.1 C78.1 C79.1 C80.1 C96.1 C97.1 C98.1 C99.1 C100.1 C108.1 C109.1 C112.1 C113.1 C114.1 C116.1 C117.2 C122.1 C123.1 C307.2 C310.1 C311.1 C312.1 C313.1 C314.1 C315.2 C316.2 C317.2 C318.2 C319.2 C320.2 C321.2 C322.2 C325.1 C326.1 C335.2 Q2.1 Q2.2 Q2.3 Q4.1 Q4.2 Q4.3 Q7.5 Q7.6 Q7.7 Q7.8 Q7.9@7493.89,873.59 Q8.5 Q8.6 Q8.7 Q8.8 Q8.9@7815.59,483.47 Q11.5 Q11.6 Q11.7 Q11.8 Q11.9@7837.5,1413.1 Q12.5 Q12.6 Q12.7 Q12.8 Q12.9@7495.26,1765.18 R150.1 R153.1 R212.2 R370.1 R371.2 R374.2 R383.1 R474.1 TP2.1 U1.15 U1.16 U23.12 U23.13 U24.2 U28.4 U29.4 U30.9 U30.12 U30.13 U30.16 U30.18 U30.20 U42.20 U43.8 U43.9 U43.14 U43.15 U43.21 U43.36 U43.42 U43.43 U43.49 U43.50 | length 1370.2
  Top Layer w5: R370.1@6740.36,4331.17 6819.54,4331.17 6838.57,4312.14 6838.57,4214.08 6856.68,4195.96 6856.68,4183.54 R371.2@6833.77,4160.63
  Top Layer w20: v4(4507.77,965.73) 4507.96,965.93 4598.11,965.93 4611.49,952.55 4640.88,952.55 4700.33,952.55 4700.39,952.61 v1(4738.54,952.61) ; v1(6122.96,959.51) U30.18@6188.4,959.51 ; v1(6122.96,1010.69) U30.16@6188.4,1010.69 ; v1(6132.96,908.33) U30.20@6188.4,908.33 ; U30.9@6416.74,1010.69 v1(6472.18,1010.69) 6521.98,1010.69 C123.1@6522.65,1010.02 ; C116.1@7311.72,2507.13 7351.74,2507.13 7365.1,2520.48 v4(7407.92,2520.48) v4(7447.29,2520.48) 7586.08,2520.48 C117.2@7586.55,2520.01
  Top Layer w30: C109.1@7182.1,2499.25 7189.97,2507.13 C116.1@7311.72,2507.13
  Bottom Layer w8: v1(6610.1,3911.03) v1@6613.34,3911.03
  Bottom Layer w20: C326.1@1008.52,4483.38 C326.1@1012.43,4479.46 ; v1(3752.2,3552.46) R212.2@3796.11,3552.46 ; v1@6613.34,3911.03 6623.92,3900.45 R474.1@6709.48,3900.45
  other v1: 7270.27,470.74 7370.27,470.74 7470.27,470.74 7570.27,470.74 7670.27,470.74 7220.27,520.74 7320.27,520.74 7420.27,520.74 7520.27,520.74 7620.27,520.74 7270.27,570.74 7370.27,570.74 7470.27,570.74 7570.27,570.74 7670.27,570.74 2833.95,844.84 7046.41,845.08 7146.41,845.08 7246.41,845.08 7346.41,845.08 2587.7,861.17 2697.7,861.17 6896.41,895.08 6996.41,895.08 7096.41,895.08 7196.41,895.08 7296.41,895.08 2587.7,911.17 2697.7,911.17 6846.41,945.08 6946.41,945.08 7046.41,945.08 7146.41,945.08 7246.41,945.08 7346.41,945.08 2587.7,961.17 2697.7,961.17 6098.75,1105.53 6048.75,1155.53 6148.75,1155.53 6098.75,1205.53 6048.75,1255.53 6148.75,1255.53 6098.75,1305.53 6048.75,1355.53 6148.75,1355.53 7283.51,1385.16 7383.51,1385.16 7483.51,1385.16 7583.51,1385.16 7683.51,1385.16 6098.75,1405.53 6248.27,1412.36 6358.27,1412.36 7243.51,1435.16 7333.51,1435.16 7433.51,1435.16 7533.51,1435.16 7633.51,1435.16 6048.75,1455.53 6148.75,1455.53 6248.27,1462.36 6358.27,1462.36 7283.51,1485.16 7383.51,1485.16 7483.51,1485.16 7583.51,1485.16 7683.51,1485.16 6098.75,1505.53 7065.12,1509.23 7137.85,1509.24 6248.27,1512.36 6358.27,1512.36 7433.51,1535.16 7533.51,1535.16 6048.75,1555.53 6148.75,1555.53 7483.51,1585.16 6098.75,1605.53 7433.51,1635.16 7533.51,1635.16 6048.75,1655.53 6148.75,1655.53 6098.75,1705.53 6048.75,1755.53 6148.75,1755.53 6248.75,1755.53 6348.75,1755.53 6448.75,1755.53 6548.75,1755.53 6648.75,1755.53 6748.75,1755.53 6848.75,1755.53 6948.75,1755.53 7048.75,1755.53 7148.75,1755.53 7248.75,1755.53 7348.75,1755.53 6098.75,1805.53 6198.75,1805.53 6298.75,1805.53 6398.75,1805.53 6498.75,1805.53 6598.75,1805.53 6698.75,1805.53 6798.75,1805.53 6898.75,1805.53 6998.75,1805.53 7098.75,1805.53 7198.75,1805.53 7298.75,1805.53 6148.75,1855.53 6248.75,1855.53 6348.75,1855.53 6448.75,1855.53 6548.75,1855.53 6648.75,1855.53 6748.75,1855.53 6848.75,1855.53 6948.75,1855.53 7048.75,1855.53 7148.75,1855.53 7248.75,1855.53 7348.75,1855.53 6514.12,2235.73 6614.12,2235.73 6714.12,2235.73 6814.12,2235.73 6914.12,2235.73 7014.12,2235.73 7114.12,2235.73 7214.12,2235.73 6564.12,2285.73 6764.12,2285.73 6864.12,2285.73 6964.12,2285.73 7064.12,2285.73 7164.12,2285.73 6614.12,2335.73 6714.12,2335.73 6814.12,2335.73 6914.12,2335.73 7014.12,2335.73 7114.12,2335.73 7214.12,2335.73 6968.79,2445.29 7018.79,2445.29 7068.79,2445.29 6968.79,2555.29 7018.79,2555.29 7068.79,2555.29 7820.98,2935.45 7879.73,2935.45 7914.73,2970.45 6460.1,3911.03 6535.1,3936.03 6460.1,3961.03 6610.1,3961.03 6535.1,3986.03 6460.1,4011.03 6610.1,4011.03 6535.1,4036.03 6685.1,4036.03 6460.1,4061.03 6610.1,4061.03 6535.1,4086.03 6685.1,4086.03 6460.1,4111.03 6610.1,4111.03 6723.37,4136.21 1174.83,4211.95 1058.9,4235.63 1553.65,4236.3 6723.37,4236.21 1553.43,4261.02 6723.37,4336.21 1636.34,4374.09 1551.58,4383.97 971.47,4385.56 1057.32,4390.15 1636.34,4402.27 1551.58,4412.05 1057.32,4418.23 971.47,4419.58 6122.15,4422.05 6272.15,4422.05 1635.97,4430.09 6723.37,4436.21 6197.15,4460.05 6122.15,4497.05 6272.15,4497.05 6197.15,4535.05 6723.37,4536.21 1058.69,4569.21 1551.1,4569.25 6122.15,4572.05 6272.15,4572.05 6197.15,4610.05 6723.37,4636.21 6122.15,4647.05 6272.15,4647.05 6197.15,4685.05 5917.29,4721.64 6027.29,4721.64 6122.15,4722.05 6272.15,4722.05 6197.15,4760.05 5917.29,4771.64 6027.29,4771.64 6723.37,4786.21 6122.15,4797.05 6272.15,4797.05 5630.74,4803 5605.74,4821 5917.29,4821.64 6027.29,4821.64 5630.74,4826 6197.15,4835.05 6122.15,4872.05 6272.15,4872.05 5936.04,4998.39 6011.04,4998.39 6086.04,4998.39 6161.04,4998.39 6236.04,4998.39 6311.04,4998.39 1071.32,5359.2 1171.32,5359.2 1277.8,5359.26 1348.8,5359.24 1476.8,5359.24 1121.32,5409.2 1227.8,5409.26 1348.8,5409.24 1476.8,5409.24 1071.32,5459.2 1171.32,5459.2 1277.8,5459.26 1348.8,5459.24 1476.8,5459.24
  other v4: 3084.06,845.45 3123.43,845.45 3162.8,845.45 4535.32,965.73 4562.88,965.73 7486.66,2520.48
VSYS_MON_AM26x_7: C219.1 D20.1 R212.1 R213.2 U32.U2 | length 428
  Top Layer w5: U32.U2@3572.51,3625.94 3588.29,3610.15 3795.68,3610.15 D20.1@3796.57,3611.05
  Top Layer w8: D20.1@3796.57,3611.05 C219.1@3858.02,3611.05 v1(3894.76,3611.05)
  Bottom Layer w8: R212.1@3796.11,3611.52 3857.55,3611.52 R213.2@3858.02,3611.05 v1(3894.76,3611.05)
WAKE: C400.1 R469.1 U49.9 U55.3 U56.5 | length 4210.2
  Top Layer w8: U49.9@5009.43,4235.58 5089.1,4235.58 v1(5117.86,4206.82) 5117.86,4062.58 5188.4,3992.05 5188.4,3232.8 5209.27,3211.93 U55.3@5209.27,3037.92 ; U56.5@7418.88,5061.27 7418.88,4994.67 C400.1@7418.7,4994.49 7442.5,4994.49 7459.13,4977.85 R469.1@7459.13,4946.6 v1(7459.13,4912.01)
  SIG_3 w6: v1(5117.86,4206.82) 5137.3,4226.26 5655.61,4226.26 5671.72,4210.14 6623.75,4210.14 7112.84,4699.24 7342.54,4699.24 7459.13,4815.84 v1(7459.13,4912.01)
WAKE2_1: D40.1 D41.1 D55.1 R336.1 U41.43 | length 5721.6
  Top Layer w8: D40.1@3394.26,5962.5 3394.26,5893.22 D41.1@3395.34,5892.14 ; D41.1@3395.34,5892.77 v2(3820.1,5892.77) ; v1(3452.32,5078.1) 3477.35,5103.13 U41.43@3516.97,5103.13 ; v1(5085.98,4101.47) D55.1@5085.98,4138.65
  SIG_1 w6: v2(3820.1,5892.77) 4273.3,5439.56 4273.3,4888.3 4404.24,4757.36 4704.76,4456.84 4704.76,4168.91 4755.7,4117.98 5069.48,4117.98 v1(5085.98,4101.47)
  Bottom Layer w8: R336.1@3510.76,5088.86 3485.87,5088.86 3475.11,5078.1 v1(3452.32,5078.1) 3239.99,4865.76 3031.9,4865.76 2991.65,4906.01 2991.65,5340.42 2824.76,5507.31 2824.76,5670.66 2936.02,5781.93 3222.28,5781.93 3411.66,5971.31 3741.56,5971.31 v2(3820.1,5892.77)
pads on no net: D18.2 FID1.1 FID2.1 FID3.1 H1.1 H2.1 H3.1 H4.1 H5.0 H6.0 H7.0 H8.0 H9.C J11. J12.MH3 J12.MH4 J13.MH3 J13.MH4 J16.5 J23.3 J23.4 J24.1 J24.4 J24.8 J29.MH1 J29.MH2 LBL1.0 Q7.9@7400.48,948.78 Q7.9@7441.53,846.62 Q7.9@7441.53,891.89 Q7.9@7441.53,937.17 Q7.9@7493.89,846.62 Q7.9@7493.89,886.58 Q7.9@7493.89,891.89 Q7.9@7493.89,937.17 Q7.9@7546.25,846.62 Q7.9@7546.25,891.89 Q7.9@7546.25,937.17 Q7.9@7587.3,948.78 Q8.9@7722.19,558.67 Q8.9@7763.23,456.5 Q8.9@7763.23,501.78 Q8.9@7763.23,547.05 Q8.9@7815.59,456.5 Q8.9@7815.59,496.46 Q8.9@7815.59,501.78 Q8.9@7815.59,547.05 Q8.9@7867.96,456.5 Q8.9@7867.96,501.78 Q8.9@7867.96,547.05 Q8.9@7909,558.67 Q9.9@7454,1071.27 Q9.9@7454,1258.08 Q9.9@7465.62,1112.32 Q9.9@7465.62,1164.68 Q9.9@7465.62,1217.04 Q9.9@7510.89,1112.32 Q9.9@7510.89,1164.68 Q9.9@7510.89,1217.04 Q9.9@7516.21,1164.68 Q9.9@7556.17,1112.32 Q9.9@7556.17,1164.68 Q9.9@7556.17,1217.04 Q10.9@7782.43,706.7 Q10.9@7782.43,893.52 Q10.9@7794.05,747.75 Q10.9@7794.05,800.11 Q10.9@7794.05,852.47 Q10.9@7839.32,747.75 Q10.9@7839.32,800.11 Q10.9@7839.32,852.47 Q10.9@7844.64,800.11 Q10.9@7884.6,747.75 Q10.9@7884.6,800.11 Q10.9@7884.6,852.47 Q11.9@7744.09,1488.29 Q11.9@7785.13,1386.13 Q11.9@7785.13,1431.4 Q11.9@7785.13,1476.68 Q11.9@7837.5,1386.13 Q11.9@7837.5,1426.09 Q11.9@7837.5,1431.4 Q11.9@7837.5,1476.68 Q11.9@7889.86,1386.13 Q11.9@7889.86,1431.4 Q11.9@7889.86,1476.68 Q11.9@7930.9,1488.29 Q12.9@7401.85,1840.38 Q12.9@7442.9,1738.21 Q12.9@7442.9,1783.49 Q12.9@7442.9,1828.76 Q12.9@7495.26,1738.21 Q12.9@7495.26,1778.17 Q12.9@7495.26,1783.49 Q12.9@7495.26,1828.76 Q12.9@7547.62,1738.21 Q12.9@7547.62,1783.49 Q12.9@7547.62,1828.76 Q12.9@7588.66,1840.38 Q13.9@7800.68,1611.14 Q13.9@7800.68,1797.95 Q13.9@7812.29,1652.18 Q13.9@7812.29,1704.54 Q13.9@7812.29,1756.9 Q13.9@7857.57,1652.18 Q13.9@7857.57,1704.54 Q13.9@7857.57,1756.9 Q13.9@7862.88,1704.54 Q13.9@7902.84,1652.18 Q13.9@7902.84,1704.54 Q13.9@7902.84,1756.9 Q14.9@7460.4,1961.72 Q14.9@7460.4,2148.53 Q14.9@7472.02,2002.76 Q14.9@7472.02,2055.12 Q14.9@7472.02,2107.48 Q14.9@7517.29,2002.76 Q14.9@7517.29,2055.12 Q14.9@7517.29,2107.48 Q14.9@7522.61,2055.12 Q14.9@7562.57,2002.76 Q14.9@7562.57,2055.12 Q14.9@7562.57,2107.48 T7.7@5072.1,4610.64 T7.7@5107.53,4610.64 U1.8 U1.17 U1.21 U1.25 U3.4 U5.11 U11.13 U11.18 U11.23 U11.24 U14.1 U15.1 U17.1 U18.1 U23.8 U23.11 U23.14 U25.1 U25.14 U25.19 U25.24 U26.5 U26.8 U27.19 U27.20 U27.21 U27.29 U27.30 U27.31 U27.40 U27.41 U27.42 U27.43 U27.51 U27.52 U27.53 U32.F15 U32.T15 U32.U3 U32.U16 U32.V2 U33.A2 U33.A3 U33.B1 U33.B5 U33.C5 U43.51 U48.7 U51.1 U52.1 U53.1
copper on no net:
  other v2: 3556.76,4051.14 3588.25,4082.63
  other v4: 5503.11,4789.38 5471.62,4820.88 5503.11,4820.88 5534.61,4820.88 5503.11,4852.37

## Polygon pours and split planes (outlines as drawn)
GND on PWR/SIG_1 "PWR/SIG_1_GND_P123" (solid, pour order 123): 0,7047.08 8858.11,7047.08 8858.11,0 0,0
3V3_2 on PWR/SIG_1 "PWR/SIG_1_3V3_2_P119" (solid, pour order 119): 2213.98,1843.86 2213.98,2509.48 2266.7,2562.2 2266.7,2722.22 1979.62,3009.31 1979.62,4079.21 2094.57,4194.16 2123.35,4222.93 4028.39,4222.93 4584.96,4779.51 4584.96,5141.51 4601.7,5158.25 4651.92,5158.25 4676.43,5182.76 4676.43,5231.78 4647.74,5260.48 4472.8,5260.48 4112.11,5621.17 4112.11,6435.24 3895.02,6652.32 1020.21,6652.32 444.94,6077.05 444.94,5305.29 1091.94,4658.29 1091.94,3481.06 1091.94,1705.31 1940.7,856.55 2325.86,471.39 7145.8,471.39 7390.82,716.41 7390.82,1832.26 7390.82,2734.91 7329.15,2796.58 7275.8,2796.58 7129.01,2649.79 7129.01,2005.73 6780.55,1657.28 6780.55,1457.62 6453.86,1130.94 5344.32,1130.94 3707.71,1130.94 3148.72,1689.92 2367.92,1689.92
OUT_1M_J1_25 on PWR/SIG_1 "PWR/SIG_1_OUT_1M_J1_25_P028" (solid, pour order 28): 1216.39,4575.27 1224.66,4566.99 1224.66,4532.53 1217.87,4525.74 1124.07,4525.74 976.32,4673.49 807.67,4673.49 797.85,4683.31 797.85,4747.65 805.64,4755.44 805.98,4755.1 984.45,4755.1 1164.29,4575.27
OUT_4M_J1_25 on PWR/SIG_1 "PWR/SIG_1_OUT_4M_J1_25_P014" (solid, pour order 14): 1374.29,4295.12 1387.9,4308.72 1443.38,4308.72 1455.93,4296.18 1455.93,4223.9 1493.08,4186.74 1781.99,4186.74 1826.56,4142.18 1914.52,4142.18 1931.84,4124.86 1931.84,4077.69 1911.13,4056.97 1792.12,4056.97 1735.96,4113.14 1455.64,4113.14 1373.82,4194.96 1373.82,4295.82
CS-_4 on PWR/SIG_1 "PWR/SIG_1_CS-_4_P034" (solid, pour order 34): 6677.26,5442.59 6700.56,5419.29 6700.56,4960.18 6822.29,4838.44 7363.98,4838.44 7383.99,4818.43 7383.99,4172.43 7075.62,3864.06 5700.65,3864.06 5656.65,3908.06 5656.65,5364.54 5734.7,5442.59
OUT_3P1_25 on PWR/SIG_1 "PWR/SIG_1_OUT_3P1_25_P012" (solid, pour order 12): 1383.96,4439.1 1392.71,4447.85 1465.44,4447.85 1636.25,4618.66 1805.25,4618.66 1813.31,4610.6 1813.31,4490.72 1801.25,4478.66 1599.93,4478.66 1521.13,4399.87 1391.47,4399.87 1383.96,4407.38
OUT_2P1_25 on PWR/SIG_1 "PWR/SIG_1_OUT_2P1_25_P021" (solid, pour order 21): 1216.37,4399.4 1102.18,4399.4 1030.65,4327.88 894.71,4327.88 885.02,4318.19 885.02,4207.9 890.67,4202.24 987.81,4202.24 1131.9,4346.33 1213.11,4346.33 1223.27,4356.49 1223.27,4392.51
NetC6_2 on PWR/SIG_1 "PWR/SIG_1_NETC6_2_P096" (solid, pour order 96): 5642.11,4908.88 4705.81,4908.88 4692.12,4922.57 4692.12,6274.25 4718.37,6300.5 6489.97,6300.5 6532.69,6257.78 6532.69,5850.56 6696.14,5687.1 6696.14,5486.51 6664.95,5455.32 5744.39,5455.32 5659.1,5370.03 5659.1,4925.86
12V_ALWAYS_ON on PWR/SIG_1 "PWR/SIG_1_12V_ALWAYS_ON_P121" (solid, pour order 121): 6547.37,5851.76 6547.37,6267.93 6469.7,6345.6 6469.7,6984.23 6497.49,7012.01 6882.5,7012.01 6904.81,6989.71 6904.81,6319.33 6934.49,6289.65 7441.15,6289.65 7472.06,6320.57 7472.06,6964.44 7521.8,7014.18 8797.45,7014.18 8828.37,6983.26 8828.37,6323.26 8792.08,6286.96 8058.14,6286.96 8029.91,6258.73 8029.91,5457.58 7803.99,5231.66 7310.66,5231.66 7234.09,5155.09 7234.09,4931.27 7157.68,4854.86 6820.78,4854.86 6720.06,4955.59 6720.06,5679.08
GND on GND_1 "GND_1_GND_P031" (solid, pour order 31): 0,7047.08 8858.11,7047.08 8858.11,0 0,0
SHIELD_GND on GND_1 "GND_1_SHIELD_GND_P030" (solid, pour order 30): 1.01,2681.26 1.01,1508.17 29.03,1480.15 489.7,1480.15 580.49,1570.94 630.61,1570.94 638.42,1578.75 638.42,1694.88 545.14,1788.15 545.14,2643.9 481.47,2707.57 27.32,2707.57
GND on PWR/SIG_2 "PWR/SIG_2_GND_P122" (solid, pour order 122): 0,7047.08 8858.11,7047.08 8858.11,0 0,0
3V3_1 on PWR/SIG_2 "PWR/SIG_2_3V3_1_P120" (solid, pour order 120): 1868.64,2693.29 1246.44,2693.29 847.48,3092.25 847.48,3257.18 907.29,3316.98 1183.72,3593.41 1465.15,3593.41 1719.01,3593.41 2096.84,3961.42 2094.42,4445.65 2317.16,4685.34 2648.86,4690.18 2762.65,4803.97 2774.87,4903.13 3273.09,5401.35 4027.51,5401.35 4075.4,5449.24 4075.4,5741.8 4274.76,5941.16 4834.56,5941.16 5623.31,5152.41 7514.04,5152.41 7738.17,4928.29 7738.17,4647.01 7707.73,4616.57 7258.28,4167.12 7258.28,3431.93 7258.28,3012.63 6718.96,2473.3 5444.71,2473.3 4649.28,1677.87 4649.28,935.25 4529.65,815.62 4211.38,815.62 3445.14,1581.86 2232.64,1581.86 1945.12,1294.34 1722.16,1294.34 1590.8,1425.71 1590.8,1765.79 1836.84,2011.83 2007.36,2011.83 2180.75,2185.23 2180.75,2381.17
3V3_ALWAYS_ON on PWR/SIG_2 "PWR/SIG_2_3V3_ALWAYS_ON_P118" (solid, pour order 118): 5255.45,2258.61 5255.45,2967.46 5390.66,3102.66 5461.79,3102.66 5472.8,3091.65 5472.8,2984.47 5427.28,2938.95 5427.28,2490.48 5457.31,2460.46 6733.81,2460.46 7273.25,2999.9 7273.25,3627.51 7134.46,3766.31 6359.85,3766.31 6276.52,3849.64 5241.48,3849.64 5023.11,4068 4680.88,4068 4655.23,4042.35 4447.56,4042.35 4414.39,4075.52 4414.39,4423.53 4618.7,4627.84 4618.7,4809.14 4588.49,4839.35 4313.67,4839.35 4258.99,4894.03 4258.99,4945.83 4286.33,4973.16 4902.15,4973.16 5340.99,4534.32 6399.72,4534.32 6605.01,4329.03 7440.24,4329.03 7749.02,4637.81 7749.02,4858.82 7723.47,4884.37 7568.93,4884.37 6897.13,4884.37 6617.99,5163.51 5634.78,5163.51 4852.33,5945.95 1271.97,5945.95 1081.71,6136.22 1081.71,6293.58 1171.07,6382.95 4812.4,6382.95 4880.17,6315.18 7740.49,6315.18 8034.79,6020.88 8034.79,4042.35 8085.51,3991.63 8085.51,2814.67 6922.73,1651.89 6022.3,1651.89 5729.55,1359.14 5729.55,444.34 5588.02,302.81 2493.54,302.81 2318.29,478.07 540.72,478.07 328,690.79 328,1293.9 567.77,1533.67 567.77,1825.08 960.67,2217.98 1794.38,2217.98 1816.44,2195.92 1816.44,2006.88 1584.9,1775.33 1584.9,1431.61 1722.16,1294.34 1950.05,1294.34 2238.46,1582.76 4167.98,1582.76 4347.12,1403.62 4347.12,1189.95 4347.12,864.33 4406.71,804.75 4547.56,804.75 4665.06,922.25 4665.06,1668.21
GND on PWR/SIG_2 "PWR/SIG_2_GND_P106" (solid, pour order 106): 3481.53,3764.05 3450.06,3795.51 3450.06,3897.31 3544.52,3991.77 3544.52,4020.32 3529.95,4034.9 3493.77,4034.9 3460.38,4001.52 3199.89,4001.52 3191.04,3992.67 3191.04,3761.19 3203.47,3748.76 3317.95,3748.76 3349.79,3716.91 3472.13,3716.91 3481.53,3726.31
OUT_4P1_25 on PWR/SIG_2 "PWR/SIG_2_OUT_4P1_25_P037" (solid, pour order 37): 1386.86,4390.28 1394.09,4397.52 1449.37,4397.52 1464.97,4381.92 1767.91,4381.92 1822.43,4327.4 1822.43,4201.69 1812.51,4191.77 1811.27,4193.01 1766.23,4193.01 1626.47,4332.77 1402.73,4332.77 1386.19,4349.31 1386.19,4390.66
OUT_1P1_25 on PWR/SIG_2 "PWR/SIG_2_OUT_1P1_25_P051" (solid, pour order 51): 1219.88,4409.58 1219.88,4439.78 1220.09,4439.99 1220.09,4447.61 1215.24,4452.46 1143.22,4452.46 982.88,4612.81 891.65,4612.81 879.28,4600.44 879.28,4487.79 891.83,4475.24 1030.1,4475.24 1100.34,4405 1215.28,4405 1219.88,4409.59
OUT_3M_J1_25 on PWR/SIG_2 "PWR/SIG_2_OUT_3M_J1_25_P024" (solid, pour order 24): 1365.9,4566.76 1382.86,4583.72 1447.31,4583.72 1619.93,4756.34 1895.73,4756.34 1895.73,4690.26 1882.26,4676.79 1630.28,4676.79 1476.99,4523.51 1379.47,4523.51 1378.62,4522.66 1366.75,4534.54
OUT_2M_J1_25 on PWR/SIG_2 "PWR/SIG_2_OUT_2M_J1_25_P016" (solid, pour order 16): 1230.76,4277.23 1229.85,4276.32 1122.19,4276.32 1098.47,4252.6 982.14,4136.27 812.45,4136.27 806.52,4130.34 806.52,4061.92 813.36,4055.07 1001.46,4055.07 1029.13,4082.74 1173.78,4227.4 1229.15,4227.4 1239.17,4237.41 1239.17,4268.82
VDDA18_LDO on PWR/SIG_2 "PWR/SIG_2_VDDA18_LDO_P052" (solid, pour order 52): 3497.22,3736.18 3506.5,3726.9 3539.24,3726.9 3545.91,3733.56 3545.91,3833.62 3575.72,3863.43 3700.78,3863.43 3739.88,3902.53 3739.88,3945.94 3677.77,4008.04 3513.67,4008.04 3399.28,3893.66 3399.28,3780.96 3444.07,3736.18
VS on PWR_2 "PWR_2_VS_P049" (solid, pour order 49): 8858.11,4.22 8858.11,7047.08 0,7047.08 0,4.22
1V1 on PWR_2 "PWR_2_1V1_P013" (solid, pour order 13): 1836.54,6215.54 1857.27,6236.27 1910.83,6236.27 2008.66,6138.45 3075.72,6138.45 3104.68,6167.4 3547.8,6167.4 3632.53,6252.13 3707.1,6252.13 3752.6,6206.63 3752.6,5849.61 4545.38,5056.83 4647.86,5056.83 4681.92,5022.77 4681.92,4983.14 4622.59,4923.8 2868.16,4923.8 2676.97,4732.62 2467.45,4732.62 2431.46,4768.6 2431.46,5719.35 2217.72,5933.1 2060.98,5933.1 1836.54,6157.54
VDDS18_LDO on PWR_2 "PWR_2_VDDS18_LDO_P007" (solid, pour order 7): 3594.94,3705.12 3481.59,3705.12 3462.27,3724.09 3462.27,3925.15 3493.77,3956.65 3493.77,4082.63 3556.43,4145.29 3556.43,4198.6 3543.84,4211.19 3501.34,4211.19 3448.47,4158.32 3443.01,4152.86 3360.55,4070.4 3212.37,4070.4 3178.81,4070.4 3147.31,4038.9 3127.97,4019.56 3127.97,3723.36 3137.89,3713.45 3228.87,3622.47 3599.71,3622.47 3618.24,3641 3618.25,3681.81
3V3_VDDA_7 on PWR_2 "PWR_2_3V3_VDDA_7_P009" (solid, pour order 9): 3796.55,3775.64 3627.77,3944.41 3488.15,3944.41 3473.57,3929.83 3473.57,3737.11 3474.51,3736.18 3474.51,3726.53 3484.12,3716.91 3785.73,3716.91 3796.55,3727.73
NetC6_2 on PWR_2 "PWR_2_NETC6_2_P023" (solid, pour order 23): 5642.11,4908.88 5299.83,4908.88 5238.62,4970.09 5238.62,5065.45 5175.26,5128.8 5175.26,5717.47 5395.08,5937.29 6445.95,5937.29 6661.59,5721.65 6661.59,5428.83 6643.11,5410.35 5699.42,5410.35 5659.1,5370.03 5659.1,4925.86
GND on Bottom Layer "BOTTOM_LAYER_GND_P105" (solid, pour order 105): -65.94,7015.35 8792.18,7015.35 8792.18,-31.73 -65.93,-31.73
CS-_4 on Bottom Layer "BOTTOM_LAYER_CS-_4_P103" (solid, pour order 103): 5656.97,4178.15 5656.97,3974.11 5765.04,3866.05 7140.41,3866.05 7383.99,4109.63 7383.99,4818.43 7363.98,4838.44 6721.59,4838.44 6700.56,4859.48 6700.56,5418.85 6679.77,5439.64 5741.56,5439.64 5656.97,5355.05
BST_4P1_25 on Bottom Layer "BOTTOM_LAYER_BST_4P1_25_P092" (solid, pour order 92): 1322.58,4288.36 1367.91,4288.36 1401.41,4321.87 1440.95,4321.87 1445.71,4326.63 1445.71,4339.73 1441.05,4344.4 1374.04,4344.4 1358.48,4328.83 1322.58,4328.83
VS on Bottom Layer "BOTTOM_LAYER_VS_P086" (solid, pour order 86): 1638.35,4608.44 1568.14,4608.44 1535.5,4575.8 1535.5,4561.23 1549.11,4547.63 1638.35,4547.63
VS on Bottom Layer "BOTTOM_LAYER_VS_P087" (solid, pour order 87): 1719.16,4435.92 1706.27,4448.81 1564.8,4448.81 1530.47,4414.48 1530.47,4380.5 1552,4358.97 1705.86,4358.97 1719.16,4372.26
VS on Bottom Layer "BOTTOM_LAYER_VS_P004" (solid, pour order 4): 1535.47,4264.47 1545.06,4274.06 1644.9,4274.06 1649.94,4269.02 1649.94,4142.02 1640.89,4132.97 1603.09,4132.97 1590.84,4145.21 1590.84,4205.69 1576.25,4220.28 1545.59,4220.28 1534.94,4230.93 1534.94,4263.41
VS on Bottom Layer "BOTTOM_LAYER_VS_P042" (solid, pour order 42): 959.35,4406.01 959.35,4373.41 967.18,4365.58 1061.52,4365.58 1071.96,4376.02 1071.96,4487 1045,4513.96 972.08,4513.96 959.79,4501.66
VS on Bottom Layer "BOTTOM_LAYER_VS_P006" (solid, pour order 6): 983.39,4213.48 1016.17,4246.26 1067.93,4246.26 1080.55,4233.64 1080.55,4188.21 1044.66,4152.32 983.39,4152.32
BST_2P1_25 on Bottom Layer "BOTTOM_LAYER_BST_2P1_25_P093" (solid, pour order 93): 1288.95,4289.4 1233.45,4289.4 1198.15,4324.71 1171.02,4324.71 1164.98,4330.75 1164.98,4343.31 1169.61,4347.94 1220.03,4347.94 1239.2,4328.77 1288.95,4328.77
OUT_4P1_25 on Bottom Layer "BOTTOM_LAYER_OUT_4P1_25_P090" (solid, pour order 90): 1322.58,4393.33 1373.27,4393.33 1375.39,4395.45 1438.89,4395.45 1443.05,4391.29 1443.05,4353.82 1442.84,4353.82 1439.09,4350.07 1326.47,4350.07 1322.58,4353.96
BST_1P1_25 on Bottom Layer "BOTTOM_LAYER_BST_1P1_25_P102" (solid, pour order 102): 1288.14,4520.5 1250.2,4520.5 1206.94,4477.24 1167.41,4477.24 1163.75,4473.58 1163.75,4459.19 1166.77,4456.16 1235.77,4456.16 1256.85,4477.24 1288.14,4477.24
OUT_1P1_25 on Bottom Layer "BOTTOM_LAYER_OUT_1P1_25_P101" (solid, pour order 101): 1287.77,4415.82 1276.51,4404.57 1167.85,4404.57 1164.96,4407.46 1164.96,4444.93 1165.16,4444.93 1171.15,4450.92 1242.06,4451.03 1250.74,4457.51 1287.77,4457.51
OUT_2P1_25 on Bottom Layer "BOTTOM_LAYER_OUT_2P1_25_P094" (solid, pour order 94): 1288.95,4352 1169.3,4352 1164.88,4356.41 1164.88,4392.78 1171.15,4399.04 1230.63,4399.04 1236.89,4392.78 1288.95,4392.78
OUT_3P1_25 on Bottom Layer "BOTTOM_LAYER_OUT_3P1_25_P089" (solid, pour order 89): 1323.61,4459.13 1361.01,4459.13 1376.15,4447.11 1439.73,4447.11 1444.68,4442.15 1444.68,4409.3 1437.7,4402.32 1376.15,4402.32 1369.17,4409.3 1334.06,4409.3 1323.61,4419.76
BST_3P1_25 on Bottom Layer "BOTTOM_LAYER_BST_3P1_25_P088" (solid, pour order 88): 1322.39,4522.12 1363.16,4522.12 1408.9,4476.38 1442.29,4476.38 1445.39,4473.27 1445.39,4456.08 1442.85,4453.53 1386.63,4453.53 1360.24,4479.92 1322.39,4479.92
NetC6_2 on Bottom Layer "BOTTOM_LAYER_NETC6_2_P104" (solid, pour order 104): 5642.11,4908.88 4705.81,4908.88 4692.12,4922.57 4692.12,6282.62 4709.99,6300.5 6489.97,6300.5 6532.69,6257.78 6532.69,5850.56 6661.59,5721.65 6661.59,5466.3 6646.84,5451.55 5740.61,5451.54 5659.1,5370.03 5659.1,4925.86
GND on Top Layer "TOP_LAYER_GND_P099" (solid, remove dead copper, pour order 99): 0,7047.08 8858.11,7047.08 8858.11,0 0,0
VS on Top Layer "TOP_LAYER_VS_P085" (solid, pour order 85): 7242.87,1121.62 7253.21,1131.95 7309.7,1131.95 7342.32,1164.57 7342.32,1291.32 7379.13,1328.14 7537.01,1328.14 7562.56,1302.58 7934.91,1302.58 7960.47,1328.14 7960.47,1494.7 7936.67,1518.49 7707.54,1518.49 7630.87,1595.17 7630.87,1845.45 7568.91,1907.41 7277.37,1907.41 7263.85,1893.89 7242.69,1915.05 7242.69,2516.67 7123.11,2636.25 6968.77,2636.25 6899.29,2566.77 6899.29,2452.97 6818.21,2371.89 6421.68,2371.89 5761.34,1711.54 5761.34,1258.66 5940.82,1079.18 6215.4,1079.18 6215.98,1078.61 6217.92,1080.55 6245.62,1108.25 6359.52,1108.25 6387.22,1080.55 6389.16,1078.61 6690.13,1078.61 6823.53,945.21 6823.53,815.71 6951.32,687.92 7080.81,687.92 7098.96,669.77 7149.98,618.76 7149.98,511.35 7263.29,398.04 7919.39,398.04 7950.23,428.87 7950.23,560.69 7920.11,590.81 7676.69,590.81 7617.06,650.44 7617.06,963.32 7605.6,974.78 7276.51,974.78 7242.87,1008.41
GND on Top Layer "TOP_LAYER_GND_P066" (solid, pour order 66): 6797.14,1955.73 6782.19,1940.29 6624.08,1940.29 6611.47,1952.9 6611.3,2072.22 6611.3,2089.96 6619.44,2096.89 6782.4,2096.89 6795.67,2083.61 6795.79,2079.52
OUT_3P1_25 on Top Layer "TOP_LAYER_OUT_3P1_25_P017" (solid, pour order 17): 1893.8,4486.5 1886.65,4479.35 1799.07,4479.35 1781.89,4496.53 1781.89,4607.75 1799.75,4625.61 1883.96,4625.61 1893.8,4615.77
OUT_4P1_25 on Top Layer "TOP_LAYER_OUT_4P1_25_P011" (solid, pour order 11): 1898.16,4199.3 1891,4192.14 1803.43,4192.14 1786.25,4209.32 1786.25,4320.55 1804.1,4338.4 1888.32,4338.4 1898.16,4328.56
OUT_2P1_25 on Top Layer "TOP_LAYER_OUT_2P1_25_P061" (solid, pour order 61): 803.78,4332.38 810.93,4339.54 898.5,4339.54 915.69,4322.36 915.69,4211.13 897.83,4193.28 813.62,4193.28 803.78,4203.12
OUT_1P1_25 on Top Layer "TOP_LAYER_OUT_1P1_25_P065" (solid, pour order 65): 802.97,4612.26 810.12,4619.42 897.7,4619.42 914.88,4602.24 914.88,4491.01 897.02,4473.16 812.81,4473.16 802.97,4483
OUT_3P_J1_25 on Top Layer "TOP_LAYER_OUT_3P_J1_25_P047" (solid, pour order 47): 1974.83,4479.3 1963.93,4490.2 1963.93,4756.92 1973.47,4766.45 2049.32,4766.45 2057.61,4758.17 2057.61,4487.81 2049.09,4479.3
OUT_4P_J1_25 on Top Layer "TOP_LAYER_OUT_4P_J1_25_P057" (solid, pour order 57): 1974.99,4053.95 1964.09,4064.85 1964.09,4331.58 1973.63,4341.11 2049.48,4341.11 2060.2,4330.39 2060.2,4064.91 2049.25,4053.95
OUT_1P_J1_25 on Top Layer "TOP_LAYER_OUT_1P_J1_25_P063" (solid, pour order 63): 726.85,4480.42 726.85,4745.11 717.17,4754.79 655.42,4754.79 642.4,4741.77 642.4,4480.42 649.41,4473.41 649.75,4473.74 720.17,4473.74
OUT_2P_J1_25 on Top Layer "TOP_LAYER_OUT_2P_J1_25_P060" (solid, pour order 60): 721.55,4341.62 732.45,4330.72 732.45,4064 722.91,4054.46 647.06,4054.46 638.77,4062.75 638.77,4333.1 647.29,4341.62
OUT_3M_J1_25 on Top Layer "TOP_LAYER_OUT_3M_J1_25_P032" (solid, pour order 32): 1822.59,4692.48 1822.59,4747.46 1835.66,4760.53 1934.13,4760.53 1943.32,4751.35 1943.32,4688.35 1934.15,4679.18 1835.88,4679.18
OUT_1M_J1_25 on Top Layer "TOP_LAYER_OUT_1M_J1_25_P062" (solid, pour order 62): 870.01,4742.32 870.01,4687.33 856.93,4674.26 758.46,4674.26 749.27,4683.45 749.27,4746.45 758.44,4755.61 856.71,4755.61
OUT_2M_J1_25 on Top Layer "TOP_LAYER_OUT_2M_J1_25_P058" (solid, pour order 58): 872.64,4123.39 872.64,4068.41 859.57,4055.34 761.1,4055.34 751.91,4064.52 751.91,4127.52 761.08,4136.69 859.35,4136.69
OUT_4M_J1_25 on Top Layer "TOP_LAYER_OUT_4M_J1_25_P056" (solid, pour order 56): 1834.46,4071.68 1834.46,4126.66 1847.53,4139.74 1946.01,4139.74 1955.19,4130.55 1955.19,4063.51 1950.07,4058.39 1847.76,4058.39
VS on Top Layer "TOP_LAYER_VS_P005" (solid, pour order 5): 1454,4230.72 1542.97,4230.72 1561.67,4212.02 1613.66,4212.02 1613.67,4248.89 1584.04,4248.89 1561.48,4271.45 1454,4271.45
OUT_3P1_25 on Top Layer "TOP_LAYER_OUT_3P1_25_P074" (solid, pour order 74): 1528.99,4430.9 1451.93,4430.9 1441.23,4420.19 1441.23,4407.78 1436.09,4402.64 1396.04,4402.64 1390.7,4407.98 1390.7,4442.47 1397.25,4449.02 1451.81,4449.02 1454.19,4446.64 1528.99,4446.64
OUT_4P1_25 on Top Layer "TOP_LAYER_OUT_4P1_25_P124" (solid, pour order 124): 1528.99,4355.9 1454.19,4355.9 1449.3,4351.01 1395.92,4351.01 1390.56,4356.36 1390.56,4391.16 1395.9,4396.5 1436.64,4396.5 1446.21,4386.92 1446.21,4379.62 1454.19,4371.64 1528.99,4371.64
VS on Top Layer "TOP_LAYER_VS_P068" (solid, pour order 68): 1454.06,4571.47 1534.8,4571.47 1567.21,4603.88 1613.67,4603.88 1613.66,4568.13 1608.48,4562.6 1570,4562.6 1563.12,4555.72 1454.06,4555.72
VS on Top Layer "TOP_LAYER_VS_P072" (solid, pour order 72): 1454.04,4421.45 1536.19,4421.45 1570.45,4455.72 1632.31,4455.72 1650.39,4437.64 1650.39,4364.35 1642.5,4356.46 1558.05,4356.46 1533.81,4380.71 1454.04,4380.71
OUT_2P1_25 on Top Layer "TOP_LAYER_OUT_2P1_25_P100" (solid, pour order 100): 1080.04,4371.47 1157.1,4371.47 1167.8,4382.17 1167.8,4394.59 1172.95,4399.73 1212.99,4399.73 1218.33,4394.39 1218.33,4359.9 1211.78,4353.35 1157.22,4353.35 1154.85,4355.72 1080.04,4355.72
OUT_1P1_25 on Top Layer "TOP_LAYER_OUT_1P1_25_P079" (solid, pour order 79): 1080.04,4446.47 1154.85,4446.47 1160.63,4452.25 1212.23,4452.25 1218.47,4446.01 1218.47,4411.21 1212.49,4405.23 1173.04,4405.23 1166.09,4412.17 1166.09,4419.48 1154.85,4430.72 1080.04,4430.72
OUT_4M_J1_25 on Top Layer "TOP_LAYER_OUT_4M_J1_25_P070" (solid, pour order 70): 1528.86,4281.02 1454.63,4281.02 1428.16,4254.55 1389.82,4254.55 1384.08,4260.29 1384.08,4294.71 1390.83,4301.46 1447.39,4301.46 1452.06,4296.79 1528.86,4296.18
OUT_1M_J1_25 on Top Layer "TOP_LAYER_OUT_1M_J1_25_P077" (solid, pour order 77): 1080.04,4546.47 1154.27,4546.47 1180.73,4572.94 1219.08,4572.94 1224.81,4567.2 1224.81,4532.78 1218.06,4526.03 1161.51,4526.03 1156.84,4530.7 1080.04,4531.31
OUT_3M_J1_25 on Top Layer "TOP_LAYER_OUT_3M_J1_25_P069" (solid, pour order 69): 1529.12,4530.86 1427.63,4530.86 1423.15,4526.38 1377.12,4526.38 1370.51,4532.99 1370.51,4568.48 1374.17,4572.14 1421.26,4572.14 1446.64,4546.76 1529.12,4546.76
OUT_2M_J1_25 on Top Layer "TOP_LAYER_OUT_2M_J1_25_P067" (solid, pour order 67): 1079.74,4271.7 1181.24,4271.7 1185.71,4276.18 1231.75,4276.18 1238.36,4269.57 1238.36,4234.08 1234.7,4230.42 1187.61,4230.42 1162.23,4255.8 1079.74,4255.8
VS on Top Layer "TOP_LAYER_VS_P075" (solid, pour order 75): 1154.86,4380.74 1072.72,4380.74 1051.44,4359.47 973.42,4359.47 958.51,4374.38 958.51,4431.84 972.32,4445.64 1057.91,4445.64 1082.07,4421.49 1154.86,4421.49
VS on Top Layer "TOP_LAYER_VS_P076" (solid, pour order 76): 1154.9,4571.49 1079.85,4571.49 1057.17,4594.17 988.91,4594.17 988.91,4560.5 1039.46,4560.5 1044.21,4555.75 1154.9,4555.75
VS on Top Layer "TOP_LAYER_VS_P008" (solid, pour order 8): 1157.78,4246.49 1190.24,4214.03 1190.24,4199 1161.65,4199 1154.9,4205.74 991.9,4205.74 987.2,4210.44 987.2,4242.49 991.2,4246.49
VS on Top Layer "TOP_LAYER_VS_P081" (solid, pour order 81): 6783.04,4141.55 6799.41,4157.92 6799.41,4461.09 6831.48,4493.16 6831.48,4778.93 6746.71,4863.7 6489.88,4863.7 6382.07,4971.51 6382.07,5082.19 6377.18,5087.08 5953.2,5087.08 5897.26,5031.15 5838.3,5031.15 5655.38,4848.24 5577.28,4848.24 5564.22,4835.17 5564.22,4806.41 5569.2,4801.43 5614.45,4801.43 5656.56,4759.32 5656.56,4171.85 5668.34,4160.07 6348.95,4160.07 6419.68,4089.34 6419.68,3894.82 6445.23,3869.27 6643.31,3869.27 6777.58,3869.27 6787.31,3859.54 6819.22,3859.54 6824.5,3864.82 6824.5,3919.64 6783.04,3961.1
3V3_1 on Top Layer "TOP_LAYER_3V3_1_P097" (solid, pour order 97): 6483.14,3357.48 6520.99,3395.33 6589.1,3395.33 6603.23,3381.19 6603.23,3336.2 6618.65,3320.78 6618.65,3275.39 6612.23,3268.96 6490.14,3268.96 6483.14,3275.96
GND on Top Layer "TOP_LAYER_GND_P098" (solid, pour order 98): 7357.95,3320.19 7357.95,3389.34 7376.43,3407.82 7393.55,3407.82 7393.55,3338.22 7375.75,3320.42 7357.95,3320.42 7356.58,3321.79
GND on Top Layer "TOP_LAYER_GND_P084" (solid, pour order 84): 7011.61,1189.45 7019.45,1197.28 7016.78,1443.59 7005.55,1454.82 6767.97,1454.82 6754.85,1441.7 6752.11,1437.61 6752.11,1200.03 6762.69,1189.45
SHIELD_GND on Top Layer "TOP_LAYER_SHIELD_GND_P080" (solid, pour order 80): 1.01,2681.26 1.01,1508.17 29.03,1480.15 489.7,1480.15 580.49,1570.94 630.61,1570.94 638.42,1578.75 638.42,1694.88 545.14,1788.15 545.14,2643.9 481.47,2707.57 27.32,2707.57
12V_VBATT_2 on Top Layer "TOP_LAYER_12V_VBATT_2_P082" (solid, pour order 82): 5830.33,5934.77 5832.28,5936.72 5861.85,5936.72 5863.8,5934.77 5863.8,5896.52 5871.88,5888.44 5912.79,5888.44 5942.32,5917.97 5942.32,7013.81 5951.79,7023.28 6444.04,7023.28 6453.88,7013.44 6453.88,6027.3 6323.99,5897.42 6323.99,5812.73 6278.74,5767.48 6161.86,5767.48 6150.14,5755.76 6150.14,5723.57 6137.66,5711.09 5585.67,5711.09 5532.57,5764.19 5532.57,6047.51 5552.32,6067.26 5689.88,6067.26 5732.1,6025.04 5732.1,5916.44 5760.09,5888.45 5822.26,5888.45 5830.33,5896.52
12V_VBATT_1 on Top Layer "TOP_LAYER_12V_VBATT_1_P083" (solid, pour order 83): 5413.91,6346.26 5413.91,5730.5 5390.42,5707.01 5252.6,5707.01 5188.44,5771.18 5121.29,5771.18 5116.32,5766.2 5116.32,5602.96 5168.63,5550.65 5168.63,5200.6 5161.14,5193.11 5067.79,5193.11 5053.26,5178.58 5053.26,5120.81 5106.61,5067.45 5198.19,5067.45 5410.32,4855.33 5438.15,4855.33 5438.15,4845.48 5385.29,4845.48 5328.58,4902.19 5020.77,4902.19 4859.26,5063.7 4859.26,6985.29 4892.97,7019.01 5395.76,7019.01 5413.91,7000.86
12V_ALWAYS_ON on PWR_1 "PWR_1_12V_ALWAYS_ON_P003" (solid, pour order 3): 8858.11,4.22 8858.11,7047.08 0,7047.08 0,4.22
1V2 on PWR_1 "PWR_1_1V2_P000" (solid, pour order 0): 2954.93,3514.03 3298.83,3514.03 3339.33,3554.53 3339.33,3663.48 3362.29,3686.44 3663.22,3686.44 3785.87,3809.08 3785.87,4158.56 3731.69,4212.74 3408.86,4212.74 3264.89,4356.71 2991.21,4356.71 2985.24,4362.68 2985.24,4535.87 2956.49,4564.62 2865.47,4564.62 2853.53,4552.67 2853.53,3615.43
CS-_4 on PWR_1 "PWR_1_CS-_4_P001" (solid, pour order 1): 6657.96,5456.15 6700.56,5413.55 6700.56,4859.48 6721.59,4838.44 7363.98,4838.44 7383.99,4818.43 7383.99,3907.38 7348.32,3871.71 5684.83,3871.71 5657.35,3899.19 5657.35,5420.48 5693.01,5456.15
GND on SIG_1 "SIG_1_GND_P115" (solid, remove dead copper, pour order 115): 0,7047.08 8858.11,7047.08 8858.11,0 0,0
12V_VBATT_1 on SIG_1 "SIG_1_12V_VBATT_1_P114" (solid, pour order 114): 5521.21,5676.59 5613.3,5584.5 7544.69,5584.5 7859.81,5269.38 7859.81,4698.82 7832.68,4671.68 7671.07,4671.68 7138.2,5204.55 6297.19,5204.55 5998.7,4906.06 4901.55,4906.06 4857.97,4949.64 4857.97,6999 4878.48,7019.51 5428.37,7019.51 5521.21,6926.66
12V_VBATT_2 on SIG_1 "SIG_1_12V_VBATT_2_P113" (solid, pour order 113): 6444.04,7023.28 6883.61,7023.28 6921.6,6985.29 6921.6,5647.8 6862.99,5589.2 5619.88,5589.2 5532.57,5676.51 5532.57,6104.88 5591.46,6163.77 5852.53,6163.77 5942.32,6253.56 5942.32,6465.89 5942.32,7013.81 5951.79,7023.28
OUT_1M_J1_25 on SIG_1 "SIG_1_OUT_1M_J1_25_P055" (solid, pour order 55): 841.42,4755.23 796.14,4755.23 762.42,4721.52 762.42,4634.74 711.48,4583.8 711.48,3576.96 583.83,3449.31 479.25,3449.31 470.54,3440.6 470.54,3384.57 486.1,3369.01 626.79,3369.01 808.94,3551.17 808.94,4581.83 840.83,4613.72
OUT_1P_J1_25 on SIG_1 "SIG_1_OUT_1P_J1_25_P033" (solid, pour order 33): 643.42,4747.65 555.8,4660.03 555.8,3728.28 468.89,3641.38 468.89,3588.76 487.96,3569.7 537.59,3569.7 646.47,3678.58 646.47,4567.25 726,4646.77 726.05,4747.65
OUT_4M_J1_25 on SIG_1 "SIG_1_OUT_4M_J1_25_P010" (solid, pour order 10): 1869.62,4056.97 1911.13,4056.97 1932.89,4078.73 1932.89,4605.94 1645.22,4893.61 623.94,4893.61 467.45,4737.12 467.45,4671.02 479.19,4659.28 527.79,4659.28 668.74,4800.22 1606.65,4800.22 1851.46,4555.41 1851.46,4075.13
GND on SIG_2 "SIG_2_GND_P117" (solid, pour order 117): 0,7047.08 8858.11,7047.08 8858.11,0 0,0
CS-_4 on SIG_2 "SIG_2_CS-_4_P109" (solid, pour order 109): 7363.98,4838.44 7968.17,4838.44 8025.84,4780.77 8025.84,3574 8000.17,3548.33 6540.81,3548.33 6220.23,3871.71 6128.26,3963.68 5703.34,3963.68 5657.22,4009.8 5657.22,4403.73 5706.93,4453.43 5706.93,4804.02 5733.82,4830.91 5733.82,5421.99 5767.97,5456.15 6175.49,5456.15 6657.96,5456.15 6700.56,5413.55 6700.56,4963.24 6825.35,4838.44
VS on SIG_2 "SIG_2_VS_P108" (solid, pour order 108): 6639.09,2636.25 7111.12,3108.28 8147.34,3108.28 8234.66,3020.96 8234.66,383.53 8153.69,302.56 6033.06,302.56 2616,302.56 2427.92,490.64 2427.92,1527.64 2863.18,1962.89 5965.73,1962.89
OUT_3M_J1_25 on SIG_2 "SIG_2_OUT_3M_J1_25_P029" (solid, pour order 29): 1895.73,4765.19 1762.45,4898.46 1046.72,4898.46 463.28,4315.02 463.28,4272.04 472.98,4262.33 522.4,4262.33 1072.71,4812.64 1718.71,4812.64 1854.54,4676.81 1882.2,4676.73 1895.73,4690.26
12V_ALWAYS_ON on SIG_2 "SIG_2_12V_ALWAYS_ON_P116" (solid, pour order 116): 7157.68,4854.86 7929.15,4854.86 8029.91,4955.62 8029.91,6258.73 8058.14,6286.96 8792.08,6286.96 8828.37,6323.26 8828.37,6983.26 8797.45,7014.18 7521.8,7014.18 7472.06,6964.44 7472.06,6261.54 7443.17,6232.65 6934.57,6232.65 6904.81,6262.41 6904.81,6989.71 6882.5,7012.01 6497.49,7012.01 6469.7,6984.23 6469.7,6345.6 6547.37,6267.93 6547.37,5851.76 6720.06,5679.08 6720.06,4955.59 6820.78,4854.86
OUT_2P_J1_25 on SIG_2 "SIG_2_OUT_2P_J1_25_P027" (solid, pour order 27): 721.85,4165.4 604.9,4165.4 474.8,4035.31 474.8,3987.46 487.32,3974.95 568.31,3974.95 727.58,4134.22 727.58,4159.67
OUT_2M_J1_25 on SIG_2 "SIG_2_OUT_2M_J1_25_P026" (solid, pour order 26): 780.16,4136.43 478.16,3834.43 478.16,3789.81 492.43,3775.54 545.54,3775.54 861.34,4091.34 861.34,4132.44 857.73,4136.05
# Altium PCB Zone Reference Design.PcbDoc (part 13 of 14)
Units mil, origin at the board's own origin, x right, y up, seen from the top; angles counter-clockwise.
Board outline 8858.11 x 7047.08 mil, 16 copper layers (Top Layer, GND_1, SIG_1, GND_2, PWR/SIG_1, GND_3, PWR_1, PWR_2, GND_4, PWR/SIG_2, GND_5, SIG_2, GND_6, SIG_3, GND_7, Bottom Layer), stack 80.368 mil thick; 1131 components, 808 nets, 3825 pads, 3523 vias.
Unrouted connection lines stored in the file: 563.

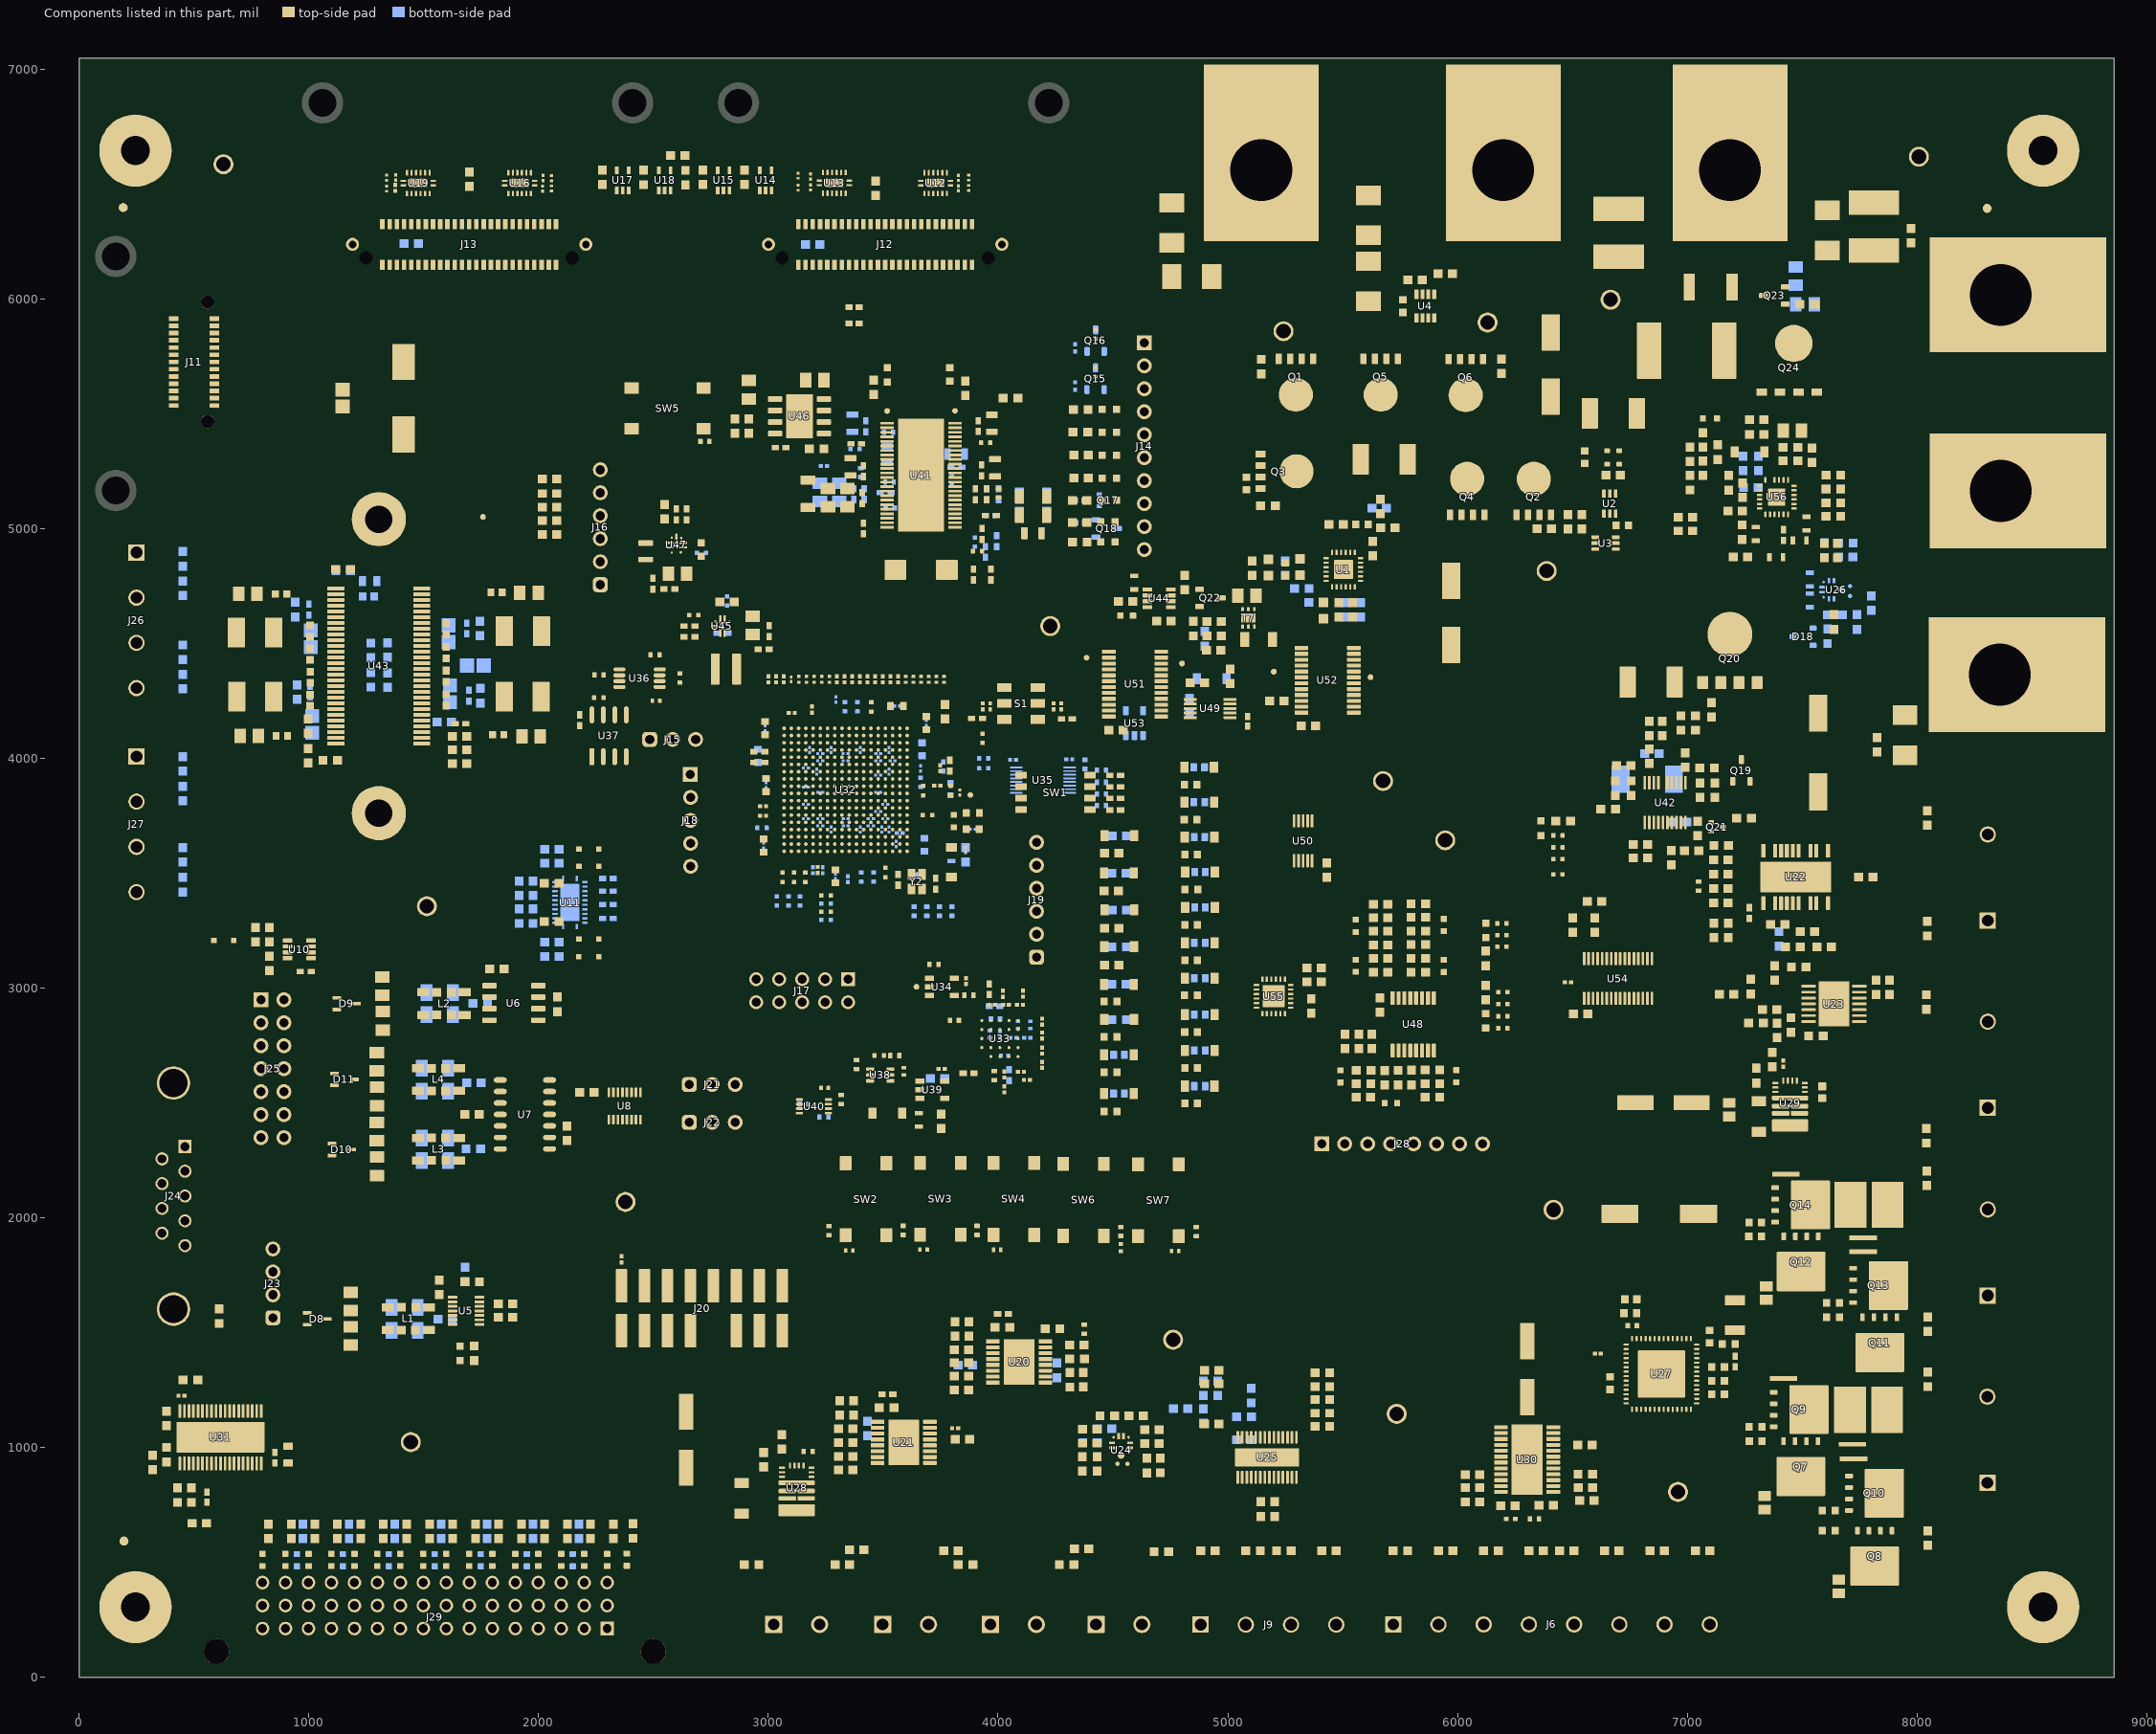
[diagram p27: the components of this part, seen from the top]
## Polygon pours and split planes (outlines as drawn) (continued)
OUT_3P_J1_25 on SIG_2 "SIG_2_OUT_3P_J1_25_P039" (solid, pour order 39): 1977.84,4645.62 1979.6,4645.62 2039.28,4645.62 2076.14,4682.49 2076.14,4784.7 1579.75,5281.08 960.48,5281.08 554.2,4874.8 554.2,4607.18 466.43,4519.41 466.43,4468.33 483.98,4450.77 538.76,4450.77 635.26,4547.28 635.26,4835.87 994.46,5195.07 1530.35,5195.07 1956.77,4768.65 1956.78,4666.69
12V_VBATT_2 on SIG_2 "SIG_2_12V_VBATT_2_P048" (solid, pour order 48): 6423.68,5471.34 6683.88,5471.34 6706.44,5493.91 6706.44,5671.34 6526.48,5851.31 6526.48,6244.25 6453.88,6316.85 6453.88,7013.44 6444.04,7023.28 5951.79,7023.28 5942.32,7013.81 5942.32,6465.89 5942.32,6253.56 5852.53,6163.77 5591.46,6163.77 5532.57,6104.88 5532.57,5692.29 5753.51,5471.34
12V_VBATT_1 on SIG_2 "SIG_2_12V_VBATT_1_P054" (solid, pour order 54): 5174.68,4902.19 5210.31,4937.82 5210.31,5055.34 5168.63,5097.02 5168.63,5200.6 5168.63,5623.04 5186.39,5640.8 5389.19,5640.8 5413.91,5665.52 5413.91,6346.26 5413.91,7000.86 5395.76,7019.01 4892.97,7019.01 4859.26,6985.29 4859.26,5063.7 5020.77,4902.19
GND on GND_7 "GND_7_GND_P046" (solid, pour order 46): 0,7047.08 8858.11,7047.08 8858.11,0 0,0
SHIELD_GND on GND_7 "GND_7_SHIELD_GND_P044" (solid, pour order 44): 1.01,2681.26 1.01,1508.17 29.03,1480.15 489.7,1480.15 580.49,1570.94 630.61,1570.94 638.42,1578.75 638.42,1694.88 545.14,1788.15 545.14,2643.9 481.47,2707.57 27.32,2707.57
GND on SIG_3 "SIG_3_GND_P043" (solid, remove dead copper, pour order 43): 0,7047.08 8858.11,7047.08 8858.11,0 0,0
NetC6_2 on SIG_3 "SIG_3_NETC6_2_P041" (solid, pour order 41): 5793.83,4908.88 4705.81,4908.88 4692.12,4922.57 4692.11,6238.33 4711.6,6257.82 6509.05,6257.82 6532.69,6234.19 6532.69,5850.56 6696.14,5687.1 6696.14,5108.55 6669.15,5081.56 5966.52,5081.56
GND on GND_3 "GND_3_GND_P035" (solid, pour order 35): 0,7047.08 8858.11,7047.08 8858.11,0 0,0
GND on GND_4 "GND_4_GND_P036" (solid, pour order 36): 0,7047.08 8858.11,7047.08 8858.11,0 0,0
GND on GND_5 "GND_5_GND_P038" (solid, pour order 38): 0,7047.08 8858.11,7047.08 8858.11,0 0,0
GND on GND_6 "GND_6_GND_P040" (solid, pour order 40): 0,7047.08 8858.11,7047.08 8858.11,0 0,0
GND on GND_2 "GND_2_GND_P045" (solid, pour order 45): 0,7047.08 8858.11,7047.08 8858.11,0 0,0

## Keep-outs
Keep-Out Layer:
  text ".Layer_Name" at 577,-858.49 h60

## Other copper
Top Layer:
  region net 3V3_2: 1302.81,6485.83 1296.74,6491.89 1296.74,6513.61 1306.2,6523.07 1384.01,6522.54 1421.55,6522.54 1425.87,6518.22 1425.87,6489.92 1421.77,6485.83
  region net VOUT_TPS1211: 6944.89,4054.19 6986.88,4096.17 7074.23,4096.17 7134.43,4156.37 7134.43,4272.16 7117.97,4288.62 7117.97,4352 7129.08,4363.11 7322.8,4363.11 7422.89,4463.2 7774.74,4463.2 7951.98,4640.44 8804.1,4640.44 8825.15,4619.4 8825.15,4114.27 8820.86,4109.98 7910.31,4109.98 7861.06,4060.73 7621.3,4060.73 7436.04,3875.47 7263.27,3875.47 7258.58,3880.16 7258.58,4023.51 7250.1,4031.99 7223.76,4031.99 7186.48,3994.71 6972.77,3994.71 6960.06,3982 6960.06,3864.41 6944.89,3864.41
  region net VOUT1_TPS2HCS05: 7634.2,3410.96 7634.2,3343.29 7614.31,3323.39 7592.63,3323.39 7579.75,3336.28 7579.75,3398.57 7571.25,3407.06 7520.85,3407.06 7507.72,3393.93 7507.72,3289.25 7528.69,3268.28 7659.94,3268.28 8133.61,3268.28 8297.56,3104.32 8810.77,3104.32 8832.1,3125.65 8832.1,3424.89 8802.71,3454.27 7634.2,3454.27 7632.26,3452.32 7632.26,3412.91
  region net 3V3_1: 4520.29,3802.28 4520.29,3939.21 4529.15,3948.06 4600.2,3948.06 4614.02,3934.24 4614.02,3861.46 4614.02,3839.65 4614.02,3775 4584.51,3745.48 4522.95,3745.48 4520.29,3748.14
  region net 3V3_1: 3038.04,1775.7 3122.57,1775.7 3132.26,1766.01 3132.26,1642.85 3120.22,1630.81 3038.04,1630.81 3036.04,1632.81 3036.04,1773.7
  region net 3V3_1: 3484.19,5195.65 3483.46,5196.38 3468.73,5196.38 3464.05,5201.06 3411.36,5201.06 3400.85,5211.58 3315.7,5211.58 3294.99,5232.29 3294.99,5256.24 3300.44,5261.7 3340.51,5261.7 3353.32,5248.89 3425.4,5248.89 3449.06,5225.24 3458.49,5225.24 3465.22,5218.5 3478.34,5218.5 3486.98,5227.14 3545.35,5227.14 3546.5,5226 3546.5,5196.79 3545.35,5195.65
  region net 3V3_1: 3875.84,3714.97 3790.79,3714.97 3787.17,3711.34 3787.17,3669.77 3802.81,3654.13 3866.5,3654.13 3882.14,3669.77 3882.14,3708.67
  region net 12V_ALWAYS_ON: 7581.1,3413.23 7593.07,3401.25 7593.07,3336.49 7597.24,3332.32 7615.31,3332.32 7627,3344.02 7627,3459.89 7764.71,3459.89 7769.33,3464.51 7769.33,3502.58 7764.05,3507.86 7632.63,3507.86 7625.4,3515.09 7625.4,3630.9 7619.67,3636.63 7605.85,3636.63 7585.64,3616.41 7585.64,3552.09 7373.85,3552.09 7361.74,3564.2 7361.74,3622.05 7351.24,3632.55 7311.41,3632.55 7258.13,3579.27 7258.13,3337.34 7270.03,3325.44 7345.54,3325.44 7351.24,3331.15 7351.24,3388.74 7375.73,3413.23
  region net VOUT2_TPS2HCS05: 7511.03,3722.16 7524.09,3735.22 7693.44,3735.22 8789.88,3735.22 8828.63,3696.48 8828.63,3488.36 8804.78,3464.51 7898.29,3464.51 7849.48,3513.32 7634.2,3513.32 7632.26,3515.27 7632.26,3635.62 7621.05,3646.82 7584.36,3646.82 7580.1,3642.56 7580.1,3574.37 7565.59,3559.85 7519.39,3559.85 7511.03,3568.21
  region net NetQ20_1: 7065.84,4361.95 7043.64,4361.95 7010.72,4329.02 7010.72,4224.02 7018.45,4216.29 7118.46,4216.29 7126.2,4224.02 7126.2,4269.91 7106.74,4289.37 7106.74,4343.99 7088.78,4361.95
  region net NetQ20_5: 6848.56,4685.72 6848.56,4498.56 6886.03,4461.09 6886.03,4209.33 6961.8,4209.33 7005.29,4252.82 7005.29,4339.35 7053.38,4387.44 7322.13,4387.44 7382.7,4448.01 7382.7,4656.82 7337.27,4702.25 6865.09,4702.25
  region net VOUT1_TPS2HCS10: 4087.12,46.9 4068.61,28.39 3871.22,28.39 3856.79,42.82 3856.79,866.91 3908.39,918.51 3908.39,1326.7 3923.71,1342.03 4005.88,1342.03 4015.4,1332.51 4015.4,1225.89 4087.12,1154.16
  region net VOUT2_TPS2HCS08: 3756.97,992.01 3783.23,965.75 3783.23,854.09 3791.76,845.56 3791.76,449.11 3823.9,416.98 3823.9,37.47 3812.8,26.37 3612.45,26.37 3593.56,45.26 3593.56,804.15 3665.29,875.87 3665.29,982.5 3674.8,992.01
  region net VOUT1_TPS2HCS08: 3421.06,992.01 3394.8,965.75 3394.8,854.09 3386.27,845.56 3386.27,449.11 3354.13,416.98 3354.13,42.24 3370.01,26.37 3565.53,26.37 3584.47,45.31 3584.47,804.15 3512.74,875.87 3512.74,982.5 3503.23,992.01
  region net OUT1_DRV8245: 3139.45,28.37 3126.38,41.43 3126.38,591.05 3214.71,679.38 3214.71,752.21 3198.23,768.68 3128.69,768.68 3126.38,770.99 3126.38,815.93 3130.32,819.86 3284.31,819.86 3317.47,786.7 3317.47,36.28 3309.56,28.37
  region net OUT2_DRV8245: 3107.41,28.37 3120.48,41.43 3120.48,591.05 3032.15,679.38 3032.15,752.21 3048.63,768.68 3118.17,768.68 3120.48,770.99 3120.48,815.93 3116.54,819.86 2962.55,819.86 2929.39,786.7 2929.39,36.28 2937.3,28.37
  region net VOUT2_TPS2HCS10: 4272.86,29.08 4294.42,50.64 4294.42,444.88 4294.42,860.68 4294.42,1195.57 4285.89,1204.1 4285.89,1315.77 4259.63,1342.03 4177.46,1342.03 4167.94,1332.51 4167.94,1225.89 4096.21,1154.16 4096.21,49.21 4116.35,29.08
  region net 3V3_2: 3904.72,5212.06 3904.72,5236.62 3912.49,5244.39 4054.46,5244.39 4064.74,5234.1 4064.74,5221.13 4049.87,5206.26 3910.52,5206.26
  region net NetL12_1: 2585.05,4912.23 2435.29,4912.23 2428.63,4918.89 2428.63,4952.86 2430.67,4954.9 2498.36,4954.9 2528.91,4924.34 2585.44,4924.34 2587.01,4922.77 2587.01,4914.2
  region net 1V1: 2588.95,4902.39 2600.36,4890.98 2600.36,4772.57 2590.17,4762.38 2434.96,4762.38 2422.51,4774.83 2422.51,4888.11 2436.79,4902.39
  region net NetL6_1: 3784.66,5069.66 3844.02,5069.66 3905.78,5007.9 3905.78,4853.21 3914.48,4844.51 3914.48,4809.01 3907.66,4802.2 3869.11,4802.2 3831.03,4764.11 3726.15,4764.11 3713.21,4777.05 3713.21,4860.8 3837.27,4984.86 3848.68,4996.27 3848.68,5031.18 3841.7,5038.17 3784.66,5038.17 3782.72,5040.12 3782.72,5067.71
  region net NetC278_1: 3544.55,5069.66 3485.96,5069.66 3437.77,5021.47 3437.77,5010.21 3425.71,4998.14 3401.79,4998.14 3392.69,4989.04 3392.69,4872.36 3497.09,4767.96 3599.52,4767.96 3621.42,4789.85 3621.42,4855.34 3492.37,4984.39 3479.83,4996.93 3479.83,5027.33 3490.67,5038.17 3544.55,5038.17 3546.5,5040.12 3546.5,5067.71
  region net VS: 1522.29,5293.84 1552.18,5323.73 1552.18,5512.74 1502.6,5562.32 1109.58,5562.32 1021.18,5473.92 1021.18,5349.88 1077.22,5293.84
  region net OUT_TLIN1021A: 823.91,3014.6 804.06,3014.6 761.71,3056.95 761.71,3148.82 784.38,3171.48 926.1,3171.48 928.05,3173.43 928.05,3187.25 926.1,3189.2 884.43,3189.2 845.05,3228.58 731.58,3228.58 609.93,3106.92 609.93,2918.44 629.72,2898.65 832.14,2898.65 842.91,2909.42 842.91,2995.59
  region net 12V_ALWAYS_ON: 3284.36,1826.84 3221.68,1764.15 3221.68,1355.72 3282.98,1294.42 3482.67,1294.42 3522.68,1254.42 3523.09,924.12 3524.09,923.12 3653.94,923.12 3655.95,925.12 3655.95,1140.11 3745.64,1229.81 3745.64,1545.74 3810,1610.1 4007.35,1610.1 4024.74,1592.71 4024.74,1275.14 4026.75,1273.13 4156.59,1273.13 4158.6,1275.14 4158.6,1769.16 4100.93,1826.84
  region net VS: 7720.09,2943.72 7783.96,2943.72 7810.51,2917.17 7935,2917.17 7961.05,2943.21 7961.05,2984.62 7947.83,2997.84 7799.6,2997.84 7789.23,2987.46 7719.05,2987.46 7717.1,2985.51 7717.1,2946.72
  region net VOUT_TPS1HC30_13: 7719.05,2910.69 7949.53,2910.69 7974.18,2935.34 8802.29,2935.34 8831.67,2905.97 8831.67,2740.43 8807.6,2716.36 7947.41,2716.36 7790.49,2873.29 7719.05,2873.29 7717.1,2875.24 7717.1,2908.74
  region net OUT1_DRV8145: 7372.48,2443.71 7526.11,2443.71 7610.89,2358.93 8072.77,2358.93 8141.92,2289.78 8796.63,2289.78 8830.16,2323.31 8830.16,2676.52 8805.52,2701.16 7817.89,2701.16 7611.62,2494.89 7372.48,2494.89 7368.55,2490.95 7368.55,2447.65
  region net 5V0_2: 3899.93,5403.76 3898.72,5404.97 3898.72,5437.97 3900.07,5439.32 3948.46,5439.32 3952.52,5435.25 4048.51,5435.25 4064.26,5419.5 4048.51,5403.76
  region net OUT1_TPS4HC120: 5273.27,895.41 5273.27,831.91 5280.87,824.3 5296.41,824.3 5304.77,832.66 5304.77,895.41 5302.82,897.36 5275.22,897.36
  region net OUT2_TPS4HC120: 5233.9,895.41 5233.9,831.91 5241.5,824.3 5257.04,824.3 5265.4,832.66 5265.4,895.41 5263.45,897.36 5235.85,897.36
  region net OUT3_TPS4HC120: 5076.42,895.41 5076.42,831.91 5084.02,824.3 5099.56,824.3 5107.92,832.66 5107.92,895.41 5105.97,897.36 5078.37,897.36
  region net OUT4_TPS4HC120: 5037.05,895.41 5037.05,831.91 5044.65,824.3 5060.19,824.3 5068.55,832.66 5068.55,895.41 5066.6,897.36 5039,897.36
  region net 12V_ALWAYS_ON: 5135.47,895.41 5135.47,843.74 5114.41,822.68 5114.41,745.09 5121.22,738.28 5222.65,738.28 5228.85,744.48 5228.85,820.73 5206.34,843.24 5206.34,895.41 5204.39,897.36 5137.42,897.36
  region net OUT1_TPS2HC08: 4601.06,939.35 4616.72,923.69 4616.72,847.7 4712.41,752.02 4712.41,466.38 4761.64,417.14 4761.64,36.06 4751.25,25.67 4558.84,25.67 4540.52,44 4540.52,934.58 4545.29,939.35
  region net OUT2_TPS2HC08: 4475.74,939.35 4460.09,923.69 4460.09,847.7 4364.4,752.02 4364.4,466.38 4315.16,417.14 4315.16,36.06 4325.56,25.67 4517.97,25.67 4533.48,41.19 4533.48,937.38 4531.51,939.35
  region net VS: 2560.56,829.01 2560.56,1009.4 2582.54,1031.38 2731.38,1031.38 2874.63,888.13 2986.57,888.13 3015.09,859.61 3208.29,859.61 3210.93,856.98 3210.93,833.08 3206.4,828.55 2955.1,828.55 2928.47,801.93 2587.64,801.93
  region net 12V_ALWAYS_ON: 3786.33,5114.43 3856.96,5114.43 3876.22,5095.17 3947.19,5095.17 3968.74,5073.62 3968.74,5014.92 4039.14,4944.52 4135.61,4944.52 4144.02,4952.93 4144.02,5168.62 4132.9,5179.74 4064.36,5179.74 4035.55,5150.93 3981.41,5150.93 3977.57,5147.09 3888.06,5147.09 3871.04,5164.1 3854.9,5164.1 3848.55,5170.45 3786.22,5170.45 3782.72,5166.95 3782.72,5118.05
  region net NetL11_1: 2802.1,4519.55 2739.41,4456.86 2739.41,4316.87 2744.59,4311.69 2802.1,4311.69 2815.25,4324.84 2815.25,4561.31 2813.92,4562.65 2806.04,4562.65 2802.1,4558.71
  region net 1V2: 2821.82,4325.58 2836.14,4311.25 2885.84,4311.25 2977.32,4402.73 2977.32,4562.28 2969.69,4569.91 2829.82,4569.91 2821.82,4561.91
  pour cut-out: 2730.81,4302.32 2730.81,4471.44 2899.55,4471.44 2899.55,4302.32
  region net 6V0_BB: 2854.56,5128.22 2671.18,4944.84 2614.95,4944.84 2611.34,4941.23 2611.34,4932.41 2614.15,4929.61 2656.49,4929.6 2673.26,4912.83 2726.7,4912.83 2740.95,4898.58 2740.95,4662.7 2784.09,4619.56 2784.09,4588.2 2786.2,4586.09 2794.78,4586.09 2796.9,4588.2 2796.9,4633.41 2817.27,4653.78 2817.27,4712.55 3146.16,5041.44 3154.77,5041.44 3392.4,5041.44 3444.16,5093.2 3454.17,5093.2 3472.46,5111.48 3482.02,5111.48 3484.56,5114.03 3544.51,5114.03 3546.5,5116.01 3546.5,5148.74 3544.29,5150.95 3444.43,5150.95 3421.71,5128.22
  region net SP2_P1_17: 7438.83,2195.75 7452.53,2209.45 7760.11,2209.45 7787,2182.56 7787,1949.83 7777.66,1940.49 7651.57,1940.49 7602.6,1891.52 7459.78,1891.52 7438.83,1912.47
  region net OUT4_DRV8714: 7775.12,1904.24 7775.12,1919.9 7798.06,1942.83 7798.06,2162.29 7804.38,2168.62 7995.75,2168.62 8070.26,2168.62 8147.17,2245.52 8791.58,2245.52 8827.47,2209.63 8827.47,1905.84 8802.99,1881.36 7798,1881.36
  region net OUT3_DRV8714: 8807.85,1475.03 8159.46,1475.03 8094.01,1540.47 7800.39,1540.47 7781.3,1559.56 7781.3,1835.88 7773.69,1843.49 7773.69,1858.76 7786.82,1871.89 8803.68,1871.89 8827.62,1847.95 8827.62,1494.79
  region net OUT2_DRV8714: 7809.29,1289.77 8065.91,1289.77 8183.19,1407.05 8801.79,1407.05 8827.87,1380.97 8827.87,1014.72 8798.17,985.01 7744.22,985.01 7733.53,995.7 7733.53,1020.61 7750.81,1037.9 7774.26,1037.9 7793.6,1057.24 7793.6,1274.08
  region net SP1_P1_17: 7436.95,1229.82 7436.95,1285.39 7429.16,1293.18 7429.16,1307.56 7435.93,1314.33 7531.12,1314.33 7556.71,1288.74 7771.88,1288.74 7785,1275.62 7785,1062.09 7774.28,1051.38 7649.19,1051.38 7589.01,991.2 7464.72,991.2 7436.95,1018.96
  region net OUT1_DRV8714: 7764.87,921.21 7742.82,943.26 7742.82,955.73 7756.69,969.6 8801.49,969.6 8827.7,943.38 8827.71,624.7 8810.9,607.9 7779.65,607.9 7764.87,622.68
  region net 3V3_2: 6772.19,1493.57 6758.71,1507.05 6758.71,1553.58 6758.71,1665.73 6765.34,1672.37 6808.69,1672.37 6825.66,1655.4 6825.66,1536.16 6786.17,1496.66 6786.17,1461.71 6783.19,1458.74 6775.38,1458.74 6772.19,1461.92
  region net 3V3_2: 3912.04,6513.14 3904.1,6521.08 3783.87,6521.08 3779.78,6516.98 3779.78,6488.68 3784.1,6484.36 3904.14,6484.37 3912.04,6492.27
  region net 3V3_2: 3229.24,6486.14 3234.12,6491.02 3234.12,6516.26 3223.08,6527.3 3101.71,6527.3 3087.8,6513.39 3087.8,6496.36 3098.02,6486.14
  region net 3V3_2: 2095.64,6484.37 2102.83,6491.56 2102.83,6511.43 2093.19,6521.08 1973.22,6521.08 1969.12,6516.98 1969.12,6488.69 1973.44,6484.37
  region net CS-_4: 5723.38,5143.19 5723.38,5092.91 5773.66,5042.63 5900.43,5042.63 5949.08,5091.28 6500.66,5091.27 6556.58,5091.27 6583.75,5118.45 6583.75,5193.71 6526.64,5250.82 6526.64,5284.79 6409.16,5402.27 6373.94,5437.5 5730.06,5437.5 5723.38,5430.82
  region net NetC6_2: 5185.07,5644.17 5185.07,5670.29 5207.79,5693.02 5381.88,5693.02 5416.76,5727.9 5416.76,6247.57 5428.85,6259.65 5504.67,6259.65 5512.37,6251.96 5512.37,5742.35 5552.87,5701.85 6572.86,5701.85 6634.36,5640.35 6634.36,5365.37 6583.9,5314.91 6510.03,5314.91 6370.84,5454.09 5657.69,5454.09 5636.77,5433.17 5636.77,5094.78 5582.99,5041 5582.99,4988.97 5498.19,4904.17 5498.19,4885.84 5488.35,4885.84 5488.35,4916.26 5476.64,4927.97 5476.64,5034.48 5466.77,5044.35 5421.42,5044.35 5414.27,5037.19 5414.27,4959.24 5458.82,4914.69 5458.82,4885.84 5456.85,4883.87 5408.86,4883.87 5236.35,5056.38 5236.35,5114.86 5222.83,5128.38 5185.07,5166.14
  region net NetQ23_3: 7175.81,6119.83 7269.79,6119.83 7356.36,6033.27 7356.36,5998.7 7338.93,5981.27 7178.72,5981.27 7170.68,5989.3 7170.68,6114.71
  region net NetQ24_5: 7266.53,5625.45 7128.66,5625.45 7107.91,5646.21 7107.91,5894.28 7113.39,5899.76 7348.1,5899.76 7617.42,5899.76 7627.75,5889.43 7627.75,5685.36 7581.94,5639.55 7369.32,5639.55 7355.23,5625.45
  region net SRC: 7596.97,6274.46 7547.21,6274.46 7499.29,6226.54 7499.29,6176.78 7394.25,6071.74 7394.25,6036.14 7413.01,6017.38 7618.82,6017.38 7640.12,5996.08 7640.12,5665.39 7598.33,5623.6 7379.15,5623.6 7366.35,5610.8 7366.35,5261.66 7394.27,5233.74 7394.27,5201.03 7404.11,5201.03 7404.11,5227.49 7448.92,5272.29 7448.92,5450.04 7473.43,5474.56 8763.84,5474.56 8827.52,5538.24 8827.52,6270.75 8823.81,6274.46
  region net 12V_ALWAYS_ON: 6983.73,5608.92 6956.58,5636.08 6901.33,5636.08 6887.43,5649.97 6887.43,5894.08 6909.26,5915.9 6909.26,5964.83 6920.76,5976.33 7023.54,5976.33 7032.89,5985.69 7032.89,6112.55 7029.66,6115.78 6918.16,6115.78 6886.7,6147.24 6886.7,6210.15 6817.66,6279.2 6588.26,6279.2 6544.02,6234.96 6544.02,5854.17 6720.98,5677.22 6720.98,5370.48 6760.35,5370.48 6786.05,5344.77 6786.05,5286.49 6786.05,4867.5 6798.63,4854.93 6975.79,4854.93 6983.73,4862.87
  region net 12V_ALWAYS_ON: 769.12,959.28 767.17,957.33 767.17,895.38 772.7,889.85 851.76,889.85 929.86,889.85 960.65,920.63 960.65,939.56 947.8,952.41 820.83,952.41 813.96,959.28
  region net 12V_ALWAYS_ON: 5044.36,4573.79 5044.36,4469.46 5055.03,4458.8 5092.81,4458.8 5104.02,4470.01 5104.01,4576.62 5096.48,4584.16 5054.73,4584.16
  text ".Layer_Name" at 577,-858.49 h60
SIG_1:
  pour cut-out: 7301.71,5064.95 7304.9,5061.75 7304.9,5055.11 7302.45,5055.11 7298.2,5059.35
PWR/SIG_1:
  pour cut-out: 7301.53,5064.38 7304.73,5061.19 7304.73,5054.55 7302.27,5054.55 7298.03,5058.79
  pour cut-out: 7092.39,5991.7 7075.45,5991.7 7063.42,5979.68 7063.42,5963.22 7075.51,5951.13 7091.58,5951.13 7100.79,5960.35 7100.79,5983.29
  region net 6V0_BB: 3374.55,5070.66 3374.55,5125 3414.06,5164.51 3430,5164.51 3442.8,5151.72 3470.27,5151.72 3486.15,5135.84 3486.15,5115.11 3471.16,5100.11 3441.16,5100.11 3427.04,5085.99 3427.04,5071 3418.27,5062.24 3382.97,5062.24
PWR_1:
  pour cut-out: 7092.39,5991.7 7075.45,5991.7 7063.42,5979.68 7063.42,5963.22 7075.51,5951.13 7091.58,5951.13 7100.79,5960.35 7100.79,5983.29
SIG_3:
  region net OUT_TPS1HC04: 7697.67,4680.02 7701.47,4676.22 8767.42,4676.22 8827.46,4736.25 8827.46,5442.98 8815.86,5454.58 7791.81,5454.58 7724.86,5387.63 7724.86,5037.05 7724.86,4987.83 7745.59,4967.11 7745.59,4834.3 7697.67,4786.38
  region net SRC: 7596.97,6274.46 7547.21,6274.46 7499.29,6226.54 7499.29,6176.78 7394.25,6071.74 7394.25,6036.14 7413.01,6017.38 7618.82,6017.38 7640.12,5996.08 7640.12,5884.56 7379.15,5623.6 7366.35,5610.8 7366.35,5261.66 7381.8,5246.22 7425.09,5246.22 7519.47,5340.6 7519.47,5432.88 7561.15,5474.56 8763.84,5474.56 8827.52,5538.24 8827.52,6270.75 8823.81,6274.46
  region net VOUT_TPS1211: 6964.51,3971.91 6942.94,3993.48 6942.94,4052.24 6942.94,4176.97 7129.08,4363.11 7322.8,4363.11 7422.89,4463.2 7774.74,4463.2 7951.98,4640.44 8804.1,4640.44 8825.15,4619.4 8825.15,4085.46 8820.22,4080.53 7880.86,4080.53 7769.34,3969 7529.57,3969 7436.04,3875.47 7263.27,3875.47 7258.58,3880.16 7258.58,3951.48 7238.15,3971.91
SIG_2:
  pour cut-out: 7092.39,5991.7 7075.45,5991.7 7063.42,5979.68 7063.42,5963.22 7075.51,5951.13 7091.58,5951.13 7100.79,5960.35 7100.79,5983.29
Bottom Layer:
  region net OUT_3M_J1_25: 552.67,4334.43 552.67,4243.05 531.86,4222.25 370.4,4222.25 86.9,4222.25 62.72,4246.43 62.72,4379.99 79.83,4397.11 357.01,4397.11 419.68,4334.43
  region net OUT_1M_J1_25: 552.67,3449.08 552.67,3374.66 514.9,3336.9 374.5,3336.9 91.01,3336.9 66.82,3361.08 66.82,3494.64 83.94,3511.76 371.19,3511.76 433.86,3449.08
  region net OUT_4P_J1_25: 548.78,4954.92 512.77,4990.93 360.13,4990.93 85.08,4990.93 65.52,4971.37 65.52,4822.3 80.39,4807.44 345,4807.44 403.97,4866.4 548.78,4866.4
  region net OUT_4M_J1_25: 548.78,4734.22 548.78,4655.6 515.21,4622.03 371.9,4622.03 88.4,4622.03 64.22,4646.22 64.22,4779.78 81.33,4796.89 340.35,4796.89 403.03,4734.22
  region net OUT_3P_J1_25: 551.99,4550.43 511.27,4591.14 358.63,4591.14 83.58,4591.14 64.02,4571.58 64.02,4422.52 78.89,4407.65 359.75,4407.65 415.4,4463.3 551.99,4463.3
  region net OUT_1P_J1_25: 551.99,3669.18 515.37,3705.8 362.73,3705.8 87.69,3705.8 68.13,3686.23 68.13,3537.17 82.99,3522.3 370.44,3522.3 429.41,3581.27 551.99,3581.27
  region net OUT_2M_J1_25: 553.35,3848.87 553.35,3770.1 519.94,3736.68 376,3736.68 92.51,3736.68 68.32,3760.87 68.32,3894.43 85.44,3911.54 362.61,3911.54 425.28,3848.87
  region net 3V3_1: 3236.11,2426.93 3236.11,2504.89 3231.56,2509.44 3165.74,2509.44 3160.62,2504.32 3160.62,2447.98 3187.37,2421.24 3230.42,2421.24
  region net 3V3_1: 2305.14,3488.22 2305.14,3287.85 2313.21,3279.77 2359.35,3279.77 2371.24,3291.67 2371.24,3484.28 2360.9,3494.62 2311.54,3494.62
  region net OUT1_TLIN1024A: 2000.96,3449.58 2000.96,3528.09 1993.61,3535.44 1993.61,3552.72 2000.96,3560.07 2000.96,3622.97 2010.53,3632.55 2047.4,3632.55 2054.43,3625.52 2054.43,3453.96 2063.21,3445.18 2081.21,3445.18 2083.19,3443.2 2083.19,3437.71 2081.21,3435.73 2014.81,3435.73
  region net OUT4_TLIN1024A: 2000.96,3293.54 2000.96,3215.03 1993.61,3207.68 1993.61,3190.39 2000.96,3183.04 2000.96,3120.14 2010.53,3110.57 2047.4,3110.57 2053.62,3116.79 2053.62,3289.13 2062.42,3297.94 2081.21,3297.94 2083.19,3299.92 2083.19,3305.4 2081.21,3307.38 2014.81,3307.38
  region net OUT2_TPS2HC08: 4533.48,489.29 4533.48,770.03 4503.65,799.86 4412.24,799.86 4364.4,752.02 4364.4,466.38 4315.16,417.14 4315.16,36.06 4325.56,25.67 4517.97,25.67 4533.48,41.19
  region net OUT1_TPS2HC08: 4543.33,489.29 4543.33,769.2 4573.98,799.86 4664.56,799.86 4712.41,752.02 4712.41,466.38 4761.64,417.14 4761.64,36.06 4751.25,25.67 4558.84,25.67 4543.33,41.19
  region net OUT1_DRV8714: 7764.87,921.21 7813.25,969.6 8801.49,969.6 8827.7,943.38 8827.71,624.7 8810.9,607.9 7779.65,607.9 7764.87,622.68
  region net OUT2_DRV8714: 7809.29,1289.77 8065.91,1289.77 8183.19,1407.05 8801.79,1407.05 8827.87,1380.97 8827.87,1014.72 8798.17,985.01 7806.51,985.01 7793.6,997.93 7793.6,1274.08
  region net OUT3_DRV8714: 8807.85,1475.03 8159.46,1475.03 8094.01,1540.47 7800.39,1540.47 7781.3,1559.56 7781.3,1835.88 7781.3,1860.74 7792.45,1871.89 8803.68,1871.89 8827.62,1847.95 8827.62,1494.79
  region net OUT4_DRV8714: 7798.06,1902.11 7798.06,2155.2 7811.47,2168.62 7995.75,2168.62 8070.26,2168.62 8147.17,2245.52 8791.58,2245.52 8827.47,2209.63 8827.47,1905.84 8802.99,1881.36 7818.81,1881.36
  region net OUT1_DRV8145: 7377.81,2416.66 7506.5,2416.66 7564.22,2358.93 8072.77,2358.93 8141.92,2289.78 8796.63,2289.78 8830.16,2323.31 8830.16,2653.75 8782.74,2701.16 7699.52,2701.16 7502.72,2504.36 7379,2504.36 7368.55,2493.91 7368.55,2425.92
  region net VOUT_TPS1HC30_13: 7790.49,2748.13 7790.49,2890.81 7810.37,2910.69 7949.53,2910.69 7974.18,2935.34 8796.88,2935.34 8831.67,2900.56 8831.67,2746.17 8801.85,2716.36 7822.25,2716.36
  pour cut-out: 7301.53,5064.38 7304.73,5061.19 7304.73,5054.55 7302.27,5054.55 7298.03,5058.79
  region net OUT_2P_J1_25: 553.35,4069.1 516.87,4105.58 364.23,4105.58 89.19,4105.58 69.63,4086.02 69.63,3936.95 84.49,3922.09 364.55,3922.09 423.51,3981.05 553.35,3981.05
  region net OUT2_DRV8245: 3107.41,28.37 3120.48,41.43 3120.48,661.94 3068.31,714.11 3068.31,737.81 3099.18,768.68 3118.17,768.68 3120.48,770.99 3120.48,815.93 3116.54,819.86 2962.55,819.86 2929.39,786.7 2929.39,36.28 2937.3,28.37
  region net OUT1_DRV8245: 3139.45,28.37 3126.38,41.43 3126.38,661.94 3178.7,714.25 3178.7,737.5 3147.51,768.68 3128.69,768.68 3126.38,770.99 3126.38,815.93 3130.32,819.86 3284.31,819.86 3317.47,786.7 3317.47,36.28 3309.56,28.37
  region net VOUT1_TPS2HCS05: 7536.95,3271.88 7503.61,3305.22 7503.61,3389.39 7525.83,3411.62 7707.39,3411.62 7750.04,3454.27 8802.71,3454.27 8832.1,3424.89 8832.1,3125.65 8810.77,3104.32 8297.56,3104.32 8130.01,3271.88
  region net VOUT2_TPS2HCS05: 7632.26,3560.94 7520.15,3560.94 7497.31,3583.78 7497.31,3682.41 7550.12,3735.22 8789.88,3735.22 8828.63,3696.48 8828.63,3488.36 8804.78,3464.51 7898.29,3464.51 7849.48,3513.32 7679.87,3513.32
  region net VOUT2_TPS2HCS10: 4096.21,793.27 4128.17,825.22 4263.94,825.22 4294.42,794.75 4294.42,652.78 4294.42,444.88 4294.42,50.64 4272.86,29.08 4116.35,29.08 4096.21,49.21
  region net VOUT1_TPS2HCS10: 3856.79,454.86 3856.79,792.3 3887.7,823.21 4058.1,823.21 4087.12,794.19 4087.12,600.53 4087.12,46.9 4068.61,28.39 3871.22,28.39 3856.79,42.82
  region net VOUT2_TPS2HCS08: 3593.56,804.15 3618.8,829.39 3758.69,829.39 3791.76,796.31 3791.76,449.11 3823.9,416.98 3823.9,37.47 3812.8,26.37 3612.45,26.37 3593.56,45.26
  region net VOUT1_TPS2HCS08: 3386.27,796.99 3415.16,825.88 3562.74,825.88 3584.47,804.15 3584.47,45.31 3565.53,26.37 3370.01,26.37 3354.13,42.24 3354.13,416.98 3386.27,449.11
  region net 5V0_1: 3871.22,5253.78 3883.32,5265.87 3883.32,5322.09 3871.22,5334.18 3871.22,5351.81 3865.41,5357.62 3840.46,5357.62 3831.45,5348.62 3831.45,5306.78 3820.42,5295.75 3820.42,5250.97 3824.41,5246.98 3864.43,5246.98
  region net OUT3_TLIN1024A: 1968.71,3365.94 1896.57,3365.94 1879.3,3348.68 1879.3,3334.27 1899.07,3314.5 2013.61,3314.5 2036.41,3337.31 2081.21,3337.31 2083.19,3339.29 2083.19,3344.77 2081.21,3346.75 2056.16,3346.75 2036.97,3365.94
  region net OUT2_TLIN1024A: 1968.71,3377.17 1896.57,3377.17 1881.07,3392.67 1881.07,3410.61 1899.07,3428.61 2013.61,3428.61 2036.41,3405.81 2081.21,3405.81 2083.19,3403.82 2083.19,3398.34 2081.21,3396.36 2059.02,3396.36 2039.83,3377.17
  region net PLDO2_OUT_3: 3462.34,5404.9 3456.84,5410.4 3456.84,5430.99 3447.15,5440.68 3338.51,5440.68 3324.75,5426.91 3324.75,5415.22 3338.82,5401.14 3431.31,5401.14 3435.83,5396.62 3435.83,5391.76 3447.32,5380.27 3458.3,5380.27 3462.34,5384.31
  region net 6V0_BB: 3487.18,5129.99 3481.96,5135.21 3468.25,5135.21 3453.55,5149.91 3191.85,5149.91 3156.87,5114.92 3156.87,5051.33 3166.51,5041.69 3392.67,5041.69 3443.32,5092.34 3465.08,5092.34 3487.18,5114.45
  pour cut-out: 5685.95,4888.28 5659.83,4888.28 5650.19,4878.65 5676.32,4878.65
  region net OUT_TPS1HC04: 7697.67,4680.02 7701.47,4676.22 8767.42,4676.22 8827.46,4736.25 8827.46,5442.98 8815.86,5454.58 7791.81,5454.58 7724.86,5387.63 7724.86,5037.05 7724.86,4987.83 7745.59,4967.11 7745.59,4844 7715.35,4813.77 7697.67,4796.08
  region net 12V_ALWAYS_ON: 3837.5,5154.89 3837.5,5117.79 3861.76,5093.54 3943.47,5093.54 3968.75,5068.26 3968.75,4953.75 3974.92,4947.58 4138.3,4947.58 4151.89,4961.17 4151.89,5162.87 4131.67,5183.1 4049.76,5183.1 4012.99,5146.33 3932.05,5146.33 3917.03,5161.36 3843.97,5161.36
  region net 12V_ALWAYS_ON: 6987.33,4854.93 7074.11,4854.93 7119.38,4900.19 7119.38,5703.39 7049.2,5773.57 7049.2,5988.31 7049.2,6103.81 7037.23,6115.78 6918.16,6115.78 6886.7,6147.24 6886.7,6210.15 6817.66,6279.2 6588.26,6279.2 6544.02,6234.96 6544.02,5854.17 6720.98,5677.22 6720.98,5096.05 6756.86,5060.17 6756.86,5041.99 6720.97,5006.11 6720.97,4867.31 6733.36,4854.93
  text ".Layer_Name" at 577,-858.49 h60

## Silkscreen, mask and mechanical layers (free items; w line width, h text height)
Top Overlay:
  lines w5: 3987.09,5189.01 3994.33,5196.25 4065.6,5196.25 4073.98,5204.63 ; 5753.64,2539.21 5764.03,2528.82 ; 5813.36,2486.25 5806.61,2486.25 ; 5868.29,2479.39 5861.44,2486.25 5806.61,2486.25 ; 5764.03,2528.82 5806.61,2486.25 ; 5764.03,2528.82 5806.61,2486.25
  text "12V_1" at 4599.95,6865.32 h100
  text "12V_2" at 5634.84,6865.32 h100
  text "GND" at 6711.41,6864.44 h100
  text "1214" at 8057.82,6285.25 h60
  text "12V_ALWAYS_ON" at 6505.42,6088.22 h45
  text "ETHERNET DAUGHTER CARD 1" at 3222.12,6073.16 h45
  text "ETHERNET DAUGHTER CARD 2" at 1393.91,6065.09 h45
  text "MAC 2" at 1624.19,6021.91 h45
  text "MAC 1" at 3438.15,6021.91 h45
  text "12V_1" at 5333.51,5846.87 h45
  text "SAFETY_ERROR" at 4064.93,5833.98 h45
  text "12V_2" at 5951.05,5814.8 h45
  text "5V_TRACK" at 4708.49,5797.58 h45
  text "LPM" at 3743.95,5771.66 h60
  text "PLDO2" at 4706.86,5693.58 h45
  text "SYSTEM WAKE" at 2373.5,5668.13 h60
  text "SAFE_OUT1" at 4152.28,5666.09 h45
  text "6V0" at 4708.58,5578.11 h45
  text "T1S NETWORK" at 740.76,5573.01 h45 r90
  text "5V0_1" at 4700.83,5490.08 h45
  text "HC04" at 8047.62,5446.78 h60
  text "ETHERNET DAUGHTER CARD 3" at 685.28,5416.73 h45 r90
  text "5V0_2" at 4705.13,5395.3 h45
  text "3V3_1" at 4709.44,5296.21 h45
  text "nCS_ETH" at 2330.3,5244.69 h40
  text "3V3_2" at 4706,5189.36 h45
  text "nCS_CAN" at 2330.3,5144.68 h40
  text "1V8" at 4708.58,5099.04 h45
  text "POCI" at 2330.3,5040.37 h40
  text "1V1" at 4709.44,4995.64 h45
  text "PICO" at 2330.3,4941.52 h40
  text "3V3_ALWAYS_ON" at 4702.55,4893.82 h45
  text "SCLK" at 2327.29,4845.09 h40
  text "OUT_4P" at 48.79,4833.56 h40 r90
  text "CAN/ETH SPI" at 2195.93,4828.46 h60 r90
  text "GND" at 2330.3,4741.72 h40
  text "12V_LOAD_DISCONNECT" at 6177.25,4691.9 h45
  text "1211" at 8047.62,4650.11 h60
  text "OUT_4M" at 48.08,4630.75 h40 r90
  text "OUT_3P" at 48.08,4453.3 h40 r90
  text "OUT_3M" at 47.38,4230.07 h40 r90
  text "GND" at 2494.11,4140.04 h40 r90
  text "SCL" at 2592.89,4140.04 h40 r90
  text "SDA" at 2693.99,4140.04 h40 r90
  text "I2C" at 2493.52,3993.84 h45
  text "OUT_2P" at 48.36,3931.1 h40 r90
  text "GND" at 2505.36,3908.95 h50
  text "PAAT eFuse Fault" at 6151.28,3830.79 h45
  text "SCLK" at 2479.24,3815.52 h50
  text "OUT_2M" at 47.24,3751.77 h40 r90
  text "PICO" at 2485.42,3717.4 h50
  text "CS_TXE" at 4222.88,3623.11 h45
  text "POCI" at 2481.99,3614.48 h50
  text "HCS05_2" at 7913.82,3604.32 h45
  text "PMIC SPI" at 2771.85,3602.5 h65 r90
  text "OUT_1P" at 46.26,3556.86 h40 r90
  text "CS_MSDI" at 4227.38,3522.85 h45
  text "CS" at 2542.42,3512.42 h50
  text "POCI" at 4227.38,3415.64 h45
  text "MD FAULT" at 6090.15,3415.07 h45
  text "HCS05_1" at 7915.84,3406.47 h45
  text "OUT_1M" at 47.4,3349.94 h40 r90
  text "PICO" at 4228.27,3315.58 h45
  text "SCLK" at 4226.48,3223.56 h45
  text "IO MANAGEMENT SPI" at 4085.33,3196.76 h45 r90
  text "GND" at 3357.14,3127.71 h45 r90
  text "GND" at 4226.48,3121.71 h45
  text "CS_HCS05" at 2950.98,3113.27 h45 r90
  text "CS_8x45" at 3053.39,3113.27 h45 r90
  text "CS_81242" at 3154.21,3113.27 h45 r90
  text "CS_8714" at 3253.62,3113.27 h45 r90
  text "1044_N" at 947.36,2939.26 h40
  text "1021" at 657.97,2937.35 h40
  text "1024_1" at 615.66,2837.78 h40
  text "1044_P" at 953.03,2835.13 h40
  text "LOAD DRIVER SPI" at 2873.07,2825.88 h45 r90
  text "GND" at 3362.36,2778.49 h45 r90
  text "PICO" at 3165.78,2771.75 h45 r90
  text "POCI" at 3062.67,2770.78 h45 r90
  text "SCLK" at 3260.21,2765 h45 r90
  text "HC30" at 8066.71,2747.76 h45 r90
  text "CAN - 1043" at 52.52,2739.04 h45
  text "1046_2_N" at 949.38,2738.57 h40
  text "1024_2" at 615.66,2736.24 h40
  text "HSS FAULT" at 6096.71,2675.49 h45
  text "1046_2_P" at 951.19,2646.11 h40
  text "CS_HCS10/20" at 2955.92,2642.62 h40 r90
  text "1024_3" at 615.66,2637.53 h40
  text "GND" at 2666.78,2638.18 h45 r90
  text "5_RXD" at 2764.11,2638.18 h45 r90
  text "5_TXD" at 2866.65,2638.18 h45 r90
  text "1024_4" at 613.78,2535.99 h40
  text "1046_1_N" at 951,2532.52 h40
  text "8145" at 8070.36,2470.53 h45 r90
  text "GND" at 657.37,2435.34 h40
  text "1046_1_P" at 953.29,2431.9 h40
  text "UART" at 2580.29,2423.24 h45 r90
  text "GND" at 950.7,2333.81 h40
  text "GND" at 655.49,2329.11 h40
  text "PORz" at 3298.48,2290.45 h60
  text "RESET" at 3942.56,2289.17 h60
  text "nINT2" at 4320.34,2289.17 h60
  text "nINT3" at 4643.07,2289.17 h60
  text "nINT" at 3628.27,2286.78 h60
  text "GND" at 2666.63,2264.59 h45 r90
  text "LIN/CAN" at 738.69,2230.47 h60
  text "3_TXD" at 2874.5,2227.08 h45 r90
  text "3_RXD" at 2771.35,2226.3 h45 r90
  text "S7" at 5424.44,2205.07 h45 r90
  text "S6" at 5522.82,2205.07 h45 r90
  text "S5" at 5622.59,2205.07 h45 r90
  text "S4" at 5723.75,2205.07 h45 r90
  text "S3" at 5820.06,2205.07 h45 r90
  text "S2" at 5919.14,2205.07 h45 r90
  text "S1" at 6017.52,2205.07 h45 r90
  text "S0" at 6118.68,2205.07 h45 r90
  text "TMUX1308" at 5653.13,2150.76 h45
  text "Zone Reference Design" at 4993.09,1984.24 h120
  text "8714_4" at 8060.64,1917.07 h45 r90
  text "EMULATION HEADER" at 2449.54,1858.57 h60
  text "1043_N" at 668.07,1654.98 h40
  text "8714_3" at 8060.64,1645.56 h45 r90
  text "1043_P" at 670.8,1550.15 h40
  text "'.PRJ_Number'.PCB_Rev" at 5168.68,1521.85 h108.27
  text "CAN FAULT" at 1554.12,1282.67 h60
  text "8714_2" at 8058.34,1054.09 h45 r90
  text "MSDI" at 1442.7,817.07 h60
  text "8714_1" at 8060.21,774.51 h45 r90
  text "HCS08_1" at 3420.37,459.62 h45
  text "HCS08_2" at 3614.63,459.62 h45
  text "HC08_2" at 4378.14,456.58 h45
  text "HC08_1" at 4559.71,456.58 h45
  text "HC120_4" at 4796.56,456.58 h45
  text "HC120_3" at 4995.49,456.58 h45
  text "HC120_2" at 5195.03,456.58 h45
  text "HC120_1" at 5394.58,456.58 h45
  text "81xx_7" at 5645.1,456.97 h45
  text "81xx_5" at 5844.02,456.97 h45
  text "81xx_3" at 6043.57,456.97 h45
  text "81xx_1" at 6243.11,456.97 h45
  text "81xx_0" at 6438.5,456.97 h45
  text "81xx_2" at 6637.43,456.97 h45
  text "81xx_4" at 6836.97,456.97 h45
  text "81xx_6" at 7036.52,456.97 h45
  text "HCS10_2" at 4175.38,454.06 h45 r90
  text "HCS10_1" at 3984.15,452.62 h45 r90
  text "8245_2" at 3039.83,450.75 h45 r90
  text "8245_1" at 3230.54,450.75 h45 r90
  text ".Layer_Name" at 577,-858.49 h60
Bottom Overlay:
  text ".Layer_Name" at 577,-858.49 h60
Top Paste:
  text ".Layer_Name" at 577,-858.49 h60
Bottom Paste:
  text ".Layer_Name" at 577,-858.49 h60
Top Solder:
  text ".Layer_Name" at 577,-858.49 h60
  text ".Layer_Name" at 577,-858.49 h60
Bottom Solder:
  text ".Layer_Name" at 577,-858.49 h60
Drill Guide:
  text ".Layer_Name" at 577,-858.49 h60
M1 Board Outline:
  the board outline again, w10
  text ".Layer_Name" at 577,-858.49 h60
M2 Board Dimensions:
  rectangle: 0,-275 125,-150
  rectangle: 125,-400 500,-275
  lines w7: 0,-275 1000,-275 ; 125,-400 125,-150 ; 250,-400 250,-150 ; 500,-400 500,-150 ; 750,-400 750,-150 ; 0,-400 1000,-400 1000,-150 0,-150 0,-400
  text ".Layer_Name" at 577,-858.49 h60
M3 3D STEP Top:
  text ".Layer_Name" at 577,-858.49 h60
M4 3D STEP Bottom:
  text ".Layer_Name" at 577,-858.49 h60
M5 Assembly Top:
  lines w10: -292,-930.17 6308,-930.17 ; -292,-726.83 6310,-726.83 ; -292,-523.5 -292,-1133.5 3713,-1133.5 6310,-1133.5 6310,-523.5 -291.5,-523.5 -291.5,-1133.5 1284,-1133.5 ; 2173,-1133.5 2173,-523.5 ; 3440,-726.83 3440,-523.5 ; 4280,-726.83 4280,-523.5 ; 4902,-1140 4902,-937.17
  text "COMPONENTS MARKED 'DNP' SHOULD NOT BE POPULATED." at 1153.5,-318.5 h60
  text "ASSEMBLY VARIANT:" at 1153,-434 h60
  text ".VariantName" at 2189,-434 h60
  text "PCB VIEWED FROM TOP SIDE" at -228.5,-655.67 h60
  text "BOARD #:" at 2248,-655.67 h60
  text ".PRJ_Number" at 2793.5,-655.67 h60
  text "REV:" at 3638,-655.67 h60
  text ".PCB_Rev" at 3929.5,-655.67 h60
  text "SVN REV:" at 4476,-655.67 h60
  text ".VersionControl_RevNumber" at 4982,-655.67 h60
  text "TID #:" at 2248,-859 h60
  text ".TID" at 2793.5,-859 h60
  text "PLOT NAME =" at -228.5,-1064.34 h60
  text ".plot_File_Name" at 577,-1064.34 h60
  text "GENERATED    :" at 2250,-1064.34 h60
  text ".Print_Date" at 3119.5,-1064.34 h60
  text ".Print_Time" at 3848.5,-1064.34 h60
  text "TEXAS INSTRUMENTS" at 5113,-1064.34 h60
M6 Assembly Bottom:
  lines w10: -292.5,-727.33 6309.5,-727.33 ; -290.5,-930.67 6309.5,-930.67 ; 1115.5,-1140.5 1115.5,-937.67 ; 1737.5,-727.33 1737.5,-524 ; 2577.5,-727.33 2577.5,-524 ; 3844.5,-1134 3844.5,-524 ; 4733.5,-1134 6309,-1134 6309,-524 -292.5,-524 -292.5,-1134 2304.5,-1134 6309.5,-1134 6309.5,-524
  text "COMPONENTS MARKED 'DNP' SHOULD NOT BE POPULATED." at 6102,-318 h60
  text ".VariantName" at 5058,-434 h60
  text "ASSEMBLY VARIANT:" at 6097,-434 h60
  text ".VersionControl_RevNumber" at 1035.5,-656.17 h60
  text "SVN REV:" at 1541.5,-656.17 h60
  text ".PCB_Rev" at 2088,-656.17 h60
  text "REV:" at 2379.5,-656.17 h60
  text ".PRJ_Number" at 3224,-656.17 h60
  text "BOARD #:" at 3769.5,-656.17 h60
  text "PCB VIEWED FROM BOTTOM SIDE" at 6246,-656.17 h60
  text ".TID" at 3224,-859.5 h60
  text "TID #:" at 3769.5,-859.5 h60
  text "TEXAS INSTRUMENTS" at 904.5,-1064.84 h60
  text ".Print_Time" at 2169,-1064.84 h60
  text ".Print_Date" at 2898,-1064.84 h60
  text "GENERATED    :" at 3767.5,-1064.84 h60
  text ".plot_File_Name" at 5440.5,-1064.84 h60
  text "PLOT NAME =" at 6246,-1064.84 h60
M9 Title Sheet:
  drawing of 57 lines, arcs and shapes, not listed
  text "1" at 739.84,8036.5 h70
  text "2" at 3235.5,8036.5 h70
  text "3" at 5724.84,8036.5 h70
  text "4" at 8231.51,8036.5 h70
  text "5" at 10730.5,8036.5 h70
  text "6" at 13235.5,8036.5 h70
  text "A" at -416.5,6893.5 h70
  text "A" at 14383.5,6893.5 h70
  text "B" at -416.5,4513.5 h70
  text "B" at 14383.5,4513.5 h70
  text "C" at -416.5,2138.5 h70
  text "C" at 14383.5,2138.5 h70
  text "PROJECT TITLE:" at 11343.5,277.5 h45
  text ".PRJ_Title" at 11393.5,144.17 h70
  text "DESIGNED FOR:" at 11343.5,-23.5 h45
  text ".PRJ_Customer" at 11393.5,-163.5 h70
  text "D" at -416.5,-231.5 h70
  text "D" at 14383.5,-231.5 h70
  text "FILE NAME:" at 11343.5,-323.5 h45
  text ".PCB_File_Name_No_Path" at 11393.5,-443.5 h70
  text "Texas Instruments (TI) and/or its licensors do not warrant the accuracy or completeness of this specification" at 6374,-605.34 h45
  text "ENGINEER:" at 11343.5,-613.5 h45
  text "LAYOUT BY:" at 12848.5,-613.5 h45
  text "or any information contained therein. TI and/or its licensors do not warrant that this design will meet" at 6329.01,-718 h45
  text ".PRJ_Engineer" at 11393.5,-768.49 h70
  text ".PCB_Layout" at 12899,-768.49 h70
  text "the specifications, will be suitable for your application or fit for any particular purpose, or will operate in" at 6329.01,-830.67 h45
  text ".Layer_Name" at 577,-858.49 h60
  text "ALTIUM DESIGNER VERSION:" at 12848.5,-923.5 h45
  text "an implementation. TI and/or its licensors do not warrant that the design is production worthy. You should" at 6329.01,-943.33 h45
  text "completely validate and test your design implementation to confirm the system functionality for your application." at 6374,-1056 h45
  text ".print_Scale" at 11393.5,-1056.83 h70
  text ".Application_BuildNumber" at 12899,-1056.83 h70
  text "1" at 739.84,-1263.5 h70
  text "2" at 3235.5,-1263.5 h70
  text "3" at 5724.84,-1263.5 h70
  text "4" at 8231.51,-1263.5 h70
  text "5" at 10730.5,-1263.5 h70
  text "6" at 13235.5,-1263.5 h70
M10 Fab Notes:
  drawing of 189 lines, arcs and shapes, not listed
  text "FAB NOTES" at 8954.84,7701.37 h150
  text "1. TRACES REQUIRE 120 OHM DIFFERENTIAL IMPEDANCE: / LAYER 1 & 16: 4 MIL, 7.8 MIL SPACE /  / 2. TRACES REQUIRE 50 OHM IMPEDANCE: / LAYER 1 & 16: 9.9 MIL / LAYER 3 & 14: 3.6 MIL /  / 3. 8 MIL VIAS REQUIRE NON-CONDUCTIVE FILL AND PLANARIZE" at 8950,6501.48 h80
  text "DESIGN INFORMATION" at 12382.02,6356.17 h60
  text "3.6" at 12764.02,6226.15 h60
  text "MIN. TRACK WIDTH:" at 11737.46,6224.05 h60
  text "MIL" at 12988.46,6224.05 h60
  text "3.937" at 12667.32,6102.36 h60
  text "MIN. CLEARANCE:" at 11737.46,6099.92 h60
  text "MIL" at 12988.46,6099.92 h60
  text "MIN. VIA PAD SIZE:" at 11737.46,5975.8 h60
  text "18" at 12803.71,5975.8 h60
  text "MIL" at 12988.46,5975.8 h60
  text "0.05mm (2MIL)" at 12432.46,5845.9 h60
  text "MINIMUM ANNULAR RING" at 11408.23,5837.67 h60
  text "EXTERNAL" at 13140.46,5837.67 h60
  text "PER" at 11608.23,5727.55 h60
  text "IPC-D-275 CLASS 2 LEVEL C" at 11828.23,5727.54 h60
  text "MIL, HOLES" at 13316.46,5627.07 h60
  text "+/-" at 12924,5618.48 h60
  text "+/-" at 13778,5618.48 h60
  text "REGISTRATION TOLERANCES:" at 11408.23,5617.42 h60
  text "METAL" at 12608,5617.42 h60
  text "5" at 13184.2,5617.42 h60
  text "3" at 14017.2,5617.42 h60
  text "MIL" at 14133.46,5617.42 h60
  text "HOLE SIZE TOLERANCE (UNLESS OTHERWISE SPECIFIED):" at 11408.23,5519.1 h60
  text "+/-" at 13778,5516.23 h60
  text "3" at 14017.2,5515.17 h60
  text "MIL" at 14133.46,5515.17 h60
  text "MATERIAL:" at 11333.46,5377.52 h60
  text "FR-4 High Tg" at 12319.9,5249 h60
  text "X" at 12175.46,5241.01 h60
  text "FR-4" at 11754.46,5236.49 h60
  text "OTHER" at 13242.46,5236.49 h60
  text "62 MIL (1.6mm) +/-10%" at 12074.56,5093.46 h60
  text "82 MIL +/- 10%" at 13653.53,5093.46 h60
  text "X" at 13242.58,5086.09 h60
  text "THICKNESS:" at 11408.23,5085.24 h60
  text "OTHER" at 13359.46,5085.24 h60
  text "TOLERANCE:" at 11408.23,4946.92 h60
  text "X" at 12256.46,4946.92 h60
  text "ANSI IPC-6012 TYPE 3 CLASS 2" at 12434.48,4946.92 h60
  text "OTHER +/-" at 12434.46,4802.73 h60
  text "BOW & TWIST:" at 11408.23,4657.54 h60
  text "X" at 12256.46,4657.54 h60
  text "ANSI IPC-6012 TYPE 3 CLASS 2" at 12434.48,4657.54 h60
  text "OTHER +/-" at 12434.46,4510.85 h60
  text "DRILLING:" at 11333.46,4380.23 h60
  text "NC_DRILL FILES" at 13094.46,4275.04 h60
  text "REFERENCE:" at 11408.23,4271.1 h60
  text "X" at 12065.46,4271.01 h60
  text "AS SHOWN" at 12243.46,4271.1 h60
  text "X" at 12966.46,4271.1 h60
  text "OTHER" at 13392.46,4128.85 h60
  text "PTH COPPER THICKNESS:" at 11407.91,4125.32 h60
  text "X" at 12547.14,4125.32 h60
  text "20-30 um" at 12675.14,4125.32 h60
  text "BOARD FINISH:" at 11333.46,3977.73 h60
  text "SILKSCREEN:" at 11488.68,3867.6 h60
  text "X" at 12446.46,3867.6 h60
  text "TOP" at 12563.46,3867.6 h60
  text "X" at 12956.46,3867.6 h60
  text "BOTTOM" at 13074.46,3867.6 h60
  text "SILKSCREEN COLOR:" at 11488.68,3712.41 h60
  text "X" at 12445.46,3712.41 h60
  text "WHITE" at 12563.46,3712.41 h60
  text "OTHER" at 13074.46,3712.41 h60
  text "X" at 12576.46,3568.96 h60
  text "GREEN" at 12694.46,3568.96 h60
  text "OTHER" at 13312.46,3568.96 h60
  text "SOLDER RESIST COLOR:" at 11488.68,3562.1 h60
  text "X" at 12576.46,3414.71 h60
  text "MATTE" at 12694.46,3414.71 h60
  text "SEMI-GLOSS" at 13312,3414.07 h60
  text "IMMERSION GOLD (ENIG)" at 12394.46,3241.94 h60
  text "ENEPIG" at 13732,3234.72 h60
  text "SURFACE FINISH:" at 11333.46,3233.72 h60
  text "X" at 12216.46,3233.72 h60
  text "IMM. TIN/SILVER OR EQUIV" at 11663,3096.4 h60
  text "OTHER" at 13094.46,3092.47 h60
  text "ARRAY/PANEL:" at 11333.46,2937.09 h60
  text "CUT AND TRIM PER M1 BOARD OUTLINE" at 12394.46,2928.87 h60
  text "N.C. ROUTE" at 12394.46,2792.9 h60
  text "X" at 13082.46,2792.9 h60
  text "V. SCORE" at 13260.46,2792.9 h60
  text "CERTIFICATION:" at 11333.46,2663.77 h60
  text "MATERIALS AND WORKMANSHIP FOR ALL PCBS" at 12058.46,2663.77 h60
  text "TO MEET OR EXCEED THE REQUIREMENTS OF:" at 12058.46,2569.71 h60
  text "X" at 11695.97,2441.08 h60
  text "ANSI IPC-A-600F CLASS ->" at 11823.96,2441.08 h60
  text "X" at 13471.97,2441.08 h60
  text "2" at 13581.96,2441.08 h60
  text "1" at 13266.96,2439.58 h60
  text "3" at 13935.96,2439.58 h60
  text "X" at 12507.97,2293.39 h60
  text "RoHS" at 12635.96,2293.39 h60
  text "OTHER" at 13280.36,2293.39 h60
  text "PER ORDER" at 13677.42,2293.39 h60
  text "ALL BOARDS MUST MEET OR EXCEED UL94-V0 REQUIREMENTS." at 11361,2139.57 h60
  text "PCB MUST BEAR THE UL94V-0 UL REGISTERED MATERIAL ID NUMBER" at 11361,2023.5 h60
  text "ADDITIONAL REQUIREMENTS:" at 11333.46,1854.08 h60
  text "MICROSECTION:" at 11408.23,1746.95 h60
  text "YES" at 12313.96,1746.95 h60
  text "REQUIRED" at 13175.46,1602.62 h60
  text "BARE BOARD ELEC. TEST:" at 11408.23,1599.76 h60
  text "NONE" at 12713.96,1599.76 h60
  text "X" at 13057.46,1599.76 h60
  text "PER ORDER" at 13767.46,1599.76 h60
  text "X" at 11464.1,1448.76 h60
  text "8 MIL VIAS REQUIRE NON-CONDUCTIVE FILL AND PLANARIZE" at 11576.38,1394.82 h59
  text "XX MIL VIAS REQUIRE CONDUCTIVE FILL AND PLANARIZE" at 11584.38,1290.84 h60
  text "OUTER XX MIL TRACES REQUIRE 50 OHM SINGLE-ENDED IMPEDANCE" at 11583.39,1127.46 h58
  text "LAYER 2 & 3 (INNER LAYERS) XX MIL WIDE, XX MIL SPACE / TRACES REQUIRE 100 OHM DIFFERENTIAL IMPEDANCE" at 11575.39,891.74 h60
  text ".Layer_Name" at 577,-858.49 h60
M11 Gerber Information:
  lines w10: -292,-930.17 6308,-930.17 ; -292,-726.83 6310,-726.83 ; -292,-523.5 -292,-1133.5 3713,-1133.5 6310,-1133.5 6310,-523.5 -291.5,-523.5 -291.5,-1133.5 1284,-1133.5 ; 2173,-1133.5 2173,-523.5 ; 3440,-726.83 3440,-523.5 ; 4280,-726.83 4280,-523.5 ; 4902,-1140 4902,-937.17
  text "ALL ARTWORK VIEWED FROM TOP SIDE" at -228.5,-655.67 h60
  text "BOARD #:" at 2248,-655.67 h60
  text ".PRJ_Number" at 2793.5,-655.67 h60
  text "REV:" at 3638,-655.67 h60
  text ".PCB_Rev" at 3929.5,-655.67 h60
  text "SVN REV:" at 4476,-655.67 h60
  text ".VersionControl_RevNumber" at 4982,-655.67 h60
  text "LAYER NAME =" at -228.5,-858.49 h60
  text "TID #:" at 2248,-859 h60
  text ".TID" at 2793.5,-859 h60
  text "PLOT NAME =" at -228.5,-1064.34 h60
  text ".plot_File_Name" at 577,-1064.34 h60
  text "GENERATED    :" at 2250,-1064.34 h60
  text ".Print_Date" at 3119.5,-1064.34 h60
  text ".Print_Time" at 3848.5,-1064.34 h60
  text "TEXAS INSTRUMENTS" at 5113,-1064.34 h60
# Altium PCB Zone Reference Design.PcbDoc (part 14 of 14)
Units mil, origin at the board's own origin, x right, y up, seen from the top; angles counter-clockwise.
Board outline 8858.11 x 7047.08 mil, 16 copper layers (Top Layer, GND_1, SIG_1, GND_2, PWR/SIG_1, GND_3, PWR_1, PWR_2, GND_4, PWR/SIG_2, GND_5, SIG_2, GND_6, SIG_3, GND_7, Bottom Layer), stack 80.368 mil thick; 1131 components, 808 nets, 3825 pads, 3523 vias.
Unrouted connection lines stored in the file: 563.

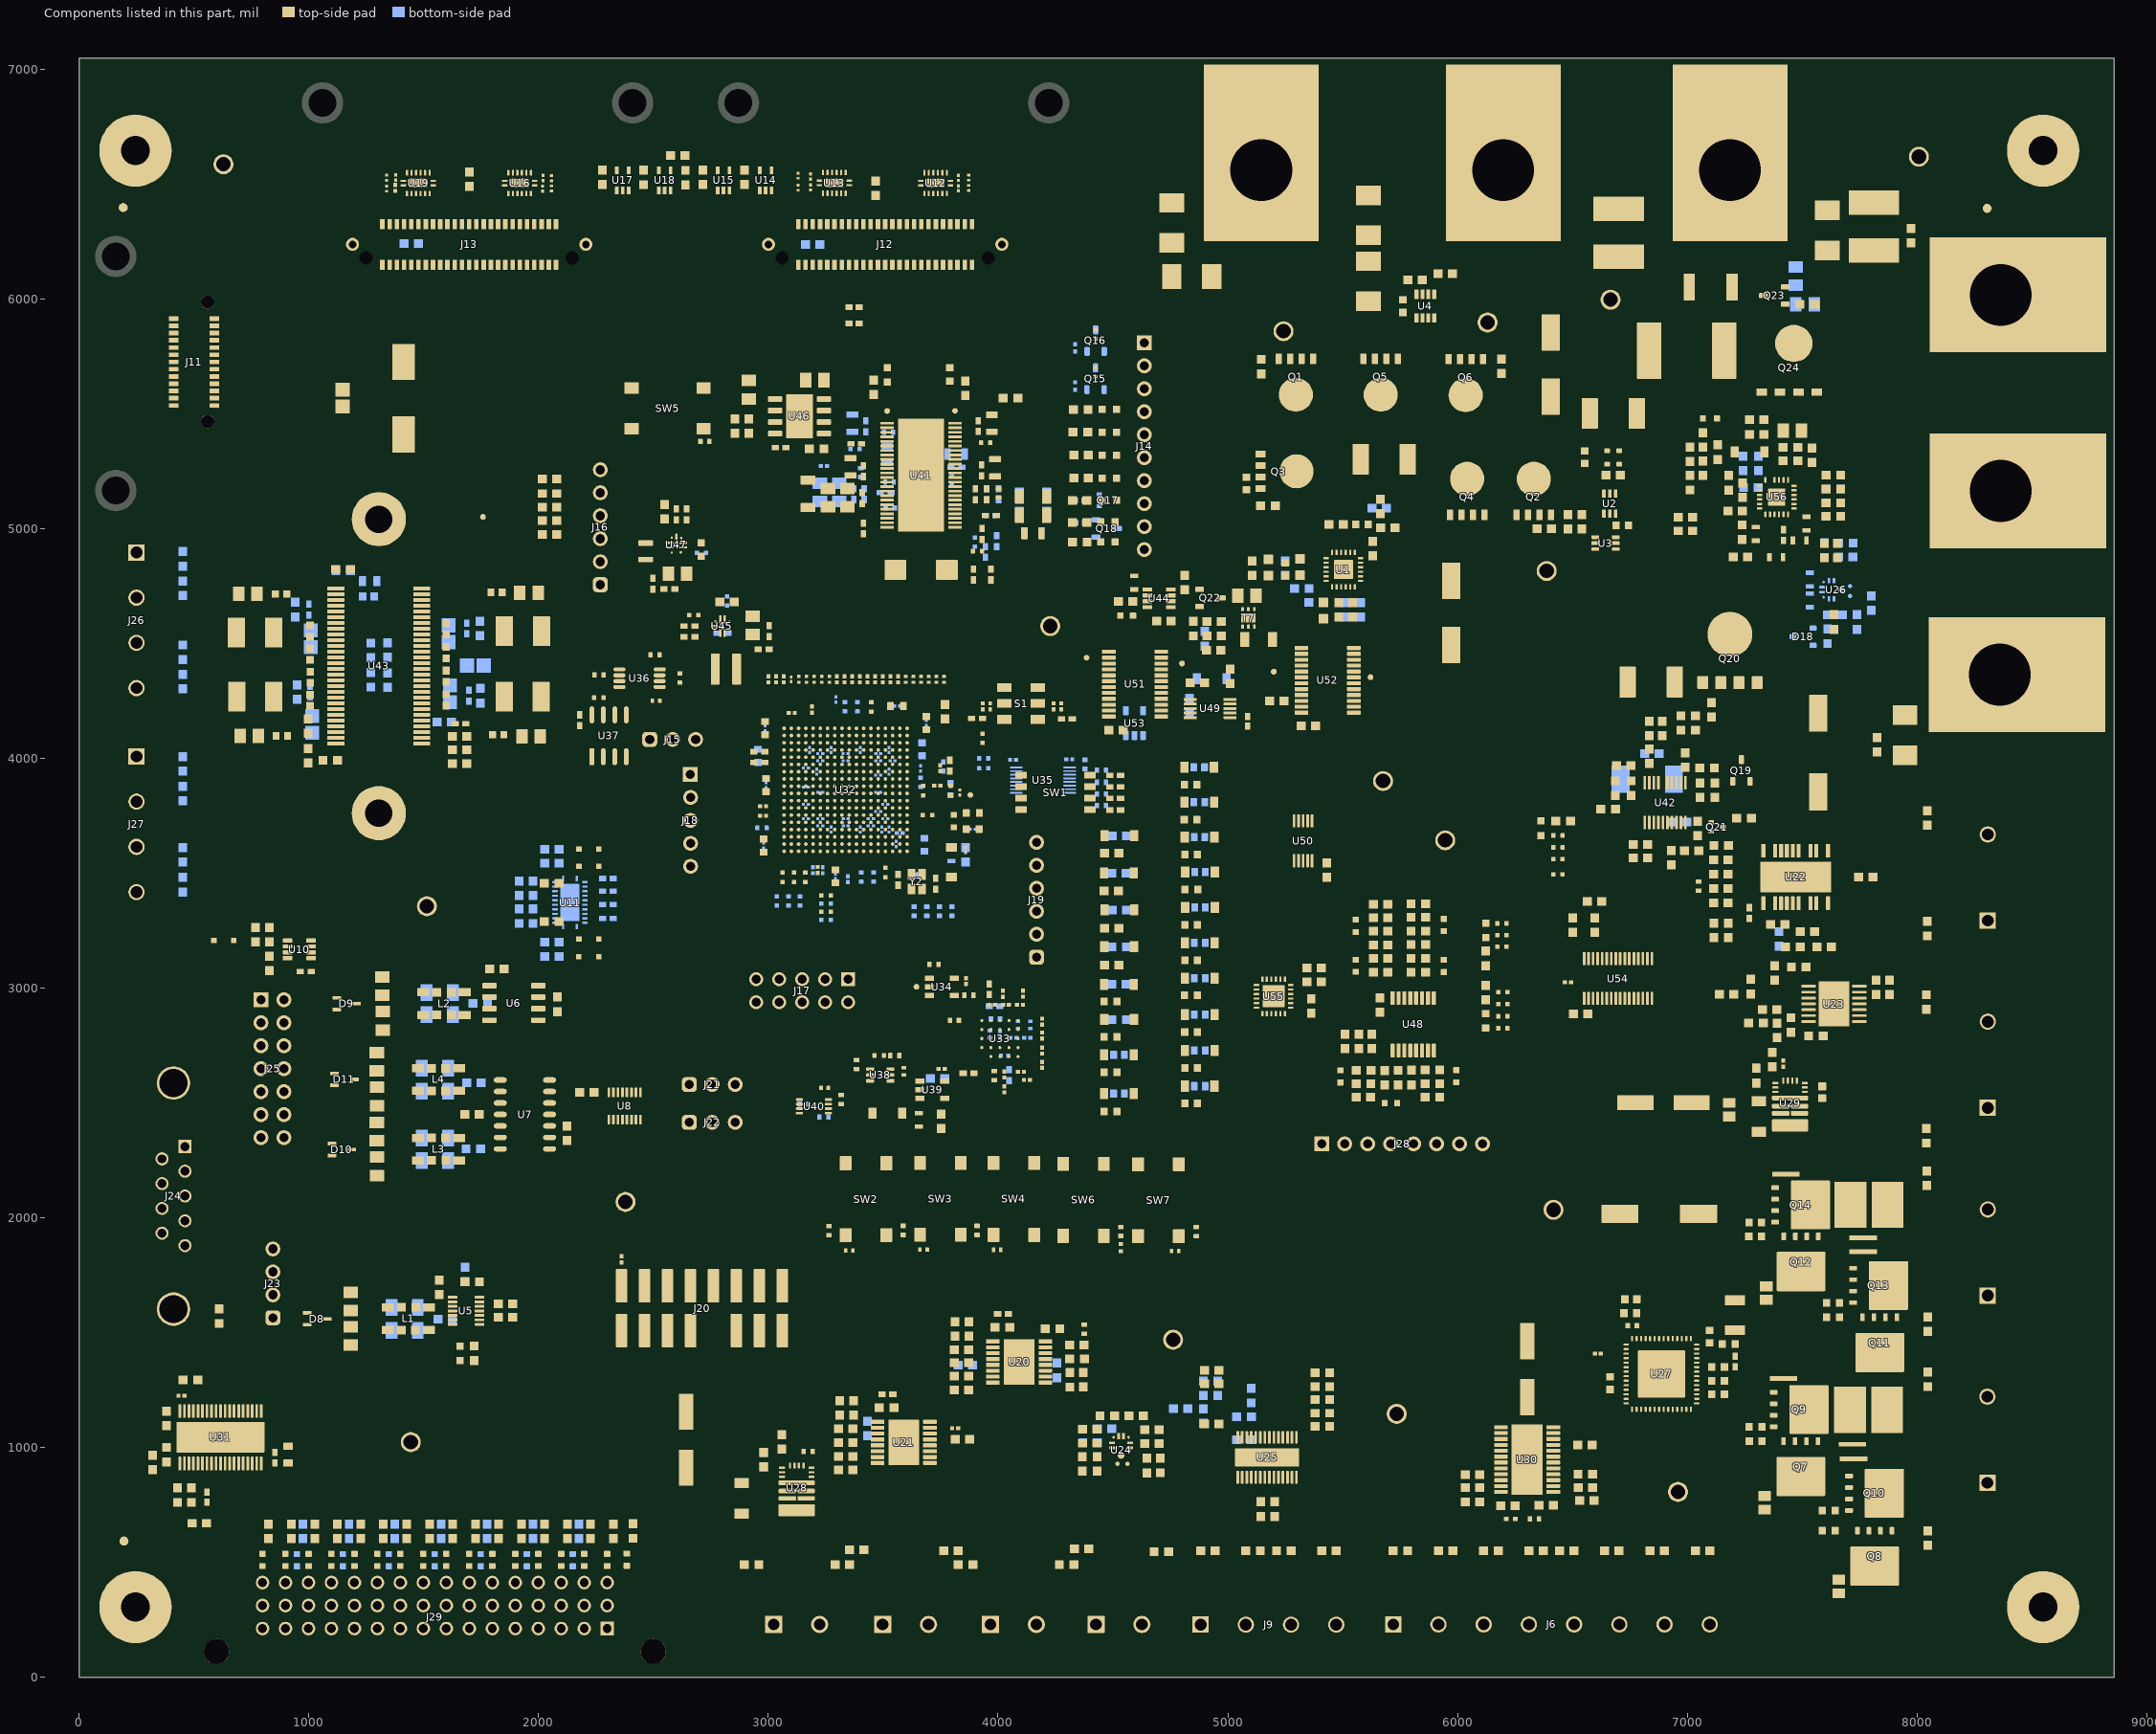
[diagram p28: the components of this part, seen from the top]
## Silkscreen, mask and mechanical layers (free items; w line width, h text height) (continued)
M12 Stackup:
  drawing of 183 lines, arcs and shapes, not listed
  text "Layer" at 8970.89,3142.18 h40
  text "Name" at 9250.83,3142.18 h40
  text "Material" at 9877.33,3142.18 h40
  text "Thickness" at 10457.18,3142.18 h40
  text "Constant" at 10897.07,3142.18 h40
  text "Top Overlay" at 9250.83,3062.18 h40
  text "Top Solder" at 9250.83,2982.18 h40
  text "Solder Resist" at 9877.33,2982.18 h40
  text "0.40mil" at 10457.18,2982.18 h40
  text "3.5" at 10897.07,2982.18 h40
  text "1" at 8970.89,2902.18 h40
  text "Top Layer" at 9250.83,2902.18 h40
  text "0.70mil" at 10457.18,2902.18 h40
  text "Dielectric 11" at 9250.83,2822.18 h40
  text "PP-006" at 9877.33,2822.18 h40
  text "5.90mil" at 10457.18,2822.18 h40
  text "4.1" at 10897.07,2822.18 h40
  text "2" at 8970.89,2742.18 h40
  text "GND_1" at 9250.83,2742.18 h40
  text "CF-004" at 9877.33,2742.18 h40
  text "0.70mil" at 10457.18,2742.18 h40
  text "Dielectric 9" at 9250.83,2662.18 h40
  text "Core-009" at 9877.33,2662.18 h40
  text "3.90mil" at 10457.18,2662.18 h40
  text "4.5" at 10897.07,2662.18 h40
  text "3" at 8970.89,2582.18 h40
  text "SIG_1" at 9250.83,2582.18 h40
  text "CF-004" at 9877.33,2582.18 h40
  text "0.70mil" at 10457.18,2582.18 h40
  text "Dielectric 7" at 9250.83,2502.18 h40
  text "PP-006" at 9877.33,2502.18 h40
  text "5.00mil" at 10457.18,2502.18 h40
  text "4.1" at 10897.07,2502.18 h40
  text "4" at 8970.89,2422.18 h40
  text "GND_2" at 9250.83,2422.18 h40
  text "CF-004" at 9877.33,2422.18 h40
  text "0.70mil" at 10457.18,2422.18 h40
  text "Dielectric 5" at 9250.83,2342.18 h40
  text "Core-009" at 9877.33,2342.18 h40
  text "3.90mil" at 10457.18,2342.18 h40
  text "4.5" at 10897.07,2342.18 h40
  text "5" at 8970.89,2262.18 h40
  text "PWR/SIG_1" at 9250.83,2262.18 h40
  text "CF-004" at 9877.33,2262.18 h40
  text "1.38mil" at 10457.18,2262.18 h40
  text "Dielectric 3" at 9250.83,2182.18 h40
  text "PP-006" at 9877.33,2182.18 h40
  text "4.00mil" at 10457.18,2182.18 h40
  text "4.1" at 10897.07,2182.18 h40
  text "6" at 8970.89,2102.18 h40
  text "GND_3" at 9250.83,2102.18 h40
  text "CF-004" at 9877.33,2102.18 h40
  text "0.70mil" at 10457.18,2102.18 h40
  text "Dielectric 1" at 9250.83,2022.18 h40
  text "Core-009" at 9877.33,2022.18 h40
  text "3.90mil" at 10457.18,2022.18 h40
  text "4.5" at 10897.07,2022.18 h40
  text "7" at 8970.89,1942.18 h40
  text "PWR_1" at 9250.83,1942.18 h40
  text "CF-004" at 9877.33,1942.18 h40
  text "1.38mil" at 10457.18,1942.18 h40
  text "Dielectric1" at 9250.83,1862.18 h40
  text "PP-006" at 9877.33,1862.18 h40
  text "4.00mil" at 10457.18,1862.18 h40
  text "4.1" at 10897.07,1862.18 h40
  text "8" at 8970.89,1782.18 h40
  text "PWR_2" at 9250.83,1782.18 h40
  text "CF-004" at 9877.33,1782.18 h40
  text "1.38mil" at 10457.18,1782.18 h40
  text "Dielectric 2" at 9250.83,1702.18 h40
  text "Core-009" at 9877.33,1702.18 h40
  text "3.90mil" at 10457.18,1702.18 h40
  text "4.5" at 10897.07,1702.18 h40
  text "9" at 8970.89,1622.18 h40
  text "GND_4" at 9250.83,1622.18 h40
  text "CF-004" at 9877.33,1622.18 h40
  text "0.70mil" at 10457.18,1622.18 h40
  text "Dielectric 4" at 9250.83,1542.18 h40
  text "PP-006" at 9877.33,1542.18 h40
  text "4.00mil" at 10457.18,1542.18 h40
  text "4.1" at 10897.07,1542.18 h40
  text "10" at 8970.89,1462.18 h40
  text "PWR/SIG_2" at 9250.83,1462.18 h40
  text "CF-004" at 9877.33,1462.18 h40
  text "1.38mil" at 10457.18,1462.18 h40
  text "Dielectric 6" at 9250.83,1382.18 h40
  text "Core-009" at 9877.33,1382.18 h40
  text "3.90mil" at 10457.18,1382.18 h40
  text "4.5" at 10897.07,1382.18 h40
  text "11" at 8970.89,1302.18 h40
  text "GND_5" at 9250.83,1302.18 h40
  text "CF-004" at 9877.33,1302.18 h40
  text "0.70mil" at 10457.18,1302.18 h40
  text "Dielectric 14" at 9250.83,1222.18 h40
  text "PP-006" at 9877.33,1222.18 h40
  text "4.00mil" at 10457.18,1222.18 h40
  text "4.1" at 10897.07,1222.18 h40
  text "12" at 8970.89,1142.18 h40
  text "SIG_2" at 9250.83,1142.18 h40
  text "CF-004" at 9877.33,1142.18 h40
  text "1.38mil" at 10457.18,1142.18 h40
  text "Dielectric 13" at 9250.83,1062.18 h40
  text "Core-009" at 9877.33,1062.18 h40
  text "3.90mil" at 10457.18,1062.18 h40
  text "4.5" at 10897.07,1062.18 h40
  text "13" at 8970.89,982.18 h40
  text "GND_6" at 9250.83,982.18 h40
  text "CF-004" at 9877.33,982.18 h40
  text "1.38mil" at 10457.18,982.18 h40
  text "Dielectric 8" at 9250.83,902.18 h40
  text "PP-006" at 9877.33,902.18 h40
  text "5.00mil" at 10457.18,902.18 h40
  text "4.1" at 10897.07,902.18 h40
  text "14" at 8970.89,822.18 h40
  text "SIG_3" at 9250.83,822.18 h40
  text "CF-004" at 9877.33,822.18 h40
  text "0.70mil" at 10457.18,822.18 h40
  text "Dielectric 10" at 9250.83,742.18 h40
  text "Core-009" at 9877.33,742.18 h40
  text "3.90mil" at 10457.18,742.18 h40
  text "4.5" at 10897.07,742.18 h40
  text "15" at 8970.89,662.18 h40
  text "GND_7" at 9250.83,662.18 h40
  text "CF-004" at 9877.33,662.18 h40
  text "0.70mil" at 10457.18,662.18 h40
  text "Dielectric 12" at 9250.83,582.18 h40
  text "PP-006" at 9877.33,582.18 h40
  text "5.90mil" at 10457.18,582.18 h40
  text "4.1" at 10897.07,582.18 h40
  text "16" at 8970.89,502.18 h40
  text "Bottom Layer" at 9250.83,502.18 h40
  text "0.70mil" at 10457.18,502.18 h40
  text "Bottom Solder" at 9250.83,422.18 h40
  text "Solder Resist" at 9877.33,422.18 h40
  text "0.40mil" at 10457.18,422.18 h40
  text "3.5" at 10897.07,422.18 h40
  text "Bottom Overlay" at 9250.83,342.18 h40
  text ".Layer_Name" at 577,-858.49 h60
M13 Component Bodies Top:
  text ".Layer_Name" at 577,-858.49 h60
M14 Component Bodies Bottom:
  text ".Layer_Name" at 577,-858.49 h60
M15 Courtyards Top:
  text ".Layer_Name" at 577,-858.49 h60
M16 Courtyards Bottom:
  text ".Layer_Name" at 577,-858.49 h60
Drill Drawing:
  drawing of 165 lines, arcs and shapes, not listed
  text ".Layer_Name" at 577,-858.49 h60
  text "Symbol" at 348.88,-1494.5 h63.38
  text "Count" at 798.02,-1494.5 h63.38
  text "Hole Size" at 1381.24,-1494.5 h63.38
  text "Plated" at 2404.45,-1494.5 h63.38
  text "Hole Type" at 2853.59,-1494.5 h63.38
  text "Drill Layer Pair" at 3503.36,-1494.5 h63.38
  text "Via/Pad" at 4825.77,-1494.5 h63.38
  text "Pad Shape" at 5348.83,-1494.5 h63.38
  text "Template" at 6009.16,-1494.5 h63.38
  text "Description" at 7278.77,-1494.5 h63.38
  text "Hole Tolerance (+)" at 8034.15,-1494.5 h63.38
  text "Hole Tolerance (-)" at 9365.35,-1494.5 h63.38
  text "1" at 798.02,-1626.54 h52.82
  text "10.00mil (0.254mm)" at 1381.24,-1626.54 h52.82
  text "PTH" at 2404.45,-1626.54 h52.82
  text "Round" at 2853.59,-1626.54 h52.82
  text "Top Layer - Bottom Layer" at 3503.36,-1626.54 h52.82
  text "Via" at 4825.77,-1626.54 h52.82
  text "Rounded" at 5348.83,-1626.54 h52.82
  text "v51h25m0mx0" at 6009.16,-1626.54 h52.82
  text "E" at 322.45,-1636.53 h58.68
  text "2" at 798.02,-1758.58 h52.82
  text "109.84mil (2.790mm)" at 1381.24,-1758.58 h52.82
  text "NPTH" at 2404.45,-1758.58 h52.82
  text "Round" at 2853.59,-1758.58 h52.82
  text "Top Layer - Bottom Layer" at 3503.36,-1758.58 h52.82
  text "Pad" at 4825.77,-1758.58 h52.82
  text "Rounded" at 5348.83,-1758.58 h52.82
  text "c279hn279m279" at 6009.16,-1758.58 h52.82
  text "J" at 322.45,-1768.57 h58.68
  text "2" at 798.02,-1890.62 h52.82
  text "118.11mil (3.000mm)" at 1381.24,-1890.62 h52.82
  text "PTH" at 2404.45,-1890.62 h52.82
  text "Round" at 2853.59,-1890.62 h52.82
  text "Top Layer - Bottom Layer" at 3503.36,-1890.62 h52.82
  text "Pad" at 4825.77,-1890.62 h52.82
  text "Rounded" at 5348.83,-1890.62 h52.82
  text "c600h300(Tol545461)" at 6009.16,-1890.62 h52.82
  text "214748.34mil (5454.608mm)" at 8034.15,-1890.62 h52.82
  text "F" at 322.45,-1900.61 h58.68
  text "2" at 798.02,-2022.66 h52.82
  text "122.05mil (3.100mm)" at 1381.24,-2022.66 h52.82
  text "PTH" at 2404.45,-2022.66 h52.82
  text "Round" at 2853.59,-2022.66 h52.82
  text "Top Layer - Bottom Layer" at 3503.36,-2022.66 h52.82
  text "Pad" at 4825.77,-2022.66 h52.82
  text "Rounded" at 5348.83,-2022.66 h52.82
  text "c370h310p0" at 6009.16,-2022.66 h52.82
  text "D" at 322.45,-2032.65 h58.68
  text "4" at 798.02,-2154.7 h52.82
  text "32.68mil (0.830mm)" at 1381.24,-2154.7 h52.82
  text "PTH" at 2404.45,-2154.7 h52.82
  text "Round" at 2853.59,-2154.7 h52.82
  text "Top Layer - Bottom Layer" at 3503.36,-2154.7 h52.82
  text "Pad" at 4825.77,-2154.7 h52.82
  text "Rounded" at 5348.83,-2154.7 h52.82
  text "c145h83" at 6009.16,-2154.7 h52.82
  text "B" at 322.45,-2164.7 h58.68
  text "4" at 798.02,-2286.75 h52.82
  text "125.98mil (3.200mm)" at 1381.24,-2286.75 h52.82
  text "PTH" at 2404.45,-2286.75 h52.82
  text "Round" at 2853.59,-2286.75 h52.82
  text "Top Layer - Bottom Layer" at 3503.36,-2286.75 h52.82
  text "Pad" at 4825.77,-2286.75 h52.82
  text "Rounded" at 5348.83,-2286.75 h52.82
  text "c800h320" at 6009.16,-2286.75 h52.82
  text "6" at 798.02,-2418.79 h52.82
  text "12.99mil (0.330mm)" at 1381.24,-2418.79 h52.82
  text "PTH" at 2404.45,-2418.79 h52.82
  text "Round" at 2853.59,-2418.79 h52.82
  text "Top Layer - Bottom Layer" at 3503.36,-2418.79 h52.82
  text "Via" at 4825.77,-2418.79 h52.82
  text "Rounded" at 5348.83,-2418.79 h52.82
  text "v63h33m0mx0" at 6009.16,-2418.79 h52.82
  text "G" at 322.45,-2428.78 h58.68
  text "6" at 798.02,-2550.83 h52.82
  text "57.09mil (1.450mm)" at 1381.24,-2550.83 h52.82
  text "NPTH" at 2404.45,-2550.83 h52.82
  text "Round" at 2853.59,-2550.83 h52.82
  text "Top Layer - Bottom Layer" at 3503.36,-2550.83 h52.82
  text "Pad" at 4825.77,-2550.83 h52.82
  text "Rounded" at 5348.83,-2550.83 h52.82
  text "(Mixed)" at 6009.16,-2550.83 h52.82
  text "A" at 322.45,-2560.82 h58.68
  text "6" at 798.02,-2682.87 h52.82
  text "121.00mil (3.073mm)" at 1381.24,-2682.87 h52.82
  text "PTH" at 2404.45,-2682.87 h52.82
  text "Round" at 2853.59,-2682.87 h52.82
  text "Top Layer - Bottom Layer" at 3503.36,-2682.87 h52.82
  text "Pad" at 4825.77,-2682.87 h52.82
  text "Rounded" at 5348.83,-2682.87 h52.82
  text "c457h307" at 6009.16,-2682.87 h52.82
  text "6" at 798.02,-2814.91 h52.82
  text "270.00mil (6.858mm)" at 1381.24,-2814.91 h52.82
  text "PTH" at 2404.45,-2814.91 h52.82
  text "Round" at 2853.59,-2814.91 h52.82
  text "Top Layer - Bottom Layer" at 3503.36,-2814.91 h52.82
  text "Pad" at 4825.77,-2814.91 h52.82
  text "Rectangle" at 5348.83,-2814.91 h52.82
  text "r1956_1270h686o-190_0p0" at 6009.16,-2814.91 h52.82
  text "8" at 798.02,-2946.95 h52.82
  text "51.18mil (1.300mm)" at 1381.24,-2946.95 h52.82
  text "PTH" at 2404.45,-2946.95 h52.82
  text "Round" at 2853.59,-2946.95 h52.82
  text "Top Layer - Bottom Layer" at 3503.36,-2946.95 h52.82
  text "Pad" at 4825.77,-2946.95 h52.82
  text "(Mixed)" at 5348.83,-2946.95 h52.82
  text "(Mixed)" at 6009.16,-2946.95 h52.82
  text "3.94mil (0.100mm)" at 8034.15,-2946.95 h52.82
  text "3.94mil (0.100mm)" at 9365.35,-2946.95 h52.82
  text "9" at 798.02,-3078.99 h52.82
  text "39.37mil (1.000mm)" at 1381.24,-3078.99 h52.82
  text "PTH" at 2404.45,-3078.99 h52.82
  text "Round" at 2853.59,-3078.99 h52.82
  text "Top Layer - Bottom Layer" at 3503.36,-3078.99 h52.82
  text "Pad" at 4825.77,-3078.99 h52.82
  text "(Mixed)" at 5348.83,-3078.99 h52.82
  text "(Mixed)" at 6009.16,-3078.99 h52.82
  text "C" at 322.45,-3088.98 h58.68
  text "10" at 798.02,-3211.03 h52.82
  text "40.16mil (1.020mm)" at 1381.24,-3211.03 h52.82
  text "PTH" at 2404.45,-3211.03 h52.82
  text "Round" at 2853.59,-3211.03 h52.82
  text "Top Layer - Bottom Layer" at 3503.36,-3211.03 h52.82
  text "Pad" at 4825.77,-3211.03 h52.82
  text "(Mixed)" at 5348.83,-3211.03 h52.82
  text "(Mixed)" at 6009.16,-3211.03 h52.82
  text "16" at 798.02,-3343.07 h52.82
  text "63.00mil (1.600mm)" at 1381.24,-3343.07 h52.82
  text "PTH" at 2404.45,-3343.07 h52.82
  text "Round" at 2853.59,-3343.07 h52.82
  text "Top Layer - Bottom Layer" at 3503.36,-3343.07 h52.82
  text "Pad" at 4825.77,-3343.07 h52.82
  text "Rounded" at 5348.83,-3343.07 h52.82
  text "c221h160" at 6009.16,-3343.07 h52.82
  text "28" at 798.02,-3475.11 h52.82
  text "51.18mil (1.300mm)" at 1381.24,-3475.11 h52.82
  text "PTH" at 2404.45,-3475.11 h52.82
  text "Round" at 2853.59,-3475.11 h52.82
  text "Top Layer - Bottom Layer" at 3503.36,-3475.11 h52.82
  text "Pad" at 4825.77,-3475.11 h52.82
  text "(Mixed)" at 5348.83,-3475.11 h52.82
  text "(Mixed)" at 6009.16,-3475.11 h52.82
  text "48" at 798.02,-3607.15 h52.82
  text "38.98mil (0.990mm)" at 1381.24,-3607.15 h52.82
  text "PTH" at 2404.45,-3607.15 h52.82
  text "Round" at 2853.59,-3607.15 h52.82
  text "Top Layer - Bottom Layer" at 3503.36,-3607.15 h52.82
  text "Pad" at 4825.77,-3607.15 h52.82
  text "(Mixed)" at 5348.83,-3607.15 h52.82
  text "(Mixed)" at 6009.16,-3607.15 h52.82
  text "I" at 332.23,-3617.14 h58.68
  text "62" at 798.02,-3739.19 h52.82
  text "40.00mil (1.016mm)" at 1381.24,-3739.19 h52.82
  text "PTH" at 2404.45,-3739.19 h52.82
  text "Round" at 2853.59,-3739.19 h52.82
  text "Top Layer - Bottom Layer" at 3503.36,-3739.19 h52.82
  text "Pad" at 4825.77,-3739.19 h52.82
  text "(Mixed)" at 5348.83,-3739.19 h52.82
  text "(Mixed)" at 6009.16,-3739.19 h52.82
  text "142" at 798.02,-3871.23 h52.82
  text "8.00mil (0.203mm)" at 1381.24,-3871.23 h52.82
  text "PTH" at 2404.45,-3871.23 h52.82
  text "Round" at 2853.59,-3871.23 h52.82
  text "Top Layer - Bottom Layer" at 3503.36,-3871.23 h52.82
  text "Via" at 4825.77,-3871.23 h52.82
  text "Rounded" at 5348.83,-3871.23 h52.82
  text "(Mixed)" at 6009.16,-3871.23 h52.82
  text "245" at 798.02,-4003.27 h52.82
  text "7.87mil (0.200mm)" at 1381.24,-4003.27 h52.82
  text "PTH" at 2404.45,-4003.27 h52.82
  text "Round" at 2853.59,-4003.27 h52.82
  text "Top Layer - Bottom Layer" at 3503.36,-4003.27 h52.82
  text "Via" at 4825.77,-4003.27 h52.82
  text "Rounded" at 5348.83,-4003.27 h52.82
  text "(Mixed)" at 6009.16,-4003.27 h52.82
  text "332" at 798.02,-4135.32 h52.82
  text "8.00mil (0.203mm)" at 1381.24,-4135.32 h52.82
  text "PTH" at 2404.45,-4135.32 h52.82
  text "Round" at 2853.59,-4135.32 h52.82
  text "Top Layer - Bottom Layer" at 3503.36,-4135.32 h52.82
  text "Via" at 4825.77,-4135.32 h52.82
  text "Rounded" at 5348.83,-4135.32 h52.82
  text "(Mixed)" at 6009.16,-4135.32 h52.82
  text "3.00mil (0.076mm)" at 8034.15,-4135.32 h52.82
  text "3.00mil (0.076mm)" at 9365.35,-4135.32 h52.82
  text "348" at 798.02,-4267.36 h52.82
  text "16.00mil (0.406mm)" at 1381.24,-4267.36 h52.82
  text "PTH" at 2404.45,-4267.36 h52.82
  text "Round" at 2853.59,-4267.36 h52.82
  text "Top Layer - Bottom Layer" at 3503.36,-4267.36 h52.82
  text "Via" at 4825.77,-4267.36 h52.82
  text "Rounded" at 5348.83,-4267.36 h52.82
  text "v81h41m0mx0" at 6009.16,-4267.36 h52.82
  text "H" at 322.45,-4277.35 h58.68
  text "2449" at 798.02,-4399.4 h52.82
  text "10.00mil (0.254mm)" at 1381.24,-4399.4 h52.82
  text "PTH" at 2404.45,-4399.4 h52.82
  text "Round" at 2853.59,-4399.4 h52.82
  text "Top Layer - Bottom Layer" at 3503.36,-4399.4 h52.82
  text "Via" at 4825.77,-4399.4 h52.82
  text "Rounded" at 5348.83,-4399.4 h52.82
  text "v51h25m0mx0(Tol8-8)" at 6009.16,-4399.4 h52.82
  text "3.00mil (0.076mm)" at 8034.15,-4399.4 h52.82
  text "3.00mil (0.076mm)" at 9365.35,-4399.4 h52.82
  text "3736 Total" at 798.02,-4531.44 h52.82
M17 Embedded Cavity:
  text ".Layer_Name" at 577,-858.49 h60
M18 Embedded Assembly:
  text ".Layer_Name" at 577,-858.49 h60
M19 Embedded Keepout:
  text ".Layer_Name" at 577,-858.49 h60

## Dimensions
0,0 to 0,7047.08 on M2 Board Dimensions
0,-400 to 1000,-400 on M2 Board Dimensions
0,0 to 8858.11,0 on M2 Board Dimensions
